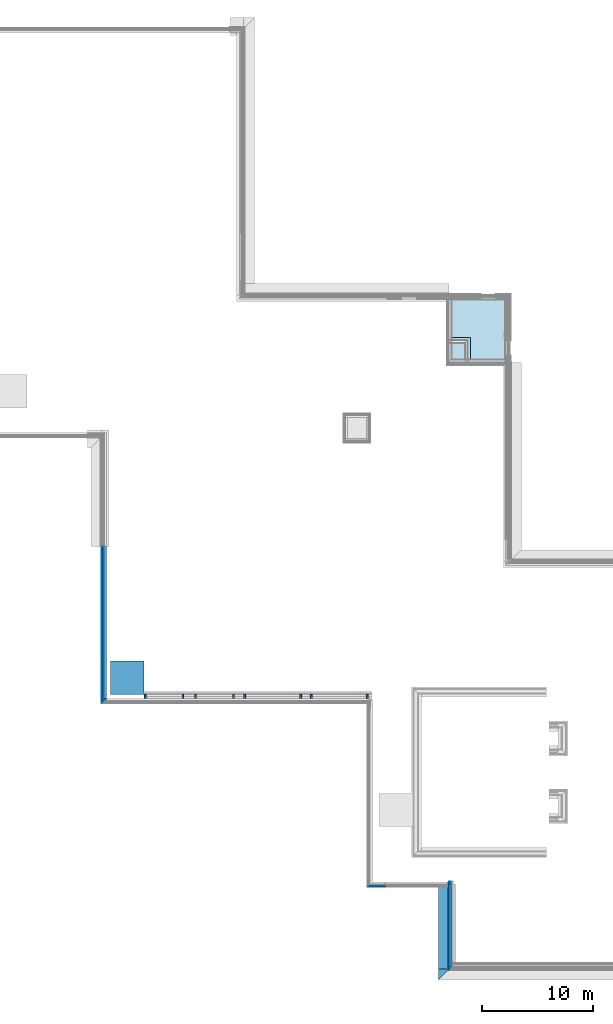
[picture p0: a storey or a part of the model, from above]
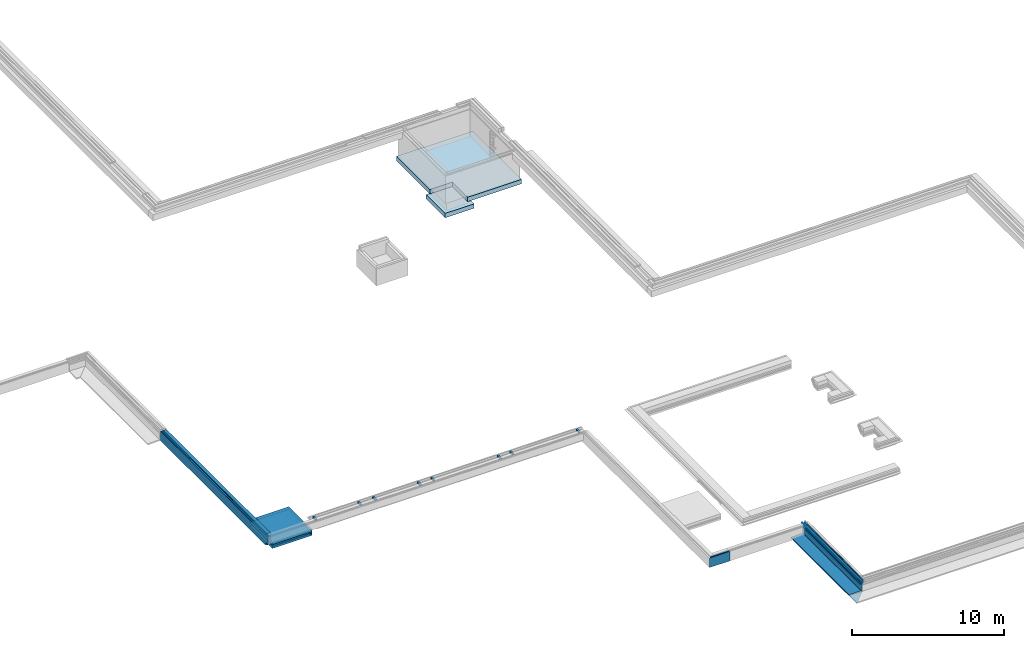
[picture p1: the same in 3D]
Properties of the parts of a building model (IFC2X3), part 1 of 14

# File
Description: ViewDefinition [CoordinationView_V2.0, SurfaceGeometryAddOnView, SpaceBoundary2ndLevelAddOnView], Option [Elements to export: Visible elements (on all stories)], Option [Partial Structure Display: Entire Model], Option [IFC Domain: All], Option [Structural Function: All Elements], Option [Convert Grid elements: On], Option [Convert IFC Annotations and ARCHICAD 2D elements: Off], Option [Convert 2D symbols of Doors and Windows: Off], Option [Export geometries that Participates in Collision Detection only: Off], Option [Split complex elements: On], Option [IFC Domain For Space Containment: Custom], Option [IFC Model position: Survey Point and Project Origin], Option [Curtain Wall export mode: Container Element], Option [Railing export mode: Container Element], Option [Stair export mode: Container Element], Option [Properties To Export: All properties], Option [Space containment: Off], Option [Bounding Box: Off], Option [Geometry to type objects: Off], Option [Element Properties: Visible Only], Option [Building Material Properties: Off], Option [Element Parameters: Off], Option [Component Parameters: Off], Option [IFC Base Quantities: Off], Option [Door Window Parameters: On], Option [IFC Space boundaries: On], Option [ARCHICAD Zone Categories as IFC Space classification data: Off], Option [Element Classifications: On]
File name: A:\ARHITEKT MUST SHARE\PROJEKTID\2020-04-09 PRG\03 Tööprojekt\Mudelid\PRG_PP_AR_v06.ifc
Time: 2022-06-07T12:43:35
Author: Ott Alver, Kaire Koidu, Lisett Laurimäe, Karoliine Kuus, Katrin Vilberg
Organization: Arhitekt Must OÜ
Written by: The EXPRESS Data Manager Version 5.02.0100.09 : 26 Sep 2013
Made in: IFC file generated by GRAPHISOFT ARCHICAD 25.0.0 INT FULL Windows version (IFC add-on version: 4013 INT FULL).
Authorization: Ott Alver, Kaire Koidu, Lisett Laurimäe, Karoliine Kuus, Katrin Vilberg

# IfcProject, Tallinna Pelgulinna riigigümnaasiumi õppehoone ehitusprojekt
Phase: Tööprojekt

# IfcSite, Kolde pst 67a
Description: Ühiskondlike ehitiste maa 100%; RefLatitude: 59, 26, 20, 700000; RefLongitude: 24, 42, 11, 300000; RefElevation: 5300 mm; Classification: 1.0.1 IfcSite (kinnistu) (RKAS BIM + ARCHICAD Classification 23 + v 2.0)
AR_Kinnistu - 025_Max_kõrgus: 16000 mm; 010_Katastritunnus: 78408:803:0075; 015_Ehitatav_pindala: 8000 m2; 020_Pindala: 38454 m2

# IfcBuilding, Riigigümnaasium
Classification: 1.0.2 IfcBuilding (hoone) (RKAS BIM + ARCHICAD Classification 23 + v 2.0)
AR_Hoone - 035_Sprinkler: yes; 001_Nimetus: Riigigümnaasium; 030_Hoone_aadress: Kolde pst 67a, Tallinn, 10321; ?: 3773.3 m2; 050_Neto_pindala: 8269.99 m2; 055_Neto_ruumala: 34560.7 m3; 040_Kõrgus: 15890 mm

# IfcBuildingStorey (6)
In: Riigigümnaasium
Name | Elevation (mm) | 060_Korruse_nimi | 070_Maapealne | Classification
Vundament | -1500 | Vundament | no
1. korrus | 0 | 1. korrus | yes | AR_Korrus - 065_Korruse_number: 1
2. korrus | 4600 | 2. korrus | yes | 1.0.3 IfcBuildingStorey (korrus) (RKAS BIM + ARCHICAD Classification 23 + v 2.0) | AR_Korrus - 065_Korruse_number: 2
3. korrus | 8350 | 3. korrus | yes | 1.0.3 IfcBuildingStorey (korrus) (RKAS BIM + ARCHICAD Classification 23 + v 2.0) | AR_Korrus - 065_Korruse_number: 3
4. TEHNO korrus | 12100 | TEHNO korrus | yes | 1.0.3 IfcBuildingStorey (korrus) (RKAS BIM + ARCHICAD Classification 23 + v 2.0)
Katus | 15900 | Katus | yes | 1.0.3 IfcBuildingStorey (korrus) (RKAS BIM + ARCHICAD Classification 23 + v 2.0)

# IfcSpace: Abiruumid/panipaigad (11)
InteriorOrExteriorSpace: INTERNAL; Classification: 1.21 IfcSpaceType (ruum) (RKAS BIM + ARCHICAD Classification)
Pset_SpaceCommon - Reference: Üüritav pind; Category: Abiruumid/panipaigad
AR_Ruum - 115_Kategooria: Abiruumid/panipaigad; 110_Tüüp: Üüritav pind; 125_Turvatsoon: Abiruumid/panipaigad
AC_Pset_RenovationAndPhasing - Renovation Status: New
Name | In | LongName = 100_Nimi | 105_Number | 120_Pindala (m2) | Group
191 | 1. korrus | Hoiuruum/Ladu | 191 | 23.9709
116 | 1. korrus | Abiruum | 116 | 3.04431 | TTS 02
198 | 1. korrus | Hoiuruum/Ladu | 198 | 26.6814 | TTS 05
176 | 1. korrus | Hoiuruum/Ladu | 176 | 9.17397 | TTS 22
230 | 2. korrus | Hoiuruum/Ladu | 230 | 30.8659 | TTS 16
254 | 2. korrus | Abiruum | 254 | 4.87507
229 | 2. korrus | Abiruum | 229 | 9.63895 | TTS 01
257 | 2. korrus | Abiruum | 257 | 5.39372
336 | 3. korrus | Abiruum | 336 | 18.426 | TTS 01
318 | 3. korrus | Abiruum | 318 | 11.8529
351 | 3. korrus | Abiruum | 351 | 6.48915 | TTS 01

# IfcSpace: Aula (2)
LongName: Aatrium/Fuajee; InteriorOrExteriorSpace: INTERNAL; Classification: 1.21 IfcSpaceType (ruum) (RKAS BIM + ARCHICAD Classification)
Pset_SpaceCommon - Reference: Üüritav pind; Category: Aula
AR_Ruum - 100_Nimi: Aatrium/Fuajee; 115_Kategooria: Aula; 110_Tüüp: Üüritav pind; 125_Turvatsoon: Aula
AC_Pset_RenovationAndPhasing - Renovation Status: New
Name | In | 105_Number | 120_Pindala (m2)
226.1 | 2. korrus | 226.1 | 103.615 | Group: TTS 01
226.2 | 3. korrus | 226.2 | 57.8569

# IfcSpace: Köögiruumid (8)
In: 1. korrus
InteriorOrExteriorSpace: INTERNAL; Classification: 1.21 IfcSpaceType (ruum) (RKAS BIM + ARCHICAD Classification)
Pset_SpaceCommon - Reference: Üüritav pind; Category: Köögiruumid
AR_Ruum - 115_Kategooria: Köögiruumid; 110_Tüüp: Üüritav pind; 125_Turvatsoon: Köögiruumid
AC_Pset_RenovationAndPhasing - Renovation Status: New
Name | LongName = 100_Nimi | 105_Number | 120_Pindala (m2) | Group
149 | Kööginurk/Köök | 149 | 95.7564 | TTS 01
141 | Hoiuruum/Ladu | 141 | 6.59968 | TTS 01
151 | Riietusruum | 151 | 6.76 | TTS 01
153 | WC | 153 | 1.94857 | TTS 01
152 | Pesuruum | 152 | 2.33343 | TTS 01
150 | Kabinet/Büroo | 150 | 9.78205
143 | Hoiuruum/Ladu | 143 | 3.49194 | TTS 01
142 | Hoiuruum/Ladu | 142 | 3.00324 | TTS 01

# IfcSpace: Märjad ruumid (56)
InteriorOrExteriorSpace: INTERNAL; Classification: 1.21 IfcSpaceType (ruum) (RKAS BIM + ARCHICAD Classification)
Pset_SpaceCommon - Reference: Üüritav pind; Category: Märjad ruumid
AR_Ruum - 115_Kategooria: Märjad ruumid; 110_Tüüp: Üüritav pind; 125_Turvatsoon: Märjad ruumid
AC_Pset_RenovationAndPhasing - Renovation Status: New
Name | In | LongName = 100_Nimi | 105_Number | 120_Pindala (m2) | Group
183 | 1. korrus | WC | 183 | 2.1358
187 | 1. korrus | WC | 187 | 2.10905
184 | 1. korrus | Pesuruum | 184 | 7.7438
186 | 1. korrus | Pesuruum | 186 | 7.65261
190 | 1. korrus | Pesuruum | 190 | 7.19918
180 | 1. korrus | Pesuruum | 180 | 7.3536
122 | 1. korrus | WC | 122 | 5.07894 | TTS 02
123 | 1. korrus | WC | 123 | 1.47943 | TTS 02
124 | 1. korrus | WC | 124 | 1.33987 | TTS 02
125 | 1. korrus | WC | 125 | 1.33987 | TTS 02
126 | 1. korrus | WC | 126 | 1.33987 | TTS 02
121 | 1. korrus | WC | 121 | 1.61197 | TTS 02
162 | 1. korrus | WC | 162 | 7.00256 | TTS 01
165 | 1. korrus | WC | 165 | 1.39298 | TTS 01
166 | 1. korrus | WC | 166 | 1.39298 | TTS 01
168 | 1. korrus | WC | 168 | 1.39298 | TTS 01
167 | 1. korrus | WC | 167 | 1.39298 | TTS 01
163 | 1. korrus | WC | 163 | 1.49425 | TTS 01
164 | 1. korrus | WC | 164 | 1.39298 | TTS 01
194 | 1. korrus | WC | 194 | 1.95199
193 | 1. korrus | WC | 193 | 2.0196
127 | 1. korrus | WC | 127 | 1.33988 | TTS 02
128 | 1. korrus | WC | 128 | 1.51264 | TTS 02
181 | 1. korrus | WC | 181 | 4.59543
189 | 1. korrus | WC | 189 | 4.55725
163.1 | 1. korrus | WC | 163.1 | 11.2722 | TTS 01
222 | 2. korrus | WC | 222 | 1.37998 | TTS 02
221 | 2. korrus | WC | 221 | 1.37998 | TTS 02
220 | 2. korrus | WC | 220 | 1.37998 | TTS 02
219 | 2. korrus | WC | 219 | 1.37998 | TTS 02
218 | 2. korrus | WC | 218 | 1.48204 | TTS 02
217 | 2. korrus | WC | 217 | 11.4102 | TTS 02
238 | 2. korrus | WC | 238 | 7.00256 | TTS 01
241 | 2. korrus | WC | 241 | 1.39298 | TTS 01
242 | 2. korrus | WC | 242 | 1.39298 | TTS 01
244 | 2. korrus | WC | 244 | 1.39298 | TTS 01
243 | 2. korrus | WC | 243 | 1.39298 | TTS 01
239 | 2. korrus | WC | 239 | 1.49425 | TTS 01
240 | 2. korrus | WC | 240 | 1.39298 | TTS 01
223 | 2. korrus | WC | 223 | 1.50827 | TTS 02
239.1 | 2. korrus | WC | 239.1 | 11.2722 | TTS 01
327 | 3. korrus | WC | 327 | 1.37998 | TTS 02
326 | 3. korrus | WC | 326 | 1.37998 | TTS 02
325 | 3. korrus | WC | 325 | 1.37998 | TTS 02
324 | 3. korrus | WC | 324 | 1.37998 | TTS 02
323 | 3. korrus | WC | 323 | 1.44592 | TTS 02
343 | 3. korrus | WC | 343 | 7.00256 | TTS 01
349 | 3. korrus | WC | 349 | 1.39298 | TTS 01
348 | 3. korrus | WC | 348 | 1.39298 | TTS 01
322 | 3. korrus | WC | 322 | 11.2901 | TTS 02
347 | 3. korrus | WC | 347 | 1.39298 | TTS 01
346 | 3. korrus | WC | 346 | 1.39298 | TTS 01
345 | 3. korrus | WC | 345 | 1.39298 | TTS 01
343.1 | 3. korrus | WC | 343.1 | 11.2722 | TTS 01
328 | 3. korrus | WC | 328 | 1.49558 | TTS 02
344 | 3. korrus | WC | 344 | 1.49425 | TTS 01

# IfcSpace: Personali ruumid (39)
InteriorOrExteriorSpace: INTERNAL; Classification: 1.21 IfcSpaceType (ruum) (RKAS BIM + ARCHICAD Classification)
Pset_SpaceCommon - Reference: Üüritav pind; Category: Personali ruumid
AR_Ruum - 115_Kategooria: Personali ruumid; 110_Tüüp: Üüritav pind; 125_Turvatsoon: Personali ruumid
AC_Pset_RenovationAndPhasing - Renovation Status: New
Name | In | LongName = 100_Nimi | 105_Number | 120_Pindala (m2) | Group
112 | 1. korrus | Riietusruum | 112 | 8.23039 | TTS 02
119 | 1. korrus | WC | 119 | 1.64765 | TTS 02
131 | 1. korrus | Kabinet/Büroo | 131 | 24.8738 | TTS 02
132 | 1. korrus | Kabinet/Büroo | 132 | 10.4075 | TTS 02
133 | 1. korrus | Nõupidamise ruum | 133 | 11.7527 | TTS 02
134 | 1. korrus | Kabinet/Büroo | 134 | 20.3091 | TTS 02
136 | 1. korrus | Kabinet/Büroo | 136 | 15.1182 | TTS 02
138 | 1. korrus | Kabinet/Büroo | 138 | 24.1936 | TTS 02
137 | 1. korrus | Kabinet/Büroo | 137 | 21.7035 | TTS 02
178 | 1. korrus | Tervishoiuruum | 178 | 20.4975
129 | 1. korrus | Kööginurk/Köök | 129 | 73.9946 | TTS 02
117 | 1. korrus | Nõupidamise ruum | 117 | 46.7019 | TTS 02
115.1 | 1. korrus | Dušš | 115.1 | 2.70465 | TTS 02
108 | 1. korrus | Kabinet/Büroo | 108 | 3.11313 | TTS 02
110 | 1. korrus | Kabinet/Büroo | 110 | 3.0839 | TTS 02
130 | 1. korrus | Koridor | 130 | 19.5208 | TTS 02
120 | 1. korrus | Puhkeruum | 120 | 80.7206 | TTS 02
114 | 1. korrus | WC | 114 | 1.62377 | TTS 02
113 | 1. korrus | WC | 113 | 1.64765 | TTS 02
111 | 1. korrus | Garderoob | 111 | 15.1477 | TTS 02
118 | 1. korrus | WC | 118 | 1.64765 | TTS 02
107 | 1. korrus | Kabinet/Büroo | 107 | 27.0513 | TTS 02
135 | 1. korrus | Kabinet/Büroo | 135 | 15.1162 | TTS 02
175 | 1. korrus | Riietusruum | 175 | 7.38083
174 | 1. korrus | Pesuruum | 174 | 1.7598
173 | 1. korrus | Pesuruum | 173 | 1.83489
172 | 1. korrus | WC | 172 | 1.79748
171 | 1. korrus | Kabinet/Büroo | 171 | 27.2314
192 | 1. korrus | Koristus- ja hooldusruum | 192 | 3.92524
115.2 | 1. korrus | Dušš | 115.2 | 2.66968 | TTS 02
109 | 1. korrus | Kabinet/Büroo | 109 | 3.11307 | TTS 02
235 | 2. korrus | Kabinet/Büroo | 235 | 18.9735 | TTS 01
207 | 2. korrus | Kabinet/Büroo | 207 | 17.0178 | TTS 02
247 | 2. korrus | Koristus- ja hooldusruum | 247 | 10.6071 | TTS 17
341 | 3. korrus | Abiruum | 341 | 19.0182 | TTS 01
305 | 3. korrus | Kabinet/Büroo | 305 | 13.5373 | TTS 02
309 | 3. korrus | Kabinet/Büroo | 309 | 16.817 | TTS 02
320 | 3. korrus | Koristus- ja hooldusruum | 320 | 11.0684 | TTS 02
305.1 | 3. korrus | Kabinet/Büroo | 305.1 | 8.99822 | TTS 02

# IfcSpace: Raamatukogu/mediateek (4)
In: 1. korrus
LongName: Raamatukogu; InteriorOrExteriorSpace: INTERNAL; Classification: 1.21 IfcSpaceType (ruum) (RKAS BIM + ARCHICAD Classification); Group: TTS 23
Pset_SpaceCommon - Reference: Üüritav pind; Category: Raamatukogu/mediateek
AR_Ruum - 100_Nimi: Raamatukogu; 115_Kategooria: Raamatukogu/mediateek; 110_Tüüp: Üüritav pind; 125_Turvatsoon: Raamatukogu/mediateek
AC_Pset_RenovationAndPhasing - Renovation Status: New
Name | 105_Number | 120_Pindala (m2)
170 | 170 | 155.958
170.1 | 170.1 | 4.45445
170.2 | 170.2 | 6.61809
170.3 | 170.3 | 4.30703

# IfcSpace: Spordiruumid (3)
LongName: Spordiruum/-saal; InteriorOrExteriorSpace: INTERNAL; Classification: 1.21 IfcSpaceType (ruum) (RKAS BIM + ARCHICAD Classification)
Pset_SpaceCommon - Reference: Üüritav pind; Category: Spordiruumid
AR_Ruum - 100_Nimi: Spordiruum/-saal; 115_Kategooria: Spordiruumid; 110_Tüüp: Üüritav pind; 125_Turvatsoon: Spordiruumid
AC_Pset_RenovationAndPhasing - Renovation Status: New
Name | In | 105_Number | 120_Pindala (m2)
197 | 1. korrus | 197 | 542.574
253 | 2. korrus | 253 | 61.32
252 | 2. korrus | 252 | 62.6603

# IfcSpace: Tehnopind (10)
InteriorOrExteriorSpace: INTERNAL; Classification: 1.21 IfcSpaceType (ruum) (RKAS BIM + ARCHICAD Classification)
Pset_SpaceCommon - Reference: Tehnopind; Category: Tehnopind
AR_Ruum - 115_Kategooria: Tehnopind; 110_Tüüp: Tehnopind; 125_Turvatsoon: Tehnopind
AC_Pset_RenovationAndPhasing - Renovation Status: New
Name | In | LongName = 100_Nimi | 105_Number | 120_Pindala (m2) | Group
160 | 1. korrus | Veemõõdusõlm | 160 | 8.43576
156 | 1. korrus | Elektrikilp | 156 | 9.02498 | TTS 19
155 | 1. korrus | Generaatoriruum | 155 | 9.12498 | TTS 18
154 | 1. korrus | Sprinkler/Tuletõrje pump | 154 | 16.7674
199 | 1. korrus | Vent ruum | 199 | 39.7786 | TTS 21
161 | 1. korrus | Vent ruum | 161 | 33.47
256 | 2. korrus | Vent ruum | 256 | 49.9815 | TTS 21
319 | 3. korrus | Elektrikilp | 319 | 11.7368
400 | 4. TEHNO korrus | Vent ruum | 400 | 158.243 | TTS 20
401 | 4. TEHNO korrus | Õhuvõtukamber | 401 | 16.8049 | TTS 20

# IfcSpace: Õpperuumid, suur (30)
InteriorOrExteriorSpace: INTERNAL; Classification: 1.21 IfcSpaceType (ruum) (RKAS BIM + ARCHICAD Classification)
Pset_SpaceCommon - Reference: Üüritav pind; Category: Õpperuumid, suur
AR_Ruum - 115_Kategooria: Õpperuumid, suur; 110_Tüüp: Üüritav pind; 125_Turvatsoon: Õpperuumid, suur
AC_Pset_RenovationAndPhasing - Renovation Status: New
Name | In | LongName = 100_Nimi | 105_Number | 120_Pindala (m2) | Group
103 | 1. korrus | Klassiruum | 103 | 67.7298 | TTS 02
148 | 1. korrus | Klassiruum | 148 | 66.9596 | TTS 01
105 | 1. korrus | Klassiruum | 105 | 67.5904 | TTS 02
104 | 1. korrus | Klassiruum | 104 | 66.867 | TTS 02
212 | 2. korrus | Klassiruum | 212 | 68.9089 | TTS 02
210 | 2. korrus | Klassiruum | 210 | 69.8721 | TTS 02
214 | 2. korrus | Nõupidamise ruum | 214 | 73.7044 | TTS 02
215 | 2. korrus | Nõupidamise ruum | 215 | 72.9467 | TTS 02
208 | 2. korrus | Klassiruum | 208 | 69.3758 | TTS 02
204 | 2. korrus | Klassiruum | 204 | 68.5561 | TTS 02
203 | 2. korrus | Klassiruum | 203 | 68.4834 | TTS 02
234 | 2. korrus | Klassiruum | 234 | 69.0595 | TTS 01
228 | 2. korrus | Klassiruum | 228 | 68.9449 | TTS 01
205 | 2. korrus | Klassiruum | 205 | 68.6598 | TTS 02
255 | 2. korrus | Klassiruum | 255 | 67.525
249 | 2. korrus | Klassiruum | 249 | 68.0334
304 | 3. korrus | Klassiruum | 304 | 68.4834 | TTS 02
303 | 3. korrus | Klassiruum | 303 | 67.8291 | TTS 02
310 | 3. korrus | Klassiruum | 310 | 69.3171 | TTS 02
302 | 3. korrus | Klassiruum | 302 | 63.9765 | TTS 02
314 | 3. korrus | Klassiruum | 314 | 68.9089 | TTS 02
334 | 3. korrus | Klassiruum | 334 | 69.3182 | TTS 01
340 | 3. korrus | Laboratoorium | 340 | 84.1305 | TTS 01
342 | 3. korrus | Klassiruum | 342 | 68.6383 | TTS 01
335 | 3. korrus | Klassiruum | 335 | 69.503 | TTS 01
337 | 3. korrus | Klassiruum | 337 | 69.2433 | TTS 01
312 | 3. korrus | Klassiruum | 312 | 69.8721 | TTS 02
332 | 3. korrus | Klassiruum | 332 | 69.8355 | TTS 01
316 | 3. korrus | Auditoorium | 316 | 144.694 | TTS 02
331 | 3. korrus | Klassiruum | 331 | 74.0632 | TTS 01

# IfcSpace: Õpperuumid, väike (16)
LongName: Klassiruum; InteriorOrExteriorSpace: INTERNAL; Classification: 1.21 IfcSpaceType (ruum) (RKAS BIM + ARCHICAD Classification)
Pset_SpaceCommon - Reference: Üüritav pind; Category: Õpperuumid, väike
AR_Ruum - 100_Nimi: Klassiruum; 115_Kategooria: Õpperuumid, väike; 110_Tüüp: Üüritav pind; 125_Turvatsoon: Õpperuumid, väike
AC_Pset_RenovationAndPhasing - Renovation Status: New
Name | In | 105_Number | 120_Pindala (m2) | Group
159 | 1. korrus | 159 | 46.7382 | TTS 01
158 | 1. korrus | 158 | 46.1161 | TTS 01
211 | 2. korrus | 211 | 41.1627 | TTS 02
232 | 2. korrus | 232 | 46.5236 | TTS 01
248 | 2. korrus | 248 | 39.8321
231 | 2. korrus | 231 | 47.3455 | TTS 01
209 | 2. korrus | 209 | 40.5333 | TTS 02
251 | 2. korrus | 251 | 40.2126
237 | 2. korrus | 237 | 39.7604 | TTS 01
236 | 2. korrus | 236 | 40.6798 | TTS 01
313 | 3. korrus | 313 | 41.1626 | TTS 02
338 | 3. korrus | 338 | 39.035 | TTS 01
311 | 3. korrus | 311 | 40.4985 | TTS 02
330 | 3. korrus | 330 | 41.5446 | TTS 01
307 | 3. korrus | 307 | 55.1263 | TTS 02
333 | 3. korrus | 333 | 40.4974 | TTS 01

# IfcSpace: Üldkasutatav pind (39)
InteriorOrExteriorSpace: INTERNAL; Classification: 1.21 IfcSpaceType (ruum) (RKAS BIM + ARCHICAD Classification)
Pset_SpaceCommon - Category: Üldkasutatav pind
AR_Ruum - 115_Kategooria: Üldkasutatav pind; 125_Turvatsoon: Üldkasutatav pind
AC_Pset_RenovationAndPhasing - Renovation Status: New
Name | In | LongName = 100_Nimi | Reference = 110_Tüüp | 105_Number | 120_Pindala (m2) | Group
195 | 1. korrus | Aatrium/Fuajee | Üüritav pind | 195 | 32.9555
106 | 1. korrus | Trepp/Trepikoda | Vertikaalsete ühendusteede pind | 106 | 19.9364 | TTS 03
139 | 1. korrus | Trepp/Trepikoda | Vertikaalsete ühendusteede pind | 139 | 38.8612 | TTS 04
188 | 1. korrus | Riietusruum | Üüritav pind | 188 | 26.5319
185 | 1. korrus | Riietusruum | Üüritav pind | 185 | 26.7094
182 | 1. korrus | Riietusruum | Üüritav pind | 182 | 28.7031
179 | 1. korrus | Riietusruum | Üüritav pind | 179 | 28.7527
157 | 1. korrus | Trepp/Trepikoda | Vertikaalsete ühendusteede pind | 157 | 19.9644
196 | 1. korrus | Koridor | Üüritav pind | 196 | 82.805
102.1 | 1. korrus | Garderoob | Üüritav pind | 102.1 | 119.782 | TTS 02
101 | 1. korrus | Aatrium/Fuajee | Üüritav pind | 101 | 253.476 | TTS 02
169 | 1. korrus | Lift | Üüritav pind | 169 | 3.23
147 | 1. korrus | Aatrium/Fuajee | Üüritav pind | 147 | 198.84 | TTS 01
140 | 1. korrus | Koridor | Üüritav pind | 140 | 7.02965 | TTS 04
177 | 1. korrus | Trepp/Trepikoda | Vertikaalsete ühendusteede pind | 177 | 21.1302
102.2 | 1. korrus | Garderoob | Üüritav pind | 102.2 | 119.849 | TTS 02
144 | 1. korrus | Koridor | Üüritav pind | 144 | 214.176 | TTS 01
146 | 1. korrus | Söökla/Kohvik | Üüritav pind | 146 | 227.255 | TTS 01
216 | 2. korrus | Nõupidamise ruum | Üüritav pind | 216 | 11.8284 | TTS 02
245 | 2. korrus | Lift | Vertikaalsete ühendusteede pind | 245 | 3.23
246 | 2. korrus | Koridor | Üüritav pind | 246 | 116.93
201 | 2. korrus | Koridor | Üüritav pind | 201 | 254.773 | TTS 02
227 | 2. korrus | Trepp/Trepikoda | Üüritav pind | 227 | 73.3487 | TTS 01
233 | 2. korrus | Trepp/Trepikoda | Vertikaalsete ühendusteede pind | 233 | 19.9573
250 | 2. korrus | Trepp/Trepikoda | Vertikaalsete ühendusteede pind | 250 | 30.3251
213 | 2. korrus | Trepp/Trepikoda | Vertikaalsete ühendusteede pind | 213 | 25.2342 | TTS 04
225 | 2. korrus | Õpilasesindus | Üüritav pind | 225 | 25.6581 | TTS 01
206 | 2. korrus | Trepp/Trepikoda | Vertikaalsete ühendusteede pind | 206 | 19.9284 | TTS 03
202 | 2. korrus | Puhkeruum | Üüritav pind | 202 | 90.2772 | TTS 02
224 | 2. korrus | Koridor | Üüritav pind | 224 | 181.989 | TTS 01
308 | 3. korrus | Trepp/Trepikoda | Vertikaalsete ühendusteede pind | 308 | 20.5717 | TTS 03
350 | 3. korrus | Lift | Vertikaalsete ühendusteede pind | 350 | 3.23
321 | 3. korrus | Nõupidamise ruum | Üüritav pind | 321 | 11.5436 | TTS 02
329 | 3. korrus | Koridor | Üüritav pind | 329 | 263.35 | TTS 01
301 | 3. korrus | Koridor | Üüritav pind | 301 | 272.216 | TTS 02
317 | 3. korrus | Nõupidamise ruum | Üüritav pind | 317 | 11.7977 | TTS 02
315 | 3. korrus | Trepp/Trepikoda | Vertikaalsete ühendusteede pind | 315 | 25.2336 | TTS 04
306 | 3. korrus | Puhkeruum | Üüritav pind | 306 | 43.1755 | TTS 02
339 | 3. korrus | Trepp/Trepikoda | Vertikaalsete ühendusteede pind | 339 | 20.5997

# IfcBeam: Garderoobi tala 650 x 280 (2)
In: 1. korrus
Type - PredefinedType: BEAM
Classification: 1.01 IfcBeamType (tala) (RKAS BIM + ARCHICAD Classification); Material: _METALL - alumiinium
Pset_BeamCommon - Reference: Vastavalt EK osale; Slope: 0 deg; LoadBearing: no; IsExternal: yes
AR_001-002 - 001_Nimetus: Tala; 002_Tüüp: Vastavalt EK osale
AC_Pset_RenovationAndPhasing - Renovation Status: New
Name | Span (mm)
Tala | 6370.27
Tala | 6140

# IfcBeam: HE200A 190 x 200, Tala
In: 2. korrus
Type - PredefinedType: BEAM
Classification: 1.01 IfcBeamType (tala) (RKAS BIM + ARCHICAD Classification); Material: Teras, S355
Pset_BeamCommon - Reference: Vastavalt-EK-osale; Span: 17296 mm; Slope: 0 deg; LoadBearing: yes; IsExternal: no
AR_001-002 - 001_Nimetus: Tala; 002_Tüüp: Vastavalt-EK-osale
AC_Pset_RenovationAndPhasing - Renovation Status: New

# IfcBeam: IPE160 160 x 82, Tala
In: 4. TEHNO korrus
Type - PredefinedType: BEAM
Classification: 1.01 IfcBeamType (tala) (RKAS BIM + ARCHICAD Classification); Material: Teras, S355
Pset_BeamCommon - Reference: Vastavalt-EK-osale; Span: 1291.36 mm; Slope: 4.585 deg; LoadBearing: yes; IsExternal: no
AR_001-002 - 001_Nimetus: Tala; 002_Tüüp: Vastavalt-EK-osale
AC_Pset_RenovationAndPhasing - Renovation Status: New

# IfcBeam: IPE180 180 x 91 (3)
In: 4. TEHNO korrus
Type - PredefinedType: BEAM
Classification: 1.01 IfcBeamType (tala) (RKAS BIM + ARCHICAD Classification); Material: Teras, S355
Pset_BeamCommon - Reference: Vastavalt-EK-osale; Slope: 0 deg; LoadBearing: yes; IsExternal: no
AR_001-002 - 001_Nimetus: Tala; 002_Tüüp: Vastavalt-EK-osale
AC_Pset_RenovationAndPhasing - Renovation Status: New
Name | Span (mm)
Tala | 13827.8
2 x Tala | 3824.65

# IfcBeam: RHS100x200x10 100 x 200 (25)
Type - PredefinedType: BEAM
Classification: 1.01 IfcBeamType (tala) (RKAS BIM + ARCHICAD Classification); Material: Teras, S355
Pset_BeamCommon - Reference: Terastalad vastavalt EK osale; LoadBearing: yes; IsExternal: no
AR_001-002 - 001_Nimetus: Katuseakna talad; 002_Tüüp: Terastalad vastavalt EK osale
AC_Pset_RenovationAndPhasing - Renovation Status: New
Name | In | Span (mm) | Slope (deg)
4 x Katuseakna talad | 3. korrus | 5730.99 | -7
2 x Katuseakna talad | 3. korrus | 7268.09 | 0
5 x Katuseakna talad | 4. TEHNO korrus | 5780.33 | -7
3 x Katuseakna talad | 4. TEHNO korrus | 5713.9 | -7
4 x Katuseakna talad | 4. TEHNO korrus | 4430 | -7
2 x Katuseakna talad | 4. TEHNO korrus | 11942.3 | 0
2 x Katuseakna talad | 4. TEHNO korrus | 6768.43 | 0
3 x Katuseakna talad | 4. TEHNO korrus | 6695.26 | 0

# IfcBeam: SHS200x200x10 200 x 200, Teras tala vastavalt EK osale
In: 3. korrus
Type - PredefinedType: BEAM
Classification: 1.01 IfcBeamType (tala) (RKAS BIM + ARCHICAD Classification); Material: Teras, S355
Pset_BeamCommon - Reference: Vastavalt ehituskonstruktiivsele osale; LoadBearing: yes; IsExternal: no
AR_001-002 - 001_Nimetus: Teras tala vastavalt EK osale; 002_Tüüp: Vastavalt ehituskonstruktiivsele osale
AC_Pset_RenovationAndPhasing - Renovation Status: New

# IfcBeam: Steel Universal Section 260 x 260 (4)
In: 4. TEHNO korrus
Type - PredefinedType: BEAM
Classification: 1.01 IfcBeamType (tala) (RKAS BIM + ARCHICAD Classification); Material: _VÄLISVIIMISTLUS - klinker tellisplaat, punane, kergelt varieeruva tooniga; vuuk weber.therm 371 – dunkelgrau
Pset_BeamCommon - Reference: Vastavalt-EK-osale; LoadBearing: yes; IsExternal: no
AR_001-002 - 001_Nimetus: Tala; 002_Tüüp: Vastavalt-EK-osale
AC_Pset_RenovationAndPhasing - Renovation Status: New
Name | Span (mm) | Slope (deg)
2 x Tala | 7798.61 | 4.42
2 x Tala | 6675.15 | 3.16

# IfcBeam: _KANDETARIND - liimpuit vastavalt EK osale 140 x 580 (11)
In: 3. korrus
Type - PredefinedType: BEAM
Classification: 1.01 IfcBeamType (tala) (RKAS BIM + ARCHICAD Classification); Material: _KANDETARIND - liimpuit vastavalt EK osale
Pset_BeamCommon - Slope: 0 deg; LoadBearing: yes; IsExternal: no
AR_001-002 - 001_Nimetus: Ribiplaat
AC_Pset_RenovationAndPhasing - Renovation Status: New
Name | Reference = 002_Tüüp | Span (mm)
6 x Ribiplaat | RP1 | 10260
5 x Ribiplaat | RP2 | 9590

# IfcBeam: _KANDETARIND - liimpuit vastavalt EK osale 140 x 640 (18)
In: 4. TEHNO korrus
Type - PredefinedType: BEAM
Classification: 1.01 IfcBeamType (tala) (RKAS BIM + ARCHICAD Classification); Material: _KANDETARIND - liimpuit vastavalt EK osale
Pset_BeamCommon - Slope: 0 deg; IsExternal: no
AC_Pset_RenovationAndPhasing - Renovation Status: New
Name | Reference = 002_Tüüp | Span (mm) | LoadBearing | 001_Nimetus
9 x Ribiplaat | RP3 | 11560.1 | yes | Ribiplaat
5 x Tala | Vastavalt-EK-osale | 13340 | no | Tala
2 x Tala | Vastavalt-EK-osale | 3750.04 | no | Tala
2 x Tala | Vastavalt-EK-osale | 3750 | no | Tala

# IfcBeam: _KANDETARIND - liimpuit vastavalt EK osale 160 x 600 (6)
In: 2. korrus
Type - PredefinedType: BEAM
Classification: 1.01 IfcBeamType (tala) (RKAS BIM + ARCHICAD Classification); Material: _KANDETARIND - liimpuit vastavalt EK osale
Pset_BeamCommon - Reference: Vastavalt-EK-osale; Slope: 0 deg; LoadBearing: no; IsExternal: no
AR_001-002 - 001_Nimetus: Tala; 002_Tüüp: Vastavalt-EK-osale
AC_Pset_RenovationAndPhasing - Renovation Status: New
Name | Span (mm)
4 x Tala | 4310.01
2 x Tala | 6310.04

# IfcBeam: _KANDETARIND - liimpuit vastavalt EK osale 160 x 720 (34)
In: 2. korrus
Type - PredefinedType: BEAM
Classification: 1.01 IfcBeamType (tala) (RKAS BIM + ARCHICAD Classification); Material: _KANDETARIND - liimpuit vastavalt EK osale
Pset_BeamCommon - Reference: Vastavalt-EK-osale; Slope: 0 deg; LoadBearing: no; IsExternal: no
AR_001-002 - 001_Nimetus: Tala; 002_Tüüp: Vastavalt-EK-osale
AC_Pset_RenovationAndPhasing - Renovation Status: New
Name | Span (mm)
7 x Tala | 7229.95
Tala | 4308.98
Tala | 4309.96
2 x Tala | 4310
Tala | 4310.06
2 x Tala | 5749.02
4 x Tala | 5750
4 x Tala | 5749.95
4 x Tala | 14010
8 x Tala | 9970

# IfcBeam: _KANDETARIND - liimpuit vastavalt EK osale 160 x 960, Tala
In: 2. korrus
Type - PredefinedType: BEAM
Classification: 1.01 IfcBeamType (tala) (RKAS BIM + ARCHICAD Classification); Material: _KANDETARIND - liimpuit vastavalt EK osale
Pset_BeamCommon - Reference: Vastavalt-EK-osale; Span: 5530.01 mm; Slope: 0 deg; LoadBearing: yes; IsExternal: no
AR_001-002 - 001_Nimetus: Tala; 002_Tüüp: Vastavalt-EK-osale
AC_Pset_RenovationAndPhasing - Renovation Status: New

# IfcBeam: _KANDETARIND - liimpuit vastavalt EK osale 240 x 1000 (11)
In: 1. korrus
Type - PredefinedType: BEAM
Classification: 1.01 IfcBeamType (tala) (RKAS BIM + ARCHICAD Classification); Material: _KANDETARIND - liimpuit vastavalt EK osale
Pset_BeamCommon - Reference: Vastavalt-EK-osale; Slope: 0 deg; LoadBearing: yes; IsExternal: no
AR_001-002 - 001_Nimetus: Tala; 002_Tüüp: Vastavalt-EK-osale
AC_Pset_RenovationAndPhasing - Renovation Status: New
Name | Span (mm)
Tala | 5460
Tala | 5280
Tala | 5390
Tala | 5270
2 x Tala | 6400
3 x Tala | 4170.01
Tala | 6170.04
Tala | 5159.95

# IfcBeam: _KANDETARIND - liimpuit vastavalt EK osale 240 x 430, Tala
In: 2. korrus
Type - PredefinedType: BEAM
Classification: 1.01 IfcBeamType (tala) (RKAS BIM + ARCHICAD Classification); Material: _KANDETARIND - liimpuit vastavalt EK osale
Pset_BeamCommon - Reference: Vastavalt-EK-osale; Span: 4170 mm; Slope: 0 deg; LoadBearing: yes; IsExternal: no
AR_001-002 - 001_Nimetus: Tala; 002_Tüüp: Vastavalt-EK-osale
AC_Pset_RenovationAndPhasing - Renovation Status: New

# IfcBeam: _KANDETARIND - liimpuit vastavalt EK osale 240 x 480 (2)
In: 1. korrus
Type - PredefinedType: BEAM
Classification: 1.01 IfcBeamType (tala) (RKAS BIM + ARCHICAD Classification); Material: _KANDETARIND - liimpuit vastavalt EK osale
Pset_BeamCommon - Reference: Vastavalt-EK-osale; Slope: 0 deg; LoadBearing: yes; IsExternal: no
AR_001-002 - 001_Nimetus: Tala; 002_Tüüp: Vastavalt-EK-osale
AC_Pset_RenovationAndPhasing - Renovation Status: New
Name | Span (mm)
Tala | 3729.99
Tala | 6569.99

# IfcBeam: _KANDETARIND - liimpuit vastavalt EK osale 240 x 680, Tala
In: 1. korrus
Type - PredefinedType: BEAM
Classification: 1.01 IfcBeamType (tala) (RKAS BIM + ARCHICAD Classification); Material: _KANDETARIND - liimpuit vastavalt EK osale
Pset_BeamCommon - Reference: Vastavalt-EK-osale; Span: 4170 mm; Slope: 0 deg; LoadBearing: yes; IsExternal: no
AR_001-002 - 001_Nimetus: Tala; 002_Tüüp: Vastavalt-EK-osale
AC_Pset_RenovationAndPhasing - Renovation Status: New

# IfcBeam: _KANDETARIND - liimpuit vastavalt EK osale 240 x 720 (34)
In: 2. korrus
Type - PredefinedType: BEAM
Classification: 1.01 IfcBeamType (tala) (RKAS BIM + ARCHICAD Classification); Material: _KANDETARIND - liimpuit vastavalt EK osale
Pset_BeamCommon - Reference: Vastavalt-EK-osale; Slope: 0 deg; IsExternal: no
AR_001-002 - 001_Nimetus: Tala; 002_Tüüp: Vastavalt-EK-osale
AC_Pset_RenovationAndPhasing - Renovation Status: New
Name | Span (mm) | LoadBearing
Tala | 4170 | no
3 x Tala | 5280 | yes
3 x Tala | 4169.73 | yes
3 x Tala | 7090 | yes
3 x Tala | 5270 | yes
Tala | 5389.99 | yes
Tala | 5280 | no
Tala | 4169.73 | no
2 x Tala | 3729.98 | yes
Tala | 4168.97 | no
Tala | 5611.02 | no
2 x Tala | 5609.99 | no
Tala | 5610 | no
Tala | 4170.05 | no
2 x Tala | 5600 | no
2 x Tala | 6170.04 | yes
Tala | 6569.99 | yes
3 x Tala | 4170.01 | yes
Tala | 6400 | yes
Tala | 2809.96 | yes

# IfcBeam: _KANDETARIND - liimpuit vastavalt EK osale 240 x 780 (10)
In: 3. korrus
Type - PredefinedType: BEAM
Classification: 1.01 IfcBeamType (tala) (RKAS BIM + ARCHICAD Classification); Material: _KANDETARIND - liimpuit vastavalt EK osale
Pset_BeamCommon - Reference: Vastavalt-EK-osale; Slope: 0 deg; IsExternal: no
AR_001-002 - 001_Nimetus: Tala; 002_Tüüp: Vastavalt-EK-osale
AC_Pset_RenovationAndPhasing - Renovation Status: New
Name | Span (mm) | LoadBearing
2 x Tala | 5609.94 | no
2 x Tala | 5270 | no
2 x Tala | 5390 | no
Tala | 5610 | no
Tala | 5609.99 | no
Tala | 6390 | yes
Tala | 4170.01 | yes

# IfcBeam: _KANDETARIND - liimpuit vastavalt EK osale 400 x 1000, Tala
In: 1. korrus
Type - PredefinedType: BEAM
Classification: 1.01 IfcBeamType (tala) (RKAS BIM + ARCHICAD Classification); Material: _KANDETARIND - liimpuit vastavalt EK osale
Pset_BeamCommon - Reference: Vastavalt-EK-osale; Span: 8579.1 mm; Slope: 0 deg; LoadBearing: yes; IsExternal: no
AR_001-002 - 001_Nimetus: Tala; 002_Tüüp: Vastavalt-EK-osale
AC_Pset_RenovationAndPhasing - Renovation Status: New

# IfcBeam: _KARKASS - puitroov 32x50mm vertikaalne, immutatud Driconi tulekaitsevahendiga või samaväärne, samm 600mm 140 x 640 (6)
In: 4. TEHNO korrus
Type - PredefinedType: BEAM
Classification: 1.01 IfcBeamType (tala) (RKAS BIM + ARCHICAD Classification); Material: _KARKASS - puitroov 32x50mm vertikaalne, immutatud Driconi tulekaitsevahendiga või samaväärne, samm 600mm
Pset_BeamCommon - Reference: Vastavalt-EK-osale; Slope: 0 deg; LoadBearing: no; IsExternal: no
AR_001-002 - 001_Nimetus: Tala; 002_Tüüp: Vastavalt-EK-osale
AC_Pset_RenovationAndPhasing - Renovation Status: New
Name | Span (mm)
2 x Tala | 2560
4 x Tala | 1160

# IfcBeam: _VIIMISTLUSKIHT - puit 320 x 1040 (5)
In: 2. korrus
Type - PredefinedType: BEAM
Classification: 1.01 IfcBeamType (tala) (RKAS BIM + ARCHICAD Classification); Material: _VIIMISTLUSKIHT - puit
Pset_BeamCommon - Reference: Vastavalt-EK-osale; Slope: 0 deg; LoadBearing: yes; IsExternal: no
AR_001-002 - 001_Nimetus: Tala; 002_Tüüp: Vastavalt-EK-osale
AC_Pset_RenovationAndPhasing - Renovation Status: New
Name | Span (mm)
Tala | 17350
4 x Tala | 17296

# IfcBeam: topeltauditooriumi tala 550 x 600, Tala
In: 3. korrus
Type - PredefinedType: BEAM
Classification: 1.01 IfcBeamType (tala) (RKAS BIM + ARCHICAD Classification); Material: _KANDETARIND - monteeritav raudbetoon vastavalt EK osale
Pset_BeamCommon - Reference: Vastavalt EK osale; Span: 13740.3 mm; Slope: 0 deg; LoadBearing: no; IsExternal: yes
AR_001-002 - 001_Nimetus: Tala; 002_Tüüp: Vastavalt EK osale
AC_Pset_RenovationAndPhasing - Renovation Status: New

# IfcBuildingElementPart (5798)
Name | In | Material
34 x _KANDETARIND - monoliitne raudbetoon vastavalt EK osale | Vundament | _KANDETARIND - monoliitne raudbetoon vastavalt EK osale
44 x _SOOJUSTUS - ekstrudeeritud polüstüreenist plaadid XPS 250, survetugevus min 250kPa, soojuserijuhtivus λD<0,036 W/(mK), veeimavus alla 0,2%, näiteks XPS 250 foam SL või samaväärne | Vundament | _SOOJUSTUS - ekstrudeeritud polüstüreenist plaadid XPS 250, survetugevus min 250kPa, soojuserijuhtivus λD<0,036 W/(mK), veeimavus alla 0,2%, näiteks XPS 250 foam SL või samaväärne
132 x _SOOJUSTUS - vahtpolüstüreenplaadid EPS 120 Perimeeter, survetugevus min 120kPa, veeimavus <2%, soojuserijuhtivus λD<0,036 W/(mK) | Vundament | _SOOJUSTUS - vahtpolüstüreenplaadid EPS 120 Perimeeter, survetugevus min 120kPa, veeimavus <2%, soojuserijuhtivus λD<0,036 W/(mK)
20 x _HÜDROISOLATSIOON - Bituumenvõõp COMBIFLEX-EL vastavalt TL2 nõuetele | Vundament | _HÜDROISOLATSIOON - Bituumenvõõp COMBIFLEX-EL vastavalt TL2 nõuetele
48 x _TUULETÕKE - sokli krohv, silikoonvaikkrohv Weber.pas 481 AquaBalance 1mm "scratch" viimistlus, toon helehall CL444 (S 3502-Y) * 35, SILS süsteem, või samaväärne | Vundament | _TUULETÕKE - sokli krohv, silikoonvaikkrohv Weber.pas 481 AquaBalance 1mm "scratch" viimistlus, toon helehall CL444 (S 3502-Y) * 35, SILS süsteem, või samaväärne
13 x _HÜDROISOLATSIOON - tsemendil baseeruv ühekomponentne hüdroisolatsioon hüdroisoleerimiseks sokli krohvi pealt, ülevärvitud silikoonvaikvärviga sokli krohvi tooni, Weber.tec 824 ja Weber.ton 411 AquaBalance toon CL444 (S 3502-Y) * 35 või samaväärne | Vundament | _HÜDROISOLATSIOON - tsemendil baseeruv ühekomponentne hüdroisolatsioon hüdroisoleerimiseks sokli krohvi pealt, ülevärvitud silikoonvaikvärviga sokli krohvi tooni, Weber.tec 824 ja Weber.ton 411 AquaBalance toon CL444 (S 3502-Y) * 35 või samaväärne
25 x _ALUSKATE - drenaaži- ja kaitsematt geotekstiiliga soojustuse kaitseks, Interplast Iso-Drain 8 Geo või samaväärne | Vundament | _ALUSKATE - drenaaži- ja kaitsematt geotekstiiliga soojustuse kaitseks, Interplast Iso-Drain 8 Geo või samaväärne
4 x _SOOJUSTUS - vahtpolüstüreenplaadid EPS 120 Perimeeter, survetugevus min. 120kPa, veeimavus <2%, soojuserijuhtivus λD<0,036 W/(mK) | Vundament | _SOOJUSTUS - vahtpolüstüreenplaadid EPS 120 Perimeeter, survetugevus min. 120kPa, veeimavus <2%, soojuserijuhtivus λD<0,036 W/(mK)
32 x _HÜDROISOLATSIOON - 3x SBS rullmaterjal vastavalt TL2 nõuetele, nakke tugevduseks betoonpind eelnevalt katta hüdroisolatsiooni bituumenvõõbaga | Vundament | _HÜDROISOLATSIOON - 3x SBS rullmaterjal vastavalt TL2 nõuetele, nakke tugevduseks betoonpind eelnevalt katta hüdroisolatsiooni bituumenvõõbaga
_PEALEVALUKIHT - raudbetoonplaat vastavalt EK osale, vajadusel põrandküte | Vundament | _PEALEVALUKIHT - raudbetoonplaat vastavalt EK osale, vajadusel põrandküte
_ERALDUSKIHT - polüetüleenkile 0,2mm, vuugid ülekattega 200mm ja teibitud | Vundament | _ERALDUSKIHT - polüetüleenkile 0,2mm, vuugid ülekattega 200mm ja teibitud
_ERALDUSKIHT - radoonitõkkekile/-membraan LEKU 280g/m² või samaväärne | Vundament | _ERALDUSKIHT - radoonitõkkekile/-membraan LEKU 280g/m² või samaväärne
22 x _TÄIDE - tasandus-/tugevduskiht, pinnasesse tambitud killustik E=80MPa, kiilutud fr 4/16 | Vundament | _TÄIDE - tasandus-/tugevduskiht, pinnasesse tambitud killustik E=80MPa, kiilutud fr 4/16
22 x _TÄIDE - tasandus-/tugevduskiht, pinnasesse tambitud killustik E=80MPa, fr 16/32 | Vundament | _TÄIDE - tasandus-/tugevduskiht, pinnasesse tambitud killustik E=80MPa, fr 16/32
4 x _PINNAS - tihendatud mineraalne tagasitäide või olemasolev pinnas, tihendusaste 92%, Emax/E1 <2.8 (vastavalt MaaRYL2010 klassile 2) | Vundament | _PINNAS - tihendatud mineraalne tagasitäide või olemasolev pinnas, tihendusaste 92%, Emax/E1 <2.8 (vastavalt MaaRYL2010 klassile 2)
3 x _PEALEVALUKIHT - raudbetoonplaat vastavalt EK osale, kalle trapi suunas 1:80 | Vundament | _PEALEVALUKIHT - raudbetoonplaat vastavalt EK osale, kalle trapi suunas 1:80
3 x _HÜDROISOLATSIOON/RADOONITÕKE - eelpaigaldatav elastne hüdroisolatsioonimembraan, värske betooniga nakkuv, radoonitihe, WFP Pre-Tec Membrane Plus või samaväärne | Vundament | _HÜDROISOLATSIOON/RADOONITÕKE - eelpaigaldatav elastne hüdroisolatsioonimembraan, värske betooniga nakkuv, radoonitihe, WFP Pre-Tec Membrane Plus või samaväärne
_VIIMISTLUSKIHT - Dold plaat vastavalt SA osale | Vundament | _VIIMISTLUSKIHT - Dold plaat vastavalt SA osale
_KARKASS - eriprofiilkinnitus vastavalt sisemisele plaatviimistlusele | Vundament | _KARKASS - eriprofiilkinnitus vastavalt sisemisele plaatviimistlusele
2 x _PLAATMATERJAL - erikõva kipsplaat, kinnitamiseks kasutada erikõvale plaadile sobivaid kruve nt XTB 3,9x55mm, Knauf Blue (Diamant) või samaväärne | Vundament | _PLAATMATERJAL - erikõva kipsplaat, kinnitamiseks kasutada erikõvale plaadile sobivaid kruve nt XTB 3,9x55mm, Knauf Blue (Diamant) või samaväärne
_KARKASS - metallkarkass CW 50/50/06 ja UW 75/40/06, samm 600, 50x50mm postid eraldiseisvalt vaheldumisi, kogupaksus 75mm, vahel mineraalvill, helineeldetegur αw = 0.85, ISOVER ACOUSTIC 50mm või samaväärne | Vundament | _KARKASS - metallkarkass CW 50/50/06 ja UW 75/40/06, samm 600, 50x50mm postid eraldiseisvalt vaheldumisi, kogupaksus 75mm, vahel mineraalvill, helineeldetegur αw = 0.85, ISOVER ACOUSTIC 50mm või samaväärne
16 x _KANDETARIND - CLT ristkihtliimpuit vastavalt EK osale, CLT paigaldusvuugid teibitakse ROTHOBLAAS teibiga | Vundament | _KANDETARIND - CLT ristkihtliimpuit vastavalt EK osale, CLT paigaldusvuugid teibitakse ROTHOBLAAS teibiga
12 x _VIIMISTLUSKIHT - viimistlus vastavalt SA osale | Vundament | _VIIMISTLUSKIHT - viimistlus vastavalt SA osale
12 x _KANDETARIND - monteeritav raudbetoon vastavalt EK osale | Vundament | _KANDETARIND - monteeritav raudbetoon vastavalt EK osale
9 x _SOOJUSTUS - ekstrudeeritud polüstüreenist plaadid XPS 250, soojuserijuhtivus lambdaD=0,035 W/mK, veeimavus alla 2%, näiteks Styrofoam 250 SL-A-N või samaväärne, plaatide vuugid omavahel nihutada | Vundament | _SOOJUSTUS - ekstrudeeritud polüstüreenist plaadid XPS 250, soojuserijuhtivus lambdaD=0,035 W/mK, veeimavus alla 2%, näiteks Styrofoam 250 SL-A-N või samaväärne, plaatide vuugid omavahel nihutada
16 x _HÜDROISOLATSIOON/RADOONITÕKE - eelpaigaldatav elastne hüdroisolatsioonimembraan, värske betooniga nakkuv, radoonitihe, FORSOC PROOFEX 3000 või samaväärne | Vundament | _HÜDROISOLATSIOON/RADOONITÕKE - eelpaigaldatav elastne hüdroisolatsioonimembraan, värske betooniga nakkuv, radoonitihe, FORSOC PROOFEX 3000 või samaväärne
8 x _KANDETARIND - monoliitne raudbetoonplaat | Vundament | _KANDETARIND - monoliitne raudbetoonplaat
56 x _KANDETARIND - CLT ristkihtliimpuit vastavalt EK osale, CLT paigaldusvuugid teibitakse ROTHOBLAAS teibiga | 1. korrus | _KANDETARIND - CLT ristkihtliimpuit vastavalt EK osale, CLT paigaldusvuugid teibitakse ROTHOBLAAS teibiga
21 x _SOOJUSTUS - mineraalvill, λD<0,032 W/(mK), kuumtsingitud lehtteras termoroovidega, S350GD+Zn275 vastavalt EN10346, ISOVER EXTREME 32 200mm või samaväärne | 1. korrus | _SOOJUSTUS - mineraalvill, λD<0,032 W/(mK), kuumtsingitud lehtteras termoroovidega, S350GD+Zn275 vastavalt EN10346, ISOVER EXTREME 32 200mm või samaväärne
21 x _TUULETÕKE - tuuletõkkeplaat, soojuserijuhtivus λD<0,031 W/(mK), ISOVER RKL FACADE või samaväärne, liitekohad katta tihendusteibiga ISOVER FacadeTape või samaväärne | 1. korrus | _TUULETÕKE - tuuletõkkeplaat, soojuserijuhtivus λD<0,031 W/(mK), ISOVER RKL FACADE või samaväärne, liitekohad katta tihendusteibiga ISOVER FacadeTape või samaväärne
21 x _KARKASS - puitroov 32x50mm vertikaalne, immutatud Driconi tulekaitsevahendiga või samaväärne, samm 600mm | 1. korrus | _KARKASS - puitroov 32x50mm vertikaalne, immutatud Driconi tulekaitsevahendiga või samaväärne, samm 600mm
21 x _KARKASS - puitroov 32x50mm horisontaalne, immutatud Driconi tulekaitsevahendiga või samaväärne, samm 600mm | 1. korrus | _KARKASS - puitroov 32x50mm horisontaalne, immutatud Driconi tulekaitsevahendiga või samaväärne, samm 600mm
21 x _VÄLISVIIMISTLUS - vertikaalne voodrilaud, Platowood P01 profiil 18x140mm, kuusk; eeltöödeldud tuletõkkega mõlemad küljed, B-s1, d0, Woodsafe Exterior WFX™ või samaväärne | 1. korrus | _VÄLISVIIMISTLUS - vertikaalne voodrilaud, Platowood P01 profiil 18x140mm, kuusk; eeltöödeldud tuletõkkega mõlemad küljed, B-s1, d0, Woodsafe Exterior WFX™ või samaväärne
353 x _VIIMISTLUSKIHT - viimistlus vastavalt SA osale | 1. korrus | _VIIMISTLUSKIHT - viimistlus vastavalt SA osale
52 x _KANDETARIND - monteeritav raudbetoon vastavalt EK osale | 1. korrus | _KANDETARIND - monteeritav raudbetoon vastavalt EK osale
81 x _VIIMISTLUSKIHT - Dold plaat vastavalt SA osale | 1. korrus | _VIIMISTLUSKIHT - Dold plaat vastavalt SA osale
107 x _KARKASS - eriprofiilkinnitus vastavalt sisemisele plaatviimistlusele | 1. korrus | _KARKASS - eriprofiilkinnitus vastavalt sisemisele plaatviimistlusele
2 x _PLAATMATERJAL - kipsplaat vastavalt ruumi nõuetele 12,5mm | 1. korrus | _PLAATMATERJAL - kipsplaat vastavalt ruumi nõuetele 12,5mm
_KARKASS - metallkarkass CW 50/50/06 ja UW 75/40/06, samm 600, 50x50mm postid eraldiseisvalt vaheldumisi, kogupaksus 75mm, vahel mineraalvill, helineeldetegur αw = 0.85, ISOVER ACOUSTIC 50mm või samaväärne | 1. korrus | _KARKASS - metallkarkass CW 50/50/06 ja UW 75/40/06, samm 600, 50x50mm postid eraldiseisvalt vaheldumisi, kogupaksus 75mm, vahel mineraalvill, helineeldetegur αw = 0.85, ISOVER ACOUSTIC 50mm või samaväärne
47 x _ÕHKVAHE | 1. korrus | _ÕHKVAHE
33 x _KARKASS - metallkarkass CW 75/50/06 ja UW 75/40/06, samm 600, vahel mineraalvill, helineeldetegur αw = 1.0, ISOVER ACOUSTIC 75mm või samaväärne | 1. korrus | _KARKASS - metallkarkass CW 75/50/06 ja UW 75/40/06, samm 600, vahel mineraalvill, helineeldetegur αw = 1.0, ISOVER ACOUSTIC 75mm või samaväärne
70 x _PLAATMATERJAL - OSB3 plaat | 1. korrus | _PLAATMATERJAL - OSB3 plaat
261 x _PLAATMATERJAL - tuletõkkekipsplaat, Knauf Red GKF või samaväärne | 1. korrus | _PLAATMATERJAL - tuletõkkekipsplaat, Knauf Red GKF või samaväärne
9 x _KARKASS - metallkarkass CW 75/50/06 ja UW 75/40/06, samm 600 | 1. korrus | _KARKASS - metallkarkass CW 75/50/06 ja UW 75/40/06, samm 600
358 x _PLAATMATERJAL - kipsplaat veekindel | 1. korrus | _PLAATMATERJAL - kipsplaat veekindel
3 x _VIIMISTLUSKIHT - keraamiline plaat sein | 1. korrus | _VIIMISTLUSKIHT - keraamiline plaat sein
52 x _KARKASS - puitpruss 100x50mm vertikaalne, samm 600mm, vahel mineraalvill, helineeldetegur αw = 1.0, ISOVER ACOUSTIC 100mm või samaväärne | 1. korrus | _KARKASS - puitpruss 100x50mm vertikaalne, samm 600mm, vahel mineraalvill, helineeldetegur αw = 1.0, ISOVER ACOUSTIC 100mm või samaväärne
74 x _KARKASS - metallkarkass CW 75/50, mineraalvill karkassi vahel | 1. korrus | _KARKASS - metallkarkass CW 75/50, mineraalvill karkassi vahel
4 x _KARKASS- distantasliist | 1. korrus | _KARKASS- distantasliist
5 x _PEALEVALUKIHT - raudbetoonplaat vastavalt EK osale, vajadusel põrandküte | 1. korrus | _PEALEVALUKIHT - raudbetoonplaat vastavalt EK osale, vajadusel põrandküte
5 x _ERALDUSKIHT - polüetüleenkile 0,2mm, vuugid ülekattega 200mm ja teibitud | 1. korrus | _ERALDUSKIHT - polüetüleenkile 0,2mm, vuugid ülekattega 200mm ja teibitud
8 x _SOOJUSTUS - vahtpolüstüreenplaadid EPS 120 Perimeeter, survetugevus min 120kPa, veeimavus <2%, soojuserijuhtivus λD<0,036 W/(mK) | 1. korrus | _SOOJUSTUS - vahtpolüstüreenplaadid EPS 120 Perimeeter, survetugevus min 120kPa, veeimavus <2%, soojuserijuhtivus λD<0,036 W/(mK)
4 x _ERALDUSKIHT - radoonitõkkekile/-membraan LEKU 280g/m² või samaväärne | 1. korrus | _ERALDUSKIHT - radoonitõkkekile/-membraan LEKU 280g/m² või samaväärne
4 x _TÄIDE - tasandus-/tugevduskiht, pinnasesse tambitud killustik E=80MPa, kiilutud fr 4/16 | 1. korrus | _TÄIDE - tasandus-/tugevduskiht, pinnasesse tambitud killustik E=80MPa, kiilutud fr 4/16
4 x _TÄIDE - tasandus-/tugevduskiht, pinnasesse tambitud killustik E=80MPa, fr 16/32 | 1. korrus | _TÄIDE - tasandus-/tugevduskiht, pinnasesse tambitud killustik E=80MPa, fr 16/32
4 x _PINNAS - tihendatud mineraalne tagasitäide või olemasolev pinnas, tihendusaste 92%, Emax/E1 <2.8 (vastavalt MaaRYL2010 klassile 2) | 1. korrus | _PINNAS - tihendatud mineraalne tagasitäide või olemasolev pinnas, tihendusaste 92%, Emax/E1 <2.8 (vastavalt MaaRYL2010 klassile 2)
8 x _KARKASS - metallkarkass CW 66/35/06, samm 600, mineraalvill karkassi vahel | 1. korrus | _KARKASS - metallkarkass CW 66/35/06, samm 600, mineraalvill karkassi vahel
7 x _VIIMISTLUSKIHT - puit | 1. korrus | _VIIMISTLUSKIHT - puit
7 x _KANDETARIND - raudbetoon C25/30 vastavalt EK osale | 1. korrus | _KANDETARIND - raudbetoon C25/30 vastavalt EK osale
44 x _KARKASS - metallkarkass CW 100/50/06 ja UW 100/40/06, samm 600, vahel mineraalvill, helineeldetegur αw = 1.0, ISOVER ACOUSTIC 100mm või samaväärne | 1. korrus | _KARKASS - metallkarkass CW 100/50/06 ja UW 100/40/06, samm 600, vahel mineraalvill, helineeldetegur αw = 1.0, ISOVER ACOUSTIC 100mm või samaväärne
_PLAATMATERJAL - vineerplaat | 1. korrus | _PLAATMATERJAL - vineerplaat
_KARKASS - roov 50x50mm, s. 600 mm, kinnitus puidukruvidega | 1. korrus | _KARKASS - roov 50x50mm, s. 600 mm, kinnitus puidukruvidega
14 x _KANDETARIND - monoliitne raudbetoon vastavalt EK osale | 1. korrus | _KANDETARIND - monoliitne raudbetoon vastavalt EK osale
12 x _HÜDROISOLATSIOON/RADOONITÕKE - eelpaigaldatav elastne hüdroisolatsioonimembraan, värske betooniga nakkuv, radoonitihe, FORSOC PROOFEX 3000 või samaväärne | 1. korrus | _HÜDROISOLATSIOON/RADOONITÕKE - eelpaigaldatav elastne hüdroisolatsioonimembraan, värske betooniga nakkuv, radoonitihe, FORSOC PROOFEX 3000 või samaväärne
12 x _SOOJUSTUS - vahtpolüstüreenplaadid EPS 120 Perimeeter, survetugevus min. 120kPa, veeimavus <2%, soojuserijuhtivus λD<0,036 W/(mK) | 1. korrus | _SOOJUSTUS - vahtpolüstüreenplaadid EPS 120 Perimeeter, survetugevus min. 120kPa, veeimavus <2%, soojuserijuhtivus λD<0,036 W/(mK)
12 x _ALUSKATE - drenaaži- ja kaitsematt geotekstiiliga soojustuse kaitseks, Interplast Iso-Drain 8 Geo või samaväärne | 1. korrus | _ALUSKATE - drenaaži- ja kaitsematt geotekstiiliga soojustuse kaitseks, Interplast Iso-Drain 8 Geo või samaväärne
_SOOJUSTUS - vahtpolüstüreenplaadid EPS 80, survetugevus min 80kPa, soojuserijuhtivus λD<0,038 W/(mK); sulundplaadid või vähemalt 2 kihti plaate ja plaadikihtide vuugid teineteise suhtes nihkes. | 1. korrus | _SOOJUSTUS - vahtpolüstüreenplaadid EPS 80, survetugevus min 80kPa, soojuserijuhtivus λD<0,038 W/(mK); sulundplaadid või vähemalt 2 kihti plaate ja plaadikihtide vuugid teineteise suhtes nihkes.
_ERALDUSKIHT - radoonitõkkekile/-membraan 0,5mm, radoonitakistus 6,1x(10 astmes 11) m2*s*Pa/kg, Delta-Radonsperre 450g/m² või samaväärne | 1. korrus | _ERALDUSKIHT - radoonitõkkekile/-membraan 0,5mm, radoonitakistus 6,1x(10 astmes 11) m2*s*Pa/kg, Delta-Radonsperre 450g/m² või samaväärne
_PLAATMATERJAL - niiskuskindel vineerplaat, kvaliteediklass BB | 1. korrus | _PLAATMATERJAL - niiskuskindel vineerplaat, kvaliteediklass BB
_KARKASS - puitroov 32x32mm, s. 600mm | 1. korrus | _KARKASS - puitroov 32x32mm, s. 600mm
_KANDETARIND - kergplokk Fibo3 200mm | 1. korrus | _KANDETARIND - kergplokk Fibo3 200mm
73 x _KANDETARIND - CLT ristkihtliimpuit vastavalt EK osale, CLT paigaldusvuugid teibitakse ROTHOBLAAS teibiga | 2. korrus | _KANDETARIND - CLT ristkihtliimpuit vastavalt EK osale, CLT paigaldusvuugid teibitakse ROTHOBLAAS teibiga
28 x _SOOJUSTUS - mineraalvill, λD<0,032 W/(mK), kuumtsingitud lehtteras termoroovidega, S350GD+Zn275 vastavalt EN10346, ISOVER EXTREME 32 200mm või samaväärne | 2. korrus | _SOOJUSTUS - mineraalvill, λD<0,032 W/(mK), kuumtsingitud lehtteras termoroovidega, S350GD+Zn275 vastavalt EN10346, ISOVER EXTREME 32 200mm või samaväärne
30 x _TUULETÕKE - tuuletõkkeplaat, soojuserijuhtivus λD<0,031 W/(mK), ISOVER RKL FACADE või samaväärne, liitekohad katta tihendusteibiga ISOVER FacadeTape või samaväärne | 2. korrus | _TUULETÕKE - tuuletõkkeplaat, soojuserijuhtivus λD<0,031 W/(mK), ISOVER RKL FACADE või samaväärne, liitekohad katta tihendusteibiga ISOVER FacadeTape või samaväärne
30 x _KARKASS - puitroov 32x50mm vertikaalne, immutatud Driconi tulekaitsevahendiga või samaväärne, samm 600mm | 2. korrus | _KARKASS - puitroov 32x50mm vertikaalne, immutatud Driconi tulekaitsevahendiga või samaväärne, samm 600mm
26 x _KARKASS - puitroov 32x50mm horisontaalne, immutatud Driconi tulekaitsevahendiga või samaväärne, samm 600mm | 2. korrus | _KARKASS - puitroov 32x50mm horisontaalne, immutatud Driconi tulekaitsevahendiga või samaväärne, samm 600mm
29 x _VÄLISVIIMISTLUS - vertikaalne voodrilaud, Platowood P01 profiil 18x140mm, kuusk; eeltöödeldud tuletõkkega mõlemad küljed, B-s1, d0, Woodsafe Exterior WFX™ või samaväärne | 2. korrus | _VÄLISVIIMISTLUS - vertikaalne voodrilaud, Platowood P01 profiil 18x140mm, kuusk; eeltöödeldud tuletõkkega mõlemad küljed, B-s1, d0, Woodsafe Exterior WFX™ või samaväärne
34 x _VIIMISTLUSKIHT - Dold plaat vastavalt SA osale | 2. korrus | _VIIMISTLUSKIHT - Dold plaat vastavalt SA osale
47 x _KARKASS - eriprofiilkinnitus vastavalt sisemisele plaatviimistlusele | 2. korrus | _KARKASS - eriprofiilkinnitus vastavalt sisemisele plaatviimistlusele
12 x _PLAATMATERJAL - kipsplaat vastavalt ruumi nõuetele 12,5mm | 2. korrus | _PLAATMATERJAL - kipsplaat vastavalt ruumi nõuetele 12,5mm
2 x _KARKASS - metallkarkass CW 50/50/06 ja UW 75/40/06, samm 600, 50x50mm postid eraldiseisvalt vaheldumisi, kogupaksus 75mm, vahel mineraalvill, helineeldetegur αw = 0.85, ISOVER ACOUSTIC 50mm või samaväärne | 2. korrus | _KARKASS - metallkarkass CW 50/50/06 ja UW 75/40/06, samm 600, 50x50mm postid eraldiseisvalt vaheldumisi, kogupaksus 75mm, vahel mineraalvill, helineeldetegur αw = 0.85, ISOVER ACOUSTIC 50mm või samaväärne
233 x _VIIMISTLUSKIHT - viimistlus vastavalt SA osale | 2. korrus | _VIIMISTLUSKIHT - viimistlus vastavalt SA osale
173 x _PLAATMATERJAL - tuletõkkekipsplaat, Knauf Red GKF või samaväärne | 2. korrus | _PLAATMATERJAL - tuletõkkekipsplaat, Knauf Red GKF või samaväärne
63 x _PLAATMATERJAL - OSB3 plaat | 2. korrus | _PLAATMATERJAL - OSB3 plaat
5 x _KARKASS - metallkarkass CW 66/35/06, samm 600, mineraalvill karkassi vahel | 2. korrus | _KARKASS - metallkarkass CW 66/35/06, samm 600, mineraalvill karkassi vahel
50 x _KANDETARIND - monteeritav raudbetoon vastavalt EK osale | 2. korrus | _KANDETARIND - monteeritav raudbetoon vastavalt EK osale
39 x _KARKASS - metallkarkass CW 75/50/06 ja UW 75/40/06, samm 600, vahel mineraalvill, helineeldetegur αw = 1.0, ISOVER ACOUSTIC 75mm või samaväärne | 2. korrus | _KARKASS - metallkarkass CW 75/50/06 ja UW 75/40/06, samm 600, vahel mineraalvill, helineeldetegur αw = 1.0, ISOVER ACOUSTIC 75mm või samaväärne
46 x _ÕHKVAHE | 2. korrus | _ÕHKVAHE
8 x _KARKASS - puitroov 70x45mm vertikaalne, samm 600mm, vahel mineraalvill, helineeldetegur αw = 1.0, ISOVER ACOUSTIC 70mm või samaväärne | 2. korrus | _KARKASS - puitroov 70x45mm vertikaalne, samm 600mm, vahel mineraalvill, helineeldetegur αw = 1.0, ISOVER ACOUSTIC 70mm või samaväärne
18 x _KARKASS- distantasliist | 2. korrus | _KARKASS- distantasliist
15 x _KARKASS - puitpruss 100x50mm vertikaalne, samm 600mm, vahel mineraalvill, helineeldetegur αw = 1.0, ISOVER ACOUSTIC 100mm või samaväärne | 2. korrus | _KARKASS - puitpruss 100x50mm vertikaalne, samm 600mm, vahel mineraalvill, helineeldetegur αw = 1.0, ISOVER ACOUSTIC 100mm või samaväärne
5 x _KANDETARIND - kergplokk Fibo3 200mm | 2. korrus | _KANDETARIND - kergplokk Fibo3 200mm
122 x _PLAATMATERJAL - kipsplaat veekindel | 2. korrus | _PLAATMATERJAL - kipsplaat veekindel
18 x _KARKASS - metallkarkass CW 75/50, mineraalvill karkassi vahel | 2. korrus | _KARKASS - metallkarkass CW 75/50, mineraalvill karkassi vahel
12 x _PEALEVALUKIHT - raudbetoonplaat vastavalt EK osale, vajadusel põrandküte | 2. korrus | _PEALEVALUKIHT - raudbetoonplaat vastavalt EK osale, vajadusel põrandküte
12 x _ISOLATSIOON - löögimüraisolatsioon, mineraalvill, koormustaluvus min 20 kPa, dünaamiline jäikus 16 MN/m³, ISOVER FLO või samaväärne | 2. korrus | _ISOLATSIOON - löögimüraisolatsioon, mineraalvill, koormustaluvus min 20 kPa, dünaamiline jäikus 16 MN/m³, ISOVER FLO või samaväärne
9 x _SOOJUSTUS - vahtpolüstüreenplaadid EPS 80, survetugevus min 80kPa, soojuserijuhtivus λD<0,038 W/(mK) | 2. korrus | _SOOJUSTUS - vahtpolüstüreenplaadid EPS 80, survetugevus min 80kPa, soojuserijuhtivus λD<0,038 W/(mK)
_METALL - alumiinium | 2. korrus | _METALL - alumiinium
Machine_Green | 2. korrus | Machine_Green
36 x _KARKASS - metallkarkass CW 100/50/06 ja UW 100/40/06, samm 600, vahel mineraalvill, helineeldetegur αw = 1.0, ISOVER ACOUSTIC 100mm või samaväärne | 2. korrus | _KARKASS - metallkarkass CW 100/50/06 ja UW 100/40/06, samm 600, vahel mineraalvill, helineeldetegur αw = 1.0, ISOVER ACOUSTIC 100mm või samaväärne
6 x _KARKASS - mütsprofiil MP-27, kuumtsingitud teras | 2. korrus | _KARKASS - mütsprofiil MP-27, kuumtsingitud teras
6 x _PLAATMATERJAL - niiskuskindel vineerplaat, kvaliteediklass BB | 2. korrus | _PLAATMATERJAL - niiskuskindel vineerplaat, kvaliteediklass BB
_KARKASS - puitroov 50x130mm, s. 600mm | 2. korrus | _KARKASS - puitroov 50x130mm, s. 600mm
2 x _KARKASS - puitpruss 70x70mm sammuga 600mm, vahel SOOJUSTUS - mineraalvill, soojuserijuhtivus λD<0,032 W/(mK), ISOVER EXTREME 32 70mm või samaväärne | 2. korrus | _KARKASS - puitpruss 70x70mm sammuga 600mm, vahel SOOJUSTUS - mineraalvill, soojuserijuhtivus λD<0,032 W/(mK), ISOVER EXTREME 32 70mm või samaväärne
3 x _SOOJUSTUS - jäik mineraalvillaplaat, vastavalt RIL 107-2012-le, R3, survetugevus min 60kPa, soojuserijuhtivus λD<0,037 W/(mK), ISOVER OL-TOP või samaväärne | 2. korrus | _SOOJUSTUS - jäik mineraalvillaplaat, vastavalt RIL 107-2012-le, R3, survetugevus min 60kPa, soojuserijuhtivus λD<0,037 W/(mK), ISOVER OL-TOP või samaväärne
3 x _SOOJUSTUS - mineraalvillaplaat, survetugevus min 60kPa, soojuserijuhtivus λD<0,037 W/(mK), ISOVER OL-P või samaväärne | 2. korrus | _SOOJUSTUS - mineraalvillaplaat, survetugevus min 60kPa, soojuserijuhtivus λD<0,037 W/(mK), ISOVER OL-P või samaväärne
3 x _AURUTÕKE - külmkleebitav aurutõkkekile Bytum 400 või samaväärne | 2. korrus | _AURUTÕKE - külmkleebitav aurutõkkekile Bytum 400 või samaväärne
5 x _KANDETARIND - raudbetoon C25/30 vastavalt EK osale | 2. korrus | _KANDETARIND - raudbetoon C25/30 vastavalt EK osale
8 x _KANDETARIND - kergplokk Fibo 100mm | 2. korrus | _KANDETARIND - kergplokk Fibo 100mm
4 x _PLAATMATERJAL - erikõva kipsplaat, kinnitamiseks kasutada erikõvale plaadile sobivaid kruve nt XTB 3,9x55mm, Knauf Blue (Diamant) või samaväärne | 2. korrus | _PLAATMATERJAL - erikõva kipsplaat, kinnitamiseks kasutada erikõvale plaadile sobivaid kruve nt XTB 3,9x55mm, Knauf Blue (Diamant) või samaväärne
2 x _ERALDUSKIHT - polüetüleenkile 0,2mm, vuugid ülekattega 200mm ja teibitud | 2. korrus | _ERALDUSKIHT - polüetüleenkile 0,2mm, vuugid ülekattega 200mm ja teibitud
2 x _SOOJUSTUS - mineraalvill, λD<0,032 W/(mK), kuumtsingitud lehtteras termoroovidega, S350GD+Zn275 vastavalt EN10346, ISOVER EXTREME 32 100mm või samaväärne | 2. korrus | _SOOJUSTUS - mineraalvill, λD<0,032 W/(mK), kuumtsingitud lehtteras termoroovidega, S350GD+Zn275 vastavalt EN10346, ISOVER EXTREME 32 100mm või samaväärne
2 x _ÕHK | 2. korrus | _ÕHK
2 x _KARKASS - kübarprofiil 50mm, samm 600mm, kuumtsingitud teras | 2. korrus | _KARKASS - kübarprofiil 50mm, samm 600mm, kuumtsingitud teras
3 x _ISOLATSIOON - tihendatud mineraalne täide, minimaalne tihedus ≥1800 kg/m3 | 2. korrus | _ISOLATSIOON - tihendatud mineraalne täide, minimaalne tihedus ≥1800 kg/m3
_KARKASS - metallkarkass CW 50/50/06 ja UW 50/40/06, samm 600, vahel mineraalvill, helineeldetegur αw = 0.85, ISOVER ACOUSTIC 50mm või samaväärne | 2. korrus | _KARKASS - metallkarkass CW 50/50/06 ja UW 50/40/06, samm 600, vahel mineraalvill, helineeldetegur αw = 0.85, ISOVER ACOUSTIC 50mm või samaväärne
2 x _VIIMISTLUSKIHT - spordipõrand vastavalt SA osale | 2. korrus | _VIIMISTLUSKIHT - spordipõrand vastavalt SA osale
_SOOJUSTUS - vill | 2. korrus | _SOOJUSTUS - vill
_EHITUS - akustiline riputussüsteem AMC EP 400+Sylomer 75, s 1,2m | 2. korrus | _EHITUS - akustiline riputussüsteem AMC EP 400+Sylomer 75, s 1,2m
2 x _UJUV TARIND - täitematerjal 1800 kg/m3 | 2. korrus | _UJUV TARIND - täitematerjal 1800 kg/m3
2 x _SOOJUSTUS - mürasummutav mineraalvill ISOVER FLO | 2. korrus | _SOOJUSTUS - mürasummutav mineraalvill ISOVER FLO
2 x _SOOJUSTUS - vahtploüstüreenplaadid EPS100 | 2. korrus | _SOOJUSTUS - vahtploüstüreenplaadid EPS100
2 x _KANDETARIND - monteeritav raudbetoon õõnespaneel, C50/60, eelpingestatud copy | 2. korrus | _KANDETARIND - monteeritav raudbetoon õõnespaneel, C50/60, eelpingestatud copy
_KARKASS - puitroov 32x32mm, s. 600mm | 2. korrus | _KARKASS - puitroov 32x32mm, s. 600mm
_VIIMISTLUSKIHT - must akustiline fliis vastavalt SA osale | 2. korrus | _VIIMISTLUSKIHT - must akustiline fliis vastavalt SA osale
3 x _SOOJUSTUS - akustiline vill Ecophon Industry must TAL PE 50mm või samaväärne | 2. korrus | _SOOJUSTUS - akustiline vill Ecophon Industry must TAL PE 50mm või samaväärne
_KARKASS - puitroov 60x40mm, s. 600mm | 2. korrus | _KARKASS - puitroov 60x40mm, s. 600mm
_KARKASS - distantsliist 18x45mm, s. 600mm | 2. korrus | _KARKASS - distantsliist 18x45mm, s. 600mm
_KARKASS - puitroov 70x50mm, s. 600mm | 2. korrus | _KARKASS - puitroov 70x50mm, s. 600mm
_KARKASS - distantsliist 22x50mm, s. 600mm | 2. korrus | _KARKASS - distantsliist 22x50mm, s. 600mm
2 x _KARKASS - metallkarkass CW 66/35/06, samm 600 | 2. korrus | _KARKASS - metallkarkass CW 66/35/06, samm 600
61 x _HÜDROISOLATSIOON - katusekate PVC rullmaterjal, vastavalt RIL 107-2012-le, helehall F91, Protan SE või samaväärne | 3. korrus | _HÜDROISOLATSIOON - katusekate PVC rullmaterjal, vastavalt RIL 107-2012-le, helehall F91, Protan SE või samaväärne
48 x _SOOJUSTUS - jäik mineraalvillaplaat, vastavalt RIL 107-2012-le, R3, survetugevus min 60kPa, soojuserijuhtivus λD<0,037 W/(mK), ISOVER OL-TOP või samaväärne | 3. korrus | _SOOJUSTUS - jäik mineraalvillaplaat, vastavalt RIL 107-2012-le, R3, survetugevus min 60kPa, soojuserijuhtivus λD<0,037 W/(mK), ISOVER OL-TOP või samaväärne
41 x _SOOJUSTUS - jäik mineraalvillaplaat tuulutussoontega, vastavalt RIL 107-2012-le, R3, survetugevus min 60kPa, soojuserijuhtivus λD<0,037 W/(mK), ISOVER OL-TOP/U või samaväärne | 3. korrus | _SOOJUSTUS - jäik mineraalvillaplaat tuulutussoontega, vastavalt RIL 107-2012-le, R3, survetugevus min 60kPa, soojuserijuhtivus λD<0,037 W/(mK), ISOVER OL-TOP/U või samaväärne
34 x _SOOJUSTUS - kergkruus fraktsioon 10-20, 50-150mm kiht kallete andmiseks | 3. korrus | _SOOJUSTUS - kergkruus fraktsioon 10-20, 50-150mm kiht kallete andmiseks
34 x _SOOJUSTUS - jäik mineraalvillaplaat paigaldatud treppi, vastavalt RIL 107-2012-le, R3, survetugevus min 60kPa, soojuserijuhtivus λD<0,037 W/(mK), ISOVER OL-TOP või samaväärne | 3. korrus | _SOOJUSTUS - jäik mineraalvillaplaat paigaldatud treppi, vastavalt RIL 107-2012-le, R3, survetugevus min 60kPa, soojuserijuhtivus λD<0,037 W/(mK), ISOVER OL-TOP või samaväärne
52 x _KANDETARIND - CLT ristkihtliimpuit vastavalt EK osale, CLT paigaldusvuugid teibitakse ROTHOBLAAS teibiga | 3. korrus | _KANDETARIND - CLT ristkihtliimpuit vastavalt EK osale, CLT paigaldusvuugid teibitakse ROTHOBLAAS teibiga
34 x _ÕHKVAHE | 3. korrus | _ÕHKVAHE
27 x _KARKASS - metallkarkass CW 75/50/06 ja UW 75/40/06, samm 600, vahel mineraalvill, helineeldetegur αw = 1.0, ISOVER ACOUSTIC 75mm või samaväärne | 3. korrus | _KARKASS - metallkarkass CW 75/50/06 ja UW 75/40/06, samm 600, vahel mineraalvill, helineeldetegur αw = 1.0, ISOVER ACOUSTIC 75mm või samaväärne
67 x _PLAATMATERJAL - OSB3 plaat | 3. korrus | _PLAATMATERJAL - OSB3 plaat
166 x _PLAATMATERJAL - tuletõkkekipsplaat, Knauf Red GKF või samaväärne | 3. korrus | _PLAATMATERJAL - tuletõkkekipsplaat, Knauf Red GKF või samaväärne
206 x _VIIMISTLUSKIHT - viimistlus vastavalt SA osale | 3. korrus | _VIIMISTLUSKIHT - viimistlus vastavalt SA osale
13 x _PEALEVALUKIHT - raudbetoonplaat vastavalt EK osale, vajadusel põrandküte | 3. korrus | _PEALEVALUKIHT - raudbetoonplaat vastavalt EK osale, vajadusel põrandküte
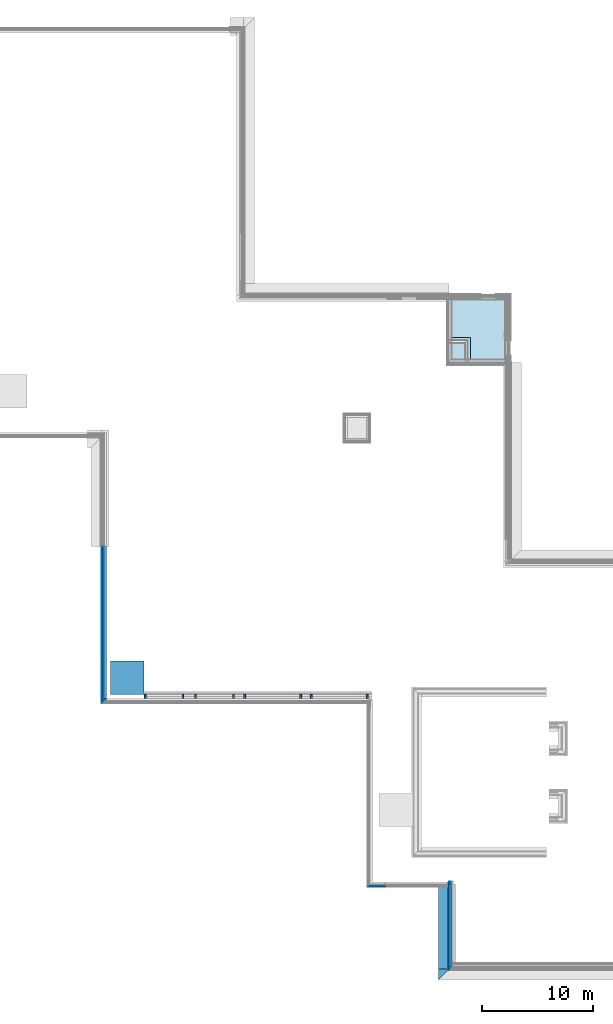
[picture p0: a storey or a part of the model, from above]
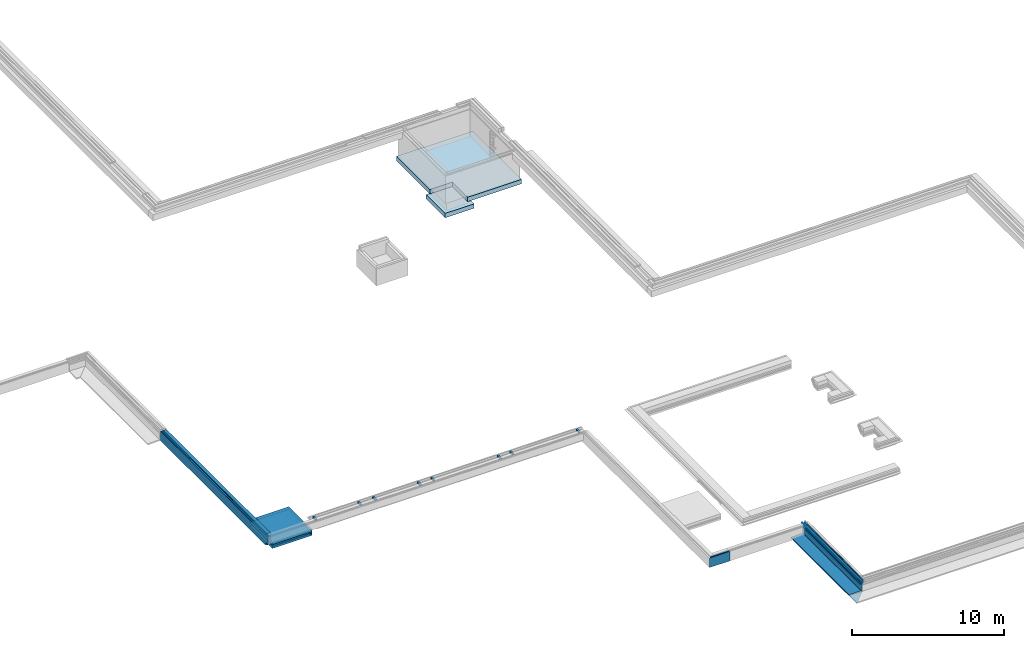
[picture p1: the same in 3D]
Properties of the parts of a building model (IFC2X3), part 2 of 14

# IfcBuildingElementPart (5798)
Name | In | Material
13 x _ISOLATSIOON - löögimüraisolatsioon, mineraalvill, koormustaluvus min 20 kPa, dünaamiline jäikus 16 MN/m³, ISOVER FLO või samaväärne | 3. korrus | _ISOLATSIOON - löögimüraisolatsioon, mineraalvill, koormustaluvus min 20 kPa, dünaamiline jäikus 16 MN/m³, ISOVER FLO või samaväärne
13 x _SOOJUSTUS - vahtpolüstüreenplaadid EPS 80, survetugevus min 80kPa, soojuserijuhtivus λD<0,038 W/(mK) | 3. korrus | _SOOJUSTUS - vahtpolüstüreenplaadid EPS 80, survetugevus min 80kPa, soojuserijuhtivus λD<0,038 W/(mK)
_UJUV TARIND - täitematerjal kergkruus 320 kg/m3 | 3. korrus | _UJUV TARIND - täitematerjal kergkruus 320 kg/m3
20 x _SOOJUSTUS - mineraalvill, λD<0,032 W/(mK), kuumtsingitud lehtteras termoroovidega, S350GD+Zn275 vastavalt EN10346, ISOVER EXTREME 32 200mm või samaväärne | 3. korrus | _SOOJUSTUS - mineraalvill, λD<0,032 W/(mK), kuumtsingitud lehtteras termoroovidega, S350GD+Zn275 vastavalt EN10346, ISOVER EXTREME 32 200mm või samaväärne
29 x _TUULETÕKE - tuuletõkkeplaat, soojuserijuhtivus λD<0,031 W/(mK), ISOVER RKL FACADE või samaväärne, liitekohad katta tihendusteibiga ISOVER FacadeTape või samaväärne | 3. korrus | _TUULETÕKE - tuuletõkkeplaat, soojuserijuhtivus λD<0,031 W/(mK), ISOVER RKL FACADE või samaväärne, liitekohad katta tihendusteibiga ISOVER FacadeTape või samaväärne
27 x _KARKASS - puitroov 32x50mm vertikaalne, immutatud Driconi tulekaitsevahendiga või samaväärne, samm 600mm | 3. korrus | _KARKASS - puitroov 32x50mm vertikaalne, immutatud Driconi tulekaitsevahendiga või samaväärne, samm 600mm
32 x _KARKASS - puitroov 32x50mm horisontaalne, immutatud Driconi tulekaitsevahendiga või samaväärne, samm 600mm | 3. korrus | _KARKASS - puitroov 32x50mm horisontaalne, immutatud Driconi tulekaitsevahendiga või samaväärne, samm 600mm
27 x _VÄLISVIIMISTLUS - vertikaalne voodrilaud, Platowood P01 profiil 18x140mm, kuusk; eeltöödeldud tuletõkkega mõlemad küljed, B-s1, d0, Woodsafe Exterior WFX™ või samaväärne | 3. korrus | _VÄLISVIIMISTLUS - vertikaalne voodrilaud, Platowood P01 profiil 18x140mm, kuusk; eeltöödeldud tuletõkkega mõlemad küljed, B-s1, d0, Woodsafe Exterior WFX™ või samaväärne
2 x _PLAATMATERJAL - niiskuskindel vineerplaat, kvaliteediklass BB | 3. korrus | _PLAATMATERJAL - niiskuskindel vineerplaat, kvaliteediklass BB
2 x _KARKASS - puitroov 50x130mm, s. 600mm | 3. korrus | _KARKASS - puitroov 50x130mm, s. 600mm
26 x _VIIMISTLUSKIHT - Dold plaat vastavalt SA osale | 3. korrus | _VIIMISTLUSKIHT - Dold plaat vastavalt SA osale
40 x _KARKASS - eriprofiilkinnitus vastavalt sisemisele plaatviimistlusele | 3. korrus | _KARKASS - eriprofiilkinnitus vastavalt sisemisele plaatviimistlusele
8 x _PLAATMATERJAL - kipsplaat vastavalt ruumi nõuetele 12,5mm | 3. korrus | _PLAATMATERJAL - kipsplaat vastavalt ruumi nõuetele 12,5mm
2 x _KARKASS - metallkarkass CW 50/50/06 ja UW 75/40/06, samm 600, 50x50mm postid eraldiseisvalt vaheldumisi, kogupaksus 75mm, vahel mineraalvill, helineeldetegur αw = 0.85, ISOVER ACOUSTIC 50mm või samaväärne | 3. korrus | _KARKASS - metallkarkass CW 50/50/06 ja UW 75/40/06, samm 600, 50x50mm postid eraldiseisvalt vaheldumisi, kogupaksus 75mm, vahel mineraalvill, helineeldetegur αw = 0.85, ISOVER ACOUSTIC 50mm või samaväärne
11 x _KARKASS - metallkarkass CW 66/35/06, samm 600, mineraalvill karkassi vahel | 3. korrus | _KARKASS - metallkarkass CW 66/35/06, samm 600, mineraalvill karkassi vahel
37 x _KANDETARIND - monteeritav raudbetoon vastavalt EK osale | 3. korrus | _KANDETARIND - monteeritav raudbetoon vastavalt EK osale
23 x _KARKASS - puitpruss 100x50mm vertikaalne, samm 600mm, vahel mineraalvill, helineeldetegur αw = 1.0, ISOVER ACOUSTIC 100mm või samaväärne | 3. korrus | _KARKASS - puitpruss 100x50mm vertikaalne, samm 600mm, vahel mineraalvill, helineeldetegur αw = 1.0, ISOVER ACOUSTIC 100mm või samaväärne
26 x _KARKASS- distantasliist | 3. korrus | _KARKASS- distantasliist
2 x _KARKASS - metallkarkass VP 120/40 | 3. korrus | _KARKASS - metallkarkass VP 120/40
2 x _KARKASS - teraskarkass vastavalt EK osale, vahel mineraalvillaplaat soojuserijuhtivus λD<0,035 W/(mK), kuumtsingitud lehtterasest termoroovidega, S350GD+Zn275 vastavalt EN10346, ISOVER OL-E 35 või samaväärne | 3. korrus | _KARKASS - teraskarkass vastavalt EK osale, vahel mineraalvillaplaat soojuserijuhtivus λD<0,035 W/(mK), kuumtsingitud lehtterasest termoroovidega, S350GD+Zn275 vastavalt EN10346, ISOVER OL-E 35 või samaväärne
6 x _KARKASS - puitroov 50x50mm vertikaalne, sügavimmutatud, samm 600mm | 3. korrus | _KARKASS - puitroov 50x50mm vertikaalne, sügavimmutatud, samm 600mm
24 x _PLAATMATERJAL - veekindla pinnaga niiskuskindel kuusevineer vastavalt EN 314 klass 3, BS 1203/H4, DIN 68705 osa 3 tüüp BFU nõuetele, lõikeserv ja õhuga kokkupuutuv pind kaitsta puidukaitsevahendiga, nt 2x Pinotex Impra | 3. korrus | _PLAATMATERJAL - veekindla pinnaga niiskuskindel kuusevineer vastavalt EN 314 klass 3, BS 1203/H4, DIN 68705 osa 3 tüüp BFU nõuetele, lõikeserv ja õhuga kokkupuutuv pind kaitsta puidukaitsevahendiga, nt 2x Pinotex Impra
6 x _KANDETARIND - puitkarkass vastavalt EK osale | 3. korrus | _KANDETARIND - puitkarkass vastavalt EK osale
18 x _ERALDUSKIHT - siirdetõke, min 140g/m2, Fibertex F2B 140g/m2 või samaväärne | 3. korrus | _ERALDUSKIHT - siirdetõke, min 140g/m2, Fibertex F2B 140g/m2 või samaväärne
2 x _SOOJUSTUS - mineraalvill, λD<0,032 W/(mK)+ kahekordne puitsõrestik 250x50+ 50x50 mm, ISOVER EXTREME 32 või samaväärne | 3. korrus | _SOOJUSTUS - mineraalvill, λD<0,032 W/(mK)+ kahekordne puitsõrestik 250x50+ 50x50 mm, ISOVER EXTREME 32 või samaväärne
_KARKASS - õhkvahe+kahekordne metallkarkass CD 60/27/06 samm 600x600mm, riputite samm 600 mm | 3. korrus | _KARKASS - õhkvahe+kahekordne metallkarkass CD 60/27/06 samm 600x600mm, riputite samm 600 mm
100 x _PLAATMATERJAL - kipsplaat veekindel | 3. korrus | _PLAATMATERJAL - kipsplaat veekindel
18 x _KARKASS - metallkarkass CW 100/50/06 ja UW 100/40/06, samm 600, vahel mineraalvill, helineeldetegur αw = 1.0, ISOVER ACOUSTIC 100mm või samaväärne | 3. korrus | _KARKASS - metallkarkass CW 100/50/06 ja UW 100/40/06, samm 600, vahel mineraalvill, helineeldetegur αw = 1.0, ISOVER ACOUSTIC 100mm või samaväärne
19 x _KARKASS - metallkarkass CW 75/50, mineraalvill karkassi vahel | 3. korrus | _KARKASS - metallkarkass CW 75/50, mineraalvill karkassi vahel
5 x _SOOJUSTUS - akustiline vill Ecophon Industry must TAL PE 50mm või samaväärne | 3. korrus | _SOOJUSTUS - akustiline vill Ecophon Industry must TAL PE 50mm või samaväärne
3 x _AURUTÕKE - aurutõkkekile, vuugid ülekattega teibitud, veeaurutakistus Sd0,3 kuni 25m, ISOVER Vario auru- ja õhutõkkesüsteem (Vario Xtra aurutõkkekile, Vario MultiTape SL, Vario DF) või samaväärne | 3. korrus | _AURUTÕKE - aurutõkkekile, vuugid ülekattega teibitud, veeaurutakistus Sd0,3 kuni 25m, ISOVER Vario auru- ja õhutõkkesüsteem (Vario Xtra aurutõkkekile, Vario MultiTape SL, Vario DF) või samaväärne
7 x _KARKASS - puitpruss 195x45mm sammuga 600mm vastavalt EK osale, vahel SOOJUSTUS - mineraalvill, soojuserijuhtivus λD<0,032 W/(mK), ISOVER EXTREME 32 200mm või samaväärne | 3. korrus | _KARKASS - puitpruss 195x45mm sammuga 600mm vastavalt EK osale, vahel SOOJUSTUS - mineraalvill, soojuserijuhtivus λD<0,032 W/(mK), ISOVER EXTREME 32 200mm või samaväärne
4 x _AURUTÕKE - aurutõkkekile, vuugid ülekattega teibitud, veeaurutakistus Sd 0,3 kuni 25m, ISOVER Vario auru- ja õhutõkkesüsteem (Vario Xtra aurutõkkekile, Vario MultiTape SL, Vario DF) või samaväärne | 3. korrus | _AURUTÕKE - aurutõkkekile, vuugid ülekattega teibitud, veeaurutakistus Sd 0,3 kuni 25m, ISOVER Vario auru- ja õhutõkkesüsteem (Vario Xtra aurutõkkekile, Vario MultiTape SL, Vario DF) või samaväärne
4 x _KARKASS - mütsprofiil MP-27, kuumtsingitud teras | 3. korrus | _KARKASS - mütsprofiil MP-27, kuumtsingitud teras
3 x _SOOJUSTUS - mineraalvillaplaat, survetugevus min 60kPa, soojuserijuhtivus λD<0,037 W/(mK), ISOVER OL-P või samaväärne | 3. korrus | _SOOJUSTUS - mineraalvillaplaat, survetugevus min 60kPa, soojuserijuhtivus λD<0,037 W/(mK), ISOVER OL-P või samaväärne
3 x _AURUTÕKE - külmkleebitav aurutõkkekile Bytum 400 või samaväärne | 3. korrus | _AURUTÕKE - külmkleebitav aurutõkkekile Bytum 400 või samaväärne
5 x _KARKASS - puitroov 50x50mm horisontaalne, sügavimmutatud, samm 600mm | 3. korrus | _KARKASS - puitroov 50x50mm horisontaalne, sügavimmutatud, samm 600mm
2 x _KANDETARIND - profiilplekk T130M-75L-930-1.2 vastavalt EK osale | 3. korrus | _KANDETARIND - profiilplekk T130M-75L-930-1.2 vastavalt EK osale
4 x _KANDETARIND - kergplokk Fibo 100mm | 3. korrus | _KANDETARIND - kergplokk Fibo 100mm
2 x _ISOLATSIOON - tihendatud mineraalne täide, minimaalne tihedus ≥1800 kg/m3 | 3. korrus | _ISOLATSIOON - tihendatud mineraalne täide, minimaalne tihedus ≥1800 kg/m3
2 x _KARKASS - metallkarkass CW 50/50/06 ja UW 50/40/06, samm 600, vahel mineraalvill, helineeldetegur αw = 0.85, ISOVER ACOUSTIC 50mm või samaväärne | 3. korrus | _KARKASS - metallkarkass CW 50/50/06 ja UW 50/40/06, samm 600, vahel mineraalvill, helineeldetegur αw = 0.85, ISOVER ACOUSTIC 50mm või samaväärne
2 x _ERALDUSKIHT - polüetüleenkile 0,2mm, vuugid ülekattega 200mm ja teibitud | 3. korrus | _ERALDUSKIHT - polüetüleenkile 0,2mm, vuugid ülekattega 200mm ja teibitud
10 x _PLAATMATERJAL - erikõva kipsplaat, kinnitamiseks kasutada erikõvale plaadile sobivaid kruve nt XTB 3,9x55mm, Knauf Blue (Diamant) või samaväärne | 3. korrus | _PLAATMATERJAL - erikõva kipsplaat, kinnitamiseks kasutada erikõvale plaadile sobivaid kruve nt XTB 3,9x55mm, Knauf Blue (Diamant) või samaväärne
3 x _SOOJUSTUS - vill metallkarkassi vahel | 3. korrus | _SOOJUSTUS - vill metallkarkassi vahel
2 x _VIIMISTLUSKIHT - must akustiline fliis vastavalt SA osale | 3. korrus | _VIIMISTLUSKIHT - must akustiline fliis vastavalt SA osale
3 x _METALL - alumiinium | 3. korrus | _METALL - alumiinium
2 x _KLAAS - kirgas | 3. korrus | _KLAAS - kirgas
9 x _PLAATMATERJAL - niiskuskindel kuusevineer vastavalt EN 314 klass 3, BS 1203/H4, DIN 68705 osa 3 tüüp BFU nõuetele | 3. korrus | _PLAATMATERJAL - niiskuskindel kuusevineer vastavalt EN 314 klass 3, BS 1203/H4, DIN 68705 osa 3 tüüp BFU nõuetele
_KARKASS - puitpruss vastavalt EK osale | 3. korrus | _KARKASS - puitpruss vastavalt EK osale
2 x _EHITUS - akustiline riputussüsteem AMC EP 400+Sylomer 75, s 1,2m | 3. korrus | _EHITUS - akustiline riputussüsteem AMC EP 400+Sylomer 75, s 1,2m
6 x _KARKASS - metallkarkass CW 100/50/06 ja UW 100/40/06, samm 600 | 3. korrus | _KARKASS - metallkarkass CW 100/50/06 ja UW 100/40/06, samm 600
_KARKASS - puitroov 50x110mm, s. 600mm | 3. korrus | _KARKASS - puitroov 50x110mm, s. 600mm
Machine_Green | 3. korrus | Machine_Green
3 x _KARKASS - metallkarkass CW 100/50/06 ja UW 100/40/06, samm 600 | 4. TEHNO korrus | _KARKASS - metallkarkass CW 100/50/06 ja UW 100/40/06, samm 600
3 x _PLAATMATERJAL - niiskuskindel kuusevineer vastavalt EN 314 klass 3, BS 1203/H4, DIN 68705 osa 3 tüüp BFU nõuetele | 4. TEHNO korrus | _PLAATMATERJAL - niiskuskindel kuusevineer vastavalt EN 314 klass 3, BS 1203/H4, DIN 68705 osa 3 tüüp BFU nõuetele
31 x _PLAATMATERJAL - tuletõkkekipsplaat, Knauf Red GKF või samaväärne | 4. TEHNO korrus | _PLAATMATERJAL - tuletõkkekipsplaat, Knauf Red GKF või samaväärne
16 x _VIIMISTLUSKIHT - viimistlus vastavalt SA osale | 4. TEHNO korrus | _VIIMISTLUSKIHT - viimistlus vastavalt SA osale
8 x _VÄLISVIIMISTLUS - kiudtsemendist fassaadikatteplaat, tuletundlikkus A2-s1, d0, Cembrit Cover toon hall C 020 või samaväärne | 4. TEHNO korrus | _VÄLISVIIMISTLUS - kiudtsemendist fassaadikatteplaat, tuletundlikkus A2-s1, d0, Cembrit Cover toon hall C 020 või samaväärne
17 x _KARKASS - puitroov 50x50mm vertikaalne, sügavimmutatud, samm 600mm | 4. TEHNO korrus | _KARKASS - puitroov 50x50mm vertikaalne, sügavimmutatud, samm 600mm
26 x _KARKASS - puitroov 32x50mm horisontaalne, immutatud Driconi tulekaitsevahendiga või samaväärne, samm 600mm | 4. TEHNO korrus | _KARKASS - puitroov 32x50mm horisontaalne, immutatud Driconi tulekaitsevahendiga või samaväärne, samm 600mm
_KARKASS - teraskarkass, C-profiilid, samm 600mm, kuumtsingitud lehtteras 2mm, S350GD+Zn275 vastavalt EN10346, keskkonnaklass C3 | 4. TEHNO korrus | _KARKASS - teraskarkass, C-profiilid, samm 600mm, kuumtsingitud lehtteras 2mm, S350GD+Zn275 vastavalt EN10346, keskkonnaklass C3
10 x _KARKASS - mütsprofiil MP-27, kuumtsingitud teras | 4. TEHNO korrus | _KARKASS - mütsprofiil MP-27, kuumtsingitud teras
18 x _KANDETARIND - CLT ristkihtliimpuit vastavalt EK osale, CLT paigaldusvuugid teibitakse ROTHOBLAAS teibiga | 4. TEHNO korrus | _KANDETARIND - CLT ristkihtliimpuit vastavalt EK osale, CLT paigaldusvuugid teibitakse ROTHOBLAAS teibiga
4 x _KARKASS - puitroov 70x45mm vertikaalne, samm 600mm, vahel mineraalvill, helineeldetegur αw = 1.0, ISOVER ACOUSTIC 70mm või samaväärne | 4. TEHNO korrus | _KARKASS - puitroov 70x45mm vertikaalne, samm 600mm, vahel mineraalvill, helineeldetegur αw = 1.0, ISOVER ACOUSTIC 70mm või samaväärne
2 x _ÕHKVAHE | 4. TEHNO korrus | _ÕHKVAHE
3 x _PLAATMATERJAL - niiskuskindel vineerplaat, kvaliteediklass BB | 4. TEHNO korrus | _PLAATMATERJAL - niiskuskindel vineerplaat, kvaliteediklass BB
10 x _SOOJUSTUS - akustiline vill Ecophon Industry must TAL PE 50mm või samaväärne | 4. TEHNO korrus | _SOOJUSTUS - akustiline vill Ecophon Industry must TAL PE 50mm või samaväärne
20 x _TUULETÕKE - tuuletõkkeplaat, soojuserijuhtivus λD<0,031 W/(mK), ISOVER RKL FACADE või samaväärne, liitekohad katta tihendusteibiga ISOVER FacadeTape või samaväärne | 4. TEHNO korrus | _TUULETÕKE - tuuletõkkeplaat, soojuserijuhtivus λD<0,031 W/(mK), ISOVER RKL FACADE või samaväärne, liitekohad katta tihendusteibiga ISOVER FacadeTape või samaväärne
5 x _SOOJUSTUS - mineraalvill, λD<0,032 W/(mK), kuumtsingitud lehtteras termoroovidega, S350GD+Zn275 vastavalt EN10346, ISOVER EXTREME 32 200mm või samaväärne | 4. TEHNO korrus | _SOOJUSTUS - mineraalvill, λD<0,032 W/(mK), kuumtsingitud lehtteras termoroovidega, S350GD+Zn275 vastavalt EN10346, ISOVER EXTREME 32 200mm või samaväärne
73 x _SOOJUSTUS - jäik mineraalvillaplaat, vastavalt RIL 107-2012-le, R3, survetugevus min 60kPa, soojuserijuhtivus λD<0,037 W/(mK), ISOVER OL-TOP või samaväärne | 4. TEHNO korrus | _SOOJUSTUS - jäik mineraalvillaplaat, vastavalt RIL 107-2012-le, R3, survetugevus min 60kPa, soojuserijuhtivus λD<0,037 W/(mK), ISOVER OL-TOP või samaväärne
13 x _SOOJUSTUS - mineraalvillaplaat, survetugevus min 60kPa, soojuserijuhtivus λD<0,037 W/(mK), ISOVER OL-P või samaväärne | 4. TEHNO korrus | _SOOJUSTUS - mineraalvillaplaat, survetugevus min 60kPa, soojuserijuhtivus λD<0,037 W/(mK), ISOVER OL-P või samaväärne
14 x _AURUTÕKE - külmkleebitav aurutõkkekile Bytum 400 või samaväärne | 4. TEHNO korrus | _AURUTÕKE - külmkleebitav aurutõkkekile Bytum 400 või samaväärne
13 x _VÄLISVIIMISTLUS - vertikaalne voodrilaud, Platowood P01 profiil 18x140mm, kuusk; eeltöödeldud tuletõkkega mõlemad küljed, B-s1, d0, Woodsafe Exterior WFX™ või samaväärne | 4. TEHNO korrus | _VÄLISVIIMISTLUS - vertikaalne voodrilaud, Platowood P01 profiil 18x140mm, kuusk; eeltöödeldud tuletõkkega mõlemad küljed, B-s1, d0, Woodsafe Exterior WFX™ või samaväärne
58 x _PLAATMATERJAL - veekindla pinnaga niiskuskindel kuusevineer vastavalt EN 314 klass 3, BS 1203/H4, DIN 68705 osa 3 tüüp BFU nõuetele, lõikeserv ja õhuga kokkupuutuv pind kaitsta puidukaitsevahendiga, nt 2x Pinotex Impra | 4. TEHNO korrus | _PLAATMATERJAL - veekindla pinnaga niiskuskindel kuusevineer vastavalt EN 314 klass 3, BS 1203/H4, DIN 68705 osa 3 tüüp BFU nõuetele, lõikeserv ja õhuga kokkupuutuv pind kaitsta puidukaitsevahendiga, nt 2x Pinotex Impra
11 x _KANDETARIND - puitkarkass vastavalt EK osale | 4. TEHNO korrus | _KANDETARIND - puitkarkass vastavalt EK osale
40 x _ERALDUSKIHT - siirdetõke, min 140g/m2, Fibertex F2B 140g/m2 või samaväärne | 4. TEHNO korrus | _ERALDUSKIHT - siirdetõke, min 140g/m2, Fibertex F2B 140g/m2 või samaväärne
101 x _HÜDROISOLATSIOON - katusekate PVC rullmaterjal, vastavalt RIL 107-2012-le, helehall F91, Protan SE või samaväärne | 4. TEHNO korrus | _HÜDROISOLATSIOON - katusekate PVC rullmaterjal, vastavalt RIL 107-2012-le, helehall F91, Protan SE või samaväärne
21 x _KARKASS - puitroov 50x50mm horisontaalne, sügavimmutatud, samm 600mm | 4. TEHNO korrus | _KARKASS - puitroov 50x50mm horisontaalne, sügavimmutatud, samm 600mm
7 x _AURUTÕKE - aurutõkkekile, vuugid ülekattega teibitud, veeaurutakistus Sd0,3 kuni 25m, ISOVER Vario auru- ja õhutõkkesüsteem (Vario Xtra aurutõkkekile, Vario MultiTape SL, Vario DF) või samaväärne | 4. TEHNO korrus | _AURUTÕKE - aurutõkkekile, vuugid ülekattega teibitud, veeaurutakistus Sd0,3 kuni 25m, ISOVER Vario auru- ja õhutõkkesüsteem (Vario Xtra aurutõkkekile, Vario MultiTape SL, Vario DF) või samaväärne
15 x _KARKASS - puitpruss 195x45mm sammuga 600mm vastavalt EK osale, vahel SOOJUSTUS - mineraalvill, soojuserijuhtivus λD<0,032 W/(mK), ISOVER EXTREME 32 200mm või samaväärne | 4. TEHNO korrus | _KARKASS - puitpruss 195x45mm sammuga 600mm vastavalt EK osale, vahel SOOJUSTUS - mineraalvill, soojuserijuhtivus λD<0,032 W/(mK), ISOVER EXTREME 32 200mm või samaväärne
14 x _KARKASS - puitroov 32x50mm vertikaalne, immutatud Driconi tulekaitsevahendiga või samaväärne, samm 600mm | 4. TEHNO korrus | _KARKASS - puitroov 32x50mm vertikaalne, immutatud Driconi tulekaitsevahendiga või samaväärne, samm 600mm
61 x _SOOJUSTUS - jäik mineraalvillaplaat tuulutussoontega, vastavalt RIL 107-2012-le, R3, survetugevus min 60kPa, soojuserijuhtivus λD<0,037 W/(mK), ISOVER OL-TOP/U või samaväärne | 4. TEHNO korrus | _SOOJUSTUS - jäik mineraalvillaplaat tuulutussoontega, vastavalt RIL 107-2012-le, R3, survetugevus min 60kPa, soojuserijuhtivus λD<0,037 W/(mK), ISOVER OL-TOP/U või samaväärne
61 x _SOOJUSTUS - kergkruus fraktsioon 10-20, 50-150mm kiht kallete andmiseks | 4. TEHNO korrus | _SOOJUSTUS - kergkruus fraktsioon 10-20, 50-150mm kiht kallete andmiseks
39 x _SOOJUSTUS - jäik mineraalvillaplaat paigaldatud treppi, vastavalt RIL 107-2012-le, R3, survetugevus min 60kPa, soojuserijuhtivus λD<0,037 W/(mK), ISOVER OL-TOP või samaväärne | 4. TEHNO korrus | _SOOJUSTUS - jäik mineraalvillaplaat paigaldatud treppi, vastavalt RIL 107-2012-le, R3, survetugevus min 60kPa, soojuserijuhtivus λD<0,037 W/(mK), ISOVER OL-TOP või samaväärne
7 x _AURUTÕKE - aurutõkkekile, vuugid ülekattega teibitud, veeaurutakistus Sd 0,3 kuni 25m, ISOVER Vario auru- ja õhutõkkesüsteem (Vario Xtra aurutõkkekile, Vario MultiTape SL, Vario DF) või samaväärne | 4. TEHNO korrus | _AURUTÕKE - aurutõkkekile, vuugid ülekattega teibitud, veeaurutakistus Sd 0,3 kuni 25m, ISOVER Vario auru- ja õhutõkkesüsteem (Vario Xtra aurutõkkekile, Vario MultiTape SL, Vario DF) või samaväärne
_VIIMISTLUSKIHT - must akustiline fliis vastavalt SA osale | 4. TEHNO korrus | _VIIMISTLUSKIHT - must akustiline fliis vastavalt SA osale
_KARKASS - puitroov 50x80mm, s. 600mm | 4. TEHNO korrus | _KARKASS - puitroov 50x80mm, s. 600mm
4 x _KANDETARIND - raudbetoon C25/30 vastavalt EK osale | 4. TEHNO korrus | _KANDETARIND - raudbetoon C25/30 vastavalt EK osale
_PEALEVALUKIHT - raudbetoonplaat vastavalt EK osale, vajadusel põrandküte | 4. TEHNO korrus | _PEALEVALUKIHT - raudbetoonplaat vastavalt EK osale, vajadusel põrandküte
_ISOLATSIOON - löögimüraisolatsioon, mineraalvill, koormustaluvus min 20 kPa, dünaamiline jäikus 16 MN/m³, ISOVER FLO või samaväärne | 4. TEHNO korrus | _ISOLATSIOON - löögimüraisolatsioon, mineraalvill, koormustaluvus min 20 kPa, dünaamiline jäikus 16 MN/m³, ISOVER FLO või samaväärne
_SOOJUSTUS - vahtpolüstüreenplaadid EPS 80, survetugevus min 80kPa, soojuserijuhtivus λD<0,038 W/(mK) | 4. TEHNO korrus | _SOOJUSTUS - vahtpolüstüreenplaadid EPS 80, survetugevus min 80kPa, soojuserijuhtivus λD<0,038 W/(mK)
_ISOLATSIOON - tihendatud mineraalne täide, minimaalne tihedus ≥1800 kg/m3 | 4. TEHNO korrus | _ISOLATSIOON - tihendatud mineraalne täide, minimaalne tihedus ≥1800 kg/m3
2 x _KARKASS - metallkarkass CW 50, samm 600, mineraalvill karkassi vahel | 4. TEHNO korrus | _KARKASS - metallkarkass CW 50, samm 600, mineraalvill karkassi vahel
12 x _METALL - alumiinium | 4. TEHNO korrus | _METALL - alumiinium
12 x _KLAAS - kirgas | 4. TEHNO korrus | _KLAAS - kirgas
6 x _PLAATMATERJAL - erikõva kipsplaat, kinnitamiseks kasutada erikõvale plaadile sobivaid kruve nt XTB 3,9x55mm, Knauf Blue (Diamant) või samaväärne | 4. TEHNO korrus | _PLAATMATERJAL - erikõva kipsplaat, kinnitamiseks kasutada erikõvale plaadile sobivaid kruve nt XTB 3,9x55mm, Knauf Blue (Diamant) või samaväärne
_SOOJUSTUS - vill metallkarkassi vahel | 4. TEHNO korrus | _SOOJUSTUS - vill metallkarkassi vahel
2 x _KARKASS - eriprofiilkinnitus vastavalt sisemisele plaatviimistlusele | 4. TEHNO korrus | _KARKASS - eriprofiilkinnitus vastavalt sisemisele plaatviimistlusele
4 x _ÕHK | 4. TEHNO korrus | _ÕHK
_METALL - teras | 4. TEHNO korrus | _METALL - teras
6 x _SOOJUSTUS - alumiiniumlaminaadiga PIR soojustusplaat, survetugevus min 120kPa, soojuserijuhtivus λD<0,022 W/(mK), KINGSPAN Therma TR26 või samaväärne, vuugid teibitud aurutõkke alumiiniumteibiga, TESCON aurutõkketeip või samaväärne | 4. TEHNO korrus | _SOOJUSTUS - alumiiniumlaminaadiga PIR soojustusplaat, survetugevus min 120kPa, soojuserijuhtivus λD<0,022 W/(mK), KINGSPAN Therma TR26 või samaväärne, vuugid teibitud aurutõkke alumiiniumteibiga, TESCON aurutõkketeip või samaväärne
9 x _METALL - raud | 4. TEHNO korrus | _METALL - raud
4 x _KANDETARIND - kergplokk Fibo 100mm | 4. TEHNO korrus | _KANDETARIND - kergplokk Fibo 100mm
_KANDETARIND - puitpruss 95x45mm sammuga 1200mm vastavalt EK osale | 4. TEHNO korrus | _KANDETARIND - puitpruss 95x45mm sammuga 1200mm vastavalt EK osale
7 x _PEALEVALUKIHT - vastavalt katusekaldele valatav raudbetoonplaat,C30/37, XC4 | 4. TEHNO korrus | _PEALEVALUKIHT - vastavalt katusekaldele valatav raudbetoonplaat,C30/37, XC4
7 x _ALUSKATE - drenaažimatt Icopal fonda geoplex 10 või analoog | 4. TEHNO korrus | _ALUSKATE - drenaažimatt Icopal fonda geoplex 10 või analoog
_EHITUS - akustiline riputussüsteem AMC EP 400+Sylomer 75, s 1,2m | 4. TEHNO korrus | _EHITUS - akustiline riputussüsteem AMC EP 400+Sylomer 75, s 1,2m
5 x _HÜDROISOLATSIOON - katusekate PVC rullmaterjal, vastavalt RIL 107-2012-le, helehall F91, Protan SE või samaväärne | Katus | _HÜDROISOLATSIOON - katusekate PVC rullmaterjal, vastavalt RIL 107-2012-le, helehall F91, Protan SE või samaväärne
3 x _SOOJUSTUS - jäik mineraalvillaplaat, vastavalt RIL 107-2012-le, R3, survetugevus min 60kPa, soojuserijuhtivus λD<0,037 W/(mK), ISOVER OL-TOP või samaväärne | Katus | _SOOJUSTUS - jäik mineraalvillaplaat, vastavalt RIL 107-2012-le, R3, survetugevus min 60kPa, soojuserijuhtivus λD<0,037 W/(mK), ISOVER OL-TOP või samaväärne
_SOOJUSTUS - jäik mineraalvillaplaat tuulutussoontega, vastavalt RIL 107-2012-le, R3, survetugevus min 60kPa, soojuserijuhtivus λD<0,037 W/(mK), ISOVER OL-TOP/U või samaväärne | Katus | _SOOJUSTUS - jäik mineraalvillaplaat tuulutussoontega, vastavalt RIL 107-2012-le, R3, survetugevus min 60kPa, soojuserijuhtivus λD<0,037 W/(mK), ISOVER OL-TOP/U või samaväärne
_SOOJUSTUS - kergkruus fraktsioon 10-20, 50-150mm kiht kallete andmiseks | Katus | _SOOJUSTUS - kergkruus fraktsioon 10-20, 50-150mm kiht kallete andmiseks
_SOOJUSTUS - jäik mineraalvillaplaat paigaldatud treppi, vastavalt RIL 107-2012-le, R3, survetugevus min 60kPa, soojuserijuhtivus λD<0,037 W/(mK), ISOVER OL-TOP või samaväärne | Katus | _SOOJUSTUS - jäik mineraalvillaplaat paigaldatud treppi, vastavalt RIL 107-2012-le, R3, survetugevus min 60kPa, soojuserijuhtivus λD<0,037 W/(mK), ISOVER OL-TOP või samaväärne
4 x _SOOJUSTUS - mineraalvillaplaat, survetugevus min 60kPa, soojuserijuhtivus λD<0,037 W/(mK), ISOVER OL-P või samaväärne | Katus | _SOOJUSTUS - mineraalvillaplaat, survetugevus min 60kPa, soojuserijuhtivus λD<0,037 W/(mK), ISOVER OL-P või samaväärne
2 x _KANDETARIND - profiilplekk T130M-75L-930-1.2 vastavalt EK osale | Katus | _KANDETARIND - profiilplekk T130M-75L-930-1.2 vastavalt EK osale

# IfcBuildingElementProxy: Coordinate Dimensions 25, nullpunkt
In: 1. korrus
Classification: 1.02 IfcBuildingElementProxyType (objekt) (RKAS BIM + ARCHICAD Classification)
Pset_BuildingElementProxyCommon - Reference: Coordinate Dimensions 25
AR_001-002 - 001_Nimetus: nullpunkt; 002_Tüüp: Coordinate Dimensions 25
AC_Pset_RenovationAndPhasing - Renovation Status: New

# IfcBuildingElementProxy: Cube 25, Nullpunkt
In: 1. korrus
Classification: 1.02 IfcBuildingElementProxyType (objekt) (RKAS BIM + ARCHICAD Classification)
Pset_BuildingElementProxyCommon - Reference: Cube 25
AR_001-002 - 001_Nimetus: Nullpunkt; 002_Tüüp: Cube 25
AC_Pset_RenovationAndPhasing - Renovation Status: New

# IfcColumn: SHS120x120x5 120 x 120 (10)
In: 1. korrus
Type - PredefinedType: COLUMN
Classification: 1.03 IfcColumnType (post) (RKAS BIM + ARCHICAD Classification); Material: Teras, S355
Pset_ColumnCommon - Reference: Vastavalt ehituskonstruktiivsele osale; Slope: 90 deg; LoadBearing: yes; IsExternal: no
AR_001-002 - 001_Nimetus: POST; 002_Tüüp: Vastavalt ehituskonstruktiivsele osale
AC_Pset_RenovationAndPhasing - Renovation Status: New

# IfcColumn: SHS150x150x6 150 x 150 (8)
Type - PredefinedType: COLUMN
Classification: 1.03 IfcColumnType (post) (RKAS BIM + ARCHICAD Classification); Material: IFC Building Material
Pset_ColumnCommon - Reference: Vastavalt ehituskonstruktiivsele osale; Slope: 90 deg; LoadBearing: yes; IsExternal: no
AR_001-002 - 002_Tüüp: Vastavalt ehituskonstruktiivsele osale
AC_Pset_RenovationAndPhasing - Renovation Status: New
Name | In | 001_Nimetus
3 x Post | 1. korrus | Post
POST | 2. korrus | POST
POST | 3. korrus | POST
3 x Post | 4. TEHNO korrus | Post

# IfcColumn: _KANDETARIND - liimpuit vastavalt EK osale 320 x 320 (16)
In: 1. korrus
Type - PredefinedType: COLUMN
Classification: 1.03 IfcColumnType (post) (RKAS BIM + ARCHICAD Classification); Material: _KANDETARIND - liimpuit vastavalt EK osale
Pset_ColumnCommon - Reference: Vastavalt ehituskonstruktiivsele osale; Slope: 90 deg; LoadBearing: yes; IsExternal: no
AR_001-002 - 001_Nimetus: Post; 002_Tüüp: Vastavalt ehituskonstruktiivsele osale
AC_Pset_RenovationAndPhasing - Renovation Status: New

# IfcColumn: _KANDETARIND - liimpuit vastavalt EK osale 380 x 380 (51)
Type - PredefinedType: COLUMN
Classification: 1.03 IfcColumnType (post) (RKAS BIM + ARCHICAD Classification); Material: _KANDETARIND - liimpuit vastavalt EK osale
Pset_ColumnCommon - Reference: Vastavalt ehituskonstruktiivsele osale; Slope: 90 deg; LoadBearing: yes; IsExternal: no
AR_001-002 - 001_Nimetus: POST; 002_Tüüp: Vastavalt ehituskonstruktiivsele osale
AC_Pset_RenovationAndPhasing - Renovation Status: New
Name | In
30 x POST | 1. korrus
14 x POST | 2. korrus
7 x POST | 3. korrus

# IfcColumn: _KANDETARIND - liimpuit vastavalt EK osale 400 x 400 (6)
In: 1. korrus
Type - PredefinedType: COLUMN
Classification: 1.03 IfcColumnType (post) (RKAS BIM + ARCHICAD Classification); Material: _KANDETARIND - liimpuit vastavalt EK osale
Pset_ColumnCommon - Reference: Vastavalt ehituskonstruktiivsele osale; Slope: 90 deg; LoadBearing: yes; IsExternal: no
AR_001-002 - 001_Nimetus: POST; 002_Tüüp: Vastavalt ehituskonstruktiivsele osale
AC_Pset_RenovationAndPhasing - Renovation Status: New

# IfcColumn: _KANDETARIND - raudbetoon C25/30 vastavalt EK osale 1160 x 300, POST
In: 1. korrus
Type - PredefinedType: COLUMN
Classification: 1.03 IfcColumnType (post) (RKAS BIM + ARCHICAD Classification); Material: _KANDETARIND - raudbetoon C25/30 vastavalt EK osale
Pset_ColumnCommon - Reference: Vastavalt ehituskonstruktiivsele osale; Slope: 90 deg; LoadBearing: yes; IsExternal: no
AR_001-002 - 001_Nimetus: POST; 002_Tüüp: Vastavalt ehituskonstruktiivsele osale
AC_Pset_RenovationAndPhasing - Renovation Status: New

# IfcColumn: _KANDETARIND - raudbetoon C25/30 vastavalt EK osale 300 x 300 (3)
Type - PredefinedType: COLUMN
Classification: 1.03 IfcColumnType (post) (RKAS BIM + ARCHICAD Classification); Material: _KANDETARIND - raudbetoon C25/30 vastavalt EK osale
Pset_ColumnCommon - Reference: Vastavalt ehituskonstruktiivsele osale; Slope: 90 deg; LoadBearing: yes; IsExternal: no
AR_001-002 - 001_Nimetus: POST; 002_Tüüp: Vastavalt ehituskonstruktiivsele osale
AC_Pset_RenovationAndPhasing - Renovation Status: New
Name | In
2 x POST | 1. korrus
POST | 2. korrus

# IfcColumn: _KANDETARIND - raudbetoon C25/30 vastavalt EK osale 400 x 400, POST
In: 1. korrus
Type - PredefinedType: COLUMN
Classification: 1.03 IfcColumnType (post) (RKAS BIM + ARCHICAD Classification); Material: _KANDETARIND - raudbetoon C25/30 vastavalt EK osale
Pset_ColumnCommon - Reference: Vastavalt ehituskonstruktiivsele osale; Slope: 90 deg; LoadBearing: yes; IsExternal: no
AR_001-002 - 001_Nimetus: POST; 002_Tüüp: Vastavalt ehituskonstruktiivsele osale
AC_Pset_RenovationAndPhasing - Renovation Status: New

# IfcColumn: _KANDETARIND - raudbetoon C25/30 vastavalt EK osale 420 x 420 (9)
Type - PredefinedType: COLUMN
Classification: 1.03 IfcColumnType (post) (RKAS BIM + ARCHICAD Classification)
Pset_ColumnCommon - Reference: Vastavalt ehituskonstruktiivsele osale; Slope: 90 deg; LoadBearing: yes; IsExternal: no
AR_001-002 - 001_Nimetus: POST; 002_Tüüp: Vastavalt ehituskonstruktiivsele osale
AC_Pset_RenovationAndPhasing - Renovation Status: New
Name | In
7 x POST | 1. korrus
2 x POST | 2. korrus

# IfcColumn: _KANDETARIND - raudbetoon C25/30 vastavalt EK osale 570 x 420, POST
In: 2. korrus
Type - PredefinedType: COLUMN
Classification: 1.03 IfcColumnType (post) (RKAS BIM + ARCHICAD Classification)
Pset_ColumnCommon - Reference: Vastavalt ehituskonstruktiivsele osale; Slope: 90 deg; LoadBearing: yes; IsExternal: no
AR_001-002 - 001_Nimetus: POST; 002_Tüüp: Vastavalt ehituskonstruktiivsele osale
AC_Pset_RenovationAndPhasing - Renovation Status: New

# IfcColumn: _ÕHK 98 x 98, Post
In: 4. TEHNO korrus
Type - PredefinedType: COLUMN
Classification: 1.03 IfcColumnType (post) (RKAS BIM + ARCHICAD Classification)
Pset_ColumnCommon - Reference: Vastavalt ehituskonstruktiivsele osale; Slope: 90 deg; LoadBearing: yes; IsExternal: no
AR_001-002 - 001_Nimetus: Post; 002_Tüüp: Vastavalt ehituskonstruktiivsele osale
AC_Pset_RenovationAndPhasing - Renovation Status: New

# IfcCovering: Aatriumi posti kõrvad 1 130 x 130 (127)
Classification: 1.07 IfcCoveringType (pinnadetailid) (RKAS BIM + ARCHICAD Classification); Material: _KANDETARIND - liimpuit vastavalt EK osale
Pset_CoveringCommon - Reference: E-01
AR_Ripplagi_Viimistlus_Põrandakate - 001_Nimetus: Posti katteelement; 200_Materjal (MUDELIS): _KANDETARIND - liimpuit vastavalt EK osale
AR_001-002 - 001_Nimetus: Posti katteelement; 002_Tüüp: E-01
AC_Pset_RenovationAndPhasing - Renovation Status: New
Name | In
82 x Posti katteelement | 1. korrus
30 x Posti katteelement | 2. korrus
15 x Posti katteelement | 3. korrus

# IfcCovering: Katuseakende parap-külg lisapuitkarkass 449 x 174 (2)
In: 4. TEHNO korrus
Classification: 1.07 IfcCoveringType (pinnadetailid) (RKAS BIM + ARCHICAD Classification)
Pset_CoveringCommon - Reference: Plekk K1
AR_Ripplagi_Viimistlus_Põrandakate - 001_Nimetus: Parapetiplekk; 200_Materjal (MUDELIS): _SOOJUSTUS - alumiiniumlaminaadiga PIR soojustusplaat, survetugevus min 120kPa, soojuserijuhtivus λD<0,022 W/(mK), KINGSPAN Therma TR26 või samaväärne, vuugid teibitud aurutõkke alumiiniumteibiga, TESCON aurutõkketeip või samaväärne; _PLAATMATERJAL - veekindla pinnaga niiskuskindel kuusevineer vastavalt EN 314 klass 3, BS 1203/H4, DIN 68705 osa 3 tüüp BFU nõuetele, lõikeserv ja õhuga kokkupuutuv pind kaitsta puidukaitsevahendiga, nt 2x Pinotex Impra; _METALL - raud; _ÕHK; _METALL - raud
AR_001-002 - 001_Nimetus: Parapetiplekk; 002_Tüüp: Plekk K1
AC_Pset_RenovationAndPhasing - Renovation Status: New

# IfcCovering: Parapeti plekk 433 x 199 (14)
In: 4. TEHNO korrus
Classification: 1.07 IfcCoveringType (pinnadetailid) (RKAS BIM + ARCHICAD Classification); Material: _GENEERILINE MATERJAL
Pset_CoveringCommon - Reference: Parapeti plekk
AR_Ripplagi_Viimistlus_Põrandakate - 001_Nimetus: Parapetiplekk; 200_Materjal (MUDELIS): _GENEERILINE MATERJAL
AR_001-002 - 001_Nimetus: Parapetiplekk; 002_Tüüp: Parapeti plekk
AC_Pset_RenovationAndPhasing - Renovation Status: New

# IfcCovering: Returned End 25 (23)
Classification: 1.07 IfcCoveringType (pinnadetailid) (RKAS BIM + ARCHICAD Classification)
Pset_CoveringCommon - Reference: Returned End 25
AR_001-002 - 002_Tüüp: Returned End 25
AC_Pset_RenovationAndPhasing - Renovation Status: New
Name | In | AR_Ripplagi_Viimistlus_Põrandakate, 001_Nimetus = AR_001-002, 001_Nimetus | 200_Materjal (MUDELIS) | Material
3 x Pale | 1. korrus | Pale | _VIIMISTLUSKIHT - viimistlus vastavalt SA osale; _KANDETARIND - monteeritav raudbetoon vastavalt EK osale
4 x Pale | 1. korrus | Pale | _VIIMISTLUSKIHT - viimistlus vastavalt SA osale | _VIIMISTLUSKIHT - viimistlus vastavalt SA osale
4 x Pale | 1. korrus | Pale | _PLAATMATERJAL - kipsplaat veekindel; _VIIMISTLUSKIHT - viimistlus vastavalt SA osale
Seina otsa krohv | 1. korrus | Seina otsa krohv | _VIIMISTLUSKIHT - viimistlus vastavalt SA osale | _VIIMISTLUSKIHT - viimistlus vastavalt SA osale
4 x Pale | 2. korrus | Pale | _VIIMISTLUSKIHT - viimistlus vastavalt SA osale | _VIIMISTLUSKIHT - viimistlus vastavalt SA osale
Pale | 2. korrus | Pale | _PLAATMATERJAL - tuletõkkekipsplaat, Knauf Red GKF või samaväärne; _KARKASS - eriprofiilkinnitus vastavalt sisemisele plaatviimistlusele; _VIIMISTLUSKIHT - Dold plaat vastavalt SA osale
Pale | 3. korrus | Pale | _PLAATMATERJAL - OSB3 plaat; _VIIMISTLUSKIHT - viimistlus vastavalt SA osale; _PLAATMATERJAL - tuletõkkekipsplaat, Knauf Red GKF või samaväärne
4 x Pale | 3. korrus | Pale | _VIIMISTLUSKIHT - viimistlus vastavalt SA osale | _VIIMISTLUSKIHT - viimistlus vastavalt SA osale
Pale | 3. korrus | Pale | _PLAATMATERJAL - tuletõkkekipsplaat, Knauf Red GKF või samaväärne; _KARKASS - eriprofiilkinnitus vastavalt sisemisele plaatviimistlusele; _VIIMISTLUSKIHT - Dold plaat vastavalt SA osale

# IfcCovering: _TUULETÕKE - sokli krohv, silikoonvaikkrohv Weber.pas 481 AquaBalance 1mm "scratch" viimistlus, toon helehall CL444 (S 3502-Y) * 35, SILS süsteem, või samaväärne 10, Välisseina viimistlus
In: 1. korrus
Classification: 1.07 IfcCoveringType (pinnadetailid) (RKAS BIM + ARCHICAD Classification); Material: _TUULETÕKE - sokli krohv, silikoonvaikkrohv Weber.pas 481 AquaBalance 1mm "scratch" viimistlus, toon helehall CL444 (S 3502-Y) * 35, SILS süsteem, või samaväärne
Pset_CoveringCommon - TotalThickness: 10 mm
AR_Ripplagi_Viimistlus_Põrandakate - 001_Nimetus: Soklikrohv; 200_Materjal (MUDELIS): _TUULETÕKE - sokli krohv, silikoonvaikkrohv Weber.pas 481 AquaBalance 1mm "scratch" viimistlus, toon helehall CL444 (S 3502-Y) * 35, SILS süsteem, või samaväärne
AR_001-002 - 001_Nimetus: Soklikrohv
AC_Pset_RenovationAndPhasing - Renovation Status: New

# IfcCovering: _VÄLISVIIMISTLUS - vertikaalne voodrilaud, Platowood P01 profiil 18x140mm, kuusk; eeltöödeldud tuletõkkega mõlemad küljed, B-s1, d0, Woodsafe Exterior WFX™ või samaväärne 18, Fassaadilaudis
In: 1. korrus
Classification: 1.07 IfcCoveringType (pinnadetailid) (RKAS BIM + ARCHICAD Classification); Material: _VÄLISVIIMISTLUS - vertikaalne voodrilaud, Platowood P01 profiil 18x140mm, kuusk; eeltöödeldud tuletõkkega mõlemad küljed, B-s1, d0, Woodsafe Exterior WFX™ või samaväärne
Pset_CoveringCommon - Reference: Fassaadilaudis; TotalThickness: 18 mm
AR_Ripplagi_Viimistlus_Põrandakate - 001_Nimetus: Fassaadilaudis; 200_Materjal (MUDELIS): _VÄLISVIIMISTLUS - vertikaalne voodrilaud, Platowood P01 profiil 18x140mm, kuusk; eeltöödeldud tuletõkkega mõlemad küljed, B-s1, d0, Woodsafe Exterior WFX™ või samaväärne
AR_001-002 - 001_Nimetus: Fassaadilaudis; 002_Tüüp: Fassaadilaudis
AC_Pset_RenovationAndPhasing - Renovation Status: New

# IfcCovering: katuseakende parap. kaldküljel-kunst 300 x 164 (2)
In: 4. TEHNO korrus
Classification: 1.07 IfcCoveringType (pinnadetailid) (RKAS BIM + ARCHICAD Classification)
Pset_CoveringCommon - Reference: Plekk K1
AR_Ripplagi_Viimistlus_Põrandakate - 001_Nimetus: Parapetiplekk; 200_Materjal (MUDELIS): _SOOJUSTUS - alumiiniumlaminaadiga PIR soojustusplaat, survetugevus min 120kPa, soojuserijuhtivus λD<0,022 W/(mK), KINGSPAN Therma TR26 või samaväärne, vuugid teibitud aurutõkke alumiiniumteibiga, TESCON aurutõkketeip või samaväärne; _PLAATMATERJAL - veekindla pinnaga niiskuskindel kuusevineer vastavalt EN 314 klass 3, BS 1203/H4, DIN 68705 osa 3 tüüp BFU nõuetele, lõikeserv ja õhuga kokkupuutuv pind kaitsta puidukaitsevahendiga, nt 2x Pinotex Impra; _METALL - raud; _ÕHK
AR_001-002 - 001_Nimetus: Parapetiplekk; 002_Tüüp: Plekk K1
AC_Pset_RenovationAndPhasing - Renovation Status: New

# IfcCovering: katuseakende parapetiplekk all 313 x 194, Parapetiplekk
In: 4. TEHNO korrus
Classification: 1.07 IfcCoveringType (pinnadetailid) (RKAS BIM + ARCHICAD Classification)
Pset_CoveringCommon - Reference: Plekk K1
AR_Ripplagi_Viimistlus_Põrandakate - 001_Nimetus: Parapetiplekk; 200_Materjal (MUDELIS): _SOOJUSTUS - alumiiniumlaminaadiga PIR soojustusplaat, survetugevus min 120kPa, soojuserijuhtivus λD<0,022 W/(mK), KINGSPAN Therma TR26 või samaväärne, vuugid teibitud aurutõkke alumiiniumteibiga, TESCON aurutõkketeip või samaväärne; _PLAATMATERJAL - veekindla pinnaga niiskuskindel kuusevineer vastavalt EN 314 klass 3, BS 1203/H4, DIN 68705 osa 3 tüüp BFU nõuetele, lõikeserv ja õhuga kokkupuutuv pind kaitsta puidukaitsevahendiga, nt 2x Pinotex Impra; _METALL - raud; _ÕHK
AR_001-002 - 001_Nimetus: Parapetiplekk; 002_Tüüp: Plekk K1
AC_Pset_RenovationAndPhasing - Renovation Status: New

# IfcCovering: katuseakende parapetiplekk all-puitkarkass 383 x 212, Parapetiplekk
In: 4. TEHNO korrus
Classification: 1.07 IfcCoveringType (pinnadetailid) (RKAS BIM + ARCHICAD Classification)
Pset_CoveringCommon - Reference: Plekk K1
AR_Ripplagi_Viimistlus_Põrandakate - 001_Nimetus: Parapetiplekk; 200_Materjal (MUDELIS): _SOOJUSTUS - alumiiniumlaminaadiga PIR soojustusplaat, survetugevus min 120kPa, soojuserijuhtivus λD<0,022 W/(mK), KINGSPAN Therma TR26 või samaväärne, vuugid teibitud aurutõkke alumiiniumteibiga, TESCON aurutõkketeip või samaväärne; _PLAATMATERJAL - veekindla pinnaga niiskuskindel kuusevineer vastavalt EN 314 klass 3, BS 1203/H4, DIN 68705 osa 3 tüüp BFU nõuetele, lõikeserv ja õhuga kokkupuutuv pind kaitsta puidukaitsevahendiga, nt 2x Pinotex Impra; _METALL - raud; _ÕHK; _METALL - raud
AR_001-002 - 001_Nimetus: Parapetiplekk; 002_Tüüp: Plekk K1
AC_Pset_RenovationAndPhasing - Renovation Status: New

# IfcCurtainWall: Curtain Wall Type (49)
Classification: 1.08 IfcCurtainWallType (rippfassaad) (RKAS BIM + ARCHICAD Classification)
AC_Pset_RenovationAndPhasing - Renovation Status: New
Name | In | 900_Tootja | 905_Mudel | 320_Klaas | 385_Raami_materjal | 390_Paneeli_materjal | 001_Nimetus | 300_Tüüp = Reference | 305_Ava_mõõt | 325_Helipidavus | 330_Tulekindlus | 335_Välispiire = IsExternal | 340_Soojusläbivus | 345_Päikesekiirgus_tegur | 350_Klaaspakett | 355_Pindala (m2) | 375_Viimistlus_seest = 376_Viimistlus_väljast | 910_Tooteinfo = 915_Kasutus-ja_hooldusjuhend
KLAASFASSAAD | 1. korrus | nt. Warmeco OÜ | Schüco AOC-50 | Kirgas | Alumiinium+liimpuitkarkass | Alumiinium raam | KLAASFASSAAD | KLF-01-ga | 61 920x7 260 | 33 dB | nõudeid ei esitata | yes | 0.8 | 0,26 | 3-kordne klaaspakett, sisemine klaas lamineritud ja välimine karastatud, 4-16-4-16-44.4 | 449.915 | toon RAL9006 alumiiniumhall | -
KLAASFASSAAD | 1. korrus | nt. Warmeco OÜ | Schüco AOC-50 | Kirgas | Alumiinium+liimpuitkarkass | Alumiinium raam | KLAASFASSAAD | KLF-02-gb | 11 420x3 490 | 33 dB | nõudeid ei esitata | yes | 0.8 | 0,39 | 3-kordne klaaspakett, sisemine klaas lamineritud ja välimine karastatud, 4-16-4-16-44.4 | 39.8566 | toon RAL9006 alumiiniumhall | -
KLAASFASSAAD | 1. korrus | nt. Warmeco OÜ | Schüco AOC-50 | Kirgas | Alumiinium+liimpuitkarkass | Alumiinium raam | KLAASFASSAAD | KLF-04-gv | 28 588x4 600 | 33 dB | nõudeid ei esitata | yes | 0.8 | 0,26 | 3-kordne,sisemine klaas lamineritud ja välimine karastatud, 4-16-4-16-66.4 | 131.503 | toon RAL9006 alumiiniumhall | -
KLAASFASSAAD | 1. korrus | nt. Warmeco OÜ | Schüco AOC-50 | Kirgas | Alumiinium+liimpuitkarkass | Alumiinium raam | KLAASFASSAAD | KLF-03-gb | 4 256x3 540 | 33 dB | nõudeid ei esitata | yes | 0.8 | 0,39 | 3-kordne klaaspakett, sisemine klaas lamineritud ja välimine karastatud, 4-16-4-16-44.4 | 15.0673 | toon RAL9006 alumiiniumhall | -
KLAASSEIN | 1. korrus | Undefined | Undefined | Undefined |  |  | KLAASSEIN | SU-403-p | 7 040x2 300 | Undefined | EI30 | no | 0 | Undefined | Undefined | 16.1915 |  | Undefined
KLAASSEIN | 1. korrus | - | - | Kirgas, karastatud lamineeritud |  |  | KLAASSEIN | SU-110-p | 4 145x3 200 | 30 dB | nõudeid ei esitata | no | 0 | nõudeid ei esitata | - | 13.264 |  | -
KLAASSEIN | 1. korrus | - | - | Kirgas, karastatud lamineeritud |  |  | KLAASSEIN | SU-404-p | 4 350x2 800 | 30 dB | EI30 | no | 0 | nõudeid ei esitata | - | 12.18 |  | -
KLAASSEIN | 1. korrus | - | - | Kirgas, karastatud lamineeritud |  |  | KLAASSEIN | SU-405-p | 3 161x2 300 | 35 dB | EI45 | no | 0 | nõudeid ei esitata | - | 7.27069 |  | -
Klaasfassaadi puitkarkass | 1. korrus | nt. Peetri Puit OÜ | Vastavalt ehituskonstruktiivsetele joonistele | - | Liimpuit, kuusk | Liimpuit, kuusk | Klaasfassaadi puitkarkass | KLF-02 | 11 420x3 490 | - | nõudeid ei esitata | yes | 0 | - | - | 39.8566 | Lakitud liimpuit vastavalt SA osale | -
Klaasfassaadi puitkarkass | 1. korrus | nt. Peetri Puit OÜ | Vastavalt ehituskonstruktiivsetele joonistele | - | Liimpuit, kuusk | Liimpuit, kuusk | Klaasfassaadi puitkarkass | KLF-03 | 4 256x3 540 | - | nõudeid ei esitata | yes | 0 | - | - | 15.0673 | Lakitud liimpuit vastavalt SA osale | -
Klaasfassaadi puitkarkass | 1. korrus | nt. Peetri Puit OÜ | Vastavalt ehituskonstruktiivsetele joonistele | - | Liimpuit, kuusk | Liimpuit, kuusk | Klaasfassaadi puitkarkass | KLF-04 | 28 588x4 600 | - | nõudeid ei esitata | yes | 0 | - | - | 131.503 | Lakitud liimpuit vastavalt SA osale | -
Klaasfassaadi puitkarkass | 1. korrus | nt. Peetri Puit OÜ | Vastavalt ehituskonstruktiivsetele joonistele | - | Liimpuit, kuusk | Liimpuit, kuusk | Klaasfassaadi puitkarkass | KLF-01 | 37 907x7 260 | - | nõudeid ei esitata | yes | 0 | - | - | 275.662 | Lakitud liimpuit vastavalt SA osale | -
Klaasfassaadi puitkarkass | 1. korrus | nt. Peetri Puit OÜ | Vastavalt ehituskonstruktiivsetele joonistele | - | Liimpuit, kuusk | Liimpuit, kuusk | Klaasfassaadi puitkarkass | KLF-01 | 23 550x7 260 | - | nõudeid ei esitata | yes | 0 | - | - | 171.05 | Lakitud liimpuit vastavalt SA osale | -
KLAASSEIN | 1. korrus | Määratakse järgmises projekti staadiumis | Määratakse järgmises projekti staadiumis | Kirgas | Sõrmjätkatud liimpuit | Kirgas klaaspakett | KLAASSEIN | SKS-101 | 4 169x2 300 | 40 dB | nõudeid ei esitata | no | 0 | - | 3-kordne karastatud ja lamineeritud klaaspakett | 9.5887 | Toonitud matt lakk | Määratakse järgmises projekti staadiumis
KLAASSEIN | 1. korrus | Määratakse järgmises projekti staadiumis | Määratakse järgmises projekti staadiumis | Kirgas | Sõrmjätkatud liimpuit | Kirgas klaaspakett | KLAASSEIN | SKS-101 | 4 169x2 300 | 40 dB | nõudeid ei esitata | no | 0 | - | 3-kordne karastatud ja lamineeritud klaaspakett | 9.58796 | Toonitud matt lakk | Määratakse järgmises projekti staadiumis
KLAASSEIN | 1. korrus | - | - | Kirgas karastatud lamineeritud |  |  | KLAASSEIN | SU-423-v | 2 510x2 300 | 35 dB | EI30 | no | 0 | - | - | 5.773 |  | -
KLAASSEIN | 1. korrus | - | - | Kirgas karastatud, lamineeritus |  |  | KLAASSEIN | SU-148-v | 2 308x3 090 | 32 dB | nõudeid ei esitata | no | 0 | - | - | 7.13206 |  | -
KLAASSEIN | 1. korrus | - | - | Kirgas karastatud, lamineeritus |  |  | KLAASSEIN | SU-148-p | 3 415x3 090 | 32 dB | nõudeid ei esitata | no | 0 | - | - | 10.5524 |  | -
KLAASSEIN | 1. korrus | - | - | Kirgas karastatud, lamineeritus |  |  | KLAASSEIN | SU-148-p | 2 230x3 090 | 32 dB | nõudeid ei esitata | no | 0 | - | - | 6.8907 |  | -
KLAASSEIN | 1. korrus | - | - | kirgas, karastatud, lamineeritud |  |  | KLAASSEIN | SU-155-v | 2 089x2 300 | 52 dB | nõudeid ei esitata | no | 0 | - | - | 4.80496 |  | -
KLAASSEIN | 1. korrus | - | - | kirgas, karastatud, lamineeritud |  |  | KLAASSEIN | SU-202-p | 2 600x3 200 | 25 dB | nõudeid ei esitata | no | 0 | - | - | 8.32001 |  | -
KLAASSEIN | 1. korrus | - | - | kirgas, karastatud, lamineeritud |  |  | KLAASSEIN | SU-154-p | 1 010x3 200 | 25 dB | nõudeid ei esitata | no | 0 | - | - | 3.23199 |  | -
KLAASSEIN | 2. korrus | - | - | Kirgas, karastatud ja lamineeritud |  |  | KLAASSEIN | SU-130-p | 7 234x2 300 | 35 dB | nõudeid ei esitata | no | 0 | nõudeid ei esitata | - | 16.6385 |  | -
2 x KLAASSEIN | 2. korrus | Määratakse järgmises projekti staadiumis | Määratakse järgmises projekti staadiumis | Kirgas | Sõrmjätkatud liimpuit | Kirgas klaaspakett | KLAASSEIN | SKS-103 | 5 195x2 300 | 40 dB | nõudeid ei esitata | no | 0 | - | 3-kordne karastatud ja lamineeritud klaaspakett | 11.9486 | Toonitud matt lakk | Määratakse järgmises projekti staadiumis
2 x KLAASSEIN | 2. korrus | Määratakse järgmises projekti staadiumis | Määratakse järgmises projekti staadiumis | Kirgas | Sõrmjätkatud liimpuit | Kirgas klaaspakett | KLAASSEIN | SKS-102 | 5 425x2 300 | 40 dB | nõudeid ei esitata | no | 0 | - | 3-kordne karastatud ja lamineeritud klaaspakett | 12.4775 | Toonitud matt lakk | Määratakse järgmises projekti staadiumis
2 x KLAASSEIN | 2. korrus | Määratakse järgmises projekti staadiumis | Määratakse järgmises projekti staadiumis | Kirgas | Sõrmjätkatud liimpuit | Kirgas klaaspakett | KLAASSEIN | SKS-104 | 6 959x2 300 | 40 dB | nõudeid ei esitata | no | 0 | - | 3-kordne karastatud ja lamineeritud klaaspakett | 16.0067 | Toonitud matt lakk | Määratakse järgmises projekti staadiumis
KLAASSEIN | 2. korrus | Vastavalt SA osale | Vastavalt SA osale | Kirgas, karastatud, lamineeritud | Sõrmjätkatud liimpuit | Kirgas klaaspakett | KLAASSEIN | SKS-105 | 5 570x2 300 | 40 dB | EI45 | no | 0 | - | 3-kordne karastatud ja lamineeritud klaaspakett | 12.811 | Toonitud matt lakk | -
KLAASSEIN | 2. korrus | - | - | Kirgas, karastatud ja lamineeritud |  |  | KLAASSEIN | SU-413-p | 4 390x2 300 | nõudeid ei esitata | EI30 | no | 0 | nõudeid ei esitata | - | 10.097 |  | -
KLAASSEIN | 2. korrus | - | - | Kirgas, karastatud ja lamineeritud |  |  | KLAASSEIN | SU-136-p | 4 351x2 300 | 40 dB | nõudeid ei esitata | no | 0 | nõudeid ei esitata | - | 10.007 |  | -
KLAASSEIN | 2. korrus | Määratakse järgmises projekti staadiumis | Määratakse järgmises projekti staadiumis | Kirgas | Sõrmjätkatud liimpuit | Kirgas klaaspakett | KLAASSEIN | SKS-108 | 2 750x2 300 | 33 dB | nõudeid ei esitata | no | 0 | - | 3-kordne karastatud ja lamineeritud klaaspakett | 0 | Toonitud matt lakk | Määratakse järgmises projekti staadiumis
KLAASSEIN | 2. korrus | - | - | Kirgas, karastatud ja lamineeritud |  |  | KLAASSEIN | SU-132-p | 5 390x2 300 | 40 dB | nõudeid ei esitata | no | 0 | nõudeid ei esitata | - | 0 |  | -
KLAASSEIN | 2. korrus | - | - | Kirgas, karastatud ja lamineeritud |  |  | KLAASSEIN | SU-407-v | 3 460x2 300 | 35 dB | EI30 | no | 0 | nõudeid ei esitata | - | 7.95801 |  | -
KLAASSEIN | 2. korrus | - | - | Kirgas, karastatud ja lamineeritud |  |  | KLAASSEIN | SU-410-v | 5 316x2 300 | 25 dB | EI30 | no | 0 | nõudeid ei esitata | - | 12.2271 |  | -
KLAASSEIN | 2. korrus | - | - | Kirgas, karastatud ja lamineeritud |  |  | KLAASSEIN | SU-409-p | 6 360x2 300 | 25 dB | EI30 | no | 0 | nõudeid ei esitata | - | 14.6281 |  | -
KLAASSEIN | 2. korrus | Vastavalt SA osale | Vastavalt SA osale | Kirgas | Sõrmjätkatud liimpuit | Kirgas klaaspakett | KLAASSEIN | SKS-106 | 5 410x2 480 | 40 dB | EI30 | no | 0 | - | 3-kordne karastatud ja lamineeritud klaaspakett | 13.4168 | Toonitud matt lakk | -
KLAASSEIN | 2. korrus | Vastavalt SA osale | Vastavalt SA osale | Kirgas | Sõrmjätkatud liimpuit | Kirgas klaaspakett | KLAASSEIN | SKS-107 | 5 410x2 480 | 40 dB | EI30 | no | 0 | - | 3-kordne karastatud ja lamineeritud klaaspakett | 13.4168 | Toonitud matt lakk | -
KLAASSEIN | 3. korrus | - | - | Kirgas, karastatud, lamineeritud |  |  | KLAASSEIN | SU-137-v | 1 890x2 300 | 35 dB | nõudeid ei esitata | no | 0 | Nõudeid ei esitata | - | 4.347 |  | -
Katuseaken | 3. korrus | nt. Warmeco OÜ | Mitteavatav osa Schüco FWS 50.SI või samaväärne ja suitsueemaldusaken Schüco AWS 57 RO. või samaväärne | kirgas klaas | alumiinium | Alumiinium | katuseaken | KA-05 | 3 726x2 744 | Rw≥25 dB | nõudeid ei esitata | yes | 1.2 | 0,28 | 3-kordne, sisemine ja välimine klaas lamineeritud ning karastatud, | 10.2199 | RAL 9006 (alumiiniumhall) | -
KLAASSEIN | 3. korrus | Vastavalt SA osale | Vastavalt SA osale | Kirgas | Sõrmjätkatud liimpuit | Kirgas klaaspakett | KLAASSEIN | SKS-109 | 2 800x2 300 | 30 dB | nõudeid ei esitata | no | 0 | - | 3-kordne karastatud ja lamineeritud klaaspakett | 6.44 | Toonitud matt lakk | -
KLAASSEIN | 3. korrus | - | - | Kirgas, karastatud, lamineeritud |  |  | KLAASSEIN | SU-410-v | 5 316x2 300 | 25 dB | EI30 | no | 0 | - | - | 12.2271 |  | -
KLAASSEIN | 3. korrus | - | - | Kirgas, karastatud, lamineeritud |  |  | KLAASSEIN | SU-409-p | 6 360x2 300 | 25 dB | EI30 | no | 0 | - | - | 14.6281 |  | -
KLAASSEIN | 3. korrus | - | - | Kirgas, karastatud ja lamineeritud |  |  | KLAASSEIN | SU-130-p | 7 311x2 300 | 35 dB | nõudeid ei esitata | no | 0 | nõudeid ei esitata | - | 16.8156 |  | -
Katuseaken | 4. TEHNO korrus | nt. Warmeco OÜ | Mitteavatav osa Schüco FWS 50.SI või samaväärne ja suitsueemaldusaken Schüco AWS 57 RO. või samaväärne | kirgas klaas | alumiinium | Alumiinium | katuseaken | KA-02 | 6 750x5 750 | Rw≥25 dB | nõudeid ei esitata | yes | 1.2 | 0,28 | 3-kordne, sisemine ja välimine klaas lamineeritud ning karastatud, | 38.8305 | RAL 9006 (alumiiniumhall) | -
Katuseaken | 4. TEHNO korrus | nt. Warmeco OÜ | Schüco FWS 50.SI või samaväärne; CE-märgisega sertifitseeritud paigaldusjuhendiga | kirgas klaas | alumiinium | Alumiinium | katuseaken | KA-03 | 11 840x5 603 | Rw≥25 dB | nõudeid ei esitata | yes | 1 | 0,28 | 3-kordne, sisemine ja välimine klaas lamineeritud ning karastatud, | 66.3535 | RAL 9006 (alumiiniumhall) | -
Katuseaken | 4. TEHNO korrus | nt. Warmeco OÜ | Mitteavatav osa Schüco FWS 50.SI või samaväärne ja suitsueemaldusaken Schüco AWS 57 RO. või samaväärne | kirgas klaas | alumiinium | Alumiinium | katuseaken | KA-04 | 7 141x5 540 | Rw≥25 dB | nõudeid ei esitata | yes | 1.2 | 0,28 | 3-kordne, sisemine ja välimine klaas lamineeritud ning karastatud, | 40.9776 | RAL 9006 (alumiiniumhall) | -
Katuseaken | 4. TEHNO korrus | nt. Warmeco OÜ | Schüco FWS 50.SI või samaväärne; CE-märgisega sertifitseeritud paigaldusjuhendiga | kirgas klaas | alumiinium | Alumiinium | katuseaken | KA-01 | 6 520x4 439 | Rw≥25 dB | nõudeid ei esitata | yes | 1 | 0,28 | 3-kordne, sisemine ja välimine klaas lamineeritud ning karastatud, | 28.9483 | RAL 9006 (alumiiniumhall) | -

# IfcDiscreteAccessory: 1+paiksekaitse 3 370 x 115 (453)
Classification: 1.09 IfcDiscreteAccessoryType (tarvik) (RKAS BIM + ARCHICAD Classification); Material: _VÄLISVIIMISTLUS - sõrmjätkatud puitprussid 120x115mm, liitekohad vähemärgatavad, Platowood sõrmjätkatud kuusk või samaväärne; eeltöödeldud tuletõkkevõõbaga, tuletundlikkus B-s1, d0, Woodsafe Exterior WFX™ või samaväärne; kinnitused vastavalt EK osale (2)
AR_001-002 - 001_Nimetus: Päikesevarjestus; 002_Tüüp: Platowood sõrmjätkatud kuusk, töödeldud tuletõkke võõbaga ja toonitud linaõliga halliks
Pset_QuantityTakeOff - Reference: Platowood sõrmjätkatud kuusk, töödeldud tuletõkke võõbaga ja toonitud linaõliga halliks
AC_Pset_RenovationAndPhasing - Renovation Status: New
Name | In
185 x Päikesevarjestus | 1. korrus
120 x Päikesevarjestus | 2. korrus
102 x Päikesevarjestus | 3. korrus
46 x Päikesevarjestus | 4. TEHNO korrus

# IfcDiscreteAccessory: 1+paiksekaitse 4 tk nihkes 1 120 x 115 (43)
Classification: 1.09 IfcDiscreteAccessoryType (tarvik) (RKAS BIM + ARCHICAD Classification); Material: _VÄLISVIIMISTLUS - sõrmjätkatud puitprussid 120x115mm, liitekohad vähemärgatavad, Platowood sõrmjätkatud kuusk või samaväärne; eeltöödeldud tuletõkkevõõbaga, tuletundlikkus B-s1, d0, Woodsafe Exterior WFX™ või samaväärne; kinnitused vastavalt EK osale
AR_001-002 - 001_Nimetus: Päikesevarjestus; 002_Tüüp: Platowood sõrmjätkatud kuusk, töödeldud tuletõkke võõbaga ja toonitud linaõliga halliks
Pset_QuantityTakeOff - Reference: Platowood sõrmjätkatud kuusk, töödeldud tuletõkke võõbaga ja toonitud linaõliga halliks
AC_Pset_RenovationAndPhasing - Renovation Status: New
Name | In
2 x Päikesevarjestus | 1. korrus
10 x Päikesevarjestus | 2. korrus
26 x Päikesevarjestus | 3. korrus
5 x Päikesevarjestus | 4. TEHNO korrus

# IfcDiscreteAccessory: 1+paiksekaitse 4 tk nihkes 2 370 x 355 (185)
Classification: 1.09 IfcDiscreteAccessoryType (tarvik) (RKAS BIM + ARCHICAD Classification); Material: _VÄLISVIIMISTLUS - sõrmjätkatud puitprussid 120x115mm, liitekohad vähemärgatavad, Platowood sõrmjätkatud kuusk või samaväärne; eeltöödeldud tuletõkkevõõbaga, tuletundlikkus B-s1, d0, Woodsafe Exterior WFX™ või samaväärne; kinnitused vastavalt EK osale (2)
AR_001-002 - 001_Nimetus: Päikesevarjestus; 002_Tüüp: Platowood sõrmjätkatud kuusk, töödeldud tuletõkke võõbaga ja toonitud linaõliga halliks
Pset_QuantityTakeOff - Reference: Platowood sõrmjätkatud kuusk, töödeldud tuletõkke võõbaga ja toonitud linaõliga halliks
AC_Pset_RenovationAndPhasing - Renovation Status: New
Name | In
55 x Päikesevarjestus | 1. korrus
46 x Päikesevarjestus | 2. korrus
47 x Päikesevarjestus | 3. korrus
37 x Päikesevarjestus | 4. TEHNO korrus

# IfcDiscreteAccessory: 120 1+paiksekaitse 3 tk 620 x 115 (27)
In: 1. korrus
Classification: 1.09 IfcDiscreteAccessoryType (tarvik) (RKAS BIM + ARCHICAD Classification); Material: _VÄLISVIIMISTLUS - sõrmjätkatud puitprussid 120x115mm, liitekohad vähemärgatavad, Platowood sõrmjätkatud kuusk või samaväärne; eeltöödeldud tuletõkkevõõbaga, tuletundlikkus B-s1, d0, Woodsafe Exterior WFX™ või samaväärne; kinnitused vastavalt EK osale (3)
AR_001-002 - 001_Nimetus: Päikesevarjestus; 002_Tüüp: Platowood sõrmjätkatud kuusk, töödeldud tuletõkke võõbaga ja toonitud linaõliga halliks
Pset_QuantityTakeOff - Reference: Platowood sõrmjätkatud kuusk, töödeldud tuletõkke võõbaga ja toonitud linaõliga halliks
AC_Pset_RenovationAndPhasing - Renovation Status: New

# IfcDiscreteAccessory: 120 4-ne vertikaalne -1 nurgaribi 620 x 115 (9)
Classification: 1.09 IfcDiscreteAccessoryType (tarvik) (RKAS BIM + ARCHICAD Classification); Material: _VÄLISVIIMISTLUS - sõrmjätkatud puitprussid 120x115mm, liitekohad vähemärgatavad, Platowood sõrmjätkatud kuusk või samaväärne; eeltöödeldud tuletõkkevõõbaga, tuletundlikkus B-s1, d0, Woodsafe Exterior WFX™ või samaväärne; kinnitused vastavalt EK osale (3)
AR_001-002 - 001_Nimetus: Päikesevarjestus; 002_Tüüp: Platowood sõrmjätkatud kuusk, töödeldud tuletõkke võõbaga ja toonitud linaõliga halliks
Pset_QuantityTakeOff - Reference: Platowood sõrmjätkatud kuusk, töödeldud tuletõkke võõbaga ja toonitud linaõliga halliks
AC_Pset_RenovationAndPhasing - Renovation Status: New
Name | In
8 x Päikesevarjestus | 1. korrus
Päikesevarjestus | 4. TEHNO korrus

# IfcDiscreteAccessory: 120 4-ne vertikaalne 870 x 115 (275)
Classification: 1.09 IfcDiscreteAccessoryType (tarvik) (RKAS BIM + ARCHICAD Classification); Material: _VÄLISVIIMISTLUS - sõrmjätkatud puitprussid 120x115mm, liitekohad vähemärgatavad, Platowood sõrmjätkatud kuusk või samaväärne; eeltöödeldud tuletõkkevõõbaga, tuletundlikkus B-s1, d0, Woodsafe Exterior WFX™ või samaväärne; kinnitused vastavalt EK osale (4)
AR_001-002 - 001_Nimetus: Päikesevarjestus; 002_Tüüp: Platowood sõrmjätkatud kuusk, töödeldud tuletõkke võõbaga ja toonitud linaõliga halliks
Pset_QuantityTakeOff - Reference: Platowood sõrmjätkatud kuusk, töödeldud tuletõkke võõbaga ja toonitud linaõliga halliks
AC_Pset_RenovationAndPhasing - Renovation Status: New
Name | In
210 x Päikesevarjestus | 1. korrus
27 x Päikesevarjestus | 2. korrus
19 x Päikesevarjestus | 3. korrus
19 x Päikesevarjestus | 4. TEHNO korrus

# IfcDiscreteAccessory: Downspout Complex 25 (8)
Classification: 1.09 IfcDiscreteAccessoryType (tarvik) (RKAS BIM + ARCHICAD Classification)
AR_001-002 - 002_Tüüp: Downspout Complex 25
Pset_QuantityTakeOff - Reference: Downspout Complex 25
AC_Pset_RenovationAndPhasing - Renovation Status: New
Name | In | 001_Nimetus
5 x Vihmavee toru LORO-X Quadratic 100x100 mm, kuumtsingitud teras, või analoogne | 1. korrus | Vihmavee toru LORO-X Quadratic 100x100 mm, kuumtsingitud teras, või analoogne
3 x küttekaabliga ja sadeveelehtriga kandiline sadeveetoru, 75x100; Ruukki kandiline vihmaveetoru, toon hõbedane RR40 või samaväärne | 4. TEHNO korrus | küttekaabliga ja sadeveelehtriga kandiline sadeveetoru, 75x100; Ruukki kandiline vihmaveetoru, toon hõbedane RR40 või samaväärne

# IfcDiscreteAccessory: Fassaadikiri graafikute kavad 10496 x 2301, Kooli nimetähed vastavalt infograafikale
In: 4. TEHNO korrus
Classification: 1.09 IfcDiscreteAccessoryType (tarvik) (RKAS BIM + ARCHICAD Classification); Material: _METALL - alumiinium (27)
AR_001-002 - 001_Nimetus: Kooli nimetähed vastavalt infograafikale; 002_Tüüp: Fassaaditähed
Pset_ManufacturerTypeInformation - ModelLabel: Fibershield-P
Pset_QuantityTakeOff - Reference: Fassaaditähed
AC_Pset_RenovationAndPhasing - Renovation Status: New

# IfcDiscreteAccessory: Fibreshield-p H kuni 6 m 235 x 290 (7)
Classification: 1.09 IfcDiscreteAccessoryType (tarvik) (RKAS BIM + ARCHICAD Classification); Material: _ÕHK, _METALL - teras
AR_001-002 - 001_Nimetus: Tuletõkkekardin
Pset_ManufacturerTypeInformation - ModelLabel: Fibershield-P
AC_Pset_RenovationAndPhasing - Renovation Status: New
Name | In | 002_Tüüp = Reference
Tuletõkkekardin | 1. korrus | TTK-1
Tuletõkkekardin | 1. korrus | TTK-2
Tuletõkkekardin | 1. korrus | TTK-5
Tuletõkkekardin | 1. korrus | TTK-6
Tuletõkkekardin | 2. korrus | TTK-7
Tuletõkkekardin | 2. korrus | TTK-3
Tuletõkkekardin | 3. korrus | TTK-4

# IfcDiscreteAccessory: KL-S-30_katusekaev vill+PVC 18 (24)
Classification: 1.09 IfcDiscreteAccessoryType (tarvik) (RKAS BIM + ARCHICAD Classification); Material: _HÜDROISOLATSIOON - katusekate PVC rullmaterjal, vastavalt RIL 107-2012-le, helehall F91, Protan SE või samaväärne, _ERALDUSKIHT - siirdetõke, min 140g/m2, Fibertex F2B 140g/m2 või samaväärne, _PLAATMATERJAL - veekindla pinnaga niiskuskindel kuusevineer vastavalt EN 314 klass 3, BS 1203/H4, DIN 68705 osa 3 tüüp BFU nõuetele, lõikeserv ja õhuga kokkupuutuv pind kaitsta puidukaitsevahendiga, nt 2x Pinotex Impra
AR_001-002 - 001_Nimetus: katusekaevu ala
AC_Pset_RenovationAndPhasing - Renovation Status: New
Name | In | 002_Tüüp = Reference
7 x katusekaevu ala | 3. korrus | SL-1
17 x katusekaevu ala | 4. TEHNO korrus | SL-02

# IfcDiscreteAccessory: Katuseakende parap-külg puitkarkass 370 x 174 (3)
Classification: 1.09 IfcDiscreteAccessoryType (tarvik) (RKAS BIM + ARCHICAD Classification)
AR_001-002 - 002_Tüüp: Katuseakende parap-külg puitkarkass
Pset_QuantityTakeOff - Reference: Katuseakende parap-külg puitkarkass
AC_Pset_RenovationAndPhasing - Renovation Status: New
Name | In | Material | 001_Nimetus
Katuseakna parapet | 3. korrus | _PLAATMATERJAL - veekindla pinnaga niiskuskindel kuusevineer vastavalt EN 314 klass 3, BS 1203/H4, DIN 68705 osa 3 tüüp BFU nõuetele, lõikeserv ja õhuga kokkupuutuv pind kaitsta puidukaitsevahendiga, nt 2x Pinotex Impra, _SOOJUSTUS - alumiiniumlaminaadiga PIR soojustusplaat, survetugevus min 120kPa, soojuserijuhtivus λD<0,022 W/(mK), KINGSPAN Therma TR26 või samaväärne, vuugid teibitud aurutõkke alumiiniumteibiga, TESCON aurutõkketeip või samaväärne, _METALL - raud (2) | Katuseakna parapet
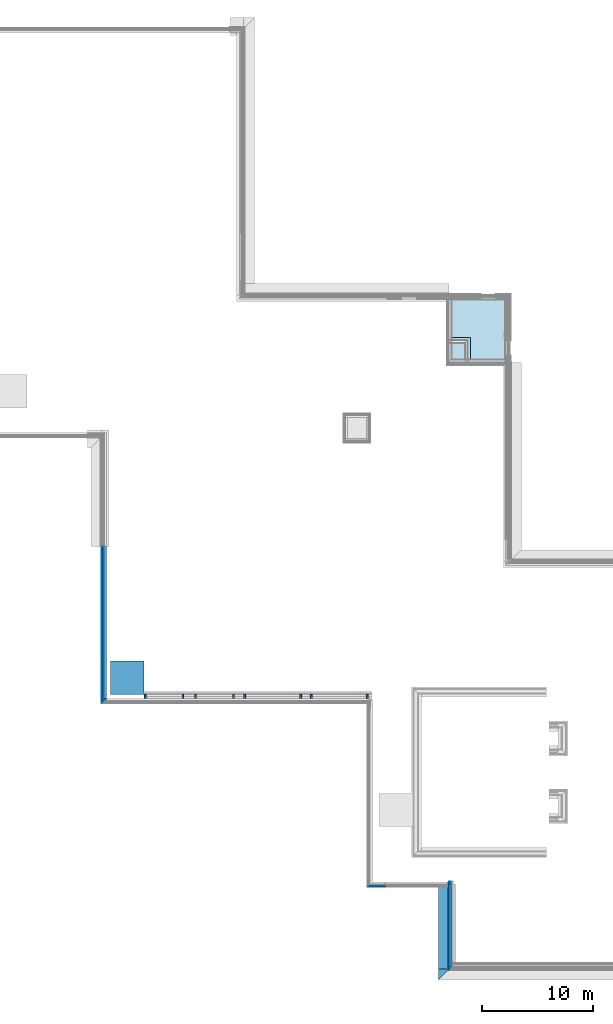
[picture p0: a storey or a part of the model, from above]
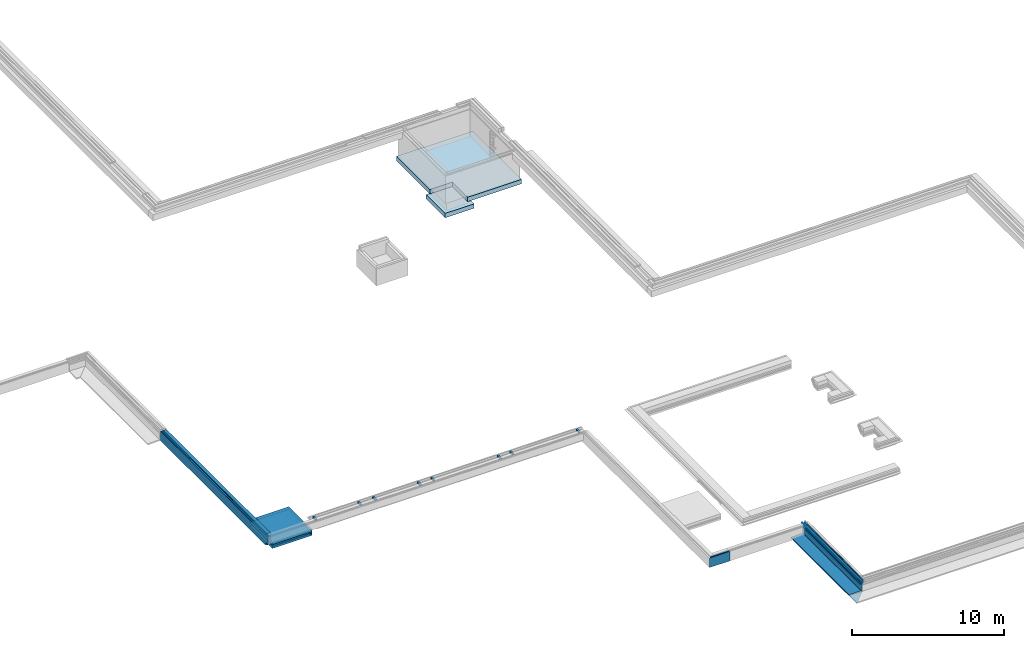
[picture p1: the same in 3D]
Properties of the parts of a building model (IFC2X3), part 3 of 14

# IfcDiscreteAccessory: Katuseakende parap-külg puitkarkass 370 x 174 (3)
Name | In | Material | 001_Nimetus
2 x Katuseakna parapetiplekk | 4. TEHNO korrus | _ÕHK, _PLAATMATERJAL - veekindla pinnaga niiskuskindel kuusevineer vastavalt EN 314 klass 3, BS 1203/H4, DIN 68705 osa 3 tüüp BFU nõuetele, lõikeserv ja õhuga kokkupuutuv pind kaitsta puidukaitsevahendiga, nt 2x Pinotex Impra, _SOOJUSTUS - alumiiniumlaminaadiga PIR soojustusplaat, survetugevus min 120kPa, soojuserijuhtivus λD<0,022 W/(mK), KINGSPAN Therma TR26 või samaväärne, vuugid teibitud aurutõkke alumiiniumteibiga, TESCON aurutõkketeip või samaväärne, _METALL - raud (2) | Katuseakna parapetiplekk

# IfcDiscreteAccessory: Renn 200 x 100 (3)
In: Katus
Classification: 1.09 IfcDiscreteAccessoryType (tarvik) (RKAS BIM + ARCHICAD Classification); Material: _METALL - teras
AR_001-002 - 001_Nimetus: Sadevee renn; 002_Tüüp: Renn
Pset_QuantityTakeOff - Reference: Renn
AC_Pset_RenovationAndPhasing - Renovation Status: New

# IfcDiscreteAccessory: Ribi mütsike (1976)
Classification: 1.09 IfcDiscreteAccessoryType (tarvik) (RKAS BIM + ARCHICAD Classification); Material: _METALL - teras
AR_001-002 - 001_Nimetus: Ribi mütsike; 002_Tüüp: FD-01
Pset_QuantityTakeOff - Reference: FD-01
AC_Pset_RenovationAndPhasing - Renovation Status: New
Name (ASTME MOODUL 1:ASTME MOODUL 1:...) | In
32 x 773977 | 2. korrus
747 x 773977 | 3. korrus
1197 x 773977 | 4. TEHNO korrus

# IfcDiscreteAccessory: Various Structures - 2 Segments - 150 x 150 x 360 (216+144) (56)
Classification: 1.09 IfcDiscreteAccessoryType (tarvik) (RKAS BIM + ARCHICAD Classification); Material: _PLASTIK (2)
AR_001-002 - 001_Nimetus: alarõhutuuluti, toon helehall; 002_Tüüp: alarõhutuuluti, toon helehall
Pset_QuantityTakeOff - Reference: alarõhutuuluti, toon helehall
AC_Pset_RenovationAndPhasing - Renovation Status: New
Name | In
19 x alarõhutuuluti, toon helehall | 3. korrus
35 x alarõhutuuluti, toon helehall | 4. TEHNO korrus
2 x alarõhutuuluti, toon helehall | Katus

# IfcDiscreteAccessory: Various Structures - 2 Segments - 150 x 150 x 395 (237+158), alarõhutuuluti, toon helehall
In: 3. korrus
Classification: 1.09 IfcDiscreteAccessoryType (tarvik) (RKAS BIM + ARCHICAD Classification); Material: _PLASTIK (2)
AR_001-002 - 001_Nimetus: alarõhutuuluti, toon helehall; 002_Tüüp: alarõhutuuluti, toon helehall
Pset_QuantityTakeOff - Reference: alarõhutuuluti, toon helehall
AC_Pset_RenovationAndPhasing - Renovation Status: New

# IfcDiscreteAccessory: Various Structures - 4 Segments - 118 x 118 x 233 (105+58+35+35) (5)
Classification: 1.09 IfcDiscreteAccessoryType (tarvik) (RKAS BIM + ARCHICAD Classification); Material: _ÕHK (4), _METALL - kuumtsingitud teras (4)
AR_001-002 - 001_Nimetus: Sadeveetoru liitmik, LORO-X 55686.100X, kuumtsingitud teras või analoog; 002_Tüüp: Sadeveetoru liitmik, LORO-X 55686.100X, kuumtsingitud teras või analoog
Pset_QuantityTakeOff - Reference: Sadeveetoru liitmik, LORO-X 55686.100X, kuumtsingitud teras või analoog
AC_Pset_RenovationAndPhasing - Renovation Status: New
Name | In
Sadeveetoru liitmik, LORO-X 55686.100X, kuumtsingitud teras või analoog | 2. korrus
4 x Sadeveetoru liitmik, LORO-X 55686.100X, kuumtsingitud teras või analoog | 3. korrus

# IfcDiscreteAccessory: Wall Mounted Ladder 25 (3)
Classification: 1.09 IfcDiscreteAccessoryType (tarvik) (RKAS BIM + ARCHICAD Classification)
AR_001-002 - 001_Nimetus: Seinaredel
AC_Pset_RenovationAndPhasing - Renovation Status: New
Name | In | 002_Tüüp = Reference
Seinaredel | Vundament | R-03
Seinaredel | 2. korrus | R-02
Seinaredel | 3. korrus | R-01

# IfcDiscreteAccessory: _METALL - alumiinium 155 x 150 (13)
In: 2. korrus
Classification: 1.09 IfcDiscreteAccessoryType (tarvik) (RKAS BIM + ARCHICAD Classification); Material: _METALL - alumiinium
AR_001-002 - 001_Nimetus: Päikesevarjestusruloo RENSON Fixscreen 150EVO või samaväärne
AC_Pset_RenovationAndPhasing - Renovation Status: New
Name | 002_Tüüp = Reference
Kardinvarjestus | PV2
12 x Kardinvarjestus | PV1

# IfcDiscreteAccessory: _METALL - kuumtsingitud teras 300 x 400, Turvakardina korpus Vastavalt Sa osale
In: 1. korrus
Classification: 1.09 IfcDiscreteAccessoryType (tarvik) (RKAS BIM + ARCHICAD Classification); Material: _METALL - kuumtsingitud teras
AR_001-002 - 001_Nimetus: Turvakardina korpus Vastavalt Sa osale
AC_Pset_RenovationAndPhasing - Renovation Status: New

# IfcDiscreteAccessory: _METALL - kuumtsingitud teras 40, hooldusplatvorm
In: 4. TEHNO korrus
Classification: 1.09 IfcDiscreteAccessoryType (tarvik) (RKAS BIM + ARCHICAD Classification); Material: _METALL - kuumtsingitud teras
AR_001-002 - 001_Nimetus: hooldusplatvorm; 002_Tüüp: keevisrest PW, kanderibi 40x3mm, silm 41,4x50,8mm, kuumtsingitud, ääristatud, hammastatud või samaväärne
Pset_QuantityTakeOff - Reference: keevisrest PW, kanderibi 40x3mm, silm 41,4x50,8mm, kuumtsingitud, ääristatud, hammastatud või samaväärne
AC_Pset_RenovationAndPhasing - Renovation Status: New

# IfcDiscreteAccessory: _METALL - kuumtsingitud teras D10 (19)
Classification: 1.09 IfcDiscreteAccessoryType (tarvik) (RKAS BIM + ARCHICAD Classification); Material: _METALL - kuumtsingitud teras
AC_Pset_RenovationAndPhasing - Renovation Status: New
Name | In | 001_Nimetus
2 x Piksevarras | 3. korrus | Piksevarras | AR_001-002 - 002_Tüüp: Piksevarras vastavalt EL osale; Pset_QuantityTakeOff - Reference: Piksevarras vastavalt EL osale
9 x turvapollari tross | 4. TEHNO korrus | turvapollari tross
3 x Piksevarras | 4. TEHNO korrus | Piksevarras | AR_001-002 - 002_Tüüp: Piksevarras vastavalt EL osale; Pset_QuantityTakeOff - Reference: Piksevarras vastavalt EL osale
2 x piksevarras | Katus | piksevarras | AR_001-002 - 002_Tüüp: Piksevarras vastavalt EL osale; Pset_QuantityTakeOff - Reference: Piksevarras vastavalt EL osale
3 x turvapollari tross | Katus | turvapollari tross

# IfcDiscreteAccessory: _METALL - kuumtsingitud teras D100 (25)
Classification: 1.09 IfcDiscreteAccessoryType (tarvik) (RKAS BIM + ARCHICAD Classification); Material: _METALL - kuumtsingitud teras
AR_001-002 - 001_Nimetus: katusepollar, toon alumiiniumhall RAL 9006
AC_Pset_RenovationAndPhasing - Renovation Status: New
Name | In
21 x katusepollar, toon alumiiniumhall RAL 9006 | 4. TEHNO korrus
4 x katusepollar, toon alumiiniumhall RAL 9006 | Katus

# IfcDiscreteAccessory: _METALL - teras 150 (7)
In: 1. korrus
Classification: 1.09 IfcDiscreteAccessoryType (tarvik) (RKAS BIM + ARCHICAD Classification); Material: _METALL - teras
AR_001-002 - 001_Nimetus: Terasdetail
AC_Pset_RenovationAndPhasing - Renovation Status: New

# IfcDiscreteAccessory: _METALL - teras 22 (11)
In: 1. korrus
Classification: 1.09 IfcDiscreteAccessoryType (tarvik) (RKAS BIM + ARCHICAD Classification); Material: _METALL - teras
AC_Pset_RenovationAndPhasing - Renovation Status: New
Name | 001_Nimetus
4 x süvistatud poritõkkesüsteem 22 mm vastavalt SA osale | süvistatud poritõkkesüsteem 22 mm vastavalt SA osale
5 x 30mm süvistatud roostevaba porirest betoonalusel vastavalt EK osale, kalle kaevu poole ≥1:80; resti silm 33x11mm, hambuline; porirest eemaldatav puhastuseks; vt joonist AR-7-207; sadevee kogumiseks resti all settepõhjaga restkaev, maapinnast -200mm kõrgusel, vesi koguneb sadeveetorustikku, vt VK osa | 30mm süvistatud roostevaba porirest betoonalusel vastavalt EK osale, kalle kaevu poole ≥1:80; resti silm 33x11mm, hambuline; porirest eemaldatav puhastuseks; vt joonist AR-7-207; sadevee kogumiseks resti all settepõhjaga restkaev, maapinnast -200mm kõrgusel, vesi koguneb sadeveetorustikku, vt VK osa
süvistatud poritõkkesüsteem 5mm vastavalt SA osale | süvistatud poritõkkesüsteem 5mm vastavalt SA osale
süvistatud poritõkkesüsteem 4mm vastavalt SA osale | süvistatud poritõkkesüsteem 4mm vastavalt SA osale

# IfcDiscreteAccessory: _METALL - teras 5 (7)
In: 1. korrus
Classification: 1.09 IfcDiscreteAccessoryType (tarvik) (RKAS BIM + ARCHICAD Classification); Material: _METALL - teras
AR_001-002 - 001_Nimetus: Terasdetail
AC_Pset_RenovationAndPhasing - Renovation Status: New

# IfcDiscreteAccessory: _METALL - teras 50 x 35 (36)
In: 1. korrus
Classification: 1.09 IfcDiscreteAccessoryType (tarvik) (RKAS BIM + ARCHICAD Classification); Material: _METALL - teras
AR_001-002 - 001_Nimetus: Varjestuskardina külgsiin RENSON või analoog; 002_Tüüp: PV1
Pset_QuantityTakeOff - Reference: PV1
AC_Pset_RenovationAndPhasing - Renovation Status: New

# IfcDiscreteAccessory: _METALL - teras 74 x 105 (14)
Classification: 1.09 IfcDiscreteAccessoryType (tarvik) (RKAS BIM + ARCHICAD Classification); Material: _METALL - teras
AR_001-002 - 001_Nimetus: Tuletõkke kardin
AC_Pset_RenovationAndPhasing - Renovation Status: New
Name | In | 002_Tüüp = Reference
8 x Tuletõkke kardin | 1. korrus | TTK-2
2 x Tuletõkke kardin | 2. korrus | TTK-3
2 x Tuletõkke kardin | 2. korrus | TTK-7
2 x Tuletõkke kardin | 3. korrus | TTK-4

# IfcDiscreteAccessory: _METALL - teras D120, Metallkorsten vastavalt generaatorile, RAL 9006 alumiiniumhall
In: 1. korrus
Classification: 1.09 IfcDiscreteAccessoryType (tarvik) (RKAS BIM + ARCHICAD Classification); Material: _METALL - teras
AR_001-002 - 001_Nimetus: Metallkorsten vastavalt generaatorile, RAL 9006 alumiiniumhall; 002_Tüüp: Metallkorsten, RAL 9006 alumiiniumhall
Pset_QuantityTakeOff - Reference: Metallkorsten, RAL 9006 alumiiniumhall
AC_Pset_RenovationAndPhasing - Renovation Status: New

# IfcDiscreteAccessory: _METALL - tsink 155 x 150 (5)
In: 2. korrus
Classification: 1.09 IfcDiscreteAccessoryType (tarvik) (RKAS BIM + ARCHICAD Classification); Material: _METALL - tsink
AR_001-002 - 001_Nimetus: Päikesevarjestusruloo RENSON Fixscreen 150EVO või samaväärne
AC_Pset_RenovationAndPhasing - Renovation Status: New
Name | 002_Tüüp = Reference
Kardinvarjestus | PV2
4 x Kardinvarjestus | PV1

# IfcDiscreteAccessory: _ÕHK 7000, Kunstiteos
In: 1. korrus
Classification: 1.09 IfcDiscreteAccessoryType (tarvik) (RKAS BIM + ARCHICAD Classification); Material: _ÕHK
AR_001-002 - 001_Nimetus: Kunstiteos; 002_Tüüp: Kunstiteos
Pset_QuantityTakeOff - Reference: Kunstiteos
AC_Pset_RenovationAndPhasing - Renovation Status: New

# IfcDiscreteAccessory: auditooriumi parapett 200 x 50 (7)
In: Katus
Classification: 1.09 IfcDiscreteAccessoryType (tarvik) (RKAS BIM + ARCHICAD Classification); Material: _METALL - kuumtsingitud teras
AR_001-002 - 001_Nimetus: Parapetiplekk; 002_Tüüp: auditooriumi parapett
Pset_QuantityTakeOff - Reference: auditooriumi parapett
AC_Pset_RenovationAndPhasing - Renovation Status: New

# IfcDiscreteAccessory: katuseakende parap. kaldküljel-kunst 300 x 164 (2)
In: 3. korrus
Classification: 1.09 IfcDiscreteAccessoryType (tarvik) (RKAS BIM + ARCHICAD Classification); Material: _PLAATMATERJAL - veekindla pinnaga niiskuskindel kuusevineer vastavalt EN 314 klass 3, BS 1203/H4, DIN 68705 osa 3 tüüp BFU nõuetele, lõikeserv ja õhuga kokkupuutuv pind kaitsta puidukaitsevahendiga, nt 2x Pinotex Impra, _SOOJUSTUS - alumiiniumlaminaadiga PIR soojustusplaat, survetugevus min 120kPa, soojuserijuhtivus λD<0,022 W/(mK), KINGSPAN Therma TR26 või samaväärne, vuugid teibitud aurutõkke alumiiniumteibiga, TESCON aurutõkketeip või samaväärne, _METALL - raud
AR_001-002 - 001_Nimetus: Katuseakna parapet; 002_Tüüp: katuseakende parap. kaldküljel-kunst
Pset_QuantityTakeOff - Reference: katuseakende parap. kaldküljel-kunst
AC_Pset_RenovationAndPhasing - Renovation Status: New

# IfcDiscreteAccessory: katuseakende parapetiplekk all 313 x 194, Katuseakna parapet
In: 3. korrus
Classification: 1.09 IfcDiscreteAccessoryType (tarvik) (RKAS BIM + ARCHICAD Classification); Material: _PLAATMATERJAL - veekindla pinnaga niiskuskindel kuusevineer vastavalt EN 314 klass 3, BS 1203/H4, DIN 68705 osa 3 tüüp BFU nõuetele, lõikeserv ja õhuga kokkupuutuv pind kaitsta puidukaitsevahendiga, nt 2x Pinotex Impra, _SOOJUSTUS - alumiiniumlaminaadiga PIR soojustusplaat, survetugevus min 120kPa, soojuserijuhtivus λD<0,022 W/(mK), KINGSPAN Therma TR26 või samaväärne, vuugid teibitud aurutõkke alumiiniumteibiga, TESCON aurutõkketeip või samaväärne, _METALL - raud
AR_001-002 - 001_Nimetus: Katuseakna parapet; 002_Tüüp: katuseakende parapetiplekk all
Pset_QuantityTakeOff - Reference: katuseakende parapetiplekk all
AC_Pset_RenovationAndPhasing - Renovation Status: New

# IfcDiscreteAccessory: katuseakende parapetiplekk all-lisapuitkarkass 405 x 241, Katuseakna parapet
In: 3. korrus
Classification: 1.09 IfcDiscreteAccessoryType (tarvik) (RKAS BIM + ARCHICAD Classification); Material: _ÕHK, _PLAATMATERJAL - veekindla pinnaga niiskuskindel kuusevineer vastavalt EN 314 klass 3, BS 1203/H4, DIN 68705 osa 3 tüüp BFU nõuetele, lõikeserv ja õhuga kokkupuutuv pind kaitsta puidukaitsevahendiga, nt 2x Pinotex Impra, _SOOJUSTUS - alumiiniumlaminaadiga PIR soojustusplaat, survetugevus min 120kPa, soojuserijuhtivus λD<0,022 W/(mK), KINGSPAN Therma TR26 või samaväärne, vuugid teibitud aurutõkke alumiiniumteibiga, TESCON aurutõkketeip või samaväärne, _METALL - raud (2)
AR_001-002 - 001_Nimetus: Katuseakna parapet; 002_Tüüp: katuseakende parapetiplekk all-lisapuitkarkass
Pset_QuantityTakeOff - Reference: katuseakende parapetiplekk all-lisapuitkarkass
AC_Pset_RenovationAndPhasing - Renovation Status: New

# IfcDiscreteAccessory: katuseakende parapetiplekk all-puitkarkass 383 x 212, Katuseakende parapetiplekk
In: 4. TEHNO korrus
Classification: 1.09 IfcDiscreteAccessoryType (tarvik) (RKAS BIM + ARCHICAD Classification); Material: _ÕHK, _PLAATMATERJAL - veekindla pinnaga niiskuskindel kuusevineer vastavalt EN 314 klass 3, BS 1203/H4, DIN 68705 osa 3 tüüp BFU nõuetele, lõikeserv ja õhuga kokkupuutuv pind kaitsta puidukaitsevahendiga, nt 2x Pinotex Impra, _SOOJUSTUS - alumiiniumlaminaadiga PIR soojustusplaat, survetugevus min 120kPa, soojuserijuhtivus λD<0,022 W/(mK), KINGSPAN Therma TR26 või samaväärne, vuugid teibitud aurutõkke alumiiniumteibiga, TESCON aurutõkketeip või samaväärne, _METALL - raud (2)
AR_001-002 - 001_Nimetus: Katuseakende parapetiplekk; 002_Tüüp: katuseakende parapetiplekk all-puitkarkass
Pset_QuantityTakeOff - Reference: katuseakende parapetiplekk all-puitkarkass
AC_Pset_RenovationAndPhasing - Renovation Status: New

# IfcDiscreteAccessory: katuseakende plekk ülal 283 x 165, Katuseakna parapet
In: 3. korrus
Classification: 1.09 IfcDiscreteAccessoryType (tarvik) (RKAS BIM + ARCHICAD Classification); Material: _PLAATMATERJAL - veekindla pinnaga niiskuskindel kuusevineer vastavalt EN 314 klass 3, BS 1203/H4, DIN 68705 osa 3 tüüp BFU nõuetele, lõikeserv ja õhuga kokkupuutuv pind kaitsta puidukaitsevahendiga, nt 2x Pinotex Impra, _SOOJUSTUS - alumiiniumlaminaadiga PIR soojustusplaat, survetugevus min 120kPa, soojuserijuhtivus λD<0,022 W/(mK), KINGSPAN Therma TR26 või samaväärne, vuugid teibitud aurutõkke alumiiniumteibiga, TESCON aurutõkketeip või samaväärne, _METALL - raud
AR_001-002 - 001_Nimetus: Katuseakna parapet; 002_Tüüp: katuseakende plekk ülal
Pset_QuantityTakeOff - Reference: katuseakende plekk ülal
AC_Pset_RenovationAndPhasing - Renovation Status: New

# IfcDiscreteAccessory: katuseakende plekk ülal-lisapuitkarkass 404 x 167, Katuseakna parapet
In: 3. korrus
Classification: 1.09 IfcDiscreteAccessoryType (tarvik) (RKAS BIM + ARCHICAD Classification); Material: _PLAATMATERJAL - veekindla pinnaga niiskuskindel kuusevineer vastavalt EN 314 klass 3, BS 1203/H4, DIN 68705 osa 3 tüüp BFU nõuetele, lõikeserv ja õhuga kokkupuutuv pind kaitsta puidukaitsevahendiga, nt 2x Pinotex Impra, _SOOJUSTUS - alumiiniumlaminaadiga PIR soojustusplaat, survetugevus min 120kPa, soojuserijuhtivus λD<0,022 W/(mK), KINGSPAN Therma TR26 või samaväärne, vuugid teibitud aurutõkke alumiiniumteibiga, TESCON aurutõkketeip või samaväärne, _METALL - raud (2)
AR_001-002 - 001_Nimetus: Katuseakna parapet; 002_Tüüp: katuseakende plekk ülal-lisapuitkarkass
Pset_QuantityTakeOff - Reference: katuseakende plekk ülal-lisapuitkarkass
AC_Pset_RenovationAndPhasing - Renovation Status: New

# IfcDiscreteAccessory: katuseakende plekk ülal-puitkarkass 353 x 165, Katuseakna parapetiplekk
In: 4. TEHNO korrus
Classification: 1.09 IfcDiscreteAccessoryType (tarvik) (RKAS BIM + ARCHICAD Classification); Material: _ÕHK, _PLAATMATERJAL - veekindla pinnaga niiskuskindel kuusevineer vastavalt EN 314 klass 3, BS 1203/H4, DIN 68705 osa 3 tüüp BFU nõuetele, lõikeserv ja õhuga kokkupuutuv pind kaitsta puidukaitsevahendiga, nt 2x Pinotex Impra, _SOOJUSTUS - alumiiniumlaminaadiga PIR soojustusplaat, survetugevus min 120kPa, soojuserijuhtivus λD<0,022 W/(mK), KINGSPAN Therma TR26 või samaväärne, vuugid teibitud aurutõkke alumiiniumteibiga, TESCON aurutõkketeip või samaväärne, _METALL - raud (2)
AR_001-002 - 001_Nimetus: Katuseakna parapetiplekk; 002_Tüüp: katuseakende plekk ülal-puitkarkass
Pset_QuantityTakeOff - Reference: katuseakende plekk ülal-puitkarkass
AC_Pset_RenovationAndPhasing - Renovation Status: New

# IfcDoor: 1015 x 2240 x 20, Siseuks
In: 1. korrus
Type - OperationType: SINGLE_SWING_RIGHT; ParameterTakesPrecedence: no; Sizeable: no
OverallHeight: 2200 mm; OverallWidth: 975 mm; Classification: 1.10 IfcDoorStyle (uks) (RKAS BIM + ARCHICAD Classification); Material: _METALL - alumiinium, _KLAAS - kirgas, _METALL - roostevaba terasleht, harjatud, 1mm
Pset_DoorCommon - Reference: SU-155-v
AR_Uks - 001_Nimetus: Siseuks; 300_Tüüp: SU-155-v; 305_Ava_mõõt: 975x2,200; 310_Materjal: MUDELIS: _METALL - alumiinium; _METALL - roostevaba terasleht, harjatud, 1mm; _KLAAS - kirgas; MÄRKUS: Täispuit ukseserv, fassaad spoonitud 8mm HDF, oksakuusk; 315_Avanemine: Pöördavanev - Parem ; ARCHICAD tüüp: 2; 320_Klaas: Kirgas, karastatud lamineeritud; 325_Helipidavus: 52 dB; 330_Tulekindlus: nõudeid ei esitata; 335_Välispiire: no; 340_Soojusläbivus: 0; 345_Päikesekiirgus_tegur: -; 350_Klaaspakett: -; 355_Pindala: 2.145 m2; 360_Ratastooliga: yes; 365_Isesulguv: yes; 370_Evakuatsiooniväljapääs: no; 375_Viimistlus_seest: Leng: METALL- tsink; Ukseleht: METALL- tsink; MÄRKUS: Toonitud matt lakk; 376_Viimistlus_väljast: Leng: METALL- tsink; Ukseleht: METALL- tsink; MÄRKUS: -; 380_Lukustus: Liugvarrega sulgur; 900_Tootja: -; 905_Mudel: -; 910_Tooteinfo: -; 915_Kasutus-ja_hooldusjuhend: -
Pset_ManufacturerOccurrence - SerialNumber: Off
AC_Pset_RenovationAndPhasing - Renovation Status: Undefined

# IfcDoor: 1040 x 2295 x 20, Klaasseina uks
In: 1. korrus
Type - OperationType: SINGLE_SWING_LEFT; ParameterTakesPrecedence: no; Sizeable: no
OverallHeight: 2275 mm; OverallWidth: 1000 mm; Classification: 1.10 IfcDoorStyle (uks) (RKAS BIM + ARCHICAD Classification); Material: _METALL - alumiinium, _KLAAS - kirgas, _METALL - teras
Pset_DoorCommon - Reference: SU-110-p
AR_Uks - 001_Nimetus: Klaasseina uks; 300_Tüüp: SU-110-p; 305_Ava_mõõt: 1,000x2,225; 310_Materjal: MUDELIS: _METALL - alumiinium; _METALL - teras; _KLAAS - kirgas; MÄRKUS: Täispuit ukseserv, fassaad spoonitud 8mm HDF, oksakuusk; 315_Avanemine: Pöördavanev - Vasak ; ARCHICAD tüüp: 2; 320_Klaas: Kirgas, karastatud; 325_Helipidavus: 30 dB; 330_Tulekindlus: nõudeid ei esitata; 335_Välispiire: no; 340_Soojusläbivus: 0; 345_Päikesekiirgus_tegur: Undefined; 350_Klaaspakett: -; 355_Pindala: 2.275 m2; 360_Ratastooliga: yes; 365_Isesulguv: yes; 370_Evakuatsiooniväljapääs: yes; 375_Viimistlus_seest: Leng: METALL- tsink; Ukseleht: METALL- tsink; MÄRKUS: Toonitud matt lakk; 376_Viimistlus_väljast: Leng: METALL- tsink; Ukseleht: METALL- tsink; MÄRKUS: -; 380_Lukustus: Liugvarrega sulgur, kaardilugeja, elektrilukk; 900_Tootja: -; 905_Mudel: -; 910_Tooteinfo: -; 915_Kasutus-ja_hooldusjuhend: -
Pset_ManufacturerOccurrence - SerialNumber: Off
AC_Pset_RenovationAndPhasing - Renovation Status: Undefined

# IfcDoor: 1122 x 1225 x 48, Peauks
In: 1. korrus
Type - OperationType: SINGLE_SWING_LEFT; ParameterTakesPrecedence: no; Sizeable: no
OverallHeight: 2435 mm; OverallWidth: 1380 mm; Classification: 1.10 IfcDoorStyle (uks) (RKAS BIM + ARCHICAD Classification); Material: _METALL - alumiinium, _KLAAS - kirgas, _METALL - teras, Birch
Pset_DoorCommon - Reference: VU-101-p-ga
AR_Uks - 001_Nimetus: Peauks; 300_Tüüp: VU-101-p-ga; 305_Ava_mõõt: 1 380x2 435; 310_Materjal: MUDELIS: Birch; _METALL - alumiinium; _METALL - teras; _KLAAS - kirgas; MÄRKUS: Alumiinium; 315_Avanemine: Pöördavanev - Parem; ARCHICAD tüüp: 2; 320_Klaas: Kirgas turvaklaas; 325_Helipidavus: 33 dB; 330_Tulekindlus: nõudeid ei esitata; 335_Välispiire: yes; 340_Soojusläbivus: 1; 345_Päikesekiirgus_tegur: 0,26; 350_Klaaspakett: 3-kordne, seest lamineeritud ja väljast karastatud turvaklaas; 355_Pindala: 3.3603 m2; 360_Ratastooliga: yes; 365_Isesulguv: yes; 370_Evakuatsiooniväljapääs: no; 375_Viimistlus_seest: Leng: TOON- RAL 9006 alumiinium hall; Ukseleht: TOON- RAL 9006 alumiinium hall; MÄRKUS: RAL 9006 alumiiniumhall; 376_Viimistlus_väljast: Leng: TOON- RAL 9006 alumiinium hall; Ukseleht: TOON- RAL 9006 alumiinium hall; MÄRKUS: RAL 9006 alumiiniumhall; 380_Lukustus: Lukustus vastavalt lukustusprojektile; 900_Tootja: nt Warmeco OÜ; 905_Mudel: Schüco AD UP 75, lai adapterproofiil või analoogl; 910_Tooteinfo: -; 915_Kasutus-ja_hooldusjuhend: -
Pset_ManufacturerOccurrence - SerialNumber: Off
AC_Pset_RenovationAndPhasing - Renovation Status: Undefined

# IfcDoor: 1122 x 1225 x 48, Peauks
In: 1. korrus
Type - OperationType: SINGLE_SWING_RIGHT; ParameterTakesPrecedence: no; Sizeable: no
OverallHeight: 2435 mm; OverallWidth: 1380 mm; Classification: 1.10 IfcDoorStyle (uks) (RKAS BIM + ARCHICAD Classification); Material: _METALL - alumiinium, _KLAAS - kirgas, _METALL - teras, Birch
Pset_DoorCommon - Reference: VU-101-v-ga
AR_Uks - 001_Nimetus: Peauks; 300_Tüüp: VU-101-v-ga; 305_Ava_mõõt: 1 380x2 435; 310_Materjal: MUDELIS: Birch; _METALL - alumiinium; _METALL - teras; _KLAAS - kirgas; MÄRKUS: Alumiinium; 315_Avanemine: Pöördavanev - Vasak; ARCHICAD tüüp: 3; 320_Klaas: Kirgas turvaklaas; 325_Helipidavus: 33 dB; 330_Tulekindlus: nõudeid ei esitata; 335_Välispiire: yes; 340_Soojusläbivus: 1; 345_Päikesekiirgus_tegur: 0,26; 350_Klaaspakett: 3-kordne, seest lamineeritud ja väljast karastatud turvaklaas; 355_Pindala: 3.3603 m2; 360_Ratastooliga: yes; 365_Isesulguv: yes; 370_Evakuatsiooniväljapääs: no; 375_Viimistlus_seest: Leng: TOON- RAL 9006 alumiinium hall; Ukseleht: TOON- RAL 9006 alumiinium hall; MÄRKUS: RAL 9006 alumiiniumhall; 376_Viimistlus_väljast: Leng: TOON- RAL 9006 alumiinium hall; Ukseleht: TOON- RAL 9006 alumiinium hall; MÄRKUS: RAL 9006 alumiiniumhall; 380_Lukustus: Vastavalt lukustusprojektile; 900_Tootja: nt Warmeco OÜ; 905_Mudel: Schüco AD UP 75, lai adapterproofiil või analoogl; 910_Tooteinfo: -; 915_Kasutus-ja_hooldusjuhend: -
Pset_ManufacturerOccurrence - SerialNumber: Off
AC_Pset_RenovationAndPhasing - Renovation Status: Undefined

# IfcDoor: 1270 x 2265 x 20, Kahepoolne siseuks
In: 1. korrus
Type - OperationType: DOUBLE_DOOR_SINGLE_SWING; ParameterTakesPrecedence: no; Sizeable: no
OverallHeight: 2225 mm; OverallWidth: 2500 mm; Classification: 1.10 IfcDoorStyle (uks) (RKAS BIM + ARCHICAD Classification); Material: _METALL - alumiinium, _KLAAS - kirgas, _METALL - roostevaba terasleht, harjatud, 1mm
Pset_DoorCommon - Reference: SU-202-p
AR_Uks - 001_Nimetus: Kahepoolne siseuks; 300_Tüüp: SU-202-p; 305_Ava_mõõt: 2,500x2,225; 310_Materjal: MUDELIS: _METALL - alumiinium; _METALL - roostevaba terasleht, harjatud, 1mm; _KLAAS - kirgas; MÄRKUS: Täispuit ukseserv, fassaad spoonitud 8mm HDF, oksakuusk; 315_Avanemine: Pöördavanev ; ARCHICAD tüüp: 2; 320_Klaas: Kirgas, karastatud lamineeritud; 325_Helipidavus: 25 dB; 330_Tulekindlus: nõudeid ei esitata; 335_Välispiire: no; 340_Soojusläbivus: 0; 345_Päikesekiirgus_tegur: -; 350_Klaaspakett: -; 355_Pindala: 5.56251 m2; 360_Ratastooliga: yes; 365_Isesulguv: yes; 370_Evakuatsiooniväljapääs: no; 375_Viimistlus_seest: Leng: METALL- tsink; Ukseleht: METALL- tsink; MÄRKUS: Toonitud matt lakk; 376_Viimistlus_väljast: Leng: METALL- tsink; Ukseleht: METALL- tsink; MÄRKUS: -; 380_Lukustus: Liugvarrega sulgur; 900_Tootja: -; 905_Mudel: -; 910_Tooteinfo: -; 915_Kasutus-ja_hooldusjuhend: -
Pset_ManufacturerOccurrence - SerialNumber: Off
AC_Pset_RenovationAndPhasing - Renovation Status: Undefined

# IfcDoor: 1379 x 1145 x 48, Kahepoolne välisuks
In: 1. korrus
Type - OperationType: DOUBLE_DOOR_SINGLE_SWING; ParameterTakesPrecedence: no; Sizeable: no
OverallHeight: 2275 mm; OverallWidth: 2763.58 mm; Classification: 1.10 IfcDoorStyle (uks) (RKAS BIM + ARCHICAD Classification); Material: _METALL - alumiinium, _KLAAS - kirgas, _METALL - roostevaba terasleht, harjatud, 1mm
Pset_DoorCommon - Reference: VU-301-p-gv
AR_Uks - 001_Nimetus: Kahepoolne välisuks; 300_Tüüp: VU-301-p-gv; 305_Ava_mõõt: 2 764x2 275; 310_Materjal: MUDELIS: _METALL - alumiinium; _METALL - roostevaba terasleht, harjatud, 1mm; _KLAAS - kirgas; MÄRKUS: Alumiinium; 315_Avanemine: Pöördavanev-Vasak ; ARCHICAD tüüp: 2; 320_Klaas: Kirgas turvaklaas; 325_Helipidavus: 33 dB; 330_Tulekindlus: nõudeid ei esitata; 335_Välispiire: yes; 340_Soojusläbivus: 1.1; 345_Päikesekiirgus_tegur: 0,26; 350_Klaaspakett: 3-kordne, seest lamineeritud ja väljast karastatud, turvaklaas 4-16-4-16-66.4; 355_Pindala: 6.28715 m2; 360_Ratastooliga: yes; 365_Isesulguv: yes; 370_Evakuatsiooniväljapääs: yes; 375_Viimistlus_seest: Leng: TOON- RAL 9006 alumiinium hall; Ukseleht: TOON- RAL 9006 alumiinium hall; MÄRKUS:; 376_Viimistlus_väljast: Leng: TOON- RAL 9006 alumiinium hall; Ukseleht: TOON- RAL 9006 alumiinium hall; MÄRKUS:; 380_Lukustus: Vastavalt lukustusprojektile. Lukud peavad olema pingega lukus - pingeta lahti; 900_Tootja: nt Warmeco OÜ; 905_Mudel: Schüco AD UP 75, lai adapterproofiil või analoog; 910_Tooteinfo: -; 915_Kasutus-ja_hooldusjuhend: -
Pset_ManufacturerOccurrence - SerialNumber: Off
AC_Pset_RenovationAndPhasing - Renovation Status: Undefined

# IfcDoor: 1420 x 1175 x 48, Ühepoolne välisuks
In: 1. korrus
Type - OperationType: SINGLE_SWING_RIGHT; ParameterTakesPrecedence: no; Sizeable: no
OverallHeight: 2335 mm; OverallWidth: 1380 mm; Classification: 1.10 IfcDoorStyle (uks) (RKAS BIM + ARCHICAD Classification); Material: _METALL - alumiinium, _KLAAS - kirgas, tuletõkke klaas, _METALL - teras, Birch
Pset_DoorCommon - Reference: VU-101-v-gb
AR_Uks - 001_Nimetus: Ühepoolne välisuks; 300_Tüüp: VU-101-v-gb; 305_Ava_mõõt: 1 380x2 335; 310_Materjal: MUDELIS: Birch; _METALL - alumiinium; _METALL - teras; _KLAAS - kirgas, tuletõkke klaas; MÄRKUS: Alumiinium; 315_Avanemine: Pöördavanev-Vasak ; ARCHICAD tüüp: 3; 320_Klaas: Kirgas turvaklaas; 325_Helipidavus: 33 dB; 330_Tulekindlus: nõudeid ei esitata; 335_Välispiire: yes; 340_Soojusläbivus: 1; 345_Päikesekiirgus_tegur: 0,39; 350_Klaaspakett: 3 kordne, seest lamineeritud ja väljast karastatud, 4-16-4-16-44,6 turvaklaas; 355_Pindala: 3.2223 m2; 360_Ratastooliga: yes; 365_Isesulguv: yes; 370_Evakuatsiooniväljapääs: yes; 375_Viimistlus_seest: Leng: TOON- RAL 9006 alumiinium hall; Ukseleht: TOON- RAL 9006 alumiinium hall; MÄRKUS:; 376_Viimistlus_väljast: Leng: TOON- RAL 9006 alumiinium hall; Ukseleht: TOON- RAL 9006 alumiinium hall; MÄRKUS:; 380_Lukustus: Vastavalt lukustusprojektile. Lukud peavad olema pingega lukus - pingeta lahti; 900_Tootja: nt Warmeco OÜ; 905_Mudel: Schüco AD UP 75, lai adapterproofiil või analoog; 910_Tooteinfo: -; 915_Kasutus-ja_hooldusjuhend: -
Pset_ManufacturerOccurrence - SerialNumber: Off
AC_Pset_RenovationAndPhasing - Renovation Status: Undefined

# IfcDoor: 1425 x 1145 x 48, Kahepoolne välisuks
In: 1. korrus
Type - OperationType: DOUBLE_DOOR_SINGLE_SWING; ParameterTakesPrecedence: no; Sizeable: no
OverallHeight: 2275 mm; OverallWidth: 2810 mm; Classification: 1.10 IfcDoorStyle (uks) (RKAS BIM + ARCHICAD Classification); Material: _METALL - alumiinium, _KLAAS - kirgas
Pset_DoorCommon - Reference: VU-301-v-gv
AR_Uks - 001_Nimetus: Kahepoolne välisuks; 300_Tüüp: VU-301-v-gv; 305_Ava_mõõt: 2 810x2 275; 310_Materjal: MUDELIS: _METALL - alumiinium; _KLAAS - kirgas; MÄRKUS: Alumiinium; 315_Avanemine: Pöördavanev-Vasak ; ARCHICAD tüüp: 2; 320_Klaas: Kirgas turvaklaas; 325_Helipidavus: 33 dB; 330_Tulekindlus: nõudeid ei esitata; 335_Välispiire: yes; 340_Soojusläbivus: 1.1; 345_Päikesekiirgus_tegur: 0,26; 350_Klaaspakett: 3-kordne, seest lamineeritud ja väljast karastatud, turvaklaas 4-16-4-16-66.4; 355_Pindala: 6.37426 m2; 360_Ratastooliga: yes; 365_Isesulguv: yes; 370_Evakuatsiooniväljapääs: yes; 375_Viimistlus_seest: Leng: TOON- RAL 9006 alumiinium hall; Ukseleht: TOON- RAL 9006 alumiinium hall; MÄRKUS:; 376_Viimistlus_väljast: Leng: TOON- RAL 9006 alumiinium hall; Ukseleht: TOON- RAL 9006 alumiinium hall; MÄRKUS:; 380_Lukustus: Vastavalt lukustusprojektile. Lukud peavad olema pingega lukus - pingeta lahti; 900_Tootja: nt Warmeco OÜ; 905_Mudel: Schüco AD UP 75, lai adapterproofiil või analoog; 910_Tooteinfo: -; 915_Kasutus-ja_hooldusjuhend: -
Pset_ManufacturerOccurrence - SerialNumber: Off
AC_Pset_RenovationAndPhasing - Renovation Status: Undefined

# IfcDoor: 1425 x 1225 x 20, Kahepoolne välisuks
In: 1. korrus
Type - OperationType: DOUBLE_DOOR_SINGLE_SWING; ParameterTakesPrecedence: no; Sizeable: no
OverallHeight: 2435 mm; OverallWidth: 2810 mm; Classification: 1.10 IfcDoorStyle (uks) (RKAS BIM + ARCHICAD Classification); Material: _METALL - alumiinium, _KLAAS - kirgas, _METALL - roostevaba terasleht, harjatud, 1mm
Pset_DoorCommon - Reference: VU-301-p-gb
AR_Uks - 001_Nimetus: Kahepoolne välisuks; 300_Tüüp: VU-301-p-gb; 305_Ava_mõõt: 2 810x2 435; 310_Materjal: MUDELIS: _METALL - alumiinium; _METALL - roostevaba terasleht, harjatud, 1mm; _KLAAS - kirgas; MÄRKUS: Alumiinium; 315_Avanemine: Pöördavanev- põhileht parem ; ARCHICAD tüüp: 2; 320_Klaas: Kirgas turvaklaas; 325_Helipidavus: 33 dB; 330_Tulekindlus: nõudeid ei esitata; 335_Välispiire: yes; 340_Soojusläbivus: 1.1; 345_Päikesekiirgus_tegur: 0,39; 350_Klaaspakett: 3-kordne, seest lamineeritud ja väljast karastatud, 4-16-4-16-44.4 turvaklaas; 355_Pindala: 6.84235 m2; 360_Ratastooliga: yes; 365_Isesulguv: yes; 370_Evakuatsiooniväljapääs: yes; 375_Viimistlus_seest: Leng: TOON- RAL 9006 alumiinium hall; Ukseleht: TOON- RAL 9006 alumiinium hall; MÄRKUS:; 376_Viimistlus_väljast: Leng: TOON- RAL 9006 alumiinium hall; Ukseleht: TOON- RAL 9006 alumiinium hall; MÄRKUS:; 380_Lukustus: Vastavalt lukustusprojektile. Lukud peavad olema pingega lukus - pingeta lahti; 900_Tootja: nt Warmeco OÜ; 905_Mudel: Schüco AD UP 75, lai adapterproofiil või analoog; 910_Tooteinfo: -; 915_Kasutus-ja_hooldusjuhend: -
Pset_ManufacturerOccurrence - SerialNumber: Off
AC_Pset_RenovationAndPhasing - Renovation Status: Undefined

# IfcDoor: 20 x 20 x 20 (2)
Type - OperationType: DOUBLE_DOOR_SINGLE_SWING; ParameterTakesPrecedence: no; Sizeable: no
OverallHeight: 2250 mm; Classification: 1.10 IfcDoorStyle (uks) (RKAS BIM + ARCHICAD Classification); Material: _METALL - alumiinium, _KLAAS - kirgas, _METALL - roostevaba terasleht, harjatud, 1mm
AR_Uks - 001_Nimetus: Klaasseina uks; 310_Materjal: MUDELIS: _METALL - alumiinium; _METALL - roostevaba terasleht, harjatud, 1mm; _KLAAS - kirgas; MÄRKUS: Täispuit ukseserv, fassaad spoonitud 8mm HDF, oksakuusk; 335_Välispiire: no; 340_Soojusläbivus: 0; 350_Klaaspakett: -; 360_Ratastooliga: yes; 365_Isesulguv: yes; 370_Evakuatsiooniväljapääs: yes; 375_Viimistlus_seest: Leng: METALL- tsink; Ukseleht: METALL- tsink; MÄRKUS: Toonitud matt lakk; 376_Viimistlus_väljast: Leng: METALL- tsink; Ukseleht: METALL- tsink; MÄRKUS: -; 900_Tootja: -; 905_Mudel: -; 910_Tooteinfo: -; 915_Kasutus-ja_hooldusjuhend: -
Pset_ManufacturerOccurrence - SerialNumber: Off
AC_Pset_RenovationAndPhasing - Renovation Status: Undefined
Name | In | OverallWidth (mm) | Reference = 300_Tüüp | 305_Ava_mõõt | 315_Avanemine | 320_Klaas | 325_Helipidavus | 330_Tulekindlus | 345_Päikesekiirgus_tegur | 355_Pindala (m2) | 380_Lukustus
Klaasseina uks | 1. korrus | 1846.56 | SU-405-p | 1,847x2,200 | Pöördavanev ; ARCHICAD tüüp: 2 | Kirgas, karastatud | 35 dB | EI45 | - | 4.15476 | Liugvarrega sulgur, kaardilugeja, elektrilukk
Klaasseina uks | 2. korrus | 1870 | SU-413-p | 1,870x2,200 | Pöördavanev, igapäevaselt magnet kinnituse abil avatud olekus. Tulekahju olukorras sulgub uks automaatselt evakuatsiooniukseks ; ARCHICAD tüüp: 2 | Kirgas, karastatud lamineeritud | nõudeid ei esitata | EI30 | nõudeid ei esitata | 4.2075 | Süvistatud magnetiline lahtihoidmismehhanism

# IfcDoor: 20 x 20 x 20 (5)
Type - OperationType: SINGLE_SWING_LEFT; ParameterTakesPrecedence: no; Sizeable: no
OverallHeight: 2250 mm; Classification: 1.10 IfcDoorStyle (uks) (RKAS BIM + ARCHICAD Classification)
AR_Uks - 001_Nimetus: Klaasseina uks; 335_Välispiire: no; 340_Soojusläbivus: 0; 350_Klaaspakett: -; 360_Ratastooliga: no; 375_Viimistlus_seest: Leng: METALL- tsink; Ukseleht: METALL- tsink; MÄRKUS: Toonitud matt lakk; 376_Viimistlus_väljast: Leng: METALL- tsink; Ukseleht: METALL- tsink; MÄRKUS: -; 900_Tootja: -; 905_Mudel: -; 910_Tooteinfo: -; 915_Kasutus-ja_hooldusjuhend: -
Pset_ManufacturerOccurrence - SerialNumber: Off
AC_Pset_RenovationAndPhasing - Renovation Status: Undefined
Name | In | OverallWidth (mm) | Material | Reference = 300_Tüüp | 305_Ava_mõõt | 310_Materjal | 315_Avanemine | 320_Klaas | 325_Helipidavus | 330_Tulekindlus | 345_Päikesekiirgus_tegur | 355_Pindala (m2) | 365_Isesulguv = 370_Evakuatsiooniväljapääs | 380_Lukustus
Klaasseina uks | 2. korrus | 979.938 | _METALL - alumiinium, _KLAAS - kirgas | SU-130-p | 980x2,200 | MUDELIS: _METALL - alumiinium; _KLAAS - kirgas; MÄRKUS: Täispuit ukseserv, fassaad spoonitud 8mm HDF, oksakuusk | Pöördavanev - Parem ; ARCHICAD tüüp: 2 | Kirgas, karastatud | 35 dB | nõudeid ei esitata | nõudeid ei esitata | 2.20486 | no | Liugvarrega sulgur, kaardilugeja, elektrilukk
Klaasseina uks | 2. korrus | 880 | _METALL - alumiinium, _KLAAS - kirgas, _METALL - roostevaba terasleht, harjatud, 1mm | SU-132-p | 880x2,200 | MUDELIS: _METALL - alumiinium; _METALL - roostevaba terasleht, harjatud, 1mm; _KLAAS - kirgas; MÄRKUS: Täispuit ukseserv, fassaad spoonitud 8mm HDF, oksakuusk | Pöördavanev - Vasak ; ARCHICAD tüüp: 2 | Kirgas, karastatud, lamineeritud | 40 dB | nõudeid ei esitata | nõudeid ei esitata | 1.98 | no | Liugvarrega sulgur, kaardilugeja, elektrilukk
Klaasseina uks | 2. korrus | 1130.04 | _METALL - alumiinium, _KLAAS - kirgas, _METALL - roostevaba terasleht, harjatud, 1mm | SU-409-p | 1,130x2,200 | MUDELIS: _METALL - alumiinium; _METALL - roostevaba terasleht, harjatud, 1mm; _KLAAS - kirgas; MÄRKUS: Täispuit ukseserv, fassaad spoonitud 8mm HDF, oksakuusk | Pöördavanev, igapäevaselt magnet kinnituse abil avatud olekus. Tulekahju olukorras sulgub uks automaatselt evakuatsiooniukseks - Vasak ; ARCHICAD tüüp: 3 | Kirgas, karastatud | 25 dB | EI30 | nõudeid ei esitata | 2.5426 | yes | Süvistatud magnetiline lahtihoidmismehhanism
Klaasseina uks | 3. korrus | 1130.11 | _METALL - alumiinium, _KLAAS - kirgas, _METALL - roostevaba terasleht, harjatud, 1mm | SU-409-p | 1,130x2,200 | MUDELIS: _METALL - alumiinium; _METALL - roostevaba terasleht, harjatud, 1mm; _KLAAS - kirgas; MÄRKUS: Täispuit ukseserv, fassaad spoonitud 8mm HDF, oksakuusk | Pöördavanev, igapäevaselt magnet kinnituse abil avatud olekus. Tulekahju olukorras sulgub uks automaatselt evakuatsiooniukseks - Vasak ; ARCHICAD tüüp: 3 | Kirgas, karastatud | 25 dB | EI30 | - | 2.54275 | yes | Süvistatud magnetiline lahtihoidmismehhanism
Klaasseina uks | 3. korrus | 979.938 | _METALL - alumiinium, _KLAAS - kirgas | SU-130-p | 980x2,200 | MUDELIS: _METALL - alumiinium; _KLAAS - kirgas; MÄRKUS: Täispuit ukseserv, fassaad spoonitud 8mm HDF, oksakuusk | Pöördavanev - Parem ; ARCHICAD tüüp: 2 | Kirgas, karastatud | 35 dB | nõudeid ei esitata | nõudeid ei esitata | 2.20486 | no | Liugvarrega sulgur, kaardilugeja, elektrilukk

# IfcDoor: 20 x 20 x 20 (5)
Type - OperationType: SINGLE_SWING_RIGHT; ParameterTakesPrecedence: no; Sizeable: no
OverallHeight: 2250 mm; Classification: 1.10 IfcDoorStyle (uks) (RKAS BIM + ARCHICAD Classification); Material: _METALL - alumiinium, _KLAAS - kirgas, _METALL - roostevaba terasleht, harjatud, 1mm
AR_Uks - 310_Materjal: MUDELIS: _METALL - alumiinium; _METALL - roostevaba terasleht, harjatud, 1mm; _KLAAS - kirgas; MÄRKUS: Täispuit ukseserv, fassaad spoonitud 8mm HDF, oksakuusk; 335_Välispiire: no; 340_Soojusläbivus: 0; 350_Klaaspakett: -; 360_Ratastooliga: no; 375_Viimistlus_seest: Leng: METALL- tsink; Ukseleht: METALL- tsink; MÄRKUS: Toonitud matt lakk; 376_Viimistlus_väljast: Leng: METALL- tsink; Ukseleht: METALL- tsink; MÄRKUS: -; 900_Tootja: -; 905_Mudel: -; 910_Tooteinfo: -; 915_Kasutus-ja_hooldusjuhend: -
Pset_ManufacturerOccurrence - SerialNumber: Off
AC_Pset_RenovationAndPhasing - Renovation Status: Undefined
Name | In | OverallWidth (mm) | Reference = 300_Tüüp | 001_Nimetus | 305_Ava_mõõt | 315_Avanemine | 320_Klaas | 325_Helipidavus | 330_Tulekindlus | 345_Päikesekiirgus_tegur | 355_Pindala (m2) | 365_Isesulguv = 370_Evakuatsiooniväljapääs | 380_Lukustus
Ühepoolne siseuks | 1. korrus | 980 | SU-423-v | Siseuks | 980x2,200 | Pöördavanev - Vasak ; ARCHICAD tüüp: 2 | Kirgas, karastatud | 35 dB | EI30 | Undefined | 2.205 | yes | Liugvarrega sulgur
Siseuks | 2. korrus | 980 | SU-407-v | Siseuks | 980x2,200 | Pöördavanev - Vasak ; ARCHICAD tüüp: 2 | Kirgas, karastatud, lamineeritud | 35 dB | EI30 | nõudeid ei esitata | 2.205 | yes | Liugvarrega sulgur
Klaasseina uks | 2. korrus | 1130 | SU-410-v | Klaasseina uks | 1,130x2,200 | Pöördavanev, igapäevaselt magnet kinnituse abil avatud olekus. Tulekahju olukorras sulgub uks automaatselt evakuatsiooniukseks - Vasak ; ARCHICAD tüüp: 3 | Kirgas, karastatud | 25 dB | EI30 | nõudeid ei esitata | 2.5425 | yes | Süvistatud magnetiline lahtihoidmismehhanism
Klaasseina uks | 3. korrus | 940 | SU-137-v | Klaasseina uks | 940x2,200 | Pöördavanev - Parem ; ARCHICAD tüüp: 2 | Kirgas, klaas | 35 dB | nõudeid ei esitata | - | 2.115 | no | Liugvarrega sulgur, kaardilugeja, elektrilukk
Klaasseina uks | 3. korrus | 1130 | SU-410-v | Klaasseina uks | 1,130x2,200 | Pöördavanev, igapäevaselt magnet kinnituse abil avatud olekus. Tulekahju olukorras sulgub uks automaatselt evakuatsiooniukseks - Vasak ; ARCHICAD tüüp: 3 | Kirgas, karastatud | 25 dB | EI30 | - | 2.5425 | yes | Süvistatud magnetiline lahtihoidmismehhanism

# IfcDoor: 20 x 2100 x 20, Siseuks
In: 1. korrus
Type - OperationType: SINGLE_SWING_LEFT; ParameterTakesPrecedence: no; Sizeable: no
OverallHeight: 2070 mm; OverallWidth: 880 mm; Classification: 1.10 IfcDoorStyle (uks) (RKAS BIM + ARCHICAD Classification); Material: _METALL - alumiinium, _KLAAS - kirgas, _METALL - roostevaba terasleht, harjatud, 1mm
Pset_DoorCommon - Reference: SU-148-p
AR_Uks - 001_Nimetus: Siseuks; 300_Tüüp: SU-148-p; 305_Ava_mõõt: 880x2,020; 310_Materjal: MUDELIS: _METALL - alumiinium; _METALL - roostevaba terasleht, harjatud, 1mm; _KLAAS - kirgas; MÄRKUS: Täispuit ukseserv, fassaad spoonitud 8mm HDF, oksakuusk; 315_Avanemine: Pöördavanev - Parem ; ARCHICAD tüüp: 3; 320_Klaas: Kirgas, karastatud; 325_Helipidavus: 35 dB; 330_Tulekindlus: nõudeid ei esitata; 335_Välispiire: no; 340_Soojusläbivus: 0; 345_Päikesekiirgus_tegur: nõudeid ei esitata; 350_Klaaspakett: -; 355_Pindala: 1.8201 m2; 360_Ratastooliga: no; 365_Isesulguv: no; 370_Evakuatsiooniväljapääs: no; 375_Viimistlus_seest: Leng: TOON- RAL 9006 alumiinium hall; Ukseleht: TOON- RAL 9006 alumiinium hall; MÄRKUS: Toonitud matt lakk; 376_Viimistlus_väljast: Leng: TOON- RAL 9006 alumiinium hall; Ukseleht: TOON- RAL 9006 alumiinium hall; MÄRKUS: -; 380_Lukustus: Liugvarrega sulgur; 900_Tootja: -; 905_Mudel: -; 910_Tooteinfo: -; 915_Kasutus-ja_hooldusjuhend: -
Pset_ManufacturerOccurrence - SerialNumber: Off
AC_Pset_RenovationAndPhasing - Renovation Status: Undefined

# IfcDoor: 20 x 2100 x 20, Siseuks
In: 1. korrus
Type - OperationType: SINGLE_SWING_RIGHT; ParameterTakesPrecedence: no; Sizeable: no
OverallHeight: 2070 mm; OverallWidth: 840 mm; Classification: 1.10 IfcDoorStyle (uks) (RKAS BIM + ARCHICAD Classification); Material: _METALL - alumiinium, _KLAAS - kirgas, _METALL - roostevaba terasleht, harjatud, 1mm
Pset_DoorCommon - Reference: SU-148-v
AR_Uks - 001_Nimetus: Siseuks; 300_Tüüp: SU-148-v; 305_Ava_mõõt: 840x2,020; 310_Materjal: MUDELIS: _METALL - alumiinium; _METALL - roostevaba terasleht, harjatud, 1mm; _KLAAS - kirgas; MÄRKUS: Täispuit ukseserv, fassaad spoonitud 8mm HDF, oksakuusk; 315_Avanemine: Pöördavanev - Parem ; ARCHICAD tüüp: 3; 320_Klaas: Kirgas, karastatud, lamineeritud; 325_Helipidavus: 35 dB; 330_Tulekindlus: nõudeid ei esitata; 335_Välispiire: no; 340_Soojusläbivus: 0; 345_Päikesekiirgus_tegur: -; 350_Klaaspakett: -; 355_Pindala: 1.7388 m2; 360_Ratastooliga: no; 365_Isesulguv: no; 370_Evakuatsiooniväljapääs: no; 375_Viimistlus_seest: Leng: TOON- RAL 9006 alumiinium hall; Ukseleht: TOON- RAL 9006 alumiinium hall; MÄRKUS: Toonitud matt lakk; 376_Viimistlus_väljast: Leng: TOON- RAL 9006 alumiinium hall; Ukseleht: TOON- RAL 9006 alumiinium hall; MÄRKUS: -; 380_Lukustus: Liugvarrega sulgur; 900_Tootja: -; 905_Mudel: -; 910_Tooteinfo: -; 915_Kasutus-ja_hooldusjuhend: -
Pset_ManufacturerOccurrence - SerialNumber: Off
AC_Pset_RenovationAndPhasing - Renovation Status: Undefined

# IfcDoor: 20 x 5 x 20, Klaasseina uks
In: 1. korrus
Type - OperationType: DOUBLE_DOOR_SINGLE_SWING; ParameterTakesPrecedence: no; Sizeable: no
OverallHeight: 2270 mm; OverallWidth: 1757.06 mm; Classification: 1.10 IfcDoorStyle (uks) (RKAS BIM + ARCHICAD Classification); Material: _METALL - alumiinium, _KLAAS - kirgas, _METALL - roostevaba terasleht, harjatud, 1mm
Pset_DoorCommon - Reference: SU-404-p
AR_Uks - 001_Nimetus: Klaasseina uks; 300_Tüüp: SU-404-p; 305_Ava_mõõt: 1,757x2,220; 310_Materjal: MUDELIS: _METALL - alumiinium; _METALL - roostevaba terasleht, harjatud, 1mm; _KLAAS - kirgas; MÄRKUS: Täispuit ukseserv, fassaad spoonitud 8mm HDF, oksakuusk; 315_Avanemine: Pöördavanev, igapäevaselt magnet kinnituse abil avatud olekus. Tulekahju olukorras sulgub uks automaatselt evakuatsiooniukseks ; ARCHICAD tüüp: 2; 320_Klaas: Kirgas, karastatud; 325_Helipidavus: 30 dB; 330_Tulekindlus: EI30; 335_Välispiire: no; 340_Soojusläbivus: 0; 345_Päikesekiirgus_tegur: nõudeid ei esitata; 350_Klaaspakett: -; 355_Pindala: 3.98852 m2; 360_Ratastooliga: yes; 365_Isesulguv: yes; 370_Evakuatsiooniväljapääs: yes; 375_Viimistlus_seest: Leng: METALL- tsink; Ukseleht: METALL- tsink; MÄRKUS: Toonitud matt lakk; 376_Viimistlus_väljast: Leng: METALL- tsink; Ukseleht: METALL- tsink; MÄRKUS: -; 380_Lukustus: Süvistatud magnetiline lahtihoidmismehhanism; 900_Tootja: -; 905_Mudel: -; 910_Tooteinfo: -; 915_Kasutus-ja_hooldusjuhend: -
Pset_ManufacturerOccurrence - SerialNumber: Off
AC_Pset_RenovationAndPhasing - Renovation Status: Undefined

# IfcDoor: 20 x 5 x 20, Siseuks
In: 1. korrus
Type - OperationType: SINGLE_SWING_LEFT; ParameterTakesPrecedence: no; Sizeable: no
OverallHeight: 2070 mm; OverallWidth: 880 mm; Classification: 1.10 IfcDoorStyle (uks) (RKAS BIM + ARCHICAD Classification); Material: _METALL - alumiinium, _KLAAS - kirgas, _METALL - roostevaba terasleht, harjatud, 1mm
Pset_DoorCommon - Reference: SU-148-p
AR_Uks - 001_Nimetus: Siseuks; 300_Tüüp: SU-148-p; 305_Ava_mõõt: 880x2,020; 310_Materjal: MUDELIS: _METALL - alumiinium; _METALL - roostevaba terasleht, harjatud, 1mm; _KLAAS - kirgas; MÄRKUS: Täispuit ukseserv, fassaad spoonitud 8mm HDF, oksakuusk; 315_Avanemine: Pöördavanev - Parem ; ARCHICAD tüüp: 3; 320_Klaas: Kirgas, karastatud; 325_Helipidavus: 35 dB; 330_Tulekindlus: nõudeid ei esitata; 335_Välispiire: no; 340_Soojusläbivus: 0; 345_Päikesekiirgus_tegur: nõudeid ei esitata; 350_Klaaspakett: -; 355_Pindala: 1.8216 m2; 360_Ratastooliga: no; 365_Isesulguv: no; 370_Evakuatsiooniväljapääs: no; 375_Viimistlus_seest: Leng: TOON- RAL 9006 alumiinium hall; Ukseleht: TOON- RAL 9006 alumiinium hall; MÄRKUS: Toonitud matt lakk; 376_Viimistlus_väljast: Leng: TOON- RAL 9006 alumiinium hall; Ukseleht: TOON- RAL 9006 alumiinium hall; MÄRKUS: -; 380_Lukustus: Liugvarrega sulgur; 900_Tootja: -; 905_Mudel: -; 910_Tooteinfo: -; 915_Kasutus-ja_hooldusjuhend: -
Pset_ManufacturerOccurrence - SerialNumber: Off
AC_Pset_RenovationAndPhasing - Renovation Status: Undefined

# IfcDoor: 72 x 1225 x 48, Kahepoolne välisuks
In: 1. korrus
Type - OperationType: DOUBLE_DOOR_SINGLE_SWING; ParameterTakesPrecedence: no; Sizeable: no
OverallHeight: 2435 mm; OverallWidth: 2810 mm; Classification: 1.10 IfcDoorStyle (uks) (RKAS BIM + ARCHICAD Classification); Material: _METALL - alumiinium, _KLAAS - kirgas, _METALL - roostevaba terasleht, harjatud, 1mm
Pset_DoorCommon - Reference: VU-301-p-ga
AR_Uks - 001_Nimetus: Kahepoolne välisuks; 300_Tüüp: VU-301-p-ga; 305_Ava_mõõt: 2 810x2 435; 310_Materjal: MUDELIS: _METALL - alumiinium; _METALL - roostevaba terasleht, harjatud, 1mm; _KLAAS - kirgas; MÄRKUS: Alumiinium; 315_Avanemine: Pöördavanev-põhileht Parem ; ARCHICAD tüüp: 2; 320_Klaas: Kirgas turvaklaas; 325_Helipidavus: 33 dB; 330_Tulekindlus: nõudeid ei esitata; 335_Välispiire: yes; 340_Soojusläbivus: 1.1; 345_Päikesekiirgus_tegur: 0,26; 350_Klaaspakett: 3-kordene, seest lamineeritud ja väljast karastatud. 4-16-4-16-44,6 turvaklaas; 355_Pindala: 6.83974 m2; 360_Ratastooliga: yes; 365_Isesulguv: yes; 370_Evakuatsiooniväljapääs: yes; 375_Viimistlus_seest: Leng: TOON- RAL 9006 alumiinium hall; Ukseleht: TOON- RAL 9006 alumiinium hall; MÄRKUS:; 376_Viimistlus_väljast: Leng: TOON- RAL 9006 alumiinium hall; Ukseleht: TOON- RAL 9006 alumiinium hall; MÄRKUS:; 380_Lukustus: Vastavalt lukustusprojektile. Lukud peavad olema pingega lukus - pingeta lahti; 900_Tootja: nt Warmeco OÜ; 905_Mudel: Schüco AD UP 75, lai adapterproofiil või analoog; 910_Tooteinfo: -; 915_Kasutus-ja_hooldusjuhend: -
Pset_ManufacturerOccurrence - SerialNumber: Off
AC_Pset_RenovationAndPhasing - Renovation Status: Undefined

# IfcDoor: 915 x 1225 x 48, Kahepoolne välisuks
In: 1. korrus
Type - OperationType: DOUBLE_DOOR_SINGLE_SWING; ParameterTakesPrecedence: no; Sizeable: no
OverallHeight: 2435 mm; OverallWidth: 2810.45 mm; Classification: 1.10 IfcDoorStyle (uks) (RKAS BIM + ARCHICAD Classification); Material: _METALL - alumiinium, _KLAAS - kirgas, _METALL - teras
Pset_DoorCommon - Reference: VU-301-p-ga
AR_Uks - 001_Nimetus: Kahepoolne välisuks; 300_Tüüp: VU-301-p-ga; 305_Ava_mõõt: 2 810x2 435; 310_Materjal: MUDELIS: _METALL - alumiinium; _METALL - teras; _KLAAS - kirgas; MÄRKUS: Alumiinium; 315_Avanemine: Pöördavanev-põhileht Parem ; ARCHICAD tüüp: 2; 320_Klaas: Kirgas turvaklaas; 325_Helipidavus: 33 dB; 330_Tulekindlus: nõudeid ei esitata; 335_Välispiire: yes; 340_Soojusläbivus: 1.1; 345_Päikesekiirgus_tegur: 0,26; 350_Klaaspakett: 3-kordene, seest lamineeritud ja väljast karastatud. 4-16-4-16-44,6 turvaklaas; 355_Pindala: 6.84346 m2; 360_Ratastooliga: yes; 365_Isesulguv: yes; 370_Evakuatsiooniväljapääs: yes; 375_Viimistlus_seest: Leng: TOON- RAL 9006 alumiinium hall; Ukseleht: TOON- RAL 9006 alumiinium hall; MÄRKUS:; 376_Viimistlus_väljast: Leng: TOON- RAL 9006 alumiinium hall; Ukseleht: TOON- RAL 9006 alumiinium hall; MÄRKUS:; 380_Lukustus: Vastavalt lukustusprojektile. Lukud peavad olema pingega lukus - pingeta lahti; 900_Tootja: nt Warmeco OÜ; 905_Mudel: Schüco AD UP 75, lai adapterproofiil või analoog; 910_Tooteinfo: -; 915_Kasutus-ja_hooldusjuhend: -
Pset_ManufacturerOccurrence - SerialNumber: Off
AC_Pset_RenovationAndPhasing - Renovation Status: Undefined

# IfcDoor: 941 x 2270 x 20, Klaasseina uks
In: 2. korrus
Type - OperationType: SINGLE_SWING_RIGHT; ParameterTakesPrecedence: no; Sizeable: no
OverallHeight: 2250 mm; OverallWidth: 1015 mm; Classification: 1.10 IfcDoorStyle (uks) (RKAS BIM + ARCHICAD Classification); Material: _METALL - alumiinium, _KLAAS - kirgas, _METALL - roostevaba terasleht, harjatud, 1mm
Pset_DoorCommon - Reference: SU-136-p
AR_Uks - 001_Nimetus: Klaasseina uks; 300_Tüüp: SU-136-p; 305_Ava_mõõt: 1,015x2,200; 310_Materjal: MUDELIS: _METALL - alumiinium; _METALL - roostevaba terasleht, harjatud, 1mm; _KLAAS - kirgas; MÄRKUS: Täispuit ukseserv, fassaad spoonitud 8mm HDF, oksakuusk; 315_Avanemine: Pöördavanev - Vasak ; ARCHICAD tüüp: 2; 320_Klaas: Kirgas, klaas; 325_Helipidavus: 40 dB; 330_Tulekindlus: nõudeid ei esitata; 335_Välispiire: no; 340_Soojusläbivus: 0; 345_Päikesekiirgus_tegur: nõudeid ei esitata; 350_Klaaspakett: -; 355_Pindala: 2.28375 m2; 360_Ratastooliga: no; 365_Isesulguv: no; 370_Evakuatsiooniväljapääs: no; 375_Viimistlus_seest: Leng: METALL- tsink; Ukseleht: METALL- tsink; MÄRKUS: Toonitud matt lakk; 376_Viimistlus_väljast: Leng: METALL- tsink; Ukseleht: METALL- tsink; MÄRKUS: -; 380_Lukustus: Liugvarrega sulgur, kaardilugeja, elektrilukk; 900_Tootja: -; 905_Mudel: -; 910_Tooteinfo: -; 915_Kasutus-ja_hooldusjuhend: -
Pset_ManufacturerOccurrence - SerialNumber: Off
AC_Pset_RenovationAndPhasing - Renovation Status: Undefined

# IfcDoor: 945 x 2270 x 20, Klaasseina uks
In: 1. korrus
Type - OperationType: DOUBLE_DOOR_SINGLE_SWING; ParameterTakesPrecedence: no; Sizeable: no
OverallHeight: 2250 mm; OverallWidth: 1850 mm; Classification: 1.10 IfcDoorStyle (uks) (RKAS BIM + ARCHICAD Classification); Material: _METALL - alumiinium, _KLAAS - kirgas, _METALL - roostevaba terasleht, harjatud, 1mm
Pset_DoorCommon - Reference: SU-403-p
AR_Uks - 001_Nimetus: Klaasseina uks; 300_Tüüp: SU-403-p; 305_Ava_mõõt: 1,850x2,200; 310_Materjal: MUDELIS: _METALL - alumiinium; _METALL - roostevaba terasleht, harjatud, 1mm; _KLAAS - kirgas; MÄRKUS: Täispuit ukseserv, fassaad spoonitud 8mm HDF, oksakuusk; 315_Avanemine: Pöördavanev ; ARCHICAD tüüp: 2; 320_Klaas: Kirgas, karastatud; 325_Helipidavus: 35 dB; 330_Tulekindlus: EI45; 335_Välispiire: no; 340_Soojusläbivus: 0; 345_Päikesekiirgus_tegur: Undefined; 350_Klaaspakett: -; 355_Pindala: 4.1625 m2; 360_Ratastooliga: yes; 365_Isesulguv: yes; 370_Evakuatsiooniväljapääs: no; 375_Viimistlus_seest: Leng: METALL- tsink; Ukseleht: METALL- tsink; MÄRKUS: Toonitud matt lakk; 376_Viimistlus_väljast: Leng: METALL- tsink; Ukseleht: METALL- tsink; MÄRKUS: -; 380_Lukustus: Liugvarrega sulgur, kaardilugeja, elektrilukk; 900_Tootja: -; 905_Mudel: -; 910_Tooteinfo: -; 915_Kasutus-ja_hooldusjuhend: -
Pset_ManufacturerOccurrence - SerialNumber: Off
AC_Pset_RenovationAndPhasing - Renovation Status: Undefined

# IfcDoor: 950 x 2265 x 20, Siseuks
In: 1. korrus
Type - OperationType: SINGLE_SWING_LEFT; ParameterTakesPrecedence: no; Sizeable: no
OverallHeight: 2225 mm; OverallWidth: 909.997 mm; Classification: 1.10 IfcDoorStyle (uks) (RKAS BIM + ARCHICAD Classification); Material: _METALL - alumiinium, _KLAAS - kirgas, _METALL - roostevaba terasleht, harjatud, 1mm
Pset_DoorCommon - Reference: SU-154-p
AR_Uks - 001_Nimetus: Siseuks; 300_Tüüp: SU-154-p; 305_Ava_mõõt: 910x2,225; 310_Materjal: MUDELIS: _METALL - alumiinium; _METALL - roostevaba terasleht, harjatud, 1mm; _KLAAS - kirgas; MÄRKUS: Täispuit ukseserv, fassaad spoonitud 8mm HDF, oksakuusk; 315_Avanemine: Pöördavanev - Parem ; ARCHICAD tüüp: 2; 320_Klaas: Kirgas, karastatud, lamineeritud; 325_Helipidavus: 25 dB; 330_Tulekindlus: nõudeid ei esitata; 335_Välispiire: no; 340_Soojusläbivus: 0; 345_Päikesekiirgus_tegur: -; 350_Klaaspakett: -; 355_Pindala: 2.02474 m2; 360_Ratastooliga: yes; 365_Isesulguv: yes; 370_Evakuatsiooniväljapääs: no; 375_Viimistlus_seest: Leng: METALL- tsink; Ukseleht: METALL- tsink; MÄRKUS: Toonitud matt lakk; 376_Viimistlus_väljast: Leng: METALL- tsink; Ukseleht: METALL- tsink; MÄRKUS: -; 380_Lukustus: Liugvarrega sulgur; 900_Tootja: -; 905_Mudel: -; 910_Tooteinfo: -; 915_Kasutus-ja_hooldusjuhend: -
Pset_ManufacturerOccurrence - SerialNumber: Off
AC_Pset_RenovationAndPhasing - Renovation Status: Undefined

# IfcDoor: Door 25, Hooldusluuk
In: 3. korrus
Type - OperationType: SINGLE_SWING_LEFT; ParameterTakesPrecedence: no; Sizeable: no
Type - Door Lining Properties - LiningDepth: 115 mm; LiningThickness: 40 mm; LiningOffset: -115 mm
Type - Door Panel Properties - Panel 1 - PanelDepth: 40 mm; PanelOperation: SWINGING; PanelWidth: 1; PanelPosition: MIDDLE
OverallHeight: 1000 mm; OverallWidth: 700 mm; Classification: 1.10 IfcDoorStyle (uks) (RKAS BIM + ARCHICAD Classification)
Pset_DoorCommon - Reference: SU-153-p; ThermalTransmittance: 0; IsExternal: no
AR_Uks - 001_Nimetus: Hooldusluuk; 300_Tüüp: SU-153-p; 305_Ava_mõõt: 700x1,000; 310_Materjal: MUDELIS: väljast-PUIT- kuusk H; PUIT- kuusk H; seest-PUIT- kuusk H; PUIT- kuusk H; MÄRKUS: Kuumtsingitud teras, 1mm; 315_Avanemine: Pöördavanev - Parem ; ARCHICAD tüüp: Side Hung; 320_Klaas: -; 325_Helipidavus: nõudeid ei esitata; 330_Tulekindlus: nõudeid ei esitata; 335_Välispiire: no; 340_Soojusläbivus: 0; 345_Päikesekiirgus_tegur: Nõudeid ei esitata; 350_Klaaspakett: -; 355_Pindala: 0.7 m2; 360_Ratastooliga: no; 365_Isesulguv: no; 370_Evakuatsiooniväljapääs: no; 375_Viimistlus_seest: Leng: PUIT- kuusk H; Ukseleht: PUIT- kuusk H; MÄRKUS: Kuumtsink; 376_Viimistlus_väljast: Leng: PUIT- kuusk H; Ukseleht: PUIT- kuusk H; MÄRKUS: -; 380_Lukustus: -; 900_Tootja: -; 905_Mudel: -; 910_Tooteinfo: -; 915_Kasutus-ja_hooldusjuhend: -
AC_Pset_RenovationAndPhasing - Renovation Status: New

# IfcDoor: Door 25 (8)
Type - OperationType: SINGLE_SWING_LEFT; ParameterTakesPrecedence: no; Sizeable: no
Type - Door Lining Properties - LiningDepth: 50 mm; LiningThickness: 30 mm; LiningOffset: -50 mm
Type - Door Panel Properties - Panel 1 - PanelDepth: 40 mm; PanelOperation: SWINGING; PanelWidth: 1; PanelPosition: MIDDLE
OverallHeight: 700 mm; OverallWidth: 700 mm; Classification: 1.10 IfcDoorStyle (uks) (RKAS BIM + ARCHICAD Classification)
Pset_DoorCommon - ThermalTransmittance: 0; IsExternal: no
AR_Uks - 001_Nimetus: Hooldusluuk vastavalt SA osale; 305_Ava_mõõt: 700x700; 310_Materjal: MUDELIS: väljast-TOON- RAL 9003 valge; TOON- RAL 9003 valge; seest-TOON- RAL 9003 valge; TOON- RAL 9003 valge; MÄRKUS: Teras; 315_Avanemine: Pöördavanev - Parem ; ARCHICAD tüüp: Side Hung; 320_Klaas: -; 325_Helipidavus: nõudeid ei esitata; 330_Tulekindlus: nõudeid ei esitata; 335_Välispiire: no; 340_Soojusläbivus: 0; 350_Klaaspakett: -; 355_Pindala: 0.49 m2; 360_Ratastooliga: no; 365_Isesulguv: no; 370_Evakuatsiooniväljapääs: no; 375_Viimistlus_seest: Leng: TOON- RAL 9003 valge; Ukseleht: TOON- RAL 9003 valge; MÄRKUS: -; 380_Lukustus: -; 900_Tootja: Alustar; 910_Tooteinfo: -; 915_Kasutus-ja_hooldusjuhend: -
AC_Pset_RenovationAndPhasing - Renovation Status: New
Name | In | Reference = 300_Tüüp | 345_Päikesekiirgus_tegur | 376_Viimistlus_väljast | 905_Mudel
2 x Hooldusluuk vastavalt SA osale | 1. korrus | HL-2 | Undefined | Leng: TOON- RAL 9003 valge; Ukseleht: TOON- RAL 9003 valge; MÄRKUS: Plaaditud vastavalt SA osale | Alustar F3 plaaditav
2 x Hooldusluuk vastavalt SA osale | 2. korrus | HL-1 | - | Leng: TOON- RAL 9003 valge; Ukseleht: TOON- RAL 9003 valge; MÄRKUS: Krohvitud ja värvitud vastavalt seinaviimistlusele | Alustar F2
2 x Hooldusluuk vastavalt SA osale | 2. korrus | HL-2 | Undefined | Leng: TOON- RAL 9003 valge; Ukseleht: TOON- RAL 9003 valge; MÄRKUS: Plaaditud vastavalt SA osale | Alustar F3 plaaditav
2 x Hooldusluuk vastavalt SA osale | 3. korrus | HL-2 | Undefined | Leng: TOON- RAL 9003 valge; Ukseleht: TOON- RAL 9003 valge; MÄRKUS: Plaaditud vastavalt SA osale | Alustar F3 plaaditav

# IfcDoor: Door 25, Välisuks
In: 4. TEHNO korrus
Type - OperationType: SINGLE_SWING_LEFT; ParameterTakesPrecedence: no; Sizeable: no
Type - Door Lining Properties - LiningDepth: 50 mm; LiningThickness: 50 mm; ThresholdThickness: 20 mm; LiningOffset: 150 mm; ThresholdOffset: 200 mm
Type - Door Panel Properties - Panel 1 - PanelDepth: 50 mm; PanelOperation: SWINGING; PanelWidth: 1; PanelPosition: MIDDLE
OverallHeight: 1800 mm; OverallWidth: 1000 mm; Classification: 1.10 IfcDoorStyle (uks) (RKAS BIM + ARCHICAD Classification)
Pset_DoorCommon - Reference: VU-103-p; ThermalTransmittance: 0; IsExternal: yes
AR_Uks - 001_Nimetus: Ühepoolne välisuks; 300_Tüüp: VU-103-p; 305_Ava_mõõt: 1 000x1 800; 310_Materjal: MUDELIS: väljast-TOON- helehall RR21; TOON- helehall RR21; seest-TOON- helehall RR21; TOON- helehall RR21; MÄRKUS: Kuumtsingitud lehtteras; 315_Avanemine: Pöördavanev - Parem ; ARCHICAD tüüp: Side Hung; 320_Klaas: -; 325_Helipidavus: 33 dB; 330_Tulekindlus: nõudeid ei esitata; 335_Välispiire: yes; 340_Soojusläbivus: 1.52; 345_Päikesekiirgus_tegur: -; 350_Klaaspakett: -; 355_Pindala: 1.8 m2; 360_Ratastooliga: no; 365_Isesulguv: no; 370_Evakuatsiooniväljapääs: no; 375_Viimistlus_seest: Leng: TOON- helehall RR21; Ukseleht: TOON- helehall RR21; MÄRKUS: RAL9006 alumiiniumhall; 376_Viimistlus_väljast: Leng: TOON- helehall RR21; Ukseleht: TOON- helehall RR21; MÄRKUS: RAL9006 alumiiniumhall; 380_Lukustus: Vastavalt lukustusprojektile; 900_Tootja: Saku Metall Uksetehas või samaväärne; 905_Mudel: Metalluks Q Med 1311; 910_Tooteinfo: Undefined; 915_Kasutus-ja_hooldusjuhend: Undefined
AC_Pset_RenovationAndPhasing - Renovation Status: New

# IfcDoor: Door 25, Välisuks
In: 4. TEHNO korrus
Type - OperationType: SINGLE_SWING_LEFT; ParameterTakesPrecedence: no; Sizeable: no
Type - Door Lining Properties - LiningDepth: 50 mm; LiningThickness: 50 mm; ThresholdThickness: 20 mm; LiningOffset: 150 mm; ThresholdOffset: 250 mm
Type - Door Panel Properties - Panel 1 - PanelDepth: 50 mm; PanelOperation: SWINGING; PanelWidth: 1; PanelPosition: MIDDLE
OverallHeight: 2100 mm; OverallWidth: 1000 mm; Classification: 1.10 IfcDoorStyle (uks) (RKAS BIM + ARCHICAD Classification)
Pset_DoorCommon - Reference: VU-102-p; ThermalTransmittance: 0; IsExternal: yes
AR_Uks - 001_Nimetus: Ühepoolne välisuks; 300_Tüüp: VU-102-p; 305_Ava_mõõt: 1 000x2 100; 310_Materjal: MUDELIS: väljast-TOON- helehall RR21; TOON- helehall RR21; seest-TOON- helehall RR21; TOON- helehall RR21; MÄRKUS: Kuumtsingitud lehtteras; 315_Avanemine: Pöördavanev - Parem ; ARCHICAD tüüp: Side Hung; 320_Klaas: -; 325_Helipidavus: 33 dB; 330_Tulekindlus: nõudeid ei esitata; 335_Välispiire: yes; 340_Soojusläbivus: 1.52; 345_Päikesekiirgus_tegur: -; 350_Klaaspakett: -; 355_Pindala: 2.1 m2; 360_Ratastooliga: no; 365_Isesulguv: no; 370_Evakuatsiooniväljapääs: no; 375_Viimistlus_seest: Leng: TOON- helehall RR21; Ukseleht: TOON- helehall RR21; MÄRKUS: RAL9006 alumiiniumhall; 376_Viimistlus_väljast: Leng: TOON- helehall RR21; Ukseleht: TOON- helehall RR21; MÄRKUS: RAL9006 alumiiniumhall; 380_Lukustus: Vastavalt lukustusprojektile; 900_Tootja: Saku Metall Uksetehas või samaväärne; 905_Mudel: Metalluks Q Med 1311; 910_Tooteinfo: -; 915_Kasutus-ja_hooldusjuhend: -
AC_Pset_RenovationAndPhasing - Renovation Status: New

# IfcDoor: Door 25 (3)
In: 1. korrus
Type - OperationType: SINGLE_SWING_LEFT; ParameterTakesPrecedence: no; Sizeable: no
Type - Door Lining Properties - LiningDepth: 80 mm; LiningThickness: 40 mm; LiningOffset: 1.38778e-14 mm
Type - Door Panel Properties - Panel 1 - PanelDepth: 40 mm; PanelOperation: SWINGING; PanelWidth: 1; PanelPosition: MIDDLE
OverallHeight: 2100 mm; OverallWidth: 1310 mm; Classification: 1.10 IfcDoorStyle (uks) (RKAS BIM + ARCHICAD Classification)
AR_Uks - 001_Nimetus: Välisuks; 305_Ava_mõõt: 1 310x2 100; 310_Materjal: MUDELIS: väljast-TOON- RAL 9006 alumiinium hall; TOON- RAL 9006 alumiinium hall; seest-TOON- RAL 9006 alumiinium hall; TOON- RAL 9006 alumiinium hall; MÄRKUS: Alumiinium; 315_Avanemine: Pöördavanev-Parem ; ARCHICAD tüüp: Side Hung; 320_Klaas: Kirgas turvaklaas; 330_Tulekindlus: nõudeid ei esitata; 335_Välispiire: yes; 340_Soojusläbivus: 1; 355_Pindala: 2.75101 m2; 360_Ratastooliga: yes; 365_Isesulguv: yes; 370_Evakuatsiooniväljapääs: yes; 380_Lukustus: Vastavalt lukustusprojektile. Lukud peavad olema pingega lukus - pingeta lahti; 900_Tootja: nt Warmeco OÜ; 905_Mudel: Schüco AD UP 75 või analoog; 910_Tooteinfo: -; 915_Kasutus-ja_hooldusjuhend: -
Pset_DoorCommon - ThermalTransmittance: 0; GlazingAreaFraction: 1.97309; IsExternal: yes
AC_Pset_RenovationAndPhasing - Renovation Status: New
Name | 376_Viimistlus_väljast = 375_Viimistlus_seest | 300_Tüüp = Reference | 325_Helipidavus | 345_Päikesekiirgus_tegur | 350_Klaaspakett
2 x Välisuks | Leng: TOON- RAL 9006 alumiinium hall; Ukseleht: TOON- RAL 9006 alumiinium hall; | VU-104-p-gb | 34 dB | 0,39 | 3-kordne klaaspakett, seest lamineeritud ja väljast karastatud, turvaklaas, 4-16-4-16-44,1
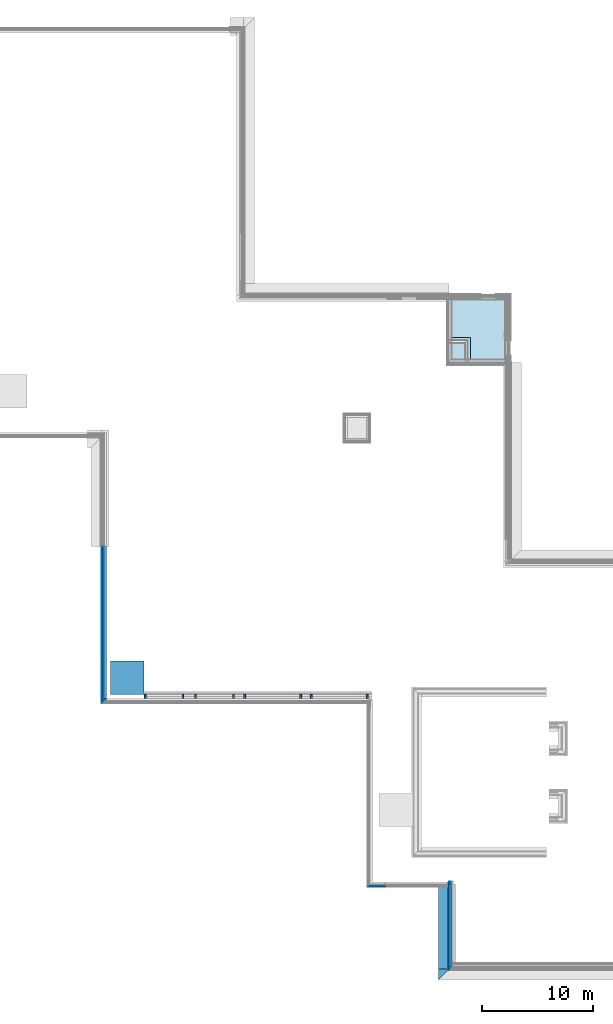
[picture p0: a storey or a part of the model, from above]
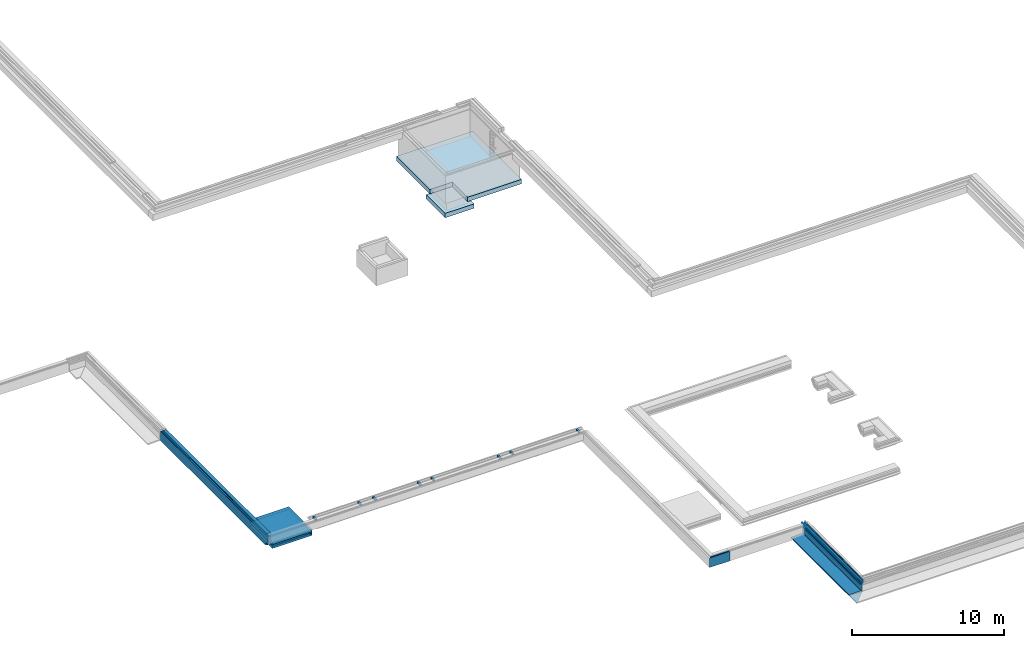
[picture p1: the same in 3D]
Properties of the parts of a building model (IFC2X3), part 4 of 14

# IfcDoor: Door 25 (3)
Name | 376_Viimistlus_väljast = 375_Viimistlus_seest | 300_Tüüp = Reference | 325_Helipidavus | 345_Päikesekiirgus_tegur | 350_Klaaspakett
Välisuks | Leng: TOON- RAL 9006 alumiinium hall; Ukseleht: TOON- RAL 9006 alumiinium hall; MÄRKUS: RAL 9006 alumiiniumhall | VU-104-p-ga | 33 dB | 0,26 | 3-kordne klaaspakett,seest lamineeritud ja väljast karastatud, 4-16-4-16-44,1

# IfcDoor: Door 25, Siseuks
In: 1. korrus
Type - OperationType: SINGLE_SWING_LEFT; ParameterTakesPrecedence: no; Sizeable: no
Type - Door Lining Properties - LiningDepth: 92 mm; LiningThickness: 40 mm; LiningOffset: -10 mm
Type - Door Panel Properties - Panel 1 - PanelDepth: 40 mm; PanelOperation: SWINGING; PanelWidth: 1; PanelPosition: MIDDLE
OverallHeight: 2300 mm; OverallWidth: 1000 mm; Classification: 1.10 IfcDoorStyle (uks) (RKAS BIM + ARCHICAD Classification)
Pset_DoorCommon - Reference: SU-420-p; ThermalTransmittance: 0; IsExternal: no
AR_Uks - 001_Nimetus: Siseuks; 300_Tüüp: SU-420-p; 305_Ava_mõõt: 1,000x2,300; 310_Materjal: MUDELIS: väljast-PUIT- kuusk H; PUIT- kuusk H; seest-PUIT- kuusk H; PUIT- kuusk H; MÄRKUS: Täispuit ukseserv, fassaad spoonitud 8mm HDF, oksakuusk; 315_Avanemine: Pöördavanev - Parem ; ARCHICAD tüüp: Side Hung; 320_Klaas: -; 325_Helipidavus: 35 dB; 330_Tulekindlus: EI30; 335_Välispiire: no; 340_Soojusläbivus: 0; 345_Päikesekiirgus_tegur: Nõudeid ei esitata; 350_Klaaspakett: -; 355_Pindala: 2.3 m2; 360_Ratastooliga: no; 365_Isesulguv: no; 370_Evakuatsiooniväljapääs: no; 375_Viimistlus_seest: Leng: PUIT- kuusk H; Ukseleht: PUIT- kuusk H; MÄRKUS: Toonitud matt lakk; 376_Viimistlus_väljast: Leng: PUIT- kuusk H; Ukseleht: PUIT- kuusk H; MÄRKUS: -; 380_Lukustus: Liugvarrega sulgur, kaardilugeja, elektrilukk; 900_Tootja: -; 905_Mudel: -; 910_Tooteinfo: -; 915_Kasutus-ja_hooldusjuhend: -
AC_Pset_RenovationAndPhasing - Renovation Status: New

# IfcDoor: Door 25, Siseuks
In: 3. korrus
Type - OperationType: SINGLE_SWING_LEFT; ParameterTakesPrecedence: no; Sizeable: no
Type - Door Lining Properties - LiningDepth: 92 mm; LiningThickness: 40 mm; LiningOffset: -300 mm
Type - Door Panel Properties - Panel 1 - PanelDepth: 40 mm; PanelOperation: SWINGING; PanelWidth: 1; PanelPosition: MIDDLE
OverallHeight: 2300 mm; OverallWidth: 1000 mm; Classification: 1.10 IfcDoorStyle (uks) (RKAS BIM + ARCHICAD Classification)
Pset_DoorCommon - Reference: SU-139-p; ThermalTransmittance: 0; IsExternal: no
AR_Uks - 001_Nimetus: Siseuks; 300_Tüüp: SU-139-p; 305_Ava_mõõt: 1,000x2,300; 310_Materjal: MUDELIS: väljast-PUIT- kuusk H; PUIT- kuusk H; seest-PUIT- kuusk H; PUIT- kuusk H; MÄRKUS: Täispuit ukseserv, fassaad spoonitud 8mm HDF, oksakuusk; 315_Avanemine: Pöördavanev - Parem ; ARCHICAD tüüp: Side Hung; 320_Klaas: -; 325_Helipidavus: nõudeid ei esitata; 330_Tulekindlus: nõudeid ei esitata; 335_Välispiire: no; 340_Soojusläbivus: 0; 345_Päikesekiirgus_tegur: Nõudeid ei esitata; 350_Klaaspakett: -; 355_Pindala: 2.3 m2; 360_Ratastooliga: no; 365_Isesulguv: no; 370_Evakuatsiooniväljapääs: no; 375_Viimistlus_seest: Leng: PUIT- kuusk H; Ukseleht: PUIT- kuusk H; MÄRKUS: Toonitud matt lakk; 376_Viimistlus_väljast: Leng: PUIT- kuusk H; Ukseleht: PUIT- kuusk H; MÄRKUS: -; 380_Lukustus: Liugvarrega sulgur, kaardilugeja, elektrilukk; 900_Tootja: -; 905_Mudel: -; 910_Tooteinfo: -; 915_Kasutus-ja_hooldusjuhend: -
AC_Pset_RenovationAndPhasing - Renovation Status: New

# IfcDoor: Door 25, Siseuks
In: 1. korrus
Type - OperationType: SINGLE_SWING_LEFT; ParameterTakesPrecedence: no; Sizeable: no
Type - Door Lining Properties - LiningDepth: 92 mm; LiningThickness: 40 mm; LiningOffset: -52 mm
Type - Door Panel Properties - Panel 1 - PanelDepth: 40 mm; PanelOperation: SWINGING; PanelWidth: 1; PanelPosition: MIDDLE
OverallHeight: 2300 mm; OverallWidth: 1000 mm; Classification: 1.10 IfcDoorStyle (uks) (RKAS BIM + ARCHICAD Classification)
Pset_DoorCommon - Reference: SU-119-p; ThermalTransmittance: 0; IsExternal: no
AR_Uks - 001_Nimetus: Siseuks; 300_Tüüp: SU-119-p; 305_Ava_mõõt: 1,000x2,300; 310_Materjal: MUDELIS: väljast-PUIT- kuusk H; PUIT- kuusk H; seest-PUIT- kuusk H; PUIT- kuusk H; MÄRKUS: Täispuit ukseserv, fassaad spoonitud 8mm HDF, oksakuusk; 315_Avanemine: Lükanduks - Parem ; ARCHICAD tüüp: Side Hung; 320_Klaas: -; 325_Helipidavus: nõudeid ei esitata; 330_Tulekindlus: nõudeid ei esitata; 335_Välispiire: no; 340_Soojusläbivus: 0; 345_Päikesekiirgus_tegur: Nõudeid ei esitata; 350_Klaaspakett: -; 355_Pindala: 2.3 m2; 360_Ratastooliga: no; 365_Isesulguv: no; 370_Evakuatsiooniväljapääs: no; 375_Viimistlus_seest: Leng: PUIT- kuusk H; Ukseleht: PUIT- kuusk H; MÄRKUS: Toonitud matt lakk; 376_Viimistlus_väljast: Leng: PUIT- kuusk H; Ukseleht: PUIT- kuusk H; MÄRKUS: -; 380_Lukustus: ilma lingita, sõrmekonks, mehaaniline lukk; 900_Tootja: -; 905_Mudel: -; 910_Tooteinfo: -; 915_Kasutus-ja_hooldusjuhend: -
AC_Pset_RenovationAndPhasing - Renovation Status: New

# IfcDoor: Door 25 (5)
In: 1. korrus
Type - OperationType: SINGLE_SWING_LEFT; ParameterTakesPrecedence: no; Sizeable: no
Type - Door Lining Properties - LiningDepth: 92 mm; LiningThickness: 40 mm; LiningOffset: -92 mm
Type - Door Panel Properties - Panel 1 - PanelDepth: 40 mm; PanelOperation: SWINGING; PanelWidth: 1; PanelPosition: MIDDLE
OverallWidth: 1000 mm; Classification: 1.10 IfcDoorStyle (uks) (RKAS BIM + ARCHICAD Classification)
Pset_DoorCommon - ThermalTransmittance: 0; IsExternal: no
AR_Uks - 001_Nimetus: Siseuks; 315_Avanemine: Pöördavanev - Parem ; ARCHICAD tüüp: Side Hung; 320_Klaas: -; 335_Välispiire: no; 340_Soojusläbivus: 0; 345_Päikesekiirgus_tegur: Nõudeid ei esitata; 350_Klaaspakett: -; 360_Ratastooliga: no; 365_Isesulguv: no; 370_Evakuatsiooniväljapääs: no; 376_Viimistlus_väljast: Leng: PUIT- kuusk H; Ukseleht: PUIT- kuusk H; MÄRKUS: -; 900_Tootja: -; 905_Mudel: -; 910_Tooteinfo: -; 915_Kasutus-ja_hooldusjuhend: -
AC_Pset_RenovationAndPhasing - Renovation Status: New
Name | OverallHeight (mm) | Reference = 300_Tüüp | 305_Ava_mõõt | 310_Materjal | 325_Helipidavus | 330_Tulekindlus | 355_Pindala (m2) | 375_Viimistlus_seest | 380_Lukustus
4 x Siseuks | 2300 | SU-126-p | 1,000x2,300 | MUDELIS: väljast-PUIT- kuusk H; PUIT- kuusk H; seest-PUIT- kuusk H; PUIT- kuusk H; MÄRKUS: Täispuit ukseserv, fassaad spoonitud 8mm HDF, oksakuusk | 30 dB | nõudeid ei esitata | 2.3 | Leng: PUIT- kuusk H; Ukseleht: PUIT- kuusk H; MÄRKUS: Toonitud matt lakk | Liugvarrega sulgur, kaardilugeja, elektrilukk
Siseuks | 2100 | SU-414-p | 1,000x2,100 | MUDELIS: väljast-PUIT- kuusk H; PUIT- kuusk H; seest-PUIT- kuusk H; PUIT- kuusk H; MÄRKUS: Kuumtsingitud teras, 1mm | 40 dB | EI30 | 2.1 | Leng: PUIT- kuusk H; Ukseleht: PUIT- kuusk H; MÄRKUS: Kuumtsink | -

# IfcDoor: Door 25 (2)
In: 1. korrus
Type - OperationType: SINGLE_SWING_LEFT; ParameterTakesPrecedence: no; Sizeable: no
Type - Door Lining Properties - LiningDepth: 92 mm; LiningThickness: 40 mm; LiningOffset: 118 mm
Type - Door Panel Properties - Panel 1 - PanelDepth: 40 mm; PanelOperation: SWINGING; PanelWidth: 1; PanelPosition: MIDDLE
OverallHeight: 2100 mm; OverallWidth: 1000 mm; Classification: 1.10 IfcDoorStyle (uks) (RKAS BIM + ARCHICAD Classification)
Pset_DoorCommon - Reference: SU-402-p; ThermalTransmittance: 0; IsExternal: no
AR_Uks - 001_Nimetus: Siseuks; 300_Tüüp: SU-402-p; 305_Ava_mõõt: 1,000x2,100; 310_Materjal: MUDELIS: väljast-PUIT- kuusk H; PUIT- kuusk H; seest-PUIT- kuusk H; PUIT- kuusk H; MÄRKUS: Kuumtsingitud teras, 1mm; 315_Avanemine: Pöördavanev - Parem ; ARCHICAD tüüp: Side Hung; 320_Klaas: -; 325_Helipidavus: 35 dB; 330_Tulekindlus: EI60; 335_Välispiire: no; 340_Soojusläbivus: 0; 345_Päikesekiirgus_tegur: Nõudeid ei esitata; 350_Klaaspakett: -; 355_Pindala: 2.1 m2; 360_Ratastooliga: no; 365_Isesulguv: no; 370_Evakuatsiooniväljapääs: no; 375_Viimistlus_seest: Leng: PUIT- kuusk H; Ukseleht: PUIT- kuusk H; MÄRKUS: Kuumtsink; 376_Viimistlus_väljast: Leng: PUIT- kuusk H; Ukseleht: PUIT- kuusk H; MÄRKUS: -; 380_Lukustus: Liugvarrega sulgur, kaardilugeja, elektrilukk; 900_Tootja: -; 905_Mudel: -; 910_Tooteinfo: -; 915_Kasutus-ja_hooldusjuhend: -
AC_Pset_RenovationAndPhasing - Renovation Status: New

# IfcDoor: Door 25, Siseuks
In: 1. korrus
Type - OperationType: SINGLE_SWING_LEFT; ParameterTakesPrecedence: no; Sizeable: no
Type - Door Lining Properties - LiningDepth: 92 mm; LiningThickness: 40 mm; LiningOffset: 165 mm
Type - Door Panel Properties - Panel 1 - PanelDepth: 40 mm; PanelOperation: SWINGING; PanelWidth: 1; PanelPosition: MIDDLE
OverallHeight: 2100 mm; OverallWidth: 1000 mm; Classification: 1.10 IfcDoorStyle (uks) (RKAS BIM + ARCHICAD Classification)
Pset_DoorCommon - Reference: SU-408-p; ThermalTransmittance: 0; IsExternal: no
AR_Uks - 001_Nimetus: Siseuks; 300_Tüüp: SU-408-p; 305_Ava_mõõt: 1,000x2,100; 310_Materjal: MUDELIS: väljast-PUIT- kuusk H; PUIT- kuusk H; seest-PUIT- kuusk H; PUIT- kuusk H; MÄRKUS: Täispuit ukseserv, fassaad värvitud 8mm HDF, oksakuusk; 315_Avanemine: Pöördavanev - Parem ; ARCHICAD tüüp: Side Hung; 320_Klaas: -; 325_Helipidavus: nõudeid ei esitata; 330_Tulekindlus: EI30; 335_Välispiire: no; 340_Soojusläbivus: 0; 345_Päikesekiirgus_tegur: Nõudeid ei esitata; 350_Klaaspakett: -; 355_Pindala: 2.1 m2; 360_Ratastooliga: no; 365_Isesulguv: no; 370_Evakuatsiooniväljapääs: no; 375_Viimistlus_seest: Leng: PUIT- kuusk H; Ukseleht: PUIT- kuusk H; MÄRKUS: Toonitud matt lakk; 376_Viimistlus_väljast: Leng: PUIT- kuusk H; Ukseleht: PUIT- kuusk H; MÄRKUS: -; 380_Lukustus: Liugvarrega sulgur, kaardilugeja, elektrilukk; 900_Tootja: -; 905_Mudel: -; 910_Tooteinfo: -; 915_Kasutus-ja_hooldusjuhend: -
AC_Pset_RenovationAndPhasing - Renovation Status: New

# IfcDoor: Door 25 (3)
Type - OperationType: SINGLE_SWING_LEFT; ParameterTakesPrecedence: no; Sizeable: no
Type - Door Lining Properties - LiningDepth: 92 mm; LiningThickness: 50 mm; LiningOffset: -177 mm
Type - Door Panel Properties - Panel 1 - PanelDepth: 50 mm; PanelOperation: SWINGING; PanelWidth: 1; PanelPosition: MIDDLE
OverallHeight: 2300 mm; OverallWidth: 1000 mm; Classification: 1.10 IfcDoorStyle (uks) (RKAS BIM + ARCHICAD Classification)
Pset_DoorCommon - Reference: SU-120-p; ThermalTransmittance: 0
AR_Uks - 001_Nimetus: Siseuks; 300_Tüüp: SU-120-p; 305_Ava_mõõt: 1,000x2,300; 310_Materjal: MUDELIS: väljast-TOON- RAL 9006 alumiinium hall; TOON- RAL 9006 alumiinium hall; seest-TOON- RAL 9006 alumiinium hall; TOON- RAL 9006 alumiinium hall; MÄRKUS: Kuumtsingitud teras, 1mm; 315_Avanemine: Pöördavanev - Parem ; ARCHICAD tüüp: Side Hung; 320_Klaas: -; 325_Helipidavus: 25 dB; 330_Tulekindlus: nõudeid ei esitata; 335_Välispiire: no; 340_Soojusläbivus: 0; 345_Päikesekiirgus_tegur: Nõudeid ei esitata; 350_Klaaspakett: -; 355_Pindala: 2.3 m2; 360_Ratastooliga: no; 365_Isesulguv: no; 370_Evakuatsiooniväljapääs: no; 375_Viimistlus_seest: Leng: TOON- RAL 9006 alumiinium hall; Ukseleht: TOON- RAL 9006 alumiinium hall; MÄRKUS: Pulbervärv, värvi toon vastavalt sanruumi tarnitavale keraamilisele plaadile.; 376_Viimistlus_väljast: Leng: TOON- RAL 9006 alumiinium hall; Ukseleht: TOON- RAL 9006 alumiinium hall; MÄRKUS: -; 380_Lukustus: Väljas link, sees väändenupp ja reeling ukse sulgemiseks; 900_Tootja: -; 905_Mudel: -; 910_Tooteinfo: -; 915_Kasutus-ja_hooldusjuhend: -
AC_Pset_RenovationAndPhasing - Renovation Status: New
Name | In
Siseuks | 1. korrus
Siseuks | 2. korrus
Siseuks | 3. korrus

# IfcDoor: Door 25, Siseuks
In: 2. korrus
Type - OperationType: SINGLE_SWING_LEFT; ParameterTakesPrecedence: no; Sizeable: no
Type - Door Lining Properties - LiningDepth: 92 mm; LiningThickness: 50 mm; LiningOffset: -35 mm
Type - Door Panel Properties - Panel 1 - PanelDepth: 50 mm; PanelOperation: SWINGING; PanelWidth: 1; PanelPosition: MIDDLE
OverallHeight: 2300 mm; OverallWidth: 1000 mm; Classification: 1.10 IfcDoorStyle (uks) (RKAS BIM + ARCHICAD Classification)
Pset_DoorCommon - Reference: SU-416-p; ThermalTransmittance: 0; IsExternal: no
AR_Uks - 001_Nimetus: Siseuks; 300_Tüüp: SU-416-p; 305_Ava_mõõt: 1,000x2,300; 310_Materjal: MUDELIS: väljast-TOON- RAL 9006 alumiinium hall; TOON- RAL 9006 alumiinium hall; seest-TOON- RAL 9006 alumiinium hall; TOON- RAL 9006 alumiinium hall; MÄRKUS: Täispuit ukseserv, fassaad spoonitud 8mm HDF, oksakuusk; 315_Avanemine: Pöördavanev - Parem ; ARCHICAD tüüp: Side Hung; 320_Klaas: -; 325_Helipidavus: 45 dB; 330_Tulekindlus: EI30; 335_Välispiire: no; 340_Soojusläbivus: 0; 345_Päikesekiirgus_tegur: Nõudeid ei esitata; 350_Klaaspakett: -; 355_Pindala: 2.3 m2; 360_Ratastooliga: no; 365_Isesulguv: no; 370_Evakuatsiooniväljapääs: no; 375_Viimistlus_seest: Leng: TOON- RAL 9006 alumiinium hall; Ukseleht: TOON- RAL 9006 alumiinium hall; MÄRKUS: Toonitud matt lakk; 376_Viimistlus_väljast: Leng: TOON- RAL 9006 alumiinium hall; Ukseleht: TOON- RAL 9006 alumiinium hall; MÄRKUS: -; 380_Lukustus: Liugvarrega sulgur, kaardilugeja, elektrilukk; 900_Tootja: -; 905_Mudel: -; 910_Tooteinfo: -; 915_Kasutus-ja_hooldusjuhend: -
AC_Pset_RenovationAndPhasing - Renovation Status: New

# IfcDoor: Door 25, Siseuks
In: 2. korrus
Type - OperationType: SINGLE_SWING_LEFT; ParameterTakesPrecedence: no; Sizeable: no
Type - Door Lining Properties - LiningDepth: 92 mm; LiningThickness: 50 mm; LiningOffset: -77 mm
Type - Door Panel Properties - Panel 1 - PanelDepth: 50 mm; PanelOperation: SWINGING; PanelWidth: 1; PanelPosition: MIDDLE
OverallHeight: 2300 mm; OverallWidth: 1000 mm; Classification: 1.10 IfcDoorStyle (uks) (RKAS BIM + ARCHICAD Classification)
Pset_DoorCommon - Reference: SU-131-p; ThermalTransmittance: 0; IsExternal: no
AR_Uks - 001_Nimetus: Siseuks; 300_Tüüp: SU-131-p; 305_Ava_mõõt: 1,000x2,300; 310_Materjal: MUDELIS: väljast-TOON- RAL 9006 alumiinium hall; TOON- RAL 9006 alumiinium hall; seest-TOON- RAL 9006 alumiinium hall; TOON- RAL 9006 alumiinium hall; MÄRKUS: Täispuit ukseserv, fassaad spoonitud 8mm HDF, oksakuusk; 315_Avanemine: Pöördavanev - Parem ; ARCHICAD tüüp: Side Hung; 320_Klaas: -; 325_Helipidavus: nõudeid ei esitata; 330_Tulekindlus: nõudeid ei esitata; 335_Välispiire: no; 340_Soojusläbivus: 0; 345_Päikesekiirgus_tegur: Nõudeid ei esitata; 350_Klaaspakett: -; 355_Pindala: 2.3 m2; 360_Ratastooliga: no; 365_Isesulguv: no; 370_Evakuatsiooniväljapääs: no; 375_Viimistlus_seest: Leng: TOON- RAL 9006 alumiinium hall; Ukseleht: TOON- RAL 9006 alumiinium hall; MÄRKUS: Toonitud matt lakk; 376_Viimistlus_väljast: Leng: TOON- RAL 9006 alumiinium hall; Ukseleht: TOON- RAL 9006 alumiinium hall; MÄRKUS: -; 380_Lukustus: ilma lingita, sõrmekonks, mehaaniline lukk; 900_Tootja: -; 905_Mudel: -; 910_Tooteinfo: -; 915_Kasutus-ja_hooldusjuhend: -
AC_Pset_RenovationAndPhasing - Renovation Status: New

# IfcDoor: Door 25, Siseuks
In: 1. korrus
Type - OperationType: SINGLE_SWING_LEFT; ParameterTakesPrecedence: no; Sizeable: no
Type - Door Lining Properties - LiningDepth: 92 mm; LiningThickness: 50 mm; LiningOffset: -82 mm
Type - Door Panel Properties - Panel 1 - PanelDepth: 50 mm; PanelOperation: SWINGING; PanelWidth: 1; PanelPosition: MIDDLE
OverallHeight: 2300 mm; OverallWidth: 1000 mm; Classification: 1.10 IfcDoorStyle (uks) (RKAS BIM + ARCHICAD Classification)
Pset_DoorCommon - Reference: SU-108-v; ThermalTransmittance: 0; IsExternal: no
AR_Uks - 001_Nimetus: Siseuks; 300_Tüüp: SU-108-v; 305_Ava_mõõt: 1,000x2,300; 310_Materjal: MUDELIS: väljast-TOON- RAL 9006 alumiinium hall; TOON- RAL 9006 alumiinium hall; seest-TOON- RAL 9006 alumiinium hall; TOON- RAL 9006 alumiinium hall; MÄRKUS: Täispuit ukseserv, fassaad spoonitud 8mm HDF, oksakuusk; 315_Avanemine: Pöördavanev - Parem ; ARCHICAD tüüp: Side Hung; 320_Klaas: -; 325_Helipidavus: 30 dB; 330_Tulekindlus: nõudeid ei esitata; 335_Välispiire: no; 340_Soojusläbivus: 0; 345_Päikesekiirgus_tegur: Nõudeid ei esitata; 350_Klaaspakett: -; 355_Pindala: 2.3 m2; 360_Ratastooliga: no; 365_Isesulguv: no; 370_Evakuatsiooniväljapääs: no; 375_Viimistlus_seest: Leng: TOON- RAL 9006 alumiinium hall; Ukseleht: TOON- RAL 9006 alumiinium hall; MÄRKUS: Toonitud matt lakk; 376_Viimistlus_väljast: Leng: TOON- RAL 9006 alumiinium hall; Ukseleht: TOON- RAL 9006 alumiinium hall; MÄRKUS: -; 380_Lukustus: Liugvarrega sulgur, mehaaniline lukk; 900_Tootja: -; 905_Mudel: -; 910_Tooteinfo: -; 915_Kasutus-ja_hooldusjuhend: -
AC_Pset_RenovationAndPhasing - Renovation Status: New

# IfcDoor: Door 25 (16)
Type - OperationType: SINGLE_SWING_LEFT; ParameterTakesPrecedence: no; Sizeable: no
Type - Door Lining Properties - LiningDepth: 92 mm; LiningThickness: 50 mm; LiningOffset: -92 mm
Type - Door Panel Properties - Panel 1 - PanelDepth: 50 mm; PanelOperation: SWINGING; PanelWidth: 1; PanelPosition: MIDDLE
Classification: 1.10 IfcDoorStyle (uks) (RKAS BIM + ARCHICAD Classification)
Pset_DoorCommon - ThermalTransmittance: 0; IsExternal: no
AR_Uks - 001_Nimetus: Siseuks; 315_Avanemine: Pöördavanev - Parem ; ARCHICAD tüüp: Side Hung; 335_Välispiire: no; 340_Soojusläbivus: 0; 345_Päikesekiirgus_tegur: Nõudeid ei esitata; 350_Klaaspakett: -; 365_Isesulguv: no; 370_Evakuatsiooniväljapääs: no; 376_Viimistlus_väljast: Leng: TOON- RAL 9006 alumiinium hall; Ukseleht: TOON- RAL 9006 alumiinium hall; MÄRKUS: -; 900_Tootja: -; 905_Mudel: -; 910_Tooteinfo: -; 915_Kasutus-ja_hooldusjuhend: -
AC_Pset_RenovationAndPhasing - Renovation Status: New
Name | In | OverallHeight (mm) | OverallWidth (mm) | Reference = 300_Tüüp | 305_Ava_mõõt | 310_Materjal | 320_Klaas | 325_Helipidavus | 330_Tulekindlus | 355_Pindala (m2) | 360_Ratastooliga | 375_Viimistlus_seest | 380_Lukustus
Siseuks | 1. korrus | 2300 | 1000 | SU-124-p | 1,000x2,300 | MUDELIS: väljast-TOON- RAL 9006 alumiinium hall; TOON- RAL 9006 alumiinium hall; seest-TOON- RAL 9006 alumiinium hall; TOON- RAL 9006 alumiinium hall; MÄRKUS: Täispuit ukseserv, fassaad spoonitud 8mm HDF, oksakuusk | Kirgas, karastatud | 40 dB | nõudeid ei esitata | 2.3 | no | Leng: TOON- RAL 9006 alumiinium hall; Ukseleht: TOON- RAL 9006 alumiinium hall; MÄRKUS: Toonitud matt lakk | Liugvarrega sulgur, kaardilugeja, elektrilukk | Pset_DoorCommon - GlazingAreaFraction: 1.72
Siseuks | 1. korrus | 2100 | 1000 | SU-127-p | 1,000x2,100 | MUDELIS: väljast-TOON- RAL 9006 alumiinium hall; TOON- RAL 9006 alumiinium hall; seest-TOON- RAL 9006 alumiinium hall; TOON- RAL 9006 alumiinium hall; MÄRKUS: Kuumtsingitud teras, 1mm | - | 25 dB | nõudeid ei esitata | 2.1 | yes | Leng: TOON- RAL 9006 alumiinium hall; Ukseleht: TOON- RAL 9006 alumiinium hall; MÄRKUS: Pulbervärv, värvi toon vastavalt sanruumi tarnitavale keraamilisele plaadile. | Väljas link, sees väändenupp ja reeling ukse sulgemiseks
Siseuks | 1. korrus | 2300 | 800 | SU-145-p | 800x2,300 | MUDELIS: väljast-TOON- RAL 9006 alumiinium hall; TOON- RAL 9006 alumiinium hall; seest-TOON- RAL 9006 alumiinium hall; TOON- RAL 9006 alumiinium hall; MÄRKUS: Kuumtsingitud teras, 1mm | - | - | nõudeid ei esitata | 1.84 | no | Leng: TOON- RAL 9006 alumiinium hall; Ukseleht: TOON- RAL 9006 alumiinium hall; MÄRKUS: Pulbervärv | ilma lingita, sõrmekonks, mehaaniline lukk
3 x Siseuks | 2. korrus | 2300 | 800 | SU-107-p | 800x2,300 | MUDELIS: väljast-TOON- RAL 9006 alumiinium hall; TOON- RAL 9006 alumiinium hall; seest-TOON- RAL 9006 alumiinium hall; TOON- RAL 9006 alumiinium hall; MÄRKUS: Kuumtsingitud teras, 1mm | - | 25 dB | nõudeid ei esitata | 1.84 | no | Leng: TOON- RAL 9006 alumiinium hall; Ukseleht: TOON- RAL 9006 alumiinium hall; MÄRKUS: Pulbervärv, värvi toon vastavalt sanruumi tarnitavale keraamilisele plaadile. | Liugvarrega sulgur, väljas link, sees väändenupp
Siseuks | 2. korrus | 2300 | 1000 | SU-124-p | 1,000x2,300 | MUDELIS: väljast-TOON- RAL 9006 alumiinium hall; TOON- RAL 9006 alumiinium hall; seest-TOON- RAL 9006 alumiinium hall; TOON- RAL 9006 alumiinium hall; MÄRKUS: Täispuit ukseserv, fassaad spoonitud 8mm HDF, oksakuusk | Kirgas, karastatud | 40 dB | nõudeid ei esitata | 2.3 | no | Leng: TOON- RAL 9006 alumiinium hall; Ukseleht: TOON- RAL 9006 alumiinium hall; MÄRKUS: Toonitud matt lakk | Liugvarrega sulgur, kaardilugeja, elektrilukk | Pset_DoorCommon - GlazingAreaFraction: 1.72
Siseuks | 2. korrus | 2300 | 800 | SU-145-p | 800x2,300 | MUDELIS: väljast-TOON- RAL 9006 alumiinium hall; TOON- RAL 9006 alumiinium hall; seest-TOON- RAL 9006 alumiinium hall; TOON- RAL 9006 alumiinium hall; MÄRKUS: Kuumtsingitud teras, 1mm | - | - | nõudeid ei esitata | 1.84 | no | Leng: TOON- RAL 9006 alumiinium hall; Ukseleht: TOON- RAL 9006 alumiinium hall; MÄRKUS: Pulbervärv | ilma lingita, sõrmekonks, mehaaniline lukk
Siseuks | 2. korrus | 2300 | 1000 | SU-415-p | 1,000x2,300 | MUDELIS: väljast-TOON- RAL 9006 alumiinium hall; TOON- RAL 9006 alumiinium hall; seest-TOON- RAL 9006 alumiinium hall; TOON- RAL 9006 alumiinium hall; MÄRKUS: Täispuit ukseserv, fassaad spoonitud 8mm HDF, oksakuusk | - | nõudeid ei esitata | EI30 | 2.3 | no | Leng: TOON- RAL 9006 alumiinium hall; Ukseleht: TOON- RAL 9006 alumiinium hall; MÄRKUS: Toonitud matt lakk | Liugvarrega sulgur, kaardilugeja, elektrilukk
2 x Siseuks | 3. korrus | 2300 | 1000 | SU-141-p | 1,000x2,300 | MUDELIS: väljast-TOON- RAL 9006 alumiinium hall; TOON- RAL 9006 alumiinium hall; seest-TOON- RAL 9006 alumiinium hall; TOON- RAL 9006 alumiinium hall; MÄRKUS: Täispuit ukseserv, fassaad spoonitud 8mm HDF, oksakuusk | Kirgas, klaas | 30 dB | nõudeid ei esitata | 2.3 | no | Leng: TOON- RAL 9006 alumiinium hall; Ukseleht: TOON- RAL 9006 alumiinium hall; MÄRKUS: Toonitud matt lakk | Liugvarrega sulgur, kaardilugeja, elektrilukk | Pset_DoorCommon - GlazingAreaFraction: 1.72
Siseuks | 3. korrus | 2300 | 1000 | SU-131-p | 1,000x2,300 | MUDELIS: väljast-TOON- RAL 9006 alumiinium hall; TOON- RAL 9006 alumiinium hall; seest-TOON- RAL 9006 alumiinium hall; TOON- RAL 9006 alumiinium hall; MÄRKUS: Täispuit ukseserv, fassaad spoonitud 8mm HDF, oksakuusk | - | nõudeid ei esitata | nõudeid ei esitata | 2.3 | no | Leng: TOON- RAL 9006 alumiinium hall; Ukseleht: TOON- RAL 9006 alumiinium hall; MÄRKUS: Toonitud matt lakk | ilma lingita, sõrmekonks, mehaaniline lukk
Siseuks | 3. korrus | 2300 | 800 | SU-145-p | 800x2,300 | MUDELIS: väljast-TOON- RAL 9006 alumiinium hall; TOON- RAL 9006 alumiinium hall; seest-TOON- RAL 9006 alumiinium hall; TOON- RAL 9006 alumiinium hall; MÄRKUS: Kuumtsingitud teras, 1mm | - | - | nõudeid ei esitata | 1.84 | no | Leng: TOON- RAL 9006 alumiinium hall; Ukseleht: TOON- RAL 9006 alumiinium hall; MÄRKUS: Pulbervärv | ilma lingita, sõrmekonks, mehaaniline lukk
3 x Siseuks | 3. korrus | 2300 | 800 | SU-107-p | 800x2,300 | MUDELIS: väljast-TOON- RAL 9006 alumiinium hall; TOON- RAL 9006 alumiinium hall; seest-TOON- RAL 9006 alumiinium hall; TOON- RAL 9006 alumiinium hall; MÄRKUS: Kuumtsingitud teras, 1mm | - | 25 dB | nõudeid ei esitata | 1.84 | no | Leng: TOON- RAL 9006 alumiinium hall; Ukseleht: TOON- RAL 9006 alumiinium hall; MÄRKUS: Pulbervärv, värvi toon vastavalt sanruumi tarnitavale keraamilisele plaadile. | Liugvarrega sulgur, väljas link, sees väändenupp

# IfcDoor: Door 25, Siseuks
In: 1. korrus
Type - OperationType: SINGLE_SWING_LEFT; ParameterTakesPrecedence: no; Sizeable: no
Type - Door Lining Properties - LiningDepth: 92 mm; LiningThickness: 50 mm; LiningOffset: 103 mm
Type - Door Panel Properties - Panel 1 - PanelDepth: 50 mm; PanelOperation: SWINGING; PanelWidth: 1; PanelPosition: MIDDLE
OverallHeight: 2300 mm; OverallWidth: 1050 mm; Classification: 1.10 IfcDoorStyle (uks) (RKAS BIM + ARCHICAD Classification)
Pset_DoorCommon - Reference: SU-109-p; ThermalTransmittance: 0; IsExternal: no
AR_Uks - 001_Nimetus: Siseuks; 300_Tüüp: SU-109-p; 305_Ava_mõõt: 1,050x2,300; 310_Materjal: MUDELIS: väljast-TOON- RAL 9006 alumiinium hall; TOON- RAL 9006 alumiinium hall; seest-TOON- RAL 9006 alumiinium hall; TOON- RAL 9006 alumiinium hall; MÄRKUS: Täispuit ukseserv, fassaad spoonitud 8mm HDF, oksakuusk; 315_Avanemine: Pöördavanev - Parem ; ARCHICAD tüüp: Side Hung; 320_Klaas: -; 325_Helipidavus: nõudeid ei esitata; 330_Tulekindlus: nõudeid ei esitata; 335_Välispiire: no; 340_Soojusläbivus: 0; 345_Päikesekiirgus_tegur: Nõudeid ei esitata; 350_Klaaspakett: -; 355_Pindala: 2.415 m2; 360_Ratastooliga: no; 365_Isesulguv: no; 370_Evakuatsiooniväljapääs: no; 375_Viimistlus_seest: Leng: TOON- RAL 9006 alumiinium hall; Ukseleht: TOON- RAL 9006 alumiinium hall; MÄRKUS: Toonitud matt lakk; 376_Viimistlus_väljast: Leng: TOON- RAL 9006 alumiinium hall; Ukseleht: TOON- RAL 9006 alumiinium hall; MÄRKUS: -; 380_Lukustus: Liugvarrega sulgur, mehaaniline lukk; 900_Tootja: -; 905_Mudel: -; 910_Tooteinfo: -; 915_Kasutus-ja_hooldusjuhend: -
AC_Pset_RenovationAndPhasing - Renovation Status: New

# IfcDoor: Door 25 (4)
In: 1. korrus
Type - OperationType: SINGLE_SWING_LEFT; ParameterTakesPrecedence: no; Sizeable: no
Type - Door Lining Properties - LiningDepth: 92 mm; LiningThickness: 50 mm; LiningOffset: 108 mm
Type - Door Panel Properties - Panel 1 - PanelDepth: 50 mm; PanelOperation: SWINGING; PanelWidth: 1; PanelPosition: MIDDLE
OverallHeight: 2100 mm; Classification: 1.10 IfcDoorStyle (uks) (RKAS BIM + ARCHICAD Classification)
Pset_DoorCommon - ThermalTransmittance: 0; IsExternal: no
AR_Uks - 001_Nimetus: Siseuks; 315_Avanemine: Pöördavanev - Parem ; ARCHICAD tüüp: Side Hung; 320_Klaas: -; 325_Helipidavus: 25 dB; 330_Tulekindlus: nõudeid ei esitata; 335_Välispiire: no; 340_Soojusläbivus: 0; 345_Päikesekiirgus_tegur: Nõudeid ei esitata; 350_Klaaspakett: -; 365_Isesulguv: no; 370_Evakuatsiooniväljapääs: no; 376_Viimistlus_väljast: Leng: TOON- RAL 9006 alumiinium hall; Ukseleht: TOON- RAL 9006 alumiinium hall; MÄRKUS: -; 900_Tootja: -; 905_Mudel: -; 910_Tooteinfo: -; 915_Kasutus-ja_hooldusjuhend: -
AC_Pset_RenovationAndPhasing - Renovation Status: New
Name | OverallWidth (mm) | Reference = 300_Tüüp | 305_Ava_mõõt | 310_Materjal | 355_Pindala (m2) | 360_Ratastooliga | 375_Viimistlus_seest | 380_Lukustus
Siseuks | 1000 | SU-127-p | 1,000x2,100 | MUDELIS: väljast-TOON- RAL 9006 alumiinium hall; TOON- RAL 9006 alumiinium hall; seest-TOON- RAL 9006 alumiinium hall; TOON- RAL 9006 alumiinium hall; MÄRKUS: Kuumtsingitud teras, 1mm | 2.1 | yes | Leng: TOON- RAL 9006 alumiinium hall; Ukseleht: TOON- RAL 9006 alumiinium hall; MÄRKUS: Pulbervärv, värvi toon vastavalt sanruumi tarnitavale keraamilisele plaadile. | Väljas link, sees väändenupp ja reeling ukse sulgemiseks
2 x Siseuks | 800 | SU-128-p | 800x2,100 | MUDELIS: väljast-TOON- RAL 9006 alumiinium hall; TOON- RAL 9006 alumiinium hall; seest-TOON- RAL 9006 alumiinium hall; TOON- RAL 9006 alumiinium hall; MÄRKUS: Kuumtsingitud teras, 1mm | 1.68 | no | Leng: TOON- RAL 9006 alumiinium hall; Ukseleht: TOON- RAL 9006 alumiinium hall; MÄRKUS: Kuumtsink | Liugvarrega sulgur, väljas link, sees väändenupp
Siseuks | 800 | SU-125-p | 800x2,100 | MUDELIS: väljast-TOON- RAL 9006 alumiinium hall; TOON- RAL 9006 alumiinium hall; seest-TOON- RAL 9006 alumiinium hall; TOON- RAL 9006 alumiinium hall; MÄRKUS: Täispuit ukseserv, fassaad spoonitud 8mm HDF, oksakuusk | 1.68 | no | Leng: TOON- RAL 9006 alumiinium hall; Ukseleht: TOON- RAL 9006 alumiinium hall; MÄRKUS: Toonitud matt lakk | Liugvarrega sulgur, väljas link, sees väändenupp | Pset_DoorCommon - GlazingAreaFraction: 1.17

# IfcDoor: Door 25, Siseuks
In: 1. korrus
Type - OperationType: SINGLE_SWING_LEFT; ParameterTakesPrecedence: no; Sizeable: no
Type - Door Lining Properties - LiningDepth: 92 mm; LiningThickness: 50 mm; LiningOffset: 125 mm
Type - Door Panel Properties - Panel 1 - PanelDepth: 50 mm; PanelOperation: SWINGING; PanelWidth: 1; PanelPosition: MIDDLE
OverallHeight: 2300 mm; OverallWidth: 1000 mm; Classification: 1.10 IfcDoorStyle (uks) (RKAS BIM + ARCHICAD Classification)
Pset_DoorCommon - Reference: SU-108-p; ThermalTransmittance: 0; IsExternal: no
AR_Uks - 001_Nimetus: Siseuks; 300_Tüüp: SU-108-p; 305_Ava_mõõt: 1,000x2,300; 310_Materjal: MUDELIS: väljast-TOON- RAL 9006 alumiinium hall; TOON- RAL 9006 alumiinium hall; seest-TOON- RAL 9006 alumiinium hall; TOON- RAL 9006 alumiinium hall; MÄRKUS: Täispuit ukseserv, fassaad spoonitud 8mm HDF, oksakuusk; 315_Avanemine: Pöördavanev - Parem ; ARCHICAD tüüp: Side Hung; 320_Klaas: -; 325_Helipidavus: 25 dB; 330_Tulekindlus: nõudeid ei esitata; 335_Välispiire: no; 340_Soojusläbivus: 0; 345_Päikesekiirgus_tegur: Nõudeid ei esitata; 350_Klaaspakett: -; 355_Pindala: 2.3 m2; 360_Ratastooliga: no; 365_Isesulguv: no; 370_Evakuatsiooniväljapääs: no; 375_Viimistlus_seest: Leng: TOON- RAL 9006 alumiinium hall; Ukseleht: TOON- RAL 9006 alumiinium hall; MÄRKUS: Toonitud matt lakk; 376_Viimistlus_väljast: Leng: TOON- RAL 9006 alumiinium hall; Ukseleht: TOON- RAL 9006 alumiinium hall; MÄRKUS: -; 380_Lukustus: Liugvarrega sulgur, mehaaniline lukk; 900_Tootja: -; 905_Mudel: -; 910_Tooteinfo: -; 915_Kasutus-ja_hooldusjuhend: -
AC_Pset_RenovationAndPhasing - Renovation Status: New

# IfcDoor: Door 25 (17)
Type - OperationType: SINGLE_SWING_LEFT; ParameterTakesPrecedence: no; Sizeable: no
Type - Door Lining Properties - LiningDepth: 92 mm; LiningThickness: 50 mm; LiningOffset: 63 mm
Type - Door Panel Properties - Panel 1 - PanelDepth: 50 mm; PanelOperation: SWINGING; PanelWidth: 1; PanelPosition: MIDDLE
OverallWidth: 800 mm; Classification: 1.10 IfcDoorStyle (uks) (RKAS BIM + ARCHICAD Classification)
Pset_DoorCommon - ThermalTransmittance: 0
AR_Uks - 001_Nimetus: Siseuks; 310_Materjal: MUDELIS: väljast-TOON- RAL 9006 alumiinium hall; TOON- RAL 9006 alumiinium hall; seest-TOON- RAL 9006 alumiinium hall; TOON- RAL 9006 alumiinium hall; MÄRKUS: Kuumtsingitud teras, 1mm; 315_Avanemine: Pöördavanev - Parem ; ARCHICAD tüüp: Side Hung; 320_Klaas: -; 325_Helipidavus: 25 dB; 330_Tulekindlus: nõudeid ei esitata; 335_Välispiire: no; 340_Soojusläbivus: 0; 345_Päikesekiirgus_tegur: Nõudeid ei esitata; 350_Klaaspakett: -; 360_Ratastooliga: no; 365_Isesulguv: no; 370_Evakuatsiooniväljapääs: no; 376_Viimistlus_väljast: Leng: TOON- RAL 9006 alumiinium hall; Ukseleht: TOON- RAL 9006 alumiinium hall; MÄRKUS: -; 380_Lukustus: Liugvarrega sulgur, väljas link, sees väändenupp; 900_Tootja: -; 905_Mudel: -; 910_Tooteinfo: -; 915_Kasutus-ja_hooldusjuhend: -
AC_Pset_RenovationAndPhasing - Renovation Status: New
Name | In | OverallHeight (mm) | Reference = 300_Tüüp | 305_Ava_mõõt | 355_Pindala (m2) | 375_Viimistlus_seest
Siseuks | 1. korrus | 2100 | SU-123-p | 800x2,100 | 1.68 | Leng: TOON- RAL 9006 alumiinium hall; Ukseleht: TOON- RAL 9006 alumiinium hall; MÄRKUS: Kuumtsink | Pset_DoorCommon - IsExternal: no
5 x Siseuks | 1. korrus | 2300 | SU-107-p | 800x2,300 | 1.84 | Leng: TOON- RAL 9006 alumiinium hall; Ukseleht: TOON- RAL 9006 alumiinium hall; MÄRKUS: Pulbervärv, värvi toon vastavalt sanruumi tarnitavale keraamilisele plaadile. | Pset_DoorCommon - IsExternal: no
2 x Siseuks | 1. korrus | 2100 | SU-128-p | 800x2,100 | 1.68 | Leng: TOON- RAL 9006 alumiinium hall; Ukseleht: TOON- RAL 9006 alumiinium hall; MÄRKUS: Kuumtsink | Pset_DoorCommon - IsExternal: no
3 x Siseuks | 1. korrus | 2300 | SU-121-p | 800x2,300 | 1.84 | Leng: TOON- RAL 9006 alumiinium hall; Ukseleht: TOON- RAL 9006 alumiinium hall; MÄRKUS: Kuumtsink
3 x Siseuks | 2. korrus | 2300 | SU-121-p | 800x2,300 | 1.84 | Leng: TOON- RAL 9006 alumiinium hall; Ukseleht: TOON- RAL 9006 alumiinium hall; MÄRKUS: Kuumtsink
3 x Siseuks | 3. korrus | 2300 | SU-121-p | 800x2,300 | 1.84 | Leng: TOON- RAL 9006 alumiinium hall; Ukseleht: TOON- RAL 9006 alumiinium hall; MÄRKUS: Kuumtsink

# IfcDoor: Door 25, Siseuks
In: 3. korrus
Type - OperationType: SINGLE_SWING_LEFT; ParameterTakesPrecedence: no; Sizeable: no
Type - Door Lining Properties - LiningDepth: 92 mm; LiningThickness: 50 mm; LiningOffset: 78 mm
Type - Door Panel Properties - Panel 1 - PanelDepth: 50 mm; PanelOperation: SWINGING; PanelWidth: 1; PanelPosition: MIDDLE
OverallHeight: 2300 mm; OverallWidth: 1000 mm; Classification: 1.10 IfcDoorStyle (uks) (RKAS BIM + ARCHICAD Classification)
Pset_DoorCommon - Reference: SU-141-p; ThermalTransmittance: 0; GlazingAreaFraction: 1.72; IsExternal: no
AR_Uks - 001_Nimetus: Siseuks; 300_Tüüp: SU-141-p; 305_Ava_mõõt: 1,000x2,300; 310_Materjal: MUDELIS: väljast-TOON- RAL 9006 alumiinium hall; TOON- RAL 9006 alumiinium hall; seest-TOON- RAL 9006 alumiinium hall; TOON- RAL 9006 alumiinium hall; MÄRKUS: Täispuit ukseserv, fassaad spoonitud 8mm HDF, oksakuusk; 315_Avanemine: Pöördavanev - Parem ; ARCHICAD tüüp: Side Hung; 320_Klaas: Kirgas, klaas; 325_Helipidavus: 30 dB; 330_Tulekindlus: nõudeid ei esitata; 335_Välispiire: no; 340_Soojusläbivus: 0; 345_Päikesekiirgus_tegur: Nõudeid ei esitata; 350_Klaaspakett: -; 355_Pindala: 2.3 m2; 360_Ratastooliga: no; 365_Isesulguv: no; 370_Evakuatsiooniväljapääs: no; 375_Viimistlus_seest: Leng: TOON- RAL 9006 alumiinium hall; Ukseleht: TOON- RAL 9006 alumiinium hall; MÄRKUS: Toonitud matt lakk; 376_Viimistlus_väljast: Leng: TOON- RAL 9006 alumiinium hall; Ukseleht: TOON- RAL 9006 alumiinium hall; MÄRKUS: -; 380_Lukustus: Liugvarrega sulgur, kaardilugeja, elektrilukk; 900_Tootja: -; 905_Mudel: -; 910_Tooteinfo: -; 915_Kasutus-ja_hooldusjuhend: -
AC_Pset_RenovationAndPhasing - Renovation Status: New

# IfcDoor: Door 25 (7)
Type - OperationType: SINGLE_SWING_RIGHT; ParameterTakesPrecedence: no; Sizeable: no
Type - Door Lining Properties - LiningDepth: 50 mm; LiningThickness: 30 mm; LiningOffset: -50 mm
Type - Door Panel Properties - Panel 1 - PanelDepth: 40 mm; PanelOperation: SWINGING; PanelWidth: 1; PanelPosition: MIDDLE
OverallHeight: 700 mm; OverallWidth: 700 mm; Classification: 1.10 IfcDoorStyle (uks) (RKAS BIM + ARCHICAD Classification)
Pset_DoorCommon - ThermalTransmittance: 0; IsExternal: no
AR_Uks - 001_Nimetus: Hooldusluuk vastavalt SA osale; 305_Ava_mõõt: 700x700; 310_Materjal: MUDELIS: väljast-TOON- RAL 9003 valge; TOON- RAL 9003 valge; seest-TOON- RAL 9003 valge; TOON- RAL 9003 valge; MÄRKUS: Teras; 315_Avanemine: Pöördavanev - Vasak ; ARCHICAD tüüp: Side Hung; 320_Klaas: -; 325_Helipidavus: nõudeid ei esitata; 330_Tulekindlus: nõudeid ei esitata; 335_Välispiire: no; 340_Soojusläbivus: 0; 350_Klaaspakett: -; 355_Pindala: 0.49 m2; 360_Ratastooliga: no; 365_Isesulguv: no; 370_Evakuatsiooniväljapääs: no; 375_Viimistlus_seest: Leng: TOON- RAL 9003 valge; Ukseleht: TOON- RAL 9003 valge; MÄRKUS: -; 380_Lukustus: -; 900_Tootja: Alustar; 910_Tooteinfo: -; 915_Kasutus-ja_hooldusjuhend: -
AC_Pset_RenovationAndPhasing - Renovation Status: New
Name | In | Reference = 300_Tüüp | 345_Päikesekiirgus_tegur | 376_Viimistlus_väljast | 905_Mudel
2 x Hooldusluuk vastavalt SA osale | 1. korrus | HL-2 | Undefined | Leng: TOON- RAL 9003 valge; Ukseleht: TOON- RAL 9003 valge; MÄRKUS: Plaaditud vastavalt SA osale | Alustar F3 plaaditav
Hooldusluuk vastavalt SA osale | 2. korrus | HL-1 | - | Leng: TOON- RAL 9003 valge; Ukseleht: TOON- RAL 9003 valge; MÄRKUS: Krohvitud ja värvitud vastavalt seinaviimistlusele | Alustar F2
2 x Hooldusluuk vastavalt SA osale | 2. korrus | HL-2 | Undefined | Leng: TOON- RAL 9003 valge; Ukseleht: TOON- RAL 9003 valge; MÄRKUS: Plaaditud vastavalt SA osale | Alustar F3 plaaditav
2 x Hooldusluuk vastavalt SA osale | 3. korrus | HL-2 | Undefined | Leng: TOON- RAL 9003 valge; Ukseleht: TOON- RAL 9003 valge; MÄRKUS: Plaaditud vastavalt SA osale | Alustar F3 plaaditav

# IfcDoor: Door 25, Hooldusluuk vastavat SA osale
In: 2. korrus
Type - OperationType: SINGLE_SWING_RIGHT; ParameterTakesPrecedence: no; Sizeable: no
Type - Door Lining Properties - LiningDepth: 50 mm; LiningThickness: 30 mm; LiningOffset: 145 mm
Type - Door Panel Properties - Panel 1 - PanelDepth: 40 mm; PanelOperation: SWINGING; PanelWidth: 1; PanelPosition: MIDDLE
OverallHeight: 700 mm; OverallWidth: 700 mm; Classification: 1.10 IfcDoorStyle (uks) (RKAS BIM + ARCHICAD Classification)
Pset_DoorCommon - Reference: HL-1; ThermalTransmittance: 0; IsExternal: no
AR_Uks - 001_Nimetus: Hooldusluuk vastavat SA osale; 300_Tüüp: HL-1; 305_Ava_mõõt: 700x700; 310_Materjal: MUDELIS: väljast-TOON- RAL 9003 valge; TOON- RAL 9003 valge; seest-TOON- RAL 9003 valge; TOON- RAL 9003 valge; MÄRKUS: Teras; 315_Avanemine: Pöördavanev - Vasak ; ARCHICAD tüüp: Side Hung; 320_Klaas: -; 325_Helipidavus: nõudeid ei esitata; 330_Tulekindlus: nõudeid ei esitata; 335_Välispiire: no; 340_Soojusläbivus: 0; 345_Päikesekiirgus_tegur: Undefined; 350_Klaaspakett: -; 355_Pindala: 0.49 m2; 360_Ratastooliga: no; 365_Isesulguv: no; 370_Evakuatsiooniväljapääs: no; 375_Viimistlus_seest: Leng: TOON- RAL 9003 valge; Ukseleht: TOON- RAL 9003 valge; MÄRKUS: -; 376_Viimistlus_väljast: Leng: TOON- RAL 9003 valge; Ukseleht: TOON- RAL 9003 valge; MÄRKUS: Viimistletud vastavalt SA osale; 380_Lukustus: -; 900_Tootja: Alustar; 905_Mudel: Alustar F2; 910_Tooteinfo: -; 915_Kasutus-ja_hooldusjuhend: -
AC_Pset_RenovationAndPhasing - Renovation Status: New

# IfcDoor: Door 25, Siseuks
In: 3. korrus
Type - OperationType: SINGLE_SWING_RIGHT; ParameterTakesPrecedence: no; Sizeable: no
Type - Door Lining Properties - LiningDepth: 92 mm; LiningThickness: 40 mm; LiningOffset: -195 mm
Type - Door Panel Properties - Panel 1 - PanelDepth: 40 mm; PanelOperation: SWINGING; PanelWidth: 1; PanelPosition: MIDDLE
OverallHeight: 2100 mm; OverallWidth: 1000 mm; Classification: 1.10 IfcDoorStyle (uks) (RKAS BIM + ARCHICAD Classification)
Pset_DoorCommon - Reference: SU-402-v; ThermalTransmittance: 0; IsExternal: no
AR_Uks - 001_Nimetus: Siseuks; 300_Tüüp: SU-402-v; 305_Ava_mõõt: 1,000x2,100; 310_Materjal: MUDELIS: väljast-PUIT- kuusk H; PUIT- kuusk H; seest-PUIT- kuusk H; PUIT- kuusk H; MÄRKUS: Kuumtsingitud teras, 1mm; 315_Avanemine: Pöördavanev - Vasak ; ARCHICAD tüüp: Side Hung; 320_Klaas: -; 325_Helipidavus: nõudeid ei esitata; 330_Tulekindlus: EI45; 335_Välispiire: no; 340_Soojusläbivus: 0; 345_Päikesekiirgus_tegur: Nõudeid ei esitata; 350_Klaaspakett: -; 355_Pindala: 2.1 m2; 360_Ratastooliga: no; 365_Isesulguv: no; 370_Evakuatsiooniväljapääs: no; 375_Viimistlus_seest: Leng: PUIT- kuusk H; Ukseleht: PUIT- kuusk H; MÄRKUS: Kuumtsink; 376_Viimistlus_väljast: Leng: PUIT- kuusk H; Ukseleht: PUIT- kuusk H; MÄRKUS: -; 380_Lukustus: Liugvarrega sulgur; 900_Tootja: -; 905_Mudel: -; 910_Tooteinfo: -; 915_Kasutus-ja_hooldusjuhend: -
AC_Pset_RenovationAndPhasing - Renovation Status: New

# IfcDoor: Door 25, Siseuks
In: 1. korrus
Type - OperationType: SINGLE_SWING_RIGHT; ParameterTakesPrecedence: no; Sizeable: no
Type - Door Lining Properties - LiningDepth: 92 mm; LiningThickness: 40 mm; LiningOffset: -92 mm
Type - Door Panel Properties - Panel 1 - PanelDepth: 40 mm; PanelOperation: SWINGING; PanelWidth: 1; PanelPosition: MIDDLE
OverallHeight: 2090 mm; OverallWidth: 800 mm; Classification: 1.10 IfcDoorStyle (uks) (RKAS BIM + ARCHICAD Classification)
Pset_DoorCommon - Reference: SU-118-v; ThermalTransmittance: 0; IsExternal: no
AR_Uks - 001_Nimetus: Siseuks; 300_Tüüp: SU-118-v; 305_Ava_mõõt: 800x2,090; 310_Materjal: MUDELIS: väljast-PUIT- kuusk H; PUIT- kuusk H; seest-PUIT- kuusk H; PUIT- kuusk H; MÄRKUS: Kuumtsingitud teras, 1mm; 315_Avanemine: Pöördavanev - Vasak ; ARCHICAD tüüp: Side Hung; 320_Klaas: -; 325_Helipidavus: nõudeid ei esitata; 330_Tulekindlus: nõudeid ei esitata; 335_Välispiire: no; 340_Soojusläbivus: 0; 345_Päikesekiirgus_tegur: Nõudeid ei esitata; 350_Klaaspakett: -; 355_Pindala: 1.672 m2; 360_Ratastooliga: no; 365_Isesulguv: no; 370_Evakuatsiooniväljapääs: no; 375_Viimistlus_seest: Leng: PUIT- kuusk H; Ukseleht: PUIT- kuusk H; MÄRKUS: Kuumtsink; 376_Viimistlus_väljast: Leng: PUIT- kuusk H; Ukseleht: PUIT- kuusk H; MÄRKUS: -; 380_Lukustus: Mehaaniline lukk; 900_Tootja: -; 905_Mudel: -; 910_Tooteinfo: -; 915_Kasutus-ja_hooldusjuhend: -
AC_Pset_RenovationAndPhasing - Renovation Status: New

# IfcDoor: Door 25, Siseuks
In: 1. korrus
Type - OperationType: SINGLE_SWING_RIGHT; ParameterTakesPrecedence: no; Sizeable: no
Type - Door Lining Properties - LiningDepth: 92 mm; LiningThickness: 40 mm; LiningOffset: 0 mm
Type - Door Panel Properties - Panel 1 - PanelDepth: 40 mm; PanelOperation: SWINGING; PanelWidth: 1; PanelPosition: MIDDLE
OverallHeight: 2300 mm; OverallWidth: 1000 mm; Classification: 1.10 IfcDoorStyle (uks) (RKAS BIM + ARCHICAD Classification)
Pset_DoorCommon - Reference: SU-126-v; ThermalTransmittance: 0; IsExternal: no
AR_Uks - 001_Nimetus: Siseuks; 300_Tüüp: SU-126-v; 305_Ava_mõõt: 1,000x2,300; 310_Materjal: MUDELIS: väljast-PUIT- kuusk H; PUIT- kuusk H; seest-PUIT- kuusk H; PUIT- kuusk H; MÄRKUS: Täispuit ukseserv, fassaad spoonitud 8mm HDF, oksakuusk; 315_Avanemine: Pöördavanev - Vasak ; ARCHICAD tüüp: Side Hung; 320_Klaas: -; 325_Helipidavus: 30 dB; 330_Tulekindlus: nõudeid ei esitata; 335_Välispiire: no; 340_Soojusläbivus: 0; 345_Päikesekiirgus_tegur: Nõudeid ei esitata; 350_Klaaspakett: -; 355_Pindala: 2.3 m2; 360_Ratastooliga: no; 365_Isesulguv: no; 370_Evakuatsiooniväljapääs: no; 375_Viimistlus_seest: Leng: PUIT- kuusk H; Ukseleht: PUIT- kuusk H; MÄRKUS: Toonitud matt lakk; 376_Viimistlus_väljast: Leng: PUIT- kuusk H; Ukseleht: PUIT- kuusk H; MÄRKUS: -; 380_Lukustus: Liugvarrega sulgur, kaardilugeja, elektrilukk; 900_Tootja: -; 905_Mudel: -; 910_Tooteinfo: -; 915_Kasutus-ja_hooldusjuhend: -
AC_Pset_RenovationAndPhasing - Renovation Status: New

# IfcDoor: Door 25, Siseuks
In: 1. korrus
Type - OperationType: SINGLE_SWING_RIGHT; ParameterTakesPrecedence: no; Sizeable: no
Type - Door Lining Properties - LiningDepth: 92 mm; LiningThickness: 40 mm; LiningOffset: 128 mm
Type - Door Panel Properties - Panel 1 - PanelDepth: 40 mm; PanelOperation: SWINGING; PanelWidth: 1; PanelPosition: MIDDLE
OverallHeight: 2100 mm; OverallWidth: 1000 mm; Classification: 1.10 IfcDoorStyle (uks) (RKAS BIM + ARCHICAD Classification)
Pset_DoorCommon - Reference: SU-402-v; ThermalTransmittance: 0; IsExternal: no
AR_Uks - 001_Nimetus: Siseuks; 300_Tüüp: SU-402-v; 305_Ava_mõõt: 1,000x2,100; 310_Materjal: MUDELIS: väljast-PUIT- kuusk H; PUIT- kuusk H; seest-PUIT- kuusk H; PUIT- kuusk H; MÄRKUS: Kuumtsingitud teras, 1mm; 315_Avanemine: Pöördavanev - Vasak ; ARCHICAD tüüp: Side Hung; 320_Klaas: -; 325_Helipidavus: nõudeid ei esitata; 330_Tulekindlus: EI60; 335_Välispiire: no; 340_Soojusläbivus: 0; 345_Päikesekiirgus_tegur: Nõudeid ei esitata; 350_Klaaspakett: -; 355_Pindala: 2.1 m2; 360_Ratastooliga: no; 365_Isesulguv: no; 370_Evakuatsiooniväljapääs: no; 375_Viimistlus_seest: Leng: PUIT- kuusk H; Ukseleht: PUIT- kuusk H; MÄRKUS: Kuumtsink; 376_Viimistlus_väljast: Leng: PUIT- kuusk H; Ukseleht: PUIT- kuusk H; MÄRKUS: -; 380_Lukustus: Liugvarrega sulgur; 900_Tootja: -; 905_Mudel: -; 910_Tooteinfo: -; 915_Kasutus-ja_hooldusjuhend: -
AC_Pset_RenovationAndPhasing - Renovation Status: New

# IfcDoor: Door 25, Siseuks
In: 1. korrus
Type - OperationType: SINGLE_SWING_RIGHT; ParameterTakesPrecedence: no; Sizeable: no
Type - Door Lining Properties - LiningDepth: 92 mm; LiningThickness: 40 mm; LiningOffset: 165 mm
Type - Door Panel Properties - Panel 1 - PanelDepth: 40 mm; PanelOperation: SWINGING; PanelWidth: 1; PanelPosition: MIDDLE
OverallHeight: 2100 mm; OverallWidth: 1000 mm; Classification: 1.10 IfcDoorStyle (uks) (RKAS BIM + ARCHICAD Classification)
Pset_DoorCommon - Reference: SU-408-v; ThermalTransmittance: 0; IsExternal: no
AR_Uks - 001_Nimetus: Siseuks; 300_Tüüp: SU-408-v; 305_Ava_mõõt: 1,000x2,100; 310_Materjal: MUDELIS: väljast-PUIT- kuusk H; PUIT- kuusk H; seest-PUIT- kuusk H; PUIT- kuusk H; MÄRKUS: Täispuit ukseserv, fassaad värvitud 8mm HDF, oksakuusk; 315_Avanemine: Pöördavanev - Vasak ; ARCHICAD tüüp: Side Hung; 320_Klaas: -; 325_Helipidavus: nõudeid ei esitata; 330_Tulekindlus: EI45; 335_Välispiire: no; 340_Soojusläbivus: 0; 345_Päikesekiirgus_tegur: Nõudeid ei esitata; 350_Klaaspakett: -; 355_Pindala: 2.1 m2; 360_Ratastooliga: no; 365_Isesulguv: no; 370_Evakuatsiooniväljapääs: no; 375_Viimistlus_seest: Leng: PUIT- kuusk H; Ukseleht: PUIT- kuusk H; MÄRKUS: Toonitud matt lakk; 376_Viimistlus_väljast: Leng: PUIT- kuusk H; Ukseleht: PUIT- kuusk H; MÄRKUS: -; 380_Lukustus: Liugvarrega sulgur, kaardilugeja, elektrilukk; 900_Tootja: -; 905_Mudel: -; 910_Tooteinfo: -; 915_Kasutus-ja_hooldusjuhend: -
AC_Pset_RenovationAndPhasing - Renovation Status: New

# IfcDoor: Door 25, Siseuks
In: 3. korrus
Type - OperationType: SINGLE_SWING_RIGHT; ParameterTakesPrecedence: no; Sizeable: no
Type - Door Lining Properties - LiningDepth: 92 mm; LiningThickness: 40 mm; LiningOffset: 47 mm
Type - Door Panel Properties - Panel 1 - PanelDepth: 40 mm; PanelOperation: SWINGING; PanelWidth: 1; PanelPosition: MIDDLE
OverallHeight: 2100 mm; OverallWidth: 1000 mm; Classification: 1.10 IfcDoorStyle (uks) (RKAS BIM + ARCHICAD Classification)
Pset_DoorCommon - Reference: SU-402-v; ThermalTransmittance: 0; IsExternal: no
AR_Uks - 001_Nimetus: Siseuks; 300_Tüüp: SU-402-v; 305_Ava_mõõt: 1,000x2,100; 310_Materjal: MUDELIS: väljast-PUIT- kuusk H; PUIT- kuusk H; seest-PUIT- kuusk H; PUIT- kuusk H; MÄRKUS: Kuumtsingitud teras, 1mm; 315_Avanemine: Pöördavanev - Vasak ; ARCHICAD tüüp: Side Hung; 320_Klaas: -; 325_Helipidavus: nõudeid ei esitata; 330_Tulekindlus: EI45; 335_Välispiire: no; 340_Soojusläbivus: 0; 345_Päikesekiirgus_tegur: Nõudeid ei esitata; 350_Klaaspakett: -; 355_Pindala: 2.1 m2; 360_Ratastooliga: no; 365_Isesulguv: no; 370_Evakuatsiooniväljapääs: no; 375_Viimistlus_seest: Leng: PUIT- kuusk H; Ukseleht: PUIT- kuusk H; MÄRKUS: Kuumtsink; 376_Viimistlus_väljast: Leng: PUIT- kuusk H; Ukseleht: PUIT- kuusk H; MÄRKUS: -; 380_Lukustus: Liugvarrega sulgur; 900_Tootja: -; 905_Mudel: -; 910_Tooteinfo: -; 915_Kasutus-ja_hooldusjuhend: -
AC_Pset_RenovationAndPhasing - Renovation Status: New

# IfcDoor: Door 25, Siseuks
In: 1. korrus
Type - OperationType: SINGLE_SWING_RIGHT; ParameterTakesPrecedence: no; Sizeable: no
Type - Door Lining Properties - LiningDepth: 92 mm; LiningThickness: 50 mm; LiningOffset: -112 mm
Type - Door Panel Properties - Panel 1 - PanelDepth: 50 mm; PanelOperation: SWINGING; PanelWidth: 1; PanelPosition: MIDDLE
OverallHeight: 2100 mm; OverallWidth: 800 mm; Classification: 1.10 IfcDoorStyle (uks) (RKAS BIM + ARCHICAD Classification)
Pset_DoorCommon - Reference: SU-418-v; ThermalTransmittance: 0; IsExternal: no
AR_Uks - 001_Nimetus: Siseuks; 300_Tüüp: SU-418-v; 305_Ava_mõõt: 800x2,100; 310_Materjal: MUDELIS: väljast-TOON- RAL 9006 alumiinium hall; TOON- RAL 9006 alumiinium hall; seest-TOON- RAL 9006 alumiinium hall; TOON- RAL 9006 alumiinium hall; MÄRKUS: Kuumtsingitud teras, 1mm; 315_Avanemine: Pöördavanev - Vasak ; ARCHICAD tüüp: Side Hung; 320_Klaas: -; 325_Helipidavus: 35 dB; 330_Tulekindlus: EI30; 335_Välispiire: no; 340_Soojusläbivus: 0; 345_Päikesekiirgus_tegur: Nõudeid ei esitata; 350_Klaaspakett: -; 355_Pindala: 1.68 m2; 360_Ratastooliga: no; 365_Isesulguv: no; 370_Evakuatsiooniväljapääs: no; 375_Viimistlus_seest: Leng: TOON- RAL 9006 alumiinium hall; Ukseleht: TOON- RAL 9006 alumiinium hall; MÄRKUS: Kuumtsink; 376_Viimistlus_väljast: Leng: TOON- RAL 9006 alumiinium hall; Ukseleht: TOON- RAL 9006 alumiinium hall; MÄRKUS: -; 380_Lukustus: Liugvarrega sulgur, kaardilugeja, elektrilukk; 900_Tootja: -; 905_Mudel: -; 910_Tooteinfo: -; 915_Kasutus-ja_hooldusjuhend: -
AC_Pset_RenovationAndPhasing - Renovation Status: New

# IfcDoor: Door 25 (3)
In: 1. korrus
Type - OperationType: SINGLE_SWING_RIGHT; ParameterTakesPrecedence: no; Sizeable: no
Type - Door Lining Properties - LiningDepth: 92 mm; LiningThickness: 50 mm; LiningOffset: -142 mm
Type - Door Panel Properties - Panel 1 - PanelDepth: 50 mm; PanelOperation: SWINGING; PanelWidth: 1; PanelPosition: MIDDLE
OverallHeight: 2300 mm; OverallWidth: 1000 mm; Classification: 1.10 IfcDoorStyle (uks) (RKAS BIM + ARCHICAD Classification)
Pset_DoorCommon - Reference: SU-108-p; ThermalTransmittance: 0; IsExternal: no
AR_Uks - 001_Nimetus: Siseuks; 300_Tüüp: SU-108-p; 305_Ava_mõõt: 1,000x2,300; 310_Materjal: MUDELIS: väljast-TOON- RAL 9006 alumiinium hall; TOON- RAL 9006 alumiinium hall; seest-TOON- RAL 9006 alumiinium hall; TOON- RAL 9006 alumiinium hall; MÄRKUS: Täispuit ukseserv, fassaad spoonitud 8mm HDF, oksakuusk; 315_Avanemine: Pöördavanev - Parem ; ARCHICAD tüüp: Side Hung; 320_Klaas: -; 325_Helipidavus: 25 dB; 330_Tulekindlus: nõudeid ei esitata; 335_Välispiire: no; 340_Soojusläbivus: 0; 345_Päikesekiirgus_tegur: Nõudeid ei esitata; 350_Klaaspakett: -; 355_Pindala: 2.3 m2; 360_Ratastooliga: no; 365_Isesulguv: no; 370_Evakuatsiooniväljapääs: no; 375_Viimistlus_seest: Leng: TOON- RAL 9006 alumiinium hall; Ukseleht: TOON- RAL 9006 alumiinium hall; MÄRKUS: Toonitud matt lakk; 376_Viimistlus_väljast: Leng: TOON- RAL 9006 alumiinium hall; Ukseleht: TOON- RAL 9006 alumiinium hall; MÄRKUS: -; 380_Lukustus: Liugvarrega sulgur, mehaaniline lukk; 900_Tootja: -; 905_Mudel: -; 910_Tooteinfo: -; 915_Kasutus-ja_hooldusjuhend: -
AC_Pset_RenovationAndPhasing - Renovation Status: New

# IfcDoor: Door 25, Siseuks
In: 1. korrus
Type - OperationType: SINGLE_SWING_RIGHT; ParameterTakesPrecedence: no; Sizeable: no
Type - Door Lining Properties - LiningDepth: 92 mm; LiningThickness: 50 mm; LiningOffset: -170 mm
Type - Door Panel Properties - Panel 1 - PanelDepth: 50 mm; PanelOperation: SWINGING; PanelWidth: 1; PanelPosition: MIDDLE
OverallHeight: 2300 mm; OverallWidth: 1000 mm; Classification: 1.10 IfcDoorStyle (uks) (RKAS BIM + ARCHICAD Classification)
Pset_DoorCommon - Reference: SU-108-p; ThermalTransmittance: 0; IsExternal: no
AR_Uks - 001_Nimetus: Siseuks; 300_Tüüp: SU-108-p; 305_Ava_mõõt: 1,000x2,300; 310_Materjal: MUDELIS: väljast-TOON- RAL 9006 alumiinium hall; TOON- RAL 9006 alumiinium hall; seest-TOON- RAL 9006 alumiinium hall; TOON- RAL 9006 alumiinium hall; MÄRKUS: Täispuit ukseserv, fassaad spoonitud 8mm HDF, oksakuusk; 315_Avanemine: Pöördavanev - Parem ; ARCHICAD tüüp: Side Hung; 320_Klaas: -; 325_Helipidavus: 25 dB; 330_Tulekindlus: nõudeid ei esitata; 335_Välispiire: no; 340_Soojusläbivus: 0; 345_Päikesekiirgus_tegur: Nõudeid ei esitata; 350_Klaaspakett: -; 355_Pindala: 2.3 m2; 360_Ratastooliga: no; 365_Isesulguv: no; 370_Evakuatsiooniväljapääs: no; 375_Viimistlus_seest: Leng: TOON- RAL 9006 alumiinium hall; Ukseleht: TOON- RAL 9006 alumiinium hall; MÄRKUS: Toonitud matt lakk; 376_Viimistlus_väljast: Leng: TOON- RAL 9006 alumiinium hall; Ukseleht: TOON- RAL 9006 alumiinium hall; MÄRKUS: -; 380_Lukustus: Liugvarrega sulgur, mehaaniline lukk; 900_Tootja: -; 905_Mudel: -; 910_Tooteinfo: -; 915_Kasutus-ja_hooldusjuhend: -
AC_Pset_RenovationAndPhasing - Renovation Status: New

# IfcDoor: Door 25, Siseuks
In: 1. korrus
Type - OperationType: SINGLE_SWING_RIGHT; ParameterTakesPrecedence: no; Sizeable: no
Type - Door Lining Properties - LiningDepth: 92 mm; LiningThickness: 50 mm; LiningOffset: -82 mm
Type - Door Panel Properties - Panel 1 - PanelDepth: 50 mm; PanelOperation: SWINGING; PanelWidth: 1; PanelPosition: MIDDLE
OverallHeight: 2300 mm; OverallWidth: 1000 mm; Classification: 1.10 IfcDoorStyle (uks) (RKAS BIM + ARCHICAD Classification)
Pset_DoorCommon - Reference: SU-108-p; ThermalTransmittance: 0; IsExternal: no
AR_Uks - 001_Nimetus: Siseuks; 300_Tüüp: SU-108-p; 305_Ava_mõõt: 1,000x2,300; 310_Materjal: MUDELIS: väljast-TOON- RAL 9006 alumiinium hall; TOON- RAL 9006 alumiinium hall; seest-TOON- RAL 9006 alumiinium hall; TOON- RAL 9006 alumiinium hall; MÄRKUS: Täispuit ukseserv, fassaad spoonitud 8mm HDF, oksakuusk; 315_Avanemine: Pöördavanev - Parem ; ARCHICAD tüüp: Side Hung; 320_Klaas: -; 325_Helipidavus: 25 dB; 330_Tulekindlus: nõudeid ei esitata; 335_Välispiire: no; 340_Soojusläbivus: 0; 345_Päikesekiirgus_tegur: Nõudeid ei esitata; 350_Klaaspakett: -; 355_Pindala: 2.3 m2; 360_Ratastooliga: no; 365_Isesulguv: no; 370_Evakuatsiooniväljapääs: no; 375_Viimistlus_seest: Leng: TOON- RAL 9006 alumiinium hall; Ukseleht: TOON- RAL 9006 alumiinium hall; MÄRKUS: Toonitud matt lakk; 376_Viimistlus_väljast: Leng: TOON- RAL 9006 alumiinium hall; Ukseleht: TOON- RAL 9006 alumiinium hall; MÄRKUS: -; 380_Lukustus: Liugvarrega sulgur, mehaaniline lukk; 900_Tootja: -; 905_Mudel: -; 910_Tooteinfo: -; 915_Kasutus-ja_hooldusjuhend: -
AC_Pset_RenovationAndPhasing - Renovation Status: New

# IfcDoor: Door 25 (23)
Type - OperationType: SINGLE_SWING_RIGHT; ParameterTakesPrecedence: no; Sizeable: no
Type - Door Lining Properties - LiningDepth: 92 mm; LiningThickness: 50 mm; LiningOffset: -92 mm
Type - Door Panel Properties - Panel 1 - PanelDepth: 50 mm; PanelOperation: SWINGING; PanelWidth: 1; PanelPosition: MIDDLE
Classification: 1.10 IfcDoorStyle (uks) (RKAS BIM + ARCHICAD Classification)
Pset_DoorCommon - ThermalTransmittance: 0; IsExternal: no
AR_Uks - 001_Nimetus: Siseuks; 315_Avanemine: Pöördavanev - Vasak ; ARCHICAD tüüp: Side Hung; 335_Välispiire: no; 340_Soojusläbivus: 0; 345_Päikesekiirgus_tegur: Nõudeid ei esitata; 350_Klaaspakett: -; 365_Isesulguv: no; 370_Evakuatsiooniväljapääs: no; 376_Viimistlus_väljast: Leng: TOON- RAL 9006 alumiinium hall; Ukseleht: TOON- RAL 9006 alumiinium hall; MÄRKUS: -; 900_Tootja: -; 905_Mudel: -; 910_Tooteinfo: -; 915_Kasutus-ja_hooldusjuhend: -
AC_Pset_RenovationAndPhasing - Renovation Status: New
Name | In | OverallHeight (mm) | OverallWidth (mm) | Reference = 300_Tüüp | 305_Ava_mõõt | 310_Materjal | 320_Klaas | 325_Helipidavus | 330_Tulekindlus | 355_Pindala (m2) | 360_Ratastooliga | 375_Viimistlus_seest | 380_Lukustus
2 x Siseuks | 1. korrus | 2300 | 800 | SU-125-v | 800x2,300 | MUDELIS: väljast-TOON- RAL 9006 alumiinium hall; TOON- RAL 9006 alumiinium hall; seest-TOON- RAL 9006 alumiinium hall; TOON- RAL 9006 alumiinium hall; MÄRKUS: Täispuit ukseserv, fassaad spoonitud 8mm HDF, oksakuusk | - | 25 dB | nõudeid ei esitata | 1.84 | no | Leng: TOON- RAL 9006 alumiinium hall; Ukseleht: TOON- RAL 9006 alumiinium hall; MÄRKUS: Toonitud matt lakk | Liugvarrega sulgur, väljas link, sees väändenupp
Siseuks | 1. korrus | 2300 | 1000 | SU-146-v | 1,000x2,300 | MUDELIS: väljast-TOON- RAL 9006 alumiinium hall; TOON- RAL 9006 alumiinium hall; seest-TOON- RAL 9006 alumiinium hall; TOON- RAL 9006 alumiinium hall; MÄRKUS: Täispuit ukseserv, fassaad spoonitud 8mm HDF, oksakuusk | - | nõudeid ei esitata | nõudeid ei esitata | 2.3 | no | Leng: TOON- RAL 9006 alumiinium hall; Ukseleht: TOON- RAL 9006 alumiinium hall; MÄRKUS: Toonitud matt lakk | Liugvarrega sulgur, kaardilugeja, elektrilukk
Siseuks | 1. korrus | 2300 | 800 | SU-150-v | 800x2,300 | MUDELIS: väljast-TOON- RAL 9006 alumiinium hall; TOON- RAL 9006 alumiinium hall; seest-TOON- RAL 9006 alumiinium hall; TOON- RAL 9006 alumiinium hall; MÄRKUS: Täispuit ukseserv, fassaad spoonitud 8mm HDF, oksakuusk | - | nõudeid ei esitata | nõudeid ei esitata | 1.84 | no | Leng: TOON- RAL 9006 alumiinium hall; Ukseleht: TOON- RAL 9006 alumiinium hall; MÄRKUS: Toonitud matt lakk | ilma lingita, sõrmekonks, mehaaniline lukk
Siseuks | 1. korrus | 2300 | 1000 | SU-106-v | 1,000x2,300 | MUDELIS: väljast-TOON- RAL 9006 alumiinium hall; TOON- RAL 9006 alumiinium hall; seest-TOON- RAL 9006 alumiinium hall; TOON- RAL 9006 alumiinium hall; MÄRKUS: Kuumtsingitud teras, 1mm | - | 25 dB | nõudeid ei esitata | 2.3 | no | Leng: TOON- RAL 9006 alumiinium hall; Ukseleht: TOON- RAL 9006 alumiinium hall; MÄRKUS: Pulbervärv, värvi toon vastavalt sanruumi tarnitavale keraamilisele plaadile. | Väljas link, sees väändenupp ja reeling ukse sulgemiseks
Siseuks | 1. korrus | 2100 | 1000 | SU-149-v | 1,000x2,100 | MUDELIS: väljast-TOON- RAL 9006 alumiinium hall; TOON- RAL 9006 alumiinium hall; seest-TOON- RAL 9006 alumiinium hall; TOON- RAL 9006 alumiinium hall; MÄRKUS: Kuumtsingitud teras, 1mm | - | nõudeid ei esitata | nõudeid ei esitata | 2.1 | yes | Leng: TOON- RAL 9006 alumiinium hall; Ukseleht: TOON- RAL 9006 alumiinium hall; MÄRKUS: Pulbervärv | Liugvarrega sulgur, väljas link, sees väändenupp
Siseuks | 1. korrus | 2300 | 1000 | SU-131-v | 1,000x2,300 | MUDELIS: väljast-TOON- RAL 9006 alumiinium hall; TOON- RAL 9006 alumiinium hall; seest-TOON- RAL 9006 alumiinium hall; TOON- RAL 9006 alumiinium hall; MÄRKUS: Täispuit ukseserv, fassaad spoonitud 8mm HDF, oksakuusk | - | nõudeid ei esitata | nõudeid ei esitata | 2.3 | no | Leng: TOON- RAL 9006 alumiinium hall; Ukseleht: TOON- RAL 9006 alumiinium hall; MÄRKUS: Toonitud matt lakk | ilma lingita, sõrmekonks, mehaaniline lukk
6 x Siseuks | 1. korrus | 2300 | 800 | SU-107-v | 800x2,300 | MUDELIS: väljast-TOON- RAL 9006 alumiinium hall; TOON- RAL 9006 alumiinium hall; seest-TOON- RAL 9006 alumiinium hall; TOON- RAL 9006 alumiinium hall; MÄRKUS: Kuumtsingitud teras, 1mm | - | 25 dB | nõudeid ei esitata | 1.84 | no | Leng: TOON- RAL 9006 alumiinium hall; Ukseleht: TOON- RAL 9006 alumiinium hall; MÄRKUS: Pulbervärv, värvi toon vastavalt sanruumi tarnitavale keraamilisele plaadile. | Liugvarrega sulgur, väljas link, sees väändenupp
Siseuks | 2. korrus | 2300 | 1000 | SU-415-v | 1,000x2,300 | MUDELIS: väljast-TOON- RAL 9006 alumiinium hall; TOON- RAL 9006 alumiinium hall; seest-TOON- RAL 9006 alumiinium hall; TOON- RAL 9006 alumiinium hall; MÄRKUS: Täispuit ukseserv, fassaad spoonitud 8mm HDF, oksakuusk | - | nõudeid ei esitata | EI30 | 2.3 | no | Leng: TOON- RAL 9006 alumiinium hall; Ukseleht: TOON- RAL 9006 alumiinium hall; MÄRKUS: Toonitud matt lakk | Mehaaniline lukk
3 x Siseuks | 2. korrus | 2300 | 800 | SU-107-v | 800x2,300 | MUDELIS: väljast-TOON- RAL 9006 alumiinium hall; TOON- RAL 9006 alumiinium hall; seest-TOON- RAL 9006 alumiinium hall; TOON- RAL 9006 alumiinium hall; MÄRKUS: Kuumtsingitud teras, 1mm | - | 25 dB | nõudeid ei esitata | 1.84 | no | Leng: TOON- RAL 9006 alumiinium hall; Ukseleht: TOON- RAL 9006 alumiinium hall; MÄRKUS: Pulbervärv, värvi toon vastavalt sanruumi tarnitavale keraamilisele plaadile. | Liugvarrega sulgur, väljas link, sees väändenupp
Siseuks | 2. korrus | 2300 | 800 | SU-150-v | 800x2,300 | MUDELIS: väljast-TOON- RAL 9006 alumiinium hall; TOON- RAL 9006 alumiinium hall; seest-TOON- RAL 9006 alumiinium hall; TOON- RAL 9006 alumiinium hall; MÄRKUS: Täispuit ukseserv, fassaad spoonitud 8mm HDF, oksakuusk | - | nõudeid ei esitata | nõudeid ei esitata | 1.84 | no | Leng: TOON- RAL 9006 alumiinium hall; Ukseleht: TOON- RAL 9006 alumiinium hall; MÄRKUS: Toonitud matt lakk | ilma lingita, sõrmekonks, mehaaniline lukk
Siseuks | 3. korrus | 2300 | 1000 | SU-141-v | 1,000x2,300 | MUDELIS: väljast-TOON- RAL 9006 alumiinium hall; TOON- RAL 9006 alumiinium hall; seest-TOON- RAL 9006 alumiinium hall; TOON- RAL 9006 alumiinium hall; MÄRKUS: Täispuit ukseserv, fassaad spoonitud 8mm HDF, oksakuusk | Kirgas, klaas | 30 dB | nõudeid ei esitata | 2.3 | no | Leng: TOON- RAL 9006 alumiinium hall; Ukseleht: TOON- RAL 9006 alumiinium hall; MÄRKUS: Toonitud matt lakk | Liugvarrega sulgur, kaardilugeja, elektrilukk
3 x Siseuks | 3. korrus | 2300 | 800 | SU-107-v | 800x2,300 | MUDELIS: väljast-TOON- RAL 9006 alumiinium hall; TOON- RAL 9006 alumiinium hall; seest-TOON- RAL 9006 alumiinium hall; TOON- RAL 9006 alumiinium hall; MÄRKUS: Kuumtsingitud teras, 1mm | - | 25 dB | nõudeid ei esitata | 1.84 | no | Leng: TOON- RAL 9006 alumiinium hall; Ukseleht: TOON- RAL 9006 alumiinium hall; MÄRKUS: Pulbervärv, värvi toon vastavalt sanruumi tarnitavale keraamilisele plaadile. | Liugvarrega sulgur, väljas link, sees väändenupp
Siseuks | 3. korrus | 2300 | 800 | SU-145-v | 800x2,300 | MUDELIS: väljast-TOON- RAL 9006 alumiinium hall; TOON- RAL 9006 alumiinium hall; seest-TOON- RAL 9006 alumiinium hall; TOON- RAL 9006 alumiinium hall; MÄRKUS: Kuumtsingitud teras, 1mm | - | - | nõudeid ei esitata | 1.84 | no | Leng: TOON- RAL 9006 alumiinium hall; Ukseleht: TOON- RAL 9006 alumiinium hall; MÄRKUS: Pulbervärv | ilma lingita, sõrmekonks, mehaaniline lukk

# IfcDoor: Door 25, Siseuks
In: 3. korrus
Type - OperationType: SINGLE_SWING_RIGHT; ParameterTakesPrecedence: no; Sizeable: no
Type - Door Lining Properties - LiningDepth: 92 mm; LiningThickness: 50 mm; LiningOffset: 0 mm
Type - Door Panel Properties - Panel 1 - PanelDepth: 50 mm; PanelOperation: SWINGING; PanelWidth: 1; PanelPosition: MIDDLE
OverallHeight: 2300 mm; OverallWidth: 1000 mm; Classification: 1.10 IfcDoorStyle (uks) (RKAS BIM + ARCHICAD Classification)
Pset_DoorCommon - Reference: SU-141-v; ThermalTransmittance: 0; GlazingAreaFraction: 1.72; IsExternal: no
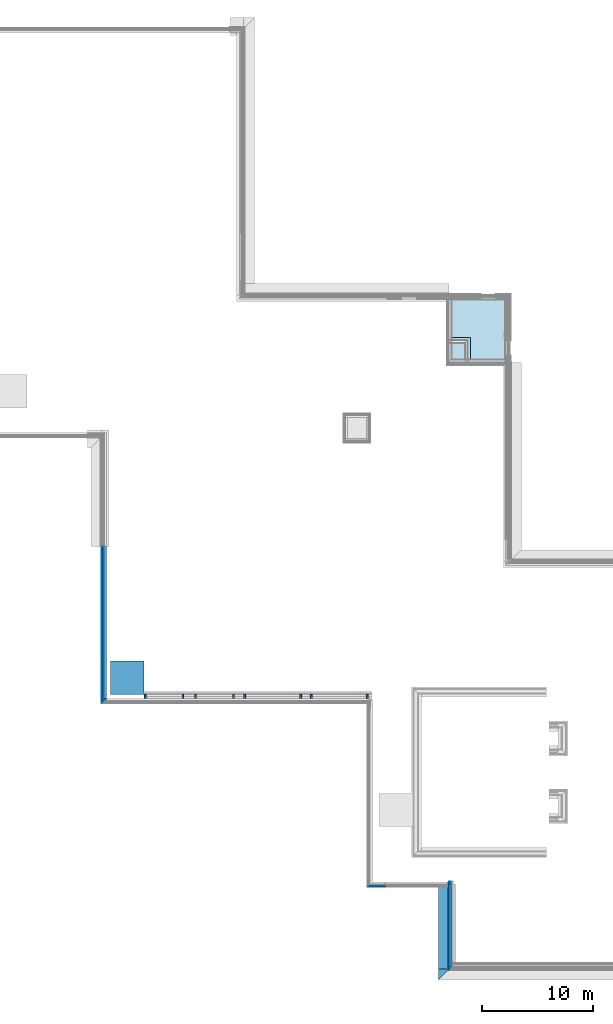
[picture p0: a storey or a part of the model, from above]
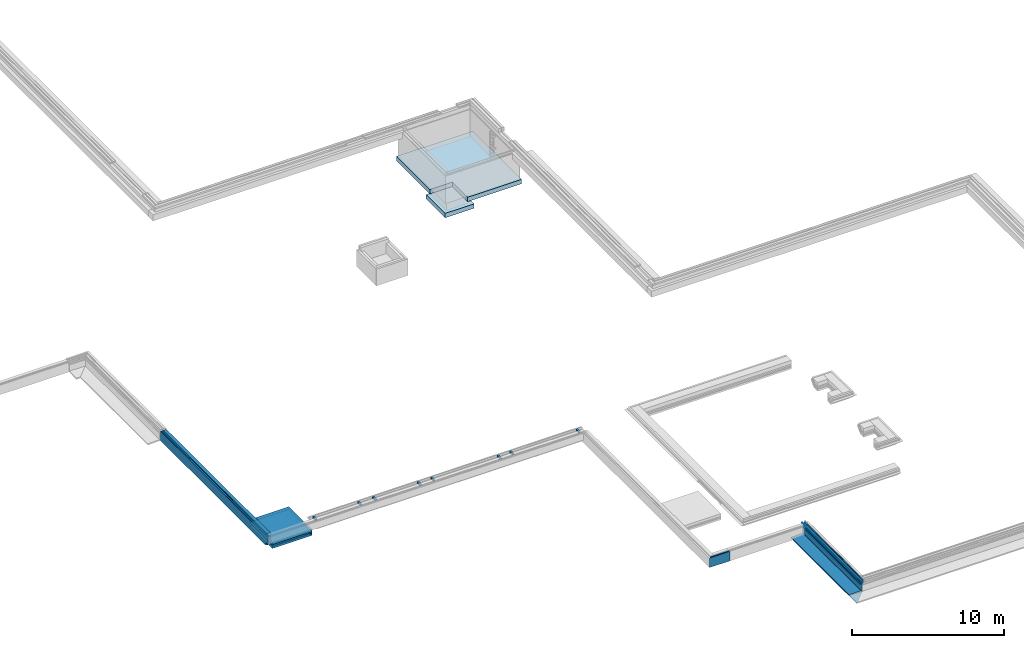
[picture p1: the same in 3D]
Properties of the parts of a building model (IFC2X3), part 5 of 14

# IfcDoor: Door 25, Siseuks
AR_Uks - 001_Nimetus: Siseuks; 300_Tüüp: SU-141-v; 305_Ava_mõõt: 1,000x2,300; 310_Materjal: MUDELIS: väljast-TOON- RAL 9006 alumiinium hall; TOON- RAL 9006 alumiinium hall; seest-TOON- RAL 9006 alumiinium hall; TOON- RAL 9006 alumiinium hall; MÄRKUS: Täispuit ukseserv, fassaad spoonitud 8mm HDF, oksakuusk; 315_Avanemine: Pöördavanev - Vasak ; ARCHICAD tüüp: Side Hung; 320_Klaas: Kirgas, klaas; 325_Helipidavus: 30 dB; 330_Tulekindlus: nõudeid ei esitata; 335_Välispiire: no; 340_Soojusläbivus: 0; 345_Päikesekiirgus_tegur: Nõudeid ei esitata; 350_Klaaspakett: -; 355_Pindala: 2.3 m2; 360_Ratastooliga: no; 365_Isesulguv: no; 370_Evakuatsiooniväljapääs: no; 375_Viimistlus_seest: Leng: TOON- RAL 9006 alumiinium hall; Ukseleht: TOON- RAL 9006 alumiinium hall; MÄRKUS: Toonitud matt lakk; 376_Viimistlus_väljast: Leng: TOON- RAL 9006 alumiinium hall; Ukseleht: TOON- RAL 9006 alumiinium hall; MÄRKUS: -; 380_Lukustus: Liugvarrega sulgur, kaardilugeja, elektrilukk; 900_Tootja: -; 905_Mudel: -; 910_Tooteinfo: -; 915_Kasutus-ja_hooldusjuhend: -
AC_Pset_RenovationAndPhasing - Renovation Status: New

# IfcDoor: Door 25 (4)
In: 1. korrus
Type - OperationType: SINGLE_SWING_RIGHT; ParameterTakesPrecedence: no; Sizeable: no
Type - Door Lining Properties - LiningDepth: 92 mm; LiningThickness: 50 mm; LiningOffset: 108 mm
Type - Door Panel Properties - Panel 1 - PanelDepth: 50 mm; PanelOperation: SWINGING; PanelWidth: 1; PanelPosition: MIDDLE
OverallHeight: 2100 mm; OverallWidth: 1000 mm; Classification: 1.10 IfcDoorStyle (uks) (RKAS BIM + ARCHICAD Classification)
Pset_DoorCommon - ThermalTransmittance: 0; IsExternal: no
AR_Uks - 001_Nimetus: Siseuks; 305_Ava_mõõt: 1,000x2,100; 315_Avanemine: Pöördavanev - Vasak ; ARCHICAD tüüp: Side Hung; 320_Klaas: -; 325_Helipidavus: nõudeid ei esitata; 330_Tulekindlus: nõudeid ei esitata; 335_Välispiire: no; 340_Soojusläbivus: 0; 345_Päikesekiirgus_tegur: Nõudeid ei esitata; 350_Klaaspakett: -; 355_Pindala: 2.1 m2; 365_Isesulguv: no; 370_Evakuatsiooniväljapääs: no; 376_Viimistlus_väljast: Leng: TOON- RAL 9006 alumiinium hall; Ukseleht: TOON- RAL 9006 alumiinium hall; MÄRKUS: -; 900_Tootja: -; 905_Mudel: -; 910_Tooteinfo: -; 915_Kasutus-ja_hooldusjuhend: -
AC_Pset_RenovationAndPhasing - Renovation Status: New
Name | Reference = 300_Tüüp | 310_Materjal | 360_Ratastooliga | 375_Viimistlus_seest | 380_Lukustus
3 x Siseuks | SU-149-v | MUDELIS: väljast-TOON- RAL 9006 alumiinium hall; TOON- RAL 9006 alumiinium hall; seest-TOON- RAL 9006 alumiinium hall; TOON- RAL 9006 alumiinium hall; MÄRKUS: Kuumtsingitud teras, 1mm | yes | Leng: TOON- RAL 9006 alumiinium hall; Ukseleht: TOON- RAL 9006 alumiinium hall; MÄRKUS: Pulbervärv | Liugvarrega sulgur, väljas link, sees väändenupp
Siseuks | SU-147-v | MUDELIS: väljast-TOON- RAL 9006 alumiinium hall; TOON- RAL 9006 alumiinium hall; seest-TOON- RAL 9006 alumiinium hall; TOON- RAL 9006 alumiinium hall; MÄRKUS: Täispuit ukseserv, fassaad spoonitud 8mm HDF, oksakuusk | no | Leng: TOON- RAL 9006 alumiinium hall; Ukseleht: TOON- RAL 9006 alumiinium hall; MÄRKUS: Toonitud matt lakk | Liugvarrega sulgur, kaardilugeja, elektrilukk | Pset_DoorCommon - GlazingAreaFraction: 1.56

# IfcDoor: Door 25, Siseuks
In: 3. korrus
Type - OperationType: SINGLE_SWING_RIGHT; ParameterTakesPrecedence: no; Sizeable: no
Type - Door Lining Properties - LiningDepth: 92 mm; LiningThickness: 50 mm; LiningOffset: 128 mm
Type - Door Panel Properties - Panel 1 - PanelDepth: 50 mm; PanelOperation: SWINGING; PanelWidth: 1; PanelPosition: MIDDLE
OverallHeight: 2300 mm; OverallWidth: 1000 mm; Classification: 1.10 IfcDoorStyle (uks) (RKAS BIM + ARCHICAD Classification)
Pset_DoorCommon - Reference: SU-141-v; ThermalTransmittance: 0; GlazingAreaFraction: 1.72; IsExternal: no
AR_Uks - 001_Nimetus: Siseuks; 300_Tüüp: SU-141-v; 305_Ava_mõõt: 1,000x2,300; 310_Materjal: MUDELIS: väljast-TOON- RAL 9006 alumiinium hall; TOON- RAL 9006 alumiinium hall; seest-TOON- RAL 9006 alumiinium hall; TOON- RAL 9006 alumiinium hall; MÄRKUS: Täispuit ukseserv, fassaad spoonitud 8mm HDF, oksakuusk; 315_Avanemine: Pöördavanev - Vasak ; ARCHICAD tüüp: Side Hung; 320_Klaas: Kirgas, klaas; 325_Helipidavus: 30 dB; 330_Tulekindlus: nõudeid ei esitata; 335_Välispiire: no; 340_Soojusläbivus: 0; 345_Päikesekiirgus_tegur: Nõudeid ei esitata; 350_Klaaspakett: -; 355_Pindala: 2.3 m2; 360_Ratastooliga: no; 365_Isesulguv: no; 370_Evakuatsiooniväljapääs: no; 375_Viimistlus_seest: Leng: TOON- RAL 9006 alumiinium hall; Ukseleht: TOON- RAL 9006 alumiinium hall; MÄRKUS: Toonitud matt lakk; 376_Viimistlus_väljast: Leng: TOON- RAL 9006 alumiinium hall; Ukseleht: TOON- RAL 9006 alumiinium hall; MÄRKUS: -; 380_Lukustus: Liugvarrega sulgur, kaardilugeja, elektrilukk; 900_Tootja: -; 905_Mudel: -; 910_Tooteinfo: -; 915_Kasutus-ja_hooldusjuhend: -
AC_Pset_RenovationAndPhasing - Renovation Status: New

# IfcDoor: Door 25, Siseuks
In: 1. korrus
Type - OperationType: SINGLE_SWING_RIGHT; ParameterTakesPrecedence: no; Sizeable: no
Type - Door Lining Properties - LiningDepth: 92 mm; LiningThickness: 50 mm; LiningOffset: 148 mm
Type - Door Panel Properties - Panel 1 - PanelDepth: 50 mm; PanelOperation: SWINGING; PanelWidth: 1; PanelPosition: MIDDLE
OverallHeight: 2300 mm; OverallWidth: 1000 mm; Classification: 1.10 IfcDoorStyle (uks) (RKAS BIM + ARCHICAD Classification)
Pset_DoorCommon - Reference: SU-122-v; ThermalTransmittance: 0; IsExternal: no
AR_Uks - 001_Nimetus: Siseuks; 300_Tüüp: SU-122-v; 305_Ava_mõõt: 1,000x2,300; 310_Materjal: MUDELIS: väljast-TOON- RAL 9006 alumiinium hall; TOON- RAL 9006 alumiinium hall; seest-TOON- RAL 9006 alumiinium hall; TOON- RAL 9006 alumiinium hall; MÄRKUS: Täispuit ukseserv, fassaad spoonitud 8mm HDF, oksakuusk; 315_Avanemine: Pöördavanev - Vasak ; ARCHICAD tüüp: Side Hung; 320_Klaas: -; 325_Helipidavus: 25 dB; 330_Tulekindlus: nõudeid ei esitata; 335_Välispiire: no; 340_Soojusläbivus: 0; 345_Päikesekiirgus_tegur: Nõudeid ei esitata; 350_Klaaspakett: -; 355_Pindala: 2.3 m2; 360_Ratastooliga: no; 365_Isesulguv: no; 370_Evakuatsiooniväljapääs: no; 375_Viimistlus_seest: Leng: TOON- RAL 9006 alumiinium hall; Ukseleht: TOON- RAL 9006 alumiinium hall; MÄRKUS: Toonitud matt lakk; 376_Viimistlus_väljast: Leng: TOON- RAL 9006 alumiinium hall; Ukseleht: TOON- RAL 9006 alumiinium hall; MÄRKUS: -; 380_Lukustus: Liugvarrega sulgur, kaardilugeja, elektrilukk; 900_Tootja: -; 905_Mudel: -; 910_Tooteinfo: -; 915_Kasutus-ja_hooldusjuhend: -
AC_Pset_RenovationAndPhasing - Renovation Status: New

# IfcDoor: Door 25, Siseuks
In: 2. korrus
Type - OperationType: SINGLE_SWING_RIGHT; ParameterTakesPrecedence: no; Sizeable: no
Type - Door Lining Properties - LiningDepth: 92 mm; LiningThickness: 50 mm; LiningOffset: 208 mm
Type - Door Panel Properties - Panel 1 - PanelDepth: 50 mm; PanelOperation: SWINGING; PanelWidth: 1; PanelPosition: MIDDLE
OverallHeight: 2300 mm; OverallWidth: 900 mm; Classification: 1.10 IfcDoorStyle (uks) (RKAS BIM + ARCHICAD Classification)
Pset_DoorCommon - Reference: SU-134-v; ThermalTransmittance: 0; GlazingAreaFraction: 1.505; IsExternal: no
AR_Uks - 001_Nimetus: Siseuks; 300_Tüüp: SU-134-v; 305_Ava_mõõt: 900x2,300; 310_Materjal: MUDELIS: väljast-TOON- RAL 9006 alumiinium hall; TOON- RAL 9006 alumiinium hall; seest-TOON- RAL 9006 alumiinium hall; TOON- RAL 9006 alumiinium hall; MÄRKUS: Täispuit ukseserv, fassaad spoonitud 8mm HDF, oksakuusk; 315_Avanemine: Pöördavanev - Vasak ; ARCHICAD tüüp: Side Hung; 320_Klaas: -; 325_Helipidavus: 40 dB; 330_Tulekindlus: nõudeid ei esitata; 335_Välispiire: no; 340_Soojusläbivus: 0; 345_Päikesekiirgus_tegur: Nõudeid ei esitata; 350_Klaaspakett: -; 355_Pindala: 2.07 m2; 360_Ratastooliga: no; 365_Isesulguv: no; 370_Evakuatsiooniväljapääs: no; 375_Viimistlus_seest: Leng: TOON- RAL 9006 alumiinium hall; Ukseleht: TOON- RAL 9006 alumiinium hall; MÄRKUS: Toonitud matt lakk; 376_Viimistlus_väljast: Leng: TOON- RAL 9006 alumiinium hall; Ukseleht: TOON- RAL 9006 alumiinium hall; MÄRKUS: -; 380_Lukustus: Mehaaniline lukk; 900_Tootja: -; 905_Mudel: -; 910_Tooteinfo: -; 915_Kasutus-ja_hooldusjuhend: -
AC_Pset_RenovationAndPhasing - Renovation Status: New

# IfcDoor: Door 25, Siseuks
In: 2. korrus
Type - OperationType: SINGLE_SWING_RIGHT; ParameterTakesPrecedence: no; Sizeable: no
Type - Door Lining Properties - LiningDepth: 92 mm; LiningThickness: 50 mm; LiningOffset: 405 mm
Type - Door Panel Properties - Panel 1 - PanelDepth: 50 mm; PanelOperation: SWINGING; PanelWidth: 1; PanelPosition: MIDDLE
OverallHeight: 2300 mm; OverallWidth: 1000 mm; Classification: 1.10 IfcDoorStyle (uks) (RKAS BIM + ARCHICAD Classification)
Pset_DoorCommon - Reference: SU-417-v; ThermalTransmittance: 0; IsExternal: no
AR_Uks - 001_Nimetus: Siseuks; 300_Tüüp: SU-417-v; 305_Ava_mõõt: 1,000x2,300; 310_Materjal: MUDELIS: väljast-TOON- RAL 9006 alumiinium hall; TOON- RAL 9006 alumiinium hall; seest-TOON- RAL 9006 alumiinium hall; TOON- RAL 9006 alumiinium hall; MÄRKUS: Kuumtsingitud teras, 1mm; 315_Avanemine: Pöördavanev - Vasak ; ARCHICAD tüüp: Side Hung; 320_Klaas: -; 325_Helipidavus: 45 dB; 330_Tulekindlus: EI30; 335_Välispiire: no; 340_Soojusläbivus: 0; 345_Päikesekiirgus_tegur: Nõudeid ei esitata; 350_Klaaspakett: -; 355_Pindala: 2.3 m2; 360_Ratastooliga: no; 365_Isesulguv: no; 370_Evakuatsiooniväljapääs: no; 375_Viimistlus_seest: Leng: TOON- RAL 9006 alumiinium hall; Ukseleht: TOON- RAL 9006 alumiinium hall; MÄRKUS: Kuumtsink; 376_Viimistlus_väljast: Leng: TOON- RAL 9006 alumiinium hall; Ukseleht: TOON- RAL 9006 alumiinium hall; MÄRKUS: -; 380_Lukustus: -; 900_Tootja: -; 905_Mudel: -; 910_Tooteinfo: -; 915_Kasutus-ja_hooldusjuhend: -
AC_Pset_RenovationAndPhasing - Renovation Status: New

# IfcDoor: Door 25, Siseuks
In: 3. korrus
Type - OperationType: SINGLE_SWING_RIGHT; ParameterTakesPrecedence: no; Sizeable: no
Type - Door Lining Properties - LiningDepth: 92 mm; LiningThickness: 50 mm; LiningOffset: 47 mm
Type - Door Panel Properties - Panel 1 - PanelDepth: 50 mm; PanelOperation: SWINGING; PanelWidth: 1; PanelPosition: MIDDLE
OverallHeight: 2100 mm; OverallWidth: 800 mm; Classification: 1.10 IfcDoorStyle (uks) (RKAS BIM + ARCHICAD Classification)
Pset_DoorCommon - Reference: SU-422-v; ThermalTransmittance: 0; IsExternal: no
AR_Uks - 001_Nimetus: Siseuks; 300_Tüüp: SU-422-v; 305_Ava_mõõt: 800x2,100; 310_Materjal: MUDELIS: väljast-TOON- RAL 9006 alumiinium hall; TOON- RAL 9006 alumiinium hall; seest-TOON- RAL 9006 alumiinium hall; TOON- RAL 9006 alumiinium hall; MÄRKUS: Täispuit ukseserv, fassaad spoonitud 8mm HDF, oksakuusk; 315_Avanemine: Pöördavanev - Vasak ; ARCHICAD tüüp: Side Hung; 320_Klaas: -; 325_Helipidavus: -; 330_Tulekindlus: EI30; 335_Välispiire: no; 340_Soojusläbivus: 0; 345_Päikesekiirgus_tegur: Nõudeid ei esitata; 350_Klaaspakett: -; 355_Pindala: 1.68 m2; 360_Ratastooliga: no; 365_Isesulguv: no; 370_Evakuatsiooniväljapääs: no; 375_Viimistlus_seest: Leng: TOON- RAL 9006 alumiinium hall; Ukseleht: TOON- RAL 9006 alumiinium hall; MÄRKUS: Toonitud matt lakk; 376_Viimistlus_väljast: Leng: TOON- RAL 9006 alumiinium hall; Ukseleht: TOON- RAL 9006 alumiinium hall; MÄRKUS: -; 380_Lukustus: ilma lingita, sõrmekonks, mehaaniline lukk; 900_Tootja: -; 905_Mudel: -; 910_Tooteinfo: -; 915_Kasutus-ja_hooldusjuhend: -
AC_Pset_RenovationAndPhasing - Renovation Status: New

# IfcDoor: Door 25, Siseuks
In: 2. korrus
Type - OperationType: SINGLE_SWING_RIGHT; ParameterTakesPrecedence: no; Sizeable: no
Type - Door Lining Properties - LiningDepth: 92 mm; LiningThickness: 50 mm; LiningOffset: 48 mm
Type - Door Panel Properties - Panel 1 - PanelDepth: 50 mm; PanelOperation: SWINGING; PanelWidth: 1; PanelPosition: MIDDLE
OverallHeight: 2300 mm; OverallWidth: 900 mm; Classification: 1.10 IfcDoorStyle (uks) (RKAS BIM + ARCHICAD Classification)
Pset_DoorCommon - Reference: SU-134-v; ThermalTransmittance: 0; GlazingAreaFraction: 1.505; IsExternal: no
AR_Uks - 001_Nimetus: Siseuks; 300_Tüüp: SU-134-v; 305_Ava_mõõt: 900x2,300; 310_Materjal: MUDELIS: väljast-TOON- RAL 9006 alumiinium hall; TOON- RAL 9006 alumiinium hall; seest-TOON- RAL 9006 alumiinium hall; TOON- RAL 9006 alumiinium hall; MÄRKUS: Täispuit ukseserv, fassaad spoonitud 8mm HDF, oksakuusk; 315_Avanemine: Pöördavanev - Vasak ; ARCHICAD tüüp: Side Hung; 320_Klaas: -; 325_Helipidavus: 40 dB; 330_Tulekindlus: nõudeid ei esitata; 335_Välispiire: no; 340_Soojusläbivus: 0; 345_Päikesekiirgus_tegur: Nõudeid ei esitata; 350_Klaaspakett: -; 355_Pindala: 2.07 m2; 360_Ratastooliga: no; 365_Isesulguv: no; 370_Evakuatsiooniväljapääs: no; 375_Viimistlus_seest: Leng: TOON- RAL 9006 alumiinium hall; Ukseleht: TOON- RAL 9006 alumiinium hall; MÄRKUS: Toonitud matt lakk; 376_Viimistlus_väljast: Leng: TOON- RAL 9006 alumiinium hall; Ukseleht: TOON- RAL 9006 alumiinium hall; MÄRKUS: -; 380_Lukustus: Mehaaniline lukk; 900_Tootja: -; 905_Mudel: -; 910_Tooteinfo: -; 915_Kasutus-ja_hooldusjuhend: -
AC_Pset_RenovationAndPhasing - Renovation Status: New

# IfcDoor: Door 25 (11)
Type - OperationType: SINGLE_SWING_RIGHT; ParameterTakesPrecedence: no; Sizeable: no
Type - Door Lining Properties - LiningDepth: 92 mm; LiningThickness: 50 mm; LiningOffset: 63 mm
Type - Door Panel Properties - Panel 1 - PanelDepth: 50 mm; PanelOperation: SWINGING; PanelWidth: 1; PanelPosition: MIDDLE
OverallWidth: 800 mm; Classification: 1.10 IfcDoorStyle (uks) (RKAS BIM + ARCHICAD Classification)
Pset_DoorCommon - ThermalTransmittance: 0
AR_Uks - 001_Nimetus: Siseuks; 310_Materjal: MUDELIS: väljast-TOON- RAL 9006 alumiinium hall; TOON- RAL 9006 alumiinium hall; seest-TOON- RAL 9006 alumiinium hall; TOON- RAL 9006 alumiinium hall; MÄRKUS: Kuumtsingitud teras, 1mm; 315_Avanemine: Pöördavanev - Vasak ; ARCHICAD tüüp: Side Hung; 320_Klaas: -; 330_Tulekindlus: nõudeid ei esitata; 335_Välispiire: no; 340_Soojusläbivus: 0; 345_Päikesekiirgus_tegur: Nõudeid ei esitata; 350_Klaaspakett: -; 360_Ratastooliga: no; 365_Isesulguv: no; 370_Evakuatsiooniväljapääs: no; 376_Viimistlus_väljast: Leng: TOON- RAL 9006 alumiinium hall; Ukseleht: TOON- RAL 9006 alumiinium hall; MÄRKUS: -; 380_Lukustus: Liugvarrega sulgur, väljas link, sees väändenupp; 900_Tootja: -; 905_Mudel: -; 910_Tooteinfo: -; 915_Kasutus-ja_hooldusjuhend: -
AC_Pset_RenovationAndPhasing - Renovation Status: New
Name | In | OverallHeight (mm) | Reference = 300_Tüüp | 305_Ava_mõõt | 325_Helipidavus | 355_Pindala (m2) | 375_Viimistlus_seest
Siseuks | 1. korrus | 2100 | SU-123-v | 800x2,100 | nõudeid ei esitata | 1.68 | Leng: TOON- RAL 9006 alumiinium hall; Ukseleht: TOON- RAL 9006 alumiinium hall; MÄRKUS: Kuumtsink | Pset_DoorCommon - IsExternal: no
Siseuks | 1. korrus | 2300 | SU-107-v | 800x2,300 | 25 dB | 1.84 | Leng: TOON- RAL 9006 alumiinium hall; Ukseleht: TOON- RAL 9006 alumiinium hall; MÄRKUS: Pulbervärv, värvi toon vastavalt sanruumi tarnitavale keraamilisele plaadile. | Pset_DoorCommon - IsExternal: no
3 x Siseuks | 1. korrus | 2300 | SU-121-v | 800x2,300 | 25 dB | 1.84 | Leng: TOON- RAL 9006 alumiinium hall; Ukseleht: TOON- RAL 9006 alumiinium hall; MÄRKUS: Kuumtsink
3 x Siseuks | 2. korrus | 2300 | SU-121-v | 800x2,300 | 25 dB | 1.84 | Leng: TOON- RAL 9006 alumiinium hall; Ukseleht: TOON- RAL 9006 alumiinium hall; MÄRKUS: Kuumtsink
3 x Siseuks | 3. korrus | 2300 | SU-121-v | 800x2,300 | 25 dB | 1.84 | Leng: TOON- RAL 9006 alumiinium hall; Ukseleht: TOON- RAL 9006 alumiinium hall; MÄRKUS: Kuumtsink

# IfcDoor: Door 25 (2)
In: 4. TEHNO korrus
Type - OperationType: SINGLE_SWING_RIGHT; ParameterTakesPrecedence: no; Sizeable: no
Type - Door Lining Properties - LiningDepth: 92 mm; LiningThickness: 50 mm; ThresholdDepth: 42 mm; ThresholdThickness: 12 mm; LiningOffset: -200 mm; ThresholdOffset: -108 mm
Type - Door Panel Properties - Panel 1 - PanelDepth: 50 mm; PanelOperation: SWINGING; PanelWidth: 1; PanelPosition: MIDDLE
OverallHeight: 2100 mm; OverallWidth: 1000 mm; Classification: 1.10 IfcDoorStyle (uks) (RKAS BIM + ARCHICAD Classification)
Pset_DoorCommon - Reference: SU-142-v; ThermalTransmittance: 0; IsExternal: no
AR_Uks - 001_Nimetus: Siseuks; 300_Tüüp: SU-142-v; 305_Ava_mõõt: 1,000x2,100; 310_Materjal: MUDELIS: väljast-TOON- helehall RR21; TOON- helehall RR21; seest-TOON- helehall RR21; TOON- helehall RR21; MÄRKUS: Kuumtsingitud teras, 1mm; 315_Avanemine: Pöördavanev - Vasak ; ARCHICAD tüüp: Side Hung; 320_Klaas: -; 325_Helipidavus: 33 dB; 330_Tulekindlus: nõudeid ei esitata; 335_Välispiire: no; 340_Soojusläbivus: 0; 345_Päikesekiirgus_tegur: Nõudeid ei esitata; 350_Klaaspakett: -; 355_Pindala: 2.1 m2; 360_Ratastooliga: no; 365_Isesulguv: no; 370_Evakuatsiooniväljapääs: no; 375_Viimistlus_seest: Leng: TOON- helehall RR21; Ukseleht: TOON- helehall RR21; MÄRKUS: Kuumtsink; 376_Viimistlus_väljast: Leng: TOON- helehall RR21; Ukseleht: TOON- helehall RR21; MÄRKUS: -; 380_Lukustus: -; 900_Tootja: Saku Metall Uksetehas või samaväärne; 905_Mudel: Metalluks Q Med 1311; 910_Tooteinfo: -; 915_Kasutus-ja_hooldusjuhend: -
AC_Pset_RenovationAndPhasing - Renovation Status: New

# IfcDoor: Door with Sidelight on Side 2 25 (41)
Type - OperationType: SINGLE_SWING_LEFT; ParameterTakesPrecedence: no; Sizeable: no
Type - Door Panel Properties - Panel 1 - PanelDepth: 40 mm; PanelOperation: SWINGING; PanelWidth: 1; PanelPosition: MIDDLE
OverallHeight: 2300 mm; Classification: 1.10 IfcDoorStyle (uks) (RKAS BIM + ARCHICAD Classification)
Pset_DoorCommon - ThermalTransmittance: 0; IsExternal: no
AR_Uks - 001_Nimetus: Siseuks; 310_Materjal: MUDELIS: väljast-PUIT- kuusk H; PUIT- kuusk H; seest-PUIT- kuusk H; PUIT- kuusk H; MÄRKUS: Täispuit ukseserv, fassaad spoonitud 8mm HDF, oksakuusk; 315_Avanemine: Pöördavanev - Parem ; ARCHICAD tüüp: Side Hung; 330_Tulekindlus: nõudeid ei esitata; 335_Välispiire: no; 340_Soojusläbivus: 0; 345_Päikesekiirgus_tegur: Nõudeid ei esitata; 350_Klaaspakett: -; 370_Evakuatsiooniväljapääs: no; 375_Viimistlus_seest: Leng: PUIT- kuusk H; Ukseleht: PUIT- kuusk H; MÄRKUS: Toonitud matt lakk; 376_Viimistlus_väljast: Leng: PUIT- kuusk H; Ukseleht: PUIT- kuusk H; MÄRKUS: -; 900_Tootja: -; 905_Mudel: -; 910_Tooteinfo: -; 915_Kasutus-ja_hooldusjuhend: -
AC_Pset_RenovationAndPhasing - Renovation Status: New
Name | In | OverallWidth (mm) | Reference = 300_Tüüp | GlazingAreaFraction | 305_Ava_mõõt | 320_Klaas | 325_Helipidavus | 355_Pindala (m2) | 360_Ratastooliga = 365_Isesulguv | 380_Lukustus
Siseuks | 1. korrus | 3000 | SU-115-p | 5.80449 | 3,02x2,30 | Kirgas, karastatud | 25 dB | 6.90001 | no | Liugvarrega sulgur, kaardilugeja, elektrilukk
Siseuks | 1. korrus | 3010.93 | SU-114-p | 5.82874 | 3,011x2,300 | Kirgas, karastatud | 25 dB | 6.92513 | no | Liugvarrega sulgur, kaardilugeja, elektrilukk
Siseuks | 1. korrus | 2996.18 | SU-117-p | 5.796 | 2,996x2,300 | Kirgas, karastatud | 25 dB | 6.89122 | no | Liugvarrega sulgur, kaardilugeja, elektrilukk
4 x Siseuks | 1. korrus | 1500 | SU-101-p | 2.47845 | 1,500x2,300 | Kirgas, karastatud | 40 dB | 3.45 | yes | Liugvarrega sulgur, kaardilugeja, elektrilukk
Siseuks | 1. korrus | 1400 | SU-102-p | 2.26637 | 1,400x2,300 | Kirgas, karastatud | 40 dB | 3.22 | no | Liugvarrega sulgur, kaardilugeja, elektrilukk
Siseuks | 1. korrus | 3245 | SU-111-p | 6.34838 | 3,245x2,300 | Kirgas, karastatud | 30 dB | 7.4635 | no | Liugvarrega sulgur, kaardilugeja, elektrilukk
Siseuks | 1. korrus | 2790 | SU-112-p | 5.33828 | 2,790x2,300 | Kirgas, karastatud | 30 dB | 6.417 | no | Liugvarrega sulgur, kaardilugeja, elektrilukk
Siseuks | 1. korrus | 2940 | SU-116-v | 5.67525 | 2,94x2,10 | Kirgas, karastatud | 25 dB | 6.762 | no | Liugvarrega sulgur, kaardilugeja, elektrilukk
9 x Siseuks | 2. korrus | 1500 | SU-101-p | 2.47845 | 1,500x2,300 | Kirgas, karastatud | 40 dB | 3.45 | yes | Liugvarrega sulgur, kaardilugeja, elektrilukk
Siseuks | 2. korrus | 1780 | SU-129-p | 3.10005 | 1,780x2,300 | Kirgas, karastatud | 40 dB | 4.094 | no | Liugvarrega sulgur, kaardilugeja, elektrilukk
Siseuks | 2. korrus | 1780 | SU-129-p | 3.10006 | 1,780x2,300 | Kirgas, karastatud | 40 dB | 4.094 | no | Liugvarrega sulgur, kaardilugeja, elektrilukk
Siseuks | 2. korrus | 1500 | SU-151-p | 2.47845 | 1,500x2,300 | Kirgas, karastatud | 40 dB | 3.45 | no | Liugvarrega sulgur
Siseuks | 2. korrus | 1500 | SU-152-p | 2.47845 | 1,500x2,300 | Kirgas, karastatud | 45 dB | 3.45 | no | Liugvarrega sulgur
12 x Siseuks | 3. korrus | 1500 | SU-101-p | 2.47845 | 1,500x2,300 | Kirgas, karastatud | 40 dB | 3.45 | yes | Liugvarrega sulgur, kaardilugeja, elektrilukk
3 x Siseuks | 3. korrus | 1500 | SU-101-p | 2.50325 | 1,500x2,300 | Kirgas, karastatud | 40 dB | 3.45 | yes | Liugvarrega sulgur, kaardilugeja, elektrilukk
Siseuks | 3. korrus | 2490 | SU-138-p | 4.67625 | 2,490x2,300 | Kirgas, klaas | 35 dB | 5.727 | no | Liugvarrega sulgur, kaardilugeja, elektrilukk
Siseuks | 3. korrus | 1780 | SU-129-p | 3.10006 | 1,780x2,300 | Kirgas, karastatud | 40 dB | 4.094 | no | Liugvarrega sulgur, kaardilugeja, elektrilukk

# IfcDoor: Door with Sidelight on Side 2 25 (27)
Type - OperationType: SINGLE_SWING_RIGHT; ParameterTakesPrecedence: no; Sizeable: no
Type - Door Panel Properties - Panel 1 - PanelDepth: 40 mm; PanelOperation: SWINGING; PanelWidth: 1; PanelPosition: MIDDLE
OverallHeight: 2300 mm; Classification: 1.10 IfcDoorStyle (uks) (RKAS BIM + ARCHICAD Classification)
Pset_DoorCommon - ThermalTransmittance: 0; IsExternal: no
AR_Uks - 001_Nimetus: Siseuks; 310_Materjal: MUDELIS: väljast-PUIT- kuusk H; PUIT- kuusk H; seest-PUIT- kuusk H; PUIT- kuusk H; MÄRKUS: Täispuit ukseserv, fassaad spoonitud 8mm HDF, oksakuusk; 315_Avanemine: Pöördavanev - Vasak ; ARCHICAD tüüp: Side Hung; 330_Tulekindlus: nõudeid ei esitata; 335_Välispiire: no; 340_Soojusläbivus: 0; 345_Päikesekiirgus_tegur: Nõudeid ei esitata; 350_Klaaspakett: -; 370_Evakuatsiooniväljapääs: no; 375_Viimistlus_seest: Leng: PUIT- kuusk H; Ukseleht: PUIT- kuusk H; MÄRKUS: Toonitud matt lakk; 376_Viimistlus_väljast: Leng: PUIT- kuusk H; Ukseleht: PUIT- kuusk H; MÄRKUS: -; 900_Tootja: -; 905_Mudel: -; 910_Tooteinfo: -; 915_Kasutus-ja_hooldusjuhend: -
AC_Pset_RenovationAndPhasing - Renovation Status: New
Name | In | OverallWidth (mm) | Reference = 300_Tüüp | GlazingAreaFraction | 305_Ava_mõõt | 320_Klaas | 325_Helipidavus | 355_Pindala (m2) | 360_Ratastooliga = 365_Isesulguv | 380_Lukustus
Siseuks | 1. korrus | 1500 | SU-101-v | 2.47845 | 1,500x2,300 | Kirgas, karastatud | 40 dB | 3.45 | yes | Liugvarrega sulgur, kaardilugeja, elektrilukk
Siseuks | 1. korrus | 1960 | SU-144-v | 3.49568 | 1,960x2,300 | Kirgas, klaas | 30 dB | 4.508 | no | Liugvarrega sulgur, kaardilugeja, elektrilukk
Siseuks | 1. korrus | 1600 | SU-105-v | 2.71037 | 1,680x2,300 | Kirgas, karastatud | 30 dB | 3.68 | no | Liugvarrega sulgur, kaardilugeja, elektrilukk
2 x Siseuks | 1. korrus | 1600 | SU-104-v | 2.71037 | 1,630x2,300 | Kirgas, karastatud | 30 dB | 3.68 | no | Liugvarrega sulgur, kaardilugeja, elektrilukk
Siseuks | 1. korrus | 2000 | SU-103-v | 3.58448 | 2,000x2,300 | Kirgas, karastatud | 30 dB | 4.6 | yes | Liugvarrega sulgur, kaardilugeja, elektrilukk
Siseuks | 1. korrus | 3320.01 | SU-113-v | 6.5149 | 4,35x2,30 | Kirgas, karastatud | 25 dB | 7.63602 | no | Liugvarrega sulgur, kaardilugeja, elektrilukk
Siseuks | 1. korrus | 1940 | SU-135-v | 3.45128 | 1,940x2,300 | Kirgas, klaas | 40 dB | 4.462 | no | Liugvarrega sulgur, kaardilugeja, elektrilukk
8 x Siseuks | 2. korrus | 1500 | SU-101-v | 2.47845 | 1,500x2,300 | Kirgas, karastatud | 40 dB | 3.45 | yes | Liugvarrega sulgur, kaardilugeja, elektrilukk
Siseuks | 2. korrus | 1500 | SU-151-v | 2.47845 | 1,500x2,300 | Kirgas, karastatud | 40 dB | 3.45 | no | Liugvarrega sulgur
3 x Siseuks | 3. korrus | 1500 | SU-101-v | 2.50325 | 1,500x2,300 | Kirgas, karastatud | 40 dB | 3.45 | yes | Liugvarrega sulgur, kaardilugeja, elektrilukk
5 x Siseuks | 3. korrus | 1500 | SU-101-v | 2.47845 | 1,500x2,300 | Kirgas, karastatud | 40 dB | 3.45 | yes | Liugvarrega sulgur, kaardilugeja, elektrilukk
Siseuks | 3. korrus | 2490 | SU-138-v | 4.67625 | 2,490x2,300 | Kirgas, klaas | 35 dB | 5.727 | no | Liugvarrega sulgur, kaardilugeja, elektrilukk
Siseuks | 3. korrus | 1810 | SU-133-v | 3.16665 | 1,810x2,300 | Kirgas, karastatud | 40 dB | 4.163 | no | Liugvarrega sulgur, kaardilugeja, elektrilukk

# IfcDoor: Double Door 25, Jäätmeluuk
In: 1. korrus
Type - OperationType: DOUBLE_DOOR_SINGLE_SWING; ParameterTakesPrecedence: no; Sizeable: no
Type - Door Lining Properties - LiningDepth: 50 mm; LiningThickness: 30 mm; LiningOffset: 80 mm
Type - Door Panel Properties - Panel 1 - PanelDepth: 40 mm; PanelOperation: SWINGING; PanelWidth: 0.513408; PanelPosition: LEFT
Type - Door Panel Properties - Panel 2 - PanelDepth: 40 mm; PanelOperation: SWINGING; PanelWidth: 0.513408; PanelPosition: RIGHT
OverallHeight: 900 mm; OverallWidth: 955 mm; Classification: 1.10 IfcDoorStyle (uks) (RKAS BIM + ARCHICAD Classification)
Pset_DoorCommon - Reference: SU-140; ThermalTransmittance: 0; IsExternal: no
AR_Uks - 001_Nimetus: Jäätmeluuk; 300_Tüüp: SU-140; 305_Ava_mõõt: 955x900; 310_Materjal: MUDELIS: väljast-PUIT- kuusk H; PUIT- kuusk H; seest-PUIT- kuusk H; PUIT- kuusk H; MÄRKUS: Kuumtsingitud teras, 1mm; 315_Avanemine: Undefined - Vasak ; ARCHICAD tüüp: Side Hung; 320_Klaas: -; 325_Helipidavus: Nõudeid ei esitata; 330_Tulekindlus: nõudeid ei esitata; 335_Välispiire: no; 340_Soojusläbivus: 0; 345_Päikesekiirgus_tegur: Nõudeid ei esitata; 350_Klaaspakett: -; 355_Pindala: 0.8595 m2; 360_Ratastooliga: no; 365_Isesulguv: no; 370_Evakuatsiooniväljapääs: no; 375_Viimistlus_seest: Leng: PUIT- kuusk H; Ukseleht: PUIT- kuusk H; MÄRKUS: Kuumtsink; 376_Viimistlus_väljast: Leng: PUIT- kuusk H; Ukseleht: PUIT- kuusk H; MÄRKUS: -; 380_Lukustus: vt lukustuse projekt; 900_Tootja: Vastavalt SA siseuste spetsifikatsioonile; 905_Mudel: Vastavalt SA siseuste spetsifikatsioonile; 910_Tooteinfo: -; 915_Kasutus-ja_hooldusjuhend: -
AC_Pset_RenovationAndPhasing - Renovation Status: New

# IfcDoor: Double Door 25, Kahepoolne siseuks
In: 1. korrus
Type - OperationType: DOUBLE_DOOR_SINGLE_SWING; ParameterTakesPrecedence: no; Sizeable: no
Type - Door Lining Properties - LiningDepth: 92 mm; LiningThickness: 40 mm; LiningOffset: -92 mm; CasingThickness: 50 mm; CasingDepth: 19 mm
Type - Door Panel Properties - Panel 1 - PanelDepth: 40 mm; PanelOperation: SWINGING; PanelWidth: 0.50625; PanelPosition: RIGHT
Type - Door Panel Properties - Panel 2 - PanelDepth: 40 mm; PanelOperation: SWINGING; PanelWidth: 0.50625; PanelPosition: LEFT
OverallHeight: 2300 mm; OverallWidth: 2000 mm; Classification: 1.10 IfcDoorStyle (uks) (RKAS BIM + ARCHICAD Classification)
Pset_DoorCommon - Reference: SU-406-p; ThermalTransmittance: 0; IsExternal: no
AR_Uks - 001_Nimetus: Kahepoolne siseuks; 300_Tüüp: SU-406-p; 305_Ava_mõõt: 2,000x2,300; 310_Materjal: MUDELIS: väljast-PUIT- kuusk H; PUIT- kuusk H; seest-PUIT- kuusk H; PUIT- kuusk H; MÄRKUS: Täispuit ukseserv, fassaad spoonitud 8mm HDF, oksakuusk; 315_Avanemine: Pöördavanev - Parem ; ARCHICAD tüüp: Side Hung; 320_Klaas: -; 325_Helipidavus: nõudeid ei esitata; 330_Tulekindlus: EI90; 335_Välispiire: no; 340_Soojusläbivus: 0; 345_Päikesekiirgus_tegur: Nõudeid ei esitata; 350_Klaaspakett: -; 355_Pindala: 4.6 m2; 360_Ratastooliga: no; 365_Isesulguv: no; 370_Evakuatsiooniväljapääs: no; 375_Viimistlus_seest: Leng: PUIT- kuusk H; Ukseleht: PUIT- kuusk H; MÄRKUS: Toonitud matt lakk; 376_Viimistlus_väljast: Leng: PUIT- kuusk H; Ukseleht: PUIT- kuusk H; MÄRKUS: -; 380_Lukustus: Liugvarrega sulgur, kaardilugeja, elektrilukk; 900_Tootja: -; 905_Mudel: -; 910_Tooteinfo: -; 915_Kasutus-ja_hooldusjuhend: -
AC_Pset_RenovationAndPhasing - Renovation Status: New

# IfcDoor: Double Door 25, Kahepoolne siseuks
In: 2. korrus
Type - OperationType: DOUBLE_DOOR_SINGLE_SWING; ParameterTakesPrecedence: no; Sizeable: no
Type - Door Lining Properties - LiningDepth: 92 mm; LiningThickness: 40 mm; LiningOffset: -92 mm
Type - Door Panel Properties - Panel 1 - PanelDepth: 40 mm; PanelOperation: SWINGING; PanelWidth: 0.508955; PanelPosition: LEFT
Type - Door Panel Properties - Panel 2 - PanelDepth: 40 mm; PanelOperation: SWINGING; PanelWidth: 0.508955; PanelPosition: RIGHT
OverallHeight: 2300 mm; OverallWidth: 1420 mm; Classification: 1.10 IfcDoorStyle (uks) (RKAS BIM + ARCHICAD Classification)
Pset_DoorCommon - Reference: SU-411-p; ThermalTransmittance: 0; GlazingAreaFraction: 1.90101; IsExternal: no
AR_Uks - 001_Nimetus: Kahepoolne siseuks; 300_Tüüp: SU-411-p; 305_Ava_mõõt: 1,420x2,300; 310_Materjal: MUDELIS: väljast-PUIT- kuusk H; PUIT- kuusk H; seest-PUIT- kuusk H; PUIT- kuusk H; MÄRKUS: Täispuit ukseserv, fassaad spoonitud 8mm HDF, oksakuusk; 315_Avanemine: Pöördavanev - Vasak ; ARCHICAD tüüp: Side Hung; 320_Klaas: -; 325_Helipidavus: nõudeid ei esitata; 330_Tulekindlus: EI45; 335_Välispiire: no; 340_Soojusläbivus: 0; 345_Päikesekiirgus_tegur: Nõudeid ei esitata; 350_Klaaspakett: -; 355_Pindala: 3.266 m2; 360_Ratastooliga: no; 365_Isesulguv: no; 370_Evakuatsiooniväljapääs: no; 375_Viimistlus_seest: Leng: PUIT- kuusk H; Ukseleht: PUIT- kuusk H; MÄRKUS: Toonitud matt lakk; 376_Viimistlus_väljast: Leng: PUIT- kuusk H; Ukseleht: PUIT- kuusk H; MÄRKUS: -; 380_Lukustus: Liugvarrega sulgur, kaardilugeja, elektrilukk; 900_Tootja: -; 905_Mudel: -; 910_Tooteinfo: -; 915_Kasutus-ja_hooldusjuhend: -
AC_Pset_RenovationAndPhasing - Renovation Status: New

# IfcDoor: Double Door 25, Kahepoolne siseuks
In: 1. korrus
Type - OperationType: DOUBLE_DOOR_SINGLE_SWING; ParameterTakesPrecedence: no; Sizeable: no
Type - Door Lining Properties - LiningDepth: 92 mm; LiningThickness: 40 mm; LiningOffset: 155 mm
Type - Door Panel Properties - Panel 1 - PanelDepth: 40 mm; PanelOperation: SWINGING; PanelWidth: 0.507643; PanelPosition: LEFT
Type - Door Panel Properties - Panel 2 - PanelDepth: 40 mm; PanelOperation: SWINGING; PanelWidth: 0.507643; PanelPosition: RIGHT
OverallHeight: 1320 mm; OverallWidth: 1650 mm; Classification: 1.10 IfcDoorStyle (uks) (RKAS BIM + ARCHICAD Classification)
Pset_DoorCommon - Reference: SU-412-p; ThermalTransmittance: 0; IsExternal: no
AR_Uks - 001_Nimetus: Kahepoolne siseuks; 300_Tüüp: SU-412-p; 305_Ava_mõõt: 1,650x1,320; 310_Materjal: MUDELIS: väljast-TOON- helehall RR21; TOON- helehall RR21; seest-TOON- helehall RR21; TOON- helehall RR21; MÄRKUS: Kuumtsingitud teras, 1mm; 315_Avanemine: Pöördavanev - Vasak ; ARCHICAD tüüp: Side Hung; 320_Klaas: -; 325_Helipidavus: nõudeid ei esitata; 330_Tulekindlus: EI45; 335_Välispiire: no; 340_Soojusläbivus: 0; 345_Päikesekiirgus_tegur: Nõudeid ei esitata; 350_Klaaspakett: -; 355_Pindala: 2.178 m2; 360_Ratastooliga: no; 365_Isesulguv: no; 370_Evakuatsiooniväljapääs: no; 375_Viimistlus_seest: Leng: TOON- helehall RR21; Ukseleht: TOON- helehall RR21; MÄRKUS: Kuumtsink; 376_Viimistlus_väljast: Leng: TOON- helehall RR21; Ukseleht: TOON- helehall RR21; MÄRKUS: -; 380_Lukustus: -; 900_Tootja: -; 905_Mudel: -; 910_Tooteinfo: -; 915_Kasutus-ja_hooldusjuhend: -
AC_Pset_RenovationAndPhasing - Renovation Status: New

# IfcDoor: Double Door Asymmetric 25, Kahepoolne siseuks
In: 1. korrus
Type - OperationType: DOUBLE_DOOR_SINGLE_SWING; ParameterTakesPrecedence: no; Sizeable: no
Type - Door Lining Properties - LiningDepth: 115 mm; LiningThickness: 40 mm; LiningOffset: -210 mm
Type - Door Panel Properties - Panel 1 - PanelDepth: 40 mm; PanelOperation: SWINGING; PanelWidth: 0.709402; PanelPosition: RIGHT
Type - Door Panel Properties - Panel 2 - PanelDepth: 40 mm; PanelOperation: SWINGING; PanelWidth: 0.30525; PanelPosition: LEFT
OverallHeight: 2100 mm; OverallWidth: 1718 mm; Classification: 1.10 IfcDoorStyle (uks) (RKAS BIM + ARCHICAD Classification)
Pset_DoorCommon - Reference: SU-201-v; ThermalTransmittance: 0; GlazingAreaFraction: 0.5316; IsExternal: no
AR_Uks - 001_Nimetus: Kahepoolne siseuks; 300_Tüüp: SU-201-v; 305_Ava_mõõt: 1,718x2,100; 310_Materjal: MUDELIS: väljast-PUIT- kuusk H; PUIT- kuusk H; seest-PUIT- kuusk H; PUIT- kuusk H; MÄRKUS: Täispuit ukseserv, fassaad värvitud 8mm HDF; 315_Avanemine: Pöördavanev - Parem ; ARCHICAD tüüp: Side Hung; 320_Klaas: Kirgas, karastatud; 325_Helipidavus: nõudeid ei esitata; 330_Tulekindlus: nõudeid ei esitata; 335_Välispiire: no; 340_Soojusläbivus: 0; 345_Päikesekiirgus_tegur: Nõudeid ei esitata; 350_Klaaspakett: -; 355_Pindala: 3.6078 m2; 360_Ratastooliga: yes; 365_Isesulguv: yes; 370_Evakuatsiooniväljapääs: no; 375_Viimistlus_seest: Leng: PUIT- kuusk H; Ukseleht: PUIT- kuusk H; MÄRKUS: Valge; 376_Viimistlus_väljast: Leng: PUIT- kuusk H; Ukseleht: PUIT- kuusk H; MÄRKUS: -; 380_Lukustus: Täpsustatada; 900_Tootja: -; 905_Mudel: -; 910_Tooteinfo: -; 915_Kasutus-ja_hooldusjuhend: -
AC_Pset_RenovationAndPhasing - Renovation Status: New

# IfcDoor: Double Door Asymmetric 25, Siseuks
In: 1. korrus
Type - OperationType: DOUBLE_DOOR_SINGLE_SWING; ParameterTakesPrecedence: no; Sizeable: no
Type - Door Lining Properties - LiningDepth: 115 mm; LiningThickness: 40 mm; LiningOffset: 55 mm; CasingThickness: 50 mm; CasingDepth: 19 mm
Type - Door Panel Properties - Panel 1 - PanelDepth: 40 mm; PanelOperation: SWINGING; PanelWidth: 0.644444; PanelPosition: RIGHT
Type - Door Panel Properties - Panel 2 - PanelDepth: 40 mm; PanelOperation: SWINGING; PanelWidth: 0.37037; PanelPosition: LEFT
OverallHeight: 2100 mm; OverallWidth: 1700 mm; Classification: 1.10 IfcDoorStyle (uks) (RKAS BIM + ARCHICAD Classification)
Pset_DoorCommon - Reference: SU-424-v; ThermalTransmittance: 0; GlazingAreaFraction: 2.20437; IsExternal: no
AR_Uks - 001_Nimetus: Siseuks; 300_Tüüp: SU-424-v; 305_Ava_mõõt: 1 700x2 100; 310_Materjal: MUDELIS: väljast-PUIT- kuusk H; PUIT- kuusk H; seest-PUIT- kuusk H; PUIT- kuusk H; MÄRKUS: Kuumtsingitud teras, 1mm; 315_Avanemine: Pöördavanev - Parem ; ARCHICAD tüüp: Side Hung; 320_Klaas: -; 325_Helipidavus: nõudeid ei esitata; 330_Tulekindlus: EI30; 335_Välispiire: no; 340_Soojusläbivus: 0; 345_Päikesekiirgus_tegur: Nõudeid ei esitata; 350_Klaaspakett: -; 355_Pindala: 3.57 m2; 360_Ratastooliga: no; 365_Isesulguv: no; 370_Evakuatsiooniväljapääs: no; 375_Viimistlus_seest: Leng: PUIT- kuusk H; Ukseleht: PUIT- kuusk H; MÄRKUS: Kuumtsink; 376_Viimistlus_väljast: Leng: PUIT- kuusk H; Ukseleht: PUIT- kuusk H; MÄRKUS: -; 380_Lukustus: Liugvarrega sulgur; 900_Tootja: -; 905_Mudel: -; 910_Tooteinfo: -; 915_Kasutus-ja_hooldusjuhend: -
AC_Pset_RenovationAndPhasing - Renovation Status: New

# IfcDoor: Double Door Asymmetric 25, Kahepoolne välisuks
In: 1. korrus
Type - OperationType: DOUBLE_DOOR_SINGLE_SWING; ParameterTakesPrecedence: no; Sizeable: no
Type - Door Lining Properties - LiningDepth: 75 mm; LiningThickness: 50 mm; ThresholdDepth: 15 mm; ThresholdThickness: 10 mm; LiningOffset: -75 mm; ThresholdOffset: 60 mm
Type - Door Panel Properties - Panel 1 - PanelDepth: 60 mm; PanelOperation: SWINGING; PanelWidth: 0.815385; PanelPosition: LEFT
Type - Door Panel Properties - Panel 2 - PanelDepth: 60 mm; PanelOperation: SWINGING; PanelWidth: 0.230769; PanelPosition: RIGHT
OverallHeight: 2100 mm; OverallWidth: 1400 mm; Classification: 1.10 IfcDoorStyle (uks) (RKAS BIM + ARCHICAD Classification)
Pset_DoorCommon - Reference: VU-202-p; ThermalTransmittance: 0; IsExternal: yes
AR_Uks - 001_Nimetus: Kahepoolne välisuks; 300_Tüüp: VU-202-p; 305_Ava_mõõt: 1 400x2 100; 310_Materjal: MUDELIS: väljast-TOON- RAL 9006 alumiinium hall; TOON- RAL 9006 alumiinium hall; seest-TOON- RAL 9006 alumiinium hall; TOON- RAL 9006 alumiinium hall; MÄRKUS: Alumiinium; 315_Avanemine: Pöördavanev-Parem ; ARCHICAD tüüp: Side Hung; 320_Klaas: -; 325_Helipidavus: 34 dB; 330_Tulekindlus: nõudeid ei esitata; 335_Välispiire: yes; 340_Soojusläbivus: 1; 345_Päikesekiirgus_tegur: -; 350_Klaaspakett: -; 355_Pindala: 2.94 m2; 360_Ratastooliga: no; 365_Isesulguv: yes; 370_Evakuatsiooniväljapääs: no; 375_Viimistlus_seest: Leng: TOON- RAL 9006 alumiinium hall; Ukseleht: TOON- RAL 9006 alumiinium hall; MÄRKUS: toon RAL9006 alumiiniumhall; 376_Viimistlus_väljast: Leng: TOON- RAL 9006 alumiinium hall; Ukseleht: TOON- RAL 9006 alumiinium hall; MÄRKUS: toon RAL9006 alumiiniumhall; 380_Lukustus: Vastavalt lukustusprojektile; 900_Tootja: nt Warmeco OÜ; 905_Mudel: Schüco AD UP 75 või analoog; 910_Tooteinfo: -; 915_Kasutus-ja_hooldusjuhend: -
AC_Pset_RenovationAndPhasing - Renovation Status: New

# IfcDoor: Double Door Asymmetric 25 (2)
In: 1. korrus
Type - OperationType: DOUBLE_DOOR_SINGLE_SWING; ParameterTakesPrecedence: no; Sizeable: no
Type - Door Lining Properties - LiningDepth: 75 mm; LiningThickness: 50 mm; ThresholdDepth: 15 mm; ThresholdThickness: 10 mm; LiningOffset: -75 mm; ThresholdOffset: 60 mm
Type - Door Panel Properties - Panel 1 - PanelDepth: 60 mm; PanelOperation: SWINGING; PanelWidth: 0.815385; PanelPosition: RIGHT
Type - Door Panel Properties - Panel 2 - PanelDepth: 60 mm; PanelOperation: SWINGING; PanelWidth: 0.230769; PanelPosition: LEFT
OverallHeight: 2100 mm; OverallWidth: 1400 mm; Classification: 1.10 IfcDoorStyle (uks) (RKAS BIM + ARCHICAD Classification)
Pset_DoorCommon - Reference: VU-202-p; ThermalTransmittance: 0; IsExternal: yes
AR_Uks - 001_Nimetus: Kahepoolne välisuks; 300_Tüüp: VU-202-p; 305_Ava_mõõt: 1 400x2 100; 310_Materjal: MUDELIS: väljast-TOON- RAL 9006 alumiinium hall; TOON- RAL 9006 alumiinium hall; seest-TOON- RAL 9006 alumiinium hall; TOON- RAL 9006 alumiinium hall; MÄRKUS: Alumiinium; 315_Avanemine: Pöördavanev-Parem ; ARCHICAD tüüp: Side Hung; 320_Klaas: -; 325_Helipidavus: 34 dB; 330_Tulekindlus: nõudeid ei esitata; 335_Välispiire: yes; 340_Soojusläbivus: 1; 345_Päikesekiirgus_tegur: -; 350_Klaaspakett: -; 355_Pindala: 2.94 m2; 360_Ratastooliga: no; 365_Isesulguv: yes; 370_Evakuatsiooniväljapääs: no; 375_Viimistlus_seest: Leng: TOON- RAL 9006 alumiinium hall; Ukseleht: TOON- RAL 9006 alumiinium hall; MÄRKUS: toon RAL9006 alumiiniumhall; 376_Viimistlus_väljast: Leng: TOON- RAL 9006 alumiinium hall; Ukseleht: TOON- RAL 9006 alumiinium hall; MÄRKUS: toon RAL9006 alumiiniumhall; 380_Lukustus: Vastavalt lukustusprojektile; 900_Tootja: nt Warmeco OÜ; 905_Mudel: Schüco AD UP 75 või analoog; 910_Tooteinfo: -; 915_Kasutus-ja_hooldusjuhend: -
AC_Pset_RenovationAndPhasing - Renovation Status: New

# IfcDoor: Double Door Asymmetric 25, Kahepoolne välisuks
In: 1. korrus
Type - OperationType: DOUBLE_DOOR_SINGLE_SWING; ParameterTakesPrecedence: no; Sizeable: no
Type - Door Lining Properties - LiningDepth: 75 mm; LiningThickness: 50 mm; ThresholdDepth: 15 mm; ThresholdThickness: 10 mm; LiningOffset: 25 mm; ThresholdOffset: 160 mm
Type - Door Panel Properties - Panel 1 - PanelDepth: 60 mm; PanelOperation: SWINGING; PanelWidth: 0.682353; PanelPosition: RIGHT
Type - Door Panel Properties - Panel 2 - PanelDepth: 60 mm; PanelOperation: SWINGING; PanelWidth: 0.352941; PanelPosition: LEFT
OverallHeight: 2100 mm; OverallWidth: 1800 mm; Classification: 1.10 IfcDoorStyle (uks) (RKAS BIM + ARCHICAD Classification)
Pset_DoorCommon - Reference: VU-203-v-gb; ThermalTransmittance: 0; GlazingAreaFraction: 2.37507; IsExternal: yes
AR_Uks - 001_Nimetus: Kahepoolne välisuks; 300_Tüüp: VU-203-v-gb; 305_Ava_mõõt: 1 800x2 100; 310_Materjal: MUDELIS: väljast-TOON- RAL 9006 alumiinium hall; TOON- RAL 9006 alumiinium hall; seest-TOON- RAL 9006 alumiinium hall; TOON- RAL 9006 alumiinium hall; MÄRKUS: Alumiinium; 315_Avanemine: Pöördavanev-vasak; ARCHICAD tüüp: Side Hung; 320_Klaas: Kirgas turvaklaas; 325_Helipidavus: 34 dB; 330_Tulekindlus: nõudeid ei esitata; 335_Välispiire: yes; 340_Soojusläbivus: 1; 345_Päikesekiirgus_tegur: 0,39; 350_Klaaspakett: 3-kordne klaaspakett, seest lamineeritud ja väljast karastatud, turvaklaas, 4-16-4-16-44,1; 355_Pindala: 3.78 m2; 360_Ratastooliga: yes; 365_Isesulguv: yes; 370_Evakuatsiooniväljapääs: yes; 375_Viimistlus_seest: Leng: TOON- RAL 9006 alumiinium hall; Ukseleht: TOON- RAL 9006 alumiinium hall; MÄRKUS: RAL 9006 alumiiniumhall; 376_Viimistlus_väljast: Leng: TOON- RAL 9006 alumiinium hall; Ukseleht: TOON- RAL 9006 alumiinium hall; MÄRKUS: RAL 9006 alumiiniumhall; 380_Lukustus: Vastavalt lukustusprojektile. Lukud peavad olema pingega lukus - pingeta lahti; 900_Tootja: nt Warmeco OÜ; 905_Mudel: Schüco AD UP 75 või analoog; 910_Tooteinfo: -; 915_Kasutus-ja_hooldusjuhend: -
AC_Pset_RenovationAndPhasing - Renovation Status: New

# IfcDoor: Double Door Asymmetric 25, Kahepoolne välisuks
In: 1. korrus
Type - OperationType: DOUBLE_DOOR_SINGLE_SWING; ParameterTakesPrecedence: no; Sizeable: no
Type - Door Lining Properties - LiningDepth: 75 mm; LiningThickness: 50 mm; ThresholdDepth: 15 mm; ThresholdThickness: 10 mm; LiningOffset: 25 mm; ThresholdOffset: 160 mm
Type - Door Panel Properties - Panel 1 - PanelDepth: 60 mm; PanelOperation: SWINGING; PanelWidth: 0.815385; PanelPosition: RIGHT
Type - Door Panel Properties - Panel 2 - PanelDepth: 60 mm; PanelOperation: SWINGING; PanelWidth: 0.230769; PanelPosition: LEFT
OverallHeight: 2100 mm; OverallWidth: 1400 mm; Classification: 1.10 IfcDoorStyle (uks) (RKAS BIM + ARCHICAD Classification)
Pset_DoorCommon - Reference: VU-202-p; ThermalTransmittance: 0; IsExternal: yes
AR_Uks - 001_Nimetus: Kahepoolne välisuks; 300_Tüüp: VU-202-p; 305_Ava_mõõt: 1 400x2 100; 310_Materjal: MUDELIS: väljast-TOON- RAL 9006 alumiinium hall; TOON- RAL 9006 alumiinium hall; seest-TOON- RAL 9006 alumiinium hall; TOON- RAL 9006 alumiinium hall; MÄRKUS: Alumiinium; 315_Avanemine: Pöördavanev-Parem ; ARCHICAD tüüp: Side Hung; 320_Klaas: -; 325_Helipidavus: 34 dB; 330_Tulekindlus: nõudeid ei esitata; 335_Välispiire: yes; 340_Soojusläbivus: 1; 345_Päikesekiirgus_tegur: -; 350_Klaaspakett: -; 355_Pindala: 2.94 m2; 360_Ratastooliga: no; 365_Isesulguv: yes; 370_Evakuatsiooniväljapääs: no; 375_Viimistlus_seest: Leng: TOON- RAL 9006 alumiinium hall; Ukseleht: TOON- RAL 9006 alumiinium hall; MÄRKUS: toon RAL9006 alumiiniumhall; 376_Viimistlus_väljast: Leng: TOON- RAL 9006 alumiinium hall; Ukseleht: TOON- RAL 9006 alumiinium hall; MÄRKUS: toon RAL9006 alumiiniumhall; 380_Lukustus: Vastavalt lukustusprojektile; 900_Tootja: nt Warmeco OÜ; 905_Mudel: Schüco AD UP 75 või analoog; 910_Tooteinfo: -; 915_Kasutus-ja_hooldusjuhend: -
AC_Pset_RenovationAndPhasing - Renovation Status: New

# IfcDoor: Double Door with Sidelight 25 (4)
Type - OperationType: USERDEFINED; ParameterTakesPrecedence: no; Sizeable: no
OverallHeight: 2300 mm; OverallWidth: 2800 mm; Classification: 1.10 IfcDoorStyle (uks) (RKAS BIM + ARCHICAD Classification)
Pset_DoorCommon - Reference: SU-401-p; ThermalTransmittance: 0; GlazingAreaFraction: 4.47181; IsExternal: no
AR_Uks - 001_Nimetus: Kahepoolne siseuks; 300_Tüüp: SU-401-p; 305_Ava_mõõt: 2,800x2,300; 310_Materjal: MUDELIS: väljast-PUIT- kuusk H; PUIT- kuusk H; seest-PUIT- kuusk H; PUIT- kuusk H; MÄRKUS: Täispuit ukseserv, fassaad spoonitud 8mm HDF, oksakuusk; 315_Avanemine: Pöördavanev, igapäevaselt magnet kinnituse abil avatud olekus. Tulekahju olukorras sulgub uks automaatselt evakuatsiooniukseks - Parem ; ARCHICAD tüüp: Side Hung; 320_Klaas: Kirgas, karastatud; 325_Helipidavus: 35 dB; 330_Tulekindlus: EI30; 335_Välispiire: no; 340_Soojusläbivus: 0; 345_Päikesekiirgus_tegur: Nõudeid ei esitata; 350_Klaaspakett: -; 355_Pindala: 6.44 m2; 360_Ratastooliga: no; 365_Isesulguv: no; 370_Evakuatsiooniväljapääs: no; 375_Viimistlus_seest: Leng: PUIT- kuusk H; Ukseleht: PUIT- kuusk H; MÄRKUS: Toonitud matt lakk; 376_Viimistlus_väljast: Leng: PUIT- kuusk H; Ukseleht: PUIT- kuusk H; MÄRKUS: -; 380_Lukustus: Süvistatud magnetiline lahtihoidmismehhanism; 900_Tootja: -; 905_Mudel: -; 910_Tooteinfo: -; 915_Kasutus-ja_hooldusjuhend: -
AC_Pset_RenovationAndPhasing - Renovation Status: New
Name | In
2 x Kahepoolne siseuks | 2. korrus
2 x Kahepoolne siseuks | 3. korrus

# IfcDoor: Double Door with Sidelight, Transom 25 (2)
In: 1. korrus
Type - OperationType: USERDEFINED; ParameterTakesPrecedence: no; Sizeable: no
OverallWidth: 2800 mm; Classification: 1.10 IfcDoorStyle (uks) (RKAS BIM + ARCHICAD Classification)
Pset_DoorCommon - ThermalTransmittance: 0; IsExternal: no
AR_Uks - 001_Nimetus: Kahepoolne siseuks; 310_Materjal: MUDELIS: väljast-PUIT- kuusk H; PUIT- kuusk H; seest-PUIT- kuusk H; PUIT- kuusk H; MÄRKUS: Täispuit ukseserv, fassaad spoonitud 8mm HDF, oksakuusk; 315_Avanemine: Pöördavanev, igapäevaselt magnet kinnituse abil avatud olekus. Tulekahju olukorras sulgub uks automaatselt evakuatsiooniukseks - Parem ; ARCHICAD tüüp: Side Hung; 330_Tulekindlus: EI30; 335_Välispiire: no; 340_Soojusläbivus: 0; 345_Päikesekiirgus_tegur: Nõudeid ei esitata; 350_Klaaspakett: -; 360_Ratastooliga: yes; 365_Isesulguv: yes; 370_Evakuatsiooniväljapääs: no; 375_Viimistlus_seest: Leng: PUIT- kuusk H; Ukseleht: PUIT- kuusk H; MÄRKUS: Toonitud matt lakk; 376_Viimistlus_väljast: Leng: PUIT- kuusk H; Ukseleht: PUIT- kuusk H; MÄRKUS: -; 380_Lukustus: Süvistatud magnetiline lahtihoidmismehhanism; 900_Tootja: -; 905_Mudel: -; 910_Tooteinfo: -; 915_Kasutus-ja_hooldusjuhend: -
AC_Pset_RenovationAndPhasing - Renovation Status: New
Name | OverallHeight (mm) | Reference = 300_Tüüp | GlazingAreaFraction | 305_Ava_mõõt | 320_Klaas | 325_Helipidavus | 355_Pindala (m2)
Kahepoolne siseuks | 3400 | SU-419-p | 7.62581 | 2,800x3,400 | Kirgas, klaas | 25 dB | 9.52
Kahepoolne siseuks | 3200 | SU-421-p | 7.07692 | 2,800x3,200 | Kirgas, karastatud | 35 dB | 8.96

# IfcDoor: Exterior Sliding Door 25 (3)
In: 1. korrus
Type - OperationType: SLIDING_TO_LEFT; ParameterTakesPrecedence: no; Sizeable: no
Type - Door Panel Properties - Panel 1 - PanelDepth: 40 mm; PanelOperation: SLIDING; PanelWidth: 1; PanelPosition: MIDDLE
OverallHeight: 2300 mm; Classification: 1.10 IfcDoorStyle (uks) (RKAS BIM + ARCHICAD Classification)
Pset_DoorCommon - ThermalTransmittance: 0; IsExternal: no
AR_Uks - 001_Nimetus: Siseuks; 315_Avanemine: Lükanduks - Parem ; ARCHICAD tüüp: External Sliding; 320_Klaas: -; 325_Helipidavus: nõudeid ei esitata; 330_Tulekindlus: nõudeid ei esitata; 335_Välispiire: no; 340_Soojusläbivus: 0; 345_Päikesekiirgus_tegur: Nõudeid ei esitata; 350_Klaaspakett: -; 360_Ratastooliga: no; 365_Isesulguv: no; 370_Evakuatsiooniväljapääs: no; 380_Lukustus: Nupust avanev; 900_Tootja: -; 905_Mudel: -; 910_Tooteinfo: -; 915_Kasutus-ja_hooldusjuhend: -
AC_Pset_RenovationAndPhasing - Renovation Status: New
Name | OverallWidth (mm) | Reference = 300_Tüüp | 305_Ava_mõõt | 310_Materjal | 355_Pindala (m2) | 375_Viimistlus_seest | 376_Viimistlus_väljast
Siseuks | 900 | SU-506-p | 900x2,300 | MUDELIS: väljast-PUIT- kuusk H; PUIT- kuusk H; seest-PUIT- kuusk H; PUIT- kuusk H; MÄRKUS: Kuumtsingitud teras, 1mm | 2.07 | Leng: PUIT- kuusk H; Ukseleht: PUIT- kuusk H; MÄRKUS: Pulbervärv, värvi toon vastavalt sanruumi tarnitavale keraamilisele plaadile. | Leng: PUIT- kuusk H; Ukseleht: PUIT- kuusk H; MÄRKUS: -
2 x Siseuks | 1000 | SU-504-p | 1 000x2 300 | MUDELIS: väljast-PUIT- kuusk H; PUIT- kuusk H; seest-PUIT- kuusk H; PUIT- kuusk H; MÄRKUS: Täispuit ukseserv, fassaad spoonitud 8mm HDF, oksakuusk | 2.3 | Leng: PUIT- kuusk H; Ukseleht: PUIT- kuusk H; MÄRKUS: Toonitud matt lakk | Leng: PUIT- kuusk H; Ukseleht: PUIT- kuusk H; MÄRKUS: Toonitud matt lakk

# IfcDoor: Movable Wall 25, Siirdesein
In: 1. korrus
Type - ParameterTakesPrecedence: no; Sizeable: no
Classification: 1.10 IfcDoorStyle (uks) (RKAS BIM + ARCHICAD Classification); Material: _PLASTIK
Pset_DoorCommon - Reference: SU-501; IsExternal: no
AR_Uks - 001_Nimetus: Siirdesein; 300_Tüüp: SU-501; 305_Ava_mõõt: 0,98x3,20; 310_Materjal: Alum raam, mdf; 315_Avanemine: Lukatavad paneelid; 320_Klaas: -; 325_Helipidavus: 52 dB; 330_Tulekindlus: nõudeid ei esitata; 335_Välispiire: no; 340_Soojusläbivus: 0; 345_Päikesekiirgus_tegur: -; 350_Klaaspakett: -; 360_Ratastooliga: yes; 365_Isesulguv: no; 370_Evakuatsiooniväljapääs: no; 375_Viimistlus_seest: Õpetajate toa pool kuuse oksaspoon, matt lakk. Konverentsiruumi poolsel küljel valge markeriga kirjutatav magnetlaminaat.; 376_Viimistlus_väljast: -; 380_Lukustus: vt lukustuse projekt; 900_Tootja: Wallenium Dorma Hüppe; 905_Mudel: Variflex100; 910_Tooteinfo: -; 915_Kasutus-ja_hooldusjuhend: -
AC_Pset_RenovationAndPhasing - Renovation Status: New

# IfcDoor: Sliding Folding Multipanel Bifold Door 25, Siirdesein
In: 1. korrus
Type - OperationType: DOUBLE_DOOR_FOLDING; ParameterTakesPrecedence: no; Sizeable: no
Type - Door Lining Properties - LiningDepth: 115 mm; LiningThickness: 40 mm; LiningOffset: 125 mm
Type - Door Panel Properties - Panel 1 - PanelDepth: 50 mm; PanelOperation: FOLDING; PanelWidth: 0.0756961; PanelPosition: RIGHT
Type - Door Panel Properties - Panel 2 - PanelDepth: 50 mm; PanelOperation: FOLDING; PanelWidth: 0.151392; PanelPosition: RIGHT
Type - Door Panel Properties - Panel 3 - PanelDepth: 50 mm; PanelOperation: FOLDING; PanelWidth: 0.151392; PanelPosition: RIGHT
Type - Door Panel Properties - Panel 4 - PanelDepth: 50 mm; PanelOperation: FOLDING; PanelWidth: 0.151392; PanelPosition: RIGHT
Type - Door Panel Properties - Panel 5 - PanelDepth: 50 mm; PanelOperation: FOLDING; PanelWidth: 0.151392; PanelPosition: LEFT
Type - Door Panel Properties - Panel 6 - PanelDepth: 50 mm; PanelOperation: FOLDING; PanelWidth: 0.151392; PanelPosition: LEFT
Type - Door Panel Properties - Panel 7 - PanelDepth: 50 mm; PanelOperation: FOLDING; PanelWidth: 0.151392; PanelPosition: LEFT
Type - Door Panel Properties - Panel 8 - PanelDepth: 50 mm; PanelOperation: FOLDING; PanelWidth: 0.0756961; PanelPosition: LEFT
OverallHeight: 2800 mm; OverallWidth: 7175 mm; Classification: 1.10 IfcDoorStyle (uks) (RKAS BIM + ARCHICAD Classification)
Pset_DoorCommon - Reference: SU-503; ThermalTransmittance: 0; IsExternal: no
AR_Uks - 001_Nimetus: Siirdesein; 300_Tüüp: SU-503; 305_Ava_mõõt: 7,175x2,800; 310_Materjal: MUDELIS: väljast-TOON- RAL 9003 valge; TOON- RAL 9003 valge; seest-TOON- RAL 9003 valge; TOON- RAL 9003 valge; MÄRKUS: Alum raam, kaetud kolmekihilise ristkihtliimpuiduga; 315_Avanemine: Siirdesein ; ARCHICAD tüüp: Double Sliding Folding Multi-panel; 320_Klaas: -; 325_Helipidavus: 52 dB; 330_Tulekindlus: nõudeid ei esitata; 335_Välispiire: no; 340_Soojusläbivus: 0; 345_Päikesekiirgus_tegur: Nõudeid ei esitata; 350_Klaaspakett: -; 355_Pindala: 20.09 m2; 360_Ratastooliga: no; 365_Isesulguv: no; 370_Evakuatsiooniväljapääs: no; 375_Viimistlus_seest: Leng: TOON- RAL 9003 valge; Ukseleht: TOON- RAL 9003 valge; MÄRKUS: Valge kirjutatav magnetlaminaat, metallosad pulbervärvitud valge; 376_Viimistlus_väljast: Leng: TOON- RAL 9003 valge; Ukseleht: TOON- RAL 9003 valge; MÄRKUS: -; 380_Lukustus: vt lukustuse projekt; 900_Tootja: Wallenium; 905_Mudel: Alatar; 910_Tooteinfo: -; 915_Kasutus-ja_hooldusjuhend: -
AC_Pset_RenovationAndPhasing - Renovation Status: New

# IfcDoor: Sliding Folding Multipanel Bifold Door 25, Siirdesein
In: 2. korrus
Type - OperationType: DOUBLE_DOOR_FOLDING; ParameterTakesPrecedence: no; Sizeable: no
Type - Door Lining Properties - LiningDepth: 115 mm; LiningThickness: 40 mm; LiningOffset: 55 mm
Type - Door Panel Properties - Panel 1 - PanelDepth: 50 mm; PanelOperation: FOLDING; PanelWidth: 0.0582036; PanelPosition: LEFT
Type - Door Panel Properties - Panel 2 - PanelDepth: 50 mm; PanelOperation: FOLDING; PanelWidth: 0.116407; PanelPosition: LEFT
Type - Door Panel Properties - Panel 3 - PanelDepth: 50 mm; PanelOperation: FOLDING; PanelWidth: 0.116407; PanelPosition: LEFT
Type - Door Panel Properties - Panel 4 - PanelDepth: 50 mm; PanelOperation: FOLDING; PanelWidth: 0.116407; PanelPosition: LEFT
Type - Door Panel Properties - Panel 5 - PanelDepth: 50 mm; PanelOperation: FOLDING; PanelWidth: 0.116407; PanelPosition: LEFT
Type - Door Panel Properties - Panel 6 - PanelDepth: 50 mm; PanelOperation: FOLDING; PanelWidth: 0.116407; PanelPosition: RIGHT
Type - Door Panel Properties - Panel 7 - PanelDepth: 50 mm; PanelOperation: FOLDING; PanelWidth: 0.116407; PanelPosition: RIGHT
Type - Door Panel Properties - Panel 8 - PanelDepth: 50 mm; PanelOperation: FOLDING; PanelWidth: 0.116407; PanelPosition: RIGHT
Type - Door Panel Properties - Panel 9 - PanelDepth: 50 mm; PanelOperation: FOLDING; PanelWidth: 0.116407; PanelPosition: RIGHT
Type - Door Panel Properties - Panel 10 - PanelDepth: 50 mm; PanelOperation: FOLDING; PanelWidth: 0.0582036; PanelPosition: RIGHT
OverallHeight: 2600 mm; OverallWidth: 11070.1 mm; Classification: 1.10 IfcDoorStyle (uks) (RKAS BIM + ARCHICAD Classification)
Pset_DoorCommon - Reference: SU-502; ThermalTransmittance: 0; IsExternal: no
AR_Uks - 001_Nimetus: Siirdesein; 300_Tüüp: SU-502; 305_Ava_mõõt: 11,070x2,600; 310_Materjal: MUDELIS: väljast-TOON- RAL 9003 valge; TOON- RAL 9003 valge; seest-TOON- RAL 9003 valge; TOON- RAL 9003 valge; MÄRKUS: Alum raam, kilp; 315_Avanemine: Siirdesein ; ARCHICAD tüüp: Double Sliding Folding Multi-panel; 320_Klaas: -; 325_Helipidavus: 52 dB; 330_Tulekindlus: nõudeid ei esitata; 335_Välispiire: no; 340_Soojusläbivus: 0; 345_Päikesekiirgus_tegur: Nõudeid ei esitata; 350_Klaaspakett: -; 355_Pindala: 28.7822 m2; 360_Ratastooliga: no; 365_Isesulguv: no; 370_Evakuatsiooniväljapääs: no; 375_Viimistlus_seest: Leng: TOON- RAL 9003 valge; Ukseleht: TOON- RAL 9003 valge; MÄRKUS: Valge kirjutatav magnetlaminaat, metallosad pulbervärvitud valge; 376_Viimistlus_väljast: Leng: TOON- RAL 9003 valge; Ukseleht: TOON- RAL 9003 valge; MÄRKUS: -; 380_Lukustus: vt lukustuse projekt; 900_Tootja: Wallenium; 905_Mudel: Alatar; 910_Tooteinfo: -; 915_Kasutus-ja_hooldusjuhend: -
AC_Pset_RenovationAndPhasing - Renovation Status: New

# IfcFlowTerminal: Fluorescent Wall Lamp 25 (138)
Classification: 1.12 IfcLightFixtureType (valgusti) (RKAS BIM + ARCHICAD Classification)
AR_Valgusti - 001_Nimetus: Fassaadivalgusti; 400_Võimsus: 31; 405_Paigaldusviis: Seina; 410_IP_klass: 66; 900_Tootja: nt. iGuzzini illuminazione S.p.A, tarnija Luminec OÜ; 910_Tooteinfo: -; 915_Kasutus-ja_hooldusjuhend: -
AR_Santehnika - 001_Nimetus: Fassaadivalgusti; 900_Tootja: nt. iGuzzini illuminazione S.p.A, tarnija Luminec OÜ; 910_Tooteinfo: -; 915_Kasutus-ja_hooldusjuhend: -
AC_Pset_RenovationAndPhasing - Renovation Status: New
Name | In | AR_Valgusti, 002_Tüüp = AR_Santehnika, 002_Tüüp = Reference | AR_Valgusti, 905_Mudel = AR_Santehnika, 905_Mudel
2 x Fassaadivalgusti | 1. korrus | FV-3 | Linealuce L63 Mini 47
42 x Fassaadivalgusti | 3. korrus | FV-1 | Linealuce L39 Mini 47
94 x Fassaadivalgusti | 4. TEHNO korrus | FV-1 | Linealuce L39 Mini 47

# IfcFlowTerminal: Spotlamp Ceiling 25 (2)
In: 2. korrus
Classification: 1.12 IfcLightFixtureType (valgusti) (RKAS BIM + ARCHICAD Classification)
AR_Valgusti - 001_Nimetus: Kunstiteose valgusti; 002_Tüüp: FV-2; 400_Võimsus: 28; 405_Paigaldusviis: Seina; 410_IP_klass: 65; 900_Tootja: nt. Meyer + Sohn, tarnija Luminec OÜ; 905_Mudel: Monospot 3, silver grey; 910_Tooteinfo: -; 915_Kasutus-ja_hooldusjuhend: -
AR_Santehnika - 001_Nimetus: Kunstiteose valgusti; 002_Tüüp: FV-2; 900_Tootja: nt. Meyer + Sohn, tarnija Luminec OÜ; 905_Mudel: Monospot 3, silver grey; 910_Tooteinfo: -; 915_Kasutus-ja_hooldusjuhend: -
Pset_DistributionFlowElementCommon - Reference: FV-2
AC_Pset_RenovationAndPhasing - Renovation Status: New

# IfcMember: 120 x 120 (6)
In: 1. korrus
Type - PredefinedType: MULLION
Classification: Curtain Wall Frame (RKAS BIM + ARCHICAD Classification); Material: _KANDETARIND - liimpuit vastavalt EK osale
Pset_MemberCommon - Slope: 90 deg
AC_Pset_RenovationAndPhasing - Renovation Status: Undefined
Name
RF RAAM NURK-855
RF RAAM NURK-854
RF RAAM NURK-853
2 x RF RAAM NURK-852
RF RAAM NURK-864

# IfcMember: 50 x 100 (2)
In: 1. korrus
Type - PredefinedType: MEMBER
Classification: 1.13 IfcMemberType (kandev element) (RKAS BIM + ARCHICAD Classification); Material: _METALL - alumiinium
Pset_MemberCommon - Reference: Regular Double Frame with Cap 25; Slope: 90 deg
AR_001-002 - 002_Tüüp: Regular Double Frame with Cap 25
AC_Pset_RenovationAndPhasing - Renovation Status: Undefined
Name | 001_Nimetus
RF RAAM NURK-869 | RF RAAM NURK-869
RF RAAM NURK-875 | RF RAAM NURK-875

# IfcMember: Boundary Frame 50 x 100 (520)
Type - PredefinedType: MEMBER
Classification: 1.13 IfcMemberType (kandev element) (RKAS BIM + ARCHICAD Classification)
Pset_MemberCommon - Reference: Built-in Frame
AR_001-002 - 002_Tüüp: Built-in Frame
AC_Pset_RenovationAndPhasing - Renovation Status: Undefined
Name | In | Material | Slope (deg) | 001_Nimetus
2 x RF RAAM SERV-553 | 1. korrus | _METALL - alumiinium | 0 | RF RAAM SERV-553
RF RAAM SERV-534 | 1. korrus | _METALL - alumiinium | 0 | RF RAAM SERV-534
2 x RF RAAM SERV-554 | 1. korrus | _METALL - alumiinium | 0 | RF RAAM SERV-554
2 x RF RAAM SERV-555 | 1. korrus | _METALL - alumiinium | 0 | RF RAAM SERV-555
2 x RF RAAM SERV-556 | 1. korrus | _METALL - alumiinium | 0 | RF RAAM SERV-556
2 x RF RAAM SERV-557 | 1. korrus | _METALL - alumiinium | 0 | RF RAAM SERV-557
2 x RF RAAM SERV-558 | 1. korrus | _METALL - alumiinium | 0 | RF RAAM SERV-558
2 x RF RAAM SERV-559 | 1. korrus | _METALL - alumiinium | 0 | RF RAAM SERV-559
2 x RF RAAM SERV-560 | 1. korrus | _METALL - alumiinium | 0 | RF RAAM SERV-560
2 x RF RAAM SERV-561 | 1. korrus | _METALL - alumiinium | 0 | RF RAAM SERV-561
2 x RF RAAM SERV-408 | 1. korrus | _METALL - alumiinium | 0 | RF RAAM SERV-408
RF RAAM SERV-589 | 1. korrus | _METALL - alumiinium | 0 | RF RAAM SERV-589
RF RAAM SERV-590 | 1. korrus | _METALL - alumiinium | 0 | RF RAAM SERV-590
RF RAAM SERV-591 | 1. korrus | _METALL - alumiinium | 0 | RF RAAM SERV-591
RF RAAM SERV-592 | 1. korrus | _METALL - alumiinium | 0 | RF RAAM SERV-592
RF RAAM SERV-593 | 1. korrus | _METALL - alumiinium | 0 | RF RAAM SERV-593
RF RAAM SERV-594 | 1. korrus | _METALL - alumiinium | 0 | RF RAAM SERV-594
RF RAAM SERV-595 | 1. korrus | _METALL - alumiinium | 0 | RF RAAM SERV-595
RF RAAM SERV-596 | 1. korrus | _METALL - alumiinium | 0 | RF RAAM SERV-596
RF RAAM SERV-597 | 1. korrus | _METALL - alumiinium | 0 | RF RAAM SERV-597
RF RAAM SERV-598 | 1. korrus | _METALL - alumiinium | 0 | RF RAAM SERV-598
RF RAAM SERV-599 | 1. korrus | _METALL - alumiinium | 0 | RF RAAM SERV-599
RF RAAM SERV-600 | 1. korrus | _METALL - alumiinium | 0 | RF RAAM SERV-600
RF RAAM SERV-601 | 1. korrus | _METALL - alumiinium | 0 | RF RAAM SERV-601
RF RAAM SERV-602 | 1. korrus | _METALL - alumiinium | 0 | RF RAAM SERV-602
RF RAAM SERV-603 | 1. korrus | _METALL - alumiinium | 0 | RF RAAM SERV-603
RF RAAM SERV-604 | 1. korrus | _METALL - alumiinium | 0 | RF RAAM SERV-604
RF RAAM SERV-605 | 1. korrus | _METALL - alumiinium | 0 | RF RAAM SERV-605
RF RAAM SERV-635 | 1. korrus | _METALL - alumiinium | 0 | RF RAAM SERV-635
2 x RF RAAM SERV-636 | 1. korrus | _METALL - alumiinium | 0 | RF RAAM SERV-636
2 x RF RAAM SERV-637 | 1. korrus | _METALL - alumiinium | 0 | RF RAAM SERV-637
2 x RF RAAM SERV-638 | 1. korrus | _METALL - alumiinium | 0 | RF RAAM SERV-638
2 x RF RAAM SERV-639 | 1. korrus | _METALL - alumiinium | 0 | RF RAAM SERV-639
2 x RF RAAM SERV-640 | 1. korrus | _METALL - alumiinium | 0 | RF RAAM SERV-640
2 x RF RAAM SERV-641 | 1. korrus | _METALL - alumiinium | 0 | RF RAAM SERV-641
2 x RF RAAM SERV-642 | 1. korrus | _METALL - alumiinium | 0 | RF RAAM SERV-642
RF RAAM SERV-533 | 1. korrus | _METALL - alumiinium | 0 | RF RAAM SERV-533
RF RAAM SERV-643 | 1. korrus | _METALL - alumiinium | 0 | RF RAAM SERV-643
RF RAAM SERV-529 | 1. korrus | _METALL - alumiinium | 0 | RF RAAM SERV-529
RF RAAM SERV-551 | 1. korrus | _METALL - alumiinium | 90 | RF RAAM SERV-551
RF RAAM SERV-550 | 1. korrus | _METALL - alumiinium | 90 | RF RAAM SERV-550
RF RAAM SERV-549 | 1. korrus | _METALL - alumiinium | 90 | RF RAAM SERV-549
RF RAAM SERV-548 | 1. korrus | _METALL - alumiinium | 90 | RF RAAM SERV-548
RF RAAM SERV-552 | 1. korrus | _METALL - alumiinium | 90 | RF RAAM SERV-552
RF RAAM SERV-530 | 1. korrus | _METALL - alumiinium | 0 | RF RAAM SERV-530
RF RAAM SERV-547 | 1. korrus | _METALL - alumiinium | 90 | RF RAAM SERV-547
RF RAAM SERV-546 | 1. korrus | _METALL - alumiinium | 0.00000575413 | RF RAAM SERV-546
2 x RF RAAM SERV-545 | 1. korrus | _METALL - alumiinium | 0.00000114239 | RF RAAM SERV-545
2 x RF RAAM SERV-544 | 1. korrus | _METALL - alumiinium | 0.00000440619 | RF RAAM SERV-544
2 x RF RAAM SERV-543 | 1. korrus | _METALL - alumiinium | 0.00000440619 | RF RAAM SERV-543
2 x RF RAAM SERV-542 | 1. korrus | _METALL - alumiinium | 0.00000440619 | RF RAAM SERV-542
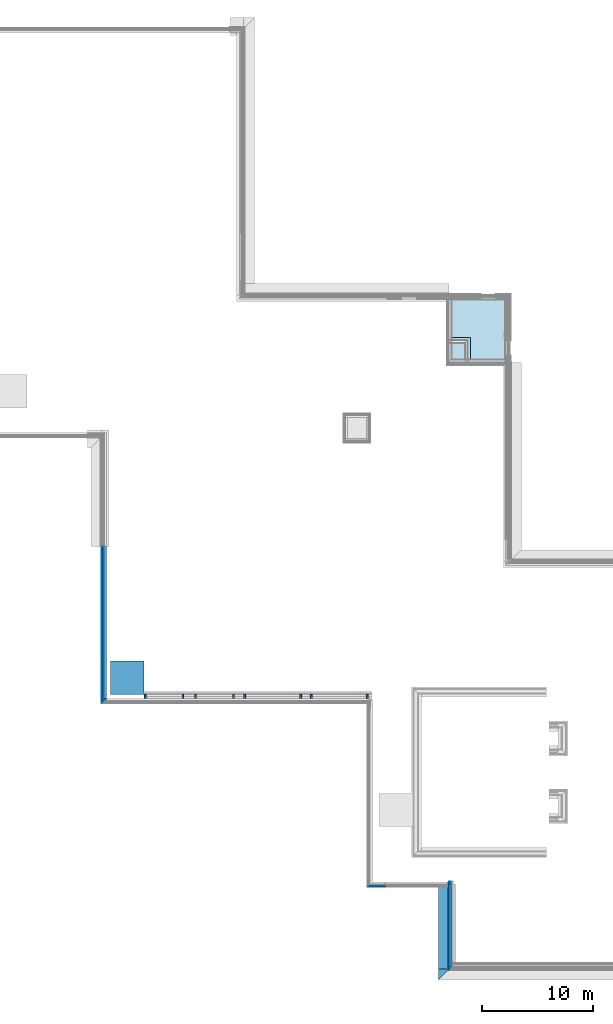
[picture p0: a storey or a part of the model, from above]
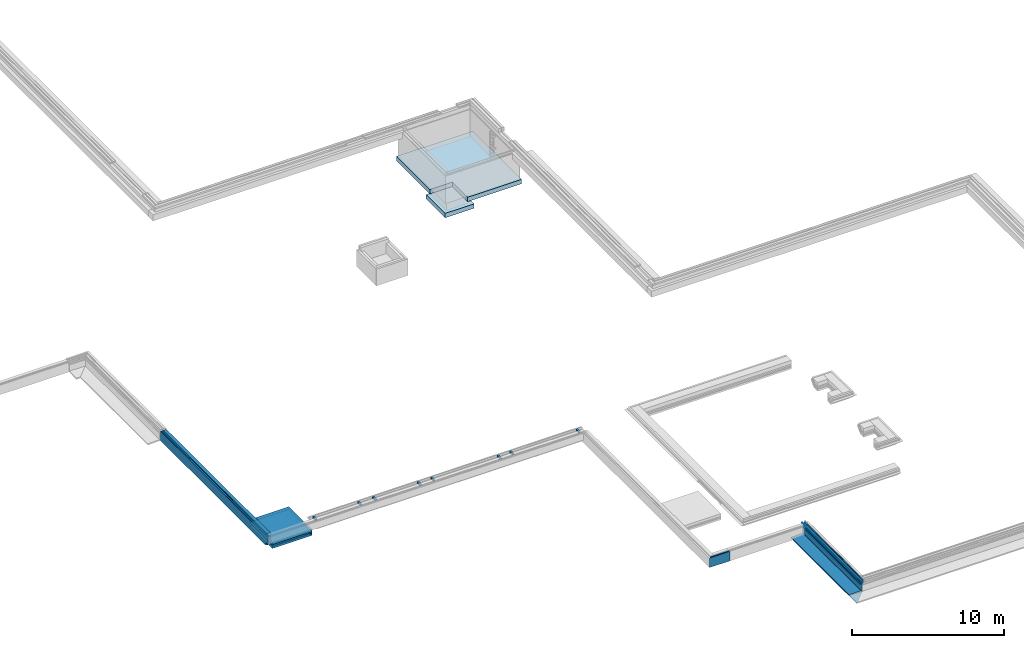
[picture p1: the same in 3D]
Properties of the parts of a building model (IFC2X3), part 6 of 14

# IfcMember: Boundary Frame 50 x 100 (520)
Name | In | Material | Slope (deg) | 001_Nimetus
RF RAAM SERV-541 | 1. korrus | _METALL - alumiinium | 0 | RF RAAM SERV-541
2 x RF RAAM SERV-582 | 1. korrus | _METALL - alumiinium | 0 | RF RAAM SERV-582
2 x RF RAAM SERV-581 | 1. korrus | _METALL - alumiinium | 0 | RF RAAM SERV-581
2 x RF RAAM SERV-580 | 1. korrus | _METALL - alumiinium | 0 | RF RAAM SERV-580
2 x RF RAAM SERV-579 | 1. korrus | _METALL - alumiinium | 0 | RF RAAM SERV-579
2 x RF RAAM SERV-578 | 1. korrus | _METALL - alumiinium | 0 | RF RAAM SERV-578
2 x RF RAAM SERV-577 | 1. korrus | _METALL - alumiinium | 0 | RF RAAM SERV-577
2 x RF RAAM SERV-576 | 1. korrus | _METALL - alumiinium | 0 | RF RAAM SERV-576
2 x RF RAAM SERV-575 | 1. korrus | _METALL - alumiinium | 0 | RF RAAM SERV-575
2 x RF RAAM SERV-574 | 1. korrus | _METALL - alumiinium | 0 | RF RAAM SERV-574
2 x RF RAAM SERV-573 | 1. korrus | _METALL - alumiinium | 0 | RF RAAM SERV-573
2 x RF RAAM SERV-572 | 1. korrus | _METALL - alumiinium | 0 | RF RAAM SERV-572
RF RAAM SERV-571 | 1. korrus | _METALL - alumiinium | 0 | RF RAAM SERV-571
RF RAAM SERV-628 | 1. korrus | _METALL - alumiinium | 0 | RF RAAM SERV-628
RF RAAM SERV-627 | 1. korrus | _METALL - alumiinium | 0 | RF RAAM SERV-627
RF RAAM SERV-626 | 1. korrus | _METALL - alumiinium | 0 | RF RAAM SERV-626
RF RAAM SERV-625 | 1. korrus | _METALL - alumiinium | 0 | RF RAAM SERV-625
RF RAAM SERV-624 | 1. korrus | _METALL - alumiinium | 0 | RF RAAM SERV-624
RF RAAM SERV-623 | 1. korrus | _METALL - alumiinium | 0 | RF RAAM SERV-623
RF RAAM SERV-622 | 1. korrus | _METALL - alumiinium | 0 | RF RAAM SERV-622
RF RAAM SERV-621 | 1. korrus | _METALL - alumiinium | 0 | RF RAAM SERV-621
RF RAAM SERV-620 | 1. korrus | _METALL - alumiinium | 0 | RF RAAM SERV-620
RF RAAM SERV-619 | 1. korrus | _METALL - alumiinium | 0 | RF RAAM SERV-619
RF RAAM SERV-618 | 1. korrus | _METALL - alumiinium | 0 | RF RAAM SERV-618
RF RAAM SERV-617 | 1. korrus | _METALL - alumiinium | 0 | RF RAAM SERV-617
RF RAAM SERV-616 | 1. korrus | _METALL - alumiinium | 0 | RF RAAM SERV-616
RF RAAM SERV-615 | 1. korrus | _METALL - alumiinium | 0 | RF RAAM SERV-615
RF RAAM SERV-614 | 1. korrus | _METALL - alumiinium | 0 | RF RAAM SERV-614
RF RAAM SERV-613 | 1. korrus | _METALL - alumiinium | 0 | RF RAAM SERV-613
RF RAAM SERV-612 | 1. korrus | _METALL - alumiinium | 0 | RF RAAM SERV-612
RF RAAM SERV-662 | 1. korrus | _METALL - alumiinium | 0 | RF RAAM SERV-662
2 x RF RAAM SERV-661 | 1. korrus | _METALL - alumiinium | 0 | RF RAAM SERV-661
2 x RF RAAM SERV-660 | 1. korrus | _METALL - alumiinium | 0 | RF RAAM SERV-660
2 x RF RAAM SERV-659 | 1. korrus | _METALL - alumiinium | 0 | RF RAAM SERV-659
2 x RF RAAM SERV-658 | 1. korrus | _METALL - alumiinium | 0 | RF RAAM SERV-658
2 x RF RAAM SERV-657 | 1. korrus | _METALL - alumiinium | 0 | RF RAAM SERV-657
2 x RF RAAM SERV-656 | 1. korrus | _METALL - alumiinium | 0 | RF RAAM SERV-656
2 x RF RAAM SERV-655 | 1. korrus | _METALL - alumiinium | 0 | RF RAAM SERV-655
2 x RF RAAM SERV-654 | 1. korrus | _METALL - alumiinium | 0 | RF RAAM SERV-654
2 x RF RAAM SERV-653 | 1. korrus | _METALL - alumiinium | 0 | RF RAAM SERV-653
RF RAAM SERV-652 | 1. korrus | _METALL - alumiinium | 0.0000042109 | RF RAAM SERV-652
RF RAAM SERV-645 | 1. korrus | _METALL - alumiinium | 0 | RF RAAM SERV-645
RF RAAM SERV-651 | 1. korrus | _METALL - alumiinium | 90 | RF RAAM SERV-651
RF RAAM SERV-650 | 1. korrus | _METALL - alumiinium | 90 | RF RAAM SERV-650
RF RAAM SERV-649 | 1. korrus | _METALL - alumiinium | 90 | RF RAAM SERV-649
RF RAAM SERV-648 | 1. korrus | _METALL - alumiinium | 90 | RF RAAM SERV-648
RF RAAM SERV-647 | 1. korrus | _METALL - alumiinium | 90 | RF RAAM SERV-647
RF RAAM SERV-646 | 1. korrus | _METALL - alumiinium | 90 | RF RAAM SERV-646
RF RAAM SERV-702 | 1. korrus | _METALL - alumiinium | 0 | RF RAAM SERV-702
RF RAAM SERV-703 | 1. korrus | _METALL - alumiinium | 0 | RF RAAM SERV-703
RF RAAM SERV-704 | 1. korrus | _METALL - alumiinium | 0 | RF RAAM SERV-704
RF RAAM SERV-707 | 1. korrus | _METALL - alumiinium | 0 | RF RAAM SERV-707
RF RAAM SERV-721 | 1. korrus | _METALL - alumiinium | 90 | RF RAAM SERV-721
RF RAAM SERV-701 | 1. korrus | _METALL - alumiinium | 0 | RF RAAM SERV-701
RF RAAM SERV-722 | 1. korrus | _METALL - alumiinium | 90 | RF RAAM SERV-722
RF RAAM SERV-710 | 1. korrus | _METALL - alumiinium | 90 | RF RAAM SERV-710
RF RAAM SERV-709 | 1. korrus | _METALL - alumiinium | 90 | RF RAAM SERV-709
RF RAAM SERV-708 | 1. korrus | _METALL - alumiinium | 0 | RF RAAM SERV-708
RF RAAM SERV-720 | 1. korrus | _METALL - alumiinium | 90 | RF RAAM SERV-720
RF RAAM SERV-719 | 1. korrus | _METALL - alumiinium | 0 | RF RAAM SERV-719
RF RAAM SERV-718 | 1. korrus | _METALL - alumiinium | 0.00000271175 | RF RAAM SERV-718
RF RAAM SERV-717 | 1. korrus | _METALL - alumiinium | 0 | RF RAAM SERV-717
RF RAAM SERV-716 | 1. korrus | _METALL - alumiinium | 0 | RF RAAM SERV-716
RF RAAM SERV-715 | 1. korrus | _METALL - alumiinium | 0 | RF RAAM SERV-715
RF RAAM SERV-714 | 1. korrus | _METALL - alumiinium | 0 | RF RAAM SERV-714
RF RAAM SERV-713 | 1. korrus | _METALL - alumiinium | 0 | RF RAAM SERV-713
RF RAAM SERV-712 | 1. korrus | _METALL - alumiinium | 0.00000124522 | RF RAAM SERV-712
RF RAAM SERV-711 | 1. korrus | _METALL - alumiinium | 90 | RF RAAM SERV-711
RF RAAM SERV-076 | 1. korrus | _METALL - alumiinium | 0 | RF RAAM SERV-076
RF RAAM SERV-077 | 1. korrus | _METALL - alumiinium | 0 | RF RAAM SERV-077
RF RAAM SERV-078 | 1. korrus | _METALL - alumiinium | 0 | RF RAAM SERV-078
RF RAAM SERV-079 | 1. korrus | _METALL - alumiinium | 0 | RF RAAM SERV-079
RF RAAM SERV-080 | 1. korrus | _METALL - alumiinium | 0 | RF RAAM SERV-080
RF RAAM SERV-081 | 1. korrus | _METALL - alumiinium | 0 | RF RAAM SERV-081
RF RAAM SERV-082 | 1. korrus | _METALL - alumiinium | 0 | RF RAAM SERV-082
RF RAAM SERV-083 | 1. korrus | _METALL - alumiinium | 0 | RF RAAM SERV-083
RF RAAM SERV-084 | 1. korrus | _METALL - alumiinium | 0 | RF RAAM SERV-084
RF RAAM SERV-085 | 1. korrus | _METALL - alumiinium | 0 | RF RAAM SERV-085
RF RAAM SERV-086 | 1. korrus | _METALL - alumiinium | 0 | RF RAAM SERV-086
RF RAAM SERV-087 | 1. korrus | _METALL - alumiinium | 0 | RF RAAM SERV-087
RF RAAM SERV-088 | 1. korrus | _METALL - alumiinium | 0 | RF RAAM SERV-088
RF RAAM SERV-089 | 1. korrus | _METALL - alumiinium | 0 | RF RAAM SERV-089
RF RAAM SERV-090 | 1. korrus | _METALL - alumiinium | 0 | RF RAAM SERV-090
RF RAAM SERV-091 | 1. korrus | _METALL - alumiinium | 0 | RF RAAM SERV-091
RF RAAM SERV-097 | 1. korrus | _METALL - alumiinium | 90 | RF RAAM SERV-097
RF RAAM SERV-096 | 1. korrus | _METALL - alumiinium | 90 | RF RAAM SERV-096
RF RAAM SERV-095 | 1. korrus | _METALL - alumiinium | 90 | RF RAAM SERV-095
RF RAAM SERV-094 | 1. korrus | _METALL - alumiinium | 0 | RF RAAM SERV-094
RF RAAM SERV-123 | 1. korrus | _METALL - alumiinium | 90 | RF RAAM SERV-123
RF RAAM SERV-122 | 1. korrus | _METALL - alumiinium | 90 | RF RAAM SERV-122
RF RAAM SERV-121 | 1. korrus | _METALL - alumiinium | 90 | RF RAAM SERV-121
RF RAAM SERV-120 | 1. korrus | _METALL - alumiinium | 90 | RF RAAM SERV-120
RF RAAM SERV-098 | 1. korrus | _METALL - alumiinium | 90 | RF RAAM SERV-098
RF RAAM SERV-119 | 1. korrus | _METALL - alumiinium | 0 | RF RAAM SERV-119
RF RAAM SERV-118 | 1. korrus | _METALL - alumiinium | 0 | RF RAAM SERV-118
RF RAAM SERV-117 | 1. korrus | _METALL - alumiinium | 0 | RF RAAM SERV-117
RF RAAM SERV-116 | 1. korrus | _METALL - alumiinium | 0 | RF RAAM SERV-116
RF RAAM SERV-115 | 1. korrus | _METALL - alumiinium | 0 | RF RAAM SERV-115
RF RAAM SERV-114 | 1. korrus | _METALL - alumiinium | 0 | RF RAAM SERV-114
RF RAAM SERV-113 | 1. korrus | _METALL - alumiinium | 0 | RF RAAM SERV-113
RF RAAM SERV-112 | 1. korrus | _METALL - alumiinium | 0 | RF RAAM SERV-112
RF RAAM SERV-111 | 1. korrus | _METALL - alumiinium | 0 | RF RAAM SERV-111
RF RAAM SERV-110 | 1. korrus | _METALL - alumiinium | 0 | RF RAAM SERV-110
RF RAAM SERV-109 | 1. korrus | _METALL - alumiinium | 0 | RF RAAM SERV-109
RF RAAM SERV-108 | 1. korrus | _METALL - alumiinium | 0 | RF RAAM SERV-108
RF RAAM SERV-107 | 1. korrus | _METALL - alumiinium | 0 | RF RAAM SERV-107
RF RAAM SERV-106 | 1. korrus | _METALL - alumiinium | 0 | RF RAAM SERV-106
RF RAAM SERV-105 | 1. korrus | _METALL - alumiinium | 0 | RF RAAM SERV-105
RF RAAM SERV-104 | 1. korrus | _METALL - alumiinium | 0 | RF RAAM SERV-104
RF RAAM SERV-103 | 1. korrus | _METALL - alumiinium | 0 | RF RAAM SERV-103
RF RAAM SERV-102 | 1. korrus | _METALL - alumiinium | 0 | RF RAAM SERV-102
RF RAAM SERV-101 | 1. korrus | _METALL - alumiinium | 0 | RF RAAM SERV-101
RF RAAM SERV-100 | 1. korrus | _METALL - alumiinium | 0 | RF RAAM SERV-100
RF RAAM SERV-099 | 1. korrus | _METALL - alumiinium | 0 | RF RAAM SERV-099
RF RAAM SERV-752 | 1. korrus | _METALL - alumiinium | 0 | RF RAAM SERV-752
RF RAAM SERV-761 | 1. korrus | _METALL - alumiinium | 90 | RF RAAM SERV-761
RF RAAM SERV-763 | 1. korrus | _METALL - alumiinium | 90 | RF RAAM SERV-763
RF RAAM SERV-762 | 1. korrus | _METALL - alumiinium | 90 | RF RAAM SERV-762
RF RAAM SERV-757 | 1. korrus | _METALL - alumiinium | 90 | RF RAAM SERV-757
RF RAAM SERV-756 | 1. korrus | _METALL - alumiinium | 90 | RF RAAM SERV-756
RF RAAM SERV-755 | 1. korrus | _METALL - alumiinium | 90 | RF RAAM SERV-755
RF RAAM SERV-754 | 1. korrus | _METALL - alumiinium | 0 | RF RAAM SERV-754
RF RAAM SERV-760 | 1. korrus | _METALL - alumiinium | 0 | RF RAAM SERV-760
RF RAAM SERV-759 | 1. korrus | _METALL - alumiinium | 0 | RF RAAM SERV-759
RF RAAM SERV-758 | 1. korrus | _METALL - alumiinium | 0 | RF RAAM SERV-758
RF RAAM SERV-198 | 1. korrus | _GENEERILINE MATERJAL | 0 | RF RAAM SERV-198
2 x RF RAAM SERV-199 | 1. korrus | _GENEERILINE MATERJAL | 0 | RF RAAM SERV-199
RF RAAM SERV-196 | 1. korrus | _GENEERILINE MATERJAL | 0 | RF RAAM SERV-196
RF RAAM SERV-195 | 1. korrus | _GENEERILINE MATERJAL | 0 | RF RAAM SERV-195
RF RAAM SERV-201 | 1. korrus | _GENEERILINE MATERJAL | 90 | RF RAAM SERV-201
RF RAAM SERV-200 | 1. korrus | _GENEERILINE MATERJAL | 0 | RF RAAM SERV-200
RF RAAM SERV-210 | 1. korrus | _GENEERILINE MATERJAL | 90 | RF RAAM SERV-210
RF RAAM SERV-209 | 1. korrus | _GENEERILINE MATERJAL | 90 | RF RAAM SERV-209
RF RAAM SERV-208 | 1. korrus | _GENEERILINE MATERJAL | 0 | RF RAAM SERV-208
RF RAAM SERV-207 | 1. korrus | _GENEERILINE MATERJAL | 6.66875e-07 | RF RAAM SERV-207
RF RAAM SERV-206 | 1. korrus | _GENEERILINE MATERJAL | 0 | RF RAAM SERV-206
RF RAAM SERV-205 | 1. korrus | _GENEERILINE MATERJAL | 0 | RF RAAM SERV-205
RF RAAM SERV-204 | 1. korrus | _GENEERILINE MATERJAL | 0 | RF RAAM SERV-204
RF RAAM SERV-203 | 1. korrus | _GENEERILINE MATERJAL | 2.0146e-07 | RF RAAM SERV-203
RF RAAM SERV-202 | 1. korrus | _GENEERILINE MATERJAL | 90 | RF RAAM SERV-202
RF RAAM SERV-212 | 1. korrus | _GENEERILINE MATERJAL | 6.66875e-07 | RF RAAM SERV-212
RF RAAM SERV-213 | 1. korrus | _GENEERILINE MATERJAL | 0 | RF RAAM SERV-213
RF RAAM SERV-214 | 1. korrus | _GENEERILINE MATERJAL | 0 | RF RAAM SERV-214
RF RAAM SERV-130 | 1. korrus | _GENEERILINE MATERJAL | 0 | RF RAAM SERV-130
RF RAAM SERV-139 | 1. korrus | _GENEERILINE MATERJAL | 0 | RF RAAM SERV-139
RF RAAM SERV-138 | 1. korrus | _GENEERILINE MATERJAL | 0 | RF RAAM SERV-138
RF RAAM SERV-134 | 1. korrus | _GENEERILINE MATERJAL | 0 | RF RAAM SERV-134
RF RAAM SERV-136 | 1. korrus | _GENEERILINE MATERJAL | 90 | RF RAAM SERV-136
RF RAAM SERV-135 | 1. korrus | _GENEERILINE MATERJAL | 0 | RF RAAM SERV-135
RF RAAM SERV-141 | 1. korrus | _GENEERILINE MATERJAL | 0 | RF RAAM SERV-141
RF RAAM SERV-143 | 1. korrus | _GENEERILINE MATERJAL | 0 | RF RAAM SERV-143
RF RAAM SERV-186 | 1. korrus | _GENEERILINE MATERJAL | 0 | RF RAAM SERV-186
RF RAAM SERV-193 | 1. korrus | _GENEERILINE MATERJAL | 0 | RF RAAM SERV-193
RF RAAM SERV-192 | 1. korrus | _GENEERILINE MATERJAL | 0 | RF RAAM SERV-192
RF RAAM SERV-190 | 1. korrus | _GENEERILINE MATERJAL | 0 | RF RAAM SERV-190
RF RAAM SERV-191 | 1. korrus | _GENEERILINE MATERJAL | 90 | RF RAAM SERV-191
RF RAAM SERV-188 | 1. korrus | _GENEERILINE MATERJAL | 0 | RF RAAM SERV-188
RF RAAM SERV-187 | 1. korrus | _GENEERILINE MATERJAL | 90 | RF RAAM SERV-187
RF RAAM SERV-341 | 1. korrus | _GENEERILINE MATERJAL | 0 | RF RAAM SERV-341
2 x RF RAAM SERV-343 | 1. korrus | _GENEERILINE MATERJAL | 90 | RF RAAM SERV-343
RF RAAM SERV-344 | 1. korrus | _GENEERILINE MATERJAL | 90 | RF RAAM SERV-344
RF RAAM SERV-346 | 1. korrus | _GENEERILINE MATERJAL | 0 | RF RAAM SERV-346
RF RAAM SERV-345 | 1. korrus | _GENEERILINE MATERJAL | 0 | RF RAAM SERV-345
RF RAAM SERV-348 | 1. korrus | _GENEERILINE MATERJAL | 90 | RF RAAM SERV-348
RF RAAM SERV-347 | 1. korrus | _GENEERILINE MATERJAL | 0 | RF RAAM SERV-347
2 x RF RAAM SERV-340 | 1. korrus | _GENEERILINE MATERJAL | 0 | RF RAAM SERV-340
RF RAAM SERV-339 | 1. korrus | _GENEERILINE MATERJAL | 90 | RF RAAM SERV-339
RF RAAM SERV-501 | 1. korrus | _GENEERILINE MATERJAL | 0 | RF RAAM SERV-501
RF RAAM SERV-499 | 1. korrus | _GENEERILINE MATERJAL | 0 | RF RAAM SERV-499
RF RAAM SERV-502 | 1. korrus | _GENEERILINE MATERJAL | 0 | RF RAAM SERV-502
RF RAAM SERV-500 | 1. korrus | _GENEERILINE MATERJAL | 0 | RF RAAM SERV-500
2 x RF RAAM SERV-509 | 1. korrus | _GENEERILINE MATERJAL | 0 | RF RAAM SERV-509
2 x RF RAAM SERV-508 | 1. korrus | _GENEERILINE MATERJAL | 0 | RF RAAM SERV-508
RF RAAM SERV-507 | 1. korrus | _GENEERILINE MATERJAL | 0 | RF RAAM SERV-507
RF RAAM SERV-510 | 1. korrus | _GENEERILINE MATERJAL | 0.00000896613 | RF RAAM SERV-510
RF RAAM SERV-512 | 1. korrus | _GENEERILINE MATERJAL | 90 | RF RAAM SERV-512
RF RAAM SERV-511 | 1. korrus | _GENEERILINE MATERJAL | 90 | RF RAAM SERV-511
RF RAAM SERV-506 | 1. korrus | _GENEERILINE MATERJAL | 0.0000129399 | RF RAAM SERV-506
RF RAAM SERV-505 | 1. korrus | _GENEERILINE MATERJAL | 90 | RF RAAM SERV-505
RF RAAM SERV-504 | 1. korrus | _GENEERILINE MATERJAL | 90 | RF RAAM SERV-504
RF RAAM SERV-503 | 1. korrus | _GENEERILINE MATERJAL | 0 | RF RAAM SERV-503
RF RAAM SERV-335 | 1. korrus | _GENEERILINE MATERJAL | 0 | RF RAAM SERV-335
RF RAAM SERV-337 | 1. korrus | _GENEERILINE MATERJAL | 90 | RF RAAM SERV-337
RF RAAM SERV-334 | 1. korrus | _GENEERILINE MATERJAL | 0 | RF RAAM SERV-334
RF RAAM SERV-338 | 1. korrus | _GENEERILINE MATERJAL | 90 | RF RAAM SERV-338
RF RAAM SERV-339 | 1. korrus | _GENEERILINE MATERJAL | 0 | RF RAAM SERV-339
RF RAAM SERV-341 | 1. korrus | _GENEERILINE MATERJAL | 1.713e-08 | RF RAAM SERV-341
RF RAAM SERV-342 | 1. korrus | _GENEERILINE MATERJAL | 90 | RF RAAM SERV-342
RF RAAM SERV-344 | 1. korrus | _GENEERILINE MATERJAL | 0 | RF RAAM SERV-344
RF RAAM SERV-179 | 2. korrus | _GENEERILINE MATERJAL | 0 | RF RAAM SERV-179
RF RAAM SERV-180 | 2. korrus | _GENEERILINE MATERJAL | 0 | RF RAAM SERV-180
RF RAAM SERV-185 | 2. korrus | _GENEERILINE MATERJAL | 0 | RF RAAM SERV-185
RF RAAM SERV-184 | 2. korrus | _GENEERILINE MATERJAL | 0 | RF RAAM SERV-184
RF RAAM SERV-189 | 2. korrus | _GENEERILINE MATERJAL | 0 | RF RAAM SERV-189
RF RAAM SERV-190 | 2. korrus | _GENEERILINE MATERJAL | 0 | RF RAAM SERV-190
2 x RF RAAM SERV-197 | 2. korrus | _GENEERILINE MATERJAL | 0 | RF RAAM SERV-197
RF RAAM SERV-196 | 2. korrus | _GENEERILINE MATERJAL | 0 | RF RAAM SERV-196
RF RAAM SERV-183 | 2. korrus | _GENEERILINE MATERJAL | 0 | RF RAAM SERV-183
RF RAAM SERV-181 | 2. korrus | _GENEERILINE MATERJAL | 0 | RF RAAM SERV-181
2 x RF RAAM SERV-195 | 2. korrus | _GENEERILINE MATERJAL | 0 | RF RAAM SERV-195
RF RAAM SERV-191 | 2. korrus | _GENEERILINE MATERJAL | 0 | RF RAAM SERV-191
RF RAAM SERV-177 | 2. korrus | _GENEERILINE MATERJAL | 90 | RF RAAM SERV-177
RF RAAM SERV-186 | 2. korrus | _GENEERILINE MATERJAL | 0 | RF RAAM SERV-186
RF RAAM SERV-188 | 2. korrus | _GENEERILINE MATERJAL | 0 | RF RAAM SERV-188
RF RAAM SERV-198 | 2. korrus | _GENEERILINE MATERJAL | 0 | RF RAAM SERV-198
RF RAAM SERV-194 | 2. korrus | _GENEERILINE MATERJAL | 0 | RF RAAM SERV-194
RF RAAM SERV-193 | 2. korrus | _GENEERILINE MATERJAL | 90 | RF RAAM SERV-193
RF RAAM SERV-192 | 2. korrus | _GENEERILINE MATERJAL | 0 | RF RAAM SERV-192
2 x RF RAAM SERV-199 | 2. korrus | _GENEERILINE MATERJAL | 0 | RF RAAM SERV-199
2 x RF RAAM SERV-200 | 2. korrus | _GENEERILINE MATERJAL | 0 | RF RAAM SERV-200
RF RAAM SERV-207 | 2. korrus | _GENEERILINE MATERJAL | 0 | RF RAAM SERV-207
RF RAAM SERV-208 | 2. korrus | _GENEERILINE MATERJAL | 0 | RF RAAM SERV-208
RF RAAM SERV-209 | 2. korrus | _GENEERILINE MATERJAL | 0 | RF RAAM SERV-209
RF RAAM SERV-210 | 2. korrus | _GENEERILINE MATERJAL | 0 | RF RAAM SERV-210
RF RAAM SERV-212 | 2. korrus | _GENEERILINE MATERJAL | 0 | RF RAAM SERV-212
RF RAAM SERV-657 | 2. korrus | _METALL - alumiinium | 0 | RF RAAM SERV-657
RF RAAM SERV-658 | 2. korrus | _METALL - alumiinium | 0 | RF RAAM SERV-658
2 x RF RAAM SERV-656 | 2. korrus | _METALL - alumiinium | 0 | RF RAAM SERV-656
RF RAAM SERV-655 | 2. korrus | _METALL - alumiinium | 90 | RF RAAM SERV-655
RF RAAM SERV-666 | 2. korrus | _METALL - alumiinium | 0 | RF RAAM SERV-666
2 x RF RAAM SERV-665 | 2. korrus | _METALL - alumiinium | 0 | RF RAAM SERV-665
2 x RF RAAM SERV-664 | 2. korrus | _METALL - alumiinium | 0 | RF RAAM SERV-664
2 x RF RAAM SERV-663 | 2. korrus | _METALL - alumiinium | 0 | RF RAAM SERV-663
RF RAAM SERV-659 | 2. korrus | _METALL - alumiinium | 0 | RF RAAM SERV-659
2 x RF RAAM SERV-662 | 2. korrus | _METALL - alumiinium | 0 | RF RAAM SERV-662
RF RAAM SERV-661 | 2. korrus | _METALL - alumiinium | 90 | RF RAAM SERV-661
RF RAAM SERV-660 | 2. korrus | _METALL - alumiinium | 0 | RF RAAM SERV-660
RF RAAM SERV-661 | 2. korrus | _METALL - alumiinium | 0 | RF RAAM SERV-661
RF RAAM SERV-660 | 2. korrus | _METALL - alumiinium | 90 | RF RAAM SERV-660
RF RAAM SERV-671 | 2. korrus | _METALL - alumiinium | 0 | RF RAAM SERV-671
RF RAAM SERV-670 | 2. korrus | _METALL - alumiinium | 0 | RF RAAM SERV-670
RF RAAM SERV-669 | 2. korrus | _METALL - alumiinium | 0 | RF RAAM SERV-669
RF RAAM SERV-668 | 2. korrus | _METALL - alumiinium | 0 | RF RAAM SERV-668
RF RAAM SERV-666 | 2. korrus | _METALL - alumiinium | 90 | RF RAAM SERV-666
RF RAAM SERV-667 | 2. korrus | _METALL - alumiinium | 0 | RF RAAM SERV-667
RF RAAM SERV-112 | 2. korrus | _GENEERILINE MATERJAL | 90 | RF RAAM SERV-112
RF RAAM SERV-111 | 2. korrus | _GENEERILINE MATERJAL | 0 | RF RAAM SERV-111
RF RAAM SERV-113 | 2. korrus | _GENEERILINE MATERJAL | 0 | RF RAAM SERV-113
RF RAAM SERV-124 | 2. korrus | _GENEERILINE MATERJAL | 0 | RF RAAM SERV-124
RF RAAM SERV-123 | 2. korrus | _GENEERILINE MATERJAL | 0 | RF RAAM SERV-123
RF RAAM SERV-122 | 2. korrus | _GENEERILINE MATERJAL | 0 | RF RAAM SERV-122
RF RAAM SERV-116 | 2. korrus | _GENEERILINE MATERJAL | 0 | RF RAAM SERV-116
RF RAAM SERV-117 | 2. korrus | _GENEERILINE MATERJAL | 0 | RF RAAM SERV-117
RF RAAM SERV-121 | 2. korrus | _GENEERILINE MATERJAL | 0 | RF RAAM SERV-121
RF RAAM SERV-118 | 2. korrus | _GENEERILINE MATERJAL | 0 | RF RAAM SERV-118
RF RAAM SERV-120 | 2. korrus | _GENEERILINE MATERJAL | 0 | RF RAAM SERV-120
RF RAAM SERV-119 | 2. korrus | _GENEERILINE MATERJAL | 90 | RF RAAM SERV-119
RF RAAM SERV-126 | 2. korrus | _GENEERILINE MATERJAL | 0 | RF RAAM SERV-126
RF RAAM SERV-127 | 2. korrus | _GENEERILINE MATERJAL | 0 | RF RAAM SERV-127
RF RAAM SERV-128 | 2. korrus | _GENEERILINE MATERJAL | 0 | RF RAAM SERV-128
RF RAAM SERV-494 | 2. korrus | _METALL - alumiinium | 0 | RF RAAM SERV-494
2 x RF RAAM SERV-497 | 2. korrus | _METALL - alumiinium | 0 | RF RAAM SERV-497
2 x RF RAAM SERV-503 | 2. korrus | _METALL - alumiinium | 0 | RF RAAM SERV-503
2 x RF RAAM SERV-502 | 2. korrus | _METALL - alumiinium | 0 | RF RAAM SERV-502
RF RAAM SERV-498 | 2. korrus | _METALL - alumiinium | 0 | RF RAAM SERV-498
RF RAAM SERV-501 | 2. korrus | _METALL - alumiinium | 0 | RF RAAM SERV-501
RF RAAM SERV-500 | 2. korrus | _METALL - alumiinium | 90 | RF RAAM SERV-500
RF RAAM SERV-496 | 2. korrus | _METALL - alumiinium | 0 | RF RAAM SERV-496
RF RAAM SERV-495 | 2. korrus | _METALL - alumiinium | 90 | RF RAAM SERV-495
RF RAAM SERV-712 | 2. korrus | _METALL - alumiinium | 0 | RF RAAM SERV-712
RF RAAM SERV-713 | 2. korrus | _METALL - alumiinium | 0 | RF RAAM SERV-713
RF RAAM SERV-711 | 2. korrus | _METALL - alumiinium | 0 | RF RAAM SERV-711
RF RAAM SERV-710 | 2. korrus | _METALL - alumiinium | 90 | RF RAAM SERV-710
RF RAAM SERV-721 | 2. korrus | _METALL - alumiinium | 0 | RF RAAM SERV-721
RF RAAM SERV-720 | 2. korrus | _METALL - alumiinium | 0 | RF RAAM SERV-720
RF RAAM SERV-719 | 2. korrus | _METALL - alumiinium | 0 | RF RAAM SERV-719
RF RAAM SERV-718 | 2. korrus | _METALL - alumiinium | 0 | RF RAAM SERV-718
RF RAAM SERV-714 | 2. korrus | _METALL - alumiinium | 0 | RF RAAM SERV-714
RF RAAM SERV-716 | 2. korrus | _METALL - alumiinium | 90 | RF RAAM SERV-716
RF RAAM SERV-715 | 2. korrus | _METALL - alumiinium | 0 | RF RAAM SERV-715
RF RAAM SERV-717 | 2. korrus | _METALL - alumiinium | 0 | RF RAAM SERV-717
RF RAAM SERV-647 | 2. korrus | _METALL - alumiinium | 0 | RF RAAM SERV-647
RF RAAM SERV-648 | 2. korrus | _METALL - alumiinium | 0 | RF RAAM SERV-648
RF RAAM SERV-646 | 2. korrus | _METALL - alumiinium | 0 | RF RAAM SERV-646
RF RAAM SERV-645 | 2. korrus | _METALL - alumiinium | 90 | RF RAAM SERV-645
RF RAAM SERV-655 | 2. korrus | _METALL - alumiinium | 0 | RF RAAM SERV-655
RF RAAM SERV-654 | 2. korrus | _METALL - alumiinium | 0 | RF RAAM SERV-654
RF RAAM SERV-653 | 2. korrus | _METALL - alumiinium | 0 | RF RAAM SERV-653
RF RAAM SERV-649 | 2. korrus | _METALL - alumiinium | 0 | RF RAAM SERV-649
RF RAAM SERV-652 | 2. korrus | _METALL - alumiinium | 0 | RF RAAM SERV-652
RF RAAM SERV-651 | 2. korrus | _METALL - alumiinium | 90 | RF RAAM SERV-651
RF RAAM SERV-650 | 2. korrus | _METALL - alumiinium | 0 | RF RAAM SERV-650
RF RAAM SERV-192 | 2. korrus | _KANDETARIND - puitkarkass | 0 | RF RAAM SERV-192
RF RAAM SERV-204 | 2. korrus | _KANDETARIND - puitkarkass | 0 | RF RAAM SERV-204
RF RAAM SERV-205 | 2. korrus | _KANDETARIND - puitkarkass | 90 | RF RAAM SERV-205
RF RAAM SERV-193 | 2. korrus | _KANDETARIND - puitkarkass | 0 | RF RAAM SERV-193
RF RAAM SERV-203 | 2. korrus | _KANDETARIND - puitkarkass | 0 | RF RAAM SERV-203
RF RAAM SERV-194 | 2. korrus | _KANDETARIND - puitkarkass | 0 | RF RAAM SERV-194
RF RAAM SERV-202 | 2. korrus | _KANDETARIND - puitkarkass | 0 | RF RAAM SERV-202
RF RAAM SERV-201 | 2. korrus | _KANDETARIND - puitkarkass | 0 | RF RAAM SERV-201
RF RAAM SERV-196 | 2. korrus | _KANDETARIND - puitkarkass | 0 | RF RAAM SERV-196
RF RAAM SERV-200 | 2. korrus | _KANDETARIND - puitkarkass | 0 | RF RAAM SERV-200
RF RAAM SERV-199 | 2. korrus | _KANDETARIND - puitkarkass | 0 | RF RAAM SERV-199
RF RAAM SERV-198 | 2. korrus | _KANDETARIND - puitkarkass | 90 | RF RAAM SERV-198
RF RAAM SERV-197 | 2. korrus | _KANDETARIND - puitkarkass | 0 | RF RAAM SERV-197
RF RAAM SERV-196 | 2. korrus | _GENEERILINE MATERJAL | 90 | RF RAAM SERV-196
RF RAAM SERV-204 | 2. korrus | _GENEERILINE MATERJAL | 0 | RF RAAM SERV-204
RF RAAM SERV-203 | 2. korrus | _GENEERILINE MATERJAL | 0 | RF RAAM SERV-203
RF RAAM SERV-202 | 2. korrus | _GENEERILINE MATERJAL | 0 | RF RAAM SERV-202
RF RAAM SERV-201 | 2. korrus | _GENEERILINE MATERJAL | 90 | RF RAAM SERV-201
RF RAAM SERV-205 | 2. korrus | _GENEERILINE MATERJAL | 0 | RF RAAM SERV-205
RF RAAM SERV-206 | 2. korrus | _GENEERILINE MATERJAL | 0 | RF RAAM SERV-206
RF RAAM SERV-589 | 2. korrus | _GENEERILINE MATERJAL | 0 | RF RAAM SERV-589
RF RAAM SERV-592 | 2. korrus | _GENEERILINE MATERJAL | 0 | RF RAAM SERV-592
RF RAAM SERV-602 | 2. korrus | _GENEERILINE MATERJAL | 0 | RF RAAM SERV-602
RF RAAM SERV-601 | 2. korrus | _GENEERILINE MATERJAL | 0 | RF RAAM SERV-601
RF RAAM SERV-600 | 2. korrus | _GENEERILINE MATERJAL | 0 | RF RAAM SERV-600
RF RAAM SERV-599 | 2. korrus | _GENEERILINE MATERJAL | 0 | RF RAAM SERV-599
RF RAAM SERV-595 | 2. korrus | _GENEERILINE MATERJAL | 0 | RF RAAM SERV-595
RF RAAM SERV-591 | 2. korrus | _GENEERILINE MATERJAL | 0 | RF RAAM SERV-591
RF RAAM SERV-598 | 2. korrus | _GENEERILINE MATERJAL | 0 | RF RAAM SERV-598
RF RAAM SERV-597 | 2. korrus | _GENEERILINE MATERJAL | 90 | RF RAAM SERV-597
RF RAAM SERV-596 | 2. korrus | _GENEERILINE MATERJAL | 0 | RF RAAM SERV-596
RF RAAM SERV-590 | 2. korrus | _GENEERILINE MATERJAL | 90 | RF RAAM SERV-590
RF RAAM SERV-604 | 2. korrus | _GENEERILINE MATERJAL | 0 | RF RAAM SERV-604
RF RAAM SERV-605 | 2. korrus | _GENEERILINE MATERJAL | 0 | RF RAAM SERV-605
RF RAAM SERV-606 | 2. korrus | _GENEERILINE MATERJAL | 0 | RF RAAM SERV-606
RF RAAM SERV-536 | 2. korrus | _GENEERILINE MATERJAL | 0 | RF RAAM SERV-536
RF RAAM SERV-525 | 2. korrus | _GENEERILINE MATERJAL | 0 | RF RAAM SERV-525
RF RAAM SERV-535 | 2. korrus | _GENEERILINE MATERJAL | 0 | RF RAAM SERV-535
RF RAAM SERV-526 | 2. korrus | _GENEERILINE MATERJAL | 0 | RF RAAM SERV-526
RF RAAM SERV-534 | 2. korrus | _GENEERILINE MATERJAL | 0 | RF RAAM SERV-534
RF RAAM SERV-533 | 2. korrus | _GENEERILINE MATERJAL | 0 | RF RAAM SERV-533
RF RAAM SERV-528 | 2. korrus | _GENEERILINE MATERJAL | 0 | RF RAAM SERV-528
RF RAAM SERV-531 | 2. korrus | _GENEERILINE MATERJAL | 0 | RF RAAM SERV-531
RF RAAM SERV-529 | 2. korrus | _GENEERILINE MATERJAL | 0 | RF RAAM SERV-529
RF RAAM SERV-524 | 2. korrus | _GENEERILINE MATERJAL | 0 | RF RAAM SERV-524
RF RAAM SERV-523 | 2. korrus | _GENEERILINE MATERJAL | 90 | RF RAAM SERV-523
RF RAAM SERV-530 | 2. korrus | _GENEERILINE MATERJAL | 90 | RF RAAM SERV-530
RF RAAM SERV-538 | 2. korrus | _GENEERILINE MATERJAL | 0 | RF RAAM SERV-538
RF RAAM SERV-539 | 2. korrus | _GENEERILINE MATERJAL | 0 | RF RAAM SERV-539
RF RAAM SERV-543 | 2. korrus | _GENEERILINE MATERJAL | 0 | RF RAAM SERV-543
RF RAAM SERV-549 | 2. korrus | _GENEERILINE MATERJAL | 0 | RF RAAM SERV-549
RF RAAM SERV-550 | 2. korrus | _GENEERILINE MATERJAL | 0 | RF RAAM SERV-550
RF RAAM SERV-551 | 2. korrus | _GENEERILINE MATERJAL | 0 | RF RAAM SERV-551
RF RAAM SERV-552 | 2. korrus | _GENEERILINE MATERJAL | 0 | RF RAAM SERV-552
RF RAAM SERV-553 | 2. korrus | _GENEERILINE MATERJAL | 0 | RF RAAM SERV-553
2 x RF RAAM SERV-078 | 3. korrus | _GENEERILINE MATERJAL | 0 | RF RAAM SERV-078
RF RAAM SERV-073 | 3. korrus | _GENEERILINE MATERJAL | 90 | RF RAAM SERV-073
2 x RF RAAM SERV-077 | 3. korrus | _GENEERILINE MATERJAL | 0 | RF RAAM SERV-077
RF RAAM SERV-076 | 3. korrus | _GENEERILINE MATERJAL | 90 | RF RAAM SERV-076
RF RAAM SERV-075 | 3. korrus | _GENEERILINE MATERJAL | 0 | RF RAAM SERV-075
RF RAAM SERV-072 | 3. korrus | _GENEERILINE MATERJAL | 0 | RF RAAM SERV-072
RF RAAM SERV-079 | 3. korrus | _GENEERILINE MATERJAL | 90 | RF RAAM SERV-079
RF RAAM SERV-073 | 3. korrus | _GENEERILINE MATERJAL | 0 | RF RAAM SERV-073
RF RAAM SERV-076 | 3. korrus | _GENEERILINE MATERJAL | 0 | RF RAAM SERV-076
RF RAAM SERV-075 | 3. korrus | _GENEERILINE MATERJAL | 90 | RF RAAM SERV-075
RF RAAM SERV-074 | 3. korrus | _GENEERILINE MATERJAL | 0 | RF RAAM SERV-074
RF RAAM SERV-589 | 3. korrus | _GENEERILINE MATERJAL | 0 | RF RAAM SERV-589
RF RAAM SERV-592 | 3. korrus | _GENEERILINE MATERJAL | 0 | RF RAAM SERV-592
RF RAAM SERV-602 | 3. korrus | _GENEERILINE MATERJAL | 0 | RF RAAM SERV-602
RF RAAM SERV-593 | 3. korrus | _GENEERILINE MATERJAL | 0 | RF RAAM SERV-593
RF RAAM SERV-601 | 3. korrus | _GENEERILINE MATERJAL | 0 | RF RAAM SERV-601
RF RAAM SERV-600 | 3. korrus | _GENEERILINE MATERJAL | 0 | RF RAAM SERV-600
2 x RF RAAM SERV-599 | 3. korrus | _GENEERILINE MATERJAL | 0 | RF RAAM SERV-599
RF RAAM SERV-597 | 3. korrus | _GENEERILINE MATERJAL | 90 | RF RAAM SERV-597
RF RAAM SERV-595 | 3. korrus | _GENEERILINE MATERJAL | 0 | RF RAAM SERV-595
RF RAAM SERV-598 | 3. korrus | _GENEERILINE MATERJAL | 0 | RF RAAM SERV-598
RF RAAM SERV-596 | 3. korrus | _GENEERILINE MATERJAL | 0 | RF RAAM SERV-596
RF RAAM SERV-591 | 3. korrus | _GENEERILINE MATERJAL | 0 | RF RAAM SERV-591
RF RAAM SERV-590 | 3. korrus | _GENEERILINE MATERJAL | 90 | RF RAAM SERV-590
RF RAAM SERV-443 | 3. korrus | _GENEERILINE MATERJAL | 0 | RF RAAM SERV-443
2 x RF RAAM SERV-446 | 3. korrus | _GENEERILINE MATERJAL | 0 | RF RAAM SERV-446
2 x RF RAAM SERV-458 | 3. korrus | _GENEERILINE MATERJAL | 0 | RF RAAM SERV-458
2 x RF RAAM SERV-447 | 3. korrus | _GENEERILINE MATERJAL | 0 | RF RAAM SERV-447
2 x RF RAAM SERV-457 | 3. korrus | _GENEERILINE MATERJAL | 0 | RF RAAM SERV-457
RF RAAM SERV-445 | 3. korrus | _GENEERILINE MATERJAL | 0 | RF RAAM SERV-445
2 x RF RAAM SERV-456 | 3. korrus | _GENEERILINE MATERJAL | 0 | RF RAAM SERV-456
RF RAAM SERV-455 | 3. korrus | _GENEERILINE MATERJAL | 0 | RF RAAM SERV-455
2 x RF RAAM SERV-454 | 3. korrus | _GENEERILINE MATERJAL | 0 | RF RAAM SERV-454
RF RAAM SERV-450 | 3. korrus | _GENEERILINE MATERJAL | 0 | RF RAAM SERV-450
RF RAAM SERV-448 | 3. korrus | _GENEERILINE MATERJAL | 0 | RF RAAM SERV-448
RF RAAM SERV-453 | 3. korrus | _GENEERILINE MATERJAL | 0 | RF RAAM SERV-453
RF RAAM SERV-452 | 3. korrus | _GENEERILINE MATERJAL | 90 | RF RAAM SERV-452
RF RAAM SERV-451 | 3. korrus | _GENEERILINE MATERJAL | 0 | RF RAAM SERV-451
RF RAAM SERV-444 | 3. korrus | _GENEERILINE MATERJAL | 90 | RF RAAM SERV-444
RF RAAM SERV-215 | 3. korrus | _GENEERILINE MATERJAL | 0 | RF RAAM SERV-215
RF RAAM SERV-216 | 3. korrus | _GENEERILINE MATERJAL | 0 | RF RAAM SERV-216
2 x RF RAAM SERV-221 | 3. korrus | _GENEERILINE MATERJAL | 0 | RF RAAM SERV-221
RF RAAM SERV-220 | 3. korrus | _GENEERILINE MATERJAL | 0 | RF RAAM SERV-220
2 x RF RAAM SERV-225 | 3. korrus | _GENEERILINE MATERJAL | 0 | RF RAAM SERV-225
2 x RF RAAM SERV-226 | 3. korrus | _GENEERILINE MATERJAL | 0 | RF RAAM SERV-226
2 x RF RAAM SERV-233 | 3. korrus | _GENEERILINE MATERJAL | 0 | RF RAAM SERV-233
2 x RF RAAM SERV-232 | 3. korrus | _GENEERILINE MATERJAL | 0 | RF RAAM SERV-232
RF RAAM SERV-219 | 3. korrus | _GENEERILINE MATERJAL | 0 | RF RAAM SERV-219
RF RAAM SERV-217 | 3. korrus | _GENEERILINE MATERJAL | 0 | RF RAAM SERV-217
2 x RF RAAM SERV-231 | 3. korrus | _GENEERILINE MATERJAL | 0 | RF RAAM SERV-231
2 x RF RAAM SERV-227 | 3. korrus | _GENEERILINE MATERJAL | 0 | RF RAAM SERV-227
RF RAAM SERV-213 | 3. korrus | _GENEERILINE MATERJAL | 90 | RF RAAM SERV-213
RF RAAM SERV-222 | 3. korrus | _GENEERILINE MATERJAL | 0 | RF RAAM SERV-222
RF RAAM SERV-224 | 3. korrus | _GENEERILINE MATERJAL | 0 | RF RAAM SERV-224
RF RAAM SERV-234 | 3. korrus | _GENEERILINE MATERJAL | 0 | RF RAAM SERV-234
RF RAAM SERV-230 | 3. korrus | _GENEERILINE MATERJAL | 0 | RF RAAM SERV-230
RF RAAM SERV-229 | 3. korrus | _GENEERILINE MATERJAL | 90 | RF RAAM SERV-229
RF RAAM SERV-228 | 3. korrus | _GENEERILINE MATERJAL | 0 | RF RAAM SERV-228

# IfcMember: Boundary Frame 50 x 120 (109)
Type - PredefinedType: MEMBER
Classification: 1.13 IfcMemberType (kandev element) (RKAS BIM + ARCHICAD Classification)
AC_Pset_RenovationAndPhasing - Renovation Status: Undefined
Name | In | Material | Reference = 002_Tüüp | Slope (deg) | 001_Nimetus
RF RAAM SERV-131 | 1. korrus | _GENEERILINE MATERJAL | Built-in Frame | 0 | RF RAAM SERV-131
RF RAAM SERV-134 | 1. korrus | _GENEERILINE MATERJAL | Built-in Frame | 0 | RF RAAM SERV-134
RF RAAM SERV-148 | 1. korrus | _GENEERILINE MATERJAL | Built-in Frame | 0 | RF RAAM SERV-148
RF RAAM SERV-135 | 1. korrus | _GENEERILINE MATERJAL | Built-in Frame | 0 | RF RAAM SERV-135
RF RAAM SERV-147 | 1. korrus | _GENEERILINE MATERJAL | Built-in Frame | 0 | RF RAAM SERV-147
RF RAAM SERV-146 | 1. korrus | _GENEERILINE MATERJAL | Built-in Frame | 0 | RF RAAM SERV-146
RF RAAM SERV-145 | 1. korrus | _GENEERILINE MATERJAL | Built-in Frame | 0 | RF RAAM SERV-145
RF RAAM SERV-138 | 1. korrus | _GENEERILINE MATERJAL | Built-in Frame | 0 | RF RAAM SERV-138
RF RAAM SERV-144 | 1. korrus | _GENEERILINE MATERJAL | Built-in Frame | 0 | RF RAAM SERV-144
RF RAAM SERV-139 | 1. korrus | _GENEERILINE MATERJAL | Built-in Frame | 0 | RF RAAM SERV-139
RF RAAM SERV-143 | 1. korrus | _GENEERILINE MATERJAL | Built-in Frame | 0 | RF RAAM SERV-143
RF RAAM SERV-133 | 1. korrus | _GENEERILINE MATERJAL | Built-in Frame | 0 | RF RAAM SERV-133
RF RAAM SERV-132 | 1. korrus | _GENEERILINE MATERJAL | Built-in Frame | 90 | RF RAAM SERV-132
RF RAAM SERV-142 | 1. korrus | _GENEERILINE MATERJAL | Built-in Frame | 0 | RF RAAM SERV-142
RF RAAM SERV-141 | 1. korrus | _GENEERILINE MATERJAL | Built-in Frame | 90 | RF RAAM SERV-141
RF RAAM SERV-140 | 1. korrus | _GENEERILINE MATERJAL | Built-in Frame | 0 | RF RAAM SERV-140
RF RAAM SERV-008 | 1. korrus | _METALL - alumiinium | Modular Frame 25 | 0 | RF RAAM SERV-008
RF RAAM SERV-019 | 1. korrus | _METALL - alumiinium | Modular Frame 25 | 90 | RF RAAM SERV-019
RF RAAM SERV-010 | 1. korrus | _METALL - alumiinium | Modular Frame 25 | 0 | RF RAAM SERV-010
RF RAAM SERV-018 | 1. korrus | _METALL - alumiinium | Modular Frame 25 | 90 | RF RAAM SERV-018
RF RAAM SERV-012 | 1. korrus | _METALL - alumiinium | Modular Frame 25 | 90 | RF RAAM SERV-012
RF RAAM SERV-013 | 1. korrus | _METALL - alumiinium | Modular Frame 25 | 90 | RF RAAM SERV-013
RF RAAM SERV-011 | 1. korrus | _METALL - alumiinium | Modular Frame 25 | 0 | RF RAAM SERV-011
RF RAAM SERV-017 | 1. korrus | _METALL - alumiinium | Modular Frame 25 | 0 | RF RAAM SERV-017
RF RAAM SERV-016 | 1. korrus | _METALL - alumiinium | Modular Frame 25 | 0 | RF RAAM SERV-016
RF RAAM SERV-015 | 1. korrus | _METALL - alumiinium | Modular Frame 25 | 0 | RF RAAM SERV-015
RF RAAM SERV-014 | 1. korrus | _METALL - alumiinium | Modular Frame 25 | 0 | RF RAAM SERV-014
RF RAAM SERV-195 | 1. korrus | _METALL - alumiinium | Built-in Frame | 0 | RF RAAM SERV-195
RF RAAM SERV-198 | 1. korrus | _METALL - alumiinium | Built-in Frame | 0 | RF RAAM SERV-198
RF RAAM SERV-204 | 1. korrus | _METALL - alumiinium | Built-in Frame | 0 | RF RAAM SERV-204
RF RAAM SERV-203 | 1. korrus | _METALL - alumiinium | Built-in Frame | 0 | RF RAAM SERV-203
RF RAAM SERV-199 | 1. korrus | _METALL - alumiinium | Built-in Frame | 0 | RF RAAM SERV-199
RF RAAM SERV-201 | 1. korrus | _METALL - alumiinium | Built-in Frame | 90 | RF RAAM SERV-201
RF RAAM SERV-200 | 1. korrus | _METALL - alumiinium | Built-in Frame | 0 | RF RAAM SERV-200
RF RAAM SERV-202 | 1. korrus | _METALL - alumiinium | Built-in Frame | 0 | RF RAAM SERV-202
RF RAAM SERV-197 | 1. korrus | _METALL - alumiinium | Built-in Frame | 0 | RF RAAM SERV-197
RF RAAM SERV-196 | 1. korrus | _METALL - alumiinium | Built-in Frame | 90 | RF RAAM SERV-196
RF RAAM SERV-113 | 1. korrus | _METALL - alumiinium | Built-in Frame | 0 | RF RAAM SERV-113
RF RAAM SERV-116 | 1. korrus | _METALL - alumiinium | Built-in Frame | 0 | RF RAAM SERV-116
RF RAAM SERV-122 | 1. korrus | _METALL - alumiinium | Built-in Frame | 0 | RF RAAM SERV-122
RF RAAM SERV-121 | 1. korrus | _METALL - alumiinium | Built-in Frame | 0 | RF RAAM SERV-121
RF RAAM SERV-117 | 1. korrus | _METALL - alumiinium | Built-in Frame | 0 | RF RAAM SERV-117
RF RAAM SERV-120 | 1. korrus | _METALL - alumiinium | Built-in Frame | 0 | RF RAAM SERV-120
RF RAAM SERV-119 | 1. korrus | _METALL - alumiinium | Built-in Frame | 90 | RF RAAM SERV-119
RF RAAM SERV-118 | 1. korrus | _METALL - alumiinium | Built-in Frame | 0 | RF RAAM SERV-118
RF RAAM SERV-115 | 1. korrus | _METALL - alumiinium | Built-in Frame | 0 | RF RAAM SERV-115
RF RAAM SERV-114 | 1. korrus | _METALL - alumiinium | Built-in Frame | 90 | RF RAAM SERV-114
RF RAAM SERV-057 | 1. korrus | _METALL - alumiinium | Modular Frame 25 | 0 | RF RAAM SERV-057
RF RAAM SERV-056 | 1. korrus | _METALL - alumiinium | Modular Frame 25 | 90 | RF RAAM SERV-056
RF RAAM SERV-061 | 1. korrus | _METALL - alumiinium | Modular Frame 25 | 0 | RF RAAM SERV-061
RF RAAM SERV-059 | 1. korrus | _METALL - alumiinium | Modular Frame 25 | 90 | RF RAAM SERV-059
RF RAAM SERV-058 | 1. korrus | _METALL - alumiinium | Modular Frame 25 | 0 | RF RAAM SERV-058
RF RAAM SERV-060 | 1. korrus | _METALL - alumiinium | Modular Frame 25 | 0 | RF RAAM SERV-060
2 x RF RAAM SERV-097 | 1. korrus | _METALL - alumiinium | Modular Frame 25 | 0 | RF RAAM SERV-097
RF RAAM SERV-104 | 1. korrus | _METALL - alumiinium | Modular Frame 25 | 90 | RF RAAM SERV-104
RF RAAM SERV-098 | 1. korrus | _METALL - alumiinium | Modular Frame 25 | 0 | RF RAAM SERV-098
RF RAAM SERV-101 | 1. korrus | _METALL - alumiinium | Modular Frame 25 | 0 | RF RAAM SERV-101
2 x RF RAAM SERV-099 | 1. korrus | _METALL - alumiinium | Modular Frame 25 | 90 | RF RAAM SERV-099
RF RAAM SERV-103 | 1. korrus | _METALL - alumiinium | Modular Frame 25 | 90 | RF RAAM SERV-103
RF RAAM SERV-100 | 1. korrus | _METALL - alumiinium | Modular Frame 25 | 90 | RF RAAM SERV-100
RF RAAM SERV-102 | 1. korrus | _METALL - alumiinium | Modular Frame 25 | 0 | RF RAAM SERV-102
RF RAAM SERV-102 | 1. korrus | _METALL - alumiinium | Modular Frame 25 | 90 | RF RAAM SERV-102
RF RAAM SERV-098 | 1. korrus | _METALL - alumiinium | Modular Frame 25 | 90 | RF RAAM SERV-098
RF RAAM SERV-101 | 1. korrus | _METALL - alumiinium | Modular Frame 25 | 90 | RF RAAM SERV-101
RF RAAM SERV-100 | 1. korrus | _METALL - alumiinium | Modular Frame 25 | 0 | RF RAAM SERV-100
RF RAAM SERV-062 | 2. korrus | _METALL - alumiinium | Built-in Frame | 0 | RF RAAM SERV-062
RF RAAM SERV-049 | 2. korrus | _METALL - alumiinium | Built-in Frame | 0 | RF RAAM SERV-049
RF RAAM SERV-061 | 2. korrus | _METALL - alumiinium | Built-in Frame | 0 | RF RAAM SERV-061
RF RAAM SERV-050 | 2. korrus | _METALL - alumiinium | Built-in Frame | 0 | RF RAAM SERV-050
RF RAAM SERV-060 | 2. korrus | _METALL - alumiinium | Built-in Frame | 0 | RF RAAM SERV-060
RF RAAM SERV-051 | 2. korrus | _METALL - alumiinium | Built-in Frame | 0 | RF RAAM SERV-051
RF RAAM SERV-059 | 2. korrus | _METALL - alumiinium | Built-in Frame | 0 | RF RAAM SERV-059
RF RAAM SERV-052 | 2. korrus | _METALL - alumiinium | Built-in Frame | 0 | RF RAAM SERV-052
RF RAAM SERV-053 | 2. korrus | _METALL - alumiinium | Built-in Frame | 0 | RF RAAM SERV-053
RF RAAM SERV-058 | 2. korrus | _METALL - alumiinium | Built-in Frame | 0 | RF RAAM SERV-058
RF RAAM SERV-057 | 2. korrus | _METALL - alumiinium | Built-in Frame | 0 | RF RAAM SERV-057
RF RAAM SERV-048 | 2. korrus | _METALL - alumiinium | Built-in Frame | 0 | RF RAAM SERV-048
RF RAAM SERV-047 | 2. korrus | _METALL - alumiinium | Built-in Frame | 90 | RF RAAM SERV-047
RF RAAM SERV-056 | 2. korrus | _METALL - alumiinium | Built-in Frame | 0 | RF RAAM SERV-056
RF RAAM SERV-055 | 2. korrus | _METALL - alumiinium | Built-in Frame | 90 | RF RAAM SERV-055
RF RAAM SERV-054 | 2. korrus | _METALL - alumiinium | Built-in Frame | 0 | RF RAAM SERV-054
RF RAAM SERV-142 | 2. korrus | _KANDETARIND - puitkarkass | Built-in Frame | 0 | RF RAAM SERV-142
RF RAAM SERV-150 | 2. korrus | _KANDETARIND - puitkarkass | Built-in Frame | 0 | RF RAAM SERV-150
RF RAAM SERV-151 | 2. korrus | _KANDETARIND - puitkarkass | Built-in Frame | 90 | RF RAAM SERV-151
RF RAAM SERV-143 | 2. korrus | _KANDETARIND - puitkarkass | Built-in Frame | 0 | RF RAAM SERV-143
RF RAAM SERV-149 | 2. korrus | _KANDETARIND - puitkarkass | Built-in Frame | 0 | RF RAAM SERV-149
RF RAAM SERV-148 | 2. korrus | _KANDETARIND - puitkarkass | Built-in Frame | 0 | RF RAAM SERV-148
RF RAAM SERV-144 | 2. korrus | _KANDETARIND - puitkarkass | Built-in Frame | 0 | RF RAAM SERV-144
RF RAAM SERV-147 | 2. korrus | _KANDETARIND - puitkarkass | Built-in Frame | 0 | RF RAAM SERV-147
RF RAAM SERV-145 | 2. korrus | _KANDETARIND - puitkarkass | Built-in Frame | 0 | RF RAAM SERV-145
RF RAAM SERV-146 | 2. korrus | _KANDETARIND - puitkarkass | Built-in Frame | 90 | RF RAAM SERV-146
RF RAAM SERV-080 | 2. korrus | _METALL - alumiinium | Built-in Frame | 0 | RF RAAM SERV-080
RF RAAM SERV-067 | 2. korrus | _METALL - alumiinium | Built-in Frame | 0 | RF RAAM SERV-067
RF RAAM SERV-079 | 2. korrus | _METALL - alumiinium | Built-in Frame | 0 | RF RAAM SERV-079
RF RAAM SERV-068 | 2. korrus | _METALL - alumiinium | Built-in Frame | 0 | RF RAAM SERV-068
RF RAAM SERV-078 | 2. korrus | _METALL - alumiinium | Built-in Frame | 0 | RF RAAM SERV-078
RF RAAM SERV-069 | 2. korrus | _METALL - alumiinium | Built-in Frame | 0 | RF RAAM SERV-069
RF RAAM SERV-077 | 2. korrus | _METALL - alumiinium | Built-in Frame | 0 | RF RAAM SERV-077
RF RAAM SERV-070 | 2. korrus | _METALL - alumiinium | Built-in Frame | 0 | RF RAAM SERV-070
RF RAAM SERV-071 | 2. korrus | _METALL - alumiinium | Built-in Frame | 0 | RF RAAM SERV-071
RF RAAM SERV-076 | 2. korrus | _METALL - alumiinium | Built-in Frame | 0 | RF RAAM SERV-076
RF RAAM SERV-075 | 2. korrus | _METALL - alumiinium | Built-in Frame | 0 | RF RAAM SERV-075
RF RAAM SERV-066 | 2. korrus | _METALL - alumiinium | Built-in Frame | 0 | RF RAAM SERV-066
RF RAAM SERV-065 | 2. korrus | _METALL - alumiinium | Built-in Frame | 90 | RF RAAM SERV-065
RF RAAM SERV-074 | 2. korrus | _METALL - alumiinium | Built-in Frame | 0 | RF RAAM SERV-074
RF RAAM SERV-073 | 2. korrus | _METALL - alumiinium | Built-in Frame | 90 | RF RAAM SERV-073
RF RAAM SERV-072 | 2. korrus | _METALL - alumiinium | Built-in Frame | 0 | RF RAAM SERV-072

# IfcMember: Boundary Frame 50 x 130 (42)
In: 2. korrus
Type - PredefinedType: MEMBER
Classification: 1.13 IfcMemberType (kandev element) (RKAS BIM + ARCHICAD Classification); Material: _METALL - alumiinium
Pset_MemberCommon - Reference: Built-in Frame
AR_001-002 - 002_Tüüp: Built-in Frame
AC_Pset_RenovationAndPhasing - Renovation Status: Undefined
Name | Slope (deg) | 001_Nimetus
RF RAAM SERV-041 | 0 | RF RAAM SERV-041
RF RAAM SERV-032 | 0 | RF RAAM SERV-032
RF RAAM SERV-040 | 0 | RF RAAM SERV-040
RF RAAM SERV-031 | 0 | RF RAAM SERV-031
RF RAAM SERV-030 | 0 | RF RAAM SERV-030
RF RAAM SERV-029 | 90 | RF RAAM SERV-029
RF RAAM SERV-042 | 0 | RF RAAM SERV-042
RF RAAM SERV-039 | 0 | RF RAAM SERV-039
RF RAAM SERV-033 | 0 | RF RAAM SERV-033
RF RAAM SERV-034 | 0 | RF RAAM SERV-034
RF RAAM SERV-038 | 0 | RF RAAM SERV-038
RF RAAM SERV-037 | 0 | RF RAAM SERV-037
RF RAAM SERV-036 | 90 | RF RAAM SERV-036
RF RAAM SERV-035 | 0 | RF RAAM SERV-035
2 x RF RAAM SERV-068 | 0 | RF RAAM SERV-068
2 x RF RAAM SERV-081 | 90 | RF RAAM SERV-081
2 x RF RAAM SERV-069 | 0 | RF RAAM SERV-069
2 x RF RAAM SERV-070 | 0 | RF RAAM SERV-070
2 x RF RAAM SERV-071 | 0 | RF RAAM SERV-071
2 x RF RAAM SERV-073 | 90 | RF RAAM SERV-073
2 x RF RAAM SERV-072 | 0 | RF RAAM SERV-072
2 x RF RAAM SERV-080 | 90 | RF RAAM SERV-080
2 x RF RAAM SERV-079 | 0 | RF RAAM SERV-079
2 x RF RAAM SERV-078 | 0 | RF RAAM SERV-078
2 x RF RAAM SERV-077 | 0 | RF RAAM SERV-077
2 x RF RAAM SERV-076 | 0 | RF RAAM SERV-076
2 x RF RAAM SERV-075 | 4.7655e-07 | RF RAAM SERV-075
2 x RF RAAM SERV-074 | 90 | RF RAAM SERV-074

# IfcMember: Boundary Frame 50 x 200 (109)
In: 4. TEHNO korrus
Type - PredefinedType: MEMBER
Classification: 1.13 IfcMemberType (kandev element) (RKAS BIM + ARCHICAD Classification); Material: _METALL - alumiinium
Pset_MemberCommon - Reference: Frame 25
AR_001-002 - 002_Tüüp: Frame 25
AC_Pset_RenovationAndPhasing - Renovation Status: Undefined
Name | Slope (deg) | 001_Nimetus
RF RAAM SERV-551 | 2.81875e-08 | RF RAAM SERV-551
RF RAAM SERV-549 | 2.81881e-08 | RF RAAM SERV-549
RF RAAM SERV-559 | 2.81884e-08 | RF RAAM SERV-559
RF RAAM SERV-558 | 2.81881e-08 | RF RAAM SERV-558
RF RAAM SERV-560 | 1.28609e-07 | RF RAAM SERV-560
RF RAAM SERV-564 | 7 | RF RAAM SERV-564
RF RAAM SERV-563 | 7 | RF RAAM SERV-563
RF RAAM SERV-562 | 7 | RF RAAM SERV-562
RF RAAM SERV-561 | 7 | RF RAAM SERV-561
RF RAAM SERV-557 | 5.8998e-07 | RF RAAM SERV-557
RF RAAM SERV-556 | 7 | RF RAAM SERV-556
RF RAAM SERV-555 | 7 | RF RAAM SERV-555
RF RAAM SERV-554 | 7 | RF RAAM SERV-554
RF RAAM SERV-553 | 7 | RF RAAM SERV-553
RF RAAM SERV-552 | 2.81881e-08 | RF RAAM SERV-552
RF RAAM SERV-566 | 7 | RF RAAM SERV-566
RF RAAM SERV-567 | 7 | RF RAAM SERV-567
RF RAAM SERV-568 | 7 | RF RAAM SERV-568
RF RAAM SERV-569 | 7 | RF RAAM SERV-569
RF RAAM SERV-570 | 7 | RF RAAM SERV-570
RF RAAM SERV-571 | 7 | RF RAAM SERV-571
RF RAAM SERV-572 | 2.81881e-08 | RF RAAM SERV-572
RF RAAM SERV-573 | 2.81884e-08 | RF RAAM SERV-573
RF RAAM SERV-576 | 2.81867e-08 | RF RAAM SERV-576
RF RAAM SERV-577 | 2.81881e-08 | RF RAAM SERV-577
RF RAAM SERV-578 | 2.81889e-08 | RF RAAM SERV-578
RF RAAM SERV-579 | 2.81881e-08 | RF RAAM SERV-579
RF RAAM SERV-863 | 0 | RF RAAM SERV-863
RF RAAM SERV-864 | 0 | RF RAAM SERV-864
RF RAAM SERV-865 | 0 | RF RAAM SERV-865
RF RAAM SERV-866 | 0 | RF RAAM SERV-866
RF RAAM SERV-875 | 0 | RF RAAM SERV-875
RF RAAM SERV-874 | 0 | RF RAAM SERV-874
RF RAAM SERV-873 | 0 | RF RAAM SERV-873
RF RAAM SERV-872 | 0 | RF RAAM SERV-872
RF RAAM SERV-876 | 3.47281e-07 | RF RAAM SERV-876
RF RAAM SERV-862 | 0 | RF RAAM SERV-862
RF RAAM SERV-861 | 7 | RF RAAM SERV-861
RF RAAM SERV-878 | 7 | RF RAAM SERV-878
RF RAAM SERV-877 | 7 | RF RAAM SERV-877
RF RAAM SERV-871 | 3.01028e-07 | RF RAAM SERV-871
RF RAAM SERV-870 | 7 | RF RAAM SERV-870
RF RAAM SERV-869 | 7 | RF RAAM SERV-869
RF RAAM SERV-868 | 7 | RF RAAM SERV-868
RF RAAM SERV-867 | 0 | RF RAAM SERV-867
RF RAAM SERV-880 | 7 | RF RAAM SERV-880
RF RAAM SERV-881 | 7 | RF RAAM SERV-881
RF RAAM SERV-882 | 7 | RF RAAM SERV-882
RF RAAM SERV-883 | 7 | RF RAAM SERV-883
RF RAAM SERV-884 | 0 | RF RAAM SERV-884
RF RAAM SERV-885 | 0 | RF RAAM SERV-885
RF RAAM SERV-886 | 0 | RF RAAM SERV-886
RF RAAM SERV-887 | 0 | RF RAAM SERV-887
RF RAAM SERV-888 | 0 | RF RAAM SERV-888
RF RAAM SERV-889 | 0 | RF RAAM SERV-889
RF RAAM SERV-890 | 0 | RF RAAM SERV-890
RF RAAM SERV-891 | 0 | RF RAAM SERV-891
RF RAAM SERV-892 | 0 | RF RAAM SERV-892
RF RAAM SERV-893 | 0 | RF RAAM SERV-893
RF RAAM SERV-894 | 0 | RF RAAM SERV-894
RF RAAM SERV-895 | 0 | RF RAAM SERV-895
2 x RF RAAM SERV-844 | 7 | RF RAAM SERV-844
RF RAAM SERV-819 | 7 | RF RAAM SERV-819
RF RAAM SERV-978 | 0.00000855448 | RF RAAM SERV-978
RF RAAM SERV-876 | 0.00000443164 | RF RAAM SERV-876
RF RAAM SERV-877 | 7.88817e-07 | RF RAAM SERV-877
RF RAAM SERV-884 | 0.00000110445 | RF RAAM SERV-884
RF RAAM SERV-990 | 7 | RF RAAM SERV-990
RF RAAM SERV-891 | 0.00000840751 | RF RAAM SERV-891
RF RAAM SERV-892 | 0.00000529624 | RF RAAM SERV-892
RF RAAM SERV-893 | 0.0000082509 | RF RAAM SERV-893
RF RAAM SERV-894 | 0.00000827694 | RF RAAM SERV-894
RF RAAM SERV-897 | 0.00000871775 | RF RAAM SERV-897
RF RAAM SERV-898 | 7 | RF RAAM SERV-898
RF RAAM SERV-900 | 7 | RF RAAM SERV-900
RF RAAM VERT-033 | 7 | RF RAAM VERT-033
RF RAAM VERT-034 | 7 | RF RAAM VERT-034
RF RAAM SERV-991 | 0.00000839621 | RF RAAM SERV-991
RF RAAM SERV-981 | 9.82871e-07 | RF RAAM SERV-981
RF RAAM SERV-984 | 0.00000105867 | RF RAAM SERV-984
RF RAAM SERV-986 | 7 | RF RAAM SERV-986
RF RAAM SERV-987 | 7 | RF RAAM SERV-987
RF RAAM SERV-964 | 7 | RF RAAM SERV-964
RF RAAM SERV-985 | 7 | RF RAAM SERV-985
RF RAAM SERV-988 | 9.8287e-07 | RF RAAM SERV-988
RF RAAM SERV-989 | 0.00000839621 | RF RAAM SERV-989
RF RAAM SERV-992 | 7 | RF RAAM SERV-992
RF RAAM SERV-993 | 0.00000850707 | RF RAAM SERV-993
RF RAAM SERV-994 | 0.00000105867 | RF RAAM SERV-994
RF RAAM SERV-995 | 0.00000855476 | RF RAAM SERV-995
RF RAAM SERV-997 | 9.07786e-07 | RF RAAM SERV-997
RF RAAM SERV-999 | 8.11802e-07 | RF RAAM SERV-999
RF RAAM SERV-000 | 0.00000825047 | RF RAAM SERV-000
RF RAAM SERV-830 | 0 | RF RAAM SERV-830
RF RAAM SERV-829 | 7 | RF RAAM SERV-829
RF RAAM SERV-831 | 0 | RF RAAM SERV-831
RF RAAM SERV-832 | 0 | RF RAAM SERV-832
RF RAAM SERV-833 | 0 | RF RAAM SERV-833
RF RAAM SERV-835 | 7 | RF RAAM SERV-835
RF RAAM SERV-836 | 7 | RF RAAM SERV-836
RF RAAM SERV-834 | 0 | RF RAAM SERV-834
RF RAAM SERV-843 | 7 | RF RAAM SERV-843
RF RAAM SERV-842 | 1.98785e-14 | RF RAAM SERV-842
RF RAAM SERV-841 | 0 | RF RAAM SERV-841
RF RAAM SERV-840 | 0 | RF RAAM SERV-840
RF RAAM SERV-839 | 0 | RF RAAM SERV-839
RF RAAM SERV-838 | 1.99395e-14 | RF RAAM SERV-838
RF RAAM SERV-837 | 7 | RF RAAM SERV-837

# IfcMember: Boundary Frame 60 x 160 (33)
In: 1. korrus
Type - PredefinedType: MEMBER
Classification: 1.13 IfcMemberType (kandev element) (RKAS BIM + ARCHICAD Classification); Material: _KANDETARIND - liimpuit vastavalt EK osale
Pset_MemberCommon - Reference: Built-in Butt-glazed Frame
AR_001-002 - 002_Tüüp: Built-in Butt-glazed Frame
AC_Pset_RenovationAndPhasing - Renovation Status: Undefined
Name | Slope (deg) | 001_Nimetus
2 x RF RAAM SERV-524 | 0 | RF RAAM SERV-524
RF RAAM SERV-617 | 0 | RF RAAM SERV-617
RF RAAM SERV-620 | 0 | RF RAAM SERV-620
RF RAAM HOR-230 | 0 | RF RAAM HOR-230
RF RAAM HOR-231 | 0 | RF RAAM HOR-231
RF RAAM SERV-634 | 90 | RF RAAM SERV-634
RF RAAM SERV-635 | 90 | RF RAAM SERV-635
RF RAAM SERV-623 | 90 | RF RAAM SERV-623
RF RAAM SERV-622 | 90 | RF RAAM SERV-622
RF RAAM SERV-621 | 0 | RF RAAM SERV-621
RF RAAM SERV-547 | 0 | RF RAAM SERV-547
RF RAAM SERV-633 | 90 | RF RAAM SERV-633
RF RAAM SERV-632 | 0 | RF RAAM SERV-632
RF RAAM SERV-631 | 0.00000271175 | RF RAAM SERV-631
RF RAAM SERV-630 | 0 | RF RAAM SERV-630
RF RAAM SERV-629 | 0 | RF RAAM SERV-629
RF RAAM SERV-628 | 0 | RF RAAM SERV-628
RF RAAM SERV-627 | 0 | RF RAAM SERV-627
RF RAAM SERV-626 | 0 | RF RAAM SERV-626
RF RAAM SERV-625 | 0.00000124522 | RF RAAM SERV-625
RF RAAM SERV-624 | 90 | RF RAAM SERV-624
RF RAAM SERV-638 | 0 | RF RAAM SERV-638
RF RAAM SERV-642 | 90 | RF RAAM SERV-642
RF RAAM SERV-641 | 90 | RF RAAM SERV-641
RF RAAM SERV-640 | 0 | RF RAAM SERV-640
RF RAAM SERV-649 | 90 | RF RAAM SERV-649
RF RAAM SERV-648 | 90 | RF RAAM SERV-648
RF RAAM SERV-647 | 90 | RF RAAM SERV-647
RF RAAM SERV-643 | 90 | RF RAAM SERV-643
RF RAAM SERV-646 | 0 | RF RAAM SERV-646
RF RAAM SERV-645 | 0 | RF RAAM SERV-645
RF RAAM SERV-644 | 0 | RF RAAM SERV-644

# IfcMember: Boundary Frame 60 x 200 (50)
In: 1. korrus
Type - PredefinedType: MEMBER
Classification: 1.13 IfcMemberType (kandev element) (RKAS BIM + ARCHICAD Classification); Material: _KANDETARIND - liimpuit vastavalt EK osale
Pset_MemberCommon - Reference: Built-in Butt-glazed Frame
AR_001-002 - 002_Tüüp: Built-in Butt-glazed Frame
AC_Pset_RenovationAndPhasing - Renovation Status: Undefined
Name | Slope (deg) | 001_Nimetus
RF RAAM SERV-456 | 90 | RF RAAM SERV-456
RF RAAM SERV-412 | 0 | RF RAAM SERV-412
RF RAAM SERV-413 | 0 | RF RAAM SERV-413
RF RAAM SERV-414 | 0 | RF RAAM SERV-414
RF RAAM SERV-415 | 0 | RF RAAM SERV-415
RF RAAM SERV-416 | 0 | RF RAAM SERV-416
RF RAAM SERV-417 | 0 | RF RAAM SERV-417
RF RAAM SERV-418 | 0 | RF RAAM SERV-418
RF RAAM SERV-419 | 0 | RF RAAM SERV-419
RF RAAM SERV-420 | 0 | RF RAAM SERV-420
RF RAAM SERV-421 | 0 | RF RAAM SERV-421
RF RAAM SERV-422 | 0 | RF RAAM SERV-422
RF RAAM SERV-423 | 0 | RF RAAM SERV-423
RF RAAM SERV-424 | 0 | RF RAAM SERV-424
RF RAAM SERV-425 | 0 | RF RAAM SERV-425
RF RAAM SERV-426 | 0 | RF RAAM SERV-426
RF RAAM SERV-427 | 0 | RF RAAM SERV-427
RF RAAM HOR-474 | 0 | RF RAAM HOR-474
RF RAAM HOR-491 | 0 | RF RAAM HOR-491
RF RAAM HOR-492 | 0 | RF RAAM HOR-492
RF RAAM SERV-433 | 90 | RF RAAM SERV-433
RF RAAM SERV-432 | 90 | RF RAAM SERV-432
RF RAAM SERV-431 | 90 | RF RAAM SERV-431
RF RAAM SERV-457 | 87.4776 | RF RAAM SERV-457
RF RAAM HOR-694 | 0 | RF RAAM HOR-694
RF RAAM SERV-458 | 87.4776 | RF RAAM SERV-458
RF RAAM SERV-410 | 0 | RF RAAM SERV-410
RF RAAM SERV-459 | 90 | RF RAAM SERV-459
RF RAAM SERV-434 | 90 | RF RAAM SERV-434
RF RAAM SERV-455 | 0 | RF RAAM SERV-455
RF RAAM SERV-454 | 0 | RF RAAM SERV-454
RF RAAM SERV-453 | 0 | RF RAAM SERV-453
RF RAAM SERV-452 | 0 | RF RAAM SERV-452
RF RAAM SERV-451 | 0 | RF RAAM SERV-451
RF RAAM SERV-450 | 0 | RF RAAM SERV-450
RF RAAM SERV-449 | 0 | RF RAAM SERV-449
RF RAAM SERV-448 | 0 | RF RAAM SERV-448
RF RAAM SERV-447 | 0 | RF RAAM SERV-447
RF RAAM SERV-446 | 0 | RF RAAM SERV-446
RF RAAM SERV-445 | 0 | RF RAAM SERV-445
RF RAAM SERV-444 | 0 | RF RAAM SERV-444
RF RAAM SERV-443 | 0 | RF RAAM SERV-443
RF RAAM SERV-442 | 0 | RF RAAM SERV-442
RF RAAM SERV-441 | 0 | RF RAAM SERV-441
RF RAAM SERV-440 | 0 | RF RAAM SERV-440
RF RAAM SERV-439 | 0 | RF RAAM SERV-439
RF RAAM SERV-438 | 0 | RF RAAM SERV-438
RF RAAM SERV-437 | 0 | RF RAAM SERV-437
RF RAAM SERV-436 | 0 | RF RAAM SERV-436
RF RAAM SERV-435 | 0 | RF RAAM SERV-435

# IfcMember: Boundary Frame 60 x 360 (124)
In: 1. korrus
Type - PredefinedType: MEMBER
Classification: 1.13 IfcMemberType (kandev element) (RKAS BIM + ARCHICAD Classification); Material: _KANDETARIND - liimpuit vastavalt EK osale
Pset_MemberCommon - Reference: Built-in Butt-glazed Frame
AR_001-002 - 002_Tüüp: Built-in Butt-glazed Frame
AC_Pset_RenovationAndPhasing - Renovation Status: Undefined
Name | Slope (deg) | 001_Nimetus
RF RAAM SERV-709 | 0 | RF RAAM SERV-709
RF RAAM SERV-710 | 0 | RF RAAM SERV-710
RF RAAM SERV-711 | 0 | RF RAAM SERV-711
RF RAAM SERV-712 | 0 | RF RAAM SERV-712
RF RAAM SERV-713 | 0 | RF RAAM SERV-713
RF RAAM SERV-714 | 0 | RF RAAM SERV-714
RF RAAM SERV-715 | 0 | RF RAAM SERV-715
RF RAAM SERV-716 | 0 | RF RAAM SERV-716
4 x RF RAAM HOR-648 | 0 | RF RAAM HOR-648
RF RAAM SERV-612 | 0 | RF RAAM SERV-612
RF RAAM SERV-678 | 0 | RF RAAM SERV-678
RF RAAM SERV-663 | 0 | RF RAAM SERV-663
RF RAAM SERV-664 | 0 | RF RAAM SERV-664
RF RAAM SERV-665 | 0 | RF RAAM SERV-665
RF RAAM SERV-666 | 0 | RF RAAM SERV-666
RF RAAM SERV-667 | 0 | RF RAAM SERV-667
RF RAAM SERV-668 | 0 | RF RAAM SERV-668
RF RAAM SERV-669 | 0 | RF RAAM SERV-669
RF RAAM SERV-670 | 0 | RF RAAM SERV-670
RF RAAM SERV-671 | 0 | RF RAAM SERV-671
RF RAAM SERV-672 | 0 | RF RAAM SERV-672
RF RAAM SERV-673 | 0 | RF RAAM SERV-673
RF RAAM SERV-674 | 0 | RF RAAM SERV-674
RF RAAM SERV-675 | 0 | RF RAAM SERV-675
RF RAAM SERV-676 | 0 | RF RAAM SERV-676
RF RAAM SERV-677 | 0 | RF RAAM SERV-677
RF RAAM SERV-662 | 0 | RF RAAM SERV-662
RF RAAM SERV-697 | 0 | RF RAAM SERV-697
RF RAAM SERV-718 | 0 | RF RAAM SERV-718
RF RAAM SERV-700 | 5.21397e-07 | RF RAAM SERV-700
RF RAAM SERV-699 | 5.21397e-07 | RF RAAM SERV-699
RF RAAM SERV-698 | 5.21397e-07 | RF RAAM SERV-698
RF RAAM SERV-697 | 5.21397e-07 | RF RAAM SERV-697
RF RAAM SERV-696 | 5.21397e-07 | RF RAAM SERV-696
RF RAAM SERV-695 | 5.21397e-07 | RF RAAM SERV-695
RF RAAM SERV-694 | 5.21397e-07 | RF RAAM SERV-694
RF RAAM SERV-693 | 5.21397e-07 | RF RAAM SERV-693
RF RAAM SERV-692 | 5.21397e-07 | RF RAAM SERV-692
RF RAAM SERV-691 | 5.21397e-07 | RF RAAM SERV-691
RF RAAM SERV-690 | 5.21397e-07 | RF RAAM SERV-690
RF RAAM SERV-689 | 5.21397e-07 | RF RAAM SERV-689
RF RAAM SERV-688 | 5.21397e-07 | RF RAAM SERV-688
RF RAAM SERV-687 | 5.21397e-07 | RF RAAM SERV-687
RF RAAM SERV-686 | 5.21397e-07 | RF RAAM SERV-686
RF RAAM SERV-685 | 5.1705e-07 | RF RAAM SERV-685
RF RAAM SERV-736 | 0 | RF RAAM SERV-736
RF RAAM SERV-735 | 0 | RF RAAM SERV-735
RF RAAM SERV-734 | 0 | RF RAAM SERV-734
RF RAAM SERV-733 | 0 | RF RAAM SERV-733
RF RAAM SERV-732 | 0 | RF RAAM SERV-732
RF RAAM SERV-731 | 0 | RF RAAM SERV-731
RF RAAM SERV-730 | 0 | RF RAAM SERV-730
RF RAAM SERV-729 | 0 | RF RAAM SERV-729
RF RAAM SERV-728 | 0 | RF RAAM SERV-728
RF RAAM SERV-727 | 0.00000617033 | RF RAAM SERV-727
RF RAAM SERV-707 | 90 | RF RAAM SERV-707
RF RAAM SERV-706 | 90 | RF RAAM SERV-706
RF RAAM SERV-705 | 90 | RF RAAM SERV-705
RF RAAM SERV-704 | 90 | RF RAAM SERV-704
RF RAAM SERV-703 | 90 | RF RAAM SERV-703
RF RAAM SERV-702 | 90 | RF RAAM SERV-702
RF RAAM SERV-701 | 5.21397e-07 | RF RAAM SERV-701
RF RAAM SERV-726 | 0.0000990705 | RF RAAM SERV-726
RF RAAM SERV-725 | 90 | RF RAAM SERV-725
RF RAAM SERV-724 | 90 | RF RAAM SERV-724
RF RAAM SERV-723 | 90 | RF RAAM SERV-723
RF RAAM SERV-722 | 90 | RF RAAM SERV-722
RF RAAM SERV-721 | 90 | RF RAAM SERV-721
RF RAAM SERV-720 | 90 | RF RAAM SERV-720
RF RAAM SERV-719 | 0 | RF RAAM SERV-719
RF RAAM SERV-880 | 0 | RF RAAM SERV-880
RF RAAM SERV-861 | 0 | RF RAAM SERV-861
RF RAAM SERV-881 | 0 | RF RAAM SERV-881
RF RAAM SERV-882 | 0 | RF RAAM SERV-882
RF RAAM SERV-883 | 0 | RF RAAM SERV-883
RF RAAM SERV-884 | 0 | RF RAAM SERV-884
RF RAAM SERV-885 | 0 | RF RAAM SERV-885
RF RAAM SERV-886 | 0 | RF RAAM SERV-886
RF RAAM SERV-887 | 0 | RF RAAM SERV-887
RF RAAM SERV-888 | 0 | RF RAAM SERV-888
4 x RF RAAM HOR-249 | 0 | RF RAAM HOR-249
RF RAAM SERV-860 | 0 | RF RAAM SERV-860
RF RAAM SERV-917 | 0 | RF RAAM SERV-917
RF RAAM SERV-856 | 0 | RF RAAM SERV-856
2 x RF RAAM SERV-916 | 0 | RF RAAM SERV-916
RF RAAM SERV-879 | 90 | RF RAAM SERV-879
RF RAAM SERV-878 | 90 | RF RAAM SERV-878
RF RAAM SERV-877 | 90 | RF RAAM SERV-877
RF RAAM SERV-876 | 90 | RF RAAM SERV-876
RF RAAM SERV-875 | 90 | RF RAAM SERV-875
RF RAAM SERV-874 | 90 | RF RAAM SERV-874
RF RAAM SERV-873 | 0 | RF RAAM SERV-873
RF RAAM SERV-872 | 0 | RF RAAM SERV-872
RF RAAM SERV-871 | 0 | RF RAAM SERV-871
RF RAAM SERV-870 | 0 | RF RAAM SERV-870
RF RAAM SERV-869 | 0 | RF RAAM SERV-869
RF RAAM SERV-868 | 0 | RF RAAM SERV-868
RF RAAM SERV-909 | 0 | RF RAAM SERV-909
RF RAAM SERV-908 | 0 | RF RAAM SERV-908
RF RAAM SERV-907 | 0 | RF RAAM SERV-907
RF RAAM SERV-906 | 0 | RF RAAM SERV-906
RF RAAM SERV-905 | 0 | RF RAAM SERV-905
RF RAAM SERV-904 | 0 | RF RAAM SERV-904
RF RAAM SERV-903 | 0 | RF RAAM SERV-903
RF RAAM SERV-902 | 0 | RF RAAM SERV-902
RF RAAM SERV-901 | 0 | RF RAAM SERV-901
RF RAAM SERV-900 | 0 | RF RAAM SERV-900
RF RAAM SERV-899 | 0 | RF RAAM SERV-899
RF RAAM SERV-898 | 0.00000252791 | RF RAAM SERV-898
RF RAAM SERV-897 | 90 | RF RAAM SERV-897
RF RAAM SERV-896 | 90 | RF RAAM SERV-896
RF RAAM SERV-895 | 90 | RF RAAM SERV-895
RF RAAM SERV-894 | 90 | RF RAAM SERV-894
RF RAAM SERV-893 | 90 | RF RAAM SERV-893
RF RAAM SERV-892 | 90 | RF RAAM SERV-892
RF RAAM SERV-891 | 0 | RF RAAM SERV-891
RF RAAM HOR-776 | 0 | RF RAAM HOR-776

# IfcMember: Boundary Frame 85 x 115 (12)
In: 3. korrus
Type - PredefinedType: MEMBER
Classification: 1.13 IfcMemberType (kandev element) (RKAS BIM + ARCHICAD Classification); Material: _METALL - alumiinium
Pset_MemberCommon - Reference: Frame 25
AR_001-002 - 002_Tüüp: Frame 25
AC_Pset_RenovationAndPhasing - Renovation Status: Undefined
Name | Slope (deg) | 001_Nimetus
RF RAAM SERV-346 | 7 | RF RAAM SERV-346
RF RAAM SERV-347 | 8.83487e-14 | RF RAAM SERV-347
RF RAAM SERV-348 | 1.34633e-13 | RF RAAM SERV-348
RF RAAM SERV-349 | 7 | RF RAAM SERV-349
RF RAAM SERV-353 | 7 | RF RAAM SERV-353
RF RAAM SERV-352 | 1.53743e-13 | RF RAAM SERV-352
RF RAAM SERV-351 | 4.12556e-08 | RF RAAM SERV-351
RF RAAM SERV-350 | 7 | RF RAAM SERV-350
RF RAAM SERV-355 | 7 | RF RAAM SERV-355
RF RAAM SERV-356 | 7 | RF RAAM SERV-356
RF RAAM SERV-357 | 1.36272e-13 | RF RAAM SERV-357
RF RAAM SERV-358 | 1.76697e-13 | RF RAAM SERV-358

# IfcMember: Corner Frame 120 x 120 (7)
In: 1. korrus
Type - PredefinedType: MEMBER
Classification: 1.13 IfcMemberType (kandev element) (RKAS BIM + ARCHICAD Classification); Material: _KANDETARIND - liimpuit vastavalt EK osale
Pset_MemberCommon - Reference: Block Butt-Glazed Frame 25; Slope: 90 deg
AR_001-002 - 002_Tüüp: Block Butt-Glazed Frame 25
AC_Pset_RenovationAndPhasing - Renovation Status: Undefined
Name | 001_Nimetus
2 x RF RAAM NURK-920 | RF RAAM NURK-920
2 x RF RAAM NURK-857 | RF RAAM NURK-857
RF RAAM NURK-921 | RF RAAM NURK-921
RF RAAM NURK-922 | RF RAAM NURK-922
RF RAAM NURK-923 | RF RAAM NURK-923

# IfcMember: Corner Frame 80 x 100 (16)
In: 1. korrus
Type - PredefinedType: MEMBER
Classification: 1.13 IfcMemberType (kandev element) (RKAS BIM + ARCHICAD Classification); Material: _METALL - alumiinium
Pset_MemberCommon - Reference: Regular Double Frame with Cap 25; Slope: 90 deg
AR_001-002 - 002_Tüüp: Regular Double Frame with Cap 25
AC_Pset_RenovationAndPhasing - Renovation Status: Undefined
Name | 001_Nimetus
RF RAAM NURK-947 | RF RAAM NURK-947
RF RAAM NURK-948 | RF RAAM NURK-948
RF RAAM NURK-949 | RF RAAM NURK-949
RF RAAM NURK-950 | RF RAAM NURK-950
RF RAAM NURK-952 | RF RAAM NURK-952
RF RAAM NURK-953 | RF RAAM NURK-953
RF RAAM NURK-954 | RF RAAM NURK-954
RF RAAM NURK-955 | RF RAAM NURK-955
RF RAAM NURK-957 | RF RAAM NURK-957
RF RAAM NURK-958 | RF RAAM NURK-958
RF RAAM NURK-959 | RF RAAM NURK-959
RF RAAM NURK-960 | RF RAAM NURK-960
RF RAAM NURK-961 | RF RAAM NURK-961
RF RAAM NURK-951 | RF RAAM NURK-951
RF RAAM NURK-956 | RF RAAM NURK-956
RF RAAM NURK-962 | RF RAAM NURK-962

# IfcMember: Corner Frame 80 x 60 (2)
Type - PredefinedType: MEMBER
Classification: 1.13 IfcMemberType (kandev element) (RKAS BIM + ARCHICAD Classification)
Pset_MemberCommon - Reference: Block Frame with Cap 25; Slope: 90 deg
AR_001-002 - 002_Tüüp: Block Frame with Cap 25
AC_Pset_RenovationAndPhasing - Renovation Status: Undefined
Name | In | 001_Nimetus
RF RAAM NURK-066 | 2. korrus | RF RAAM NURK-066
RF RAAM NURK-067 | 3. korrus | RF RAAM NURK-067

# IfcMember: IfcMember (2)
In: 4. TEHNO korrus
Type - ElementType: Rail; PredefinedType: USERDEFINED
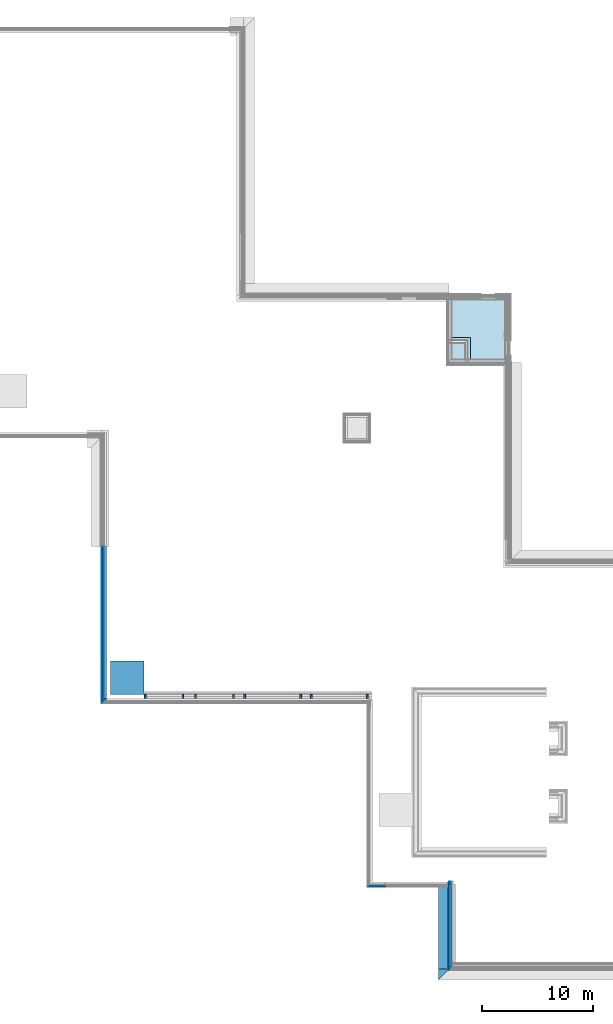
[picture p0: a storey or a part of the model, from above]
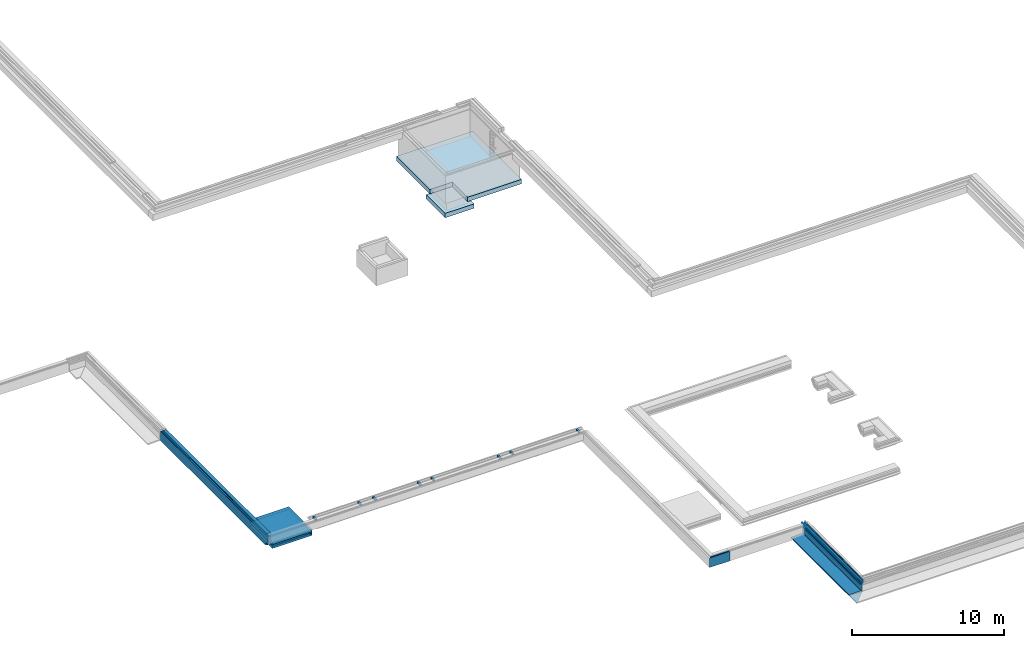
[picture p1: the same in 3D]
Properties of the parts of a building model (IFC2X3), part 7 of 14

# IfcMember: IfcMember (2)
Classification: Rail (RKAS BIM + ARCHICAD Classification); Material: _METALL - kuumtsingitud teras
AC_Pset_RenovationAndPhasing - Renovation Status: New

# IfcMember: IfcMember (260)
Type - ElementType: Stair Riser; PredefinedType: USERDEFINED
Classification: Stair Riser (RKAS BIM + ARCHICAD Classification); Material: _VIIMISTLUSKIHT - viimistlus vastavalt SA osale
AC_Pset_RenovationAndPhasing - Renovation Status: New
Name | In
2 x TV TÕUS - 146 | 1. korrus
2 x TV TÕUS - 147 | 1. korrus
2 x TV TÕUS - 148 | 1. korrus
2 x TV TÕUS - 149 | 1. korrus
2 x TV TÕUS - 150 | 1. korrus
2 x TV TÕUS - 151 | 1. korrus
2 x TV TÕUS - 152 | 1. korrus
2 x TV TÕUS - 153 | 1. korrus
2 x TV TÕUS - 154 | 1. korrus
2 x TV TÕUS - 155 | 1. korrus
2 x TV TÕUS - 156 | 1. korrus
2 x TV TÕUS - 157 | 1. korrus
2 x TV TÕUS - 158 | 1. korrus
2 x TV TÕUS - 159 | 1. korrus
2 x SL RISER - 006 | 1. korrus
2 x TV TÕUS - 160 | 1. korrus
2 x TV TÕUS - 161 | 1. korrus
2 x TV TÕUS - 162 | 1. korrus
2 x TV TÕUS - 163 | 1. korrus
2 x TV TÕUS - 164 | 1. korrus
2 x TV TÕUS - 165 | 1. korrus
2 x TV TÕUS - 166 | 1. korrus
2 x TV TÕUS - 167 | 1. korrus
2 x TV TÕUS - 168 | 1. korrus
2 x TV TÕUS - 169 | 1. korrus
2 x TV TÕUS - 170 | 1. korrus
2 x TV TÕUS - 171 | 1. korrus
2 x TV TÕUS - 172 | 1. korrus
2 x TV TÕUS - 173 | 1. korrus
TV TÕUS - 110 | 1. korrus
TV TÕUS - 111 | 1. korrus
TV TÕUS - 112 | 1. korrus
TV TÕUS - 113 | 1. korrus
TV TÕUS - 114 | 1. korrus
TV TÕUS - 115 | 1. korrus
TV TÕUS - 116 | 1. korrus
SL RISER - 012 | 1. korrus
TV TÕUS - 117 | 1. korrus
TV TÕUS - 118 | 1. korrus
TV TÕUS - 119 | 1. korrus
TV TÕUS - 120 | 1. korrus
TV TÕUS - 121 | 1. korrus
TV TÕUS - 122 | 1. korrus
TV TÕUS - 123 | 1. korrus
TV TÕUS - 124 | 1. korrus
SL RISER - 013 | 1. korrus
TV TÕUS - 125 | 1. korrus
TV TÕUS - 126 | 1. korrus
TV TÕUS - 127 | 1. korrus
TV TÕUS - 128 | 1. korrus
SL RISER - 014 | 1. korrus
TV TÕUS - 129 | 1. korrus
TV TÕUS - 130 | 1. korrus
TV TÕUS - 131 | 1. korrus
TV TÕUS - 132 | 1. korrus
TV TÕUS - 133 | 1. korrus
TV TÕUS - 134 | 1. korrus
TV TÕUS - 135 | 1. korrus
TV TÕUS - 176 | 1. korrus
TV TÕUS - 177 | 1. korrus
TV TÕUS - 178 | 1. korrus
TV TÕUS - 179 | 1. korrus
TV TÕUS - 180 | 1. korrus
TV TÕUS - 181 | 1. korrus
TV TÕUS - 182 | 1. korrus
TV TÕUS - 183 | 1. korrus
TV TÕUS - 184 | 1. korrus
TV TÕUS - 185 | 1. korrus
TV TÕUS - 186 | 1. korrus
TV TÕUS - 187 | 1. korrus
TV TÕUS - 188 | 1. korrus
TV TÕUS - 189 | 1. korrus
TV TÕUS - 190 | 1. korrus
TV TÕUS - 191 | 1. korrus
TV TÕUS - 192 | 1. korrus
TV TÕUS - 193 | 1. korrus
TV TÕUS - 205 | 1. korrus
TV TÕUS - 206 | 1. korrus
TV TÕUS - 207 | 1. korrus
TV TÕUS - 208 | 1. korrus
TV TÕUS - 209 | 1. korrus
TV TÕUS - 210 | 1. korrus
TV TÕUS - 211 | 1. korrus
TV TÕUS - 212 | 1. korrus
TV TÕUS - 213 | 1. korrus
TV TÕUS - 223 | 1. korrus
TV TÕUS - 224 | 1. korrus
3 x TV TÕUS - 117 | 2. korrus
3 x TV TÕUS - 118 | 2. korrus
3 x TV TÕUS - 119 | 2. korrus
3 x TV TÕUS - 120 | 2. korrus
3 x TV TÕUS - 121 | 2. korrus
3 x TV TÕUS - 122 | 2. korrus
3 x TV TÕUS - 123 | 2. korrus
3 x TV TÕUS - 124 | 2. korrus
3 x TV TÕUS - 125 | 2. korrus
3 x TV TÕUS - 126 | 2. korrus
2 x TV TÕUS - 127 | 2. korrus
2 x TV TÕUS - 128 | 2. korrus
2 x SL RISER - 005 | 2. korrus
2 x TV TÕUS - 129 | 2. korrus
2 x TV TÕUS - 130 | 2. korrus
2 x TV TÕUS - 131 | 2. korrus
3 x TV TÕUS - 132 | 2. korrus
3 x TV TÕUS - 133 | 2. korrus
3 x TV TÕUS - 134 | 2. korrus
3 x TV TÕUS - 135 | 2. korrus
2 x TV TÕUS - 136 | 2. korrus
2 x TV TÕUS - 137 | 2. korrus
2 x TV TÕUS - 138 | 2. korrus
2 x TV TÕUS - 139 | 2. korrus
TV TÕUS - 110 | 2. korrus
TV TÕUS - 111 | 2. korrus
TV TÕUS - 112 | 2. korrus
SL RISER - 012 | 2. korrus
TV TÕUS - 113 | 2. korrus
TV TÕUS - 114 | 2. korrus
TV TÕUS - 115 | 2. korrus
TV TÕUS - 116 | 2. korrus
SL RISER - 013 | 2. korrus
SL RISER - 014 | 2. korrus
TV TÕUS - 163 | 2. korrus
TV TÕUS - 164 | 2. korrus
TV TÕUS - 165 | 2. korrus
TV TÕUS - 166 | 2. korrus
TV TÕUS - 167 | 2. korrus
TV TÕUS - 168 | 2. korrus
TV TÕUS - 169 | 2. korrus
TV TÕUS - 170 | 2. korrus
TV TÕUS - 171 | 2. korrus
TV TÕUS - 172 | 2. korrus
TV TÕUS - 173 | 2. korrus
TV TÕUS - 174 | 2. korrus
TV TÕUS - 175 | 2. korrus
TV TÕUS - 176 | 2. korrus
TV TÕUS - 177 | 2. korrus
TV TÕUS - 178 | 2. korrus
TV TÕUS - 179 | 2. korrus
TV TÕUS - 180 | 2. korrus
TV TÕUS - 181 | 2. korrus
TV TÕUS - 182 | 2. korrus
TV TÕUS - 183 | 2. korrus
TV TÕUS - 184 | 2. korrus
TV TÕUS - 185 | 2. korrus
TV TÕUS - 186 | 2. korrus
TV TÕUS - 197 | 2. korrus
TV TÕUS - 198 | 2. korrus
TV TÕUS - 199 | 2. korrus
TV TÕUS - 200 | 2. korrus
TV TÕUS - 201 | 2. korrus
TV TÕUS - 202 | 2. korrus
TV TÕUS - 203 | 2. korrus
TV TÕUS - 204 | 2. korrus
TV TÕUS - 163 | 3. korrus
TV TÕUS - 164 | 3. korrus
TV TÕUS - 165 | 3. korrus
TV TÕUS - 166 | 3. korrus
TV TÕUS - 167 | 3. korrus
TV TÕUS - 168 | 3. korrus
TV TÕUS - 169 | 3. korrus
TV TÕUS - 170 | 3. korrus
TV TÕUS - 171 | 3. korrus
TV TÕUS - 172 | 3. korrus
TV TÕUS - 173 | 3. korrus
TV TÕUS - 174 | 3. korrus
TV TÕUS - 175 | 3. korrus
TV TÕUS - 176 | 3. korrus
TV TÕUS - 177 | 3. korrus
TV TÕUS - 178 | 3. korrus
TV TÕUS - 179 | 3. korrus
TV TÕUS - 180 | 3. korrus
TV TÕUS - 181 | 3. korrus
TV TÕUS - 182 | 3. korrus
TV TÕUS - 183 | 3. korrus
TV TÕUS - 184 | 3. korrus
TV TÕUS - 185 | 3. korrus
TV TÕUS - 186 | 3. korrus
2 x TV TÕUS - 197 | 3. korrus
2 x TV TÕUS - 198 | 3. korrus
2 x TV TÕUS - 199 | 3. korrus
2 x TV TÕUS - 200 | 3. korrus
2 x TV TÕUS - 201 | 3. korrus
2 x TV TÕUS - 202 | 3. korrus
2 x TV TÕUS - 203 | 3. korrus
2 x TV TÕUS - 204 | 3. korrus

# IfcMember: IfcMember (34)
Type - ElementType: Stair Structure; PredefinedType: USERDEFINED
Classification: Stair Structure (RKAS BIM + ARCHICAD Classification)
AC_Pset_RenovationAndPhasing - Renovation Status: New
Name | In | Material
2 x TT KONSTRUKTSIOON - 010 | 1. korrus | _KANDETARIND - raudbetoon C25/30 vastavalt EK osale
2 x TM KONSTRUKTSIOON - 006 | 1. korrus | _KANDETARIND - raudbetoon C25/30 vastavalt EK osale
2 x TT KONSTRUKTSIOON - 011 | 1. korrus | _KANDETARIND - raudbetoon C25/30 vastavalt EK osale
TT KONSTRUKTSIOON - 015 | 1. korrus | _KANDETARIND - raudbetoon C25/30 vastavalt EK osale
TM KONSTRUKTSIOON - 012 | 1. korrus | _KANDETARIND - raudbetoon C25/30 vastavalt EK osale
TT KONSTRUKTSIOON - 016 | 1. korrus | _KANDETARIND - raudbetoon C25/30 vastavalt EK osale
TM KONSTRUKTSIOON - 013 | 1. korrus | _KANDETARIND - raudbetoon C25/30 vastavalt EK osale
TT KONSTRUKTSIOON - 017 | 1. korrus | _KANDETARIND - raudbetoon C25/30 vastavalt EK osale
TM KONSTRUKTSIOON - 014 | 1. korrus | _KANDETARIND - raudbetoon C25/30 vastavalt EK osale
TT KONSTRUKTSIOON - 018 | 1. korrus | _KANDETARIND - raudbetoon C25/30 vastavalt EK osale
2 x TT KONSTRUKTSIOON - 019 | 1. korrus | _KANDETARIND - raudbetoon C25/30 vastavalt EK osale
2 x TT KONSTRUKTSIOON - 012 | 1. korrus | _KANDETARIND - raudbetoon C25/30 vastavalt EK osale
2 x TT KONSTRUKTSIOON - 008 | 2. korrus | _KANDETARIND - raudbetoon C25/30 vastavalt EK osale
2 x TM KONSTRUKTSIOON - 005 | 2. korrus | _KANDETARIND - raudbetoon C25/30 vastavalt EK osale
2 x TT KONSTRUKTSIOON - 009 | 2. korrus | _KANDETARIND - raudbetoon C25/30 vastavalt EK osale
TT KONSTRUKTSIOON - 015 | 2. korrus | _KANDETARIND - raudbetoon C25/30 vastavalt EK osale
TM KONSTRUKTSIOON - 012 | 2. korrus | _KANDETARIND - raudbetoon C25/30 vastavalt EK osale
TT KONSTRUKTSIOON - 016 | 2. korrus | _KANDETARIND - raudbetoon C25/30 vastavalt EK osale
TM KONSTRUKTSIOON - 013 | 2. korrus | _KANDETARIND - raudbetoon C25/30 vastavalt EK osale
TT KONSTRUKTSIOON - 017 | 2. korrus | _KANDETARIND - raudbetoon C25/30 vastavalt EK osale
TM KONSTRUKTSIOON - 014 | 2. korrus | _KANDETARIND - raudbetoon C25/30 vastavalt EK osale
TT KONSTRUKTSIOON - 018 | 2. korrus | _KANDETARIND - raudbetoon C25/30 vastavalt EK osale
trepp | 4. TEHNO korrus | _METALL - kuumtsingitud teras
2 x SF RIGHT STRINGER - 025 | 4. TEHNO korrus | _METALL - kuumtsingitud teras
SF LEFT STRINGER - 025 | 4. TEHNO korrus | _METALL - kuumtsingitud teras

# IfcMember: IfcMember (311)
Type - ElementType: Stair Tread; PredefinedType: USERDEFINED
Classification: Stair Tread (RKAS BIM + ARCHICAD Classification)
AC_Pset_RenovationAndPhasing - Renovation Status: New
Name | In | Material
2 x TV ASTE - 146 | 1. korrus | _VIIMISTLUSKIHT - viimistlus vastavalt SA osale
2 x TV ASTE - 147 | 1. korrus | _VIIMISTLUSKIHT - viimistlus vastavalt SA osale
2 x TV ASTE - 148 | 1. korrus | _VIIMISTLUSKIHT - viimistlus vastavalt SA osale
2 x TV ASTE - 149 | 1. korrus | _VIIMISTLUSKIHT - viimistlus vastavalt SA osale
2 x TV ASTE - 150 | 1. korrus | _VIIMISTLUSKIHT - viimistlus vastavalt SA osale
2 x TV ASTE - 151 | 1. korrus | _VIIMISTLUSKIHT - viimistlus vastavalt SA osale
2 x TV ASTE - 152 | 1. korrus | _VIIMISTLUSKIHT - viimistlus vastavalt SA osale
2 x TV ASTE - 153 | 1. korrus | _VIIMISTLUSKIHT - viimistlus vastavalt SA osale
2 x TV ASTE - 154 | 1. korrus | _VIIMISTLUSKIHT - viimistlus vastavalt SA osale
2 x TV ASTE - 155 | 1. korrus | _VIIMISTLUSKIHT - viimistlus vastavalt SA osale
2 x TV ASTE - 156 | 1. korrus | _VIIMISTLUSKIHT - viimistlus vastavalt SA osale
2 x TV ASTE - 157 | 1. korrus | _VIIMISTLUSKIHT - viimistlus vastavalt SA osale
2 x TV ASTE - 158 | 1. korrus | _VIIMISTLUSKIHT - viimistlus vastavalt SA osale
2 x TV ASTE - 159 | 1. korrus | _VIIMISTLUSKIHT - viimistlus vastavalt SA osale
2 x SL TREAD - 006 | 1. korrus | _VIIMISTLUSKIHT - viimistlus vastavalt SA osale
2 x TV ASTE - 160 | 1. korrus | _VIIMISTLUSKIHT - viimistlus vastavalt SA osale
2 x TV ASTE - 161 | 1. korrus | _VIIMISTLUSKIHT - viimistlus vastavalt SA osale
2 x TV ASTE - 162 | 1. korrus | _VIIMISTLUSKIHT - viimistlus vastavalt SA osale
2 x TV ASTE - 163 | 1. korrus | _VIIMISTLUSKIHT - viimistlus vastavalt SA osale
2 x TV ASTE - 164 | 1. korrus | _VIIMISTLUSKIHT - viimistlus vastavalt SA osale
2 x TV ASTE - 165 | 1. korrus | _VIIMISTLUSKIHT - viimistlus vastavalt SA osale
2 x TV ASTE - 166 | 1. korrus | _VIIMISTLUSKIHT - viimistlus vastavalt SA osale
2 x TV ASTE - 167 | 1. korrus | _VIIMISTLUSKIHT - viimistlus vastavalt SA osale
2 x TV ASTE - 168 | 1. korrus | _VIIMISTLUSKIHT - viimistlus vastavalt SA osale
2 x TV ASTE - 169 | 1. korrus | _VIIMISTLUSKIHT - viimistlus vastavalt SA osale
2 x TV ASTE - 170 | 1. korrus | _VIIMISTLUSKIHT - viimistlus vastavalt SA osale
2 x TV ASTE - 171 | 1. korrus | _VIIMISTLUSKIHT - viimistlus vastavalt SA osale
2 x TV ASTE - 172 | 1. korrus | _VIIMISTLUSKIHT - viimistlus vastavalt SA osale
TV ASTE - 110 | 1. korrus | _VIIMISTLUSKIHT - viimistlus vastavalt SA osale
TV ASTE - 111 | 1. korrus | _VIIMISTLUSKIHT - viimistlus vastavalt SA osale
TV ASTE - 112 | 1. korrus | _VIIMISTLUSKIHT - viimistlus vastavalt SA osale
TV ASTE - 113 | 1. korrus | _VIIMISTLUSKIHT - viimistlus vastavalt SA osale
TV ASTE - 114 | 1. korrus | _VIIMISTLUSKIHT - viimistlus vastavalt SA osale
TV ASTE - 115 | 1. korrus | _VIIMISTLUSKIHT - viimistlus vastavalt SA osale
TV ASTE - 116 | 1. korrus | _VIIMISTLUSKIHT - viimistlus vastavalt SA osale
SL TREAD - 012 | 1. korrus | _VIIMISTLUSKIHT - viimistlus vastavalt SA osale
TV ASTE - 117 | 1. korrus | _VIIMISTLUSKIHT - viimistlus vastavalt SA osale
TV ASTE - 118 | 1. korrus | _VIIMISTLUSKIHT - viimistlus vastavalt SA osale
TV ASTE - 119 | 1. korrus | _VIIMISTLUSKIHT - viimistlus vastavalt SA osale
TV ASTE - 120 | 1. korrus | _VIIMISTLUSKIHT - viimistlus vastavalt SA osale
TV ASTE - 121 | 1. korrus | _VIIMISTLUSKIHT - viimistlus vastavalt SA osale
TV ASTE - 122 | 1. korrus | _VIIMISTLUSKIHT - viimistlus vastavalt SA osale
TV ASTE - 123 | 1. korrus | _VIIMISTLUSKIHT - viimistlus vastavalt SA osale
TV ASTE - 124 | 1. korrus | _VIIMISTLUSKIHT - viimistlus vastavalt SA osale
SL TREAD - 013 | 1. korrus | _VIIMISTLUSKIHT - viimistlus vastavalt SA osale
TV ASTE - 125 | 1. korrus | _VIIMISTLUSKIHT - viimistlus vastavalt SA osale
TV ASTE - 126 | 1. korrus | _VIIMISTLUSKIHT - viimistlus vastavalt SA osale
TV ASTE - 127 | 1. korrus | _VIIMISTLUSKIHT - viimistlus vastavalt SA osale
TV ASTE - 128 | 1. korrus | _VIIMISTLUSKIHT - viimistlus vastavalt SA osale
SL TREAD - 014 | 1. korrus | _VIIMISTLUSKIHT - viimistlus vastavalt SA osale
TV ASTE - 129 | 1. korrus | _VIIMISTLUSKIHT - viimistlus vastavalt SA osale
TV ASTE - 130 | 1. korrus | _VIIMISTLUSKIHT - viimistlus vastavalt SA osale
TV ASTE - 131 | 1. korrus | _VIIMISTLUSKIHT - viimistlus vastavalt SA osale
TV ASTE - 132 | 1. korrus | _VIIMISTLUSKIHT - viimistlus vastavalt SA osale
TV ASTE - 133 | 1. korrus | _VIIMISTLUSKIHT - viimistlus vastavalt SA osale
TV ASTE - 134 | 1. korrus | _VIIMISTLUSKIHT - viimistlus vastavalt SA osale
TV ASTE - 135 | 1. korrus | _VIIMISTLUSKIHT - viimistlus vastavalt SA osale
TV ASTE - 177 | 1. korrus | _VIIMISTLUSKIHT - viimistlus vastavalt SA osale
TV ASTE - 178 | 1. korrus | _VIIMISTLUSKIHT - viimistlus vastavalt SA osale
TV ASTE - 179 | 1. korrus | _VIIMISTLUSKIHT - viimistlus vastavalt SA osale
TV ASTE - 180 | 1. korrus | _VIIMISTLUSKIHT - viimistlus vastavalt SA osale
TV ASTE - 181 | 1. korrus | _VIIMISTLUSKIHT - viimistlus vastavalt SA osale
TV ASTE - 182 | 1. korrus | _VIIMISTLUSKIHT - viimistlus vastavalt SA osale
TV ASTE - 183 | 1. korrus | _VIIMISTLUSKIHT - viimistlus vastavalt SA osale
TV ASTE - 184 | 1. korrus | _VIIMISTLUSKIHT - viimistlus vastavalt SA osale
TV ASTE - 185 | 1. korrus | _VIIMISTLUSKIHT - viimistlus vastavalt SA osale
TV ASTE - 186 | 1. korrus | _VIIMISTLUSKIHT - viimistlus vastavalt SA osale
TV ASTE - 187 | 1. korrus | _VIIMISTLUSKIHT - viimistlus vastavalt SA osale
TV ASTE - 188 | 1. korrus | _VIIMISTLUSKIHT - viimistlus vastavalt SA osale
TV ASTE - 189 | 1. korrus | _VIIMISTLUSKIHT - viimistlus vastavalt SA osale
TV ASTE - 190 | 1. korrus | _VIIMISTLUSKIHT - viimistlus vastavalt SA osale
TV ASTE - 191 | 1. korrus | _VIIMISTLUSKIHT - viimistlus vastavalt SA osale
TV ASTE - 192 | 1. korrus | _VIIMISTLUSKIHT - viimistlus vastavalt SA osale
TV ASTE - 193 | 1. korrus | _VIIMISTLUSKIHT - viimistlus vastavalt SA osale
TV ASTE - 194 | 1. korrus | _VIIMISTLUSKIHT - viimistlus vastavalt SA osale
TV ASTE - 206 | 1. korrus | _VIIMISTLUSKIHT - viimistlus vastavalt SA osale
TV ASTE - 207 | 1. korrus | _VIIMISTLUSKIHT - viimistlus vastavalt SA osale
TV ASTE - 208 | 1. korrus | _VIIMISTLUSKIHT - viimistlus vastavalt SA osale
TV ASTE - 209 | 1. korrus | _VIIMISTLUSKIHT - viimistlus vastavalt SA osale
TV ASTE - 210 | 1. korrus | _VIIMISTLUSKIHT - viimistlus vastavalt SA osale
TV ASTE - 211 | 1. korrus | _VIIMISTLUSKIHT - viimistlus vastavalt SA osale
TV ASTE - 212 | 1. korrus | _VIIMISTLUSKIHT - viimistlus vastavalt SA osale
TV ASTE - 213 | 1. korrus | _VIIMISTLUSKIHT - viimistlus vastavalt SA osale
TV ASTE - 214 | 1. korrus | _VIIMISTLUSKIHT - viimistlus vastavalt SA osale
TV ASTE - 224 | 1. korrus | _VIIMISTLUSKIHT - viimistlus vastavalt SA osale
TV ASTE - 225 | 1. korrus | _VIIMISTLUSKIHT - viimistlus vastavalt SA osale
3 x TV ASTE - 117 | 2. korrus | _VIIMISTLUSKIHT - viimistlus vastavalt SA osale
3 x TV ASTE - 118 | 2. korrus | _VIIMISTLUSKIHT - viimistlus vastavalt SA osale
3 x TV ASTE - 119 | 2. korrus | _VIIMISTLUSKIHT - viimistlus vastavalt SA osale
3 x TV ASTE - 120 | 2. korrus | _VIIMISTLUSKIHT - viimistlus vastavalt SA osale
3 x TV ASTE - 121 | 2. korrus | _VIIMISTLUSKIHT - viimistlus vastavalt SA osale
3 x TV ASTE - 122 | 2. korrus | _VIIMISTLUSKIHT - viimistlus vastavalt SA osale
3 x TV ASTE - 123 | 2. korrus | _VIIMISTLUSKIHT - viimistlus vastavalt SA osale
3 x TV ASTE - 124 | 2. korrus | _VIIMISTLUSKIHT - viimistlus vastavalt SA osale
3 x TV ASTE - 125 | 2. korrus | _VIIMISTLUSKIHT - viimistlus vastavalt SA osale
3 x TV ASTE - 126 | 2. korrus | _VIIMISTLUSKIHT - viimistlus vastavalt SA osale
3 x TV ASTE - 127 | 2. korrus | _VIIMISTLUSKIHT - viimistlus vastavalt SA osale
2 x TV ASTE - 128 | 2. korrus | _VIIMISTLUSKIHT - viimistlus vastavalt SA osale
2 x SL TREAD - 005 | 2. korrus | _VIIMISTLUSKIHT - viimistlus vastavalt SA osale
2 x TV ASTE - 129 | 2. korrus | _VIIMISTLUSKIHT - viimistlus vastavalt SA osale
2 x TV ASTE - 130 | 2. korrus | _VIIMISTLUSKIHT - viimistlus vastavalt SA osale
2 x TV ASTE - 131 | 2. korrus | _VIIMISTLUSKIHT - viimistlus vastavalt SA osale
2 x TV ASTE - 132 | 2. korrus | _VIIMISTLUSKIHT - viimistlus vastavalt SA osale
3 x TV ASTE - 133 | 2. korrus | _VIIMISTLUSKIHT - viimistlus vastavalt SA osale
3 x TV ASTE - 134 | 2. korrus | _VIIMISTLUSKIHT - viimistlus vastavalt SA osale
3 x TV ASTE - 135 | 2. korrus | _VIIMISTLUSKIHT - viimistlus vastavalt SA osale
3 x TV ASTE - 136 | 2. korrus | _VIIMISTLUSKIHT - viimistlus vastavalt SA osale
2 x TV ASTE - 137 | 2. korrus | _VIIMISTLUSKIHT - viimistlus vastavalt SA osale
2 x TV ASTE - 138 | 2. korrus | _VIIMISTLUSKIHT - viimistlus vastavalt SA osale
TV ASTE - 111 | 2. korrus | _VIIMISTLUSKIHT - viimistlus vastavalt SA osale
TV ASTE - 112 | 2. korrus | _VIIMISTLUSKIHT - viimistlus vastavalt SA osale
TV ASTE - 113 | 2. korrus | _VIIMISTLUSKIHT - viimistlus vastavalt SA osale
SL TREAD - 012 | 2. korrus | _VIIMISTLUSKIHT - viimistlus vastavalt SA osale
TV ASTE - 114 | 2. korrus | _VIIMISTLUSKIHT - viimistlus vastavalt SA osale
TV ASTE - 115 | 2. korrus | _VIIMISTLUSKIHT - viimistlus vastavalt SA osale
TV ASTE - 116 | 2. korrus | _VIIMISTLUSKIHT - viimistlus vastavalt SA osale
SL TREAD - 013 | 2. korrus | _VIIMISTLUSKIHT - viimistlus vastavalt SA osale
SL TREAD - 014 | 2. korrus | _VIIMISTLUSKIHT - viimistlus vastavalt SA osale
TV ASTE - 163 | 2. korrus | _VIIMISTLUSKIHT - viimistlus vastavalt SA osale
TV ASTE - 164 | 2. korrus | _VIIMISTLUSKIHT - viimistlus vastavalt SA osale
TV ASTE - 165 | 2. korrus | _VIIMISTLUSKIHT - viimistlus vastavalt SA osale
TV ASTE - 166 | 2. korrus | _VIIMISTLUSKIHT - viimistlus vastavalt SA osale
TV ASTE - 167 | 2. korrus | _VIIMISTLUSKIHT - viimistlus vastavalt SA osale
TV ASTE - 168 | 2. korrus | _VIIMISTLUSKIHT - viimistlus vastavalt SA osale
TV ASTE - 169 | 2. korrus | _VIIMISTLUSKIHT - viimistlus vastavalt SA osale
TV ASTE - 170 | 2. korrus | _VIIMISTLUSKIHT - viimistlus vastavalt SA osale
TV ASTE - 171 | 2. korrus | _VIIMISTLUSKIHT - viimistlus vastavalt SA osale
TV ASTE - 172 | 2. korrus | _VIIMISTLUSKIHT - viimistlus vastavalt SA osale
TV ASTE - 173 | 2. korrus | _VIIMISTLUSKIHT - viimistlus vastavalt SA osale
TV ASTE - 174 | 2. korrus | _VIIMISTLUSKIHT - viimistlus vastavalt SA osale
TV ASTE - 175 | 2. korrus | _VIIMISTLUSKIHT - viimistlus vastavalt SA osale
TV ASTE - 176 | 2. korrus | _VIIMISTLUSKIHT - viimistlus vastavalt SA osale
TV ASTE - 177 | 2. korrus | _VIIMISTLUSKIHT - viimistlus vastavalt SA osale
TV ASTE - 178 | 2. korrus | _VIIMISTLUSKIHT - viimistlus vastavalt SA osale
TV ASTE - 179 | 2. korrus | _VIIMISTLUSKIHT - viimistlus vastavalt SA osale
TV ASTE - 180 | 2. korrus | _VIIMISTLUSKIHT - viimistlus vastavalt SA osale
TV ASTE - 181 | 2. korrus | _VIIMISTLUSKIHT - viimistlus vastavalt SA osale
TV ASTE - 182 | 2. korrus | _VIIMISTLUSKIHT - viimistlus vastavalt SA osale
TV ASTE - 183 | 2. korrus | _VIIMISTLUSKIHT - viimistlus vastavalt SA osale
TV ASTE - 184 | 2. korrus | _VIIMISTLUSKIHT - viimistlus vastavalt SA osale
TV ASTE - 185 | 2. korrus | _VIIMISTLUSKIHT - viimistlus vastavalt SA osale
TV ASTE - 186 | 2. korrus | _VIIMISTLUSKIHT - viimistlus vastavalt SA osale
TV ASTE - 201 | 2. korrus | _VIIMISTLUSKIHT - viimistlus vastavalt SA osale
TV ASTE - 202 | 2. korrus | _VIIMISTLUSKIHT - viimistlus vastavalt SA osale
TV ASTE - 203 | 2. korrus | _VIIMISTLUSKIHT - viimistlus vastavalt SA osale
TV ASTE - 204 | 2. korrus | _VIIMISTLUSKIHT - viimistlus vastavalt SA osale
TV ASTE - 205 | 2. korrus | _VIIMISTLUSKIHT - viimistlus vastavalt SA osale
TV ASTE - 206 | 2. korrus | _VIIMISTLUSKIHT - viimistlus vastavalt SA osale
TV ASTE - 207 | 2. korrus | _VIIMISTLUSKIHT - viimistlus vastavalt SA osale
TV ASTE - 208 | 2. korrus | _VIIMISTLUSKIHT - viimistlus vastavalt SA osale
3 x TV ASTE - 163 | 3. korrus | _VIIMISTLUSKIHT - viimistlus vastavalt SA osale
3 x TV ASTE - 164 | 3. korrus | _VIIMISTLUSKIHT - viimistlus vastavalt SA osale
3 x TV ASTE - 165 | 3. korrus | _VIIMISTLUSKIHT - viimistlus vastavalt SA osale
3 x TV ASTE - 166 | 3. korrus | _VIIMISTLUSKIHT - viimistlus vastavalt SA osale
3 x TV ASTE - 167 | 3. korrus | _VIIMISTLUSKIHT - viimistlus vastavalt SA osale
3 x TV ASTE - 168 | 3. korrus | _VIIMISTLUSKIHT - viimistlus vastavalt SA osale
3 x TV ASTE - 169 | 3. korrus | _VIIMISTLUSKIHT - viimistlus vastavalt SA osale
3 x TV ASTE - 170 | 3. korrus | _VIIMISTLUSKIHT - viimistlus vastavalt SA osale
3 x TV ASTE - 171 | 3. korrus | _VIIMISTLUSKIHT - viimistlus vastavalt SA osale
3 x TV ASTE - 172 | 3. korrus | _VIIMISTLUSKIHT - viimistlus vastavalt SA osale
3 x TV ASTE - 173 | 3. korrus | _VIIMISTLUSKIHT - viimistlus vastavalt SA osale
3 x TV ASTE - 174 | 3. korrus | _VIIMISTLUSKIHT - viimistlus vastavalt SA osale
3 x TV ASTE - 175 | 3. korrus | _VIIMISTLUSKIHT - viimistlus vastavalt SA osale
3 x TV ASTE - 176 | 3. korrus | _VIIMISTLUSKIHT - viimistlus vastavalt SA osale
3 x TV ASTE - 177 | 3. korrus | _VIIMISTLUSKIHT - viimistlus vastavalt SA osale
3 x TV ASTE - 178 | 3. korrus | _VIIMISTLUSKIHT - viimistlus vastavalt SA osale
3 x TV ASTE - 179 | 3. korrus | _VIIMISTLUSKIHT - viimistlus vastavalt SA osale
3 x TV ASTE - 180 | 3. korrus | _VIIMISTLUSKIHT - viimistlus vastavalt SA osale
3 x TV ASTE - 181 | 3. korrus | _VIIMISTLUSKIHT - viimistlus vastavalt SA osale
3 x TV ASTE - 182 | 3. korrus | _VIIMISTLUSKIHT - viimistlus vastavalt SA osale
3 x TV ASTE - 183 | 3. korrus | _VIIMISTLUSKIHT - viimistlus vastavalt SA osale
3 x TV ASTE - 184 | 3. korrus | _VIIMISTLUSKIHT - viimistlus vastavalt SA osale
3 x TV ASTE - 185 | 3. korrus | _VIIMISTLUSKIHT - viimistlus vastavalt SA osale
3 x TV ASTE - 186 | 3. korrus | _VIIMISTLUSKIHT - viimistlus vastavalt SA osale
2 x TV ASTE - 201 | 3. korrus | _VIIMISTLUSKIHT - viimistlus vastavalt SA osale
2 x TV ASTE - 202 | 3. korrus | _VIIMISTLUSKIHT - viimistlus vastavalt SA osale
2 x TV ASTE - 203 | 3. korrus | _VIIMISTLUSKIHT - viimistlus vastavalt SA osale
2 x TV ASTE - 204 | 3. korrus | _VIIMISTLUSKIHT - viimistlus vastavalt SA osale
2 x TV ASTE - 205 | 3. korrus | _VIIMISTLUSKIHT - viimistlus vastavalt SA osale
2 x TV ASTE - 206 | 3. korrus | _VIIMISTLUSKIHT - viimistlus vastavalt SA osale
2 x TV ASTE - 207 | 3. korrus | _VIIMISTLUSKIHT - viimistlus vastavalt SA osale
2 x TV ASTE - 208 | 3. korrus | _VIIMISTLUSKIHT - viimistlus vastavalt SA osale
4 x aste | 4. TEHNO korrus | _METALL - kuumtsingitud teras
TV ASTE - 179 | 4. TEHNO korrus | _METALL - kuumtsingitud teras
TV ASTE - 180 | 4. TEHNO korrus | _METALL - kuumtsingitud teras
TV ASTE - 185 | 4. TEHNO korrus | _METALL - kuumtsingitud teras

# IfcMember: IfcMember (4)
In: 4. TEHNO korrus
Type - PredefinedType: POST
Classification: Railing Post (RKAS BIM + ARCHICAD Classification); Material: _METALL - kuumtsingitud teras
AC_Pset_RenovationAndPhasing - Renovation Status: New

# IfcMember: Mullion Frame 20 x 70 (59)
Type - PredefinedType: MEMBER
Classification: 1.13 IfcMemberType (kandev element) (RKAS BIM + ARCHICAD Classification)
Pset_MemberCommon - Reference: Built-in Frame; Slope: 90 deg
AR_001-002 - 002_Tüüp: Built-in Frame
AC_Pset_RenovationAndPhasing - Renovation Status: Undefined
Name | In | Material | 001_Nimetus
RF RAAM VERT-332 | 1. korrus | _GENEERILINE MATERJAL | RF RAAM VERT-332
RF RAAM VERT-333 | 1. korrus | _GENEERILINE MATERJAL | RF RAAM VERT-333
RF RAAM VERT-346 | 1. korrus | _GENEERILINE MATERJAL | RF RAAM VERT-346
RF RAAM VERT-389 | 1. korrus | _GENEERILINE MATERJAL | RF RAAM VERT-389
RF RAAM VERT-390 | 1. korrus | _GENEERILINE MATERJAL | RF RAAM VERT-390
RF RAAM VERT-391 | 1. korrus | _GENEERILINE MATERJAL | RF RAAM VERT-391
RF RAAM VERT-340 | 1. korrus | _GENEERILINE MATERJAL | RF RAAM VERT-340
RF RAAM VERT-345 | 1. korrus | _GENEERILINE MATERJAL | RF RAAM VERT-345
RF RAAM VERT-350 | 1. korrus | _GENEERILINE MATERJAL | RF RAAM VERT-350
RF RAAM VERT-351 | 1. korrus | _GENEERILINE MATERJAL | RF RAAM VERT-351
RF RAAM VERT-356 | 1. korrus | _METALL - alumiinium | RF RAAM VERT-356
2 x RF RAAM VERT-401 | 1. korrus | _METALL - alumiinium | RF RAAM VERT-401
RF RAAM VERT-395 | 1. korrus | _METALL - alumiinium | RF RAAM VERT-395
RF RAAM VERT-396 | 1. korrus | _METALL - alumiinium | RF RAAM VERT-396
RF RAAM VERT-456 | 1. korrus | _METALL - alumiinium | RF RAAM VERT-456
RF RAAM VERT-455 | 1. korrus | _METALL - alumiinium | RF RAAM VERT-455
RF RAAM VERT-421 | 1. korrus | _METALL - alumiinium | RF RAAM VERT-421
2 x RF RAAM VERT-302 | 2. korrus | _GENEERILINE MATERJAL | RF RAAM VERT-302
RF RAAM VERT-317 | 2. korrus | _GENEERILINE MATERJAL | RF RAAM VERT-317
RF RAAM VERT-321 | 2. korrus | _GENEERILINE MATERJAL | RF RAAM VERT-321
RF RAAM VERT-322 | 2. korrus | _GENEERILINE MATERJAL | RF RAAM VERT-322
RF RAAM VERT-323 | 2. korrus | _GENEERILINE MATERJAL | RF RAAM VERT-323
RF RAAM VERT-340 | 2. korrus | _GENEERILINE MATERJAL | RF RAAM VERT-340
RF RAAM VERT-341 | 2. korrus | _GENEERILINE MATERJAL | RF RAAM VERT-341
RF RAAM VERT-306 | 2. korrus | _KANDETARIND - puitkarkass | RF RAAM VERT-306
RF RAAM VERT-307 | 2. korrus | _KANDETARIND - puitkarkass | RF RAAM VERT-307
RF RAAM VERT-308 | 2. korrus | _KANDETARIND - puitkarkass | RF RAAM VERT-308
RF RAAM VERT-309 | 2. korrus | _KANDETARIND - puitkarkass | RF RAAM VERT-309
RF RAAM VERT-310 | 2. korrus | _KANDETARIND - puitkarkass | RF RAAM VERT-310
RF RAAM VERT-350 | 2. korrus | _GENEERILINE MATERJAL | RF RAAM VERT-350
RF RAAM VERT-351 | 2. korrus | _GENEERILINE MATERJAL | RF RAAM VERT-351
RF RAAM VERT-358 | 2. korrus | _GENEERILINE MATERJAL | RF RAAM VERT-358
RF RAAM VERT-366 | 2. korrus | _GENEERILINE MATERJAL | RF RAAM VERT-366
RF RAAM VERT-367 | 2. korrus | _GENEERILINE MATERJAL | RF RAAM VERT-367
RF RAAM VERT-464 | 2. korrus | _GENEERILINE MATERJAL | RF RAAM VERT-464
RF RAAM VERT-465 | 2. korrus | _GENEERILINE MATERJAL | RF RAAM VERT-465
RF RAAM VERT-392 | 2. korrus | _GENEERILINE MATERJAL | RF RAAM VERT-392
RF RAAM VERT-397 | 2. korrus | _GENEERILINE MATERJAL | RF RAAM VERT-397
RF RAAM VERT-398 | 2. korrus | _GENEERILINE MATERJAL | RF RAAM VERT-398
RF RAAM VERT-399 | 2. korrus | _GENEERILINE MATERJAL | RF RAAM VERT-399
RF RAAM VERT-304 | 3. korrus | _GENEERILINE MATERJAL | RF RAAM VERT-304
3 x RF RAAM VERT-302 | 3. korrus | _GENEERILINE MATERJAL | RF RAAM VERT-302
RF RAAM VERT-303 | 3. korrus | _GENEERILINE MATERJAL | RF RAAM VERT-303
RF RAAM VERT-366 | 3. korrus | _GENEERILINE MATERJAL | RF RAAM VERT-366
2 x RF RAAM VERT-367 | 3. korrus | _GENEERILINE MATERJAL | RF RAAM VERT-367
RF RAAM VERT-368 | 3. korrus | _GENEERILINE MATERJAL | RF RAAM VERT-368
RF RAAM VERT-452 | 3. korrus | _GENEERILINE MATERJAL | RF RAAM VERT-452
RF RAAM VERT-379 | 3. korrus | _GENEERILINE MATERJAL | RF RAAM VERT-379
RF RAAM VERT-380 | 3. korrus | _GENEERILINE MATERJAL | RF RAAM VERT-380
RF RAAM VERT-385 | 3. korrus | _GENEERILINE MATERJAL | RF RAAM VERT-385
RF RAAM VERT-317 | 3. korrus | _GENEERILINE MATERJAL | RF RAAM VERT-317
RF RAAM VERT-321 | 3. korrus | _GENEERILINE MATERJAL | RF RAAM VERT-321
RF RAAM VERT-322 | 3. korrus | _GENEERILINE MATERJAL | RF RAAM VERT-322
RF RAAM VERT-323 | 3. korrus | _GENEERILINE MATERJAL | RF RAAM VERT-323

# IfcMember: Mullion Frame 50 x 100 (334)
In: 1. korrus
Type - PredefinedType: MEMBER
Classification: 1.13 IfcMemberType (kandev element) (RKAS BIM + ARCHICAD Classification); Material: _METALL - alumiinium
Pset_MemberCommon - Reference: Built-in Frame; Slope: 90 deg
AR_001-002 - 002_Tüüp: Built-in Frame
AC_Pset_RenovationAndPhasing - Renovation Status: Undefined
Name | 001_Nimetus
2 x RF RAAM VERT-053 | RF RAAM VERT-053
RF RAAM VERT-054 | RF RAAM VERT-054
RF RAAM VERT-055 | RF RAAM VERT-055
RF RAAM VERT-056 | RF RAAM VERT-056
RF RAAM VERT-057 | RF RAAM VERT-057
RF RAAM VERT-059 | RF RAAM VERT-059
RF RAAM VERT-060 | RF RAAM VERT-060
RF RAAM VERT-061 | RF RAAM VERT-061
RF RAAM VERT-062 | RF RAAM VERT-062
RF RAAM VERT-063 | RF RAAM VERT-063
RF RAAM VERT-065 | RF RAAM VERT-065
RF RAAM VERT-066 | RF RAAM VERT-066
RF RAAM VERT-067 | RF RAAM VERT-067
RF RAAM VERT-068 | RF RAAM VERT-068
RF RAAM VERT-069 | RF RAAM VERT-069
RF RAAM VERT-071 | RF RAAM VERT-071
RF RAAM VERT-072 | RF RAAM VERT-072
RF RAAM VERT-073 | RF RAAM VERT-073
2 x RF RAAM VERT-074 | RF RAAM VERT-074
2 x RF RAAM VERT-075 | RF RAAM VERT-075
2 x RF RAAM VERT-077 | RF RAAM VERT-077
2 x RF RAAM VERT-078 | RF RAAM VERT-078
2 x RF RAAM VERT-079 | RF RAAM VERT-079
2 x RF RAAM VERT-080 | RF RAAM VERT-080
2 x RF RAAM VERT-081 | RF RAAM VERT-081
2 x RF RAAM VERT-083 | RF RAAM VERT-083
2 x RF RAAM VERT-084 | RF RAAM VERT-084
2 x RF RAAM VERT-085 | RF RAAM VERT-085
2 x RF RAAM VERT-086 | RF RAAM VERT-086
2 x RF RAAM VERT-087 | RF RAAM VERT-087
2 x RF RAAM VERT-089 | RF RAAM VERT-089
RF RAAM VERT-090 | RF RAAM VERT-090
RF RAAM VERT-091 | RF RAAM VERT-091
RF RAAM VERT-092 | RF RAAM VERT-092
RF RAAM VERT-093 | RF RAAM VERT-093
RF RAAM VERT-095 | RF RAAM VERT-095
RF RAAM VERT-096 | RF RAAM VERT-096
RF RAAM VERT-097 | RF RAAM VERT-097
RF RAAM VERT-098 | RF RAAM VERT-098
RF RAAM VERT-099 | RF RAAM VERT-099
RF RAAM VERT-101 | RF RAAM VERT-101
RF RAAM VERT-102 | RF RAAM VERT-102
RF RAAM VERT-103 | RF RAAM VERT-103
RF RAAM VERT-104 | RF RAAM VERT-104
RF RAAM VERT-105 | RF RAAM VERT-105
RF RAAM VERT-107 | RF RAAM VERT-107
RF RAAM VERT-108 | RF RAAM VERT-108
2 x RF RAAM VERT-109 | RF RAAM VERT-109
2 x RF RAAM VERT-110 | RF RAAM VERT-110
2 x RF RAAM VERT-111 | RF RAAM VERT-111
2 x RF RAAM VERT-113 | RF RAAM VERT-113
2 x RF RAAM VERT-114 | RF RAAM VERT-114
2 x RF RAAM VERT-115 | RF RAAM VERT-115
2 x RF RAAM VERT-116 | RF RAAM VERT-116
2 x RF RAAM VERT-117 | RF RAAM VERT-117
RF RAAM VERT-119 | RF RAAM VERT-119
RF RAAM VERT-120 | RF RAAM VERT-120
RF RAAM VERT-121 | RF RAAM VERT-121
RF RAAM VERT-122 | RF RAAM VERT-122
RF RAAM VERT-123 | RF RAAM VERT-123
RF RAAM VERT-125 | RF RAAM VERT-125
RF RAAM VERT-126 | RF RAAM VERT-126
RF RAAM VERT-127 | RF RAAM VERT-127
RF RAAM VERT-128 | RF RAAM VERT-128
RF RAAM VERT-129 | RF RAAM VERT-129
RF RAAM VERT-131 | RF RAAM VERT-131
RF RAAM VERT-132 | RF RAAM VERT-132
RF RAAM VERT-133 | RF RAAM VERT-133
RF RAAM VERT-134 | RF RAAM VERT-134
RF RAAM VERT-135 | RF RAAM VERT-135
RF RAAM VERT-137 | RF RAAM VERT-137
RF RAAM VERT-138 | RF RAAM VERT-138
RF RAAM VERT-139 | RF RAAM VERT-139
RF RAAM VERT-140 | RF RAAM VERT-140
RF RAAM VERT-141 | RF RAAM VERT-141
RF RAAM VERT-143 | RF RAAM VERT-143
RF RAAM VERT-144 | RF RAAM VERT-144
RF RAAM VERT-145 | RF RAAM VERT-145
RF RAAM VERT-146 | RF RAAM VERT-146
RF RAAM VERT-147 | RF RAAM VERT-147
RF RAAM VERT-624 | RF RAAM VERT-624
RF RAAM VERT-625 | RF RAAM VERT-625
RF RAAM VERT-626 | RF RAAM VERT-626
RF RAAM VERT-629 | RF RAAM VERT-629
RF RAAM VERT-630 | RF RAAM VERT-630
RF RAAM VERT-631 | RF RAAM VERT-631
RF RAAM VERT-632 | RF RAAM VERT-632
RF RAAM VERT-633 | RF RAAM VERT-633
RF RAAM VERT-634 | RF RAAM VERT-634
RF RAAM VERT-635 | RF RAAM VERT-635
RF RAAM VERT-636 | RF RAAM VERT-636
RF RAAM VERT-637 | RF RAAM VERT-637
RF RAAM VERT-638 | RF RAAM VERT-638
RF RAAM VERT-639 | RF RAAM VERT-639
RF RAAM VERT-640 | RF RAAM VERT-640
RF RAAM VERT-641 | RF RAAM VERT-641
RF RAAM VERT-642 | RF RAAM VERT-642
RF RAAM VERT-643 | RF RAAM VERT-643
RF RAAM VERT-644 | RF RAAM VERT-644
RF RAAM VERT-645 | RF RAAM VERT-645
RF RAAM VERT-646 | RF RAAM VERT-646
RF RAAM VERT-647 | RF RAAM VERT-647
RF RAAM VERT-648 | RF RAAM VERT-648
RF RAAM VERT-649 | RF RAAM VERT-649
RF RAAM VERT-650 | RF RAAM VERT-650
RF RAAM VERT-651 | RF RAAM VERT-651
RF RAAM VERT-652 | RF RAAM VERT-652
RF RAAM VERT-653 | RF RAAM VERT-653
RF RAAM VERT-654 | RF RAAM VERT-654
RF RAAM VERT-655 | RF RAAM VERT-655
RF RAAM VERT-656 | RF RAAM VERT-656
RF RAAM VERT-657 | RF RAAM VERT-657
RF RAAM VERT-658 | RF RAAM VERT-658
RF RAAM VERT-659 | RF RAAM VERT-659
RF RAAM VERT-660 | RF RAAM VERT-660
RF RAAM VERT-661 | RF RAAM VERT-661
RF RAAM VERT-662 | RF RAAM VERT-662
RF RAAM VERT-663 | RF RAAM VERT-663
RF RAAM VERT-664 | RF RAAM VERT-664
RF RAAM VERT-665 | RF RAAM VERT-665
RF RAAM VERT-666 | RF RAAM VERT-666
RF RAAM VERT-667 | RF RAAM VERT-667
RF RAAM VERT-668 | RF RAAM VERT-668
RF RAAM VERT-867 | RF RAAM VERT-867
RF RAAM VERT-868 | RF RAAM VERT-868
RF RAAM VERT-869 | RF RAAM VERT-869
RF RAAM VERT-870 | RF RAAM VERT-870
RF RAAM VERT-871 | RF RAAM VERT-871
RF RAAM VERT-872 | RF RAAM VERT-872
RF RAAM VERT-873 | RF RAAM VERT-873
RF RAAM VERT-874 | RF RAAM VERT-874
RF RAAM VERT-875 | RF RAAM VERT-875
RF RAAM VERT-876 | RF RAAM VERT-876
RF RAAM VERT-878 | RF RAAM VERT-878
RF RAAM VERT-879 | RF RAAM VERT-879
RF RAAM VERT-880 | RF RAAM VERT-880
RF RAAM VERT-881 | RF RAAM VERT-881
RF RAAM VERT-942 | RF RAAM VERT-942
RF RAAM VERT-943 | RF RAAM VERT-943
RF RAAM VERT-945 | RF RAAM VERT-945
RF RAAM VERT-946 | RF RAAM VERT-946
RF RAAM VERT-947 | RF RAAM VERT-947
RF RAAM VERT-948 | RF RAAM VERT-948
RF RAAM VERT-950 | RF RAAM VERT-950
RF RAAM VERT-951 | RF RAAM VERT-951
RF RAAM VERT-952 | RF RAAM VERT-952
RF RAAM VERT-954 | RF RAAM VERT-954
RF RAAM VERT-955 | RF RAAM VERT-955
RF RAAM VERT-956 | RF RAAM VERT-956
RF RAAM VERT-957 | RF RAAM VERT-957
RF RAAM VERT-959 | RF RAAM VERT-959
RF RAAM VERT-965 | RF RAAM VERT-965
RF RAAM VERT-966 | RF RAAM VERT-966
RF RAAM VERT-967 | RF RAAM VERT-967
RF RAAM VERT-969 | RF RAAM VERT-969
RF RAAM VERT-970 | RF RAAM VERT-970
RF RAAM VERT-971 | RF RAAM VERT-971
RF RAAM VERT-972 | RF RAAM VERT-972
RF RAAM VERT-974 | RF RAAM VERT-974
RF RAAM VERT-975 | RF RAAM VERT-975
RF RAAM VERT-976 | RF RAAM VERT-976
RF RAAM VERT-977 | RF RAAM VERT-977
RF RAAM VERT-979 | RF RAAM VERT-979
RF RAAM VERT-980 | RF RAAM VERT-980
RF RAAM VERT-981 | RF RAAM VERT-981
RF RAAM VERT-982 | RF RAAM VERT-982
RF RAAM VERT-984 | RF RAAM VERT-984
RF RAAM VERT-985 | RF RAAM VERT-985
RF RAAM VERT-986 | RF RAAM VERT-986
RF RAAM VERT-987 | RF RAAM VERT-987
RF RAAM VERT-989 | RF RAAM VERT-989
RF RAAM VERT-990 | RF RAAM VERT-990
RF RAAM VERT-991 | RF RAAM VERT-991
RF RAAM VERT-992 | RF RAAM VERT-992
RF RAAM VERT-994 | RF RAAM VERT-994
RF RAAM VERT-995 | RF RAAM VERT-995
RF RAAM VERT-996 | RF RAAM VERT-996
RF RAAM VERT-997 | RF RAAM VERT-997
RF RAAM VERT-998 | RF RAAM VERT-998
RF RAAM VERT-999 | RF RAAM VERT-999
RF RAAM VERT-000 | RF RAAM VERT-000
RF RAAM VERT-001 | RF RAAM VERT-001
RF RAAM VERT-002 | RF RAAM VERT-002
RF RAAM VERT-003 | RF RAAM VERT-003
RF RAAM VERT-004 | RF RAAM VERT-004
RF RAAM VERT-005 | RF RAAM VERT-005
2 x RF RAAM VERT-010 | RF RAAM VERT-010
2 x RF RAAM VERT-011 | RF RAAM VERT-011
RF RAAM VERT-012 | RF RAAM VERT-012
RF RAAM VERT-025 | RF RAAM VERT-025
RF RAAM VERT-026 | RF RAAM VERT-026
RF RAAM VERT-027 | RF RAAM VERT-027
RF RAAM VERT-028 | RF RAAM VERT-028
RF RAAM VERT-043 | RF RAAM VERT-043
RF RAAM VERT-044 | RF RAAM VERT-044
RF RAAM VERT-045 | RF RAAM VERT-045
RF RAAM VERT-046 | RF RAAM VERT-046
RF RAAM VERT-047 | RF RAAM VERT-047
RF RAAM VERT-048 | RF RAAM VERT-048
RF RAAM VERT-050 | RF RAAM VERT-050
RF RAAM VERT-051 | RF RAAM VERT-051
RF RAAM VERT-052 | RF RAAM VERT-052
RF RAAM VERT-076 | RF RAAM VERT-076
RF RAAM VERT-082 | RF RAAM VERT-082
RF RAAM VERT-088 | RF RAAM VERT-088
RF RAAM VERT-112 | RF RAAM VERT-112
RF RAAM VERT-524 | RF RAAM VERT-524
RF RAAM VERT-525 | RF RAAM VERT-525
RF RAAM VERT-526 | RF RAAM VERT-526
RF RAAM VERT-527 | RF RAAM VERT-527
RF RAAM VERT-528 | RF RAAM VERT-528
RF RAAM VERT-529 | RF RAAM VERT-529
RF RAAM VERT-345 | RF RAAM VERT-345
RF RAAM VERT-346 | RF RAAM VERT-346
RF RAAM VERT-347 | RF RAAM VERT-347
RF RAAM VERT-348 | RF RAAM VERT-348
RF RAAM VERT-350 | RF RAAM VERT-350
RF RAAM VERT-351 | RF RAAM VERT-351
RF RAAM VERT-353 | RF RAAM VERT-353
RF RAAM VERT-354 | RF RAAM VERT-354
RF RAAM VERT-355 | RF RAAM VERT-355
RF RAAM VERT-356 | RF RAAM VERT-356
RF RAAM VERT-358 | RF RAAM VERT-358
RF RAAM VERT-359 | RF RAAM VERT-359
5 x RF RAAM VERT-470 | RF RAAM VERT-470
RF RAAM VERT-471 | RF RAAM VERT-471
RF RAAM VERT-472 | RF RAAM VERT-472
RF RAAM VERT-473 | RF RAAM VERT-473
RF RAAM VERT-474 | RF RAAM VERT-474
RF RAAM VERT-475 | RF RAAM VERT-475
RF RAAM VERT-476 | RF RAAM VERT-476
53 x RF RAAM VERT-904 | RF RAAM VERT-904
RF RAAM VERT-242 | RF RAAM VERT-242
RF RAAM VERT-223 | RF RAAM VERT-223
RF RAAM VERT-224 | RF RAAM VERT-224
RF RAAM VERT-225 | RF RAAM VERT-225
RF RAAM VERT-226 | RF RAAM VERT-226
RF RAAM VERT-227 | RF RAAM VERT-227
RF RAAM VERT-228 | RF RAAM VERT-228
RF RAAM VERT-229 | RF RAAM VERT-229
RF RAAM VERT-230 | RF RAAM VERT-230
RF RAAM VERT-231 | RF RAAM VERT-231
RF RAAM VERT-232 | RF RAAM VERT-232
RF RAAM VERT-233 | RF RAAM VERT-233
RF RAAM VERT-234 | RF RAAM VERT-234
RF RAAM VERT-235 | RF RAAM VERT-235
RF RAAM VERT-236 | RF RAAM VERT-236
RF RAAM VERT-237 | RF RAAM VERT-237
RF RAAM VERT-238 | RF RAAM VERT-238
RF RAAM VERT-239 | RF RAAM VERT-239
RF RAAM VERT-240 | RF RAAM VERT-240
RF RAAM VERT-241 | RF RAAM VERT-241
RF RAAM VERT-488 | RF RAAM VERT-488
RF RAAM VERT-489 | RF RAAM VERT-489

# IfcMember: Mullion Frame 50 x 110 (6)
In: 1. korrus
Type - PredefinedType: MEMBER
Classification: 1.13 IfcMemberType (kandev element) (RKAS BIM + ARCHICAD Classification); Material: _GENEERILINE MATERJAL
Pset_MemberCommon - Reference: Built-in Frame; Slope: 90 deg
AR_001-002 - 002_Tüüp: Built-in Frame
AC_Pset_RenovationAndPhasing - Renovation Status: Undefined
Name | 001_Nimetus
RF RAAM VERT-288 | RF RAAM VERT-288
RF RAAM VERT-289 | RF RAAM VERT-289
RF RAAM VERT-290 | RF RAAM VERT-290
RF RAAM VERT-292 | RF RAAM VERT-292
RF RAAM VERT-293 | RF RAAM VERT-293
RF RAAM VERT-294 | RF RAAM VERT-294

# IfcMember: Mullion Frame 50 x 125 (8)
In: 1. korrus
Type - PredefinedType: MEMBER
Classification: 1.13 IfcMemberType (kandev element) (RKAS BIM + ARCHICAD Classification); Material: _METALL - alumiinium
Pset_MemberCommon - Reference: Modular Frame 25; Slope: 90 deg
AR_001-002 - 002_Tüüp: Modular Frame 25
AC_Pset_RenovationAndPhasing - Renovation Status: Undefined
Name | 001_Nimetus
RF RAAM VERT-294 | RF RAAM VERT-294
RF RAAM VERT-295 | RF RAAM VERT-295
RF RAAM VERT-340 | RF RAAM VERT-340
RF RAAM VERT-335 | RF RAAM VERT-335
RF RAAM VERT-336 | RF RAAM VERT-336
RF RAAM VERT-337 | RF RAAM VERT-337
RF RAAM VERT-354 | RF RAAM VERT-354
RF RAAM VERT-370 | RF RAAM VERT-370

# IfcMember: Mullion Frame 50 x 200 (76)
Type - PredefinedType: MEMBER
Classification: 1.13 IfcMemberType (kandev element) (RKAS BIM + ARCHICAD Classification); Material: _METALL - alumiinium
Pset_MemberCommon - Reference: Frame 25
AR_001-002 - 002_Tüüp: Frame 25
AC_Pset_RenovationAndPhasing - Renovation Status: Undefined
Name | In | Slope (deg) | 001_Nimetus
RF RAAM VERT-460 | 3. korrus | 2.19933e-08 | RF RAAM VERT-460
RF RAAM VERT-458 | 3. korrus | 46.319 | RF RAAM VERT-458
RF RAAM VERT-461 | 3. korrus | 23.9435 | RF RAAM VERT-461
RF RAAM VERT-462 | 3. korrus | 1.65952 | RF RAAM VERT-462
RF RAAM VERT-463 | 3. korrus | 9.24688 | RF RAAM VERT-463
RF RAAM VERT-464 | 3. korrus | 7 | RF RAAM VERT-464
RF RAAM VERT-655 | 4. TEHNO korrus | 7 | RF RAAM VERT-655
RF RAAM VERT-659 | 4. TEHNO korrus | 7 | RF RAAM VERT-659
RF RAAM VERT-651 | 4. TEHNO korrus | 7 | RF RAAM VERT-651
RF RAAM VERT-652 | 4. TEHNO korrus | 7 | RF RAAM VERT-652
RF RAAM VERT-662 | 4. TEHNO korrus | 7 | RF RAAM VERT-662
RF RAAM VERT-663 | 4. TEHNO korrus | 7 | RF RAAM VERT-663
RF RAAM VERT-644 | 4. TEHNO korrus | 7 | RF RAAM VERT-644
2 x RF RAAM VERT-645 | 4. TEHNO korrus | 7 | RF RAAM VERT-645
RF RAAM VERT-646 | 4. TEHNO korrus | 7 | RF RAAM VERT-646
RF RAAM VERT-647 | 4. TEHNO korrus | 7 | RF RAAM VERT-647
RF RAAM VERT-648 | 4. TEHNO korrus | 7 | RF RAAM VERT-648
RF RAAM VERT-649 | 4. TEHNO korrus | 7 | RF RAAM VERT-649
RF RAAM VERT-650 | 4. TEHNO korrus | 7 | RF RAAM VERT-650
RF RAAM VERT-664 | 4. TEHNO korrus | 7 | RF RAAM VERT-664
RF RAAM VERT-665 | 4. TEHNO korrus | 7 | RF RAAM VERT-665
RF RAAM VERT-666 | 4. TEHNO korrus | 7 | RF RAAM VERT-666
RF RAAM VERT-667 | 4. TEHNO korrus | 7 | RF RAAM VERT-667
RF RAAM VERT-833 | 4. TEHNO korrus | 7 | RF RAAM VERT-833
RF RAAM VERT-834 | 4. TEHNO korrus | 7 | RF RAAM VERT-834
RF RAAM VERT-835 | 4. TEHNO korrus | 7 | RF RAAM VERT-835
RF RAAM VERT-838 | 4. TEHNO korrus | 7 | RF RAAM VERT-838
RF RAAM VERT-839 | 4. TEHNO korrus | 7 | RF RAAM VERT-839
RF RAAM VERT-841 | 4. TEHNO korrus | 7 | RF RAAM VERT-841
RF RAAM VERT-842 | 4. TEHNO korrus | 7 | RF RAAM VERT-842
RF RAAM VERT-850 | 4. TEHNO korrus | 7 | RF RAAM VERT-850
RF RAAM VERT-851 | 4. TEHNO korrus | 7 | RF RAAM VERT-851
RF RAAM VERT-853 | 4. TEHNO korrus | 7 | RF RAAM VERT-853
RF RAAM VERT-854 | 4. TEHNO korrus | 7 | RF RAAM VERT-854
RF RAAM VERT-855 | 4. TEHNO korrus | 7 | RF RAAM VERT-855
RF RAAM VERT-856 | 4. TEHNO korrus | 7 | RF RAAM VERT-856
RF RAAM VERT-857 | 4. TEHNO korrus | 7 | RF RAAM VERT-857
RF RAAM VERT-858 | 4. TEHNO korrus | 7 | RF RAAM VERT-858
RF RAAM VERT-860 | 4. TEHNO korrus | 7 | RF RAAM VERT-860
RF RAAM VERT-863 | 4. TEHNO korrus | 7 | RF RAAM VERT-863
RF RAAM VERT-869 | 4. TEHNO korrus | 7 | RF RAAM VERT-869
RF RAAM VERT-870 | 4. TEHNO korrus | 7 | RF RAAM VERT-870
RF RAAM VERT-031 | 4. TEHNO korrus | 7 | RF RAAM VERT-031
RF RAAM VERT-102 | 4. TEHNO korrus | 7 | RF RAAM VERT-102
RF RAAM VERT-030 | 4. TEHNO korrus | 7 | RF RAAM VERT-030
RF RAAM VERT-098 | 4. TEHNO korrus | 7 | RF RAAM VERT-098
RF RAAM VERT-099 | 4. TEHNO korrus | 7 | RF RAAM VERT-099
RF RAAM VERT-100 | 4. TEHNO korrus | 7 | RF RAAM VERT-100
RF RAAM VERT-104 | 4. TEHNO korrus | 7 | RF RAAM VERT-104
RF RAAM VERT-105 | 4. TEHNO korrus | 7 | RF RAAM VERT-105
RF RAAM VERT-106 | 4. TEHNO korrus | 7 | RF RAAM VERT-106
RF RAAM VERT-107 | 4. TEHNO korrus | 7 | RF RAAM VERT-107
RF RAAM VERT-108 | 4. TEHNO korrus | 7 | RF RAAM VERT-108
RF RAAM VERT-109 | 4. TEHNO korrus | 7 | RF RAAM VERT-109
RF RAAM VERT-110 | 4. TEHNO korrus | 7 | RF RAAM VERT-110
RF RAAM VERT-111 | 4. TEHNO korrus | 7 | RF RAAM VERT-111
RF RAAM VERT-112 | 4. TEHNO korrus | 7 | RF RAAM VERT-112
RF RAAM VERT-113 | 4. TEHNO korrus | 7 | RF RAAM VERT-113
RF RAAM VERT-114 | 4. TEHNO korrus | 7 | RF RAAM VERT-114
RF RAAM VERT-115 | 4. TEHNO korrus | 7 | RF RAAM VERT-115
RF RAAM VERT-116 | 4. TEHNO korrus | 7 | RF RAAM VERT-116
RF RAAM VERT-117 | 4. TEHNO korrus | 7 | RF RAAM VERT-117
RF RAAM VERT-118 | 4. TEHNO korrus | 7 | RF RAAM VERT-118
RF RAAM VERT-197 | 4. TEHNO korrus | 7 | RF RAAM VERT-197
RF RAAM VERT-193 | 4. TEHNO korrus | 7 | RF RAAM VERT-193
RF RAAM VERT-337 | 4. TEHNO korrus | 7 | RF RAAM VERT-337
RF RAAM VERT-199 | 4. TEHNO korrus | 7 | RF RAAM VERT-199
RF RAAM VERT-198 | 4. TEHNO korrus | 7 | RF RAAM VERT-198
RF RAAM VERT-339 | 4. TEHNO korrus | 7 | RF RAAM VERT-339
RF RAAM VERT-195 | 4. TEHNO korrus | 7 | RF RAAM VERT-195
RF RAAM VERT-194 | 4. TEHNO korrus | 7 | RF RAAM VERT-194
RF RAAM VERT-331 | 4. TEHNO korrus | 7 | RF RAAM VERT-331
RF RAAM VERT-332 | 4. TEHNO korrus | 7 | RF RAAM VERT-332
RF RAAM VERT-333 | 4. TEHNO korrus | 7 | RF RAAM VERT-333
RF RAAM VERT-335 | 4. TEHNO korrus | 7 | RF RAAM VERT-335

# IfcMember: Mullion Frame 50 x 70 (20)
In: 2. korrus
Type - PredefinedType: MEMBER
Classification: 1.13 IfcMemberType (kandev element) (RKAS BIM + ARCHICAD Classification)
Pset_MemberCommon - Reference: Built-in Frame; Slope: 90 deg
AR_001-002 - 002_Tüüp: Built-in Frame
AC_Pset_RenovationAndPhasing - Renovation Status: Undefined
Name | Material | 001_Nimetus
2 x RF RAAM VERT-268 | _METALL - alumiinium | RF RAAM VERT-268
2 x RF RAAM VERT-269 | _METALL - alumiinium | RF RAAM VERT-269
RF RAAM VERT-270 | _METALL - alumiinium | RF RAAM VERT-270
RF RAAM VERT-277 | _METALL - alumiinium | RF RAAM VERT-277
2 x RF RAAM VERT-282 | _METALL - alumiinium | RF RAAM VERT-282
2 x RF RAAM VERT-283 | _METALL - alumiinium | RF RAAM VERT-283
2 x RF RAAM VERT-284 | _METALL - alumiinium | RF RAAM VERT-284
RF RAAM VERT-293 | _METALL - alumiinium | RF RAAM VERT-293
RF RAAM VERT-238 | _METALL - alumiinium | RF RAAM VERT-238
RF RAAM VERT-239 | _METALL - alumiinium | RF RAAM VERT-239
RF RAAM VERT-335 | _KANDETARIND - puitkarkass | RF RAAM VERT-335
RF RAAM VERT-336 | _KANDETARIND - puitkarkass | RF RAAM VERT-336
RF RAAM VERT-317 | _METALL - alumiinium | RF RAAM VERT-317
RF RAAM VERT-267 | _METALL - alumiinium | RF RAAM VERT-267
RF RAAM VERT-276 | _METALL - alumiinium | RF RAAM VERT-276

# IfcMember: Mullion Frame 50 x 90 (21)
In: 2. korrus
Type - PredefinedType: MEMBER
Classification: 1.13 IfcMemberType (kandev element) (RKAS BIM + ARCHICAD Classification); Material: _METALL - alumiinium
Pset_MemberCommon - Reference: Built-in Frame; Slope: 90 deg
AR_001-002 - 002_Tüüp: Built-in Frame
AC_Pset_RenovationAndPhasing - Renovation Status: Undefined
Name | 001_Nimetus
RF RAAM VERT-301 | RF RAAM VERT-301
RF RAAM VERT-302 | RF RAAM VERT-302
RF RAAM VERT-311 | RF RAAM VERT-311
RF RAAM VERT-316 | RF RAAM VERT-316
RF RAAM VERT-317 | RF RAAM VERT-317
2 x RF RAAM VERT-321 | RF RAAM VERT-321
2 x RF RAAM VERT-322 | RF RAAM VERT-322
2 x RF RAAM VERT-323 | RF RAAM VERT-323
2 x RF RAAM VERT-324 | RF RAAM VERT-324
2 x RF RAAM VERT-333 | RF RAAM VERT-333
2 x RF RAAM VERT-334 | RF RAAM VERT-334
2 x RF RAAM VERT-335 | RF RAAM VERT-335
2 x RF RAAM VERT-336 | RF RAAM VERT-336

# IfcMember: Mullion Frame 60 x 160 (25)
In: 1. korrus
Type - PredefinedType: MEMBER
Classification: 1.13 IfcMemberType (kandev element) (RKAS BIM + ARCHICAD Classification); Material: _KANDETARIND - liimpuit vastavalt EK osale
Pset_MemberCommon - Reference: Built-in Butt-glazed Frame
AR_001-002 - 002_Tüüp: Built-in Butt-glazed Frame
AC_Pset_RenovationAndPhasing - Renovation Status: Undefined
Name | Slope (deg) | 001_Nimetus
RF RAAM VERT-345 | 90 | RF RAAM VERT-345
RF RAAM VERT-346 | 90 | RF RAAM VERT-346
RF RAAM VERT-347 | 90 | RF RAAM VERT-347
RF RAAM VERT-348 | 90 | RF RAAM VERT-348
RF RAAM VERT-350 | 90 | RF RAAM VERT-350
RF RAAM VERT-351 | 90 | RF RAAM VERT-351
RF RAAM VERT-353 | 90 | RF RAAM VERT-353
RF RAAM VERT-354 | 90 | RF RAAM VERT-354
RF RAAM VERT-355 | 90 | RF RAAM VERT-355
RF RAAM VERT-356 | 88.6028 | RF RAAM VERT-356
RF RAAM VERT-358 | 88.5679 | RF RAAM VERT-358
RF RAAM VERT-359 | 90 | RF RAAM VERT-359
RF RAAM VERT-446 | 90 | RF RAAM VERT-446
RF RAAM VERT-447 | 90 | RF RAAM VERT-447
RF RAAM VERT-448 | 90 | RF RAAM VERT-448
RF RAAM VERT-449 | 85.2115 | RF RAAM VERT-449
RF RAAM VERT-450 | 90 | RF RAAM VERT-450
RF RAAM VERT-451 | 85.2115 | RF RAAM VERT-451
RF RAAM VERT-452 | 90 | RF RAAM VERT-452
RF RAAM VERT-399 | 90 | RF RAAM VERT-399
RF RAAM VERT-400 | 90 | RF RAAM VERT-400
RF RAAM VERT-402 | 90 | RF RAAM VERT-402
RF RAAM VERT-403 | 90 | RF RAAM VERT-403
RF RAAM VERT-474 | 90 | RF RAAM VERT-474
RF RAAM VERT-475 | 90 | RF RAAM VERT-475

# IfcMember: Mullion Frame 60 x 200 (73)
In: 1. korrus
Type - PredefinedType: MEMBER
Classification: 1.13 IfcMemberType (kandev element) (RKAS BIM + ARCHICAD Classification); Material: _KANDETARIND - liimpuit vastavalt EK osale
Pset_MemberCommon - Reference: Built-in Butt-glazed Frame
AR_001-002 - 002_Tüüp: Built-in Butt-glazed Frame
AC_Pset_RenovationAndPhasing - Renovation Status: Undefined
Name | Slope (deg) | 001_Nimetus
RF RAAM VERT-675 | 90 | RF RAAM VERT-675
RF RAAM VERT-674 | 90 | RF RAAM VERT-674
RF RAAM VERT-673 | 90 | RF RAAM VERT-673
RF RAAM VERT-672 | 90 | RF RAAM VERT-672
RF RAAM VERT-671 | 90 | RF RAAM VERT-671
RF RAAM VERT-457 | 90 | RF RAAM VERT-457
RF RAAM VERT-458 | 90 | RF RAAM VERT-458
RF RAAM VERT-459 | 90 | RF RAAM VERT-459
RF RAAM VERT-460 | 90 | RF RAAM VERT-460
RF RAAM VERT-461 | 90 | RF RAAM VERT-461
RF RAAM VERT-462 | 90 | RF RAAM VERT-462
RF RAAM VERT-463 | 90 | RF RAAM VERT-463
RF RAAM VERT-464 | 90 | RF RAAM VERT-464
RF RAAM VERT-465 | 90 | RF RAAM VERT-465
RF RAAM VERT-466 | 90 | RF RAAM VERT-466
RF RAAM VERT-467 | 90 | RF RAAM VERT-467
RF RAAM VERT-468 | 90 | RF RAAM VERT-468
RF RAAM VERT-469 | 90 | RF RAAM VERT-469
RF RAAM VERT-470 | 90 | RF RAAM VERT-470
RF RAAM VERT-471 | 90 | RF RAAM VERT-471
RF RAAM VERT-472 | 90 | RF RAAM VERT-472
RF RAAM VERT-473 | 90 | RF RAAM VERT-473
RF RAAM VERT-479 | 88.4657 | RF RAAM VERT-479
RF RAAM VERT-480 | 90 | RF RAAM VERT-480
RF RAAM VERT-481 | 90 | RF RAAM VERT-481
RF RAAM VERT-482 | 90 | RF RAAM VERT-482
RF RAAM VERT-483 | 90 | RF RAAM VERT-483
RF RAAM VERT-484 | 90 | RF RAAM VERT-484
RF RAAM VERT-485 | 90 | RF RAAM VERT-485
RF RAAM VERT-486 | 90 | RF RAAM VERT-486
RF RAAM VERT-487 | 90 | RF RAAM VERT-487
RF RAAM VERT-488 | 90 | RF RAAM VERT-488
RF RAAM VERT-489 | 90 | RF RAAM VERT-489
RF RAAM VERT-490 | 90 | RF RAAM VERT-490
RF RAAM VERT-491 | 90 | RF RAAM VERT-491
RF RAAM VERT-492 | 90 | RF RAAM VERT-492
RF RAAM VERT-493 | 90 | RF RAAM VERT-493
RF RAAM VERT-494 | 90 | RF RAAM VERT-494
RF RAAM VERT-495 | 88.5057 | RF RAAM VERT-495
RF RAAM VERT-622 | 90 | RF RAAM VERT-622
RF RAAM VERT-500 | 90 | RF RAAM VERT-500
RF RAAM VERT-501 | 84.9649 | RF RAAM VERT-501
RF RAAM VERT-502 | 90 | RF RAAM VERT-502
RF RAAM VERT-503 | 90 | RF RAAM VERT-503
RF RAAM VERT-504 | 90 | RF RAAM VERT-504
RF RAAM VERT-505 | 90 | RF RAAM VERT-505
RF RAAM VERT-506 | 90 | RF RAAM VERT-506
RF RAAM VERT-507 | 90 | RF RAAM VERT-507
RF RAAM VERT-508 | 90 | RF RAAM VERT-508
RF RAAM VERT-509 | 90 | RF RAAM VERT-509
RF RAAM VERT-510 | 90 | RF RAAM VERT-510
RF RAAM VERT-511 | 90 | RF RAAM VERT-511
RF RAAM VERT-512 | 90 | RF RAAM VERT-512
RF RAAM VERT-513 | 90 | RF RAAM VERT-513
RF RAAM VERT-514 | 90 | RF RAAM VERT-514
RF RAAM VERT-515 | 90 | RF RAAM VERT-515
RF RAAM VERT-516 | 90 | RF RAAM VERT-516
RF RAAM VERT-517 | 84.9649 | RF RAAM VERT-517
RF RAAM VERT-518 | 90 | RF RAAM VERT-518
RF RAAM VERT-676 | 90 | RF RAAM VERT-676
RF RAAM VERT-677 | 90 | RF RAAM VERT-677
RF RAAM VERT-678 | 90 | RF RAAM VERT-678
RF RAAM VERT-679 | 90 | RF RAAM VERT-679
RF RAAM VERT-680 | 90 | RF RAAM VERT-680
RF RAAM VERT-681 | 90 | RF RAAM VERT-681
RF RAAM VERT-682 | 90 | RF RAAM VERT-682
RF RAAM VERT-683 | 90 | RF RAAM VERT-683
RF RAAM VERT-684 | 90 | RF RAAM VERT-684
RF RAAM VERT-685 | 90 | RF RAAM VERT-685
RF RAAM VERT-686 | 90 | RF RAAM VERT-686
RF RAAM VERT-687 | 90 | RF RAAM VERT-687
RF RAAM VERT-688 | 90 | RF RAAM VERT-688
RF RAAM VERT-689 | 90 | RF RAAM VERT-689

# IfcMember: Mullion Frame 60 x 360 (242)
In: 1. korrus
Type - PredefinedType: MEMBER
Classification: 1.13 IfcMemberType (kandev element) (RKAS BIM + ARCHICAD Classification); Material: _KANDETARIND - liimpuit vastavalt EK osale
Pset_MemberCommon - Reference: Built-in Butt-glazed Frame
AR_001-002 - 002_Tüüp: Built-in Butt-glazed Frame
AC_Pset_RenovationAndPhasing - Renovation Status: Undefined
Name | Slope (deg) | 001_Nimetus
121 x RF RAAM VERT-837 | 90 | RF RAAM VERT-837
RF RAAM VERT-837 | 88.6028 | RF RAAM VERT-837
RF RAAM VERT-837 | 81.573 | RF RAAM VERT-837
RF RAAM VERT-153 | 90 | RF RAAM VERT-153
RF RAAM VERT-154 | 90 | RF RAAM VERT-154
RF RAAM VERT-155 | 90 | RF RAAM VERT-155
RF RAAM VERT-156 | 90 | RF RAAM VERT-156
RF RAAM VERT-157 | 90 | RF RAAM VERT-157
RF RAAM VERT-158 | 90 | RF RAAM VERT-158
RF RAAM VERT-159 | 90 | RF RAAM VERT-159
RF RAAM VERT-160 | 90 | RF RAAM VERT-160
RF RAAM VERT-186 | 90 | RF RAAM VERT-186
RF RAAM VERT-187 | 90 | RF RAAM VERT-187
RF RAAM VERT-188 | 90 | RF RAAM VERT-188
RF RAAM VERT-189 | 90 | RF RAAM VERT-189
RF RAAM VERT-190 | 90 | RF RAAM VERT-190
RF RAAM VERT-227 | 90 | RF RAAM VERT-227
RF RAAM VERT-228 | 90 | RF RAAM VERT-228
RF RAAM VERT-229 | 90 | RF RAAM VERT-229
RF RAAM VERT-230 | 90 | RF RAAM VERT-230
RF RAAM VERT-231 | 90 | RF RAAM VERT-231
RF RAAM VERT-232 | 90 | RF RAAM VERT-232
RF RAAM VERT-233 | 90 | RF RAAM VERT-233
RF RAAM VERT-234 | 90 | RF RAAM VERT-234
RF RAAM VERT-257 | 90 | RF RAAM VERT-257
RF RAAM VERT-258 | 90 | RF RAAM VERT-258
RF RAAM VERT-259 | 90 | RF RAAM VERT-259
RF RAAM VERT-260 | 90 | RF RAAM VERT-260
RF RAAM VERT-489 | 90 | RF RAAM VERT-489
RF RAAM VERT-490 | 90 | RF RAAM VERT-490
RF RAAM VERT-491 | 90 | RF RAAM VERT-491
RF RAAM VERT-492 | 90 | RF RAAM VERT-492
RF RAAM VERT-493 | 90 | RF RAAM VERT-493
RF RAAM VERT-501 | 90 | RF RAAM VERT-501
62 x RF RAAM VERT-457 | 90 | RF RAAM VERT-457
RF RAAM VERT-457 | 88.6028 | RF RAAM VERT-457
3 x RF RAAM VERT-457 | 81.573 | RF RAAM VERT-457
RF RAAM VERT-457 | 88.5679 | RF RAAM VERT-457
RF RAAM VERT-457 | 88.6361 | RF RAAM VERT-457
RF RAAM VERT-849 | 90 | RF RAAM VERT-849
RF RAAM VERT-850 | 90 | RF RAAM VERT-850
RF RAAM VERT-851 | 90 | RF RAAM VERT-851
RF RAAM VERT-852 | 90 | RF RAAM VERT-852
RF RAAM VERT-872 | 90 | RF RAAM VERT-872
RF RAAM VERT-873 | 90 | RF RAAM VERT-873
RF RAAM VERT-874 | 90 | RF RAAM VERT-874
RF RAAM VERT-875 | 90 | RF RAAM VERT-875
RF RAAM VERT-876 | 90 | RF RAAM VERT-876
RF RAAM VERT-877 | 90 | RF RAAM VERT-877
RF RAAM VERT-878 | 90 | RF RAAM VERT-878
RF RAAM VERT-879 | 90 | RF RAAM VERT-879
RF RAAM VERT-880 | 90 | RF RAAM VERT-880
RF RAAM VERT-881 | 90 | RF RAAM VERT-881
RF RAAM VERT-882 | 90 | RF RAAM VERT-882
RF RAAM VERT-975 | 90 | RF RAAM VERT-975
RF RAAM VERT-976 | 90 | RF RAAM VERT-976
RF RAAM VERT-008 | 90 | RF RAAM VERT-008
RF RAAM VERT-009 | 90 | RF RAAM VERT-009
RF RAAM VERT-010 | 90 | RF RAAM VERT-010

# IfcMember: Mullion Frame 70 x 70 (18)
Type - PredefinedType: MEMBER
Classification: 1.13 IfcMemberType (kandev element) (RKAS BIM + ARCHICAD Classification); Material: _METALL - alumiinium
Pset_MemberCommon - Reference: Built-in Frame; Slope: 90 deg
AR_001-002 - 002_Tüüp: Built-in Frame
AC_Pset_RenovationAndPhasing - Renovation Status: Undefined
Name | In | 001_Nimetus
2 x RF RAAM VERT-299 | 1. korrus | RF RAAM VERT-299
2 x RF RAAM VERT-300 | 1. korrus | RF RAAM VERT-300
2 x RF RAAM VERT-311 | 1. korrus | RF RAAM VERT-311
2 x RF RAAM VERT-282 | 2. korrus | RF RAAM VERT-282
2 x RF RAAM VERT-283 | 2. korrus | RF RAAM VERT-283
2 x RF RAAM VERT-284 | 2. korrus | RF RAAM VERT-284
2 x RF RAAM VERT-285 | 2. korrus | RF RAAM VERT-285
2 x RF RAAM VERT-308 | 2. korrus | RF RAAM VERT-308
2 x RF RAAM VERT-309 | 2. korrus | RF RAAM VERT-309

# IfcMember: Transom Frame 50 x 100 (423)
Type - PredefinedType: MEMBER
Classification: 1.13 IfcMemberType (kandev element) (RKAS BIM + ARCHICAD Classification)
Pset_MemberCommon - Slope: 0 deg
AC_Pset_RenovationAndPhasing - Renovation Status: Undefined
Name | In | Material | Reference = 002_Tüüp | 001_Nimetus
RF RAAM HOR-705 | 1. korrus | _METALL - alumiinium | Frame 25 | RF RAAM HOR-705
26 x RF RAAM HOR-669 | 1. korrus | _METALL - alumiinium | Frame 25 | RF RAAM HOR-669
RF RAAM HOR-760 | 1. korrus | _METALL - alumiinium | Frame 25 | RF RAAM HOR-760
RF RAAM HOR-704 | 1. korrus | _METALL - alumiinium | Frame 25 | RF RAAM HOR-704
RF RAAM HOR-758 | 1. korrus | _METALL - alumiinium | Frame 25 | RF RAAM HOR-758
RF RAAM HOR-757 | 1. korrus | _METALL - alumiinium | Frame 25 | RF RAAM HOR-757
RF RAAM HOR-756 | 1. korrus | _METALL - alumiinium | Frame 25 | RF RAAM HOR-756
RF RAAM HOR-755 | 1. korrus | _METALL - alumiinium | Frame 25 | RF RAAM HOR-755
RF RAAM HOR-754 | 1. korrus | _METALL - alumiinium | Frame 25 | RF RAAM HOR-754
RF RAAM HOR-753 | 1. korrus | _METALL - alumiinium | Frame 25 | RF RAAM HOR-753
RF RAAM HOR-752 | 1. korrus | _METALL - alumiinium | Frame 25 | RF RAAM HOR-752
RF RAAM HOR-751 | 1. korrus | _METALL - alumiinium | Frame 25 | RF RAAM HOR-751
RF RAAM HOR-750 | 1. korrus | _METALL - alumiinium | Frame 25 | RF RAAM HOR-750
RF RAAM HOR-749 | 1. korrus | _METALL - alumiinium | Frame 25 | RF RAAM HOR-749
RF RAAM HOR-701 | 1. korrus | _METALL - alumiinium | Frame 25 | RF RAAM HOR-701
RF RAAM HOR-702 | 1. korrus | _METALL - alumiinium | Frame 25 | RF RAAM HOR-702
RF RAAM HOR-703 | 1. korrus | _METALL - alumiinium | Frame 25 | RF RAAM HOR-703
RF RAAM HOR-706 | 1. korrus | _METALL - alumiinium | Frame 25 | RF RAAM HOR-706
RF RAAM HOR-681 | 1. korrus | _METALL - alumiinium | Frame 25 | RF RAAM HOR-681
RF RAAM HOR-682 | 1. korrus | _METALL - alumiinium | Frame 25 | RF RAAM HOR-682
RF RAAM HOR-683 | 1. korrus | _METALL - alumiinium | Frame 25 | RF RAAM HOR-683
RF RAAM HOR-684 | 1. korrus | _METALL - alumiinium | Frame 25 | RF RAAM HOR-684
RF RAAM HOR-685 | 1. korrus | _METALL - alumiinium | Frame 25 | RF RAAM HOR-685
RF RAAM HOR-686 | 1. korrus | _METALL - alumiinium | Frame 25 | RF RAAM HOR-686
RF RAAM HOR-687 | 1. korrus | _METALL - alumiinium | Frame 25 | RF RAAM HOR-687
RF RAAM HOR-688 | 1. korrus | _METALL - alumiinium | Frame 25 | RF RAAM HOR-688
RF RAAM HOR-689 | 1. korrus | _METALL - alumiinium | Frame 25 | RF RAAM HOR-689
RF RAAM HOR-690 | 1. korrus | _METALL - alumiinium | Frame 25 | RF RAAM HOR-690
RF RAAM HOR-691 | 1. korrus | _METALL - alumiinium | Frame 25 | RF RAAM HOR-691
RF RAAM HOR-692 | 1. korrus | _METALL - alumiinium | Frame 25 | RF RAAM HOR-692
RF RAAM HOR-711 | 1. korrus | _METALL - alumiinium | Frame 25 | RF RAAM HOR-711
RF RAAM HOR-712 | 1. korrus | _METALL - alumiinium | Frame 25 | RF RAAM HOR-712
RF RAAM HOR-713 | 1. korrus | _METALL - alumiinium | Frame 25 | RF RAAM HOR-713
RF RAAM HOR-714 | 1. korrus | _METALL - alumiinium | Frame 25 | RF RAAM HOR-714
RF RAAM HOR-715 | 1. korrus | _METALL - alumiinium | Frame 25 | RF RAAM HOR-715
RF RAAM HOR-716 | 1. korrus | _METALL - alumiinium | Frame 25 | RF RAAM HOR-716
RF RAAM HOR-717 | 1. korrus | _METALL - alumiinium | Frame 25 | RF RAAM HOR-717
RF RAAM HOR-718 | 1. korrus | _METALL - alumiinium | Frame 25 | RF RAAM HOR-718
RF RAAM HOR-719 | 1. korrus | _METALL - alumiinium | Frame 25 | RF RAAM HOR-719
RF RAAM HOR-720 | 1. korrus | _METALL - alumiinium | Frame 25 | RF RAAM HOR-720
RF RAAM HOR-721 | 1. korrus | _METALL - alumiinium | Frame 25 | RF RAAM HOR-721
RF RAAM HOR-723 | 1. korrus | _METALL - alumiinium | Frame 25 | RF RAAM HOR-723
RF RAAM HOR-724 | 1. korrus | _METALL - alumiinium | Frame 25 | RF RAAM HOR-724
RF RAAM HOR-725 | 1. korrus | _METALL - alumiinium | Frame 25 | RF RAAM HOR-725
RF RAAM HOR-726 | 1. korrus | _METALL - alumiinium | Frame 25 | RF RAAM HOR-726
RF RAAM HOR-727 | 1. korrus | _METALL - alumiinium | Frame 25 | RF RAAM HOR-727
RF RAAM HOR-728 | 1. korrus | _METALL - alumiinium | Frame 25 | RF RAAM HOR-728
RF RAAM HOR-729 | 1. korrus | _METALL - alumiinium | Frame 25 | RF RAAM HOR-729
RF RAAM HOR-730 | 1. korrus | _METALL - alumiinium | Frame 25 | RF RAAM HOR-730
RF RAAM HOR-731 | 1. korrus | _METALL - alumiinium | Frame 25 | RF RAAM HOR-731
RF RAAM HOR-732 | 1. korrus | _METALL - alumiinium | Frame 25 | RF RAAM HOR-732
RF RAAM HOR-733 | 1. korrus | _METALL - alumiinium | Frame 25 | RF RAAM HOR-733
2 x RF RAAM HOR-827 | 1. korrus | _METALL - alumiinium | Frame 25 | RF RAAM HOR-827
2 x RF RAAM HOR-828 | 1. korrus | _METALL - alumiinium | Frame 25 | RF RAAM HOR-828
2 x RF RAAM HOR-829 | 1. korrus | _METALL - alumiinium | Frame 25 | RF RAAM HOR-829
2 x RF RAAM HOR-830 | 1. korrus | _METALL - alumiinium | Frame 25 | RF RAAM HOR-830
2 x RF RAAM HOR-831 | 1. korrus | _METALL - alumiinium | Frame 25 | RF RAAM HOR-831
RF RAAM HOR-978 | 1. korrus | _METALL - alumiinium | Frame 25 | RF RAAM HOR-978
RF RAAM HOR-979 | 1. korrus | _METALL - alumiinium | Frame 25 | RF RAAM HOR-979
RF RAAM HOR-980 | 1. korrus | _METALL - alumiinium | Frame 25 | RF RAAM HOR-980
RF RAAM HOR-981 | 1. korrus | _METALL - alumiinium | Frame 25 | RF RAAM HOR-981
RF RAAM HOR-982 | 1. korrus | _METALL - alumiinium | Frame 25 | RF RAAM HOR-982
RF RAAM HOR-026 | 1. korrus | _METALL - alumiinium | Frame 25 | RF RAAM HOR-026
RF RAAM HOR-027 | 1. korrus | _METALL - alumiinium | Frame 25 | RF RAAM HOR-027
RF RAAM HOR-028 | 1. korrus | _METALL - alumiinium | Frame 25 | RF RAAM HOR-028
RF RAAM HOR-029 | 1. korrus | _METALL - alumiinium | Frame 25 | RF RAAM HOR-029
RF RAAM HOR-030 | 1. korrus | _METALL - alumiinium | Frame 25 | RF RAAM HOR-030
RF RAAM HOR-031 | 1. korrus | _METALL - alumiinium | Frame 25 | RF RAAM HOR-031
RF RAAM HOR-032 | 1. korrus | _METALL - alumiinium | Frame 25 | RF RAAM HOR-032
RF RAAM HOR-033 | 1. korrus | _METALL - alumiinium | Frame 25 | RF RAAM HOR-033
RF RAAM HOR-034 | 1. korrus | _METALL - alumiinium | Frame 25 | RF RAAM HOR-034
RF RAAM HOR-035 | 1. korrus | _METALL - alumiinium | Frame 25 | RF RAAM HOR-035
RF RAAM HOR-036 | 1. korrus | _METALL - alumiinium | Frame 25 | RF RAAM HOR-036
RF RAAM HOR-037 | 1. korrus | _METALL - alumiinium | Frame 25 | RF RAAM HOR-037
RF RAAM HOR-038 | 1. korrus | _METALL - alumiinium | Frame 25 | RF RAAM HOR-038
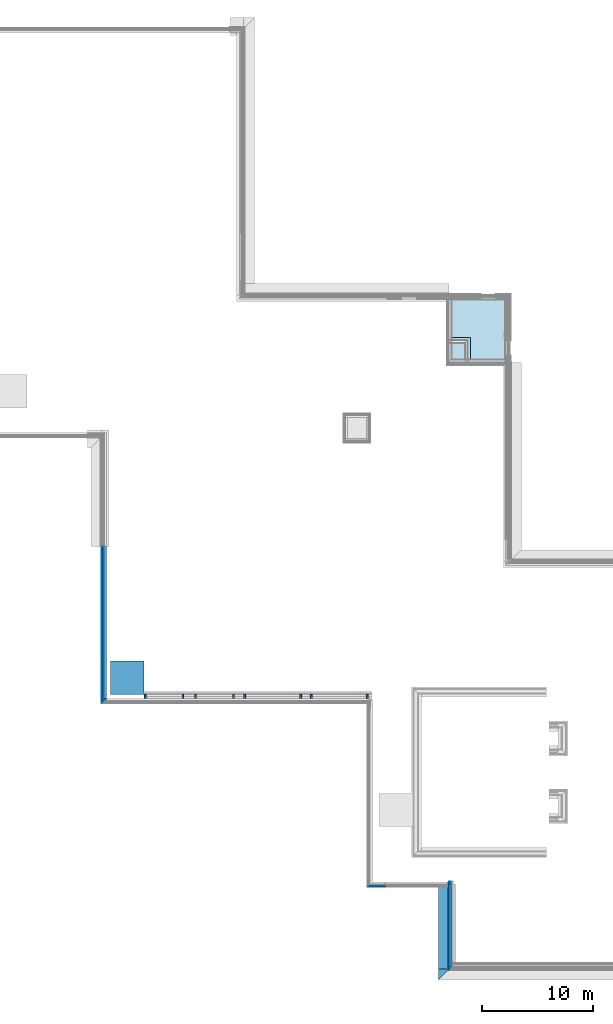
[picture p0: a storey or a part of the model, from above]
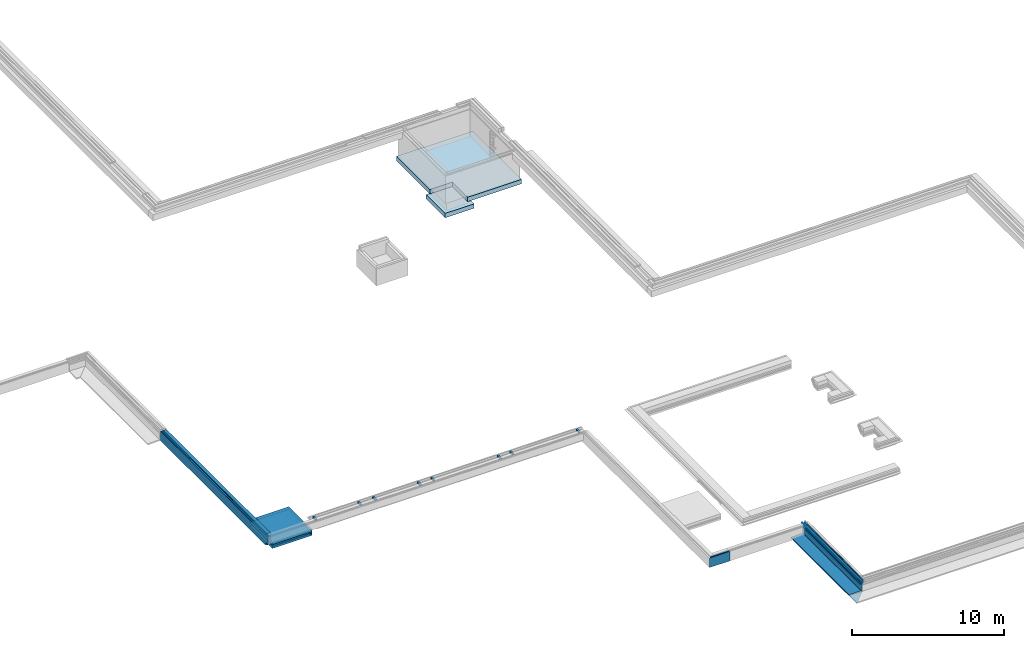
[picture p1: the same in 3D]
Properties of the parts of a building model (IFC2X3), part 8 of 14

# IfcMember: Transom Frame 50 x 100 (423)
Name | In | Material | Reference = 002_Tüüp | 001_Nimetus
RF RAAM HOR-039 | 1. korrus | _METALL - alumiinium | Frame 25 | RF RAAM HOR-039
RF RAAM HOR-040 | 1. korrus | _METALL - alumiinium | Frame 25 | RF RAAM HOR-040
RF RAAM HOR-043 | 1. korrus | _METALL - alumiinium | Frame 25 | RF RAAM HOR-043
RF RAAM HOR-044 | 1. korrus | _METALL - alumiinium | Frame 25 | RF RAAM HOR-044
RF RAAM HOR-045 | 1. korrus | _METALL - alumiinium | Frame 25 | RF RAAM HOR-045
RF RAAM HOR-046 | 1. korrus | _METALL - alumiinium | Frame 25 | RF RAAM HOR-046
RF RAAM HOR-047 | 1. korrus | _METALL - alumiinium | Frame 25 | RF RAAM HOR-047
RF RAAM HOR-048 | 1. korrus | _METALL - alumiinium | Frame 25 | RF RAAM HOR-048
RF RAAM HOR-049 | 1. korrus | _METALL - alumiinium | Frame 25 | RF RAAM HOR-049
RF RAAM HOR-050 | 1. korrus | _METALL - alumiinium | Frame 25 | RF RAAM HOR-050
RF RAAM HOR-051 | 1. korrus | _METALL - alumiinium | Frame 25 | RF RAAM HOR-051
RF RAAM HOR-052 | 1. korrus | _METALL - alumiinium | Frame 25 | RF RAAM HOR-052
RF RAAM HOR-053 | 1. korrus | _METALL - alumiinium | Frame 25 | RF RAAM HOR-053
RF RAAM HOR-054 | 1. korrus | _METALL - alumiinium | Frame 25 | RF RAAM HOR-054
RF RAAM HOR-055 | 1. korrus | _METALL - alumiinium | Frame 25 | RF RAAM HOR-055
RF RAAM HOR-056 | 1. korrus | _METALL - alumiinium | Frame 25 | RF RAAM HOR-056
RF RAAM HOR-057 | 1. korrus | _METALL - alumiinium | Frame 25 | RF RAAM HOR-057
RF RAAM HOR-060 | 1. korrus | _METALL - alumiinium | Frame 25 | RF RAAM HOR-060
RF RAAM HOR-061 | 1. korrus | _METALL - alumiinium | Frame 25 | RF RAAM HOR-061
RF RAAM HOR-062 | 1. korrus | _METALL - alumiinium | Frame 25 | RF RAAM HOR-062
RF RAAM HOR-063 | 1. korrus | _METALL - alumiinium | Frame 25 | RF RAAM HOR-063
RF RAAM HOR-064 | 1. korrus | _METALL - alumiinium | Frame 25 | RF RAAM HOR-064
RF RAAM HOR-065 | 1. korrus | _METALL - alumiinium | Frame 25 | RF RAAM HOR-065
RF RAAM HOR-066 | 1. korrus | _METALL - alumiinium | Frame 25 | RF RAAM HOR-066
RF RAAM HOR-067 | 1. korrus | _METALL - alumiinium | Frame 25 | RF RAAM HOR-067
RF RAAM HOR-068 | 1. korrus | _METALL - alumiinium | Frame 25 | RF RAAM HOR-068
RF RAAM HOR-069 | 1. korrus | _METALL - alumiinium | Frame 25 | RF RAAM HOR-069
RF RAAM HOR-070 | 1. korrus | _METALL - alumiinium | Frame 25 | RF RAAM HOR-070
RF RAAM HOR-071 | 1. korrus | _METALL - alumiinium | Frame 25 | RF RAAM HOR-071
RF RAAM HOR-072 | 1. korrus | _METALL - alumiinium | Frame 25 | RF RAAM HOR-072
RF RAAM HOR-073 | 1. korrus | _METALL - alumiinium | Frame 25 | RF RAAM HOR-073
RF RAAM HOR-074 | 1. korrus | _METALL - alumiinium | Frame 25 | RF RAAM HOR-074
RF RAAM HOR-077 | 1. korrus | _METALL - alumiinium | Frame 25 | RF RAAM HOR-077
RF RAAM HOR-078 | 1. korrus | _METALL - alumiinium | Frame 25 | RF RAAM HOR-078
RF RAAM HOR-079 | 1. korrus | _METALL - alumiinium | Frame 25 | RF RAAM HOR-079
RF RAAM HOR-080 | 1. korrus | _METALL - alumiinium | Frame 25 | RF RAAM HOR-080
RF RAAM HOR-081 | 1. korrus | _METALL - alumiinium | Frame 25 | RF RAAM HOR-081
RF RAAM HOR-082 | 1. korrus | _METALL - alumiinium | Frame 25 | RF RAAM HOR-082
RF RAAM HOR-083 | 1. korrus | _METALL - alumiinium | Frame 25 | RF RAAM HOR-083
RF RAAM HOR-084 | 1. korrus | _METALL - alumiinium | Frame 25 | RF RAAM HOR-084
RF RAAM HOR-085 | 1. korrus | _METALL - alumiinium | Frame 25 | RF RAAM HOR-085
RF RAAM HOR-086 | 1. korrus | _METALL - alumiinium | Frame 25 | RF RAAM HOR-086
RF RAAM HOR-087 | 1. korrus | _METALL - alumiinium | Frame 25 | RF RAAM HOR-087
RF RAAM HOR-088 | 1. korrus | _METALL - alumiinium | Frame 25 | RF RAAM HOR-088
RF RAAM HOR-089 | 1. korrus | _METALL - alumiinium | Frame 25 | RF RAAM HOR-089
RF RAAM HOR-090 | 1. korrus | _METALL - alumiinium | Frame 25 | RF RAAM HOR-090
RF RAAM HOR-091 | 1. korrus | _METALL - alumiinium | Frame 25 | RF RAAM HOR-091
RF RAAM HOR-094 | 1. korrus | _METALL - alumiinium | Frame 25 | RF RAAM HOR-094
RF RAAM HOR-095 | 1. korrus | _METALL - alumiinium | Frame 25 | RF RAAM HOR-095
RF RAAM HOR-096 | 1. korrus | _METALL - alumiinium | Frame 25 | RF RAAM HOR-096
RF RAAM HOR-097 | 1. korrus | _METALL - alumiinium | Frame 25 | RF RAAM HOR-097
RF RAAM HOR-098 | 1. korrus | _METALL - alumiinium | Frame 25 | RF RAAM HOR-098
RF RAAM HOR-099 | 1. korrus | _METALL - alumiinium | Frame 25 | RF RAAM HOR-099
RF RAAM HOR-100 | 1. korrus | _METALL - alumiinium | Frame 25 | RF RAAM HOR-100
RF RAAM HOR-101 | 1. korrus | _METALL - alumiinium | Frame 25 | RF RAAM HOR-101
RF RAAM HOR-102 | 1. korrus | _METALL - alumiinium | Frame 25 | RF RAAM HOR-102
RF RAAM HOR-103 | 1. korrus | _METALL - alumiinium | Frame 25 | RF RAAM HOR-103
RF RAAM HOR-104 | 1. korrus | _METALL - alumiinium | Frame 25 | RF RAAM HOR-104
RF RAAM HOR-105 | 1. korrus | _METALL - alumiinium | Frame 25 | RF RAAM HOR-105
RF RAAM HOR-106 | 1. korrus | _METALL - alumiinium | Frame 25 | RF RAAM HOR-106
RF RAAM HOR-107 | 1. korrus | _METALL - alumiinium | Frame 25 | RF RAAM HOR-107
RF RAAM HOR-108 | 1. korrus | _METALL - alumiinium | Frame 25 | RF RAAM HOR-108
RF RAAM HOR-128 | 1. korrus | _METALL - alumiinium | Frame 25 | RF RAAM HOR-128
RF RAAM HOR-129 | 1. korrus | _METALL - alumiinium | Frame 25 | RF RAAM HOR-129
RF RAAM HOR-130 | 1. korrus | _METALL - alumiinium | Frame 25 | RF RAAM HOR-130
RF RAAM HOR-131 | 1. korrus | _METALL - alumiinium | Frame 25 | RF RAAM HOR-131
RF RAAM HOR-132 | 1. korrus | _METALL - alumiinium | Frame 25 | RF RAAM HOR-132
RF RAAM HOR-241 | 1. korrus | _METALL - alumiinium | Frame 25 | RF RAAM HOR-241
RF RAAM HOR-242 | 1. korrus | _METALL - alumiinium | Frame 25 | RF RAAM HOR-242
RF RAAM HOR-243 | 1. korrus | _METALL - alumiinium | Frame 25 | RF RAAM HOR-243
RF RAAM HOR-244 | 1. korrus | _METALL - alumiinium | Frame 25 | RF RAAM HOR-244
RF RAAM HOR-245 | 1. korrus | _METALL - alumiinium | Frame 25 | RF RAAM HOR-245
RF RAAM HOR-301 | 1. korrus | _METALL - alumiinium | Frame 25 | RF RAAM HOR-301
RF RAAM HOR-302 | 1. korrus | _METALL - alumiinium | Frame 25 | RF RAAM HOR-302
RF RAAM HOR-303 | 1. korrus | _METALL - alumiinium | Frame 25 | RF RAAM HOR-303
RF RAAM HOR-304 | 1. korrus | _METALL - alumiinium | Frame 25 | RF RAAM HOR-304
RF RAAM HOR-305 | 1. korrus | _METALL - alumiinium | Frame 25 | RF RAAM HOR-305
RF RAAM HOR-306 | 1. korrus | _METALL - alumiinium | Frame 25 | RF RAAM HOR-306
RF RAAM HOR-307 | 1. korrus | _METALL - alumiinium | Frame 25 | RF RAAM HOR-307
RF RAAM HOR-312 | 1. korrus | _METALL - alumiinium | Frame 25 | RF RAAM HOR-312
RF RAAM HOR-313 | 1. korrus | _METALL - alumiinium | Frame 25 | RF RAAM HOR-313
RF RAAM HOR-314 | 1. korrus | _METALL - alumiinium | Frame 25 | RF RAAM HOR-314
RF RAAM HOR-315 | 1. korrus | _METALL - alumiinium | Frame 25 | RF RAAM HOR-315
RF RAAM HOR-316 | 1. korrus | _METALL - alumiinium | Frame 25 | RF RAAM HOR-316
RF RAAM HOR-317 | 1. korrus | _METALL - alumiinium | Frame 25 | RF RAAM HOR-317
RF RAAM HOR-318 | 1. korrus | _METALL - alumiinium | Frame 25 | RF RAAM HOR-318
RF RAAM HOR-319 | 1. korrus | _METALL - alumiinium | Frame 25 | RF RAAM HOR-319
RF RAAM HOR-320 | 1. korrus | _METALL - alumiinium | Frame 25 | RF RAAM HOR-320
RF RAAM HOR-323 | 1. korrus | _METALL - alumiinium | Frame 25 | RF RAAM HOR-323
RF RAAM HOR-324 | 1. korrus | _METALL - alumiinium | Frame 25 | RF RAAM HOR-324
RF RAAM HOR-325 | 1. korrus | _METALL - alumiinium | Frame 25 | RF RAAM HOR-325
RF RAAM HOR-326 | 1. korrus | _METALL - alumiinium | Frame 25 | RF RAAM HOR-326
RF RAAM HOR-327 | 1. korrus | _METALL - alumiinium | Frame 25 | RF RAAM HOR-327
RF RAAM HOR-328 | 1. korrus | _METALL - alumiinium | Frame 25 | RF RAAM HOR-328
2 x RF RAAM HOR-329 | 1. korrus | _METALL - alumiinium | Frame 25 | RF RAAM HOR-329
2 x RF RAAM HOR-330 | 1. korrus | _METALL - alumiinium | Frame 25 | RF RAAM HOR-330
RF RAAM HOR-331 | 1. korrus | _METALL - alumiinium | Frame 25 | RF RAAM HOR-331
RF RAAM HOR-334 | 1. korrus | _METALL - alumiinium | Frame 25 | RF RAAM HOR-334
RF RAAM HOR-335 | 1. korrus | _METALL - alumiinium | Frame 25 | RF RAAM HOR-335
RF RAAM HOR-336 | 1. korrus | _METALL - alumiinium | Frame 25 | RF RAAM HOR-336
RF RAAM HOR-337 | 1. korrus | _METALL - alumiinium | Frame 25 | RF RAAM HOR-337
RF RAAM HOR-338 | 1. korrus | _METALL - alumiinium | Frame 25 | RF RAAM HOR-338
RF RAAM HOR-339 | 1. korrus | _METALL - alumiinium | Frame 25 | RF RAAM HOR-339
RF RAAM HOR-340 | 1. korrus | _METALL - alumiinium | Frame 25 | RF RAAM HOR-340
RF RAAM HOR-341 | 1. korrus | _METALL - alumiinium | Frame 25 | RF RAAM HOR-341
RF RAAM HOR-342 | 1. korrus | _METALL - alumiinium | Frame 25 | RF RAAM HOR-342
RF RAAM HOR-345 | 1. korrus | _METALL - alumiinium | Frame 25 | RF RAAM HOR-345
RF RAAM HOR-346 | 1. korrus | _METALL - alumiinium | Frame 25 | RF RAAM HOR-346
RF RAAM HOR-347 | 1. korrus | _METALL - alumiinium | Frame 25 | RF RAAM HOR-347
RF RAAM HOR-348 | 1. korrus | _METALL - alumiinium | Frame 25 | RF RAAM HOR-348
RF RAAM HOR-349 | 1. korrus | _METALL - alumiinium | Frame 25 | RF RAAM HOR-349
RF RAAM HOR-350 | 1. korrus | _METALL - alumiinium | Frame 25 | RF RAAM HOR-350
RF RAAM HOR-351 | 1. korrus | _METALL - alumiinium | Frame 25 | RF RAAM HOR-351
RF RAAM HOR-352 | 1. korrus | _METALL - alumiinium | Frame 25 | RF RAAM HOR-352
RF RAAM HOR-353 | 1. korrus | _METALL - alumiinium | Frame 25 | RF RAAM HOR-353
RF RAAM HOR-503 | 1. korrus | _METALL - alumiinium | Frame 25 | RF RAAM HOR-503
RF RAAM HOR-956 | 1. korrus | _METALL - alumiinium | Frame 25 | RF RAAM HOR-956
RF RAAM HOR-591 | 1. korrus | _METALL - alumiinium | Frame 25 | RF RAAM HOR-591
RF RAAM HOR-592 | 1. korrus | _METALL - alumiinium | Frame 25 | RF RAAM HOR-592
RF RAAM HOR-593 | 1. korrus | _METALL - alumiinium | Frame 25 | RF RAAM HOR-593
RF RAAM HOR-594 | 1. korrus | _METALL - alumiinium | Frame 25 | RF RAAM HOR-594
RF RAAM HOR-595 | 1. korrus | _METALL - alumiinium | Frame 25 | RF RAAM HOR-595
RF RAAM HOR-596 | 1. korrus | _METALL - alumiinium | Frame 25 | RF RAAM HOR-596
RF RAAM HOR-597 | 1. korrus | _METALL - alumiinium | Frame 25 | RF RAAM HOR-597
RF RAAM HOR-598 | 1. korrus | _METALL - alumiinium | Frame 25 | RF RAAM HOR-598
RF RAAM HOR-599 | 1. korrus | _METALL - alumiinium | Frame 25 | RF RAAM HOR-599
RF RAAM HOR-600 | 1. korrus | _METALL - alumiinium | Frame 25 | RF RAAM HOR-600
RF RAAM HOR-601 | 1. korrus | _METALL - alumiinium | Frame 25 | RF RAAM HOR-601
RF RAAM HOR-602 | 1. korrus | _METALL - alumiinium | Frame 25 | RF RAAM HOR-602
RF RAAM HOR-604 | 1. korrus | _METALL - alumiinium | Frame 25 | RF RAAM HOR-604
RF RAAM HOR-605 | 1. korrus | _METALL - alumiinium | Frame 25 | RF RAAM HOR-605
RF RAAM HOR-606 | 1. korrus | _METALL - alumiinium | Frame 25 | RF RAAM HOR-606
RF RAAM HOR-607 | 1. korrus | _METALL - alumiinium | Frame 25 | RF RAAM HOR-607
RF RAAM HOR-608 | 1. korrus | _METALL - alumiinium | Frame 25 | RF RAAM HOR-608
RF RAAM HOR-609 | 1. korrus | _METALL - alumiinium | Frame 25 | RF RAAM HOR-609
RF RAAM HOR-610 | 1. korrus | _METALL - alumiinium | Frame 25 | RF RAAM HOR-610
RF RAAM HOR-611 | 1. korrus | _METALL - alumiinium | Frame 25 | RF RAAM HOR-611
RF RAAM HOR-612 | 1. korrus | _METALL - alumiinium | Frame 25 | RF RAAM HOR-612
RF RAAM HOR-613 | 1. korrus | _METALL - alumiinium | Frame 25 | RF RAAM HOR-613
RF RAAM HOR-614 | 1. korrus | _METALL - alumiinium | Frame 25 | RF RAAM HOR-614
RF RAAM HOR-615 | 1. korrus | _METALL - alumiinium | Frame 25 | RF RAAM HOR-615
RF RAAM HOR-616 | 1. korrus | _METALL - alumiinium | Frame 25 | RF RAAM HOR-616
RF RAAM HOR-617 | 1. korrus | _METALL - alumiinium | Frame 25 | RF RAAM HOR-617
RF RAAM HOR-618 | 1. korrus | _METALL - alumiinium | Frame 25 | RF RAAM HOR-618
RF RAAM HOR-619 | 1. korrus | _METALL - alumiinium | Frame 25 | RF RAAM HOR-619
RF RAAM HOR-620 | 1. korrus | _METALL - alumiinium | Frame 25 | RF RAAM HOR-620
RF RAAM HOR-621 | 1. korrus | _METALL - alumiinium | Frame 25 | RF RAAM HOR-621
RF RAAM HOR-622 | 1. korrus | _METALL - alumiinium | Frame 25 | RF RAAM HOR-622
RF RAAM HOR-623 | 1. korrus | _METALL - alumiinium | Frame 25 | RF RAAM HOR-623
RF RAAM HOR-624 | 1. korrus | _METALL - alumiinium | Frame 25 | RF RAAM HOR-624
RF RAAM HOR-625 | 1. korrus | _METALL - alumiinium | Frame 25 | RF RAAM HOR-625
RF RAAM HOR-626 | 1. korrus | _METALL - alumiinium | Frame 25 | RF RAAM HOR-626
RF RAAM HOR-627 | 1. korrus | _METALL - alumiinium | Frame 25 | RF RAAM HOR-627
RF RAAM HOR-628 | 1. korrus | _METALL - alumiinium | Frame 25 | RF RAAM HOR-628
RF RAAM HOR-629 | 1. korrus | _METALL - alumiinium | Frame 25 | RF RAAM HOR-629
RF RAAM HOR-630 | 1. korrus | _METALL - alumiinium | Frame 25 | RF RAAM HOR-630
RF RAAM HOR-631 | 1. korrus | _METALL - alumiinium | Frame 25 | RF RAAM HOR-631
RF RAAM HOR-632 | 1. korrus | _METALL - alumiinium | Frame 25 | RF RAAM HOR-632
RF RAAM HOR-633 | 1. korrus | _METALL - alumiinium | Frame 25 | RF RAAM HOR-633
RF RAAM HOR-634 | 1. korrus | _METALL - alumiinium | Frame 25 | RF RAAM HOR-634
RF RAAM HOR-635 | 1. korrus | _METALL - alumiinium | Frame 25 | RF RAAM HOR-635
RF RAAM HOR-821 | 1. korrus | _METALL - alumiinium | Frame 25 | RF RAAM HOR-821
RF RAAM HOR-822 | 1. korrus | _METALL - alumiinium | Frame 25 | RF RAAM HOR-822
RF RAAM HOR-823 | 1. korrus | _METALL - alumiinium | Frame 25 | RF RAAM HOR-823
RF RAAM HOR-824 | 1. korrus | _METALL - alumiinium | Frame 25 | RF RAAM HOR-824
RF RAAM HOR-825 | 1. korrus | _METALL - alumiinium | Frame 25 | RF RAAM HOR-825
RF RAAM HOR-826 | 1. korrus | _METALL - alumiinium | Frame 25 | RF RAAM HOR-826
RF RAAM HOR-832 | 1. korrus | _METALL - alumiinium | Frame 25 | RF RAAM HOR-832
RF RAAM HOR-833 | 1. korrus | _METALL - alumiinium | Frame 25 | RF RAAM HOR-833
RF RAAM HOR-834 | 1. korrus | _METALL - alumiinium | Frame 25 | RF RAAM HOR-834
RF RAAM HOR-835 | 1. korrus | _METALL - alumiinium | Frame 25 | RF RAAM HOR-835
RF RAAM HOR-836 | 1. korrus | _METALL - alumiinium | Frame 25 | RF RAAM HOR-836
RF RAAM HOR-837 | 1. korrus | _METALL - alumiinium | Frame 25 | RF RAAM HOR-837
RF RAAM HOR-838 | 1. korrus | _METALL - alumiinium | Frame 25 | RF RAAM HOR-838
RF RAAM HOR-839 | 1. korrus | _METALL - alumiinium | Frame 25 | RF RAAM HOR-839
RF RAAM HOR-840 | 1. korrus | _METALL - alumiinium | Frame 25 | RF RAAM HOR-840
RF RAAM HOR-843 | 1. korrus | _METALL - alumiinium | Frame 25 | RF RAAM HOR-843
RF RAAM HOR-844 | 1. korrus | _METALL - alumiinium | Frame 25 | RF RAAM HOR-844
RF RAAM HOR-845 | 1. korrus | _METALL - alumiinium | Frame 25 | RF RAAM HOR-845
RF RAAM HOR-846 | 1. korrus | _METALL - alumiinium | Frame 25 | RF RAAM HOR-846
RF RAAM HOR-847 | 1. korrus | _METALL - alumiinium | Frame 25 | RF RAAM HOR-847
RF RAAM HOR-848 | 1. korrus | _METALL - alumiinium | Frame 25 | RF RAAM HOR-848
RF RAAM HOR-849 | 1. korrus | _METALL - alumiinium | Frame 25 | RF RAAM HOR-849
RF RAAM HOR-850 | 1. korrus | _METALL - alumiinium | Frame 25 | RF RAAM HOR-850
RF RAAM HOR-914 | 1. korrus | _METALL - alumiinium | Frame 25 | RF RAAM HOR-914
RF RAAM HOR-915 | 1. korrus | _METALL - alumiinium | Frame 25 | RF RAAM HOR-915
RF RAAM HOR-916 | 1. korrus | _METALL - alumiinium | Frame 25 | RF RAAM HOR-916
RF RAAM HOR-917 | 1. korrus | _METALL - alumiinium | Frame 25 | RF RAAM HOR-917
RF RAAM HOR-918 | 1. korrus | _METALL - alumiinium | Frame 25 | RF RAAM HOR-918
RF RAAM HOR-919 | 1. korrus | _METALL - alumiinium | Frame 25 | RF RAAM HOR-919
RF RAAM HOR-920 | 1. korrus | _METALL - alumiinium | Frame 25 | RF RAAM HOR-920
RF RAAM HOR-921 | 1. korrus | _METALL - alumiinium | Frame 25 | RF RAAM HOR-921
RF RAAM HOR-922 | 1. korrus | _METALL - alumiinium | Frame 25 | RF RAAM HOR-922
RF RAAM HOR-923 | 1. korrus | _METALL - alumiinium | Frame 25 | RF RAAM HOR-923
RF RAAM HOR-924 | 1. korrus | _METALL - alumiinium | Frame 25 | RF RAAM HOR-924
RF RAAM HOR-928 | 1. korrus | _METALL - alumiinium | Frame 25 | RF RAAM HOR-928
RF RAAM HOR-929 | 1. korrus | _METALL - alumiinium | Frame 25 | RF RAAM HOR-929
RF RAAM HOR-930 | 1. korrus | _METALL - alumiinium | Frame 25 | RF RAAM HOR-930
RF RAAM HOR-931 | 1. korrus | _METALL - alumiinium | Frame 25 | RF RAAM HOR-931
RF RAAM HOR-932 | 1. korrus | _METALL - alumiinium | Frame 25 | RF RAAM HOR-932
RF RAAM HOR-933 | 1. korrus | _METALL - alumiinium | Frame 25 | RF RAAM HOR-933
RF RAAM HOR-934 | 1. korrus | _METALL - alumiinium | Frame 25 | RF RAAM HOR-934
RF RAAM HOR-935 | 1. korrus | _METALL - alumiinium | Frame 25 | RF RAAM HOR-935
RF RAAM HOR-936 | 1. korrus | _METALL - alumiinium | Frame 25 | RF RAAM HOR-936
RF RAAM HOR-937 | 1. korrus | _METALL - alumiinium | Frame 25 | RF RAAM HOR-937
RF RAAM HOR-938 | 1. korrus | _METALL - alumiinium | Frame 25 | RF RAAM HOR-938
RF RAAM HOR-939 | 1. korrus | _METALL - alumiinium | Frame 25 | RF RAAM HOR-939
RF RAAM HOR-940 | 1. korrus | _METALL - alumiinium | Frame 25 | RF RAAM HOR-940
RF RAAM HOR-941 | 1. korrus | _METALL - alumiinium | Frame 25 | RF RAAM HOR-941
RF RAAM HOR-942 | 1. korrus | _METALL - alumiinium | Frame 25 | RF RAAM HOR-942
RF RAAM HOR-943 | 1. korrus | _METALL - alumiinium | Frame 25 | RF RAAM HOR-943
RF RAAM HOR-944 | 1. korrus | _METALL - alumiinium | Frame 25 | RF RAAM HOR-944
RF RAAM HOR-945 | 1. korrus | _METALL - alumiinium | Frame 25 | RF RAAM HOR-945
RF RAAM HOR-946 | 1. korrus | _METALL - alumiinium | Frame 25 | RF RAAM HOR-946
RF RAAM HOR-947 | 1. korrus | _METALL - alumiinium | Frame 25 | RF RAAM HOR-947
RF RAAM HOR-948 | 1. korrus | _METALL - alumiinium | Frame 25 | RF RAAM HOR-948
RF RAAM HOR-949 | 1. korrus | _METALL - alumiinium | Frame 25 | RF RAAM HOR-949
RF RAAM HOR-951 | 1. korrus | _METALL - alumiinium | Frame 25 | RF RAAM HOR-951
RF RAAM HOR-952 | 1. korrus | _METALL - alumiinium | Frame 25 | RF RAAM HOR-952
RF RAAM HOR-881 | 1. korrus | _METALL - alumiinium | Frame 25 | RF RAAM HOR-881
RF RAAM HOR-954 | 1. korrus | _METALL - alumiinium | Frame 25 | RF RAAM HOR-954
RF RAAM HOR-955 | 1. korrus | _METALL - alumiinium | Frame 25 | RF RAAM HOR-955
RF RAAM HOR-393 | 1. korrus | _METALL - alumiinium | Frame 25 | RF RAAM HOR-393
RF RAAM HOR-394 | 1. korrus | _METALL - alumiinium | Frame 25 | RF RAAM HOR-394
RF RAAM HOR-395 | 1. korrus | _METALL - alumiinium | Frame 25 | RF RAAM HOR-395
RF RAAM HOR-396 | 1. korrus | _METALL - alumiinium | Frame 25 | RF RAAM HOR-396
RF RAAM HOR-397 | 1. korrus | _METALL - alumiinium | Frame 25 | RF RAAM HOR-397
RF RAAM HOR-746 | 1. korrus | _METALL - alumiinium | Frame 25 | RF RAAM HOR-746
RF RAAM HOR-747 | 1. korrus | _METALL - alumiinium | Frame 25 | RF RAAM HOR-747
RF RAAM HOR-748 | 1. korrus | _METALL - alumiinium | Frame 25 | RF RAAM HOR-748
RF RAAM HOR-813 | 1. korrus | _METALL - alumiinium | Frame 25 | RF RAAM HOR-813
RF RAAM HOR-882 | 1. korrus | _METALL - alumiinium | Frame 25 | RF RAAM HOR-882
RF RAAM HOR-883 | 1. korrus | _METALL - alumiinium | Frame 25 | RF RAAM HOR-883
RF RAAM HOR-217 | 1. korrus | _METALL - alumiinium | Frame 25 | RF RAAM HOR-217
RF RAAM HOR-218 | 1. korrus | _METALL - alumiinium | Frame 25 | RF RAAM HOR-218
RF RAAM HOR-219 | 1. korrus | _METALL - alumiinium | Frame 25 | RF RAAM HOR-219
RF RAAM HOR-220 | 1. korrus | _METALL - alumiinium | Frame 25 | RF RAAM HOR-220
RF RAAM HOR-223 | 1. korrus | _METALL - alumiinium | Frame 25 | RF RAAM HOR-223
RF RAAM HOR-226 | 1. korrus | _METALL - alumiinium | Frame 25 | RF RAAM HOR-226
RF RAAM HOR-227 | 1. korrus | _METALL - alumiinium | Frame 25 | RF RAAM HOR-227
RF RAAM HOR-228 | 1. korrus | _METALL - alumiinium | Frame 25 | RF RAAM HOR-228
RF RAAM HOR-229 | 1. korrus | _METALL - alumiinium | Frame 25 | RF RAAM HOR-229
RF RAAM HOR-230 | 1. korrus | _METALL - alumiinium | Frame 25 | RF RAAM HOR-230
RF RAAM HOR-231 | 1. korrus | _METALL - alumiinium | Frame 25 | RF RAAM HOR-231
RF RAAM HOR-232 | 1. korrus | _METALL - alumiinium | Frame 25 | RF RAAM HOR-232
54 x RF RAAM HOR-798 | 1. korrus | _METALL - alumiinium | Frame 25 | RF RAAM HOR-798
RF RAAM HOR-018 | 1. korrus | _METALL - alumiinium | Frame 25 | RF RAAM HOR-018
RF RAAM HOR-019 | 1. korrus | _METALL - alumiinium | Frame 25 | RF RAAM HOR-019
5 x RF RAAM HOR-404 | 1. korrus | _METALL - alumiinium | Frame 25 | RF RAAM HOR-404
2 x RF RAAM HOR-389 | 2. korrus | _GENEERILINE MATERJAL | Built-in Butt-glazed Frame | RF RAAM HOR-389
2 x RF RAAM HOR-388 | 2. korrus | _GENEERILINE MATERJAL | Built-in Butt-glazed Frame | RF RAAM HOR-388
2 x RF RAAM HOR-387 | 2. korrus | _GENEERILINE MATERJAL | Built-in Butt-glazed Frame | RF RAAM HOR-387
2 x RF RAAM HOR-386 | 2. korrus | _GENEERILINE MATERJAL | Built-in Butt-glazed Frame | RF RAAM HOR-386
2 x RF RAAM HOR-385 | 2. korrus | _GENEERILINE MATERJAL | Built-in Butt-glazed Frame | RF RAAM HOR-385

# IfcMember: Transom Frame 50 x 125 (7)
In: 1. korrus
Type - PredefinedType: MEMBER
Classification: 1.13 IfcMemberType (kandev element) (RKAS BIM + ARCHICAD Classification); Material: _METALL - alumiinium
Pset_MemberCommon - Reference: Modular Frame 25; Slope: 0 deg
AR_001-002 - 002_Tüüp: Modular Frame 25
AC_Pset_RenovationAndPhasing - Renovation Status: Undefined
Name | 001_Nimetus
RF RAAM HOR-372 | RF RAAM HOR-372
RF RAAM HOR-371 | RF RAAM HOR-371
RF RAAM HOR-370 | RF RAAM HOR-370
RF RAAM HOR-365 | RF RAAM HOR-365
RF RAAM HOR-405 | RF RAAM HOR-405
RF RAAM HOR-404 | RF RAAM HOR-404
RF RAAM HOR-400 | RF RAAM HOR-400

# IfcMember: Transom Frame 50 x 200 (49)
In: 4. TEHNO korrus
Type - PredefinedType: MEMBER
Classification: 1.13 IfcMemberType (kandev element) (RKAS BIM + ARCHICAD Classification); Material: _METALL - alumiinium
Pset_MemberCommon - Reference: Frame 25
AR_001-002 - 002_Tüüp: Frame 25
AC_Pset_RenovationAndPhasing - Renovation Status: Undefined
Name | Slope (deg) | 001_Nimetus
RF RAAM HOR-523 | 5.43395e-08 | RF RAAM HOR-523
RF RAAM HOR-526 | 6.89237e-08 | RF RAAM HOR-526
RF RAAM HOR-543 | 2.81881e-08 | RF RAAM HOR-543
RF RAAM HOR-534 | 2.81881e-08 | RF RAAM HOR-534
RF RAAM HOR-535 | 2.81881e-08 | RF RAAM HOR-535
RF RAAM HOR-538 | 2.81881e-08 | RF RAAM HOR-538
RF RAAM HOR-546 | 2.03121e-08 | RF RAAM HOR-546
RF RAAM HOR-547 | 4.92861e-08 | RF RAAM HOR-547
RF RAAM HOR-548 | 2.76808e-08 | RF RAAM HOR-548
RF RAAM HOR-549 | 2.81881e-08 | RF RAAM HOR-549
RF RAAM HOR-550 | 2.81881e-08 | RF RAAM HOR-550
RF RAAM HOR-551 | 2.81882e-08 | RF RAAM HOR-551
RF RAAM HOR-530 | 0 | RF RAAM HOR-530
RF RAAM HOR-536 | 0 | RF RAAM HOR-536
RF RAAM HOR-544 | 0 | RF RAAM HOR-544
RF RAAM HOR-545 | 0 | RF RAAM HOR-545
RF RAAM HOR-548 | 0 | RF RAAM HOR-548
RF RAAM HOR-549 | 0 | RF RAAM HOR-549
RF RAAM HOR-552 | 0 | RF RAAM HOR-552
RF RAAM HOR-554 | 0 | RF RAAM HOR-554
RF RAAM HOR-558 | 1.32861e-14 | RF RAAM HOR-558
RF RAAM HOR-562 | 0 | RF RAAM HOR-562
RF RAAM HOR-564 | 3.79044e-09 | RF RAAM HOR-564
RF RAAM HOR-565 | 2.27575e-08 | RF RAAM HOR-565
RF RAAM HOR-833 | 3.88508e-08 | RF RAAM HOR-833
RF RAAM HOR-744 | 2.81204e-11 | RF RAAM HOR-744
RF RAAM HOR-745 | 7.38879e-08 | RF RAAM HOR-745
RF RAAM HOR-749 | 1.32896e-07 | RF RAAM HOR-749
RF RAAM HOR-848 | 2.91798e-07 | RF RAAM HOR-848
RF RAAM HOR-837 | 5.52009e-08 | RF RAAM HOR-837
RF RAAM HOR-753 | 2.53075e-07 | RF RAAM HOR-753
RF RAAM HOR-756 | 2.85654e-08 | RF RAAM HOR-756
RF RAAM HOR-757 | 6.81644e-09 | RF RAAM HOR-757
RF RAAM HOR-846 | 8.50584e-08 | RF RAAM HOR-846
RF RAAM HOR-831 | 4.98441e-08 | RF RAAM HOR-831
RF RAAM HOR-834 | 1.85726e-14 | RF RAAM HOR-834
RF RAAM HOR-845 | 0.00000362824 | RF RAAM HOR-845
RF RAAM HOR-852 | 7.69985e-07 | RF RAAM HOR-852
RF RAAM HOR-853 | 0 | RF RAAM HOR-853
RF RAAM HOR-028 | 0 | RF RAAM HOR-028
RF RAAM HOR-029 | 0 | RF RAAM HOR-029
RF RAAM HOR-030 | 0 | RF RAAM HOR-030
RF RAAM HOR-031 | 0 | RF RAAM HOR-031
RF RAAM HOR-033 | 0 | RF RAAM HOR-033
RF RAAM HOR-034 | 0 | RF RAAM HOR-034
RF RAAM HOR-035 | 0 | RF RAAM HOR-035
RF RAAM HOR-036 | 0 | RF RAAM HOR-036
RF RAAM HOR-150 | 0 | RF RAAM HOR-150
RF RAAM HOR-151 | 0 | RF RAAM HOR-151

# IfcMember: Transom Frame 60 x 100 (23)
In: 1. korrus
Type - PredefinedType: MEMBER
Classification: 1.13 IfcMemberType (kandev element) (RKAS BIM + ARCHICAD Classification); Material: _GENEERILINE MATERJAL
Pset_MemberCommon - Reference: Built-in Butt-glazed Frame; Slope: 0 deg
AR_001-002 - 002_Tüüp: Built-in Butt-glazed Frame
AC_Pset_RenovationAndPhasing - Renovation Status: Undefined
Name | 001_Nimetus
RF RAAM HOR-389 | RF RAAM HOR-389
RF RAAM HOR-388 | RF RAAM HOR-388
RF RAAM HOR-387 | RF RAAM HOR-387
RF RAAM HOR-386 | RF RAAM HOR-386
RF RAAM HOR-385 | RF RAAM HOR-385
RF RAAM HOR-384 | RF RAAM HOR-384
RF RAAM HOR-383 | RF RAAM HOR-383
RF RAAM HOR-382 | RF RAAM HOR-382
RF RAAM HOR-381 | RF RAAM HOR-381
RF RAAM HOR-436 | RF RAAM HOR-436
RF RAAM HOR-435 | RF RAAM HOR-435
RF RAAM HOR-434 | RF RAAM HOR-434
RF RAAM HOR-472 | RF RAAM HOR-472
RF RAAM HOR-471 | RF RAAM HOR-471
RF RAAM HOR-470 | RF RAAM HOR-470
RF RAAM HOR-467 | RF RAAM HOR-467
RF RAAM HOR-469 | RF RAAM HOR-469
RF RAAM HOR-464 | RF RAAM HOR-464
RF RAAM HOR-562 | RF RAAM HOR-562
RF RAAM HOR-433 | RF RAAM HOR-433
RF RAAM HOR-432 | RF RAAM HOR-432
RF RAAM HOR-431 | RF RAAM HOR-431
RF RAAM HOR-463 | RF RAAM HOR-463

# IfcMember: Transom Frame 60 x 120 (273)
In: 1. korrus
Type - PredefinedType: MEMBER
Classification: 1.13 IfcMemberType (kandev element) (RKAS BIM + ARCHICAD Classification); Material: _KANDETARIND - liimpuit vastavalt EK osale
Pset_MemberCommon - Reference: Built-in Butt-glazed Frame; Slope: 0 deg
AR_001-002 - 002_Tüüp: Built-in Butt-glazed Frame
AC_Pset_RenovationAndPhasing - Renovation Status: Undefined
Name | 001_Nimetus
RF RAAM HOR-217 | RF RAAM HOR-217
RF RAAM HOR-218 | RF RAAM HOR-218
RF RAAM HOR-219 | RF RAAM HOR-219
RF RAAM HOR-220 | RF RAAM HOR-220
RF RAAM HOR-223 | RF RAAM HOR-223
RF RAAM HOR-226 | RF RAAM HOR-226
RF RAAM HOR-227 | RF RAAM HOR-227
RF RAAM HOR-228 | RF RAAM HOR-228
RF RAAM HOR-229 | RF RAAM HOR-229
RF RAAM HOR-232 | RF RAAM HOR-232
RF RAAM HOR-329 | RF RAAM HOR-329
RF RAAM HOR-330 | RF RAAM HOR-330
RF RAAM HOR-364 | RF RAAM HOR-364
RF RAAM HOR-294 | RF RAAM HOR-294
RF RAAM HOR-363 | RF RAAM HOR-363
RF RAAM HOR-298 | RF RAAM HOR-298
RF RAAM HOR-299 | RF RAAM HOR-299
RF RAAM HOR-452 | RF RAAM HOR-452
RF RAAM HOR-453 | RF RAAM HOR-453
RF RAAM HOR-454 | RF RAAM HOR-454
RF RAAM HOR-455 | RF RAAM HOR-455
RF RAAM HOR-456 | RF RAAM HOR-456
RF RAAM HOR-457 | RF RAAM HOR-457
RF RAAM HOR-458 | RF RAAM HOR-458
RF RAAM HOR-459 | RF RAAM HOR-459
RF RAAM HOR-460 | RF RAAM HOR-460
RF RAAM HOR-461 | RF RAAM HOR-461
RF RAAM HOR-462 | RF RAAM HOR-462
RF RAAM HOR-463 | RF RAAM HOR-463
RF RAAM HOR-464 | RF RAAM HOR-464
RF RAAM HOR-465 | RF RAAM HOR-465
RF RAAM HOR-466 | RF RAAM HOR-466
RF RAAM HOR-467 | RF RAAM HOR-467
RF RAAM HOR-475 | RF RAAM HOR-475
RF RAAM HOR-476 | RF RAAM HOR-476
RF RAAM HOR-477 | RF RAAM HOR-477
RF RAAM HOR-478 | RF RAAM HOR-478
RF RAAM HOR-479 | RF RAAM HOR-479
RF RAAM HOR-480 | RF RAAM HOR-480
RF RAAM HOR-481 | RF RAAM HOR-481
RF RAAM HOR-482 | RF RAAM HOR-482
RF RAAM HOR-483 | RF RAAM HOR-483
RF RAAM HOR-484 | RF RAAM HOR-484
RF RAAM HOR-485 | RF RAAM HOR-485
RF RAAM HOR-486 | RF RAAM HOR-486
RF RAAM HOR-487 | RF RAAM HOR-487
RF RAAM HOR-488 | RF RAAM HOR-488
RF RAAM HOR-489 | RF RAAM HOR-489
RF RAAM HOR-490 | RF RAAM HOR-490
RF RAAM HOR-496 | RF RAAM HOR-496
RF RAAM HOR-497 | RF RAAM HOR-497
RF RAAM HOR-498 | RF RAAM HOR-498
RF RAAM HOR-499 | RF RAAM HOR-499
RF RAAM HOR-500 | RF RAAM HOR-500
RF RAAM HOR-501 | RF RAAM HOR-501
RF RAAM HOR-502 | RF RAAM HOR-502
RF RAAM HOR-503 | RF RAAM HOR-503
RF RAAM HOR-504 | RF RAAM HOR-504
RF RAAM HOR-505 | RF RAAM HOR-505
RF RAAM HOR-506 | RF RAAM HOR-506
RF RAAM HOR-507 | RF RAAM HOR-507
RF RAAM HOR-508 | RF RAAM HOR-508
RF RAAM HOR-509 | RF RAAM HOR-509
RF RAAM HOR-510 | RF RAAM HOR-510
RF RAAM HOR-511 | RF RAAM HOR-511
RF RAAM HOR-512 | RF RAAM HOR-512
RF RAAM HOR-513 | RF RAAM HOR-513
RF RAAM HOR-514 | RF RAAM HOR-514
RF RAAM HOR-515 | RF RAAM HOR-515
124 x RF RAAM HOR-648 | RF RAAM HOR-648
RF RAAM HOR-783 | RF RAAM HOR-783
RF RAAM HOR-784 | RF RAAM HOR-784
RF RAAM HOR-835 | RF RAAM HOR-835
RF RAAM HOR-836 | RF RAAM HOR-836
69 x RF RAAM HOR-249 | RF RAAM HOR-249
RF RAAM HOR-808 | RF RAAM HOR-808
RF RAAM HOR-738 | RF RAAM HOR-738
RF RAAM HOR-739 | RF RAAM HOR-739
RF RAAM HOR-740 | RF RAAM HOR-740
RF RAAM HOR-741 | RF RAAM HOR-741
RF RAAM HOR-742 | RF RAAM HOR-742
RF RAAM HOR-810 | RF RAAM HOR-810

# IfcOpeningElement: OPENING (45)
Classification: 1.14 IfcOpeningElement (avaelement) (RKAS BIM + ARCHICAD Classification)
AC_Pset_RenovationAndPhasing - Renovation Status: New
Name | In | Reference = 002_Tüüp | 001_Nimetus
4 x Tulekustuti nišš vastavalt SA osale | 1. korrus | Tulekustuti nišš vastavalt SA osale: 1 320x250 | Tulekustuti nišš vastavalt SA osale
2 x Tulekustuti nišš vastavalt SA osale | 1. korrus | Tulekustuti nišš vastavalt SA osale: 1 300x400 | Tulekustuti nišš vastavalt SA osale
2 x Tulekustuti nišš vastavalt SA osale | 1. korrus | Tulekustuti nišš vastavalt SA osale: 900x900 | Tulekustuti nišš vastavalt SA osale
Tulekustuti nišš vastavalt SA osale | 1. korrus | Tulekustuti nišš vastavalt SA osale: 1 200x1 000 | Tulekustuti nišš vastavalt SA osale
6 x Tulekustuti nišš vastavalt SA osale | 2. korrus | Tulekustuti nišš vastavalt SA osale: 1 320x250 | Tulekustuti nišš vastavalt SA osale
2 x Küttekollektori nišš, luuk vastavalt SA osale | 2. korrus | Küttekollektori nišš, luuk vastavalt SA osale: 900x900 | Küttekollektori nišš, luuk vastavalt SA osale
Šaht | 2. korrus | Šaht: 1 801x2 100 | Šaht
Šaht | 2. korrus | Šaht: 2 299x2 100 | Šaht
Õhuruum | 2. korrus | Õhuruum: 6 390x4 900 | Õhuruum
Šaht | 2. korrus | Šaht: 609x500 | Šaht
Šaht | 2. korrus | Šaht: 815x550 | Šaht
Šaht | 2. korrus | Šaht: 2 796x2 530 | Šaht
Šaht | 2. korrus | Šaht: 605x500 | Šaht
Šaht | 2. korrus | Šaht: 500x700 | Šaht
2 x Tulekustuti nišš vastavalt SA osale | 2. korrus | Tulekustuti nišš vastavalt SA osale: 900x900 | Tulekustuti nišš vastavalt SA osale
Tulekustuti nišš vastavalt SA osale | 2. korrus | Tulekustuti nišš vastavalt SA osale: 980x220 | Tulekustuti nišš vastavalt SA osale
Šaht | 3. korrus | Šaht: 655x2 530 | Šaht
Šaht | 3. korrus | Šaht: 1 840x5 580 | Šaht
Õhuruum | 3. korrus | Õhuruum: 6 490x4 620 | Õhuruum
3 x Šaht | 3. korrus | Šaht: 500x700 | Šaht
6 x Tulekustuti nišš vastavalt SA osale | 3. korrus | Tulekustuti nišš vastavalt SA osale: 1 320x250 | Tulekustuti nišš vastavalt SA osale
2 x Küttekollektori nišš, luuk vastavalt SA osale | 3. korrus | Küttekollektori nišš, luuk vastavalt SA osale: 900x900 | Küttekollektori nišš, luuk vastavalt SA osale
Ava | 3. korrus | Ava: 205x205 | Ava
2 x Tulekustuti nišš vastavalt SA osale | 3. korrus | Tulekustuti nišš vastavalt SA osale: 900x900 | Tulekustuti nišš vastavalt SA osale

# IfcPlate: Distinct Panel 1000 x 2240 x 20 (2)
In: 2. korrus
Classification: 1.15 IfcPlateType (plaat) (RKAS BIM + ARCHICAD Classification); Material: _GENEERILINE MATERJAL KLAAS
Pset_PlateCommon - Reference: Built-in CW Panel
AR_001-002 - 001_Nimetus: RF PANEEL ERI-026; 002_Tüüp: Built-in CW Panel
AC_Pset_RenovationAndPhasing - Renovation Status: Undefined

# IfcPlate: Distinct Panel 1005 x 2240 x 20 (2)
In: 2. korrus
Classification: 1.15 IfcPlateType (plaat) (RKAS BIM + ARCHICAD Classification); Material: _GENEERILINE MATERJAL KLAAS
Pset_PlateCommon - Reference: Built-in CW Panel
AR_001-002 - 001_Nimetus: RF PANEEL ERI-016; 002_Tüüp: Built-in CW Panel
AC_Pset_RenovationAndPhasing - Renovation Status: Undefined

# IfcPlate: Distinct Panel 1010 x 2240 x 20 (2)
In: 1. korrus
Classification: 1.15 IfcPlateType (plaat) (RKAS BIM + ARCHICAD Classification); Material: _GENEERILINE MATERJAL KLAAS
Pset_PlateCommon - Reference: Built-in CW Panel
AR_001-002 - 001_Nimetus: RF PANEEL ERI-029; 002_Tüüp: Built-in CW Panel
AC_Pset_RenovationAndPhasing - Renovation Status: Undefined

# IfcPlate: Distinct Panel 1015 x 2265 x 20, RF PANEEL ERI-022
In: 1. korrus
Classification: 1.15 IfcPlateType (plaat) (RKAS BIM + ARCHICAD Classification); Material: _GENEERILINE MATERJAL KLAAS
Pset_PlateCommon - Reference: Built-in CW Panel
AR_001-002 - 001_Nimetus: RF PANEEL ERI-022; 002_Tüüp: Built-in CW Panel
AC_Pset_RenovationAndPhasing - Renovation Status: Undefined

# IfcPlate: Distinct Panel 1030 x 2240 x 20 (6)
In: 2. korrus
Classification: 1.15 IfcPlateType (plaat) (RKAS BIM + ARCHICAD Classification); Material: _GENEERILINE MATERJAL KLAAS
Pset_PlateCommon - Reference: Built-in CW Panel
AR_001-002 - 002_Tüüp: Built-in CW Panel
AC_Pset_RenovationAndPhasing - Renovation Status: Undefined
Name | 001_Nimetus
2 x Siseuks | Siseuks
2 x RF PANEEL ERI-018 | RF PANEEL ERI-018
2 x RF PANEEL ERI-019 | RF PANEEL ERI-019

# IfcPlate: Distinct Panel 1035 x 2240 x 20 (4)
In: 1. korrus
Classification: 1.15 IfcPlateType (plaat) (RKAS BIM + ARCHICAD Classification); Material: _GENEERILINE MATERJAL KLAAS
Pset_PlateCommon - Reference: Built-in CW Panel
AR_001-002 - 002_Tüüp: Built-in CW Panel
AC_Pset_RenovationAndPhasing - Renovation Status: Undefined
Name | 001_Nimetus
2 x RF PANEEL ERI-026 | RF PANEEL ERI-026
2 x RF PANEEL ERI-027 | RF PANEEL ERI-027

# IfcPlate: Distinct Panel 1040 x 2265 x 20, RF PANEEL ERI-024
In: 1. korrus
Classification: 1.15 IfcPlateType (plaat) (RKAS BIM + ARCHICAD Classification); Material: _GENEERILINE MATERJAL KLAAS
Pset_PlateCommon - Reference: Built-in CW Panel
AR_001-002 - 001_Nimetus: RF PANEEL ERI-024; 002_Tüüp: Built-in CW Panel
AC_Pset_RenovationAndPhasing - Renovation Status: Undefined

# IfcPlate: Distinct Panel 1050 x 2240 x 20 (4)
In: 2. korrus
Classification: 1.15 IfcPlateType (plaat) (RKAS BIM + ARCHICAD Classification); Material: _GENEERILINE MATERJAL KLAAS
Pset_PlateCommon - Reference: Built-in CW Panel
AR_001-002 - 002_Tüüp: Built-in CW Panel
AC_Pset_RenovationAndPhasing - Renovation Status: Undefined
Name | 001_Nimetus
2 x RF PANEEL ERI-016 | RF PANEEL ERI-016
2 x RF PANEEL ERI-027 | RF PANEEL ERI-027

# IfcPlate: Distinct Panel 1075 x 145 x 20 (2)
In: 2. korrus
Classification: 1.15 IfcPlateType (plaat) (RKAS BIM + ARCHICAD Classification); Material: _GENEERILINE MATERJAL KLAAS
Pset_PlateCommon - Reference: Built-in CW Panel
AR_001-002 - 001_Nimetus: RF PANEEL ERI-043; 002_Tüüp: Built-in CW Panel
AC_Pset_RenovationAndPhasing - Renovation Status: Undefined

# IfcPlate: Distinct Panel 1075 x 2240 x 20 (9)
In: 2. korrus
Classification: 1.15 IfcPlateType (plaat) (RKAS BIM + ARCHICAD Classification); Material: _GENEERILINE MATERJAL KLAAS
Pset_PlateCommon - Reference: Built-in CW Panel
AR_001-002 - 002_Tüüp: Built-in CW Panel
AC_Pset_RenovationAndPhasing - Renovation Status: Undefined
Name | 001_Nimetus
2 x Siseuks | Siseuks
2 x RF PANEEL ERI-018 | RF PANEEL ERI-018
4 x RF PANEEL ERI-019 | RF PANEEL ERI-019
RF PANEEL ERI-034 | RF PANEEL ERI-034

# IfcPlate: Distinct Panel 1075 x 2265 x 20 (2)
In: 2. korrus
Classification: 1.15 IfcPlateType (plaat) (RKAS BIM + ARCHICAD Classification); Material: _GENEERILINE MATERJAL KLAAS
Pset_PlateCommon - Reference: Built-in CW Panel
AR_001-002 - 001_Nimetus: RF PANEEL ERI-037; 002_Tüüp: Built-in CW Panel
AC_Pset_RenovationAndPhasing - Renovation Status: Undefined

# IfcPlate: Distinct Panel 1100 x 145 x 20 (6)
In: 2. korrus
Classification: 1.15 IfcPlateType (plaat) (RKAS BIM + ARCHICAD Classification); Material: _GENEERILINE MATERJAL KLAAS
Pset_PlateCommon - Reference: Built-in CW Panel
AR_001-002 - 002_Tüüp: Built-in CW Panel
AC_Pset_RenovationAndPhasing - Renovation Status: Undefined
Name | 001_Nimetus
2 x RF PANEEL ERI-044 | RF PANEEL ERI-044
2 x RF PANEEL ERI-045 | RF PANEEL ERI-045
2 x RF PANEEL ERI-046 | RF PANEEL ERI-046

# IfcPlate: Distinct Panel 1100 x 2240 x 20 (14)
In: 2. korrus
Classification: 1.15 IfcPlateType (plaat) (RKAS BIM + ARCHICAD Classification); Material: _GENEERILINE MATERJAL KLAAS
Pset_PlateCommon - Reference: Built-in CW Panel
AR_001-002 - 002_Tüüp: Built-in CW Panel
AC_Pset_RenovationAndPhasing - Renovation Status: Undefined
Name | 001_Nimetus
2 x RF PANEEL ERI-020 | RF PANEEL ERI-020
2 x RF PANEEL ERI-021 | RF PANEEL ERI-021
2 x RF PANEEL ERI-022 | RF PANEEL ERI-022
2 x RF PANEEL ERI-023 | RF PANEEL ERI-023
2 x RF PANEEL ERI-027 | RF PANEEL ERI-027
RF PANEEL ERI-031 | RF PANEEL ERI-031
RF PANEEL ERI-030 | RF PANEEL ERI-030
RF PANEEL ERI-032 | RF PANEEL ERI-032
RF PANEEL ERI-036 | RF PANEEL ERI-036

# IfcPlate: Distinct Panel 1100 x 2265 x 20 (6)
In: 2. korrus
Classification: 1.15 IfcPlateType (plaat) (RKAS BIM + ARCHICAD Classification); Material: _GENEERILINE MATERJAL KLAAS
Pset_PlateCommon - Reference: Built-in CW Panel
AR_001-002 - 002_Tüüp: Built-in CW Panel
AC_Pset_RenovationAndPhasing - Renovation Status: Undefined
Name | 001_Nimetus
2 x RF PANEEL ERI-038 | RF PANEEL ERI-038
2 x RF PANEEL ERI-039 | RF PANEEL ERI-039
2 x RF PANEEL ERI-040 | RF PANEEL ERI-040

# IfcPlate: Distinct Panel 1136 x 2240 x 20, RF PANEEL ERI-025
In: 2. korrus
Classification: 1.15 IfcPlateType (plaat) (RKAS BIM + ARCHICAD Classification); Material: _GENEERILINE MATERJAL KLAAS
Pset_PlateCommon - Reference: Built-in CW Panel
AR_001-002 - 001_Nimetus: RF PANEEL ERI-025; 002_Tüüp: Built-in CW Panel
AC_Pset_RenovationAndPhasing - Renovation Status: Undefined

# IfcPlate: Distinct Panel 1266 x 1444 x 58, RF PANEEL ERI-205
In: 4. TEHNO korrus
Classification: 1.15 IfcPlateType (plaat) (RKAS BIM + ARCHICAD Classification); Material: _KLAAS - kirgas
Pset_PlateCommon - Reference: Built-in CW Panel
AR_001-002 - 001_Nimetus: RF PANEEL ERI-205; 002_Tüüp: Built-in CW Panel
AC_Pset_RenovationAndPhasing - Renovation Status: Undefined

# IfcPlate: Distinct Panel 1266 x 1445 x 58, RF PANEEL ERI-209
In: 4. TEHNO korrus
Classification: 1.15 IfcPlateType (plaat) (RKAS BIM + ARCHICAD Classification); Material: _KLAAS - kirgas
Pset_PlateCommon - Reference: Built-in CW Panel
AR_001-002 - 001_Nimetus: RF PANEEL ERI-209; 002_Tüüp: Built-in CW Panel
AC_Pset_RenovationAndPhasing - Renovation Status: Undefined

# IfcPlate: Distinct Panel 1266 x 1470 x 58, RF PANEEL ERI-207
In: 4. TEHNO korrus
Classification: 1.15 IfcPlateType (plaat) (RKAS BIM + ARCHICAD Classification); Material: _KLAAS - kirgas
Pset_PlateCommon - Reference: Built-in CW Panel
AR_001-002 - 001_Nimetus: RF PANEEL ERI-207; 002_Tüüp: Built-in CW Panel
AC_Pset_RenovationAndPhasing - Renovation Status: Undefined

# IfcPlate: Distinct Panel 1270 x 1444 x 58, RF PANEEL ERI-206
In: 4. TEHNO korrus
Classification: 1.15 IfcPlateType (plaat) (RKAS BIM + ARCHICAD Classification); Material: _KLAAS - kirgas
Pset_PlateCommon - Reference: Built-in CW Panel
AR_001-002 - 001_Nimetus: RF PANEEL ERI-206; 002_Tüüp: Built-in CW Panel
AC_Pset_RenovationAndPhasing - Renovation Status: Undefined

# IfcPlate: Distinct Panel 1295 x 1444 x 58 (3)
In: 4. TEHNO korrus
Classification: 1.15 IfcPlateType (plaat) (RKAS BIM + ARCHICAD Classification); Material: _KLAAS - kirgas
Pset_PlateCommon - Reference: Built-in CW Panel
AR_001-002 - 002_Tüüp: Built-in CW Panel
AC_Pset_RenovationAndPhasing - Renovation Status: Undefined
Name | 001_Nimetus
RF PANEEL ERI-211 | RF PANEEL ERI-211
RF PANEEL ERI-208 | RF PANEEL ERI-208
RF PANEEL ERI-210 | RF PANEEL ERI-210

# IfcPlate: Distinct Panel 1317 x 2240 x 20, RF PANEEL ERI-025
In: 2. korrus
Classification: 1.15 IfcPlateType (plaat) (RKAS BIM + ARCHICAD Classification); Material: _GENEERILINE MATERJAL KLAAS
Pset_PlateCommon - Reference: Built-in CW Panel
AR_001-002 - 001_Nimetus: RF PANEEL ERI-025; 002_Tüüp: Built-in CW Panel
AC_Pset_RenovationAndPhasing - Renovation Status: Undefined

# IfcPlate: Distinct Panel 20 x 20 x 20 (39)
Classification: 1.15 IfcPlateType (plaat) (RKAS BIM + ARCHICAD Classification); Material: _GENEERILINE MATERJAL KLAAS
Pset_PlateCommon - Reference: Built-in CW Panel
AR_001-002 - 002_Tüüp: Built-in CW Panel
AC_Pset_RenovationAndPhasing - Renovation Status: Undefined
Name | In | 001_Nimetus
2 x RF PANEEL ERI-049 | 1. korrus | RF PANEEL ERI-049
RF PANEEL ERI-050 | 1. korrus | RF PANEEL ERI-050
RF PANEEL ERI-051 | 1. korrus | RF PANEEL ERI-051
2 x RF PANEEL ERI-060 | 1. korrus | RF PANEEL ERI-060
RF PANEEL ERI-061 | 1. korrus | RF PANEEL ERI-061
RF PANEEL ERI-064 | 1. korrus | RF PANEEL ERI-064
Klaasseina uks | 2. korrus | Klaasseina uks
5 x RF PANEEL ERI-023 | 2. korrus | RF PANEEL ERI-023
RF PANEEL ERI-040 | 2. korrus | RF PANEEL ERI-040
RF PANEEL ERI-024 | 2. korrus | RF PANEEL ERI-024
RF PANEEL ERI-025 | 2. korrus | RF PANEEL ERI-025
RF PANEEL ERI-027 | 2. korrus | RF PANEEL ERI-027
RF PANEEL ERI-049 | 2. korrus | RF PANEEL ERI-049
2 x RF PANEEL ERI-051 | 2. korrus | RF PANEEL ERI-051
RF PANEEL ERI-060 | 2. korrus | RF PANEEL ERI-060
RF PANEEL ERI-059 | 2. korrus | RF PANEEL ERI-059
RF PANEEL ERI-061 | 2. korrus | RF PANEEL ERI-061
RF PANEEL ERI-054 | 2. korrus | RF PANEEL ERI-054
RF PANEEL ERI-053 | 2. korrus | RF PANEEL ERI-053
5 x RF PANEEL ERI-023 | 3. korrus | RF PANEEL ERI-023
RF PANEEL ERI-024 | 3. korrus | RF PANEEL ERI-024
RF PANEEL ERI-060 | 3. korrus | RF PANEEL ERI-060
RF PANEEL ERI-061 | 3. korrus | RF PANEEL ERI-061
RF PANEEL ERI-059 | 3. korrus | RF PANEEL ERI-059
RF PANEEL ERI-051 | 3. korrus | RF PANEEL ERI-051
RF PANEEL ERI-053 | 3. korrus | RF PANEEL ERI-053
2 x Klaasseina uks | 3. korrus | Klaasseina uks

# IfcPlate: Distinct Panel 20 x 2100 x 20, RF PANEEL ERI-058
In: 1. korrus
Classification: 1.15 IfcPlateType (plaat) (RKAS BIM + ARCHICAD Classification); Material: _GENEERILINE MATERJAL KLAAS
Pset_PlateCommon - Reference: Built-in CW Panel
AR_001-002 - 001_Nimetus: RF PANEEL ERI-058; 002_Tüüp: Built-in CW Panel
AC_Pset_RenovationAndPhasing - Renovation Status: Undefined

# IfcPlate: Distinct Panel 20 x 2300 x 20 (16)
Classification: 1.15 IfcPlateType (plaat) (RKAS BIM + ARCHICAD Classification); Material: _GENEERILINE MATERJAL KLAAS
Pset_PlateCommon - Reference: Built-in CW Panel
AR_001-002 - 002_Tüüp: Built-in CW Panel
AC_Pset_RenovationAndPhasing - Renovation Status: Undefined
Name | In | 001_Nimetus
RF PANEEL ERI-046 | 1. korrus | RF PANEEL ERI-046
RF PANEEL ERI-045 | 1. korrus | RF PANEEL ERI-045
RF PANEEL ERI-051 | 1. korrus | RF PANEEL ERI-051
2 x RF PANEEL ERI-023 | 2. korrus | RF PANEEL ERI-023
RF PANEEL ERI-042 | 2. korrus | RF PANEEL ERI-042
RF PANEEL ERI-028 | 2. korrus | RF PANEEL ERI-028
RF PANEEL ERI-052 | 2. korrus | RF PANEEL ERI-052
2 x Klaasseina uks | 2. korrus | Klaasseina uks
3 x RF PANEEL ERI-023 | 3. korrus | RF PANEEL ERI-023
RF PANEEL ERI-025 | 3. korrus | RF PANEEL ERI-025
Siseuks | 3. korrus | Siseuks
RF PANEEL ERI-059 | 3. korrus | RF PANEEL ERI-059

# IfcPlate: Distinct Panel 20 x 5 x 20 (5)
In: 1. korrus
Classification: 1.15 IfcPlateType (plaat) (RKAS BIM + ARCHICAD Classification); Material: _GENEERILINE MATERJAL KLAAS
Pset_PlateCommon - Reference: Built-in CW Panel
AR_001-002 - 002_Tüüp: Built-in CW Panel
AC_Pset_RenovationAndPhasing - Renovation Status: Undefined
Name | 001_Nimetus
RF PANEEL ERI-040 | RF PANEEL ERI-040
RF PANEEL ERI-042 | RF PANEEL ERI-042
2 x RF PANEEL ERI-052 | RF PANEEL ERI-052
RF PANEEL ERI-053 | RF PANEEL ERI-053

# IfcPlate: Distinct Panel 20 x 500 x 20, RF PANEEL ERI-047
In: 1. korrus
Classification: 1.15 IfcPlateType (plaat) (RKAS BIM + ARCHICAD Classification); Material: _GENEERILINE MATERJAL KLAAS
Pset_PlateCommon - Reference: Built-in CW Panel
AR_001-002 - 001_Nimetus: RF PANEEL ERI-047; 002_Tüüp: Built-in CW Panel
AC_Pset_RenovationAndPhasing - Renovation Status: Undefined

# IfcPlate: Distinct Panel 20 x 990 x 20 (3)
In: 1. korrus
Classification: 1.15 IfcPlateType (plaat) (RKAS BIM + ARCHICAD Classification); Material: _GENEERILINE MATERJAL KLAAS
Pset_PlateCommon - Reference: Built-in CW Panel
AR_001-002 - 002_Tüüp: Built-in CW Panel
AC_Pset_RenovationAndPhasing - Renovation Status: Undefined
Name | 001_Nimetus
2 x RF PANEEL ERI-058 | RF PANEEL ERI-058
RF PANEEL ERI-060 | RF PANEEL ERI-060

# IfcPlate: Distinct Panel 264 x 2240 x 20 (2)
In: 2. korrus
Classification: 1.15 IfcPlateType (plaat) (RKAS BIM + ARCHICAD Classification); Material: _GENEERILINE MATERJAL KLAAS
Pset_PlateCommon - Reference: Built-in CW Panel
AR_001-002 - 001_Nimetus: RF PANEEL ERI-025; 002_Tüüp: Built-in CW Panel
AC_Pset_RenovationAndPhasing - Renovation Status: Undefined

# IfcPlate: Distinct Panel 545 x 2240 x 20, RF PANEEL ERI-036
In: 1. korrus
Classification: 1.15 IfcPlateType (plaat) (RKAS BIM + ARCHICAD Classification); Material: _GENEERILINE MATERJAL KLAAS
Pset_PlateCommon - Reference: Built-in CW Panel
AR_001-002 - 001_Nimetus: RF PANEEL ERI-036; 002_Tüüp: Built-in CW Panel
AC_Pset_RenovationAndPhasing - Renovation Status: Undefined

# IfcPlate: Distinct Panel 725 x 2240 x 20, RF PANEEL ERI-029
In: 1. korrus
Classification: 1.15 IfcPlateType (plaat) (RKAS BIM + ARCHICAD Classification); Material: _GENEERILINE MATERJAL KLAAS
Pset_PlateCommon - Reference: Built-in CW Panel
AR_001-002 - 001_Nimetus: RF PANEEL ERI-029; 002_Tüüp: Built-in CW Panel
AC_Pset_RenovationAndPhasing - Renovation Status: Undefined

# IfcPlate: Distinct Panel 865 x 2240 x 20, RF PANEEL ERI-041
In: 2. korrus
Classification: 1.15 IfcPlateType (plaat) (RKAS BIM + ARCHICAD Classification); Material: _GENEERILINE MATERJAL KLAAS
Pset_PlateCommon - Reference: Built-in CW Panel
AR_001-002 - 001_Nimetus: RF PANEEL ERI-041; 002_Tüüp: Built-in CW Panel
AC_Pset_RenovationAndPhasing - Renovation Status: Undefined

# IfcPlate: Distinct Panel 890 x 2240 x 20, RF PANEEL ERI-042
In: 2. korrus
Classification: 1.15 IfcPlateType (plaat) (RKAS BIM + ARCHICAD Classification); Material: _GENEERILINE MATERJAL KLAAS
Pset_PlateCommon - Reference: Built-in CW Panel
AR_001-002 - 001_Nimetus: RF PANEEL ERI-042; 002_Tüüp: Built-in CW Panel
AC_Pset_RenovationAndPhasing - Renovation Status: Undefined

# IfcPlate: Distinct Panel 895 x 2240 x 20, RF PANEEL ERI-052
In: 2. korrus
Classification: 1.15 IfcPlateType (plaat) (RKAS BIM + ARCHICAD Classification); Material: _GENEERILINE MATERJAL KLAAS
Pset_PlateCommon - Reference: Built-in CW Panel
AR_001-002 - 001_Nimetus: RF PANEEL ERI-052; 002_Tüüp: Built-in CW Panel
AC_Pset_RenovationAndPhasing - Renovation Status: Undefined

# IfcPlate: Distinct Panel 935 x 145 x 20 (2)
In: 2. korrus
Classification: 1.15 IfcPlateType (plaat) (RKAS BIM + ARCHICAD Classification); Material: _GENEERILINE MATERJAL KLAAS
Pset_PlateCommon - Reference: Built-in CW Panel
AR_001-002 - 001_Nimetus: RF PANEEL ERI-042; 002_Tüüp: Built-in CW Panel
AC_Pset_RenovationAndPhasing - Renovation Status: Undefined

# IfcPlate: Distinct Panel 935 x 2265 x 20 (2)
In: 2. korrus
Classification: 1.15 IfcPlateType (plaat) (RKAS BIM + ARCHICAD Classification); Material: _GENEERILINE MATERJAL KLAAS
Pset_PlateCommon - Reference: Built-in CW Panel
AR_001-002 - 001_Nimetus: RF PANEEL ERI-041; 002_Tüüp: Built-in CW Panel
AC_Pset_RenovationAndPhasing - Renovation Status: Undefined

# IfcPlate: Distinct Panel 940 x 2240 x 20 (4)
In: 1. korrus
Classification: 1.15 IfcPlateType (plaat) (RKAS BIM + ARCHICAD Classification); Material: _GENEERILINE MATERJAL KLAAS
Pset_PlateCommon - Reference: Built-in CW Panel
AR_001-002 - 002_Tüüp: Built-in CW Panel
AC_Pset_RenovationAndPhasing - Renovation Status: Undefined
Name | 001_Nimetus
RF PANEEL ERI-030 | RF PANEEL ERI-030
RF PANEEL ERI-031 | RF PANEEL ERI-031
RF PANEEL ERI-034 | RF PANEEL ERI-034
RF PANEEL ERI-035 | RF PANEEL ERI-035

# IfcPlate: Distinct Panel 999 x 2240 x 20 (2)
In: 1. korrus
Classification: 1.15 IfcPlateType (plaat) (RKAS BIM + ARCHICAD Classification); Material: _GENEERILINE MATERJAL KLAAS
Pset_PlateCommon - Reference: Built-in CW Panel
AR_001-002 - 001_Nimetus: RF PANEEL ERI-025; 002_Tüüp: Built-in CW Panel
AC_Pset_RenovationAndPhasing - Renovation Status: Undefined

# IfcPlate: Main Panel 10 x 1822 x 58, RF PANEEL PEAMINE-926
In: 4. TEHNO korrus
Classification: 1.15 IfcPlateType (plaat) (RKAS BIM + ARCHICAD Classification); Material: _KLAAS - kirgas
Pset_PlateCommon - Reference: Built-in CW Panel
AR_001-002 - 001_Nimetus: RF PANEEL PEAMINE-926; 002_Tüüp: Built-in CW Panel
AC_Pset_RenovationAndPhasing - Renovation Status: Undefined

# IfcPlate: Main Panel 10 x 5 x 58 (3)
In: 4. TEHNO korrus
Classification: 1.15 IfcPlateType (plaat) (RKAS BIM + ARCHICAD Classification); Material: _KLAAS - kirgas
Pset_PlateCommon - Reference: Built-in CW Panel
AR_001-002 - 002_Tüüp: Built-in CW Panel
AC_Pset_RenovationAndPhasing - Renovation Status: Undefined
Name | 001_Nimetus
RF PANEEL PEAMINE-912 | RF PANEEL PEAMINE-912
RF PANEEL PEAMINE-916 | RF PANEEL PEAMINE-916
RF PANEEL PEAMINE-906 | RF PANEEL PEAMINE-906

# IfcPlate: Main Panel 1004 x 2240 x 20, RF PANEEL PEAMINE-067
In: 1. korrus
Classification: 1.15 IfcPlateType (plaat) (RKAS BIM + ARCHICAD Classification); Material: _GENEERILINE MATERJAL KLAAS
Pset_PlateCommon - Reference: Built-in CW Panel
AR_001-002 - 001_Nimetus: RF PANEEL PEAMINE-067; 002_Tüüp: Built-in CW Panel
AC_Pset_RenovationAndPhasing - Renovation Status: Undefined

# IfcPlate: Main Panel 1015 x 865 x 20, RF PANEEL PEAMINE-053
In: 1. korrus
Classification: 1.15 IfcPlateType (plaat) (RKAS BIM + ARCHICAD Classification); Material: _GENEERILINE MATERJAL KLAAS
Pset_PlateCommon - Reference: Built-in CW Panel
AR_001-002 - 001_Nimetus: RF PANEEL PEAMINE-053; 002_Tüüp: Built-in CW Panel
AC_Pset_RenovationAndPhasing - Renovation Status: Undefined

# IfcPlate: Main Panel 1040 x 865 x 20 (2)
In: 1. korrus
Classification: 1.15 IfcPlateType (plaat) (RKAS BIM + ARCHICAD Classification); Material: _GENEERILINE MATERJAL KLAAS
Pset_PlateCommon - Reference: Built-in CW Panel
AR_001-002 - 002_Tüüp: Built-in CW Panel
AC_Pset_RenovationAndPhasing - Renovation Status: Undefined
Name | 001_Nimetus
RF PANEEL PEAMINE-054 | RF PANEEL PEAMINE-054
RF PANEEL PEAMINE-055 | RF PANEEL PEAMINE-055

# IfcPlate: Main Panel 1086 x 1075 x 33, RF PANEEL PEAMINE-010
In: 1. korrus
Classification: 1.15 IfcPlateType (plaat) (RKAS BIM + ARCHICAD Classification); Material: _KLAAS - kirgas
Pset_PlateCommon - Reference: Built-in CW Panel
AR_001-002 - 001_Nimetus: RF PANEEL PEAMINE-010; 002_Tüüp: Built-in CW Panel
AC_Pset_RenovationAndPhasing - Renovation Status: Undefined

# IfcPlate: Main Panel 1086 x 1195 x 33, RF PANEEL PEAMINE-010
In: 1. korrus
Classification: 1.15 IfcPlateType (plaat) (RKAS BIM + ARCHICAD Classification); Material: _KLAAS - kirgas
Pset_PlateCommon - Reference: Built-in CW Panel
AR_001-002 - 001_Nimetus: RF PANEEL PEAMINE-010; 002_Tüüp: Built-in CW Panel
AC_Pset_RenovationAndPhasing - Renovation Status: Undefined

# IfcPlate: Main Panel 1086 x 1220 x 33 (4)
In: 1. korrus
Classification: 1.15 IfcPlateType (plaat) (RKAS BIM + ARCHICAD Classification); Material: _KLAAS - kirgas
Pset_PlateCommon - Reference: Built-in CW Panel
AR_001-002 - 002_Tüüp: Built-in CW Panel
AC_Pset_RenovationAndPhasing - Renovation Status: Undefined
Name | 001_Nimetus
2 x RF PANEEL PEAMINE-010 | RF PANEEL PEAMINE-010
RF PANEEL PEAMINE-018 | RF PANEEL PEAMINE-018
RF PANEEL PEAMINE-022 | RF PANEEL PEAMINE-022

# IfcPlate: Main Panel 1122 x 1075 x 33 (4)
In: 1. korrus
Classification: 1.15 IfcPlateType (plaat) (RKAS BIM + ARCHICAD Classification); Material: _KLAAS - kirgas
Pset_PlateCommon - Reference: Built-in CW Panel
AR_001-002 - 002_Tüüp: Built-in CW Panel
AC_Pset_RenovationAndPhasing - Renovation Status: Undefined
Name | 001_Nimetus
RF PANEEL PEAMINE-024 | RF PANEEL PEAMINE-024
RF PANEEL PEAMINE-019 | RF PANEEL PEAMINE-019
RF PANEEL PEAMINE-026 | RF PANEEL PEAMINE-026
RF PANEEL PEAMINE-017 | RF PANEEL PEAMINE-017

# IfcPlate: Main Panel 1122 x 1220 x 33 (14)
In: 1. korrus
Classification: 1.15 IfcPlateType (plaat) (RKAS BIM + ARCHICAD Classification); Material: _KLAAS - kirgas
Pset_PlateCommon - Reference: Built-in CW Panel
AR_001-002 - 002_Tüüp: Built-in CW Panel
AC_Pset_RenovationAndPhasing - Renovation Status: Undefined
Name | 001_Nimetus
4 x RF PANEEL PEAMINE-010 | RF PANEEL PEAMINE-010
RF PANEEL PEAMINE-011 | RF PANEEL PEAMINE-011
RF PANEEL PEAMINE-014 | RF PANEEL PEAMINE-014
RF PANEEL PEAMINE-015 | RF PANEEL PEAMINE-015
RF PANEEL PEAMINE-016 | RF PANEEL PEAMINE-016
RF PANEEL PEAMINE-027 | RF PANEEL PEAMINE-027
RF PANEEL PEAMINE-021 | RF PANEEL PEAMINE-021
RF PANEEL PEAMINE-023 | RF PANEEL PEAMINE-023
RF PANEEL PEAMINE-025 | RF PANEEL PEAMINE-025
2 x Pöörduks | Pöörduks

# IfcPlate: Main Panel 1122 x 1225 x 33 (2)
In: 1. korrus
Classification: 1.15 IfcPlateType (plaat) (RKAS BIM + ARCHICAD Classification); Material: _KLAAS - kirgas
Pset_PlateCommon - Reference: Built-in CW Panel
AR_001-002 - 002_Tüüp: Built-in CW Panel
AC_Pset_RenovationAndPhasing - Renovation Status: Undefined
Name | 001_Nimetus
RF PANEEL PEAMINE-010 | RF PANEEL PEAMINE-010
Pöörduks | Pöörduks

# IfcPlate: Main Panel 1137 x 1220 x 33, RF PANEEL PEAMINE-079
In: 1. korrus
Classification: 1.15 IfcPlateType (plaat) (RKAS BIM + ARCHICAD Classification); Material: _KLAAS - kirgas
Pset_PlateCommon - Reference: Built-in CW Panel
AR_001-002 - 001_Nimetus: RF PANEEL PEAMINE-079; 002_Tüüp: Built-in CW Panel
AC_Pset_RenovationAndPhasing - Renovation Status: Undefined

# IfcPlate: Main Panel 1143 x 1075 x 33, RF PANEEL PEAMINE-086
In: 1. korrus
Classification: 1.15 IfcPlateType (plaat) (RKAS BIM + ARCHICAD Classification); Material: _KLAAS - kirgas
Pset_PlateCommon - Reference: Built-in CW Panel
AR_001-002 - 001_Nimetus: RF PANEEL PEAMINE-086; 002_Tüüp: Built-in CW Panel
AC_Pset_RenovationAndPhasing - Renovation Status: Undefined

# IfcPlate: Main Panel 1143 x 1195 x 33, RF PANEEL PEAMINE-106
In: 1. korrus
Classification: 1.15 IfcPlateType (plaat) (RKAS BIM + ARCHICAD Classification); Material: _KLAAS - kirgas
Pset_PlateCommon - Reference: Built-in CW Panel
AR_001-002 - 001_Nimetus: RF PANEEL PEAMINE-106; 002_Tüüp: Built-in CW Panel
AC_Pset_RenovationAndPhasing - Renovation Status: Undefined

# IfcPlate: Main Panel 1143 x 1220 x 33 (4)
In: 1. korrus
Classification: 1.15 IfcPlateType (plaat) (RKAS BIM + ARCHICAD Classification); Material: _KLAAS - kirgas
Pset_PlateCommon - Reference: Built-in CW Panel
AR_001-002 - 002_Tüüp: Built-in CW Panel
AC_Pset_RenovationAndPhasing - Renovation Status: Undefined
Name | 001_Nimetus
RF PANEEL PEAMINE-082 | RF PANEEL PEAMINE-082
RF PANEEL PEAMINE-083 | RF PANEEL PEAMINE-083
RF PANEEL PEAMINE-085 | RF PANEEL PEAMINE-085
RF PANEEL PEAMINE-118 | RF PANEEL PEAMINE-118

# IfcPlate: Main Panel 1177 x 1075 x 33, RF PANEEL PEAMINE-081
In: 1. korrus
Classification: 1.15 IfcPlateType (plaat) (RKAS BIM + ARCHICAD Classification); Material: _KLAAS - kirgas
Pset_PlateCommon - Reference: Built-in CW Panel
AR_001-002 - 001_Nimetus: RF PANEEL PEAMINE-081; 002_Tüüp: Built-in CW Panel
AC_Pset_RenovationAndPhasing - Renovation Status: Undefined

# IfcPlate: Main Panel 1177 x 1195 x 33, RF PANEEL PEAMINE-071
In: 1. korrus
Classification: 1.15 IfcPlateType (plaat) (RKAS BIM + ARCHICAD Classification); Material: _KLAAS - kirgas
Pset_PlateCommon - Reference: Built-in CW Panel
AR_001-002 - 001_Nimetus: RF PANEEL PEAMINE-071; 002_Tüüp: Built-in CW Panel
AC_Pset_RenovationAndPhasing - Renovation Status: Undefined

# IfcPlate: Main Panel 1177 x 1220 x 33 (3)
In: 1. korrus
Classification: 1.15 IfcPlateType (plaat) (RKAS BIM + ARCHICAD Classification); Material: _KLAAS - kirgas
Pset_PlateCommon - Reference: Built-in CW Panel
AR_001-002 - 002_Tüüp: Built-in CW Panel
AC_Pset_RenovationAndPhasing - Renovation Status: Undefined
Name | 001_Nimetus
RF PANEEL PEAMINE-073 | RF PANEEL PEAMINE-073
RF PANEEL PEAMINE-075 | RF PANEEL PEAMINE-075
RF PANEEL PEAMINE-077 | RF PANEEL PEAMINE-077

# IfcPlate: Main Panel 12 x 1400 x 58, RF PANEEL PEAMINE-875
In: 4. TEHNO korrus
Classification: 1.15 IfcPlateType (plaat) (RKAS BIM + ARCHICAD Classification); Material: _KLAAS - kirgas
Pset_PlateCommon - Reference: Built-in CW Panel
AR_001-002 - 001_Nimetus: RF PANEEL PEAMINE-875; 002_Tüüp: Built-in CW Panel
AC_Pset_RenovationAndPhasing - Renovation Status: Undefined

# IfcPlate: Main Panel 1265 x 865 x 20 (2)
In: 1. korrus
Classification: 1.15 IfcPlateType (plaat) (RKAS BIM + ARCHICAD Classification); Material: _GENEERILINE MATERJAL KLAAS
Pset_PlateCommon - Reference: Built-in CW Panel
AR_001-002 - 002_Tüüp: Built-in CW Panel
AC_Pset_RenovationAndPhasing - Renovation Status: Undefined
Name | 001_Nimetus
RF PANEEL PEAMINE-080 | RF PANEEL PEAMINE-080
RF PANEEL PEAMINE-079 | RF PANEEL PEAMINE-079

# IfcPlate: Main Panel 1270 x 1445 x 58, RF PANEEL PEAMINE-954
In: 4. TEHNO korrus
Classification: 1.15 IfcPlateType (plaat) (RKAS BIM + ARCHICAD Classification); Material: _KLAAS - kirgas
Pset_PlateCommon - Reference: Built-in CW Panel
AR_001-002 - 001_Nimetus: RF PANEEL PEAMINE-954; 002_Tüüp: Built-in CW Panel
AC_Pset_RenovationAndPhasing - Renovation Status: Undefined

# IfcPlate: Main Panel 1270 x 1470 x 58, RF PANEEL PEAMINE-958
In: 4. TEHNO korrus
Classification: 1.15 IfcPlateType (plaat) (RKAS BIM + ARCHICAD Classification); Material: _KLAAS - kirgas
Pset_PlateCommon - Reference: Built-in CW Panel
AR_001-002 - 001_Nimetus: RF PANEEL PEAMINE-958; 002_Tüüp: Built-in CW Panel
AC_Pset_RenovationAndPhasing - Renovation Status: Undefined

# IfcPlate: Main Panel 1295 x 1445 x 58 (3)
In: 4. TEHNO korrus
Classification: 1.15 IfcPlateType (plaat) (RKAS BIM + ARCHICAD Classification); Material: _KLAAS - kirgas
Pset_PlateCommon - Reference: Built-in CW Panel
AR_001-002 - 002_Tüüp: Built-in CW Panel
AC_Pset_RenovationAndPhasing - Renovation Status: Undefined
Name | 001_Nimetus
RF PANEEL PEAMINE-957 | RF PANEEL PEAMINE-957
RF PANEEL PEAMINE-956 | RF PANEEL PEAMINE-956
RF PANEEL PEAMINE-955 | RF PANEEL PEAMINE-955

# IfcPlate: Main Panel 1295 x 1470 x 58 (3)
In: 4. TEHNO korrus
Classification: 1.15 IfcPlateType (plaat) (RKAS BIM + ARCHICAD Classification); Material: _KLAAS - kirgas
Pset_PlateCommon - Reference: Built-in CW Panel
AR_001-002 - 002_Tüüp: Built-in CW Panel
AC_Pset_RenovationAndPhasing - Renovation Status: Undefined
Name | 001_Nimetus
RF PANEEL PEAMINE-960 | RF PANEEL PEAMINE-960
RF PANEEL PEAMINE-959 | RF PANEEL PEAMINE-959
RF PANEEL PEAMINE-961 | RF PANEEL PEAMINE-961

# IfcPlate: Main Panel 13 x 5 x 58, SE-aken
In: 4. TEHNO korrus
Classification: 1.15 IfcPlateType (plaat) (RKAS BIM + ARCHICAD Classification); Material: _KLAAS - kirgas
Pset_PlateCommon - Reference: Built-in CW Panel
AR_001-002 - 001_Nimetus: SE-aken; 002_Tüüp: Built-in CW Panel
AC_Pset_RenovationAndPhasing - Renovation Status: Undefined

# IfcPlate: Main Panel 1365 x 1783 x 58, RF PANEEL PEAMINE-915
In: 4. TEHNO korrus
Classification: 1.15 IfcPlateType (plaat) (RKAS BIM + ARCHICAD Classification); Material: _KLAAS - kirgas
Pset_PlateCommon - Reference: Built-in CW Panel
AR_001-002 - 001_Nimetus: RF PANEEL PEAMINE-915; 002_Tüüp: Built-in CW Panel
AC_Pset_RenovationAndPhasing - Renovation Status: Undefined

# IfcPlate: Main Panel 1365 x 1820 x 58, RF PANEEL PEAMINE-928
In: 4. TEHNO korrus
Classification: 1.15 IfcPlateType (plaat) (RKAS BIM + ARCHICAD Classification); Material: _KLAAS - kirgas
Pset_PlateCommon - Reference: Built-in CW Panel
AR_001-002 - 001_Nimetus: RF PANEEL PEAMINE-928; 002_Tüüp: Built-in CW Panel
AC_Pset_RenovationAndPhasing - Renovation Status: Undefined

# IfcPlate: Main Panel 1366 x 33 x 58, RF PANEEL PEAMINE-930
In: 4. TEHNO korrus
Classification: 1.15 IfcPlateType (plaat) (RKAS BIM + ARCHICAD Classification); Material: _KLAAS - kirgas
Pset_PlateCommon - Reference: Built-in CW Panel
AR_001-002 - 001_Nimetus: RF PANEEL PEAMINE-930; 002_Tüüp: Built-in CW Panel
AC_Pset_RenovationAndPhasing - Renovation Status: Undefined

# IfcPlate: Main Panel 1371 x 1145 x 33 (2)
In: 1. korrus
Classification: 1.15 IfcPlateType (plaat) (RKAS BIM + ARCHICAD Classification); Material: _KLAAS - kirgas
Pset_PlateCommon - Reference: Built-in CW Panel
AR_001-002 - 002_Tüüp: Built-in CW Panel
AC_Pset_RenovationAndPhasing - Renovation Status: Undefined
Name | 001_Nimetus
RF PANEEL PEAMINE-021 | RF PANEEL PEAMINE-021
RF PANEEL PEAMINE-013 | RF PANEEL PEAMINE-013

# IfcPlate: Main Panel 1371 x 1170 x 33, RF PANEEL PEAMINE-017
In: 1. korrus
Classification: 1.15 IfcPlateType (plaat) (RKAS BIM + ARCHICAD Classification); Material: _KLAAS - kirgas
Pset_PlateCommon - Reference: Built-in CW Panel
AR_001-002 - 001_Nimetus: RF PANEEL PEAMINE-017; 002_Tüüp: Built-in CW Panel
AC_Pset_RenovationAndPhasing - Renovation Status: Undefined

# IfcPlate: Main Panel 1385 x 1145 x 33 (2)
In: 1. korrus
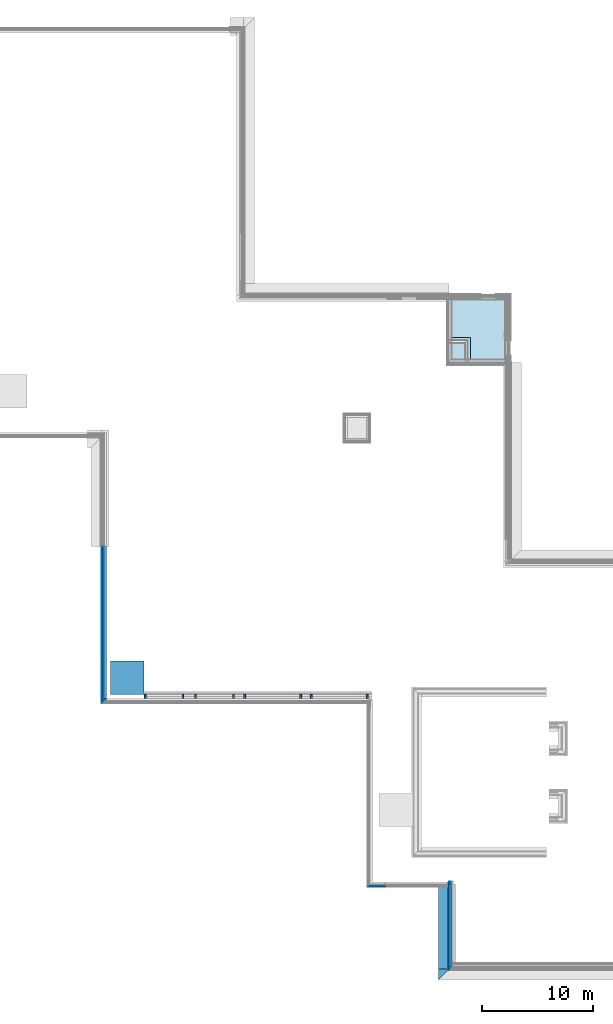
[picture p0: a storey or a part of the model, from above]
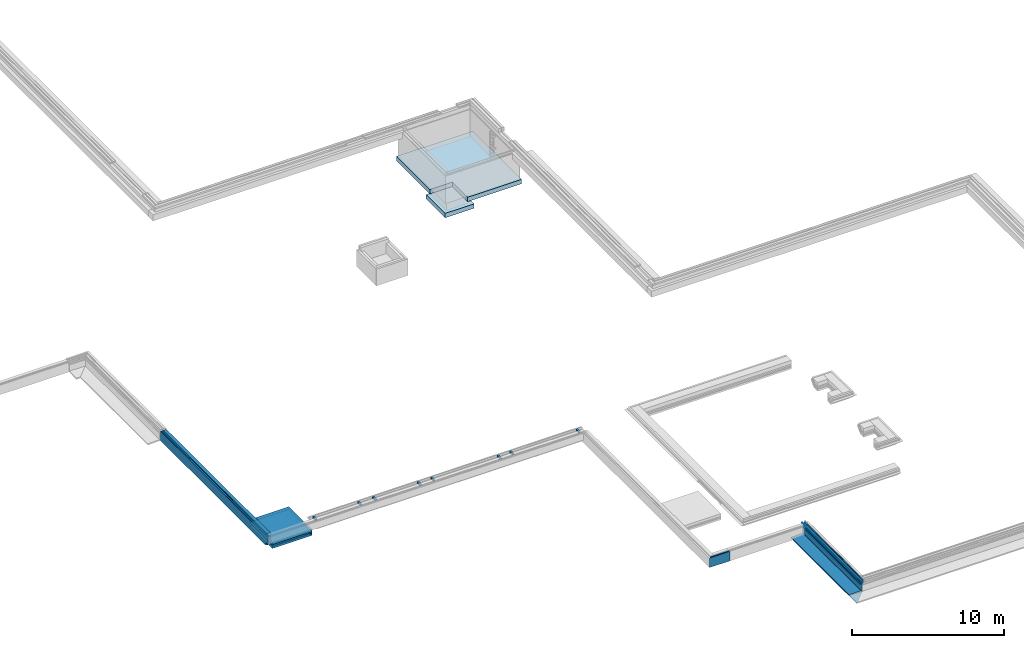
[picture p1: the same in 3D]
Properties of the parts of a building model (IFC2X3), part 9 of 14

# IfcPlate: Main Panel 1385 x 1145 x 33 (2)
Classification: 1.15 IfcPlateType (plaat) (RKAS BIM + ARCHICAD Classification); Material: _KLAAS - kirgas
Pset_PlateCommon - Reference: Built-in CW Panel
AR_001-002 - 002_Tüüp: Built-in CW Panel
AC_Pset_RenovationAndPhasing - Renovation Status: Undefined
Name | 001_Nimetus
RF PANEEL PEAMINE-011 | RF PANEEL PEAMINE-011
RF PANEEL PEAMINE-019 | RF PANEEL PEAMINE-019

# IfcPlate: Main Panel 1385 x 1170 x 33, RF PANEEL PEAMINE-015
In: 1. korrus
Classification: 1.15 IfcPlateType (plaat) (RKAS BIM + ARCHICAD Classification); Material: _KLAAS - kirgas
Pset_PlateCommon - Reference: Built-in CW Panel
AR_001-002 - 001_Nimetus: RF PANEEL PEAMINE-015; 002_Tüüp: Built-in CW Panel
AC_Pset_RenovationAndPhasing - Renovation Status: Undefined

# IfcPlate: Main Panel 1385 x 1220 x 33 (2)
In: 1. korrus
Classification: 1.15 IfcPlateType (plaat) (RKAS BIM + ARCHICAD Classification); Material: _KLAAS - kirgas
Pset_PlateCommon - Reference: Built-in CW Panel
AR_001-002 - 002_Tüüp: Built-in CW Panel
AC_Pset_RenovationAndPhasing - Renovation Status: Undefined
Name | 001_Nimetus
RF PANEEL PEAMINE-987 | RF PANEEL PEAMINE-987
RF PANEEL PEAMINE-994 | RF PANEEL PEAMINE-994

# IfcPlate: Main Panel 1385 x 995 x 33 (2)
In: 1. korrus
Classification: 1.15 IfcPlateType (plaat) (RKAS BIM + ARCHICAD Classification); Material: _KLAAS - kirgas
Pset_PlateCommon - Reference: Built-in CW Panel
AR_001-002 - 002_Tüüp: Built-in CW Panel
AC_Pset_RenovationAndPhasing - Renovation Status: Undefined
Name | 001_Nimetus
RF PANEEL PEAMINE-996 | RF PANEEL PEAMINE-996
RF PANEEL PEAMINE-003 | RF PANEEL PEAMINE-003

# IfcPlate: Main Panel 1396 x 33 x 58, RF PANEEL PEAMINE-882
In: 4. TEHNO korrus
Classification: 1.15 IfcPlateType (plaat) (RKAS BIM + ARCHICAD Classification); Material: _KLAAS - kirgas
Pset_PlateCommon - Reference: Built-in CW Panel
AR_001-002 - 001_Nimetus: RF PANEEL PEAMINE-882; 002_Tüüp: Built-in CW Panel
AC_Pset_RenovationAndPhasing - Renovation Status: Undefined

# IfcPlate: Main Panel 1410 x 1783 x 58, RF PANEEL PEAMINE-935
In: 4. TEHNO korrus
Classification: 1.15 IfcPlateType (plaat) (RKAS BIM + ARCHICAD Classification); Material: _KLAAS - kirgas
Pset_PlateCommon - Reference: Built-in CW Panel
AR_001-002 - 001_Nimetus: RF PANEEL PEAMINE-935; 002_Tüüp: Built-in CW Panel
AC_Pset_RenovationAndPhasing - Renovation Status: Undefined

# IfcPlate: Main Panel 1410 x 1820 x 58, RF PANEEL PEAMINE-938
In: 4. TEHNO korrus
Classification: 1.15 IfcPlateType (plaat) (RKAS BIM + ARCHICAD Classification); Material: _KLAAS - kirgas
Pset_PlateCommon - Reference: Built-in CW Panel
AR_001-002 - 001_Nimetus: RF PANEEL PEAMINE-938; 002_Tüüp: Built-in CW Panel
AC_Pset_RenovationAndPhasing - Renovation Status: Undefined

# IfcPlate: Main Panel 1415 x 33 x 58, RF PANEEL PEAMINE-936
In: 4. TEHNO korrus
Classification: 1.15 IfcPlateType (plaat) (RKAS BIM + ARCHICAD Classification); Material: _KLAAS - kirgas
Pset_PlateCommon - Reference: Built-in CW Panel
AR_001-002 - 001_Nimetus: RF PANEEL PEAMINE-936; 002_Tüüp: Built-in CW Panel
AC_Pset_RenovationAndPhasing - Renovation Status: Undefined

# IfcPlate: Main Panel 1420 x 1075 x 33 (15)
In: 1. korrus
Classification: 1.15 IfcPlateType (plaat) (RKAS BIM + ARCHICAD Classification); Material: _KLAAS - kirgas
Pset_PlateCommon - Reference: Built-in CW Panel
AR_001-002 - 002_Tüüp: Built-in CW Panel
AC_Pset_RenovationAndPhasing - Renovation Status: Undefined
Name | 001_Nimetus
RF PANEEL PEAMINE-130 | RF PANEEL PEAMINE-130
RF PANEEL PEAMINE-136 | RF PANEEL PEAMINE-136
RF PANEEL PEAMINE-142 | RF PANEEL PEAMINE-142
RF PANEEL PEAMINE-148 | RF PANEEL PEAMINE-148
RF PANEEL PEAMINE-154 | RF PANEEL PEAMINE-154
RF PANEEL PEAMINE-160 | RF PANEEL PEAMINE-160
RF PANEEL PEAMINE-166 | RF PANEEL PEAMINE-166
RF PANEEL PEAMINE-172 | RF PANEEL PEAMINE-172
RF PANEEL PEAMINE-084 | RF PANEEL PEAMINE-084
RF PANEEL PEAMINE-124 | RF PANEEL PEAMINE-124
RF PANEEL PEAMINE-112 | RF PANEEL PEAMINE-112
RF PANEEL PEAMINE-090 | RF PANEEL PEAMINE-090
RF PANEEL PEAMINE-089 | RF PANEEL PEAMINE-089
RF PANEEL PEAMINE-088 | RF PANEEL PEAMINE-088
RF PANEEL PEAMINE-087 | RF PANEEL PEAMINE-087

# IfcPlate: Main Panel 1420 x 1145 x 33, RF PANEEL PEAMINE-020
In: 1. korrus
Classification: 1.15 IfcPlateType (plaat) (RKAS BIM + ARCHICAD Classification); Material: _KLAAS - kirgas
Pset_PlateCommon - Reference: Built-in CW Panel
AR_001-002 - 001_Nimetus: RF PANEEL PEAMINE-020; 002_Tüüp: Built-in CW Panel
AC_Pset_RenovationAndPhasing - Renovation Status: Undefined

# IfcPlate: Main Panel 1420 x 1195 x 33 (15)
In: 1. korrus
Classification: 1.15 IfcPlateType (plaat) (RKAS BIM + ARCHICAD Classification); Material: _KLAAS - kirgas
Pset_PlateCommon - Reference: Built-in CW Panel
AR_001-002 - 002_Tüüp: Built-in CW Panel
AC_Pset_RenovationAndPhasing - Renovation Status: Undefined
Name | 001_Nimetus
RF PANEEL PEAMINE-091 | RF PANEEL PEAMINE-091
RF PANEEL PEAMINE-096 | RF PANEEL PEAMINE-096
RF PANEEL PEAMINE-101 | RF PANEEL PEAMINE-101
RF PANEEL PEAMINE-107 | RF PANEEL PEAMINE-107
RF PANEEL PEAMINE-113 | RF PANEEL PEAMINE-113
RF PANEEL PEAMINE-119 | RF PANEEL PEAMINE-119
RF PANEEL PEAMINE-125 | RF PANEEL PEAMINE-125
RF PANEEL PEAMINE-131 | RF PANEEL PEAMINE-131
RF PANEEL PEAMINE-137 | RF PANEEL PEAMINE-137
RF PANEEL PEAMINE-143 | RF PANEEL PEAMINE-143
RF PANEEL PEAMINE-149 | RF PANEEL PEAMINE-149
RF PANEEL PEAMINE-155 | RF PANEEL PEAMINE-155
RF PANEEL PEAMINE-161 | RF PANEEL PEAMINE-161
RF PANEEL PEAMINE-167 | RF PANEEL PEAMINE-167
RF PANEEL PEAMINE-173 | RF PANEEL PEAMINE-173

# IfcPlate: Main Panel 1420 x 1220 x 33 (64)
In: 1. korrus
Classification: 1.15 IfcPlateType (plaat) (RKAS BIM + ARCHICAD Classification); Material: _KLAAS - kirgas
Pset_PlateCommon - Reference: Built-in CW Panel
AR_001-002 - 002_Tüüp: Built-in CW Panel
AC_Pset_RenovationAndPhasing - Renovation Status: Undefined
Name | 001_Nimetus
RF PANEEL PEAMINE-092 | RF PANEEL PEAMINE-092
RF PANEEL PEAMINE-093 | RF PANEEL PEAMINE-093
RF PANEEL PEAMINE-094 | RF PANEEL PEAMINE-094
RF PANEEL PEAMINE-095 | RF PANEEL PEAMINE-095
RF PANEEL PEAMINE-097 | RF PANEEL PEAMINE-097
RF PANEEL PEAMINE-098 | RF PANEEL PEAMINE-098
RF PANEEL PEAMINE-099 | RF PANEEL PEAMINE-099
RF PANEEL PEAMINE-100 | RF PANEEL PEAMINE-100
RF PANEEL PEAMINE-102 | RF PANEEL PEAMINE-102
RF PANEEL PEAMINE-103 | RF PANEEL PEAMINE-103
RF PANEEL PEAMINE-104 | RF PANEEL PEAMINE-104
RF PANEEL PEAMINE-105 | RF PANEEL PEAMINE-105
RF PANEEL PEAMINE-108 | RF PANEEL PEAMINE-108
RF PANEEL PEAMINE-109 | RF PANEEL PEAMINE-109
RF PANEEL PEAMINE-110 | RF PANEEL PEAMINE-110
RF PANEEL PEAMINE-111 | RF PANEEL PEAMINE-111
RF PANEEL PEAMINE-114 | RF PANEEL PEAMINE-114
RF PANEEL PEAMINE-115 | RF PANEEL PEAMINE-115
RF PANEEL PEAMINE-116 | RF PANEEL PEAMINE-116
RF PANEEL PEAMINE-117 | RF PANEEL PEAMINE-117
RF PANEEL PEAMINE-120 | RF PANEEL PEAMINE-120
RF PANEEL PEAMINE-121 | RF PANEEL PEAMINE-121
RF PANEEL PEAMINE-122 | RF PANEEL PEAMINE-122
RF PANEEL PEAMINE-123 | RF PANEEL PEAMINE-123
RF PANEEL PEAMINE-126 | RF PANEEL PEAMINE-126
RF PANEEL PEAMINE-127 | RF PANEEL PEAMINE-127
RF PANEEL PEAMINE-128 | RF PANEEL PEAMINE-128
RF PANEEL PEAMINE-129 | RF PANEEL PEAMINE-129
RF PANEEL PEAMINE-132 | RF PANEEL PEAMINE-132
RF PANEEL PEAMINE-133 | RF PANEEL PEAMINE-133
RF PANEEL PEAMINE-134 | RF PANEEL PEAMINE-134
RF PANEEL PEAMINE-135 | RF PANEEL PEAMINE-135
RF PANEEL PEAMINE-138 | RF PANEEL PEAMINE-138
RF PANEEL PEAMINE-139 | RF PANEEL PEAMINE-139
RF PANEEL PEAMINE-140 | RF PANEEL PEAMINE-140
RF PANEEL PEAMINE-141 | RF PANEEL PEAMINE-141
RF PANEEL PEAMINE-144 | RF PANEEL PEAMINE-144
RF PANEEL PEAMINE-145 | RF PANEEL PEAMINE-145
RF PANEEL PEAMINE-146 | RF PANEEL PEAMINE-146
RF PANEEL PEAMINE-147 | RF PANEEL PEAMINE-147
RF PANEEL PEAMINE-150 | RF PANEEL PEAMINE-150
RF PANEEL PEAMINE-151 | RF PANEEL PEAMINE-151
RF PANEEL PEAMINE-152 | RF PANEEL PEAMINE-152
RF PANEEL PEAMINE-153 | RF PANEEL PEAMINE-153
RF PANEEL PEAMINE-156 | RF PANEEL PEAMINE-156
RF PANEEL PEAMINE-157 | RF PANEEL PEAMINE-157
RF PANEEL PEAMINE-158 | RF PANEEL PEAMINE-158
RF PANEEL PEAMINE-159 | RF PANEEL PEAMINE-159
RF PANEEL PEAMINE-162 | RF PANEEL PEAMINE-162
RF PANEEL PEAMINE-163 | RF PANEEL PEAMINE-163
RF PANEEL PEAMINE-164 | RF PANEEL PEAMINE-164
RF PANEEL PEAMINE-165 | RF PANEEL PEAMINE-165
RF PANEEL PEAMINE-168 | RF PANEEL PEAMINE-168
RF PANEEL PEAMINE-169 | RF PANEEL PEAMINE-169
RF PANEEL PEAMINE-170 | RF PANEEL PEAMINE-170
RF PANEEL PEAMINE-171 | RF PANEEL PEAMINE-171
RF PANEEL PEAMINE-174 | RF PANEEL PEAMINE-174
RF PANEEL PEAMINE-175 | RF PANEEL PEAMINE-175
RF PANEEL PEAMINE-176 | RF PANEEL PEAMINE-176
RF PANEEL PEAMINE-177 | RF PANEEL PEAMINE-177
RF PANEEL PEAMINE-988 | RF PANEEL PEAMINE-988
RF PANEEL PEAMINE-989 | RF PANEEL PEAMINE-989
RF PANEEL PEAMINE-990 | RF PANEEL PEAMINE-990
RF PANEEL PEAMINE-993 | RF PANEEL PEAMINE-993

# IfcPlate: Main Panel 1420 x 995 x 33 (6)
In: 1. korrus
Classification: 1.15 IfcPlateType (plaat) (RKAS BIM + ARCHICAD Classification); Material: _KLAAS - kirgas
Pset_PlateCommon - Reference: Built-in CW Panel
AR_001-002 - 002_Tüüp: Built-in CW Panel
AC_Pset_RenovationAndPhasing - Renovation Status: Undefined
Name | 001_Nimetus
RF PANEEL PEAMINE-997 | RF PANEEL PEAMINE-997
RF PANEEL PEAMINE-998 | RF PANEEL PEAMINE-998
RF PANEEL PEAMINE-999 | RF PANEEL PEAMINE-999
RF PANEEL PEAMINE-000 | RF PANEEL PEAMINE-000
RF PANEEL PEAMINE-001 | RF PANEEL PEAMINE-001
RF PANEEL PEAMINE-002 | RF PANEEL PEAMINE-002

# IfcPlate: Main Panel 1660 x 1400 x 58, RF PANEEL PEAMINE-890
In: 4. TEHNO korrus
Classification: 1.15 IfcPlateType (plaat) (RKAS BIM + ARCHICAD Classification); Material: _KLAAS - kirgas
Pset_PlateCommon - Reference: Built-in CW Panel
AR_001-002 - 001_Nimetus: RF PANEEL PEAMINE-890; 002_Tüüp: Built-in CW Panel
AC_Pset_RenovationAndPhasing - Renovation Status: Undefined

# IfcPlate: Main Panel 1667 x 1415 x 58, RF PANEEL PEAMINE-855
In: 4. TEHNO korrus
Classification: 1.15 IfcPlateType (plaat) (RKAS BIM + ARCHICAD Classification); Material: _KLAAS - kirgas
Pset_PlateCommon - Reference: Built-in CW Panel
AR_001-002 - 001_Nimetus: RF PANEEL PEAMINE-855; 002_Tüüp: Built-in CW Panel
AC_Pset_RenovationAndPhasing - Renovation Status: Undefined

# IfcPlate: Main Panel 1674 x 20 x 58, RF PANEEL PEAMINE-876
In: 4. TEHNO korrus
Classification: 1.15 IfcPlateType (plaat) (RKAS BIM + ARCHICAD Classification); Material: _KLAAS - kirgas
Pset_PlateCommon - Reference: Built-in CW Panel
AR_001-002 - 001_Nimetus: RF PANEEL PEAMINE-876; 002_Tüüp: Built-in CW Panel
AC_Pset_RenovationAndPhasing - Renovation Status: Undefined

# IfcPlate: Main Panel 18 x 5 x 58, RF PANEEL PEAMINE-927
In: 4. TEHNO korrus
Classification: 1.15 IfcPlateType (plaat) (RKAS BIM + ARCHICAD Classification); Material: _KLAAS - kirgas
Pset_PlateCommon - Reference: Built-in CW Panel
AR_001-002 - 001_Nimetus: RF PANEEL PEAMINE-927; 002_Tüüp: Built-in CW Panel
AC_Pset_RenovationAndPhasing - Renovation Status: Undefined

# IfcPlate: Main Panel 19 x 5 x 58, RF PANEEL PEAMINE-904
In: 4. TEHNO korrus
Classification: 1.15 IfcPlateType (plaat) (RKAS BIM + ARCHICAD Classification); Material: _KLAAS - kirgas
Pset_PlateCommon - Reference: Built-in CW Panel
AR_001-002 - 001_Nimetus: RF PANEEL PEAMINE-904; 002_Tüüp: Built-in CW Panel
AC_Pset_RenovationAndPhasing - Renovation Status: Undefined

# IfcPlate: Main Panel 1945 x 1834 x 58, RF PANEEL PEAMINE-922
In: 4. TEHNO korrus
Classification: 1.15 IfcPlateType (plaat) (RKAS BIM + ARCHICAD Classification); Material: _KLAAS - kirgas
Pset_PlateCommon - Reference: Built-in CW Panel
AR_001-002 - 001_Nimetus: RF PANEEL PEAMINE-922; 002_Tüüp: Built-in CW Panel
AC_Pset_RenovationAndPhasing - Renovation Status: Undefined

# IfcPlate: Main Panel 1955 x 1821 x 58, RF PANEEL PEAMINE-924
In: 4. TEHNO korrus
Classification: 1.15 IfcPlateType (plaat) (RKAS BIM + ARCHICAD Classification); Material: _KLAAS - kirgas
Pset_PlateCommon - Reference: Built-in CW Panel
AR_001-002 - 001_Nimetus: RF PANEEL PEAMINE-924; 002_Tüüp: Built-in CW Panel
AC_Pset_RenovationAndPhasing - Renovation Status: Undefined

# IfcPlate: Main Panel 1955 x 1841 x 58, RF PANEEL PEAMINE-915
In: 4. TEHNO korrus
Classification: 1.15 IfcPlateType (plaat) (RKAS BIM + ARCHICAD Classification); Material: _KLAAS - kirgas
Pset_PlateCommon - Reference: Built-in CW Panel
AR_001-002 - 001_Nimetus: RF PANEEL PEAMINE-915; 002_Tüüp: Built-in CW Panel
AC_Pset_RenovationAndPhasing - Renovation Status: Undefined

# IfcPlate: Main Panel 1960 x 1822 x 58, RF PANEEL PEAMINE-925
In: 4. TEHNO korrus
Classification: 1.15 IfcPlateType (plaat) (RKAS BIM + ARCHICAD Classification); Material: _KLAAS - kirgas
Pset_PlateCommon - Reference: Built-in CW Panel
AR_001-002 - 001_Nimetus: RF PANEEL PEAMINE-925; 002_Tüüp: Built-in CW Panel
AC_Pset_RenovationAndPhasing - Renovation Status: Undefined

# IfcPlate: Main Panel 20 x 1822 x 58, RF PANEEL PEAMINE-927
In: 4. TEHNO korrus
Classification: 1.15 IfcPlateType (plaat) (RKAS BIM + ARCHICAD Classification); Material: _KLAAS - kirgas
Pset_PlateCommon - Reference: Built-in CW Panel
AR_001-002 - 001_Nimetus: RF PANEEL PEAMINE-927; 002_Tüüp: Built-in CW Panel
AC_Pset_RenovationAndPhasing - Renovation Status: Undefined

# IfcPlate: Main Panel 20 x 1841 x 58, RF PANEEL PEAMINE-917
In: 4. TEHNO korrus
Classification: 1.15 IfcPlateType (plaat) (RKAS BIM + ARCHICAD Classification); Material: _KLAAS - kirgas
Pset_PlateCommon - Reference: Built-in CW Panel
AR_001-002 - 001_Nimetus: RF PANEEL PEAMINE-917; 002_Tüüp: Built-in CW Panel
AC_Pset_RenovationAndPhasing - Renovation Status: Undefined

# IfcPlate: Main Panel 20 x 5 x 58 (5)
In: 4. TEHNO korrus
Classification: 1.15 IfcPlateType (plaat) (RKAS BIM + ARCHICAD Classification); Material: _KLAAS - kirgas
Pset_PlateCommon - Reference: Built-in CW Panel
AR_001-002 - 002_Tüüp: Built-in CW Panel
AC_Pset_RenovationAndPhasing - Renovation Status: Undefined
Name | 001_Nimetus
RF PANEEL PEAMINE-855 | RF PANEEL PEAMINE-855
RF PANEEL PEAMINE-876 | RF PANEEL PEAMINE-876
RF PANEEL PEAMINE-903 | RF PANEEL PEAMINE-903
RF PANEEL PEAMINE-914 | RF PANEEL PEAMINE-914
RF PANEEL PEAMINE-915 | RF PANEEL PEAMINE-915

# IfcPlate: Main Panel 24 x 33 x 58, RF PANEEL PEAMINE-882
In: 4. TEHNO korrus
Classification: 1.15 IfcPlateType (plaat) (RKAS BIM + ARCHICAD Classification); Material: _KLAAS - kirgas
Pset_PlateCommon - Reference: Built-in CW Panel
AR_001-002 - 001_Nimetus: RF PANEEL PEAMINE-882; 002_Tüüp: Built-in CW Panel
AC_Pset_RenovationAndPhasing - Renovation Status: Undefined

# IfcPlate: Main Panel 24 x 5 x 58 (2)
In: 4. TEHNO korrus
Classification: 1.15 IfcPlateType (plaat) (RKAS BIM + ARCHICAD Classification); Material: _KLAAS - kirgas
Pset_PlateCommon - Reference: Built-in CW Panel
AR_001-002 - 002_Tüüp: Built-in CW Panel
AC_Pset_RenovationAndPhasing - Renovation Status: Undefined
Name | 001_Nimetus
RF PANEEL PEAMINE-905 | RF PANEEL PEAMINE-905
RF PANEEL PEAMINE-916 | RF PANEEL PEAMINE-916

# IfcPlate: Main Panel 25 x 1 x 58, RF PANEEL PEAMINE-907
In: 4. TEHNO korrus
Classification: 1.15 IfcPlateType (plaat) (RKAS BIM + ARCHICAD Classification); Material: _KLAAS - kirgas
Pset_PlateCommon - Reference: Built-in CW Panel
AR_001-002 - 001_Nimetus: RF PANEEL PEAMINE-907; 002_Tüüp: Built-in CW Panel
AC_Pset_RenovationAndPhasing - Renovation Status: Undefined

# IfcPlate: Main Panel 5 x 1783 x 58, RF PANEEL PEAMINE-935
In: 4. TEHNO korrus
Classification: 1.15 IfcPlateType (plaat) (RKAS BIM + ARCHICAD Classification); Material: _KLAAS - kirgas
Pset_PlateCommon - Reference: Built-in CW Panel
AR_001-002 - 001_Nimetus: RF PANEEL PEAMINE-935; 002_Tüüp: Built-in CW Panel
AC_Pset_RenovationAndPhasing - Renovation Status: Undefined

# IfcPlate: Main Panel 5 x 1787 x 58, RF PANEEL PEAMINE-936
In: 4. TEHNO korrus
Classification: 1.15 IfcPlateType (plaat) (RKAS BIM + ARCHICAD Classification); Material: _KLAAS - kirgas
Pset_PlateCommon - Reference: Built-in CW Panel
AR_001-002 - 001_Nimetus: RF PANEEL PEAMINE-936; 002_Tüüp: Built-in CW Panel
AC_Pset_RenovationAndPhasing - Renovation Status: Undefined

# IfcPlate: Main Panel 5 x 21 x 58, RF PANEEL PEAMINE-925
In: 4. TEHNO korrus
Classification: 1.15 IfcPlateType (plaat) (RKAS BIM + ARCHICAD Classification); Material: _KLAAS - kirgas
Pset_PlateCommon - Reference: Built-in CW Panel
AR_001-002 - 001_Nimetus: RF PANEEL PEAMINE-925; 002_Tüüp: Built-in CW Panel
AC_Pset_RenovationAndPhasing - Renovation Status: Undefined

# IfcPlate: Main Panel 625 x 1075 x 33, RF PANEEL PEAMINE-183
In: 1. korrus
Classification: 1.15 IfcPlateType (plaat) (RKAS BIM + ARCHICAD Classification); Material: _KLAAS - kirgas
Pset_PlateCommon - Reference: Built-in CW Panel
AR_001-002 - 001_Nimetus: RF PANEEL PEAMINE-183; 002_Tüüp: Built-in CW Panel
AC_Pset_RenovationAndPhasing - Renovation Status: Undefined

# IfcPlate: Main Panel 625 x 1195 x 33, RF PANEEL PEAMINE-178
In: 1. korrus
Classification: 1.15 IfcPlateType (plaat) (RKAS BIM + ARCHICAD Classification); Material: _KLAAS - kirgas
Pset_PlateCommon - Reference: Built-in CW Panel
AR_001-002 - 001_Nimetus: RF PANEEL PEAMINE-178; 002_Tüüp: Built-in CW Panel
AC_Pset_RenovationAndPhasing - Renovation Status: Undefined

# IfcPlate: Main Panel 625 x 1220 x 33 (4)
In: 1. korrus
Classification: 1.15 IfcPlateType (plaat) (RKAS BIM + ARCHICAD Classification); Material: _KLAAS - kirgas
Pset_PlateCommon - Reference: Built-in CW Panel
AR_001-002 - 002_Tüüp: Built-in CW Panel
AC_Pset_RenovationAndPhasing - Renovation Status: Undefined
Name | 001_Nimetus
RF PANEEL PEAMINE-182 | RF PANEEL PEAMINE-182
RF PANEEL PEAMINE-181 | RF PANEEL PEAMINE-181
RF PANEEL PEAMINE-180 | RF PANEEL PEAMINE-180
RF PANEEL PEAMINE-179 | RF PANEEL PEAMINE-179

# IfcPlate: Main Panel 7 x 5 x 58 (2)
In: 4. TEHNO korrus
Classification: 1.15 IfcPlateType (plaat) (RKAS BIM + ARCHICAD Classification); Material: _KLAAS - kirgas
Pset_PlateCommon - Reference: Built-in CW Panel
AR_001-002 - 002_Tüüp: Built-in CW Panel
AC_Pset_RenovationAndPhasing - Renovation Status: Undefined
Name | 001_Nimetus
RF PANEEL PEAMINE-851 | RF PANEEL PEAMINE-851
RF PANEEL PEAMINE-849 | RF PANEEL PEAMINE-849

# IfcPlate: Main Panel 72 x 1075 x 33 (10)
In: 1. korrus
Classification: 1.15 IfcPlateType (plaat) (RKAS BIM + ARCHICAD Classification); Material: _KLAAS - kirgas
Pset_PlateCommon - Reference: Built-in CW Panel
AR_001-002 - 002_Tüüp: Built-in CW Panel
AC_Pset_RenovationAndPhasing - Renovation Status: Undefined
Name | 001_Nimetus
RF PANEEL PEAMINE-058 | RF PANEEL PEAMINE-058
RF PANEEL PEAMINE-030 | RF PANEEL PEAMINE-030
RF PANEEL PEAMINE-028 | RF PANEEL PEAMINE-028
RF PANEEL PEAMINE-031 | RF PANEEL PEAMINE-031
RF PANEEL PEAMINE-062 | RF PANEEL PEAMINE-062
RF PANEEL PEAMINE-060 | RF PANEEL PEAMINE-060
RF PANEEL PEAMINE-056 | RF PANEEL PEAMINE-056
RF PANEEL PEAMINE-054 | RF PANEEL PEAMINE-054
RF PANEEL PEAMINE-052 | RF PANEEL PEAMINE-052
RF PANEEL PEAMINE-050 | RF PANEEL PEAMINE-050

# IfcPlate: Main Panel 72 x 1195 x 33 (8)
In: 1. korrus
Classification: 1.15 IfcPlateType (plaat) (RKAS BIM + ARCHICAD Classification); Material: _KLAAS - kirgas
Pset_PlateCommon - Reference: Built-in CW Panel
AR_001-002 - 002_Tüüp: Built-in CW Panel
AC_Pset_RenovationAndPhasing - Renovation Status: Undefined
Name | 001_Nimetus
7 x RF PANEEL PEAMINE-010 | RF PANEEL PEAMINE-010
Kahepoolne välisuks | Kahepoolne välisuks

# IfcPlate: Main Panel 72 x 1220 x 33 (38)
In: 1. korrus
Classification: 1.15 IfcPlateType (plaat) (RKAS BIM + ARCHICAD Classification); Material: _KLAAS - kirgas
Pset_PlateCommon - Reference: Built-in CW Panel
AR_001-002 - 002_Tüüp: Built-in CW Panel
AC_Pset_RenovationAndPhasing - Renovation Status: Undefined
Name | 001_Nimetus
18 x RF PANEEL PEAMINE-010 | RF PANEEL PEAMINE-010
RF PANEEL PEAMINE-038 | RF PANEEL PEAMINE-038
RF PANEEL PEAMINE-041 | RF PANEEL PEAMINE-041
RF PANEEL PEAMINE-047 | RF PANEEL PEAMINE-047
RF PANEEL PEAMINE-049 | RF PANEEL PEAMINE-049
RF PANEEL PEAMINE-051 | RF PANEEL PEAMINE-051
RF PANEEL PEAMINE-053 | RF PANEEL PEAMINE-053
RF PANEEL PEAMINE-057 | RF PANEEL PEAMINE-057
RF PANEEL PEAMINE-059 | RF PANEEL PEAMINE-059
RF PANEEL PEAMINE-063 | RF PANEEL PEAMINE-063
RF PANEEL PEAMINE-045 | RF PANEEL PEAMINE-045
RF PANEEL PEAMINE-032 | RF PANEEL PEAMINE-032
RF PANEEL PEAMINE-042 | RF PANEEL PEAMINE-042
RF PANEEL PEAMINE-040 | RF PANEEL PEAMINE-040
RF PANEEL PEAMINE-061 | RF PANEEL PEAMINE-061
RF PANEEL PEAMINE-039 | RF PANEEL PEAMINE-039
RF PANEEL PEAMINE-037 | RF PANEEL PEAMINE-037
RF PANEEL PEAMINE-036 | RF PANEEL PEAMINE-036
RF PANEEL PEAMINE-035 | RF PANEEL PEAMINE-035
RF PANEEL PEAMINE-034 | RF PANEEL PEAMINE-034
RF PANEEL PEAMINE-055 | RF PANEEL PEAMINE-055

# IfcPlate: Main Panel 76 x 1075 x 33, RF PANEEL PEAMINE-048
In: 1. korrus
Classification: 1.15 IfcPlateType (plaat) (RKAS BIM + ARCHICAD Classification); Material: _KLAAS - kirgas
Pset_PlateCommon - Reference: Built-in CW Panel
AR_001-002 - 001_Nimetus: RF PANEEL PEAMINE-048; 002_Tüüp: Built-in CW Panel
AC_Pset_RenovationAndPhasing - Renovation Status: Undefined

# IfcPlate: Main Panel 76 x 1195 x 33, RF PANEEL PEAMINE-010
In: 1. korrus
Classification: 1.15 IfcPlateType (plaat) (RKAS BIM + ARCHICAD Classification); Material: _KLAAS - kirgas
Pset_PlateCommon - Reference: Built-in CW Panel
AR_001-002 - 001_Nimetus: RF PANEEL PEAMINE-010; 002_Tüüp: Built-in CW Panel
AC_Pset_RenovationAndPhasing - Renovation Status: Undefined

# IfcPlate: Main Panel 76 x 1220 x 33 (4)
In: 1. korrus
Classification: 1.15 IfcPlateType (plaat) (RKAS BIM + ARCHICAD Classification); Material: _KLAAS - kirgas
Pset_PlateCommon - Reference: Built-in CW Panel
AR_001-002 - 002_Tüüp: Built-in CW Panel
AC_Pset_RenovationAndPhasing - Renovation Status: Undefined
Name | 001_Nimetus
2 x RF PANEEL PEAMINE-010 | RF PANEEL PEAMINE-010
RF PANEEL PEAMINE-044 | RF PANEEL PEAMINE-044
RF PANEEL PEAMINE-033 | RF PANEEL PEAMINE-033

# IfcPlate: Main Panel 8 x 5 x 58, RF PANEEL PEAMINE-848
In: 4. TEHNO korrus
Classification: 1.15 IfcPlateType (plaat) (RKAS BIM + ARCHICAD Classification); Material: _KLAAS - kirgas
Pset_PlateCommon - Reference: Built-in CW Panel
AR_001-002 - 001_Nimetus: RF PANEEL PEAMINE-848; 002_Tüüp: Built-in CW Panel
AC_Pset_RenovationAndPhasing - Renovation Status: Undefined

# IfcPlate: Main Panel 838 x 1075 x 33, RF PANEEL PEAMINE-046
In: 1. korrus
Classification: 1.15 IfcPlateType (plaat) (RKAS BIM + ARCHICAD Classification); Material: _KLAAS - kirgas
Pset_PlateCommon - Reference: Built-in CW Panel
AR_001-002 - 001_Nimetus: RF PANEEL PEAMINE-046; 002_Tüüp: Built-in CW Panel
AC_Pset_RenovationAndPhasing - Renovation Status: Undefined

# IfcPlate: Main Panel 838 x 1195 x 33, RF PANEEL PEAMINE-010
In: 1. korrus
Classification: 1.15 IfcPlateType (plaat) (RKAS BIM + ARCHICAD Classification); Material: _KLAAS - kirgas
Pset_PlateCommon - Reference: Built-in CW Panel
AR_001-002 - 001_Nimetus: RF PANEEL PEAMINE-010; 002_Tüüp: Built-in CW Panel
AC_Pset_RenovationAndPhasing - Renovation Status: Undefined

# IfcPlate: Main Panel 838 x 1220 x 33 (4)
In: 1. korrus
Classification: 1.15 IfcPlateType (plaat) (RKAS BIM + ARCHICAD Classification); Material: _KLAAS - kirgas
Pset_PlateCommon - Reference: Built-in CW Panel
AR_001-002 - 002_Tüüp: Built-in CW Panel
AC_Pset_RenovationAndPhasing - Renovation Status: Undefined
Name | 001_Nimetus
RF PANEEL PEAMINE-043 | RF PANEEL PEAMINE-043
RF PANEEL PEAMINE-029 | RF PANEEL PEAMINE-029
2 x RF PANEEL PEAMINE-010 | RF PANEEL PEAMINE-010

# IfcPlate: Main Panel 9 x 5 x 58, RF PANEEL PEAMINE-902
In: 4. TEHNO korrus
Classification: 1.15 IfcPlateType (plaat) (RKAS BIM + ARCHICAD Classification); Material: _KLAAS - kirgas
Pset_PlateCommon - Reference: Built-in CW Panel
AR_001-002 - 001_Nimetus: RF PANEEL PEAMINE-902; 002_Tüüp: Built-in CW Panel
AC_Pset_RenovationAndPhasing - Renovation Status: Undefined

# IfcPlate: Main Panel 915 x 1075 x 33 (9)
In: 1. korrus
Classification: 1.15 IfcPlateType (plaat) (RKAS BIM + ARCHICAD Classification); Material: _KLAAS - kirgas
Pset_PlateCommon - Reference: Built-in CW Panel
AR_001-002 - 002_Tüüp: Built-in CW Panel
AC_Pset_RenovationAndPhasing - Renovation Status: Undefined
Name | 001_Nimetus
RF PANEEL PEAMINE-237 | RF PANEEL PEAMINE-237
RF PANEEL PEAMINE-243 | RF PANEEL PEAMINE-243
RF PANEEL PEAMINE-219 | RF PANEEL PEAMINE-219
RF PANEEL PEAMINE-213 | RF PANEEL PEAMINE-213
RF PANEEL PEAMINE-192 | RF PANEEL PEAMINE-192
RF PANEEL PEAMINE-191 | RF PANEEL PEAMINE-191
RF PANEEL PEAMINE-190 | RF PANEEL PEAMINE-190
RF PANEEL PEAMINE-189 | RF PANEEL PEAMINE-189
RF PANEEL PEAMINE-231 | RF PANEEL PEAMINE-231

# IfcPlate: Main Panel 915 x 1195 x 33 (7)
In: 1. korrus
Classification: 1.15 IfcPlateType (plaat) (RKAS BIM + ARCHICAD Classification); Material: _KLAAS - kirgas
Pset_PlateCommon - Reference: Built-in CW Panel
AR_001-002 - 002_Tüüp: Built-in CW Panel
AC_Pset_RenovationAndPhasing - Renovation Status: Undefined
Name | 001_Nimetus
RF PANEEL PEAMINE-214 | RF PANEEL PEAMINE-214
RF PANEEL PEAMINE-193 | RF PANEEL PEAMINE-193
RF PANEEL PEAMINE-198 | RF PANEEL PEAMINE-198
RF PANEEL PEAMINE-203 | RF PANEEL PEAMINE-203
RF PANEEL PEAMINE-208 | RF PANEEL PEAMINE-208
RF PANEEL PEAMINE-220 | RF PANEEL PEAMINE-220
RF PANEEL PEAMINE-226 | RF PANEEL PEAMINE-226

# IfcPlate: Main Panel 915 x 1220 x 33 (34)
In: 1. korrus
Classification: 1.15 IfcPlateType (plaat) (RKAS BIM + ARCHICAD Classification); Material: _KLAAS - kirgas
Pset_PlateCommon - Reference: Built-in CW Panel
AR_001-002 - 002_Tüüp: Built-in CW Panel
AC_Pset_RenovationAndPhasing - Renovation Status: Undefined
Name | 001_Nimetus
RF PANEEL PEAMINE-195 | RF PANEEL PEAMINE-195
RF PANEEL PEAMINE-196 | RF PANEEL PEAMINE-196
RF PANEEL PEAMINE-197 | RF PANEEL PEAMINE-197
RF PANEEL PEAMINE-200 | RF PANEEL PEAMINE-200
RF PANEEL PEAMINE-201 | RF PANEEL PEAMINE-201
RF PANEEL PEAMINE-202 | RF PANEEL PEAMINE-202
RF PANEEL PEAMINE-205 | RF PANEEL PEAMINE-205
RF PANEEL PEAMINE-206 | RF PANEEL PEAMINE-206
RF PANEEL PEAMINE-207 | RF PANEEL PEAMINE-207
RF PANEEL PEAMINE-210 | RF PANEEL PEAMINE-210
RF PANEEL PEAMINE-211 | RF PANEEL PEAMINE-211
RF PANEEL PEAMINE-212 | RF PANEEL PEAMINE-212
RF PANEEL PEAMINE-216 | RF PANEEL PEAMINE-216
RF PANEEL PEAMINE-217 | RF PANEEL PEAMINE-217
RF PANEEL PEAMINE-218 | RF PANEEL PEAMINE-218
RF PANEEL PEAMINE-222 | RF PANEEL PEAMINE-222
RF PANEEL PEAMINE-223 | RF PANEEL PEAMINE-223
RF PANEEL PEAMINE-224 | RF PANEEL PEAMINE-224
RF PANEEL PEAMINE-227 | RF PANEEL PEAMINE-227
RF PANEEL PEAMINE-228 | RF PANEEL PEAMINE-228
RF PANEEL PEAMINE-229 | RF PANEEL PEAMINE-229
RF PANEEL PEAMINE-230 | RF PANEEL PEAMINE-230
RF PANEEL PEAMINE-234 | RF PANEEL PEAMINE-234
RF PANEEL PEAMINE-235 | RF PANEEL PEAMINE-235
RF PANEEL PEAMINE-236 | RF PANEEL PEAMINE-236
RF PANEEL PEAMINE-240 | RF PANEEL PEAMINE-240
RF PANEEL PEAMINE-241 | RF PANEEL PEAMINE-241
RF PANEEL PEAMINE-242 | RF PANEEL PEAMINE-242
RF PANEEL PEAMINE-215 | RF PANEEL PEAMINE-215
RF PANEEL PEAMINE-194 | RF PANEEL PEAMINE-194
RF PANEEL PEAMINE-221 | RF PANEEL PEAMINE-221
RF PANEEL PEAMINE-199 | RF PANEEL PEAMINE-199
RF PANEEL PEAMINE-204 | RF PANEEL PEAMINE-204
RF PANEEL PEAMINE-209 | RF PANEEL PEAMINE-209

# IfcPlate: Main Panel 950 x 865 x 20, RF PANEEL PEAMINE-081
In: 1. korrus
Classification: 1.15 IfcPlateType (plaat) (RKAS BIM + ARCHICAD Classification); Material: _GENEERILINE MATERJAL KLAAS
Pset_PlateCommon - Reference: Built-in CW Panel
AR_001-002 - 001_Nimetus: RF PANEEL PEAMINE-081; 002_Tüüp: Built-in CW Panel
AC_Pset_RenovationAndPhasing - Renovation Status: Undefined

# IfcPlate: Main Panel 960 x 2265 x 20, RF PANEEL PEAMINE-056
In: 1. korrus
Classification: 1.15 IfcPlateType (plaat) (RKAS BIM + ARCHICAD Classification); Material: _GENEERILINE MATERJAL KLAAS
Pset_PlateCommon - Reference: Built-in CW Panel
AR_001-002 - 001_Nimetus: RF PANEEL PEAMINE-056; 002_Tüüp: Built-in CW Panel
AC_Pset_RenovationAndPhasing - Renovation Status: Undefined

# IfcPlate: Main Panel 960 x 865 x 20, RF PANEEL PEAMINE-057
In: 1. korrus
Classification: 1.15 IfcPlateType (plaat) (RKAS BIM + ARCHICAD Classification); Material: _GENEERILINE MATERJAL KLAAS
Pset_PlateCommon - Reference: Built-in CW Panel
AR_001-002 - 001_Nimetus: RF PANEEL PEAMINE-057; 002_Tüüp: Built-in CW Panel
AC_Pset_RenovationAndPhasing - Renovation Status: Undefined

# IfcPlate: Turvaklaas 1374 x 1115 x 48, Panel-Turvaklaas-149
In: 1. korrus
Type - PredefinedType: CURTAIN_PANEL
Classification: Curtain Wall Panel (RKAS BIM + ARCHICAD Classification); Material: _KLAAS - kirgas
AC_Pset_RenovationAndPhasing - Renovation Status: Undefined

# IfcPlate: Turvaklaas 1374 x 1140 x 48, Panel-Turvaklaas-151
In: 1. korrus
Type - PredefinedType: CURTAIN_PANEL
Classification: Curtain Wall Panel (RKAS BIM + ARCHICAD Classification); Material: _KLAAS - kirgas
AC_Pset_RenovationAndPhasing - Renovation Status: Undefined

# IfcPlate: Turvaklaas 1385 x 1195 x 33 (2)
In: 1. korrus
Type - PredefinedType: CURTAIN_PANEL
Classification: Curtain Wall Panel (RKAS BIM + ARCHICAD Classification); Material: _KLAAS - kirgas
AC_Pset_RenovationAndPhasing - Renovation Status: Undefined
Name
Panel-Turvaklaas-005
Panel-Turvaklaas-006

# IfcPlate: Turvaklaas 1404 x 1115 x 48, Panel-Turvaklaas-088
In: 1. korrus
Type - PredefinedType: CURTAIN_PANEL
Classification: Curtain Wall Panel (RKAS BIM + ARCHICAD Classification); Material: _KLAAS - kirgas
AC_Pset_RenovationAndPhasing - Renovation Status: Undefined

# IfcPlate: Turvaklaas 1404 x 1140 x 48, Panel-Turvaklaas-047
In: 1. korrus
Type - PredefinedType: CURTAIN_PANEL
Classification: Curtain Wall Panel (RKAS BIM + ARCHICAD Classification); Material: _KLAAS - kirgas
AC_Pset_RenovationAndPhasing - Renovation Status: Undefined

# IfcPlate: Turvaklaas 1420 x 1115 x 48 (34)
In: 1. korrus
Type - PredefinedType: CURTAIN_PANEL
Classification: Curtain Wall Panel (RKAS BIM + ARCHICAD Classification); Material: _KLAAS - kirgas
AC_Pset_RenovationAndPhasing - Renovation Status: Undefined
Name
16 x Panel-Turvaklaas-027
Panel-Turvaklaas-070
Panel-Turvaklaas-071
Panel-Turvaklaas-072
Panel-Turvaklaas-073
Panel-Turvaklaas-074
Panel-Turvaklaas-075
Panel-Turvaklaas-076
Panel-Turvaklaas-077
Panel-Turvaklaas-078
Panel-Turvaklaas-079
Panel-Turvaklaas-080
Panel-Turvaklaas-081
Panel-Turvaklaas-082
Panel-Turvaklaas-083
Panel-Turvaklaas-084
Panel-Turvaklaas-085
Panel-Turvaklaas-086
Panel-Turvaklaas-087

# IfcPlate: Turvaklaas 1420 x 1140 x 48 (34)
In: 1. korrus
Type - PredefinedType: CURTAIN_PANEL
Classification: Curtain Wall Panel (RKAS BIM + ARCHICAD Classification); Material: _KLAAS - kirgas
AC_Pset_RenovationAndPhasing - Renovation Status: Undefined
Name
Panel-Turvaklaas-029
Panel-Turvaklaas-030
Panel-Turvaklaas-031
Panel-Turvaklaas-032
Panel-Turvaklaas-033
Panel-Turvaklaas-034
Panel-Turvaklaas-035
Panel-Turvaklaas-036
Panel-Turvaklaas-037
Panel-Turvaklaas-038
Panel-Turvaklaas-039
Panel-Turvaklaas-040
Panel-Turvaklaas-041
Panel-Turvaklaas-042
Panel-Turvaklaas-043
Panel-Turvaklaas-044
Panel-Turvaklaas-048
Panel-Turvaklaas-049
Panel-Turvaklaas-050
Panel-Turvaklaas-051
Panel-Turvaklaas-052
Panel-Turvaklaas-053
Panel-Turvaklaas-054
Panel-Turvaklaas-055
Panel-Turvaklaas-056
Panel-Turvaklaas-057
Panel-Turvaklaas-058
Panel-Turvaklaas-059
Panel-Turvaklaas-060
Panel-Turvaklaas-061
Panel-Turvaklaas-062
Panel-Turvaklaas-063
Panel-Turvaklaas-064
Panel-Turvaklaas-065

# IfcPlate: Turvaklaas 1420 x 1195 x 33 (4)
In: 1. korrus
Type - PredefinedType: CURTAIN_PANEL
Classification: Curtain Wall Panel (RKAS BIM + ARCHICAD Classification); Material: _KLAAS - kirgas
AC_Pset_RenovationAndPhasing - Renovation Status: Undefined
Name
Panel-Turvaklaas-001
Panel-Turvaklaas-002
Panel-Turvaklaas-003
Panel-Turvaklaas-004

# IfcRailing: IfcRailing (4)
In: 4. TEHNO korrus
Classification: 1.16 IfcRailingType (piire) (RKAS BIM + ARCHICAD Classification); Material: _METALL - kuumtsingitud teras
Pset_RailingCommon - Reference: Rail 25
AR_001-002 - 001_Nimetus: Piirde Ülaosa - 001; 002_Tüüp: Rail 25
AC_Pset_RenovationAndPhasing - Renovation Status: New

# IfcRailing: Railing Type (2)
In: 4. TEHNO korrus
Classification: 1.16 IfcRailingType (piire) (RKAS BIM + ARCHICAD Classification)
Pset_RailingCommon - IsExternal: no
AR_001-002 - 001_Nimetus: PIIRE
AC_Pset_RenovationAndPhasing - Renovation Status: New
Name | Reference = 002_Tüüp
PIIRE | TR-07-käsipuu
PIIRE | TR-08-käsipuu

# IfcSlab: KL-CLT-14/1_ribiplaadi plaat 141, Ribiplaat
In: 4. TEHNO korrus
Type - PredefinedType: ROOF
Classification: 1.19 IfcSlabType.ROOF (katus) (RKAS BIM + ARCHICAD Classification)
Pset_SlabCommon - Reference: KL-CLT-14/1; LoadBearing: yes; IsExternal: yes
AR_Katus - 001_Nimetus: Ribiplaat; 205_Tüüp: KL-CLT-14/1; 325_Helipidavus: nõudeid ei esitata; 330_Tulekindlus: REI 60; 340_Soojusläbivus: 0.1; 520_Pindala: 157.448 m2
AR_Vahelagi - 001_Nimetus: Ribiplaat; 205_Tüüp: KL-CLT-14/1; 325_Helipidavus: nõudeid ei esitata; 330_Tulekindlus: REI 60; 340_Soojusläbivus: 0.1
AC_Pset_RenovationAndPhasing - Renovation Status: New

# IfcSlab: KL-CLT-20/_soojust. 350 PVCta 551, Lamekatus
In: 4. TEHNO korrus
Type - PredefinedType: ROOF
Classification: 1.19 IfcSlabType.ROOF (katus) (RKAS BIM + ARCHICAD Classification)
Pset_SlabCommon - Reference: KL-CLT-20/; LoadBearing: yes; IsExternal: yes
AR_Katus - 001_Nimetus: Lamekatus; 205_Tüüp: KL-CLT-20/; 325_Helipidavus: nõudeid ei esitata; 330_Tulekindlus: REI 60; 340_Soojusläbivus: 0.1; 520_Pindala: 504.226 m2
AR_Vahelagi - 001_Nimetus: Lamekatus; 205_Tüüp: KL-CLT-20/; 325_Helipidavus: nõudeid ei esitata; 330_Tulekindlus: REI 60; 340_Soojusläbivus: 0.1
AC_Pset_RenovationAndPhasing - Renovation Status: New

# IfcSlab: KL-CLT-24/_CLT 240 ilma PVCta 591 (5)
Type - PredefinedType: ROOF
Classification: 1.19 IfcSlabType.ROOF (katus) (RKAS BIM + ARCHICAD Classification)
Pset_SlabCommon - Reference: KL-CLT-24/; LoadBearing: yes; IsExternal: yes
AR_Katus - 001_Nimetus: Lamekatus; 205_Tüüp: KL-CLT-24/; 325_Helipidavus: nõudeid ei esitata; 330_Tulekindlus: REI 60; 340_Soojusläbivus: 0.1
AR_Vahelagi - 001_Nimetus: Lamekatus; 205_Tüüp: KL-CLT-24/; 325_Helipidavus: nõudeid ei esitata; 330_Tulekindlus: REI 60; 340_Soojusläbivus: 0.1
AC_Pset_RenovationAndPhasing - Renovation Status: New
Name | In | 520_Pindala (m2)
Lamekatus | 3. korrus | 401.68
Lamekatus | 4. TEHNO korrus | 801.211
Lamekatus | 4. TEHNO korrus | 82.1389
Lamekatus | 4. TEHNO korrus | 307.986
Lamekatus | 4. TEHNO korrus | 59.8246

# IfcSlab: KL-CLT-28/2_PVC 883, Vahelagi
In: 4. TEHNO korrus
Classification: 1.20 IfcSlabType (vahelagi) (RKAS BIM + ARCHICAD Classification)
Pset_SlabCommon - Reference: KL-CLT-28/2; LoadBearing: yes; IsExternal: no
AR_Katus - 001_Nimetus: Vahelagi; 205_Tüüp: KL-CLT-28/2; 325_Helipidavus: nõudeid ei esitata; 330_Tulekindlus: REI 60; 340_Soojusläbivus: 0.1
AR_Vahelagi - 001_Nimetus: Vahelagi; 205_Tüüp: KL-CLT-28/2; 325_Helipidavus: nõudeid ei esitata; 330_Tulekindlus: REI 60; 335_Välispiire: no; 340_Soojusläbivus: 0.1; 500_Kandev: TRUE; 505_Paksus: 883 mm; 510_Bruto_pindala: 21.648 m2; 515_Neto_pindala: 0.000327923 m2
AC_Pset_RenovationAndPhasing - Renovation Status: New

# IfcSlab: KL-CLT-28/_PVCta 631, Lamekatus
In: 2. korrus
Type - PredefinedType: ROOF
Classification: 1.19 IfcSlabType.ROOF (katus) (RKAS BIM + ARCHICAD Classification)
Pset_SlabCommon - Reference: KL-CLT-28/; LoadBearing: yes; IsExternal: yes
AR_Katus - 001_Nimetus: Lamekatus; 205_Tüüp: KL-CLT-28/; 325_Helipidavus: nõudeid ei esitata; 330_Tulekindlus: REI 60; 340_Soojusläbivus: 0.1; 520_Pindala: 66.1251 m2
AR_Vahelagi - 001_Nimetus: Lamekatus; 205_Tüüp: KL-CLT-28/; 325_Helipidavus: nõudeid ei esitata; 330_Tulekindlus: REI 60; 340_Soojusläbivus: 0.1
AC_Pset_RenovationAndPhasing - Renovation Status: New

# IfcSlab: KL-CLT-72/1_viimistluseta klass 331 491 (2)
In: 4. TEHNO korrus
Type - PredefinedType: ROOF
Classification: 1.19 IfcSlabType.ROOF (katus) (RKAS BIM + ARCHICAD Classification)
Pset_SlabCommon - Reference: KL-CLT-72/1; LoadBearing: yes; IsExternal: yes
AR_Katus - 205_Tüüp: KL-CLT-72/1; 325_Helipidavus: nõudeid ei esitata; 330_Tulekindlus: REI 60; 340_Soojusläbivus: 0.1
AR_Vahelagi - 205_Tüüp: KL-CLT-72/1; 325_Helipidavus: nõudeid ei esitata; 330_Tulekindlus: REI 60; 340_Soojusläbivus: 0.1
AC_Pset_RenovationAndPhasing - Renovation Status: New
Name | AR_Katus, 001_Nimetus = AR_Vahelagi, 001_Nimetus | 520_Pindala (m2)
Ribiplaat | Ribiplaat | 78.8289
Lamekatus | Lamekatus | 69.9077

# IfcSlab: KL-MK-13/1_spordisaali lagi 511, Lamekatus
In: 3. korrus
Type - PredefinedType: ROOF
Classification: 1.19 IfcSlabType.ROOF (katus) (RKAS BIM + ARCHICAD Classification)
Pset_SlabCommon - Reference: KL-MK-13/1; LoadBearing: yes; IsExternal: yes
AR_Katus - 001_Nimetus: Lamekatus; 205_Tüüp: KL-MK-13/1; 325_Helipidavus: nõudeid ei esitata; 330_Tulekindlus: REI 60; 340_Soojusläbivus: 0.1; 520_Pindala: 478.089 m2
AR_Vahelagi - 001_Nimetus: Lamekatus; 205_Tüüp: KL-MK-13/1; 325_Helipidavus: nõudeid ei esitata; 330_Tulekindlus: REI 60; 340_Soojusläbivus: 0.1
AC_Pset_RenovationAndPhasing - Renovation Status: New

# IfcSlab: KL-MK-13/2_soojustus 350+PVC tehnoruumi lagi 482 (4)
In: Katus
Type - PredefinedType: ROOF
Classification: 1.19 IfcSlabType.ROOF (katus) (RKAS BIM + ARCHICAD Classification)
Pset_SlabCommon - Reference: KL-MK-13/2; LoadBearing: yes; IsExternal: yes
AR_Katus - 001_Nimetus: Viilkatus; 205_Tüüp: KL-MK-13/2; 325_Helipidavus: nõudeid ei esitata; 330_Tulekindlus: REI 60; 340_Soojusläbivus: 0.1
AR_Vahelagi - 001_Nimetus: Viilkatus; 205_Tüüp: KL-MK-13/2; 325_Helipidavus: nõudeid ei esitata; 330_Tulekindlus: REI 60; 340_Soojusläbivus: 0.1
AC_Pset_RenovationAndPhasing - Renovation Status: New
Name | 520_Pindala (m2)
Viilkatus | 97.0135
Viilkatus | 109.659
Viilkatus | 0.361508
Viilkatus | 0.341539

# IfcSlab: KL-MK-13/3_spordisaali lagi kaldtugede all 541, Katusekalded
In: 3. korrus
Type - PredefinedType: ROOF
Classification: 1.19 IfcSlabType.ROOF (katus) (RKAS BIM + ARCHICAD Classification)
Pset_SlabCommon - Reference: KL-MK-13/3; LoadBearing: yes; IsExternal: yes
AR_Katus - 001_Nimetus: Katusekalded; 205_Tüüp: KL-MK-13/3; 325_Helipidavus: nõudeid ei esitata; 330_Tulekindlus: nõudeid ei esitata; 340_Soojusläbivus: 0; 520_Pindala: 147.71 m2
AR_Vahelagi - 001_Nimetus: Katusekalded; 205_Tüüp: KL-MK-13/3; 325_Helipidavus: nõudeid ei esitata; 330_Tulekindlus: nõudeid ei esitata; 340_Soojusläbivus: 0
AC_Pset_RenovationAndPhasing - Renovation Status: New

# IfcSlab: KL-PK-19/1_soojust. 350 PVCta 494, Lamekatus
In: 4. TEHNO korrus
Type - PredefinedType: ROOF
Classification: 1.19 IfcSlabType.ROOF (katus) (RKAS BIM + ARCHICAD Classification)
Pset_SlabCommon - Reference: KL-PK-19/1; LoadBearing: yes; IsExternal: yes
AR_Katus - 001_Nimetus: Lamekatus; 205_Tüüp: KL-PK-19/1; 325_Helipidavus: nõudeid ei esitata; 330_Tulekindlus: REI 60; 340_Soojusläbivus: 0.1; 520_Pindala: 11.9968 m2
AR_Vahelagi - 001_Nimetus: Lamekatus; 205_Tüüp: KL-PK-19/1; 325_Helipidavus: nõudeid ei esitata; 330_Tulekindlus: REI 60; 340_Soojusläbivus: 0.1
AC_Pset_RenovationAndPhasing - Renovation Status: New

# IfcSlab: KL-PK-20/1_parapeti kaldtoed 74 (21)
Type - PredefinedType: ROOF
Classification: 1.19 IfcSlabType.ROOF (katus) (RKAS BIM + ARCHICAD Classification)
Pset_SlabCommon - Reference: KL-PK-20/1; IsExternal: yes
AR_Katus - 205_Tüüp: KL-PK-20/1; 325_Helipidavus: nõudeid ei esitata; 330_Tulekindlus: nõudeid ei esitata
AR_Vahelagi - 205_Tüüp: KL-PK-20/1; 325_Helipidavus: nõudeid ei esitata; 330_Tulekindlus: nõudeid ei esitata
AC_Pset_RenovationAndPhasing - Renovation Status: New
Name | In | LoadBearing | AR_Katus, 001_Nimetus = AR_Vahelagi, 001_Nimetus | AR_Katus, 340_Soojusläbivus = AR_Vahelagi, 340_Soojusläbivus | 520_Pindala (m2)
Katusekalded | 3. korrus | yes | Katusekalded | 0 | 34.3469
Katusekalded | 3. korrus | yes | Katusekalded | 0 | 77.1682
Katusekalded | 3. korrus | yes | Katusekalded | 0 | 14.5771
Katusekalded | 3. korrus | yes | Katusekalded | 0 | 100.252
Katusekalded | 3. korrus | yes | Katusekalded | 0 | 49.541
šahti katus | 4. TEHNO korrus | no | šahti katus | 0 | 70.2963
šahti katus | 4. TEHNO korrus | no | šahti katus | 0 | 16.4856
Katusekalded | 4. TEHNO korrus | yes | Katusekalded | 0 | 73.7758
Katusekalded | 4. TEHNO korrus | yes | Katusekalded | 0.1 | 150.575
Katusekalded | 4. TEHNO korrus | yes | Katusekalded | 0 | 38.405
Katusekalded | 4. TEHNO korrus | yes | Katusekalded | 0.1 | 42.4197
Katusekalded | 4. TEHNO korrus | yes | Katusekalded | 0 | 35.9035
Katusekalded | 4. TEHNO korrus | yes | Katusekalded | 0.1 | 99.18
Katusekalded | 4. TEHNO korrus | yes | Katusekalded | 0 | 0.150337
Katusekalded | 4. TEHNO korrus | yes | Katusekalded | 0 | 0.14953
Katusekalded | 4. TEHNO korrus | yes | Katusekalded | 0 | 0.150593
Katusekalded | 4. TEHNO korrus | yes | Katusekalded | 0 | 0.150373
Katusekalded | 4. TEHNO korrus | yes | Katusekalded | 0 | 0.150541
Katusekalded | 4. TEHNO korrus | yes | Katusekalded | 0 | 0.150516
Katusekalded | 4. TEHNO korrus | yes | Katusekalded | 0.1 | 1.56612
Katusekalded | 4. TEHNO korrus | yes | Katusekalded | 0.1 | 0.812069

# IfcSlab: KL-RB-10_100 mm betoonplaat trenaazimatil katusekorstende toetuseks 125 (7)
In: 4. TEHNO korrus
Type - PredefinedType: ROOF
Classification: 1.19 IfcSlabType.ROOF (katus) (RKAS BIM + ARCHICAD Classification)
Pset_SlabCommon - Reference: KL-RB-10; LoadBearing: no; IsExternal: yes
AR_Katus - 001_Nimetus: Korstende toetusplaat; 205_Tüüp: KL-RB-10; 325_Helipidavus: nõudeid ei esitata; 330_Tulekindlus: nõudeid ei esitata; 340_Soojusläbivus: 0
AR_Vahelagi - 001_Nimetus: Korstende toetusplaat; 205_Tüüp: KL-RB-10; 325_Helipidavus: nõudeid ei esitata; 330_Tulekindlus: nõudeid ei esitata; 340_Soojusläbivus: 0
AC_Pset_RenovationAndPhasing - Renovation Status: New
Name | 520_Pindala (m2)
2 x Korstende toetusplaat | 1.44115
Korstende toetusplaat | 0.896179
Korstende toetusplaat | 1.01812
Korstende toetusplaat | 0.422874
Korstende toetusplaat | 1.0008
Korstende toetusplaat | 0.544973

# IfcSlab: KL-RB-22/2_soojust 350 571 (4)
Type - PredefinedType: ROOF
Classification: 1.19 IfcSlabType.ROOF (katus) (RKAS BIM + ARCHICAD Classification)
Pset_SlabCommon - Reference: KL-RB-22/2; LoadBearing: yes; IsExternal: yes
AR_Katus - 001_Nimetus: Lamekatus; 205_Tüüp: KL-RB-22/2; 325_Helipidavus: nõudeid ei esitata; 330_Tulekindlus: REI 60; 340_Soojusläbivus: 0.1
AR_Vahelagi - 001_Nimetus: Lamekatus; 205_Tüüp: KL-RB-22/2; 325_Helipidavus: nõudeid ei esitata; 330_Tulekindlus: REI 60; 340_Soojusläbivus: 0.1
AC_Pset_RenovationAndPhasing - Renovation Status: New
Name | In | 520_Pindala (m2)
Lamekatus | 2. korrus | 6.95958
Lamekatus | 4. TEHNO korrus | 45.5273
Lamekatus | 4. TEHNO korrus | 25.0559
Lamekatus | 4. TEHNO korrus | 11.5749

# IfcSlab: KL-RB-22/_PVCta 571 (2)
Type - PredefinedType: ROOF
Classification: 1.19 IfcSlabType.ROOF (katus) (RKAS BIM + ARCHICAD Classification)
Pset_SlabCommon - Reference: KL-RB-22/; LoadBearing: yes; IsExternal: yes
AR_Katus - 001_Nimetus: Lamekatus; 205_Tüüp: KL-RB-22/; 325_Helipidavus: nõudeid ei esitata; 330_Tulekindlus: REI 60; 340_Soojusläbivus: 0.1
AR_Vahelagi - 001_Nimetus: Lamekatus; 205_Tüüp: KL-RB-22/; 325_Helipidavus: nõudeid ei esitata; 330_Tulekindlus: REI 60; 340_Soojusläbivus: 0.1
AC_Pset_RenovationAndPhasing - Renovation Status: New
Name | In | 520_Pindala (m2)
Lamekatus | 2. korrus | 29.9862
Lamekatus | 4. TEHNO korrus | 13.1047

# IfcSlab: KL-S-35_(KL-24/2, KL-28/2, KL-RB-22/2) +PVC 382 (89)
Type - PredefinedType: ROOF
Classification: 1.19 IfcSlabType.ROOF (katus) (RKAS BIM + ARCHICAD Classification)
Pset_SlabCommon - Reference: KL-S-35; LoadBearing: no; IsExternal: yes
AR_Katus - 001_Nimetus: Katusekalded; 205_Tüüp: KL-S-35; 325_Helipidavus: nõudeid ei esitata; 340_Soojusläbivus: 0.1
AR_Vahelagi - 001_Nimetus: Katusekalded; 205_Tüüp: KL-S-35; 325_Helipidavus: nõudeid ei esitata; 340_Soojusläbivus: 0.1
AC_Pset_RenovationAndPhasing - Renovation Status: New
Name | In | AR_Katus, 330_Tulekindlus = AR_Vahelagi, 330_Tulekindlus | 520_Pindala (m2)
Katusekalded | 3. korrus | REI 60 | 83.6982
Katusekalded | 3. korrus | REI 60 | 21.0265
Katusekalded | 3. korrus | REI 60 | 17.8656
Katusekalded | 3. korrus | REI 60 | 17.838
Katusekalded | 3. korrus | REI 60 | 25.4219
Katusekalded | 3. korrus | REI 60 | 17.3561
Katusekalded | 3. korrus | REI 60 | 17.3221
Katusekalded | 3. korrus | REI 60 | 25.4875
Katusekalded | 3. korrus | REI 60 | 42.7731
Katusekalded | 3. korrus | REI 60 | 66.0548
Katusekalded | 3. korrus | REI 60 | 11.759
Katusekalded | 3. korrus | REI 60 | 1.0246
Katusekalded | 3. korrus | REI 60 | 29.4948
Katusekalded | 3. korrus | REI 60 | 12.3078
Katusekalded | 3. korrus | REI 60 | 41.0336
Katusekalded | 3. korrus | REI 60 | 196.596
8 x Katusekalded | 3. korrus | REI 60 | 0.28359
2 x Katusekalded | 3. korrus | nõudeid ei esitata | 0.394995
2 x Katusekalded | 3. korrus | nõudeid ei esitata | 0.214039
2 x Katusekalded | 3. korrus | nõudeid ei esitata | 0.196514
Katusekalded | 3. korrus | REI 60 | 0.542274
Katusekalded | 3. korrus | REI 60 | 0.398137
Katusekalded | 3. korrus | REI 60 | 0.453212
Katusekalded | 3. korrus | REI 60 | 0.468778
Katusekalded | 3. korrus | REI 60 | 0.39484
Katusekalded | 3. korrus | REI 60 | 0.394525
Katusekalded | 4. TEHNO korrus | REI 60 | 8.24151
Katusekalded | 4. TEHNO korrus | REI 60 | 7.51862
Katusekalded | 4. TEHNO korrus | REI 60 | 9.43479
Katusekalded | 4. TEHNO korrus | REI 60 | 9.02673
Katusekalded | 4. TEHNO korrus | REI 60 | 22.6391
Katusekalded | 4. TEHNO korrus | REI 60 | 33.3161
Katusekalded | 4. TEHNO korrus | REI 60 | 22.3598
Katusekalded | 4. TEHNO korrus | REI 60 | 26.2062
Katusekalded | 4. TEHNO korrus | REI 60 | 9.58921
Katusekalded | 4. TEHNO korrus | REI 60 | 7.8592
Katusekalded | 4. TEHNO korrus | REI 60 | 8.05035
Katusekalded | 4. TEHNO korrus | REI 60 | 7.62423
Katusekalded | 4. TEHNO korrus | REI 60 | 8.33163
Katusekalded | 4. TEHNO korrus | REI 60 | 9.44699
Katusekalded | 4. TEHNO korrus | REI 60 | 6.6197
Katusekalded | 4. TEHNO korrus | REI 60 | 4.25056
Katusekalded | 4. TEHNO korrus | REI 60 | 9.37243
Katusekalded | 4. TEHNO korrus | REI 60 | 8.53564
Katusekalded | 4. TEHNO korrus | REI 60 | 9.44916
Katusekalded | 4. TEHNO korrus | REI 60 | 14.1346
Katusekalded | 4. TEHNO korrus | REI 60 | 14.2312
Katusekalded | 4. TEHNO korrus | REI 60 | 14.2366
Katusekalded | 4. TEHNO korrus | REI 60 | 12.1474
Katusekalded | 4. TEHNO korrus | REI 60 | 21.9388
Katusekalded | 4. TEHNO korrus | REI 60 | 23.2963
Katusekalded | 4. TEHNO korrus | REI 60 | 15.9215
Katusekalded | 4. TEHNO korrus | REI 60 | 16.8239
Katusekalded | 4. TEHNO korrus | REI 60 | 17.2368
Katusekalded | 4. TEHNO korrus | REI 60 | 16.1314
Katusekalded | 4. TEHNO korrus | REI 60 | 16.1231
Katusekalded | 4. TEHNO korrus | REI 60 | 12.5414
Katusekalded | 4. TEHNO korrus | REI 60 | 14.5726
Katusekalded | 4. TEHNO korrus | REI 60 | 20.4059
Katusekalded | 4. TEHNO korrus | REI 60 | 13.706
Katusekalded | 4. TEHNO korrus | REI 60 | 14.1753
Katusekalded | 4. TEHNO korrus | REI 60 | 11.4597
2 x Katusekalded | 4. TEHNO korrus | REI 60 | 9.06714
Katusekalded | 4. TEHNO korrus | REI 60 | 11.2364
Katusekalded | 4. TEHNO korrus | REI 60 | 12.6583
Katusekalded | 4. TEHNO korrus | REI 60 | 9.43047
Katusekalded | 4. TEHNO korrus | REI 60 | 10.2207
Katusekalded | 4. TEHNO korrus | REI 60 | 11.6581
Katusekalded | 4. TEHNO korrus | REI 60 | 9.68574
2 x Katusekalded | 4. TEHNO korrus | REI 60 | 0.350345
Katusekalded | 4. TEHNO korrus | REI 60 | 10.2112
Katusekalded | 4. TEHNO korrus | REI 60 | 10.1846
Katusekalded | 4. TEHNO korrus | REI 60 | 3.61527
Katusekalded | 4. TEHNO korrus | REI 60 | 4.41777
Katusekalded | 4. TEHNO korrus | REI 60 | 3.81971
Katusekalded | 4. TEHNO korrus | REI 60 | 2.62604
Katusekalded | 4. TEHNO korrus | REI 60 | 14.4989

# IfcSlab: KL-S-65_(KL-24/1, KL-14, KL-RB-22/3)+PVC 682 (15)
Type - PredefinedType: ROOF
Classification: 1.19 IfcSlabType.ROOF (katus) (RKAS BIM + ARCHICAD Classification)
Pset_SlabCommon - Reference: KL-S-65; IsExternal: yes
AR_Katus - 205_Tüüp: KL-S-65; 325_Helipidavus: nõudeid ei esitata; 330_Tulekindlus: REI 60; 340_Soojusläbivus: 0.1
AR_Vahelagi - 205_Tüüp: KL-S-65; 325_Helipidavus: nõudeid ei esitata; 330_Tulekindlus: REI 60; 340_Soojusläbivus: 0.1
AC_Pset_RenovationAndPhasing - Renovation Status: New
Name | In | LoadBearing | AR_Katus, 001_Nimetus = AR_Vahelagi, 001_Nimetus | 520_Pindala (m2)
Katusekalded | 3. korrus | no | Katusekalded | 59.1077
Katusekalded | 3. korrus | no | Katusekalded | 82.601
Katusekalded | 3. korrus | no | Katusekalded | 42.918
Katusekalded | 3. korrus | no | Katusekalded | 47.6022
Katusekalded | 3. korrus | no | Katusekalded | 1.05049
Katusekalded | 3. korrus | no | Katusekalded | 8.29209
Katusekalded | 3. korrus | no | Katusekalded | 1.03028
Katusekalded | 4. TEHNO korrus | no | Katusekalded | 431.745
Katusekalded | 4. TEHNO korrus | no | Katusekalded | 31.7566
Katusekalded | 4. TEHNO korrus | no | Katusekalded | 271.017
Katusekalded | 4. TEHNO korrus | no | Katusekalded | 61.0184
Katusekalded | 4. TEHNO korrus | no | Katusekalded | 60.2611
2 x Katusekalded | 4. TEHNO korrus | no | Katusekalded | 0.350223
Lamekatus | Katus | yes | Lamekatus | 164.578

# IfcSlab: PP-RBM-10/1_EPS 200 500 (4)
Classification: 1.20 IfcSlabType (vahelagi) (RKAS BIM + ARCHICAD Classification)
Pset_SlabCommon - Reference: PP-RBM-10/1; LoadBearing: yes
AR_Katus - 205_Tüüp: PP-RBM-10/1; 325_Helipidavus: nõudeid ei esitata; 330_Tulekindlus: nõudeid ei esitata; 340_Soojusläbivus: 0.1
AR_Vahelagi - 205_Tüüp: PP-RBM-10/1; 325_Helipidavus: nõudeid ei esitata; 330_Tulekindlus: nõudeid ei esitata; 340_Soojusläbivus: 0.1; 500_Kandev: TRUE; 505_Paksus: 500.3 mm; 510_Bruto_pindala: 0 m2; 515_Neto_pindala: 0 m2
AC_Pset_RenovationAndPhasing - Renovation Status: New
Name | In | IsExternal = 335_Välispiire | AR_Katus, 001_Nimetus = AR_Vahelagi, 001_Nimetus
Liftišaht | Vundament | yes | Liftišaht
3 x Põrand pinnasel | 1. korrus | no | Põrand pinnasel

# IfcSlab: PP-RBM-10/2_EPS 200+spordipõrand 589, Põrand pinnasel
In: 1. korrus
Classification: 1.20 IfcSlabType (vahelagi) (RKAS BIM + ARCHICAD Classification)
Pset_SlabCommon - Reference: PP-RBM-10/2; LoadBearing: yes; IsExternal: no
AR_Katus - 001_Nimetus: Põrand pinnasel; 205_Tüüp: PP-RBM-10/2; 325_Helipidavus: nõudeid ei esitata; 330_Tulekindlus: nõudeid ei esitata; 340_Soojusläbivus: 0.1
AR_Vahelagi - 001_Nimetus: Põrand pinnasel; 205_Tüüp: PP-RBM-10/2; 325_Helipidavus: nõudeid ei esitata; 330_Tulekindlus: nõudeid ei esitata; 335_Välispiire: no; 340_Soojusläbivus: 0.1; 500_Kandev: TRUE; 505_Paksus: 589.3 mm; 510_Bruto_pindala: 544.577 m2; 515_Neto_pindala: 544.577 m2
AC_Pset_RenovationAndPhasing - Renovation Status: New

# IfcSlab: PP-RBM-20/1_EPS 100+ betoon, mullakast 500 (3)
In: Vundament
Classification: 1.20 IfcSlabType (vahelagi) (RKAS BIM + ARCHICAD Classification)
Pset_SlabCommon - Reference: PP-RBM-20/1; LoadBearing: yes; IsExternal: yes
AR_Katus - 001_Nimetus: Taimekast; 205_Tüüp: PP-RBM-20/1; 340_Soojusläbivus: 0.1
AR_Vahelagi - 001_Nimetus: Taimekast; 205_Tüüp: PP-RBM-20/1; 335_Välispiire: yes; 340_Soojusläbivus: 0.1; 500_Kandev: TRUE; 505_Paksus: 500.2 mm
AC_Pset_RenovationAndPhasing - Renovation Status: New
Name | AR_Katus, 325_Helipidavus = AR_Vahelagi, 325_Helipidavus | AR_Katus, 330_Tulekindlus = AR_Vahelagi, 330_Tulekindlus | 510_Bruto_pindala (m2) = 515_Neto_pindala (m2)
Taimekast | nõudeid ei esitata | nõudeid ei esitata | 9.03604
Taimekast | - | REI 60 | 9.03604
Taimekast | nõudeid ei esitata | nõudeid ei esitata | 9.02702

# IfcSlab: VL-CLT-10/1_PVC kate aula kassettlagi 430, VAHELAGI
In: 3. korrus
Classification: 1.20 IfcSlabType (vahelagi) (RKAS BIM + ARCHICAD Classification)
Pset_SlabCommon - Reference: VL-CLT-10/1; LoadBearing: yes; IsExternal: no
AR_Katus - 001_Nimetus: VAHELAGI; 205_Tüüp: VL-CLT-10/1; 325_Helipidavus: 52 dB; 330_Tulekindlus: REI 60; 340_Soojusläbivus: 0
AR_Vahelagi - 001_Nimetus: VAHELAGI; 205_Tüüp: VL-CLT-10/1; 325_Helipidavus: 52 dB; 330_Tulekindlus: REI 60; 335_Välispiire: no; 340_Soojusläbivus: 0; 500_Kandev: TRUE; 505_Paksus: 430 mm; 510_Bruto_pindala: 281.146 m2; 515_Neto_pindala: 264.07 m2
AC_Pset_RenovationAndPhasing - Renovation Status: New

# IfcSlab: VL-CLT-24/1_lihvitud bet.- ventseadmete vahetasand 450, VAHELAGI
In: 2. korrus
Classification: 1.20 IfcSlabType (vahelagi) (RKAS BIM + ARCHICAD Classification)
Pset_SlabCommon - Reference: VL-CLT-24/1; LoadBearing: yes; IsExternal: no
AR_Katus - 001_Nimetus: VAHELAGI; 205_Tüüp: VL-CLT-24/1; 325_Helipidavus: 55 dB; 330_Tulekindlus: REI 90; 340_Soojusläbivus: 0
AR_Vahelagi - 001_Nimetus: VAHELAGI; 205_Tüüp: VL-CLT-24/1; 325_Helipidavus: 55 dB; 330_Tulekindlus: REI 90; 335_Välispiire: no; 340_Soojusläbivus: 0; 500_Kandev: TRUE; 505_Paksus: 450 mm; 510_Bruto_pindala: 0 m2; 515_Neto_pindala: 0 m2
AC_Pset_RenovationAndPhasing - Renovation Status: New

# IfcSlab: VL-CLT-28/1_PVC kate 430 (4)
Classification: 1.20 IfcSlabType (vahelagi) (RKAS BIM + ARCHICAD Classification)
Pset_SlabCommon - Reference: VL-CLT-28/1; LoadBearing: yes; IsExternal: no
AR_Katus - 001_Nimetus: VAHELAGI; 205_Tüüp: VL-CLT-28/1; 325_Helipidavus: 52 dB; 330_Tulekindlus: REI 60; 340_Soojusläbivus: 0
AR_Vahelagi - 001_Nimetus: VAHELAGI; 205_Tüüp: VL-CLT-28/1; 325_Helipidavus: 52 dB; 330_Tulekindlus: REI 60; 335_Välispiire: no; 340_Soojusläbivus: 0; 500_Kandev: TRUE; 505_Paksus: 430 mm
AC_Pset_RenovationAndPhasing - Renovation Status: New
Name | In | 510_Bruto_pindala (m2) | 515_Neto_pindala (m2)
VAHELAGI | 2. korrus | 1493.82 | 1351.14
VAHELAGI | 2. korrus | 163.056 | 150.497
VAHELAGI | 3. korrus | 36.8878 | 31.0981
VAHELAGI | 3. korrus | 1322.47 | 1162.13

# IfcSlab: VL-CLT-28/2_ aeroobika 520, VAHELAGI
In: 2. korrus
Classification: 1.20 IfcSlabType (vahelagi) (RKAS BIM + ARCHICAD Classification)
Pset_SlabCommon - Reference: VL-CLT-28/2; LoadBearing: yes; IsExternal: no
AR_Katus - 001_Nimetus: VAHELAGI; 205_Tüüp: VL-CLT-28/2; 325_Helipidavus: 55 dB; 330_Tulekindlus: REI 60; 340_Soojusläbivus: 0
AR_Vahelagi - 001_Nimetus: VAHELAGI; 205_Tüüp: VL-CLT-28/2; 325_Helipidavus: 55 dB; 330_Tulekindlus: REI 60; 335_Välispiire: no; 340_Soojusläbivus: 0; 500_Kandev: TRUE; 505_Paksus: 520 mm; 510_Bruto_pindala: 68.6647 m2; 515_Neto_pindala: 66.5876 m2
AC_Pset_RenovationAndPhasing - Renovation Status: New

# IfcSlab: VL-CLT-28/3_ jõusaal 520, VAHELAGI
In: 2. korrus
Classification: 1.20 IfcSlabType (vahelagi) (RKAS BIM + ARCHICAD Classification)
Pset_SlabCommon - Reference: VL-CLT-28/3; LoadBearing: yes; IsExternal: no
AR_Katus - 001_Nimetus: VAHELAGI; 205_Tüüp: VL-CLT-28/3; 325_Helipidavus: 55 dB; 330_Tulekindlus: REI 60; 340_Soojusläbivus: 0
AR_Vahelagi - 001_Nimetus: VAHELAGI; 205_Tüüp: VL-CLT-28/3; 325_Helipidavus: 55 dB; 330_Tulekindlus: REI 60; 335_Välispiire: no; 340_Soojusläbivus: 0; 500_Kandev: TRUE; 505_Paksus: 520 mm; 510_Bruto_pindala: 69.7778 m2; 515_Neto_pindala: 67.0239 m2
AC_Pset_RenovationAndPhasing - Renovation Status: New

# IfcSlab: VL-CLT-28/6_PVC konsoolne soojustatud põrand 1078, VAHELAGI
In: 3. korrus
Classification: 1.20 IfcSlabType (vahelagi) (RKAS BIM + ARCHICAD Classification)
Pset_SlabCommon - Reference: VL-CLT-28/6; LoadBearing: yes; IsExternal: yes
AR_Katus - 001_Nimetus: VAHELAGI; 205_Tüüp: VL-CLT-28/6; 325_Helipidavus: nõudeid ei esitata; 330_Tulekindlus: REI 60; 340_Soojusläbivus: 0.06
AR_Vahelagi - 001_Nimetus: VAHELAGI; 205_Tüüp: VL-CLT-28/6; 325_Helipidavus: nõudeid ei esitata; 330_Tulekindlus: REI 60; 335_Välispiire: yes; 340_Soojusläbivus: 0.06; 500_Kandev: TRUE; 505_Paksus: 1078 mm; 510_Bruto_pindala: 56.441 m2; 515_Neto_pindala: 53.3608 m2
AC_Pset_RenovationAndPhasing - Renovation Status: New

# IfcSlab: VL-CLT-28/7_tehnokambri vahelagi 510, Vahelagi
In: 4. TEHNO korrus
Classification: 1.20 IfcSlabType (vahelagi) (RKAS BIM + ARCHICAD Classification)
Pset_SlabCommon - Reference: VL-CLT-28/7; LoadBearing: yes; IsExternal: yes
AR_Katus - 001_Nimetus: Vahelagi; 205_Tüüp: VL-CLT-28/7; 325_Helipidavus: 60 dB; 330_Tulekindlus: REI 60; 340_Soojusläbivus: 0
AR_Vahelagi - 001_Nimetus: Vahelagi; 205_Tüüp: VL-CLT-28/7; 325_Helipidavus: 60 dB; 330_Tulekindlus: REI 60; 335_Välispiire: yes; 340_Soojusläbivus: 0; 500_Kandev: TRUE; 505_Paksus: 510 mm; 510_Bruto_pindala: 167.514 m2; 515_Neto_pindala: 157.943 m2
AC_Pset_RenovationAndPhasing - Renovation Status: New

# IfcSlab: VL-CLT-30/1_+PVC kate 443 (4)
Classification: 1.20 IfcSlabType (vahelagi) (RKAS BIM + ARCHICAD Classification)
Pset_SlabCommon - Reference: VL-CLT-30/1; LoadBearing: yes; IsExternal: no
AR_Katus - 001_Nimetus: VAHELAGI; 205_Tüüp: VL-CLT-30/1; 325_Helipidavus: 60 dB; 330_Tulekindlus: REI 60; 340_Soojusläbivus: 0
AR_Vahelagi - 001_Nimetus: VAHELAGI; 205_Tüüp: VL-CLT-30/1; 325_Helipidavus: 60 dB; 330_Tulekindlus: REI 60; 335_Välispiire: no; 340_Soojusläbivus: 0; 500_Kandev: TRUE; 505_Paksus: 443.1 mm
AC_Pset_RenovationAndPhasing - Renovation Status: New
Name | In | 510_Bruto_pindala (m2) | 515_Neto_pindala (m2)
VAHELAGI | 2. korrus | 196.659 | 185.451
VAHELAGI | 2. korrus | 59.8959 | 56.4492
VAHELAGI | 3. korrus | 196.662 | 184.999
VAHELAGI | 3. korrus | 59.671 | 55.4415

# IfcSlab: VL-CLT-30/2_+PVC kate muusika lagi 575 (2)
In: 3. korrus
Classification: 1.20 IfcSlabType (vahelagi) (RKAS BIM + ARCHICAD Classification)
Pset_SlabCommon - Reference: VL-CLT-30/2; LoadBearing: yes; IsExternal: no
AR_Katus - 001_Nimetus: VAHELAGI; 205_Tüüp: VL-CLT-30/2; 325_Helipidavus: 60 dB; 330_Tulekindlus: REI 60; 340_Soojusläbivus: 0
AR_Vahelagi - 001_Nimetus: VAHELAGI; 205_Tüüp: VL-CLT-30/2; 325_Helipidavus: 60 dB; 330_Tulekindlus: REI 60; 335_Välispiire: no; 340_Soojusläbivus: 0; 500_Kandev: TRUE; 505_Paksus: 575 mm
AC_Pset_RenovationAndPhasing - Renovation Status: New
Name | 510_Bruto_pindala (m2) | 515_Neto_pindala (m2)
VAHELAGI | 59.8995 | 57.4483
VAHELAGI | 13.7856 | 13.4666

# IfcSlab: VL-MK-10/1_ köögi tehno šahti lagi 35 dB 130 (2)
In: 2. korrus
Classification: 1.20 IfcSlabType (vahelagi) (RKAS BIM + ARCHICAD Classification)
Pset_SlabCommon - Reference: VL-MK-10/1; LoadBearing: yes; IsExternal: no
AR_Katus - 001_Nimetus: VAHELAGI; 205_Tüüp: VL-MK-10/1; 325_Helipidavus: 35 dB; 330_Tulekindlus: REI 60; 340_Soojusläbivus: 0
AR_Vahelagi - 001_Nimetus: VAHELAGI; 205_Tüüp: VL-MK-10/1; 325_Helipidavus: 35 dB; 330_Tulekindlus: REI 60; 335_Välispiire: no; 340_Soojusläbivus: 0; 500_Kandev: TRUE; 505_Paksus: 130 mm
AC_Pset_RenovationAndPhasing - Renovation Status: New
Name | 510_Bruto_pindala (m2) = 515_Neto_pindala (m2)
VAHELAGI | 11.6934
VAHELAGI | 7.07434

# IfcSlab: VL-MK-10/2_variseinte hor. osad - laeks 130, VAHELAGI
In: 2. korrus
Classification: 1.20 IfcSlabType (vahelagi) (RKAS BIM + ARCHICAD Classification)
Pset_SlabCommon - Reference: VL-MK-10/2; LoadBearing: yes; IsExternal: no
AR_Katus - 001_Nimetus: VAHELAGI; 205_Tüüp: VL-MK-10/2; 325_Helipidavus: nõudeid ei esitata; 330_Tulekindlus: REI 60; 340_Soojusläbivus: 0
AR_Vahelagi - 001_Nimetus: VAHELAGI; 205_Tüüp: VL-MK-10/2; 325_Helipidavus: nõudeid ei esitata; 330_Tulekindlus: REI 60; 335_Välispiire: no; 340_Soojusläbivus: 0; 500_Kandev: TRUE; 505_Paksus: 130 mm; 510_Bruto_pindala: 0.5764 m2; 515_Neto_pindala: 0.524 m2
AC_Pset_RenovationAndPhasing - Renovation Status: New

# IfcSlab: VL-MK-10/2_variseinte hor. osad+vill- tasapind 130, VAHELAGI
In: 2. korrus
Classification: 1.20 IfcSlabType (vahelagi) (RKAS BIM + ARCHICAD Classification)
Pset_SlabCommon - Reference: VL-MK-10/2; LoadBearing: yes; IsExternal: no
AR_Katus - 001_Nimetus: VAHELAGI; 205_Tüüp: VL-MK-10/2; 325_Helipidavus: nõudeid ei esitata; 330_Tulekindlus: nõudeid ei esitata; 340_Soojusläbivus: 0
AR_Vahelagi - 001_Nimetus: VAHELAGI; 205_Tüüp: VL-MK-10/2; 325_Helipidavus: nõudeid ei esitata; 330_Tulekindlus: nõudeid ei esitata; 335_Välispiire: no; 340_Soojusläbivus: 0; 500_Kandev: TRUE; 505_Paksus: 130 mm; 510_Bruto_pindala: 0.5764 m2; 515_Neto_pindala: 0.5764 m2
AC_Pset_RenovationAndPhasing - Renovation Status: New

# IfcSlab: VL-MK-10/3_variseinte hor. osad - laeks 135 (2)
In: 4. TEHNO korrus
Classification: 1.20 IfcSlabType (vahelagi) (RKAS BIM + ARCHICAD Classification)
Pset_SlabCommon - Reference: VL-MK-10/3; LoadBearing: yes; IsExternal: no
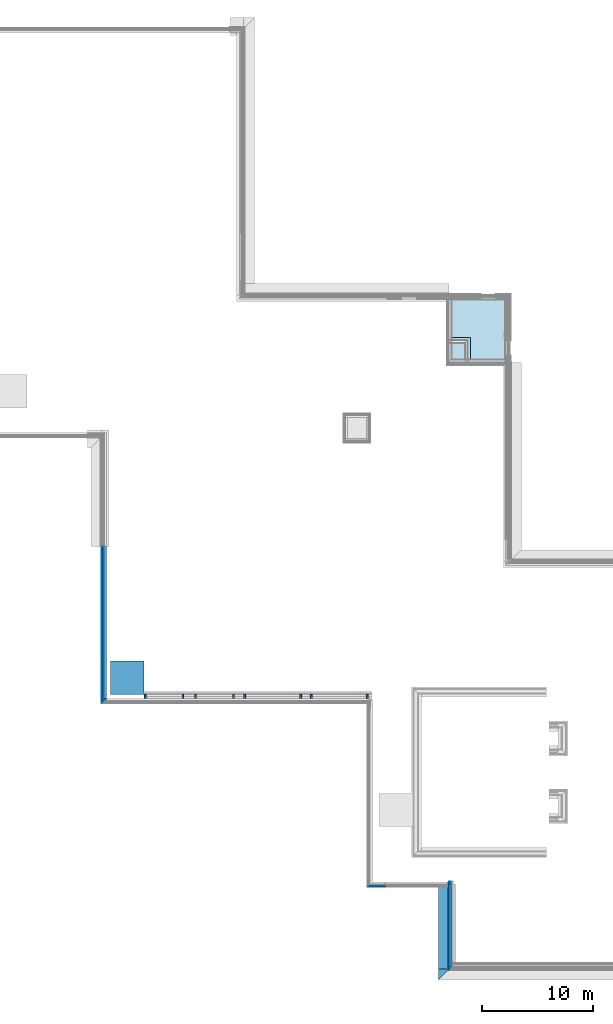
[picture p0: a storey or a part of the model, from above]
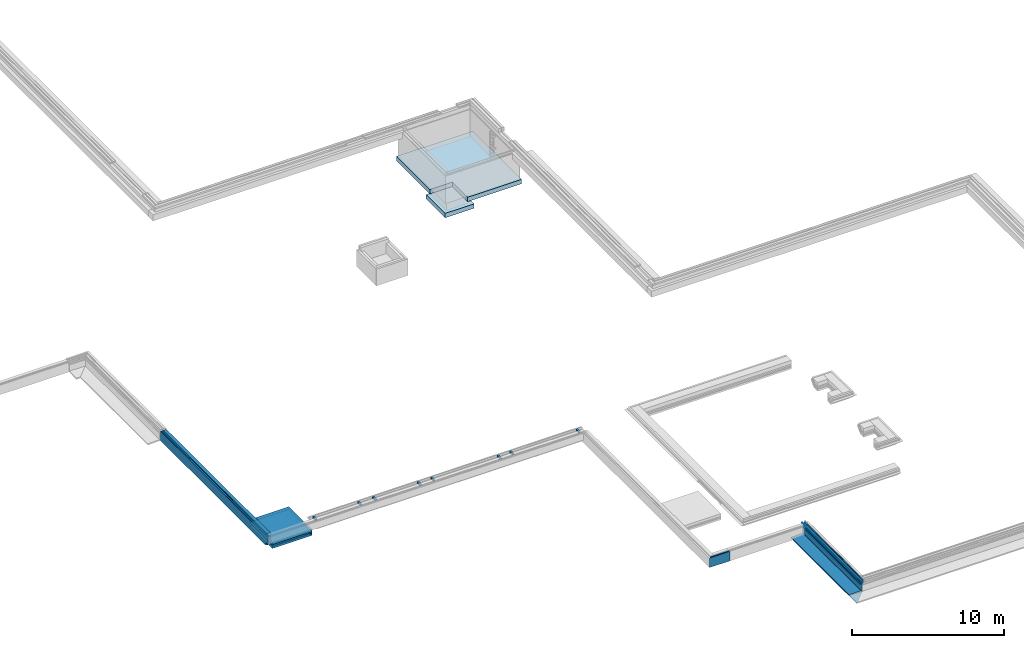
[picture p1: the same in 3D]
Properties of the parts of a building model (IFC2X3), part 10 of 14

# IfcSlab: VL-MK-10/3_variseinte hor. osad - laeks 135 (2)
AR_Katus - 001_Nimetus: VAHELAGI; 205_Tüüp: VL-MK-10/3; 325_Helipidavus: nõudeid ei esitata; 330_Tulekindlus: nõudeid ei esitata; 340_Soojusläbivus: 0
AR_Vahelagi - 001_Nimetus: VAHELAGI; 205_Tüüp: VL-MK-10/3; 325_Helipidavus: nõudeid ei esitata; 330_Tulekindlus: nõudeid ei esitata; 335_Välispiire: no; 340_Soojusläbivus: 0; 500_Kandev: TRUE; 505_Paksus: 135 mm
AC_Pset_RenovationAndPhasing - Renovation Status: New
Name | 510_Bruto_pindala (m2) = 515_Neto_pindala (m2)
VAHELAGI | 7.78086
VAHELAGI | 0.0000124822

# IfcSlab: VL-MK-22/1_ Audika trepistik koosolekuruumis 380, Katuslagi
In: 4. TEHNO korrus
Classification: 1.20 IfcSlabType (vahelagi) (RKAS BIM + ARCHICAD Classification)
Pset_SlabCommon - Reference: VL-MK-22/1; LoadBearing: yes; IsExternal: yes
AR_Katus - 001_Nimetus: Katuslagi; 205_Tüüp: VL-MK-22/1; 325_Helipidavus: 60 dB; 330_Tulekindlus: REI 60; 340_Soojusläbivus: 0
AR_Vahelagi - 001_Nimetus: Katuslagi; 205_Tüüp: VL-MK-22/1; 325_Helipidavus: 60 dB; 330_Tulekindlus: REI 60; 335_Välispiire: yes; 340_Soojusläbivus: 0; 500_Kandev: TRUE; 505_Paksus: 380 mm; 510_Bruto_pindala: 1.38267 m2; 515_Neto_pindala: 0 m2
AC_Pset_RenovationAndPhasing - Renovation Status: New

# IfcSlab: VL-MK-22/1_ Audika trepistik koosolekuruumis 380, Katusekalded
In: 3. korrus
Type - PredefinedType: ROOF
Classification: 1.19 IfcSlabType.ROOF (katus) (RKAS BIM + ARCHICAD Classification)
Pset_SlabCommon - Reference: VL-MK-22/1; LoadBearing: no; IsExternal: yes
AR_Katus - 001_Nimetus: Katusekalded; 205_Tüüp: VL-MK-22/1; 325_Helipidavus: 60 dB; 330_Tulekindlus: nõudeid ei esitata; 340_Soojusläbivus: 0; 520_Pindala: 13.5985 m2
AR_Vahelagi - 001_Nimetus: Katusekalded; 205_Tüüp: VL-MK-22/1; 325_Helipidavus: 60 dB; 330_Tulekindlus: nõudeid ei esitata; 340_Soojusläbivus: 0
AC_Pset_RenovationAndPhasing - Renovation Status: New

# IfcSlab: VL-MK-22/2_ Audika trepistik mudelis 320, Katuslagi
In: 4. TEHNO korrus
Classification: 1.20 IfcSlabType (vahelagi) (RKAS BIM + ARCHICAD Classification)
Pset_SlabCommon - Reference: VL-MK-22/2; LoadBearing: yes; IsExternal: yes
AR_Katus - 001_Nimetus: Katuslagi; 205_Tüüp: VL-MK-22/2; 325_Helipidavus: 60 dB; 330_Tulekindlus: REI 60; 340_Soojusläbivus: 0
AR_Vahelagi - 001_Nimetus: Katuslagi; 205_Tüüp: VL-MK-22/2; 325_Helipidavus: 60 dB; 330_Tulekindlus: REI 60; 335_Välispiire: yes; 340_Soojusläbivus: 0; 500_Kandev: TRUE; 505_Paksus: 320 mm; 510_Bruto_pindala: 4.54738 m2; 515_Neto_pindala: 0.661358 m2
AC_Pset_RenovationAndPhasing - Renovation Status: New

# IfcSlab: VL-MK-22/2_ Audika trepistik mudelis 320, Kaldlagi
In: 3. korrus
Type - PredefinedType: ROOF
Classification: 1.19 IfcSlabType.ROOF (katus) (RKAS BIM + ARCHICAD Classification)
Pset_SlabCommon - Reference: VL-MK-22/2; LoadBearing: no; IsExternal: yes
AR_Katus - 001_Nimetus: Kaldlagi; 205_Tüüp: VL-MK-22/2; 325_Helipidavus: 60 dB; 330_Tulekindlus: nõudeid ei esitata; 340_Soojusläbivus: 0; 520_Pindala: 40.8054 m2
AR_Vahelagi - 001_Nimetus: Kaldlagi; 205_Tüüp: VL-MK-22/2; 325_Helipidavus: 60 dB; 330_Tulekindlus: nõudeid ei esitata; 340_Soojusläbivus: 0
AC_Pset_RenovationAndPhasing - Renovation Status: New

# IfcSlab: VL-MK-24/1_ 2. k astmestiku lagi 370, Kaldlagi
In: 2. korrus
Type - PredefinedType: ROOF
Classification: 1.19 IfcSlabType.ROOF (katus) (RKAS BIM + ARCHICAD Classification)
Pset_SlabCommon - Reference: VL-MK-24/1; LoadBearing: yes; IsExternal: yes
AR_Katus - 001_Nimetus: Kaldlagi; 205_Tüüp: VL-MK-24/1; 325_Helipidavus: 52 dB; 330_Tulekindlus: REI 60; 340_Soojusläbivus: 0; 520_Pindala: 22.8963 m2
AR_Vahelagi - 001_Nimetus: Kaldlagi; 205_Tüüp: VL-MK-24/1; 325_Helipidavus: 52 dB; 330_Tulekindlus: REI 60; 340_Soojusläbivus: 0
AC_Pset_RenovationAndPhasing - Renovation Status: New

# IfcSlab: VL-MK-24/2_ 2 k astmestiku ülemine osa 555, VAHELAGI
In: 3. korrus
Classification: 1.20 IfcSlabType (vahelagi) (RKAS BIM + ARCHICAD Classification)
Pset_SlabCommon - Reference: VL-MK-24/2; LoadBearing: yes; IsExternal: no
AR_Katus - 001_Nimetus: VAHELAGI; 205_Tüüp: VL-MK-24/2; 325_Helipidavus: 52 dB; 330_Tulekindlus: REI 60; 340_Soojusläbivus: 0
AR_Vahelagi - 001_Nimetus: VAHELAGI; 205_Tüüp: VL-MK-24/2; 325_Helipidavus: 52 dB; 330_Tulekindlus: REI 60; 335_Välispiire: no; 340_Soojusläbivus: 0; 500_Kandev: TRUE; 505_Paksus: 555 mm; 510_Bruto_pindala: 5.82755 m2; 515_Neto_pindala: 0.0158214 m2
AC_Pset_RenovationAndPhasing - Renovation Status: New

# IfcSlab: VL-RB-22/1 370 (2)
Classification: 1.20 IfcSlabType (vahelagi) (RKAS BIM + ARCHICAD Classification)
Pset_SlabCommon - Reference: VL-RB-22/1; LoadBearing: yes; IsExternal: no
AR_Katus - 001_Nimetus: VAHELAGI; 205_Tüüp: VL-RB-22/1; 325_Helipidavus: 55 dB; 330_Tulekindlus: REI 60; 340_Soojusläbivus: 0
AR_Vahelagi - 001_Nimetus: VAHELAGI; 205_Tüüp: VL-RB-22/1; 325_Helipidavus: 55 dB; 330_Tulekindlus: REI 60; 335_Välispiire: no; 340_Soojusläbivus: 0; 500_Kandev: TRUE; 505_Paksus: 370 mm; 510_Bruto_pindala: 35.7629 m2
AC_Pset_RenovationAndPhasing - Renovation Status: New
Name | In | 515_Neto_pindala (m2)
VAHELAGI | 2. korrus | 34.0232
VAHELAGI | 3. korrus | 32.1892

# IfcSlab: VL-RB-22/2 _köögi ventruumi lagi 55 dB 450, VAHELAGI
In: 2. korrus
Classification: 1.20 IfcSlabType (vahelagi) (RKAS BIM + ARCHICAD Classification)
Pset_SlabCommon - Reference: VL-RB-22/2; LoadBearing: yes; IsExternal: no
AR_Katus - 001_Nimetus: VAHELAGI; 205_Tüüp: VL-RB-22/2; 325_Helipidavus: 55 dB; 330_Tulekindlus: REI 60; 340_Soojusläbivus: 0
AR_Vahelagi - 001_Nimetus: VAHELAGI; 205_Tüüp: VL-RB-22/2; 325_Helipidavus: 55 dB; 330_Tulekindlus: REI 60; 335_Välispiire: no; 340_Soojusläbivus: 0; 500_Kandev: TRUE; 505_Paksus: 450 mm; 510_Bruto_pindala: 20.8889 m2; 515_Neto_pindala: 17.7738 m2
AC_Pset_RenovationAndPhasing - Renovation Status: New

# IfcSlab: VL-RB-22/3_PVC 370 (2)
In: 2. korrus
Classification: 1.20 IfcSlabType (vahelagi) (RKAS BIM + ARCHICAD Classification)
Pset_SlabCommon - Reference: VL-RB-22/3; LoadBearing: yes; IsExternal: no
AR_Katus - 001_Nimetus: VAHELAGI; 205_Tüüp: VL-RB-22/3; 325_Helipidavus: 60 dB; 330_Tulekindlus: REI 60; 340_Soojusläbivus: 0
AR_Vahelagi - 001_Nimetus: VAHELAGI; 205_Tüüp: VL-RB-22/3; 325_Helipidavus: 60 dB; 330_Tulekindlus: REI 60; 335_Välispiire: no; 340_Soojusläbivus: 0; 500_Kandev: TRUE; 505_Paksus: 370 mm
AC_Pset_RenovationAndPhasing - Renovation Status: New
Name | 510_Bruto_pindala (m2) | 515_Neto_pindala (m2)
VAHELAGI | 99.2421 | 90.7443
VAHELAGI | 67.3506 | 64.022

# IfcSlab: VL-RB-25/1_+puitkilp trepikodades 290 (8)
Classification: 1.20 IfcSlabType (vahelagi) (RKAS BIM + ARCHICAD Classification)
Pset_SlabCommon - Reference: VL-RB-25/1; LoadBearing: yes; IsExternal: no
AR_Katus - 205_Tüüp: VL-RB-25/1; 325_Helipidavus: 57 dB; 340_Soojusläbivus: 0
AR_Vahelagi - 205_Tüüp: VL-RB-25/1; 325_Helipidavus: 57 dB; 335_Välispiire: no; 340_Soojusläbivus: 0; 500_Kandev: TRUE; 505_Paksus: 290 mm
AC_Pset_RenovationAndPhasing - Renovation Status: New
Name | In | AR_Katus, 001_Nimetus = AR_Vahelagi, 001_Nimetus | AR_Katus, 330_Tulekindlus = AR_Vahelagi, 330_Tulekindlus | 510_Bruto_pindala (m2) = 515_Neto_pindala (m2)
TR4 made | 1. korrus | TR4 made | REI 30 | 10.2574
VAHELAGI | 2. korrus | VAHELAGI | REI 60 | 5.84254
VAHELAGI | 2. korrus | VAHELAGI | REI 60 | 12.2095
VAHELAGI | 2. korrus | VAHELAGI | REI 60 | 5.62858
VAHELAGI | 2. korrus | VAHELAGI | REI 60 | 6.85805
VAHELAGI | 3. korrus | VAHELAGI | REI 60 | 6.41106
VAHELAGI | 3. korrus | VAHELAGI | REI 60 | 7.12454
VAHELAGI | 3. korrus | VAHELAGI | REI 60 | 6.85842

# IfcSlab: VL-RB-26/1_PVC 415 (2)
Classification: 1.20 IfcSlabType (vahelagi) (RKAS BIM + ARCHICAD Classification)
Pset_SlabCommon - Reference: VL-RB-26/1; LoadBearing: yes; IsExternal: no
AR_Katus - 001_Nimetus: VAHELAGI; 205_Tüüp: VL-RB-26/1; 325_Helipidavus: 60 dB; 330_Tulekindlus: REI 60; 340_Soojusläbivus: 0
AR_Vahelagi - 001_Nimetus: VAHELAGI; 205_Tüüp: VL-RB-26/1; 325_Helipidavus: 60 dB; 330_Tulekindlus: REI 60; 335_Välispiire: no; 340_Soojusläbivus: 0; 500_Kandev: TRUE; 505_Paksus: 415 mm
AC_Pset_RenovationAndPhasing - Renovation Status: New
Name | In | 510_Bruto_pindala (m2) | 515_Neto_pindala (m2)
VAHELAGI | 2. korrus | 55.8142 | 54.5882
VAHELAGI | 3. korrus | 56.1643 | 52.9442

# IfcSlab: VL-RB-26/2_parkett/plaat 415 (3)
Classification: 1.20 IfcSlabType (vahelagi) (RKAS BIM + ARCHICAD Classification)
Pset_SlabCommon - Reference: VL-RB-26/2; LoadBearing: yes; IsExternal: no
AR_Katus - 001_Nimetus: VAHELAGI; 205_Tüüp: VL-RB-26/2; 325_Helipidavus: 60 dB; 330_Tulekindlus: REI 60; 340_Soojusläbivus: 0
AR_Vahelagi - 001_Nimetus: VAHELAGI; 205_Tüüp: VL-RB-26/2; 325_Helipidavus: 60 dB; 330_Tulekindlus: REI 60; 335_Välispiire: no; 340_Soojusläbivus: 0; 500_Kandev: TRUE; 505_Paksus: 415 mm
AC_Pset_RenovationAndPhasing - Renovation Status: New
Name | In | 510_Bruto_pindala (m2) | 515_Neto_pindala (m2)
VAHELAGI | 2. korrus | 159.66 | 148.757
VAHELAGI | 2. korrus | 26.9011 | 24.0741
VAHELAGI | 3. korrus | 27.6035 | 25.3773

# IfcSlab: VL-RB-40/1_PVC 600, VAHELAGI
In: 3. korrus
Classification: 1.20 IfcSlabType (vahelagi) (RKAS BIM + ARCHICAD Classification)
Pset_SlabCommon - Reference: VL-RB-40/1; LoadBearing: yes; IsExternal: no
AR_Katus - 001_Nimetus: VAHELAGI; 205_Tüüp: VL-RB-40/1; 325_Helipidavus: 60 dB; 330_Tulekindlus: REI 60; 340_Soojusläbivus: 0
AR_Vahelagi - 001_Nimetus: VAHELAGI; 205_Tüüp: VL-RB-40/1; 325_Helipidavus: 60 dB; 330_Tulekindlus: REI 60; 335_Välispiire: no; 340_Soojusläbivus: 0; 500_Kandev: TRUE; 505_Paksus: 600 mm; 510_Bruto_pindala: 104.41 m2; 515_Neto_pindala: 100.265 m2
AC_Pset_RenovationAndPhasing - Renovation Status: New

# IfcSlab: VL-RB-40/2_parkett kaldaudikas 600, VAHELAGI
In: 3. korrus
Classification: 1.20 IfcSlabType (vahelagi) (RKAS BIM + ARCHICAD Classification)
Pset_SlabCommon - Reference: VL-RB-40/2; LoadBearing: yes; IsExternal: no
AR_Katus - 001_Nimetus: VAHELAGI; 205_Tüüp: VL-RB-40/2; 325_Helipidavus: 60 dB; 330_Tulekindlus: REI 60; 340_Soojusläbivus: 0
AR_Vahelagi - 001_Nimetus: VAHELAGI; 205_Tüüp: VL-RB-40/2; 325_Helipidavus: 60 dB; 330_Tulekindlus: REI 60; 335_Välispiire: no; 340_Soojusläbivus: 0; 500_Kandev: TRUE; 505_Paksus: 600 mm; 510_Bruto_pindala: 51.4571 m2; 515_Neto_pindala: 50.5061 m2
AC_Pset_RenovationAndPhasing - Renovation Status: New

# IfcSlab: VL-RBM-20/1_garderoobi tasand 200 (3)
In: 1. korrus
Classification: 1.20 IfcSlabType (vahelagi) (RKAS BIM + ARCHICAD Classification); Material: _KANDETARIND - monoliitne raudbetoon vastavalt EK osale
Pset_SlabCommon - Reference: VL-RBM-20/1; LoadBearing: yes; IsExternal: no
AR_Katus - 205_Tüüp: VL-RBM-20/1; 340_Soojusläbivus: 0
AR_Vahelagi - 205_Tüüp: VL-RBM-20/1; 335_Välispiire: no; 340_Soojusläbivus: 0; 500_Kandev: TRUE; 505_Paksus: 200 mm
AC_Pset_RenovationAndPhasing - Renovation Status: New
Name | AR_Katus, 001_Nimetus = AR_Vahelagi, 001_Nimetus | AR_Katus, 325_Helipidavus = AR_Vahelagi, 325_Helipidavus | AR_Katus, 330_Tulekindlus = AR_Vahelagi, 330_Tulekindlus | 510_Bruto_pindala (m2) = 515_Neto_pindala (m2)
VAHELAGI | VAHELAGI | 55 dB | REI 60 | 0
VAHELAGI | VAHELAGI | nõudeid ei esitata | REI 60 | 0
Vahelagi | Vahelagi | 60 dB | R60

# IfcSlab: VL-RBM-20/2_mahuti vahelagi 350, Mahuti vahelagi
In: 1. korrus
Classification: 1.20 IfcSlabType (vahelagi) (RKAS BIM + ARCHICAD Classification)
Pset_SlabCommon - Reference: VL-RBM-20/2; LoadBearing: yes; IsExternal: no
AR_Katus - 001_Nimetus: Mahuti vahelagi; 205_Tüüp: VL-RBM-20/2; 325_Helipidavus: -; 330_Tulekindlus: REI 60; 340_Soojusläbivus: 0.1
AR_Vahelagi - 001_Nimetus: Mahuti vahelagi; 205_Tüüp: VL-RBM-20/2; 325_Helipidavus: -; 330_Tulekindlus: REI 60; 335_Välispiire: no; 340_Soojusläbivus: 0.1; 500_Kandev: TRUE; 505_Paksus: 350.2 mm; 510_Bruto_pindala: 0 m2; 515_Neto_pindala: 0 m2
AC_Pset_RenovationAndPhasing - Renovation Status: New

# IfcSlab: _KANDETARIND - monoliitne raudbetoon vastavalt EK osale 100 (6)
In: 1. korrus
Classification: 1.20 IfcSlabType (vahelagi) (RKAS BIM + ARCHICAD Classification); Material: _KANDETARIND - monoliitne raudbetoon vastavalt EK osale
Pset_SlabCommon - LoadBearing: no; IsExternal: yes
AR_Katus - 001_Nimetus: Porivann, monoliitne raudbetoon vastavalt EK osale; 325_Helipidavus: Undefined; 330_Tulekindlus: nõudeid ei esitata; 340_Soojusläbivus: 0
AR_Vahelagi - 001_Nimetus: Porivann, monoliitne raudbetoon vastavalt EK osale; 325_Helipidavus: Undefined; 330_Tulekindlus: nõudeid ei esitata; 335_Välispiire: yes; 340_Soojusläbivus: 0; 500_Kandev: FALSE; 505_Paksus: 100 mm
AC_Pset_RenovationAndPhasing - Renovation Status: New
Name | 510_Bruto_pindala (m2) = 515_Neto_pindala (m2)
2 x Porivann, monoliitne raudbetoon vastavalt EK osale | 1.0188
Porivann, monoliitne raudbetoon vastavalt EK osale | 6.54337
Porivann, monoliitne raudbetoon vastavalt EK osale | 1.45796
Porivann, monoliitne raudbetoon vastavalt EK osale | 1.02116
Porivann, monoliitne raudbetoon vastavalt EK osale | 12.4424

# IfcSlab: _KANDETARIND - monoliitne raudbetoonplaat 100 (4)
In: 4. TEHNO korrus
Classification: 1.20 IfcSlabType (vahelagi) (RKAS BIM + ARCHICAD Classification); Material: _KANDETARIND - monoliitne raudbetoonplaat
Pset_SlabCommon - LoadBearing: no; IsExternal: no
AR_Katus - 001_Nimetus: SE korstna kate, monoliitne raudbetoonplaat, vuugid hermetiseeritud tulekindla vuugihermeetikuga PENOSIL Firestop Acrylic või analoogne; 325_Helipidavus: nõudeid ei esitata; 330_Tulekindlus: nõudeid ei esitata; 340_Soojusläbivus: 0
AR_Vahelagi - 001_Nimetus: SE korstna kate, monoliitne raudbetoonplaat, vuugid hermetiseeritud tulekindla vuugihermeetikuga PENOSIL Firestop Acrylic või analoogne; 325_Helipidavus: nõudeid ei esitata; 330_Tulekindlus: nõudeid ei esitata; 335_Välispiire: no; 340_Soojusläbivus: 0; 500_Kandev: FALSE; 505_Paksus: 100 mm; 510_Bruto_pindala: 0.350001 m2; 515_Neto_pindala: 0.350001 m2
AC_Pset_RenovationAndPhasing - Renovation Status: New

# IfcSlab: _KANDETARIND - monoliitne raudbetoonplaat 350 (2)
In: Vundament
Classification: 1.20 IfcSlabType (vahelagi) (RKAS BIM + ARCHICAD Classification); Material: _KANDETARIND - monoliitne raudbetoonplaat
Pset_SlabCommon - Reference: Raudbetoon vastavalt EK osale; LoadBearing: yes; IsExternal: yes
AR_Katus - 001_Nimetus: Põrand pinnasel; 205_Tüüp: Raudbetoon vastavalt EK osale; 325_Helipidavus: -; 330_Tulekindlus: REI 60; 340_Soojusläbivus: 0.1
AR_Vahelagi - 001_Nimetus: Põrand pinnasel; 205_Tüüp: Raudbetoon vastavalt EK osale; 325_Helipidavus: -; 330_Tulekindlus: REI 60; 335_Välispiire: yes; 340_Soojusläbivus: 0.1; 500_Kandev: TRUE; 505_Paksus: 350 mm
AC_Pset_RenovationAndPhasing - Renovation Status: New
Name | 510_Bruto_pindala (m2) | 515_Neto_pindala (m2)
Põrand pinnasel | 33.9359 | 33.9274
Põrand pinnasel | 5.49147 | 5.49147

# IfcSlab: _VÄLISVIIMISTLUS - vertikaalne voodrilaud, Platowood P01 profiil 18x140mm, kuusk; eeltöödeldud tuletõkkega mõlemad küljed, B-s1, d0, Woodsafe Exterior WFX™ või samaväärne 18, VAHELAGI
In: 2. korrus
Classification: 1.20 IfcSlabType (vahelagi) (RKAS BIM + ARCHICAD Classification); Material: _VÄLISVIIMISTLUS - vertikaalne voodrilaud, Platowood P01 profiil 18x140mm, kuusk; eeltöödeldud tuletõkkega mõlemad küljed, B-s1, d0, Woodsafe Exterior WFX™ või samaväärne
Pset_SlabCommon - LoadBearing: yes; IsExternal: yes
AR_Katus - 001_Nimetus: VAHELAGI; 325_Helipidavus: nõudeid ei esitata; 330_Tulekindlus: REI 60; 340_Soojusläbivus: 0.06
AR_Vahelagi - 001_Nimetus: VAHELAGI; 325_Helipidavus: nõudeid ei esitata; 330_Tulekindlus: REI 60; 335_Välispiire: yes; 340_Soojusläbivus: 0.06; 500_Kandev: TRUE; 505_Paksus: 18 mm; 510_Bruto_pindala: 54.9386 m2; 515_Neto_pindala: 54.8037 m2
AC_Pset_RenovationAndPhasing - Renovation Status: New

# IfcStair (25)
Classification: 1.22 IfcStair (trepp) (RKAS BIM + ARCHICAD Classification)
Pset_StairCommon - IsExternal: no
AC_Pset_RenovationAndPhasing - Renovation Status: New
Name | In | Reference = 002_Tüüp | NumberOfRiser = NumberOfTreads | RiserHeight (mm) | RequiredHeadroom (mm) | 001_Nimetus
TREPP | 1. korrus | TR1.1 | 29 | 158.621 | 2200 | TREPP
TREPP | 1. korrus | TR2.1 | 29 | 158.621 | 2200 | TREPP
2 x Aste | 1. korrus |  |  |  |  | Aste | Material: _KANDETARIND - monoliitne raudbetoonplaat
3 x Aste | 1. korrus |  |  |  |  | Aste | Material: _PEALEVALUKIHT - raudbetoon plaat, C25/30, XF2
TREPP | 1. korrus | TR6 | 13 | 157.308 | 2200 | Betoontrepp vastavalt EK osale
TREPP | 1. korrus | TR5 | 13 | 157.308 | 2200 | Betoontrepp vastavalt EK osale
TREPP | 1. korrus | TR3.1 | 29 | 158.621 | 2200 | TREPP
TREPP | 1. korrus | TR4 | 18 | 158.611 | 2200 | TREPP
TREPP | 1. korrus | TR4 | 11 | 158.636 | 2200 | TREPP
vahelae luugi sisse kokkuklapitav, allatõmmatav käärtrepp käsipuuga | 1. korrus | TR-05 |  |  |  | vahelae luugi sisse kokkuklapitav, allatõmmatav käärtrepp käsipuuga
TREPP | 2. korrus | TR1.2: 156 ( H ) ; 280 ( AL ) ; KÄIGUTEE: 9 240 | 24 | 156.25 | 2200 | TR1.2
TREPP | 2. korrus | TR2.2: 156 ( H ) ; 280 ( AL ) ; KÄIGUTEE: 10 865 | 24 | 156.25 | 2200 | TR2.2
Aula astmed | 2. korrus | Aula astmed: 156 ( H ) ; 300 ( AL ) ; KÄIGUTEE: 7 200 | 24 | 156.25 | 2200 | Aula astmed
Aula astmed | 2. korrus | Aula astmed: 469 ( H ) ; 900 ( AL ) ; KÄIGUTEE: 7 200 | 8 | 468.75 | 2200 | Aula astmed
TREPP | 2. korrus | TR3.2: 156 ( H ) ; 280 ( AL ) ; KÄIGUTEE: 9 240 | 24 | 156.25 | 2200 | TR3.2
3 x TREPP | 3. korrus | TREPP: 156 ( H ) ; 300 ( AL ) ; KÄIGUTEE: 7 200 | 24 | 156.25 | 2200 | TREPP
2 x Auditooriomi astmed | 3. korrus | Auditooriomi astmed: 469 ( H ) ; 900 ( AL ) ; KÄIGUTEE: 7 200 | 8 | 468.75 | 2200 | Auditooriomi astmed
metalltrepp | 4. TEHNO korrus | TR-07 | 4 | 157.5 | 2200 | metalltrepp
metalltrepp | 4. TEHNO korrus | TR-08 | 3 | 166.667 | 2200 | metalltrepp

# IfcTransportElement: LIFT KONE Monospace, KONE_LDO_KES201_2L_P15_TX:KONE_LDO_2.0:299058
In: 1. korrus
Classification: 1.23 IfcTransportElementType (lift) (RKAS BIM + ARCHICAD Classification); Material: _GENEERILINE MATERJAL, _ÕHK
Constraints - Moves With Nearby Elements: no; Offset: 8350 mm
Dimensions - DIM_FLOORING_THICKNESS: 0 mm; DIM_FRAME_BR_FIX_LEVEL: 0 mm; DIM_FRAME_BR_FIX_LEVEL_OPT_1: 0 mm; DIM_FRAME_BR_FIX_LEVEL_OPT_2: 0 mm; DIM_FRAME_BR_FIX_LEVEL_OPT_3: 0 mm; DIM_FRAME_BR_FIX_LEVEL_OPT_4: 0 mm; DIM_FRAME_BR_HEIGHT: 0 mm; DIM_FRAME_BR_LEFTSIDE: 0 mm; DIM_FRAME_BR_LEFTSIDE_OPT_1: 0 mm; DIM_FRAME_BR_LEFTSIDE_OPT_2: 0 mm; DIM_FRAME_BR_LEFTSIDE_OPT_3: 0 mm; DIM_FRAME_BR_LEFTSIDE_OPT_4: 0 mm; DIM_FRAME_BR_OPT_HEIGHT: 0 mm; DIM_FRAME_BR_RIGHTSIDE: 0 mm; DIM_FRAME_BR_RIGHTSIDE_OPT_1: 0 mm; DIM_FRAME_BR_RIGHTSIDE_OPT_2: 0 mm; DIM_FRAME_BR_RIGHTSIDE_OPT_3: 0 mm; DIM_FRAME_BR_RIGHTSIDE_OPT_4: 0 mm; DIM_FRAME_BR_SUPPORT_LEFTSIDE: 0 mm; DIM_FRAME_BR_SUPPORT_LEFTSIDE_OPT: 0 mm; DIM_FRAME_BR_SUPPORT_RIGHTSIDE: 0 mm; DIM_FRAME_BR_SUPPORT_RIGHTSIDE_OPT: 0 mm; DIM_RAILING_BR_LEFTSIDE_OPT: 0 mm; DIM_RAILING_CUTOUT_EXT: 0 mm; DIM_SILL_BR_LEFTSIDE_1: 0 mm; DIM_SILL_BR_LEFTSIDE_2: 0 mm; DIM_SILL_BR_LEFTSIDE_4: 0 mm; DIM_SILL_BR_LEFTSIDE_5: 0 mm; DIM_SILL_BR_RIGHTSIDE_1: 0 mm; DIM_SILL_BR_RIGHTSIDE_2: 0 mm; DIM_SILL_BR_RIGHTSIDE_4: 0 mm; DIM_SILL_BR_RIGHTSIDE_5: 0 mm; DIM_SILL_FIX_FROM_SHAFT_WALL: 0 mm; Area: 23.9381 m2; DIM_DOOR_HH: 2100 mm; DIM_DOOR_HR: 2280 mm; DIM_DOOR_LL: 900 mm; DIM_DOOR_LR: 1200 mm; DIM_DOOR_LR_LEFTSIDE: 600 mm; DIM_DOOR_LR_RIGHTSIDE: 600 mm; DIM_DOOR_PH_LEFTSIDE: 620 mm; DIM_DOOR_PH_RIGHTSIDE: 970 mm; DIM_LDO_HA: 150 mm; DIM_LDO_LA: 120 mm; DIM_LDO_LB: 120 mm; DIM_LDO_RECESS_MANUAL_FROM_SILL_LINE: 140 mm; DIM_LDO_WALL_TO_SILL_LINE: 140 mm; DIM_PANEL_FRAME_BOTTOM_WIDTH: 1 mm; DIM_PANEL_FRAME_LEFT_WIDTH: 1 mm; DIM_PANEL_FRAME_RIGHT_WIDTH: 1 mm; DIM_PANEL_FRAME_TOP_WIDTH: 1 mm; DIM_PANEL_GAP_TO_FRAME: 5 mm; DIM_PANEL_THICKNESS_BACK: 45 mm; DIM_PANEL_THICKNESS_FRONT: 45 mm; DIM_PANEL_WIDTH: 472 mm; DIM_RAILING_BR_FIX_LEVEL: 2430 mm; DIM_RAILING_BR_FIX_LEVEL_OPT: 2430 mm; DIM_RAILING_BR_LEFTSIDE: 510 mm; DIM_RAILING_BR_RIGHTSIDE: 510 mm; DIM_RAILING_BR_RIGHTSIDE_OPT: 850 mm; DIM_RAILING_BR_TOP_FROM_HH: 500 mm; DIM_RAILING_FIX_FROM_SILL_LINE: 140 mm; DIM_SHAFT_TOLERANCE: 25 mm; DIM_SHAFT_WALL_THICKNESS: 150 mm; DIM_SILL_BR_BOTTOM_FROM_FFL: 275 mm; DIM_SILL_BR_FIX_LEVEL: 100 mm; DIM_SILL_BR_LEFTSIDE_3: 350 mm; DIM_SILL_BR_RIGHTSIDE_3: 350 mm; DIM_SILL_CUTOUT_EXT: 30 mm; DIM_SILL_FIX_FROM_SILL_LINE: 140 mm; DIM_SILL_PH_DEPTH: 140 mm; DIM_SILL_PH_HEIGHT: 2 mm; Volume: 4.63787 m3
Other - Category: Specialty Equipment; Family: KONE_LDO_KES201_2L_P15_TX: KONE_LDO_2.0; Family and Type: KONE_LDO_KES201_2L_P15_TX: KONE_LDO_2.0; TYP_DOOR_FIRE_CLASS_CODE: yes; Type: KONE_LDO_KES201_2L_P15_TX: KONE_LDO_2.0; Type Id: KONE_LDO_KES201_2L_P15_TX: KONE_LDO_2.0
Phasing - Phase Created: Phase 3
Visibility - VIS_CINSERT: no; VIS_DOOR_OPENING: no; VIS_DOOR_WALL_CUTOUT: no; VIS_FRAME: yes; VIS_FRAME_BR_LEFTSIDE_OPT_1: no; VIS_FRAME_BR_LEFTSIDE_OPT_2: no; VIS_FRAME_BR_LEFTSIDE_OPT_3: no; VIS_FRAME_BR_LEFTSIDE_OPT_4: no; VIS_FRAME_BR_RIGHTSIDE_OPT_1: no; VIS_FRAME_BR_RIGHTSIDE_OPT_2: no; VIS_FRAME_BR_RIGHTSIDE_OPT_3: no; VIS_FRAME_BR_RIGHTSIDE_OPT_4: no; VIS_FRAME_BRACKETS: no; VIS_FRAME_CINSERT_OPT_1: no; VIS_FRAME_CINSERT_OPT_2: no; VIS_FRAME_MAP_RIGHT: no; VIS_PANEL_GLASS_WINDOW_LEFT: no; VIS_PANEL_GLASS_WINDOW_RIGHT: no; VIS_RAILING_BR_LEFTSIDE: yes; VIS_RAILING_BR_LEFTSIDE_OPT: no; VIS_RAILING_BR_RIGHTSIDE: yes; VIS_RAILING_BR_RIGHTSIDE_OPT: no; VIS_RAILING_BRACKETS: yes; VIS_RAILING_CINSERT_OPT: no; VIS_SILL_BR_LEFTSIDE_1: yes; VIS_SILL_BR_LEFTSIDE_2: no; VIS_SILL_BR_LEFTSIDE_3: yes; VIS_SILL_BR_LEFTSIDE_4: no; VIS_SILL_BR_LEFTSIDE_5: no; VIS_SILL_BR_RIGHTSIDE_1: no; VIS_SILL_BR_RIGHTSIDE_2: no; VIS_SILL_BR_RIGHTSIDE_3: yes; VIS_SILL_BR_RIGHTSIDE_4: no; VIS_SILL_BR_RIGHTSIDE_5: no; VIS_SILL_BRACKETS: yes; VIS_SILL_CINSERT_OPT_1: no; VIS_SILL_CINSERT_OPT_2: no; VIS_SILL_CINSERT_OPT_3: no; VIS_SILL_CINSERT_OPT_4: no; VIS_SILL_CINSERT_VERTICAL: no; VIS_SILL_POV: no; VIS_FRAME_MAP_LEFT: yes
Pset_TransportElementCommon - Reference: LIFT KONE Monospace
AR_001-002 - 001_Nimetus: KONE MonoSpace 300 DX; 002_Tüüp: LIFT KONE Monospace
AC_Pset_RenovationAndPhasing - Renovation Status: New

# IfcWall: KL-PK-20/1_parapeti kaldtoed 74 (3)
In: 4. TEHNO korrus
Classification: 1.24 IfcWallType (sein) (RKAS BIM + ARCHICAD Classification)
Pset_WallCommon - Reference: KL-PK-20/1; LoadBearing: yes; IsExternal: yes
AR_Sein - 205_Tüüp: KL-PK-20/1; 325_Helipidavus: nõudeid ei esitata; 330_Tulekindlus: nõudeid ei esitata; 335_Välispiire: yes; 340_Soojusläbivus: 0; 376_Viimistlus_väljast: Telje poolne pind: TOON- helehall RR21; Telje vastaspoolne pind: ÕHK; 505_Paksus: 74 mm; 500_Kandev: TRUE; 376_Viimistlus_väljast (MUDELIS): _HÜDROISOLATSIOON - katusekate PVC rullmaterjal, vastavalt RIL 107-2012-le, helehall F91, Protan SE või samaväärne; _ERALDUSKIHT - siirdetõke, min 140g/m2, Fibertex F2B 140g/m2 või samaväärne; _PLAATMATERJAL - veekindla pinnaga niiskuskindel kuusevineer vastavalt EN 314 klass 3, BS 1203/H4, DIN 68705 osa 3 tüüp BFU nõuetele, lõikeserv ja õhuga kokkupuutuv pind kaitsta puidukaitsevahendiga, nt 2x Pinotex Impra; _KARKASS - puitroov 50x50mm horisontaalne, sügavimmutatud, samm 600mm; _KANDETARIND - puitkarkass vastavalt EK osale
AC_Pset_RenovationAndPhasing - Renovation Status: New
Name | 001_Nimetus | 605_Neto_pindala (m2) | 600_Bruto_pindala (m2)
Varisein | Varisein | 21.9412 | 22.083
Varisein | Varisein | 9.17753 | 9.57524
Välissein | Välissein | 13.269 | 25.0494

# IfcWall: Konsooli välisnurk 312 x 1078 (2)
In: 2. korrus
Classification: 1.24 IfcWallType (sein) (RKAS BIM + ARCHICAD Classification)
Pset_WallCommon - Reference: Konsooli välisnurk; LoadBearing: yes; IsExternal: yes
AR_Sein - 001_Nimetus: Välissein; 205_Tüüp: Konsooli välisnurk; 325_Helipidavus: nõudeid ei esitata; 330_Tulekindlus: REI 60; 335_Välispiire: yes; 340_Soojusläbivus: 0; 505_Paksus: 312 mm; 500_Kandev: TRUE; 376_Viimistlus_väljast (MUDELIS): _TUULETÕKE - tuuletõkkeplaat, soojuserijuhtivus λD<0,031 W/(mK), ISOVER RKL FACADE või samaväärne, liitekohad katta tihendusteibiga ISOVER FacadeTape või samaväärne; _ÕHK; _KARKASS - kübarprofiil 50mm, samm 600mm, kuumtsingitud teras; _SOOJUSTUS - mineraalvill, λD<0,032 W/(mK), kuumtsingitud lehtteras termoroovidega, S350GD+Zn275 vastavalt EN10346, ISOVER EXTREME 32 100mm või samaväärne; _VÄLISVIIMISTLUS - vertikaalne voodrilaud, Platowood P01 profiil 18x140mm, kuusk; eeltöödeldud tuletõkkega mõlemad küljed, B-s1, d0, Woodsafe Exterior WFX™ või samaväärne; _KARKASS - puitroov 32x50mm vertikaalne, immutatud Driconi tulekaitsevahendiga või samaväärne, samm 600mm; _VÄLISVIIMISTLUS - vertikaalne voodrilaud, Platowood P01 profiil 18x140mm, kuusk; eeltöödeldud tuletõkkega mõlemad küljed, B-s1, d0, Woodsafe Exterior WFX™ või samaväärne; _TUULETÕKE - tuuletõkkeplaat, soojuserijuhtivus λD<0,031 W/(mK), ISOVER RKL FACADE või samaväärne, liitekohad katta tihendusteibiga ISOVER FacadeTape või samaväärne; _SOOJUSTUS - mineraalvill, λD<0,032 W/(mK), kuumtsingitud lehtteras termoroovidega, S350GD+Zn275 vastavalt EN10346, ISOVER EXTREME 32 200mm või samaväärne; _KARKASS - puitroov 32x50mm vertikaalne, immutatud Driconi tulekaitsevahendiga või samaväärne, samm 600mm
AC_Pset_RenovationAndPhasing - Renovation Status: New
Name | 605_Neto_pindala (m2) | 600_Bruto_pindala (m2)
Välissein | 8.82106 | 8.95647
Välissein | 7.83826 | 7.98691

# IfcWall: Lintvundament 1602 x 765 (11)
In: Vundament
Classification: 1.24 IfcWallType (sein) (RKAS BIM + ARCHICAD Classification)
Pset_WallCommon - Reference: Lintvundament; LoadBearing: yes; IsExternal: yes
AR_Sein - 001_Nimetus: Vundament; 205_Tüüp: Lintvundament; 325_Helipidavus: -; 330_Tulekindlus: nõudeid ei esitata; 335_Välispiire: yes; 340_Soojusläbivus: 0; 505_Paksus: 1602.41 mm; 500_Kandev: TRUE; 376_Viimistlus_väljast (MUDELIS): _TUULETÕKE - sokli krohv, silikoonvaikkrohv Weber.pas 481 AquaBalance 1mm "scratch" viimistlus, toon helehall CL444 (S 3502-Y) * 35, SILS süsteem, või samaväärne; _HÜDROISOLATSIOON - tsemendil baseeruv ühekomponentne hüdroisolatsioon hüdroisoleerimiseks sokli krohvi pealt, ülevärvitud silikoonvaikvärviga sokli krohvi tooni, Weber.tec 824 ja Weber.ton 411 AquaBalance toon CL444 (S 3502-Y) * 35 või samaväärne; _SOOJUSTUS - ekstrudeeritud polüstüreenist plaadid XPS 250, survetugevus min 250kPa, soojuserijuhtivus λD<0,036 W/(mK), veeimavus alla 0,2%, näiteks XPS 250 foam SL või samaväärne; _SOOJUSTUS - vahtpolüstüreenplaadid EPS 120 Perimeeter, survetugevus min 120kPa, veeimavus <2%, soojuserijuhtivus λD<0,036 W/(mK); _HÜDROISOLATSIOON - Bituumenvõõp COMBIFLEX-EL vastavalt TL2 nõuetele; _SOOJUSTUS - vahtpolüstüreenplaadid EPS 120 Perimeeter, survetugevus min 120kPa, veeimavus <2%, soojuserijuhtivus λD<0,036 W/(mK); _ALUSKATE - drenaaži- ja kaitsematt geotekstiiliga soojustuse kaitseks, Interplast Iso-Drain 8 Geo või samaväärne; _SOOJUSTUS - vahtpolüstüreenplaadid EPS 120 Perimeeter, survetugevus min 120kPa, veeimavus <2%, soojuserijuhtivus λD<0,036 W/(mK); _SOOJUSTUS - vahtpolüstüreenplaadid EPS 120 Perimeeter, survetugevus min 120kPa, veeimavus <2%, soojuserijuhtivus λD<0,036 W/(mK); _KANDETARIND - monoliitne raudbetoon vastavalt EK osale
AC_Pset_RenovationAndPhasing - Renovation Status: New
Name | 605_Neto_pindala (m2) | 600_Bruto_pindala (m2)
Vundament | 49.7574 | 49.7973
Vundament | 12.6661 | 13.2692
Vundament | 61.2228 | 61.8458
Vundament | 39.4493 | 41.0434
Vundament | 28.7313 | 30.3054
Vundament | 30.3855 | 31.3703
Vundament | 18.5078 | 19.1104
Vundament | 16.1803 | 17.1712
Vundament | 1.49707 | 3.0712
Vundament | 2.02371 | 2.62623
Vundament | 11.4513 | 12.0538

# IfcWall: Lintvundament C plokk 1602 x 765 (2)
In: Vundament
Classification: 1.24 IfcWallType (sein) (RKAS BIM + ARCHICAD Classification)
Pset_WallCommon - Reference: Lintvundament C plokk; LoadBearing: yes; IsExternal: yes
AR_Sein - 001_Nimetus: Vundament; 205_Tüüp: Lintvundament C plokk; 325_Helipidavus: -; 330_Tulekindlus: nõudeid ei esitata; 335_Välispiire: yes; 340_Soojusläbivus: 0; 505_Paksus: 1602.41 mm; 500_Kandev: TRUE; 376_Viimistlus_väljast (MUDELIS): _TUULETÕKE - sokli krohv, silikoonvaikkrohv Weber.pas 481 AquaBalance 1mm "scratch" viimistlus, toon helehall CL444 (S 3502-Y) * 35, SILS süsteem, või samaväärne; _HÜDROISOLATSIOON - tsemendil baseeruv ühekomponentne hüdroisolatsioon hüdroisoleerimiseks sokli krohvi pealt, ülevärvitud silikoonvaikvärviga sokli krohvi tooni, Weber.tec 824 ja Weber.ton 411 AquaBalance toon CL444 (S 3502-Y) * 35 või samaväärne; _SOOJUSTUS - vahtpolüstüreenplaadid EPS 120 Perimeeter, survetugevus min 120kPa, veeimavus <2%, soojuserijuhtivus λD<0,036 W/(mK); _HÜDROISOLATSIOON - Bituumenvõõp COMBIFLEX-EL vastavalt TL2 nõuetele; _SOOJUSTUS - vahtpolüstüreenplaadid EPS 120 Perimeeter, survetugevus min 120kPa, veeimavus <2%, soojuserijuhtivus λD<0,036 W/(mK); _ALUSKATE - drenaaži- ja kaitsematt geotekstiiliga soojustuse kaitseks, Interplast Iso-Drain 8 Geo või samaväärne; _SOOJUSTUS - vahtpolüstüreenplaadid EPS 120 Perimeeter, survetugevus min 120kPa, veeimavus <2%, soojuserijuhtivus λD<0,036 W/(mK); _SOOJUSTUS - vahtpolüstüreenplaadid EPS 120 Perimeeter, survetugevus min 120kPa, veeimavus <2%, soojuserijuhtivus λD<0,036 W/(mK); _SOOJUSTUS - ekstrudeeritud polüstüreenist plaadid XPS 250, survetugevus min 250kPa, soojuserijuhtivus λD<0,036 W/(mK), veeimavus alla 0,2%, näiteks XPS 250 foam SL või samaväärne; _KANDETARIND - monoliitne raudbetoon vastavalt EK osale
AC_Pset_RenovationAndPhasing - Renovation Status: New
Name | 605_Neto_pindala (m2) | 600_Bruto_pindala (m2)
Vundament | 39.4493 | 41.0434
Vundament | 61.806 | 61.8458

# IfcWall: Puit 20, ASTMESTIK
In: 1. korrus
Classification: 1.24 IfcWallType (sein) (RKAS BIM + ARCHICAD Classification); Material: Puit
Pset_WallCommon - Reference: Puit; LoadBearing: no; IsExternal: no
AR_Sein - 001_Nimetus: Vastavalt SA osale; 205_Tüüp: Puit; 325_Helipidavus: nõudeid ei esitata; 330_Tulekindlus: nõudeid ei esitata; 335_Välispiire: no; 340_Soojusläbivus: 0; 376_Viimistlus_väljast: Telje poolne pind: Puit; Telje vastaspoolne pind: Puit; 505_Paksus: 20 mm; 605_Neto_pindala: 0.41468 m2; 600_Bruto_pindala: 0.487881 m2; 500_Kandev: FALSE; 376_Viimistlus_väljast (MUDELIS): Puit
AC_Pset_RenovationAndPhasing - Renovation Status: New

# IfcWall: SS-CLT-12/1_jõusaal 65 dB 554 (2)
In: 2. korrus
Classification: 1.24 IfcWallType (sein) (RKAS BIM + ARCHICAD Classification)
Pset_WallCommon - Reference: SS-CLT-12/1; LoadBearing: yes; IsExternal: no
AR_Sein - 001_Nimetus: Sisesein; 205_Tüüp: SS-CLT-12/1; 325_Helipidavus: 65 dB; 330_Tulekindlus: REI 60; 335_Välispiire: no; 340_Soojusläbivus: 0; 376_Viimistlus_väljast: Telje poolne pind: TOON- vastavalt SA osale; Telje vastaspoolne pind: TOON- vastavalt SA osale; 505_Paksus: 554 mm; 500_Kandev: TRUE; 376_Viimistlus_väljast (MUDELIS): _VIIMISTLUSKIHT - viimistlus vastavalt SA osale; _PLAATMATERJAL - tuletõkkekipsplaat, Knauf Red GKF või samaväärne; _PLAATMATERJAL - OSB3 plaat; _KARKASS - mütsprofiil MP-27, kuumtsingitud teras; _KANDETARIND - CLT ristkihtliimpuit vastavalt EK osale, CLT paigaldusvuugid teibitakse ROTHOBLAAS teibiga; _PLAATMATERJAL - tuletõkkekipsplaat, Knauf Red GKF või samaväärne; _KARKASS - puitroov 70x45mm vertikaalne, samm 600mm, vahel mineraalvill, helineeldetegur αw = 1.0, ISOVER ACOUSTIC 70mm või samaväärne; _ÕHKVAHE; _KARKASS - puitroov 70x45mm vertikaalne, samm 600mm, vahel mineraalvill, helineeldetegur αw = 1.0, ISOVER ACOUSTIC 70mm või samaväärne; _PLAATMATERJAL - tuletõkkekipsplaat, Knauf Red GKF või samaväärne; _KANDETARIND - CLT ristkihtliimpuit vastavalt EK osale, CLT paigaldusvuugid teibitakse ROTHOBLAAS teibiga; _KARKASS - mütsprofiil MP-27, kuumtsingitud teras; _PLAATMATERJAL - tuletõkkekipsplaat, Knauf Red GKF või samaväärne; _PLAATMATERJAL - tuletõkkekipsplaat, Knauf Red GKF või samaväärne; _VIIMISTLUSKIHT - viimistlus vastavalt SA osale
AC_Pset_RenovationAndPhasing - Renovation Status: New
Name | 605_Neto_pindala (m2) | 600_Bruto_pindala (m2)
Sisesein | 11.0266 | 14.1638
Sisesein | 23.8997 | 28.5378

# IfcWall: SS-CLT-12/3_Tehno 65 dB õhuvõturuumis 857, Sisesein
In: 4. TEHNO korrus
Classification: 1.24 IfcWallType (sein) (RKAS BIM + ARCHICAD Classification)
Pset_WallCommon - Reference: SS-CLT-12/3; LoadBearing: yes; IsExternal: no
AR_Sein - 001_Nimetus: Sisesein; 205_Tüüp: SS-CLT-12/3; 325_Helipidavus: 65 dB; 330_Tulekindlus: REI 60; 335_Välispiire: no; 340_Soojusläbivus: 0; 376_Viimistlus_väljast: Telje poolne pind: TOON- helehall RR21; Telje vastaspoolne pind: TOON- vastavalt SA osale; 505_Paksus: 856.5 mm; 605_Neto_pindala: 2.90496 m2; 600_Bruto_pindala: 4.79055 m2; 500_Kandev: TRUE; 376_Viimistlus_väljast (MUDELIS): _VÄLISVIIMISTLUS - kiudtsemendist fassaadikatteplaat, tuletundlikkus A2-s1, d0, Cembrit Cover toon hall C 020 või samaväärne; _KARKASS - puitroov 50x50mm horisontaalne, sügavimmutatud, samm 600mm; _KARKASS - puitroov 32x50mm vertikaalne, immutatud Driconi tulekaitsevahendiga või samaväärne, samm 600mm; _TUULETÕKE - tuuletõkkeplaat, soojuserijuhtivus λD<0,031 W/(mK), ISOVER RKL FACADE või samaväärne, liitekohad katta tihendusteibiga ISOVER FacadeTape või samaväärne; _KARKASS - puitpruss 195x45mm sammuga 600mm vastavalt EK osale, vahel SOOJUSTUS - mineraalvill, soojuserijuhtivus λD<0,032 W/(mK), ISOVER EXTREME 32 200mm või samaväärne; _KANDETARIND - CLT ristkihtliimpuit vastavalt EK osale, CLT paigaldusvuugid teibitakse ROTHOBLAAS teibiga; _PLAATMATERJAL - tuletõkkekipsplaat, Knauf Red GKF või samaväärne; _KARKASS - puitroov 70x45mm vertikaalne, samm 600mm, vahel mineraalvill, helineeldetegur αw = 1.0, ISOVER ACOUSTIC 70mm või samaväärne; _ÕHKVAHE; _KARKASS - puitroov 70x45mm vertikaalne, samm 600mm, vahel mineraalvill, helineeldetegur αw = 1.0, ISOVER ACOUSTIC 70mm või samaväärne; _PLAATMATERJAL - tuletõkkekipsplaat, Knauf Red GKF või samaväärne; _KANDETARIND - CLT ristkihtliimpuit vastavalt EK osale, CLT paigaldusvuugid teibitakse ROTHOBLAAS teibiga; _KARKASS - mütsprofiil MP-27, kuumtsingitud teras; _PLAATMATERJAL - niiskuskindel vineerplaat, kvaliteediklass BB; _PLAATMATERJAL - tuletõkkekipsplaat, Knauf Red GKF või samaväärne; _SOOJUSTUS - akustiline vill Ecophon Industry must TAL PE 50mm või samaväärne; _VIIMISTLUSKIHT - viimistlus vastavalt SA osale
AC_Pset_RenovationAndPhasing - Renovation Status: New

# IfcWall: SS-CLT-12/4_Tehno 65 dB auditoorium 594, Sisesein
In: 4. TEHNO korrus
Classification: 1.24 IfcWallType (sein) (RKAS BIM + ARCHICAD Classification)
Pset_WallCommon - Reference: SS-CLT-12/4; LoadBearing: yes; IsExternal: no
AR_Sein - 001_Nimetus: Sisesein; 205_Tüüp: SS-CLT-12/4; 325_Helipidavus: 65 dB; 330_Tulekindlus: REI 60; 335_Välispiire: no; 340_Soojusläbivus: 0; 376_Viimistlus_väljast: Telje poolne pind: TOON- vastavalt SA osale; Telje vastaspoolne pind: TOON- vastavalt SA osale; 505_Paksus: 593.5 mm; 605_Neto_pindala: 0 m2; 600_Bruto_pindala: 0 m2; 500_Kandev: TRUE; 376_Viimistlus_väljast (MUDELIS): _VIIMISTLUSKIHT - viimistlus vastavalt SA osale; _PLAATMATERJAL - tuletõkkekipsplaat, Knauf Red GKF või samaväärne; _PLAATMATERJAL - tuletõkkekipsplaat, Knauf Red GKF või samaväärne; _KARKASS - mütsprofiil MP-27, kuumtsingitud teras; _KANDETARIND - CLT ristkihtliimpuit vastavalt EK osale, CLT paigaldusvuugid teibitakse ROTHOBLAAS teibiga; _PLAATMATERJAL - tuletõkkekipsplaat, Knauf Red GKF või samaväärne; _KARKASS - puitroov 70x45mm vertikaalne, samm 600mm, vahel mineraalvill, helineeldetegur αw = 1.0, ISOVER ACOUSTIC 70mm või samaväärne; _ÕHKVAHE; _KARKASS - puitroov 70x45mm vertikaalne, samm 600mm, vahel mineraalvill, helineeldetegur αw = 1.0, ISOVER ACOUSTIC 70mm või samaväärne; _PLAATMATERJAL - tuletõkkekipsplaat, Knauf Red GKF või samaväärne; _KANDETARIND - CLT ristkihtliimpuit vastavalt EK osale, CLT paigaldusvuugid teibitakse ROTHOBLAAS teibiga; _KARKASS - mütsprofiil MP-27, kuumtsingitud teras; _PLAATMATERJAL - niiskuskindel vineerplaat, kvaliteediklass BB; _PLAATMATERJAL - tuletõkkekipsplaat, Knauf Red GKF või samaväärne; _SOOJUSTUS - akustiline vill Ecophon Industry must TAL PE 50mm või samaväärne; _VIIMISTLUSKIHT - viimistlus vastavalt SA osale
AC_Pset_RenovationAndPhasing - Renovation Status: New

# IfcWall: SS-CLT-12/5_Klass-võimla 65 dB 527, Sisesein
In: 2. korrus
Classification: 1.24 IfcWallType (sein) (RKAS BIM + ARCHICAD Classification)
Pset_WallCommon - Reference: SS-CLT-12/5; LoadBearing: yes; IsExternal: no
AR_Sein - 001_Nimetus: Sisesein; 205_Tüüp: SS-CLT-12/5; 325_Helipidavus: 65 dB; 330_Tulekindlus: REI 60; 335_Välispiire: no; 340_Soojusläbivus: 0; 376_Viimistlus_väljast: Telje poolne pind: TOON- vastavalt SA osale; Telje vastaspoolne pind: PUIT- Woodex 1820; 505_Paksus: 527 mm; 605_Neto_pindala: 0 m2; 600_Bruto_pindala: 7.97238 m2; 500_Kandev: TRUE; 376_Viimistlus_väljast (MUDELIS): _VIIMISTLUSKIHT - viimistlus vastavalt SA osale; _PLAATMATERJAL - tuletõkkekipsplaat, Knauf Red GKF või samaväärne; _PLAATMATERJAL - OSB3 plaat; _KARKASS - mütsprofiil MP-27, kuumtsingitud teras; _KANDETARIND - CLT ristkihtliimpuit vastavalt EK osale, CLT paigaldusvuugid teibitakse ROTHOBLAAS teibiga; _PLAATMATERJAL - tuletõkkekipsplaat, Knauf Red GKF või samaväärne; _KARKASS - puitroov 70x45mm vertikaalne, samm 600mm, vahel mineraalvill, helineeldetegur αw = 1.0, ISOVER ACOUSTIC 70mm või samaväärne; _ÕHKVAHE; _KARKASS - puitroov 70x45mm vertikaalne, samm 600mm, vahel mineraalvill, helineeldetegur αw = 1.0, ISOVER ACOUSTIC 70mm või samaväärne; _PLAATMATERJAL - tuletõkkekipsplaat, Knauf Red GKF või samaväärne; _KANDETARIND - CLT ristkihtliimpuit vastavalt EK osale, CLT paigaldusvuugid teibitakse ROTHOBLAAS teibiga; _KARKASS - mütsprofiil MP-27, kuumtsingitud teras; _VIIMISTLUSKIHT - Dold plaat vastavalt SA osale
AC_Pset_RenovationAndPhasing - Renovation Status: New

# IfcWall: SS-CLT-16/10_vineer18+karkass60+CLT+vill75+krohv 378, Sisesein
In: 2. korrus
Classification: 1.24 IfcWallType (sein) (RKAS BIM + ARCHICAD Classification)
Pset_WallCommon - Reference: SS-CLT-16/10; LoadBearing: yes; IsExternal: no
AR_Sein - 001_Nimetus: Sisesein; 205_Tüüp: SS-CLT-16/10; 325_Helipidavus: 52 dB; 330_Tulekindlus: REI 90; 335_Välispiire: no; 340_Soojusläbivus: 0; 376_Viimistlus_väljast: Telje poolne pind: PUIT- mahagon V; Telje vastaspoolne pind: TOON- vastavalt SA osale; 505_Paksus: 378 mm; 605_Neto_pindala: 16.4224 m2; 600_Bruto_pindala: 17.68 m2; 500_Kandev: TRUE; 376_Viimistlus_väljast (MUDELIS): _PLAATMATERJAL - niiskuskindel vineerplaat, kvaliteediklass BB; _KARKASS - puitroov 60x40mm, s. 600mm; _KANDETARIND - CLT ristkihtliimpuit vastavalt EK osale, CLT paigaldusvuugid teibitakse ROTHOBLAAS teibiga; _ÕHKVAHE; _KARKASS - metallkarkass CW 75/50/06 ja UW 75/40/06, samm 600, vahel mineraalvill, helineeldetegur αw = 1.0, ISOVER ACOUSTIC 75mm või samaväärne; _PLAATMATERJAL - OSB3 plaat; _PLAATMATERJAL - tuletõkkekipsplaat, Knauf Red GKF või samaväärne; _PLAATMATERJAL - tuletõkkekipsplaat, Knauf Red GKF või samaväärne; _VIIMISTLUSKIHT - viimistlus vastavalt SA osale
AC_Pset_RenovationAndPhasing - Renovation Status: New

# IfcWall: SS-CLT-16/11_ak. plaat50+vineer12+distansliist18+CLT+vill75+krohv 380, Sisesein
In: 2. korrus
Classification: 1.24 IfcWallType (sein) (RKAS BIM + ARCHICAD Classification)
Pset_WallCommon - Reference: SS-CLT-16/11; LoadBearing: yes; IsExternal: no
AR_Sein - 001_Nimetus: Sisesein; 205_Tüüp: SS-CLT-16/11; 325_Helipidavus: 52 dB; 330_Tulekindlus: EI60; 335_Välispiire: no; 340_Soojusläbivus: 0; 376_Viimistlus_väljast: Telje poolne pind: TOON- must; Telje vastaspoolne pind: TOON- vastavalt SA osale; 505_Paksus: 380 mm; 605_Neto_pindala: 9.56283 m2; 600_Bruto_pindala: 9.5862 m2; 500_Kandev: TRUE; 376_Viimistlus_väljast (MUDELIS): _SOOJUSTUS - akustiline vill Ecophon Industry must TAL PE 50mm või samaväärne; _PLAATMATERJAL - niiskuskindel vineerplaat, kvaliteediklass BB; _KARKASS - distantsliist 18x45mm, s. 600mm; _KANDETARIND - CLT ristkihtliimpuit vastavalt EK osale, CLT paigaldusvuugid teibitakse ROTHOBLAAS teibiga; _ÕHKVAHE; _KARKASS - metallkarkass CW 75/50/06 ja UW 75/40/06, samm 600, vahel mineraalvill, helineeldetegur αw = 1.0, ISOVER ACOUSTIC 75mm või samaväärne; _PLAATMATERJAL - tuletõkkekipsplaat, Knauf Red GKF või samaväärne; _PLAATMATERJAL - tuletõkkekipsplaat, Knauf Red GKF või samaväärne; _VIIMISTLUSKIHT - viimistlus vastavalt SA osale
AC_Pset_RenovationAndPhasing - Renovation Status: New

# IfcWall: SS-CLT-16/12_vineer18+karkass70+CLT+vill75+krohv 388, Sisesein
In: 2. korrus
Classification: 1.24 IfcWallType (sein) (RKAS BIM + ARCHICAD Classification)
Pset_WallCommon - Reference: SS-CLT-16/12; LoadBearing: yes; IsExternal: no
AR_Sein - 001_Nimetus: Sisesein; 205_Tüüp: SS-CLT-16/12; 325_Helipidavus: 52 dB; 330_Tulekindlus: REI 90; 335_Välispiire: no; 340_Soojusläbivus: 0; 376_Viimistlus_väljast: Telje poolne pind: PUIT- mahagon V; Telje vastaspoolne pind: TOON- vastavalt SA osale; 505_Paksus: 388 mm; 605_Neto_pindala: 16.4226 m2; 600_Bruto_pindala: 17.6802 m2; 500_Kandev: TRUE; 376_Viimistlus_väljast (MUDELIS): _PLAATMATERJAL - niiskuskindel vineerplaat, kvaliteediklass BB; _KARKASS - puitroov 70x50mm, s. 600mm; _KANDETARIND - CLT ristkihtliimpuit vastavalt EK osale, CLT paigaldusvuugid teibitakse ROTHOBLAAS teibiga; _ÕHKVAHE; _KARKASS - metallkarkass CW 75/50/06 ja UW 75/40/06, samm 600, vahel mineraalvill, helineeldetegur αw = 1.0, ISOVER ACOUSTIC 75mm või samaväärne; _PLAATMATERJAL - OSB3 plaat; _PLAATMATERJAL - tuletõkkekipsplaat, Knauf Red GKF või samaväärne; _PLAATMATERJAL - tuletõkkekipsplaat, Knauf Red GKF või samaväärne; _VIIMISTLUSKIHT - viimistlus vastavalt SA osale
AC_Pset_RenovationAndPhasing - Renovation Status: New

# IfcWall: SS-CLT-16/13_ak.plaat50+vineer18+distants22+CLT+vill75+krohv 390, Sisesein
In: 2. korrus
Classification: 1.24 IfcWallType (sein) (RKAS BIM + ARCHICAD Classification)
Pset_WallCommon - Reference: SS-CLT-16/13; LoadBearing: yes; IsExternal: no
AR_Sein - 001_Nimetus: Sisesein; 205_Tüüp: SS-CLT-16/13; 325_Helipidavus: 52 dB; 330_Tulekindlus: EI60; 335_Välispiire: no; 340_Soojusläbivus: 0; 376_Viimistlus_väljast: Telje poolne pind: TOON- must; Telje vastaspoolne pind: TOON- vastavalt SA osale; 505_Paksus: 390 mm; 605_Neto_pindala: 9.28408 m2; 600_Bruto_pindala: 9.98545 m2; 500_Kandev: TRUE; 376_Viimistlus_väljast (MUDELIS): _SOOJUSTUS - akustiline vill Ecophon Industry must TAL PE 50mm või samaväärne; _PLAATMATERJAL - niiskuskindel vineerplaat, kvaliteediklass BB; _KARKASS - distantsliist 22x50mm, s. 600mm; _KANDETARIND - CLT ristkihtliimpuit vastavalt EK osale, CLT paigaldusvuugid teibitakse ROTHOBLAAS teibiga; _ÕHKVAHE; _KARKASS - metallkarkass CW 75/50/06 ja UW 75/40/06, samm 600, vahel mineraalvill, helineeldetegur αw = 1.0, ISOVER ACOUSTIC 75mm või samaväärne; _PLAATMATERJAL - tuletõkkekipsplaat, Knauf Red GKF või samaväärne; _PLAATMATERJAL - tuletõkkekipsplaat, Knauf Red GKF või samaväärne; _VIIMISTLUSKIHT - viimistlus vastavalt SA osale
AC_Pset_RenovationAndPhasing - Renovation Status: New

# IfcWall: SS-CLT-16/14_vill75+dold 52 dB 310, Sisesein
In: 1. korrus
Classification: 1.24 IfcWallType (sein) (RKAS BIM + ARCHICAD Classification)
Pset_WallCommon - Reference: SS-CLT-16/14; LoadBearing: yes; IsExternal: no
AR_Sein - 001_Nimetus: Sisesein; 205_Tüüp: SS-CLT-16/14; 325_Helipidavus: 52 dB; 330_Tulekindlus: REI 90; 335_Välispiire: no; 340_Soojusläbivus: 0; 376_Viimistlus_väljast: Telje poolne pind: PUIT- kuusk V; Telje vastaspoolne pind: PUIT- Woodex 1820; 505_Paksus: 310 mm; 605_Neto_pindala: 14.7604 m2; 600_Bruto_pindala: 14.8312 m2; 500_Kandev: TRUE; 376_Viimistlus_väljast (MUDELIS): _KANDETARIND - CLT ristkihtliimpuit vastavalt EK osale, CLT paigaldusvuugid teibitakse ROTHOBLAAS teibiga; _ÕHKVAHE; _KARKASS - metallkarkass CW 75/50/06 ja UW 75/40/06, samm 600, vahel mineraalvill, helineeldetegur αw = 1.0, ISOVER ACOUSTIC 75mm või samaväärne; _PLAATMATERJAL - OSB3 plaat; _PLAATMATERJAL - tuletõkkekipsplaat, Knauf Red GKF või samaväärne; _PLAATMATERJAL - tuletõkkekipsplaat, Knauf Red GKF või samaväärne; _KARKASS - eriprofiilkinnitus vastavalt sisemisele plaatviimistlusele; _VIIMISTLUSKIHT - Dold plaat vastavalt SA osale
AC_Pset_RenovationAndPhasing - Renovation Status: New

# IfcWall: SS-CLT-16/1_vill75+krohv 52 dB 300 (63)
Classification: 1.24 IfcWallType (sein) (RKAS BIM + ARCHICAD Classification)
Pset_WallCommon - Reference: SS-CLT-16/1; IsExternal: no
AR_Sein - 001_Nimetus: Sisesein; 205_Tüüp: SS-CLT-16/1; 335_Välispiire: no; 340_Soojusläbivus: 0; 376_Viimistlus_väljast: Telje poolne pind: PUIT- kuusk V; Telje vastaspoolne pind: TOON- vastavalt SA osale; 505_Paksus: 300 mm; 376_Viimistlus_väljast (MUDELIS): _KANDETARIND - CLT ristkihtliimpuit vastavalt EK osale, CLT paigaldusvuugid teibitakse ROTHOBLAAS teibiga; _ÕHKVAHE; _KARKASS - metallkarkass CW 75/50/06 ja UW 75/40/06, samm 600, vahel mineraalvill, helineeldetegur αw = 1.0, ISOVER ACOUSTIC 75mm või samaväärne; _PLAATMATERJAL - OSB3 plaat; _PLAATMATERJAL - tuletõkkekipsplaat, Knauf Red GKF või samaväärne; _PLAATMATERJAL - tuletõkkekipsplaat, Knauf Red GKF või samaväärne; _VIIMISTLUSKIHT - viimistlus vastavalt SA osale
AC_Pset_RenovationAndPhasing - Renovation Status: New
Name | In | LoadBearing | 325_Helipidavus | 330_Tulekindlus | 605_Neto_pindala (m2) | 600_Bruto_pindala (m2) | 500_Kandev
Sisesein | 1. korrus | yes | 52 dB | REI 60 | 35.2595 | 45.9288 | TRUE
Sisesein | 1. korrus | yes | 52 dB | REI 60 | 21.4694 | 23.8832 | TRUE
Sisesein | 1. korrus | yes | 52 dB | REI 90 | 35.3777 | 38.1482 | TRUE
Sisesein | 1. korrus | yes | 52 dB | REI 60 | 5.9595 | 19.6511 | TRUE
Sisesein | 1. korrus | yes | 52 dB | REI 90 | 9.05574 | 18.1846 | TRUE
Sisesein | 1. korrus | yes | 52 dB | REI 90 | 17.294 | 22.3835 | TRUE
Sisesein | 1. korrus | yes | 52 dB | REI 60 | 31.4001 | 32.2211 | TRUE
Sisesein | 1. korrus | yes | 52 dB | REI 90 | 15.1892 | 18.0172 | TRUE
Sisesein | 1. korrus | yes | 52 dB | REI 60 | 66.8195 | 74.0731 | TRUE
Sisesein | 1. korrus | yes | 52 dB | REI 60 | 7.54359 | 8.25017 | TRUE
Sisesein | 1. korrus | yes | 52 dB | REI 60 | 10.0706 | 10.0706 | TRUE
Sisesein | 1. korrus | yes | 52 dB | REI 60 | 14.2303 | 14.2303 | TRUE
Sisesein | 1. korrus | yes | 52 dB | REI 60 | 13.7746 | 13.7746 | TRUE
Sisesein | 1. korrus | yes | 52 dB | REI 60 | 14.0638 | 14.0638 | TRUE
Sisesein | 1. korrus | yes | 52 dB | REI 90 | 80.9411 | 81.3293 | TRUE
Sisesein | 2. korrus | yes | 55 dB | REI 60 | 6.9 | 6.9 | TRUE
Sisesein | 2. korrus | yes | 52 dB | REI 60 | 17.1274 | 17.2184 | TRUE
Sisesein | 2. korrus | yes | 52 dB | REI 60 | 26.3925 | 28.3221 | TRUE
Sisesein | 2. korrus | yes | 52 dB | REI 60 | 77.8246 | 106.681 | TRUE
Sisesein | 2. korrus | yes | 52 dB | REI 60 | 13.0924 | 15.9232 | TRUE
Sisesein | 2. korrus | yes | 52 dB | REI 60 | 21.5086 | 32.5617 | TRUE
Sisesein | 2. korrus | yes | 52 dB | REI 60 | 38.6295 | 46.1857 | TRUE
Sisesein | 2. korrus | yes | 52 dB | REI 60 | 25.9785 | 27.2226 | TRUE
Sisesein | 2. korrus | yes | 52 dB | REI 60 | 61.5937 | 73.6335 | TRUE
Sisesein | 2. korrus | yes | 52 dB | REI 60 | 10.833 | 15.4068 | TRUE
Sisesein | 2. korrus | yes | 52 dB | REI 60 | 1.65718 | 1.78115 | TRUE
Sisesein | 2. korrus | yes | 52 dB | EI60 | 5.89864 | 25.1329 | TRUE
Sisesein | 2. korrus | yes | 52 dB | REI 60 | 27.2804 | 28.8898 | TRUE
Sisesein | 2. korrus | yes | 52 dB | REI 60 | 13.5616 | 16.6558 | TRUE
Sisesein | 2. korrus | no | 52 dB | REI 60 | 8.82716 | 9.86216 | FALSE
Sisesein | 2. korrus | yes | 52 dB | REI 60 | 1.65737 | 1.93336 | TRUE
Sisesein | 2. korrus | yes | 52 dB | REI 60 | 29.0468 | 33.8314 | TRUE
Sisesein | 2. korrus | yes | 52 dB | REI 60 | 13.4283 | 33.5896 | TRUE
Sisesein | 2. korrus | yes | 52 dB | REI 60 | 10.8672 | 11.4854 | TRUE
Sisesein | 2. korrus | yes | 52 dB | REI 60 | 40.8615 | 55.7629 | TRUE
Sisesein | 2. korrus | yes | 52 dB | REI 60 | 6.9 | 7.5 | TRUE
Sisesein | 2. korrus | yes | 52 dB | REI 60 | 73.4468 | 87.3466 | TRUE
Sisesein | 2. korrus | yes | 52 dB | REI 60 | 10.8716 | 11.4236 | TRUE
Sisesein | 2. korrus | yes | 52 dB | REI 60 | 11.3493 | 12.9103 | TRUE
Sisesein | 2. korrus | yes | 52 dB | REI 60 | 51.6664 | 59.5289 | TRUE
Sisesein | 2. korrus | no | 52 dB | REI 60 | 10.1085 | 10.1671 | FALSE
Sisesein | 2. korrus | yes | 52 dB | REI 60 | 15.7653 | 22.5783 | TRUE
Sisesein | 2. korrus | yes | 52 dB | REI 60 | 7.33063 | 10.9756 | TRUE
Sisesein | 3. korrus | yes | 52 dB | REI 60 | 13.9011 | 13.9347 | TRUE
Sisesein | 3. korrus | yes | 52 dB | REI 60 | 51.192 | 63.18 | TRUE
Sisesein | 3. korrus | yes | 52 dB | REI 60 | 6.0722 | 7.72892 | TRUE
Sisesein | 3. korrus | yes | 52 dB | REI 60 | 50.66 | 58.845 | TRUE
Sisesein | 3. korrus | yes | 52 dB | REI 60 | 26.2548 | 28.4731 | TRUE
Sisesein | 3. korrus | yes | 52 dB | REI 60 | 49.2698 | 63.145 | TRUE
Sisesein | 3. korrus | yes | 52 dB | REI 60 | 69.9583 | 81.7438 | TRUE
Sisesein | 3. korrus | yes | 52 dB | REI 60 | 51.379 | 52.1588 | TRUE
Sisesein | 3. korrus | yes | 52 dB | REI 60 | 20.5553 | 27.659 | TRUE
Sisesein | 3. korrus | yes | 52 dB | REI 60 | 8.95046 | 9.56626 | TRUE
Sisesein | 3. korrus | yes | 55 dB | REI 60 | 6.2192 | 6.2192 | TRUE
Sisesein | 3. korrus | yes | 52 dB | REI 60 | 10.495 | 11.2671 | TRUE
Sisesein | 3. korrus | yes | 52 dB | REI 60 | 30.0996 | 39.1406 | TRUE
Sisesein | 3. korrus | yes | 52 dB | REI 60 | 45.3654 | 56.3004 | TRUE
Sisesein | 3. korrus | yes | 52 dB | REI 60 | 15.5493 | 15.5493 | TRUE
Sisesein | 3. korrus | yes | 52 dB | REI 60 | 75.0288 | 88.3535 | TRUE
Sisesein | 3. korrus | yes | 52 dB | REI 60 | 7.02 | 7.02 | TRUE
Sisesein | 3. korrus | yes | 52 dB | REI 60 | 30.5775 | 35.2755 | TRUE
Sisesein | 3. korrus | yes | 52 dB | REI 60 | 102.805 | 122.922 | TRUE
Sisesein | 3. korrus | yes | 52 dB | REI 60 | 8.0519 | 12.9792 | TRUE

# IfcWall: SS-CLT-16/2_vill75 +plaat 300 (4)
In: 1. korrus
Classification: 1.24 IfcWallType (sein) (RKAS BIM + ARCHICAD Classification)
Pset_WallCommon - Reference: SS-CLT-16/2; LoadBearing: yes; IsExternal: no
AR_Sein - 001_Nimetus: Sisesein; 205_Tüüp: SS-CLT-16/2; 325_Helipidavus: 52 dB; 330_Tulekindlus: REI 60; 335_Välispiire: no; 340_Soojusläbivus: 0; 376_Viimistlus_väljast: Telje poolne pind: PUIT- kuusk V; Telje vastaspoolne pind: TOON- vastavalt SA osale; 505_Paksus: 300 mm; 500_Kandev: TRUE; 376_Viimistlus_väljast (MUDELIS): _KANDETARIND - CLT ristkihtliimpuit vastavalt EK osale, CLT paigaldusvuugid teibitakse ROTHOBLAAS teibiga; _ÕHKVAHE; _KARKASS - metallkarkass CW 75/50/06 ja UW 75/40/06, samm 600, vahel mineraalvill, helineeldetegur αw = 1.0, ISOVER ACOUSTIC 75mm või samaväärne; _PLAATMATERJAL - tuletõkkekipsplaat, Knauf Red GKF või samaväärne; _PLAATMATERJAL - tuletõkkekipsplaat, Knauf Red GKF või samaväärne; _VIIMISTLUSKIHT - viimistlus vastavalt SA osale
AC_Pset_RenovationAndPhasing - Renovation Status: New
Name | 605_Neto_pindala (m2) | 600_Bruto_pindala (m2)
Sisesein | 11.577 | 11.577
Sisesein | 9.62552 | 9.62552
Sisesein | 10.2278 | 10.2278
Sisesein | 10.1607 | 10.8311

# IfcWall: SS-CLT-16/3_vill+plaat märgruumid 285 (6)
In: 1. korrus
Classification: 1.24 IfcWallType (sein) (RKAS BIM + ARCHICAD Classification)
Pset_WallCommon - Reference: SS-CLT-16/3; LoadBearing: yes; IsExternal: no
AR_Sein - 001_Nimetus: Sisesein; 205_Tüüp: SS-CLT-16/3; 325_Helipidavus: 45 dB; 330_Tulekindlus: REI 60; 335_Välispiire: no; 340_Soojusläbivus: 0; 376_Viimistlus_väljast: Telje poolne pind: PUIT- kuusk V; Telje vastaspoolne pind: TOON- vastavalt SA osale; 505_Paksus: 285 mm; 500_Kandev: TRUE; 376_Viimistlus_väljast (MUDELIS): _KANDETARIND - CLT ristkihtliimpuit vastavalt EK osale, CLT paigaldusvuugid teibitakse ROTHOBLAAS teibiga; _ÕHKVAHE; _KARKASS - metallkarkass CW 75/50/06 ja UW 75/40/06, samm 600; _PLAATMATERJAL - kipsplaat veekindel; _PLAATMATERJAL - kipsplaat veekindel; _HÜDROISLOATSIOON - märgruumidesse; _VIIMISTLUSKIHT - viimistlus vastavalt SA osale
AC_Pset_RenovationAndPhasing - Renovation Status: New
Name | 605_Neto_pindala (m2) | 600_Bruto_pindala (m2)
Sisesein | 14.0453 | 15.0944
Sisesein | 16.5278 | 17.6438
Sisesein | 16.587 | 17.7046
Sisesein | 6.30581 | 8.23562
Sisesein | 9.27387 | 10.1943
Sisesein | 9.17187 | 10.0896

# IfcWall: SS-CLT-16/4_1xplaaditud 285 (3)
In: 1. korrus
Classification: 1.24 IfcWallType (sein) (RKAS BIM + ARCHICAD Classification)
Pset_WallCommon - Reference: SS-CLT-16/4; LoadBearing: yes; IsExternal: no
AR_Sein - 001_Nimetus: Sisesein; 205_Tüüp: SS-CLT-16/4; 325_Helipidavus: 45 dB; 335_Välispiire: no; 340_Soojusläbivus: 0; 376_Viimistlus_väljast: Telje poolne pind: PUIT- kuusk V; Telje vastaspoolne pind: KERAAMILINE PLAAT- liiva hall 25x25 mm, tumehall vuuk; 505_Paksus: 285 mm; 500_Kandev: TRUE; 376_Viimistlus_väljast (MUDELIS): _KANDETARIND - CLT ristkihtliimpuit vastavalt EK osale, CLT paigaldusvuugid teibitakse ROTHOBLAAS teibiga; _ÕHKVAHE; _KARKASS - metallkarkass CW 75/50/06 ja UW 75/40/06, samm 600; _PLAATMATERJAL - kipsplaat veekindel; _PLAATMATERJAL - kipsplaat veekindel; _HÜDROISLOATSIOON - märgruumidesse; _VIIMISTLUSKIHT - keraamiline plaat sein
AC_Pset_RenovationAndPhasing - Renovation Status: New
Name | 330_Tulekindlus | 605_Neto_pindala (m2) | 600_Bruto_pindala (m2)
Sisesein | REI 90 | 14.2946 | 15.0337
Sisesein | REI 60 | 9.074 | 9.78792
Sisesein | REI 60 | 19.9984 | 25.5322

# IfcWall: SS-CLT-16/5_vill75+värv 52 dB 292 (12)
Classification: 1.24 IfcWallType (sein) (RKAS BIM + ARCHICAD Classification)
Pset_WallCommon - Reference: SS-CLT-16/5; LoadBearing: yes; IsExternal: no
AR_Sein - 001_Nimetus: Sisesein; 205_Tüüp: SS-CLT-16/5; 325_Helipidavus: 52 dB; 335_Välispiire: no; 340_Soojusläbivus: 0; 376_Viimistlus_väljast: Telje poolne pind: PUIT- kuusk V; Telje vastaspoolne pind: TOON- vastavalt SA osale; 505_Paksus: 292 mm; 500_Kandev: TRUE; 376_Viimistlus_väljast (MUDELIS): _KANDETARIND - CLT ristkihtliimpuit vastavalt EK osale, CLT paigaldusvuugid teibitakse ROTHOBLAAS teibiga; _ÕHKVAHE; _KARKASS - metallkarkass CW 75/50/06 ja UW 75/40/06, samm 600, vahel mineraalvill, helineeldetegur αw = 1.0, ISOVER ACOUSTIC 75mm või samaväärne; _PLAATMATERJAL - tuletõkkekipsplaat, Knauf Red GKF või samaväärne; _PLAATMATERJAL - tuletõkkekipsplaat, Knauf Red GKF või samaväärne; _VIIMISTLUSKIHT - viimistlus vastavalt SA osale
AC_Pset_RenovationAndPhasing - Renovation Status: New
Name | In | 330_Tulekindlus | 605_Neto_pindala (m2) | 600_Bruto_pindala (m2)
Sisesein | 2. korrus | REI 90 | 23.0798 | 27.2394
Sisesein | 2. korrus | REI 60 | 7.6095 | 10.0977
Sisesein | 2. korrus | REI 60 | 1.54299 | 1.55194
Sisesein | 2. korrus | REI 90 | 15.801 | 16.5426
Sisesein | 2. korrus | REI 60 | 5.01059 | 7.52685
Sisesein | 2. korrus | REI 60 | 25.0056 | 25.1506
Sisesein | 2. korrus | REI 90 | 20.3523 | 32.4238
Sisesein | 3. korrus | REI 60 | 26.1495 | 26.2985
Sisesein | 3. korrus | REI 60 | 11.6731 | 12.6807
Sisesein | 3. korrus | REI 60 | 12.2519 | 13.4298
Sisesein | 3. korrus | REI 90 | 11.9541 | 12.5386
Sisesein | 3. korrus | REI 60 | 10.9289 | 11.4478

# IfcWall: SS-CLT-16/6_vill75 +värv 292, Sisesein
In: 1. korrus
Classification: 1.24 IfcWallType (sein) (RKAS BIM + ARCHICAD Classification)
Pset_WallCommon - Reference: SS-CLT-16/6; LoadBearing: yes; IsExternal: no
AR_Sein - 001_Nimetus: Sisesein; 205_Tüüp: SS-CLT-16/6; 325_Helipidavus: 40 dB; 330_Tulekindlus: REI 90; 335_Välispiire: no; 340_Soojusläbivus: 0; 376_Viimistlus_väljast: Telje poolne pind: PUIT- kuusk V; Telje vastaspoolne pind: TOON- vastavalt SA osale; 505_Paksus: 292 mm; 605_Neto_pindala: 22.5346 m2; 600_Bruto_pindala: 23.3131 m2; 500_Kandev: TRUE; 376_Viimistlus_väljast (MUDELIS): _KANDETARIND - CLT ristkihtliimpuit vastavalt EK osale, CLT paigaldusvuugid teibitakse ROTHOBLAAS teibiga; _ÕHKVAHE; _KARKASS - metallkarkass CW 75/50/06 ja UW 75/40/06, samm 600, vahel mineraalvill, helineeldetegur αw = 1.0, ISOVER ACOUSTIC 75mm või samaväärne; _PLAATMATERJAL - tuletõkkekipsplaat, Knauf Red GKF või samaväärne; _PLAATMATERJAL - tuletõkkekipsplaat, Knauf Red GKF või samaväärne; _VIIMISTLUSKIHT - viimistlus vastavalt SA osale
AC_Pset_RenovationAndPhasing - Renovation Status: New

# IfcWall: SS-CLT-16/7_viimistluseta 160 (7)
Classification: 1.24 IfcWallType (sein) (RKAS BIM + ARCHICAD Classification); Material: _KANDETARIND - CLT ristkihtliimpuit vastavalt EK osale, CLT paigaldusvuugid teibitakse ROTHOBLAAS teibiga
Pset_WallCommon - Reference: SS-CLT-16/7; LoadBearing: yes; IsExternal: no
AR_Sein - 001_Nimetus: Sisesein; 205_Tüüp: SS-CLT-16/7; 335_Välispiire: no; 340_Soojusläbivus: 0; 376_Viimistlus_väljast: Telje poolne pind: PUIT- kuusk V; Telje vastaspoolne pind: PUIT- kuusk V; 505_Paksus: 160 mm; 500_Kandev: TRUE; 376_Viimistlus_väljast (MUDELIS): _KANDETARIND - CLT ristkihtliimpuit vastavalt EK osale, CLT paigaldusvuugid teibitakse ROTHOBLAAS teibiga
AC_Pset_RenovationAndPhasing - Renovation Status: New
Name | In | 325_Helipidavus | 330_Tulekindlus | 605_Neto_pindala (m2) | 600_Bruto_pindala (m2)
Sisesein | 1. korrus | 45 dB | REI 60 | 1.10924 | 3.44001
Sisesein | 1. korrus | 45 dB | REI 90 | 8.66107 | 8.70261
Sisesein | 1. korrus | 30 dB | REI 60 | 10.5753 | 10.8604
Sisesein | 1. korrus | 30 dB | REI 60 | 5.1247 | 5.26286
Sisesein | 1. korrus | 30 dB | REI 60 | 5.16754 | 6.39626
Sisesein | 2. korrus | 52 dB | EI60 | 1.27139 | 3.25268
Sisesein | 2. korrus | 52 dB | REI 60 | 2.53773 | 2.53773

# IfcWall: SS-CLT-16/8_karkass30+CLT+vill75+krohv 350, Sisesein
In: 3. korrus
Classification: 1.24 IfcWallType (sein) (RKAS BIM + ARCHICAD Classification)
Pset_WallCommon - Reference: SS-CLT-16/8; LoadBearing: yes; IsExternal: no
AR_Sein - 001_Nimetus: Sisesein; 205_Tüüp: SS-CLT-16/8; 325_Helipidavus: 52 dB; 330_Tulekindlus: REI 60; 335_Välispiire: no; 340_Soojusläbivus: 0; 376_Viimistlus_väljast: Telje poolne pind: PUIT- kuusk H; Telje vastaspoolne pind: TOON- vastavalt SA osale; 505_Paksus: 350 mm; 605_Neto_pindala: 11.271 m2; 600_Bruto_pindala: 12.838 m2; 500_Kandev: TRUE; 376_Viimistlus_väljast (MUDELIS): _KARKASS - puitroov 50x110mm, s. 600mm; _KANDETARIND - CLT ristkihtliimpuit vastavalt EK osale, CLT paigaldusvuugid teibitakse ROTHOBLAAS teibiga; _ÕHKVAHE; _KARKASS - metallkarkass CW 75/50/06 ja UW 75/40/06, samm 600, vahel mineraalvill, helineeldetegur αw = 1.0, ISOVER ACOUSTIC 75mm või samaväärne; _PLAATMATERJAL - OSB3 plaat; _PLAATMATERJAL - tuletõkkekipsplaat, Knauf Red GKF või samaväärne; _PLAATMATERJAL - tuletõkkekipsplaat, Knauf Red GKF või samaväärne; _VIIMISTLUSKIHT - viimistlus vastavalt SA osale
AC_Pset_RenovationAndPhasing - Renovation Status: New

# IfcWall: SS-CLT-16/9_must fliis+vineer18+karkass110+CLT+vill75+krohv 350, Sisesein
In: 3. korrus
Classification: 1.24 IfcWallType (sein) (RKAS BIM + ARCHICAD Classification)
Pset_WallCommon - Reference: SS-CLT-16/9; LoadBearing: yes; IsExternal: no
AR_Sein - 001_Nimetus: Sisesein; 205_Tüüp: SS-CLT-16/9; 325_Helipidavus: 52 dB; 330_Tulekindlus: REI 60; 335_Välispiire: no; 340_Soojusläbivus: 0; 376_Viimistlus_väljast: Telje poolne pind: TOON- must; Telje vastaspoolne pind: TOON- vastavalt SA osale; 505_Paksus: 350 mm; 605_Neto_pindala: 3.96428 m2; 600_Bruto_pindala: 3.96428 m2; 500_Kandev: TRUE; 376_Viimistlus_väljast (MUDELIS): _SOOJUSTUS - akustiline vill Ecophon Industry must TAL PE 50mm või samaväärne; _KANDETARIND - CLT ristkihtliimpuit vastavalt EK osale, CLT paigaldusvuugid teibitakse ROTHOBLAAS teibiga; _ÕHKVAHE; _KARKASS - metallkarkass CW 75/50/06 ja UW 75/40/06, samm 600, vahel mineraalvill, helineeldetegur αw = 1.0, ISOVER ACOUSTIC 75mm või samaväärne; _PLAATMATERJAL - tuletõkkekipsplaat, Knauf Red GKF või samaväärne; _PLAATMATERJAL - tuletõkkekipsplaat, Knauf Red GKF või samaväärne; _VIIMISTLUSKIHT - viimistlus vastavalt SA osale
AC_Pset_RenovationAndPhasing - Renovation Status: New

# IfcWall: SS-CLT-20/1_vill+krohv 340 (11)
In: 1. korrus
Classification: 1.24 IfcWallType (sein) (RKAS BIM + ARCHICAD Classification)
Pset_WallCommon - Reference: SS-CLT-20/1; IsExternal: no
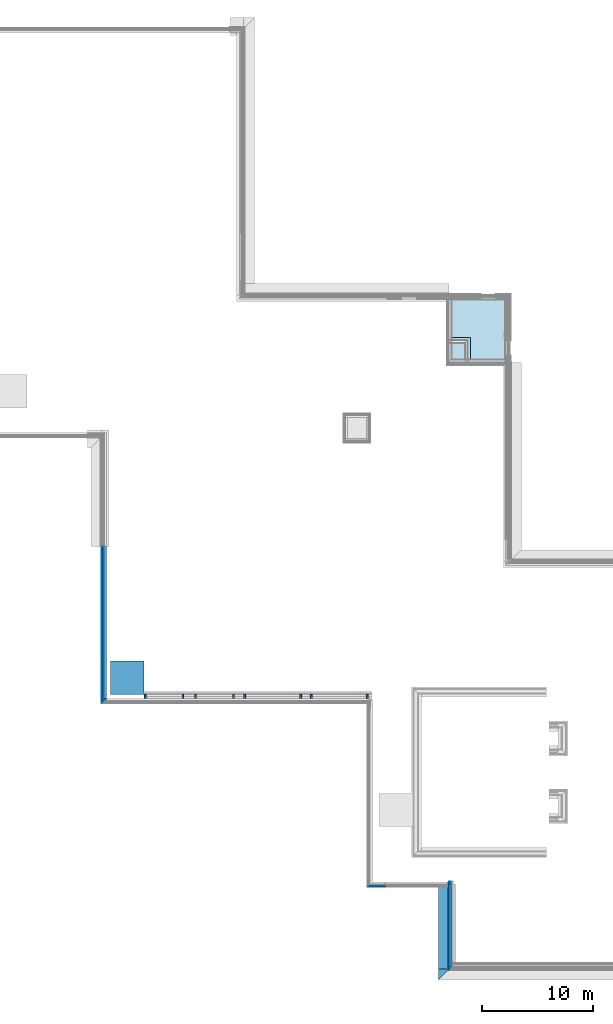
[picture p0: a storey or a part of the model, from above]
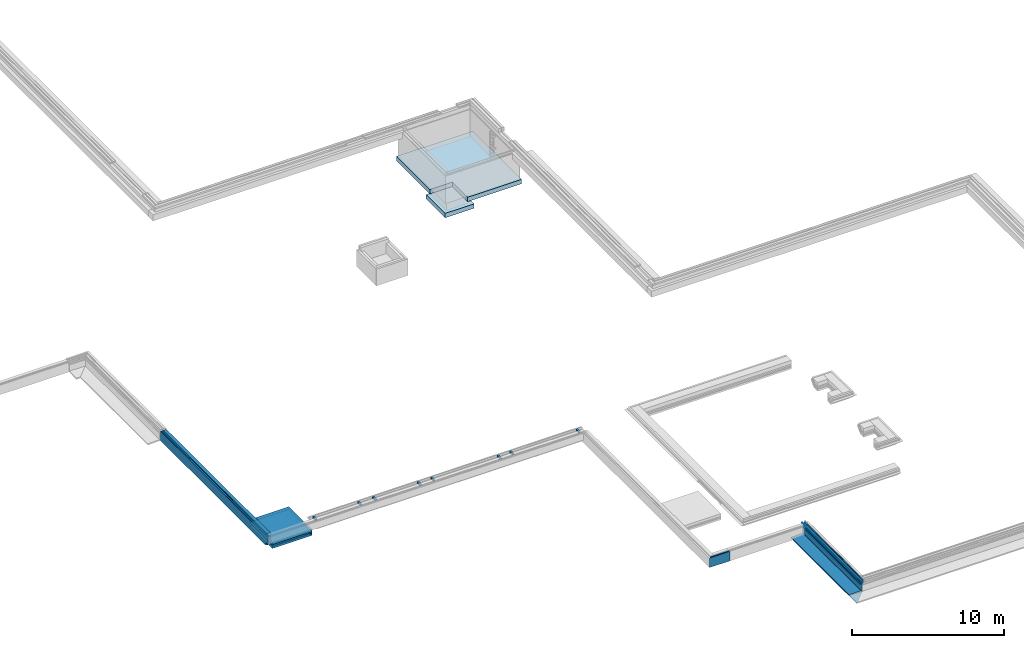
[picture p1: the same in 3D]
Properties of the parts of a building model (IFC2X3), part 11 of 14

# IfcWall: SS-CLT-20/1_vill+krohv 340 (11)
AR_Sein - 001_Nimetus: Sisesein; 205_Tüüp: SS-CLT-20/1; 325_Helipidavus: 52 dB; 335_Välispiire: no; 340_Soojusläbivus: 0; 376_Viimistlus_väljast: Telje poolne pind: PUIT- kuusk V; Telje vastaspoolne pind: TOON- vastavalt SA osale; 505_Paksus: 340 mm; 376_Viimistlus_väljast (MUDELIS): _KANDETARIND - CLT ristkihtliimpuit vastavalt EK osale, CLT paigaldusvuugid teibitakse ROTHOBLAAS teibiga; _ÕHKVAHE; _KARKASS - metallkarkass CW 75/50/06 ja UW 75/40/06, samm 600, vahel mineraalvill, helineeldetegur αw = 1.0, ISOVER ACOUSTIC 75mm või samaväärne; _PLAATMATERJAL - OSB3 plaat; _PLAATMATERJAL - tuletõkkekipsplaat, Knauf Red GKF või samaväärne; _PLAATMATERJAL - tuletõkkekipsplaat, Knauf Red GKF või samaväärne; _VIIMISTLUSKIHT - viimistlus vastavalt SA osale
AC_Pset_RenovationAndPhasing - Renovation Status: New
Name | LoadBearing | 330_Tulekindlus | 605_Neto_pindala (m2) | 600_Bruto_pindala (m2) | 500_Kandev
Sisesein | yes | REI 60 | 29.1502 | 41.2358 | TRUE
Sisesein | yes | REI 60 | 17.356 | 17.4395 | TRUE
Sisesein | yes | REI 60 | 78.4509 | 88.9957 | TRUE
Sisesein | yes | REI 60 | 31.2333 | 34.1676 | TRUE
Sisesein | yes | REI 90 | 31.0665 | 32.0535 | TRUE
Sisesein | no | nõudeid ei esitata | 11.0382 | 34.2095 | FALSE
Sisesein | yes | REI 90 | 19.1736 | 35.5313 | TRUE
Sisesein | yes | REI 60 | 16.263 | 17.179 | TRUE
Sisesein | yes | REI 60 | 48.7695 | 55.9365 | TRUE
Sisesein | no | nõudeid ei esitata | 6.08916 | 13.911 | FALSE
Sisesein | no | nõudeid ei esitata | 5.21733 | 14.2879 | FALSE

# IfcWall: SS-CLT-20/2_vill+dold 360, Sisesein
In: 1. korrus
Classification: 1.24 IfcWallType (sein) (RKAS BIM + ARCHICAD Classification)
Pset_WallCommon - Reference: SS-CLT-20/2; LoadBearing: yes; IsExternal: no
AR_Sein - 001_Nimetus: Sisesein; 205_Tüüp: SS-CLT-20/2; 325_Helipidavus: 52 dB; 330_Tulekindlus: REI 60; 335_Välispiire: no; 340_Soojusläbivus: 0; 376_Viimistlus_väljast: Telje poolne pind: PUIT- kuusk V; Telje vastaspoolne pind: PUIT- Woodex 1820; 505_Paksus: 360 mm; 605_Neto_pindala: 31.0305 m2; 600_Bruto_pindala: 33.3715 m2; 500_Kandev: TRUE; 376_Viimistlus_väljast (MUDELIS): _KANDETARIND - CLT ristkihtliimpuit vastavalt EK osale, CLT paigaldusvuugid teibitakse ROTHOBLAAS teibiga; _ÕHKVAHE; _KARKASS - metallkarkass CW 75/50/06 ja UW 75/40/06, samm 600, vahel mineraalvill, helineeldetegur αw = 1.0, ISOVER ACOUSTIC 75mm või samaväärne; _PLAATMATERJAL - OSB3 plaat; _PLAATMATERJAL - tuletõkkekipsplaat, Knauf Red GKF või samaväärne; _PLAATMATERJAL - tuletõkkekipsplaat, Knauf Red GKF või samaväärne; _KARKASS - eriprofiilkinnitus vastavalt sisemisele plaatviimistlusele; _VIIMISTLUSKIHT - Dold plaat vastavalt SA osale
AC_Pset_RenovationAndPhasing - Renovation Status: New

# IfcWall: SS-KP-10/1_1x dold 130 (2)
In: 2. korrus
Classification: 1.24 IfcWallType (sein) (RKAS BIM + ARCHICAD Classification)
Pset_WallCommon - Reference: SS-KP-10/1; LoadBearing: no; IsExternal: no
AR_Sein - 001_Nimetus: SE šaht; 205_Tüüp: SS-KP-10/1; 325_Helipidavus: 42 dB; 330_Tulekindlus: EI60; 335_Välispiire: no; 340_Soojusläbivus: 0; 376_Viimistlus_väljast: Telje poolne pind: TOON- helehall RR21; Telje vastaspoolne pind: PUIT- Woodex 1820; 505_Paksus: 130 mm; 605_Neto_pindala: 3.75001 m2; 500_Kandev: FALSE; 376_Viimistlus_väljast (MUDELIS): _KANDETARIND - kergplokk Fibo 100mm; _KARKASS - eriprofiilkinnitus vastavalt sisemisele plaatviimistlusele; _VIIMISTLUSKIHT - Dold plaat vastavalt SA osale
AC_Pset_RenovationAndPhasing - Renovation Status: New
Name | 600_Bruto_pindala (m2)
SE šaht | 4.07971
SE šaht | 5.59071

# IfcWall: SS-KP-10/2_SE šahti sein +plaat 115 (3)
In: 2. korrus
Classification: 1.24 IfcWallType (sein) (RKAS BIM + ARCHICAD Classification)
Pset_WallCommon - Reference: SS-KP-10/2; LoadBearing: no; IsExternal: no
AR_Sein - 001_Nimetus: SE šaht; 205_Tüüp: SS-KP-10/2; 325_Helipidavus: 40 dB; 330_Tulekindlus: EI60; 335_Välispiire: no; 340_Soojusläbivus: 0; 376_Viimistlus_väljast: Telje poolne pind: TOON- helehall RR21; Telje vastaspoolne pind: TOON- vastavalt SA osale; 505_Paksus: 115 mm; 500_Kandev: FALSE; 376_Viimistlus_väljast (MUDELIS): _KANDETARIND - kergplokk Fibo 100mm; _VIIMISTLUSKIHT - viimistlus vastavalt SA osale
AC_Pset_RenovationAndPhasing - Renovation Status: New
Name | 605_Neto_pindala (m2) | 600_Bruto_pindala (m2)
SE šaht | 4.1965 | 4.4254
SE šaht | 5.45545 | 6.4092
SE šaht | 4.69245 | 6.4092

# IfcWall: SS-KP-10/3_viimistluseta 100 (30)
Classification: 1.24 IfcWallType (sein) (RKAS BIM + ARCHICAD Classification); Material: _KANDETARIND - kergplokk Fibo 100mm
Pset_WallCommon - Reference: SS-KP-10/3; LoadBearing: no; IsExternal: no
AR_Sein - 001_Nimetus: SE šaht; 205_Tüüp: SS-KP-10/3; 330_Tulekindlus: EI60; 335_Välispiire: no; 340_Soojusläbivus: 0; 376_Viimistlus_väljast: Telje poolne pind: TOON- vastavalt SA osale; Telje vastaspoolne pind: TOON- helehall RR21; 505_Paksus: 100 mm; 605_Neto_pindala: 0 m2; 600_Bruto_pindala: 0 m2; 500_Kandev: FALSE; 376_Viimistlus_väljast (MUDELIS): _VIIMISTLUSKIHT - viimistlus vastavalt SA osale; _KANDETARIND - kergplokk Fibo 100mm
AC_Pset_RenovationAndPhasing - Renovation Status: New
Name | In | 325_Helipidavus
2 x SE šaht | 2. korrus | 42 dB
20 x SE šaht | 2. korrus | nõudeid ei esitata
8 x SE šaht | 3. korrus | 42 dB

# IfcWall: SS-KP-10/4_SE šahti sein +krohv 110 (11)
Classification: 1.24 IfcWallType (sein) (RKAS BIM + ARCHICAD Classification)
Pset_WallCommon - Reference: SS-KP-10/4; LoadBearing: no; IsExternal: no
AR_Sein - 001_Nimetus: SE šaht; 205_Tüüp: SS-KP-10/4; 330_Tulekindlus: EI60; 335_Välispiire: no; 340_Soojusläbivus: 0; 376_Viimistlus_väljast: Telje poolne pind: TOON- helehall RR21; Telje vastaspoolne pind: TOON- vastavalt SA osale; 505_Paksus: 110 mm; 500_Kandev: FALSE; 376_Viimistlus_väljast (MUDELIS): _KANDETARIND - kergplokk Fibo 100mm; _VIIMISTLUSKIHT - viimistlus vastavalt SA osale
AC_Pset_RenovationAndPhasing - Renovation Status: New
Name | In | 325_Helipidavus | 605_Neto_pindala (m2) | 600_Bruto_pindala (m2)
SE šaht | 2. korrus | 42 dB | 4.50001 | 5.59071
SE šaht | 2. korrus | 42 dB | 3.00001 | 4.07971
SE šaht | 2. korrus | 40 dB | 3.4335 | 4.4254
SE šaht | 3. korrus | 42 dB | 2.07778 | 2.52669
SE šaht | 3. korrus | 42 dB | 1.6324 | 2.08131
SE šaht | 3. korrus | 42 dB | 2.0405 | 2.08131
SE šaht | 3. korrus | 42 dB | 2.06091 | 2.50982
SE šaht | 4. TEHNO korrus | nõudeid ei esitata | 0.865001 | 0.900701
SE šaht | 4. TEHNO korrus | nõudeid ei esitata | 0.865001 | 1.2467
SE šaht | 4. TEHNO korrus | nõudeid ei esitata | 1.038 | 1.2467
SE šaht | 4. TEHNO korrus | nõudeid ei esitata | 0.692001 | 0.900701

# IfcWall: SS-KP-20/1_2xplaaditud 230, Sisesein
In: 1. korrus
Classification: 1.24 IfcWallType (sein) (RKAS BIM + ARCHICAD Classification)
Pset_WallCommon - Reference: SS-KP-20/1; LoadBearing: yes; IsExternal: no
AR_Sein - 001_Nimetus: Sisesein; 205_Tüüp: SS-KP-20/1; 325_Helipidavus: 49 dB; 330_Tulekindlus: REI 60; 335_Välispiire: no; 340_Soojusläbivus: 0; 376_Viimistlus_väljast: Telje poolne pind: TOON- vastavalt SA osale; Telje vastaspoolne pind: TOON- vastavalt SA osale; 505_Paksus: 230 mm; 605_Neto_pindala: 9.00135 m2; 600_Bruto_pindala: 11.5344 m2; 500_Kandev: TRUE; 376_Viimistlus_väljast (MUDELIS): _VIIMISTLUSKIHT - viimistlus vastavalt SA osale; _HÜDROISLOATSIOON - märgruumidesse; _KANDETARIND - kergplokk Fibo3 200mm; _HÜDROISLOATSIOON - märgruumidesse; _VIIMISTLUSKIHT - viimistlus vastavalt SA osale
AC_Pset_RenovationAndPhasing - Renovation Status: New

# IfcWall: SS-KP-20/2_plokksein 1xplaaditud (1) 215 (2)
In: 2. korrus
Classification: 1.24 IfcWallType (sein) (RKAS BIM + ARCHICAD Classification)
Pset_WallCommon - Reference: SS-KP-20/2; LoadBearing: no; IsExternal: no
AR_Sein - 001_Nimetus: Sisesein; 205_Tüüp: SS-KP-20/2; 325_Helipidavus: 49 dB; 330_Tulekindlus: REI 60; 335_Välispiire: no; 340_Soojusläbivus: 0; 376_Viimistlus_väljast: Telje poolne pind: TOON- vastavalt SA osale; Telje vastaspoolne pind: TOON- helehall RR21; 505_Paksus: 215 mm; 500_Kandev: FALSE; 376_Viimistlus_väljast (MUDELIS): _VIIMISTLUSKIHT - viimistlus vastavalt SA osale; _HÜDROISLOATSIOON - märgruumidesse; _KANDETARIND - kergplokk Fibo3 200mm
AC_Pset_RenovationAndPhasing - Renovation Status: New
Name | 605_Neto_pindala (m2) | 600_Bruto_pindala (m2)
Sisesein | 5.54892 | 6.61453
Sisesein | 9.09308 | 12.378

# IfcWall: SS-KP-20/3_plokksein viimistluseta 200 (3)
Classification: 1.24 IfcWallType (sein) (RKAS BIM + ARCHICAD Classification); Material: _KANDETARIND - kergplokk Fibo3 200mm
Pset_WallCommon - Reference: SS-KP-20/3; LoadBearing: no; IsExternal: no
AR_Sein - 001_Nimetus: Sisesein; 205_Tüüp: SS-KP-20/3; 330_Tulekindlus: REI 60; 335_Välispiire: no; 340_Soojusläbivus: 0; 376_Viimistlus_väljast: Telje poolne pind: TOON- helehall RR21; Telje vastaspoolne pind: TOON- helehall RR21; 505_Paksus: 200 mm; 500_Kandev: FALSE; 376_Viimistlus_väljast (MUDELIS): _KANDETARIND - kergplokk Fibo3 200mm
AC_Pset_RenovationAndPhasing - Renovation Status: New
Name | In | 325_Helipidavus | 605_Neto_pindala (m2) = 600_Bruto_pindala (m2)
Sisesein | 1. korrus | 47 dB | 8.33034
Sisesein | 2. korrus | 42 dB | 6.375
Sisesein | 3. korrus | 47 dB | 5.95

# IfcWall: SS-KP-20/4_1xplaat+1dold 245, Sisesein
In: 2. korrus
Classification: 1.24 IfcWallType (sein) (RKAS BIM + ARCHICAD Classification)
Pset_WallCommon - Reference: SS-KP-20/4; LoadBearing: no; IsExternal: no
AR_Sein - 001_Nimetus: Sisesein; 205_Tüüp: SS-KP-20/4; 325_Helipidavus: 49 dB; 330_Tulekindlus: nõudeid ei esitata; 335_Välispiire: no; 340_Soojusläbivus: 0; 376_Viimistlus_väljast: Telje poolne pind: TOON- vastavalt SA osale; Telje vastaspoolne pind: TOON- vastavalt SA osale; 505_Paksus: 245 mm; 605_Neto_pindala: 5.54944 m2; 600_Bruto_pindala: 7.3758 m2; 500_Kandev: FALSE; 376_Viimistlus_väljast (MUDELIS): _VIIMISTLUSKIHT - viimistlus vastavalt SA osale; _HÜDROISLOATSIOON - märgruumidesse; _KANDETARIND - kergplokk Fibo3 200mm; _KARKASS - eriprofiilkinnitus vastavalt sisemisele plaatviimistlusele; _VIIMISTLUSKIHT - viimistlus vastavalt SA osale
AC_Pset_RenovationAndPhasing - Renovation Status: New

# IfcWall: SS-KP-20/5_plokksein 1xplaaditud+kollektor 360, Sisesein
In: 2. korrus
Classification: 1.24 IfcWallType (sein) (RKAS BIM + ARCHICAD Classification)
Pset_WallCommon - Reference: SS-KP-20/5; LoadBearing: no; IsExternal: no
AR_Sein - 001_Nimetus: Sisesein; 205_Tüüp: SS-KP-20/5; 325_Helipidavus: 49 dB; 330_Tulekindlus: REI 60; 335_Välispiire: no; 340_Soojusläbivus: 0; 376_Viimistlus_väljast: Telje poolne pind: TOON- vastavalt SA osale; Telje vastaspoolne pind: TOON- helehall RR21; 505_Paksus: 360 mm; 605_Neto_pindala: 4.8045 m2; 600_Bruto_pindala: 6.6417 m2; 500_Kandev: FALSE; 376_Viimistlus_väljast (MUDELIS): _VIIMISTLUSKIHT - viimistlus vastavalt SA osale; _HÜDROISLOATSIOON - märgruumidesse; _PLAATMATERJAL - kipsplaat veekindel; _PLAATMATERJAL - kipsplaat veekindel; _KARKASS - eriprofiilkinnitus vastavalt sisemisele plaatviimistlusele; _KANDETARIND - kergplokk Fibo3 200mm
AC_Pset_RenovationAndPhasing - Renovation Status: New

# IfcWall: SS-KP-20/6_plokksein dold+plaat+kollektor 390, Sisesein
In: 2. korrus
Classification: 1.24 IfcWallType (sein) (RKAS BIM + ARCHICAD Classification)
Pset_WallCommon - Reference: SS-KP-20/6; LoadBearing: no; IsExternal: no
AR_Sein - 001_Nimetus: Sisesein; 205_Tüüp: SS-KP-20/6; 325_Helipidavus: 49 dB; 330_Tulekindlus: nõudeid ei esitata; 335_Välispiire: no; 340_Soojusläbivus: 0; 376_Viimistlus_väljast: Telje poolne pind: TOON- vastavalt SA osale; Telje vastaspoolne pind: TOON- vastavalt SA osale; 505_Paksus: 390 mm; 605_Neto_pindala: 4.82325 m2; 600_Bruto_pindala: 7.605 m2; 500_Kandev: FALSE; 376_Viimistlus_väljast (MUDELIS): _VIIMISTLUSKIHT - viimistlus vastavalt SA osale; _HÜDROISLOATSIOON - märgruumidesse; _PLAATMATERJAL - kipsplaat veekindel; _PLAATMATERJAL - kipsplaat veekindel; _KARKASS - eriprofiilkinnitus vastavalt sisemisele plaatviimistlusele; _KANDETARIND - kergplokk Fibo3 200mm; _KARKASS - eriprofiilkinnitus vastavalt sisemisele plaatviimistlusele; _VIIMISTLUSKIHT - viimistlus vastavalt SA osale
AC_Pset_RenovationAndPhasing - Renovation Status: New

# IfcWall: SS-MK-07/1_varisein 2x vineer 100 (2)
In: 3. korrus
Classification: 1.24 IfcWallType (sein) (RKAS BIM + ARCHICAD Classification)
Pset_WallCommon - Reference: SS-MK-07/1; LoadBearing: no; IsExternal: no
AR_Sein - 001_Nimetus: SE šaht; 205_Tüüp: SS-MK-07/1; 325_Helipidavus: nõudeid ei esitata; 330_Tulekindlus: nõudeid ei esitata; 335_Välispiire: no; 340_Soojusläbivus: 0; 376_Viimistlus_väljast: Telje poolne pind: PUIT- mahagon V; Telje vastaspoolne pind: PUIT- mahagon V; 505_Paksus: 100 mm; 500_Kandev: FALSE; 376_Viimistlus_väljast (MUDELIS): _PLAATMATERJAL - niiskuskindel kuusevineer vastavalt EN 314 klass 3, BS 1203/H4, DIN 68705 osa 3 tüüp BFU nõuetele; _KARKASS - metallkarkass CW 100/50/06 ja UW 100/40/06, samm 600; _PLAATMATERJAL - niiskuskindel kuusevineer vastavalt EN 314 klass 3, BS 1203/H4, DIN 68705 osa 3 tüüp BFU nõuetele
AC_Pset_RenovationAndPhasing - Renovation Status: New
Name | 605_Neto_pindala (m2) = 600_Bruto_pindala (m2)
SE šaht | 0.514024
SE šaht | 0.543534

# IfcWall: SS-MK-07/2_varisein 1x vineer 85 (4)
In: 3. korrus
Classification: 1.24 IfcWallType (sein) (RKAS BIM + ARCHICAD Classification)
Pset_WallCommon - Reference: SS-MK-07/2; LoadBearing: no; IsExternal: no
AR_Sein - 001_Nimetus: SE šaht; 205_Tüüp: SS-MK-07/2; 325_Helipidavus: nõudeid ei esitata; 330_Tulekindlus: nõudeid ei esitata; 335_Välispiire: no; 340_Soojusläbivus: 0; 376_Viimistlus_väljast: Telje poolne pind: PUIT- mahagon V; Telje vastaspoolne pind: Roostevaba teras; 505_Paksus: 85 mm; 500_Kandev: FALSE; 376_Viimistlus_väljast (MUDELIS): _PLAATMATERJAL - niiskuskindel kuusevineer vastavalt EN 314 klass 3, BS 1203/H4, DIN 68705 osa 3 tüüp BFU nõuetele; _KARKASS - metallkarkass CW 100/50/06 ja UW 100/40/06, samm 600
AC_Pset_RenovationAndPhasing - Renovation Status: New
Name | 605_Neto_pindala (m2) | 600_Bruto_pindala (m2)
SE šaht | 3.12 | 4.18964
SE šaht | 2.56739 | 4.04187
SE šaht | 3.01184 | 4.02584
SE šaht | 2.55829 | 4.04187

# IfcWall: SS-MK-1/1_1x dold pinnakiht 30 (58)
Classification: 1.24 IfcWallType (sein) (RKAS BIM + ARCHICAD Classification)
Pset_WallCommon - Reference: SS-MK-1/1; LoadBearing: no; IsExternal: no
AR_Sein - 001_Nimetus: Sisesein; 205_Tüüp: SS-MK-1/1; 335_Välispiire: no; 340_Soojusläbivus: 0; 505_Paksus: 30 mm; 500_Kandev: FALSE; 376_Viimistlus_väljast (MUDELIS): _KARKASS - eriprofiilkinnitus vastavalt sisemisele plaatviimistlusele; _VIIMISTLUSKIHT - Dold plaat vastavalt SA osale
AC_Pset_RenovationAndPhasing - Renovation Status: New
Name | In | 325_Helipidavus | 330_Tulekindlus | 376_Viimistlus_väljast | 605_Neto_pindala (m2) | 600_Bruto_pindala (m2)
Sisesein | 1. korrus | 42 dB | nõudeid ei esitata | Telje poolne pind: METALL- teras; Telje vastaspoolne pind: PUIT- Woodex 1820 | 2.2725 | 2.45445
Sisesein | 1. korrus | 42 dB | EI60 | Telje poolne pind: METALL- teras; Telje vastaspoolne pind: PUIT- Woodex 1820 | 0.04131 | 0.184084
Sisesein | 1. korrus | 42 dB | nõudeid ei esitata | Telje poolne pind: METALL- teras; Telje vastaspoolne pind: PUIT- Woodex 1820 | 0.14718 | 0.49089
Sisesein | 1. korrus | 42 dB | nõudeid ei esitata | Telje poolne pind: METALL- teras; Telje vastaspoolne pind: PUIT- Woodex 1820 | 0.3206 | 0.47201
Sisesein | 1. korrus | 42 dB | nõudeid ei esitata | Telje poolne pind: PUIT- hele tamm V; Telje vastaspoolne pind: PUIT- hele tamm V | 4.83694 | 4.83694
Sisesein | 1. korrus | 42 dB | nõudeid ei esitata | Telje poolne pind: PUIT- hele tamm V; Telje vastaspoolne pind: PUIT- hele tamm V | 0.84476 | 0.84476
Sisesein | 1. korrus | 42 dB | nõudeid ei esitata | Telje poolne pind: PUIT- hele tamm V; Telje vastaspoolne pind: PUIT- hele tamm V | 0.2085 | 0.3879
2 x Sisesein | 1. korrus | 42 dB | nõudeid ei esitata | Telje poolne pind: PUIT- hele tamm V; Telje vastaspoolne pind: PUIT- hele tamm V | 0.3336 | 0.5603
Sisesein | 1. korrus | 42 dB | nõudeid ei esitata | Telje poolne pind: PUIT- hele tamm V; Telje vastaspoolne pind: PUIT- hele tamm V | 0.2502 | 0.3879
Sisesein | 1. korrus | 42 dB | nõudeid ei esitata | Telje poolne pind: PUIT- hele tamm V; Telje vastaspoolne pind: PUIT- hele tamm V | 1.2093 | 1.293
Sisesein | 1. korrus | 42 dB | nõudeid ei esitata | Telje poolne pind: PUIT- hele tamm V; Telje vastaspoolne pind: PUIT- hele tamm V | 0.24715 | 0.3879
Sisesein | 1. korrus | 42 dB | nõudeid ei esitata | Telje poolne pind: PUIT- hele tamm V; Telje vastaspoolne pind: PUIT- hele tamm V | 0.31275 | 0.53875
Sisesein | 1. korrus | 42 dB | nõudeid ei esitata | Telje poolne pind: PUIT- hele tamm V; Telje vastaspoolne pind: PUIT- hele tamm V | 0.28885 | 0.3879
Sisesein | 1. korrus | 42 dB | nõudeid ei esitata | Telje poolne pind: PUIT- hele tamm V; Telje vastaspoolne pind: PUIT- hele tamm V | 0.235971 | 0.366371
Sisesein | 1. korrus | 42 dB | nõudeid ei esitata | Telje poolne pind: PUIT- hele tamm V; Telje vastaspoolne pind: PUIT- hele tamm V | 1.02176 | 1.293
Sisesein | 1. korrus | 42 dB | nõudeid ei esitata | Telje poolne pind: PUIT- hele tamm V; Telje vastaspoolne pind: PUIT- hele tamm V | 0.258621 | 0.387921
2 x Sisesein | 1. korrus | 42 dB | nõudeid ei esitata | Telje poolne pind: PUIT- hele tamm V; Telje vastaspoolne pind: PUIT- hele tamm V | 0.3448 | 0.5603
Sisesein | 1. korrus | 42 dB | nõudeid ei esitata | Telje poolne pind: PUIT- hele tamm V; Telje vastaspoolne pind: PUIT- hele tamm V | 0.2586 | 0.3879
Sisesein | 1. korrus | 42 dB | nõudeid ei esitata | Telje poolne pind: PUIT- hele tamm V; Telje vastaspoolne pind: PUIT- hele tamm V | 0.92564 | 0.97406
Sisesein | 1. korrus | 42 dB | nõudeid ei esitata | Telje poolne pind: PUIT- hele tamm V; Telje vastaspoolne pind: PUIT- hele tamm V | 0.36465 | 0.36635
Sisesein | 1. korrus | 42 dB | nõudeid ei esitata | Telje poolne pind: PUIT- hele tamm V; Telje vastaspoolne pind: PUIT- hele tamm V | 0.288988 | 0.429545
Sisesein | 1. korrus | 42 dB | nõudeid ei esitata | Telje poolne pind: PUIT- hele tamm V; Telje vastaspoolne pind: PUIT- hele tamm V | 0.43785 | 0.53875
Sisesein | 1. korrus | 42 dB | nõudeid ei esitata | Telje poolne pind: PUIT- hele tamm V; Telje vastaspoolne pind: PUIT- hele tamm V | 0.3328 | 0.3879
Sisesein | 1. korrus | 42 dB | nõudeid ei esitata | Telje poolne pind: METALL- teras; Telje vastaspoolne pind: PUIT- Woodex 1820 | 1.7577 | 1.7724
Sisesein | 1. korrus | nõudeid ei esitata | nõudeid ei esitata | Telje poolne pind: METALL- teras; Telje vastaspoolne pind: PUIT- Woodex 1820 | 1.65266 | 1.87578
Sisesein | 1. korrus | nõudeid ei esitata | nõudeid ei esitata | Telje poolne pind: METALL- teras; Telje vastaspoolne pind: PUIT- Woodex 1820 | 1.31696 | 1.49672
Sisesein | 2. korrus | 42 dB | nõudeid ei esitata | Telje poolne pind: METALL- teras; Telje vastaspoolne pind: PUIT- Woodex 1820 | 0.506852 | 0.506852
Sisesein | 2. korrus | 42 dB | nõudeid ei esitata | Telje poolne pind: PUIT- hele tamm V; Telje vastaspoolne pind: PUIT- hele tamm V | 0.569689 | 0.575473
Sisesein | 2. korrus | 42 dB | nõudeid ei esitata | Telje poolne pind: PUIT- hele tamm V; Telje vastaspoolne pind: PUIT- hele tamm V | 0.1655 | 0.2076
Sisesein | 2. korrus | 42 dB | nõudeid ei esitata | Telje poolne pind: PUIT- hele tamm V; Telje vastaspoolne pind: PUIT- hele tamm V | 0.166 | 0.2422
Sisesein | 2. korrus | 42 dB | nõudeid ei esitata | Telje poolne pind: PUIT- hele tamm V; Telje vastaspoolne pind: PUIT- hele tamm V | 0.20354 | 0.3114
Sisesein | 2. korrus | 42 dB | nõudeid ei esitata | Telje poolne pind: PUIT- hele tamm V; Telje vastaspoolne pind: PUIT- hele tamm V | 0.851143 | 0.920343
Sisesein | 2. korrus | 42 dB | nõudeid ei esitata | Telje poolne pind: PUIT- hele tamm V; Telje vastaspoolne pind: PUIT- hele tamm V | 0.854145 | 0.957945
Sisesein | 2. korrus | 42 dB | nõudeid ei esitata | Telje poolne pind: PUIT- hele tamm V; Telje vastaspoolne pind: PUIT- hele tamm V | 0.2712 | 0.346
Sisesein | 2. korrus | 42 dB | nõudeid ei esitata | Telje poolne pind: PUIT- hele tamm V; Telje vastaspoolne pind: PUIT- hele tamm V | 0.249 | 0.4325
Sisesein | 2. korrus | 42 dB | nõudeid ei esitata | Telje poolne pind: PUIT- hele tamm V; Telje vastaspoolne pind: PUIT- hele tamm V | 0.2034 | 0.3114
Sisesein | 2. korrus | 42 dB | nõudeid ei esitata | Telje poolne pind: PUIT- hele tamm V; Telje vastaspoolne pind: PUIT- hele tamm V | 0.826213 | 0.860813
Sisesein | 2. korrus | 42 dB | nõudeid ei esitata | Telje poolne pind: PUIT- hele tamm V; Telje vastaspoolne pind: PUIT- hele tamm V | 0.202 | 0.3114
2 x Sisesein | 2. korrus | 42 dB | nõudeid ei esitata | Telje poolne pind: PUIT- hele tamm V; Telje vastaspoolne pind: PUIT- hele tamm V | 0.2656 | 0.4498
Sisesein | 2. korrus | 42 dB | nõudeid ei esitata | Telje poolne pind: PUIT- hele tamm V; Telje vastaspoolne pind: PUIT- hele tamm V | 0.09974 | 0.2076
Sisesein | 3. korrus | 42 dB | nõudeid ei esitata | Telje poolne pind: METALL- teras; Telje vastaspoolne pind: PUIT- Woodex 1820 | 0.506852 | 0.506852
Sisesein | 3. korrus | 42 dB | nõudeid ei esitata | Telje poolne pind: PUIT- hele tamm V; Telje vastaspoolne pind: PUIT- hele tamm V | 0.570918 | 0.617334
2 x Sisesein | 3. korrus | 42 dB | nõudeid ei esitata | Telje poolne pind: PUIT- hele tamm V; Telje vastaspoolne pind: PUIT- hele tamm V | 0.2768 | 0.4498
Sisesein | 3. korrus | 42 dB | nõudeid ei esitata | Telje poolne pind: PUIT- hele tamm V; Telje vastaspoolne pind: PUIT- hele tamm V | 0.1014 | 0.2076
Sisesein | 3. korrus | 42 dB | nõudeid ei esitata | Telje poolne pind: PUIT- hele tamm V; Telje vastaspoolne pind: PUIT- hele tamm V | 0.2768 | 0.346
Sisesein | 3. korrus | 42 dB | nõudeid ei esitata | Telje poolne pind: PUIT- hele tamm V; Telje vastaspoolne pind: PUIT- hele tamm V | 0.478824 | 0.548449
Sisesein | 3. korrus | 42 dB | nõudeid ei esitata | Telje poolne pind: PUIT- hele tamm V; Telje vastaspoolne pind: PUIT- hele tamm V | 0.2595 | 0.4325
Sisesein | 3. korrus | 42 dB | nõudeid ei esitata | Telje poolne pind: PUIT- hele tamm V; Telje vastaspoolne pind: PUIT- hele tamm V | 0.1701 | 0.2422
2 x Sisesein | 3. korrus | 42 dB | nõudeid ei esitata | Telje poolne pind: PUIT- hele tamm V; Telje vastaspoolne pind: PUIT- hele tamm V | 0.2076 | 0.3114
Sisesein | 3. korrus | 42 dB | nõudeid ei esitata | Telje poolne pind: PUIT- hele tamm V; Telje vastaspoolne pind: PUIT- hele tamm V | 1.0034 | 1.038
Sisesein | 3. korrus | 42 dB | nõudeid ei esitata | Telje poolne pind: PUIT- hele tamm V; Telje vastaspoolne pind: PUIT- hele tamm V | 0.569789 | 0.575473
Sisesein | 3. korrus | 42 dB | nõudeid ei esitata | Telje poolne pind: PUIT- hele tamm V; Telje vastaspoolne pind: PUIT- hele tamm V | 0.1685 | 0.2076
Sisesein | 3. korrus | 42 dB | nõudeid ei esitata | Telje poolne pind: PUIT- hele tamm V; Telje vastaspoolne pind: PUIT- hele tamm V | 0.2028 | 0.3114

# IfcWall: SS-MK-10/10_varisein vineer+kips 130, Sisesein
In: 4. TEHNO korrus
Classification: 1.24 IfcWallType (sein) (RKAS BIM + ARCHICAD Classification)
Pset_WallCommon - Reference: SS-MK-10/10; LoadBearing: no; IsExternal: no
AR_Sein - 001_Nimetus: Sisesein; 205_Tüüp: SS-MK-10/10; 325_Helipidavus: 35 dB; 330_Tulekindlus: nõudeid ei esitata; 335_Välispiire: no; 340_Soojusläbivus: 0; 376_Viimistlus_väljast: Telje poolne pind: KROHV- peenkrohv, valge; Telje vastaspoolne pind: Roostevaba teras; 505_Paksus: 130 mm; 605_Neto_pindala: 39.6139 m2; 600_Bruto_pindala: 40.4203 m2; 500_Kandev: FALSE; 376_Viimistlus_väljast (MUDELIS): _PLAATMATERJAL - tuletõkkekipsplaat, Knauf Red GKF või samaväärne; _PLAATMATERJAL - niiskuskindel kuusevineer vastavalt EN 314 klass 3, BS 1203/H4, DIN 68705 osa 3 tüüp BFU nõuetele; _KARKASS - metallkarkass CW 100/50/06 ja UW 100/40/06, samm 600
AC_Pset_RenovationAndPhasing - Renovation Status: New

# IfcWall: SS-MK-10/11_kollektorvarisein plaaditud 40 (12)
Classification: 1.24 IfcWallType (sein) (RKAS BIM + ARCHICAD Classification)
Pset_WallCommon - Reference: SS-MK-10/11; LoadBearing: no; IsExternal: no
AR_Sein - 001_Nimetus: Sisesein; 205_Tüüp: SS-MK-10/11; 330_Tulekindlus: nõudeid ei esitata; 335_Välispiire: no; 376_Viimistlus_väljast: Telje poolne pind: TOON- vastavalt SA osale; Telje vastaspoolne pind: KROHV- peenkrohv, valge; 505_Paksus: 40 mm; 500_Kandev: FALSE; 376_Viimistlus_väljast (MUDELIS): _VIIMISTLUSKIHT - viimistlus vastavalt SA osale; _PLAATMATERJAL - kipsplaat veekindel; _PLAATMATERJAL - kipsplaat veekindel
AC_Pset_RenovationAndPhasing - Renovation Status: New
Name | In | 325_Helipidavus | 340_Soojusläbivus | 605_Neto_pindala (m2) | 600_Bruto_pindala (m2)
2 x Sisesein | 1. korrus | 35dB | 0 | 0.86 | 1.35
Sisesein | 1. korrus | 40 dB | 0 | 0.35445 | 0.356318
Sisesein | 1. korrus | 40 dB | 0 | 2.2935 | 2.36847
4 x Sisesein | 2. korrus | 35dB | 0 | 0.86 | 1.35
4 x Sisesein | 3. korrus | 35dB | 0.12 | 0.86 | 1.35

# IfcWall: SS-MK-10/12_šahti sein viimistluseta 125 (4)
In: 2. korrus
Classification: 1.24 IfcWallType (sein) (RKAS BIM + ARCHICAD Classification)
Pset_WallCommon - Reference: SS-MK-10/12; LoadBearing: no; IsExternal: no
AR_Sein - 001_Nimetus: Sisesein; 205_Tüüp: SS-MK-10/12; 325_Helipidavus: nõudeid ei esitata; 330_Tulekindlus: nõudeid ei esitata; 335_Välispiire: no; 340_Soojusläbivus: 0; 376_Viimistlus_väljast: Telje poolne pind: KROHV- peenkrohv, valge; Telje vastaspoolne pind: SOOJUSTUS- vill; 505_Paksus: 125 mm; 500_Kandev: FALSE; 376_Viimistlus_väljast (MUDELIS): _PLAATMATERJAL - kipsplaat veekindel; _PLAATMATERJAL - kipsplaat veekindel; _KARKASS - metallkarkass CW 100/50/06 ja UW 100/40/06, samm 600, vahel mineraalvill, helineeldetegur αw = 1.0, ISOVER ACOUSTIC 100mm või samaväärne
AC_Pset_RenovationAndPhasing - Renovation Status: New
Name | 605_Neto_pindala (m2) | 600_Bruto_pindala (m2)
2 x Sisesein | 0.1575 | 0.1575
2 x Sisesein | 0.839198 | 1.26445

# IfcWall: SS-MK-10/1_šahti sein TTS+värv 127 (2)
In: 4. TEHNO korrus
Classification: 1.24 IfcWallType (sein) (RKAS BIM + ARCHICAD Classification)
Pset_WallCommon - Reference: SS-MK-10/1; LoadBearing: no; IsExternal: no
AR_Sein - 001_Nimetus: Sisesein; 205_Tüüp: SS-MK-10/1; 325_Helipidavus: 35 dB; 330_Tulekindlus: EI60; 335_Välispiire: no; 340_Soojusläbivus: 0; 376_Viimistlus_väljast: Telje poolne pind: TOON- vastavalt SA osale; Telje vastaspoolne pind: KROHV- peenkrohv, valge; 505_Paksus: 127 mm; 500_Kandev: FALSE; 376_Viimistlus_väljast (MUDELIS): _VIIMISTLUSKIHT - viimistlus vastavalt SA osale; _PLAATMATERJAL - tuletõkkekipsplaat, Knauf Red GKF või samaväärne; _PLAATMATERJAL - tuletõkkekipsplaat, Knauf Red GKF või samaväärne; _KARKASS - metallkarkass CW 50, samm 600, mineraalvill karkassi vahel; _PLAATMATERJAL - tuletõkkekipsplaat, Knauf Red GKF või samaväärne
AC_Pset_RenovationAndPhasing - Renovation Status: New
Name | 605_Neto_pindala (m2) | 600_Bruto_pindala (m2)
Sisesein | 10.6265 | 11.4628
Sisesein | 11.5115 | 14.749

# IfcWall: SS-MK-10/2_šahti sein+plaat 140 (46)
Classification: 1.24 IfcWallType (sein) (RKAS BIM + ARCHICAD Classification)
Pset_WallCommon - Reference: SS-MK-10/2; IsExternal: no
AR_Sein - 205_Tüüp: SS-MK-10/2; 325_Helipidavus: 40 dB; 335_Välispiire: no; 340_Soojusläbivus: 0; 376_Viimistlus_väljast: Telje poolne pind: TOON- vastavalt SA osale; Telje vastaspoolne pind: SOOJUSTUS- vill; 505_Paksus: 140 mm; 376_Viimistlus_väljast (MUDELIS): _VIIMISTLUSKIHT - viimistlus vastavalt SA osale; _HÜDROISLOATSIOON - märgruumidesse; _PLAATMATERJAL - kipsplaat veekindel; _PLAATMATERJAL - kipsplaat veekindel; _KARKASS - metallkarkass CW 100/50/06 ja UW 100/40/06, samm 600, vahel mineraalvill, helineeldetegur αw = 1.0, ISOVER ACOUSTIC 100mm või samaväärne
AC_Pset_RenovationAndPhasing - Renovation Status: New
Name | In | LoadBearing | 001_Nimetus | 330_Tulekindlus | 605_Neto_pindala (m2) | 600_Bruto_pindala (m2) | 500_Kandev
Varisein | 1. korrus | no | Varisein | nõudeid ei esitata | 5.0062 | 6.8762 | FALSE
Sisesein | 1. korrus | no | Sisesein | nõudeid ei esitata | 2.06876 | 3.26974 | FALSE
Varisein | 1. korrus | no | Varisein | nõudeid ei esitata | 12.5521 | 14.4976 | FALSE
Sisesein | 1. korrus | no | Sisesein | nõudeid ei esitata | 4.06575 | 5.32313 | FALSE
Sisesein | 1. korrus | no | Sisesein | nõudeid ei esitata | 1.2093 | 2.783 | FALSE
Sisesein | 1. korrus | no | Sisesein | nõudeid ei esitata | 2.6219 | 4.557 | FALSE
Varisein | 1. korrus | no | Varisein | nõudeid ei esitata | 1.8348 | 1.9096 | FALSE
Varisein | 1. korrus | no | Varisein | nõudeid ei esitata | 1.93947 | 2.08363 | FALSE
2 x Sisesein | 1. korrus | no | Sisesein | nõudeid ei esitata | 3.74312 | 4.1143 | FALSE
Sisesein | 1. korrus | no | Sisesein | nõudeid ei esitata | 4.81658 | 5.9018 | FALSE
Sisesein | 1. korrus | no | Sisesein | nõudeid ei esitata | 4.59478 | 5.658 | FALSE
Sisesein | 1. korrus | no | Sisesein | nõudeid ei esitata | 0.4945 | 1.80255 | FALSE
Sisesein | 1. korrus | no | Sisesein | nõudeid ei esitata | 2.05975 | 2.36847 | FALSE
Sisesein | 1. korrus | no | Sisesein | nõudeid ei esitata | 6.8068 | 6.88679 | FALSE
Sisesein | 1. korrus | no | Sisesein | nõudeid ei esitata | 4.862 | 5.37321 | FALSE
Sisesein | 1. korrus | no | Sisesein | nõudeid ei esitata | 2.1223 | 3.01822 | FALSE
Sisesein | 1. korrus | no | Sisesein | nõudeid ei esitata | 2.85645 | 2.93438 | FALSE
Sisesein | 1. korrus | no | Sisesein | nõudeid ei esitata | 3.366 | 3.85963 | FALSE
Sisesein | 1. korrus | no | Sisesein | nõudeid ei esitata | 0.834 | 1.67679 | FALSE
Sisesein | 1. korrus | no | Sisesein | nõudeid ei esitata | 2.05975 | 3.01822 | FALSE
Sisesein | 1. korrus | no | Sisesein | nõudeid ei esitata | 0.834 | 0.838395 | FALSE
Sisesein | 1. korrus | no | Sisesein | nõudeid ei esitata | 1.93905 | 2.93438 | FALSE
Sisesein | 1. korrus | no | Sisesein | nõudeid ei esitata | 2.1684 | 2.7667 | FALSE
Sisesein | 1. korrus | no | Sisesein | nõudeid ei esitata | 0.4587 | 0.461117 | FALSE
Sisesein | 2. korrus | no | Sisesein | nõudeid ei esitata | 1.1148 | 2.9815 | FALSE
Varisein | 2. korrus | no | Varisein | nõudeid ei esitata | 1.50491 | 3.11915 | FALSE
Varisein | 2. korrus | no | Varisein | nõudeid ei esitata | 1.3167 | 1.368 | FALSE
Varisein | 2. korrus | no | Varisein | nõudeid ei esitata | 1.20702 | 2.0202 | FALSE
Varisein | 2. korrus | no | Varisein | nõudeid ei esitata | 1.68656 | 1.77995 | FALSE
Sisesein | 2. korrus | no | Sisesein | REI 60 | 3.1208 | 4.0964 | FALSE
Sisesein | 2. korrus | no | Sisesein | REI 60 | 0.91298 | 2.18248 | FALSE
Varisein | 2. korrus | no | Varisein | nõudeid ei esitata | 1.182 | 2.6904 | FALSE
Varisein | 2. korrus | no | Varisein | nõudeid ei esitata | 0.3818 | 1.16475 | FALSE
Varisein | 2. korrus | no | Varisein | nõudeid ei esitata | 0.4847 | 0.8525 | FALSE
Varisein | 2. korrus | no | Varisein | nõudeid ei esitata | 0.6419 | 0.6812 | FALSE
Sisesein | 3. korrus | yes | Sisesein | nõudeid ei esitata | 1.1682 | 3.0082 | TRUE
Varisein | 3. korrus | no | Varisein | nõudeid ei esitata | 1.4872 | 3.21936 | FALSE
Varisein | 3. korrus | no | Varisein | nõudeid ei esitata | 1.4534 | 2.34305 | FALSE
Sisesein | 3. korrus | no | Sisesein | REI 60 | 5.29416 | 7.34136 | FALSE
Varisein | 3. korrus | no | Varisein | nõudeid ei esitata | 1.42561 | 2.5826 | FALSE
Varisein | 3. korrus | no | Varisein | nõudeid ei esitata | 1.37701 | 1.5356 | FALSE
Sisesein | 3. korrus | no | Sisesein | nõudeid ei esitata | 1.443 | 3.283 | FALSE
Sisesein | 3. korrus | no | Sisesein | nõudeid ei esitata | 1.8425 | 1.89275 | FALSE
Varisein | 3. korrus | no | Varisein | nõudeid ei esitata | 1.26701 | 2.09544 | FALSE
Varisein | 3. korrus | no | Varisein | nõudeid ei esitata | 1.4703 | 2.6475 | FALSE

# IfcWall: SS-MK-10/3_TTS sein viimistluseta 160 (2)
In: 1. korrus
Classification: 1.24 IfcWallType (sein) (RKAS BIM + ARCHICAD Classification)
Pset_WallCommon - Reference: SS-MK-10/3; IsExternal: no
AR_Sein - 001_Nimetus: Sisesein; 205_Tüüp: SS-MK-10/3; 335_Välispiire: no; 340_Soojusläbivus: 0; 376_Viimistlus_väljast: Telje poolne pind: KROHV- peenkrohv, valge; Telje vastaspoolne pind: TOON- vastavalt SA osale; 505_Paksus: 160 mm; 376_Viimistlus_väljast (MUDELIS): _PLAATMATERJAL - tuletõkkekipsplaat, Knauf Red GKF või samaväärne; _PLAATMATERJAL - tuletõkkekipsplaat, Knauf Red GKF või samaväärne; _KARKASS - metallkarkass CW 100/50/06 ja UW 100/40/06, samm 600, vahel mineraalvill, helineeldetegur αw = 1.0, ISOVER ACOUSTIC 100mm või samaväärne; _PLAATMATERJAL - tuletõkkekipsplaat, Knauf Red GKF või samaväärne; _PLAATMATERJAL - tuletõkkekipsplaat, Knauf Red GKF või samaväärne; _VIIMISTLUSKIHT - viimistlus vastavalt SA osale
AC_Pset_RenovationAndPhasing - Renovation Status: New
Name | LoadBearing | 325_Helipidavus | 330_Tulekindlus | 605_Neto_pindala (m2) | 600_Bruto_pindala (m2) | 500_Kandev
Sisesein | yes | 40 dB | REI 90 | 16.6534 | 19.1592 | TRUE
Sisesein | no | 53 dB | REI 60 | 7.43418 | 7.43418 | FALSE

# IfcWall: SS-MK-10/4_šahti sein+dold 160 (13)
Classification: 1.24 IfcWallType (sein) (RKAS BIM + ARCHICAD Classification)
Pset_WallCommon - Reference: SS-MK-10/4; IsExternal: no
AR_Sein - 205_Tüüp: SS-MK-10/4; 335_Välispiire: no; 340_Soojusläbivus: 0; 376_Viimistlus_väljast: Telje poolne pind: PUIT- Woodex 1820; Telje vastaspoolne pind: SOOJUSTUS- vill; 505_Paksus: 160 mm; 376_Viimistlus_väljast (MUDELIS): _VIIMISTLUSKIHT - Dold plaat vastavalt SA osale; _KARKASS - eriprofiilkinnitus vastavalt sisemisele plaatviimistlusele; _PLAATMATERJAL - tuletõkkekipsplaat, Knauf Red GKF või samaväärne; _PLAATMATERJAL - tuletõkkekipsplaat, Knauf Red GKF või samaväärne; _KARKASS - metallkarkass CW 100/50/06 ja UW 100/40/06, samm 600, vahel mineraalvill, helineeldetegur αw = 1.0, ISOVER ACOUSTIC 100mm või samaväärne
AC_Pset_RenovationAndPhasing - Renovation Status: New
Name | In | LoadBearing | 001_Nimetus | 325_Helipidavus | 330_Tulekindlus | 605_Neto_pindala (m2) | 600_Bruto_pindala (m2) | 500_Kandev
Sisesein | 1. korrus | no | Sisesein | 52 dB | nõudeid ei esitata | 1.06426 | 1.73466 | FALSE
Sisesein | 1. korrus | no | Sisesein | 52 dB | nõudeid ei esitata | 1.02514 | 1.72318 | FALSE
Sisesein | 1. korrus | no | Sisesein | 52 dB | nõudeid ei esitata | 3.26433 | 3.63119 | FALSE
Varisein | 1. korrus | no | Varisein | 35 dB | nõudeid ei esitata | 15.2782 | 17.8475 | FALSE
Sisesein | 1. korrus | no | Sisesein | 35 dB | EI60 | 1.16726 | 1.16726 | FALSE
Sisesein | 1. korrus | no | Sisesein | 35 dB | EI60 | 1.4268 | 1.4268 | FALSE
Sisesein | 1. korrus | no | Sisesein | 52 dB | nõudeid ei esitata | 1.04617 | 1.25875 | FALSE
Sisesein | 1. korrus | no | Sisesein | 52 dB | nõudeid ei esitata | 1.0812 | 1.78075 | FALSE
Sisesein | 2. korrus | no | Sisesein | 40 dB | nõudeid ei esitata | 3.5717 | 7.20799 | FALSE
Sisesein | 2. korrus | no | Sisesein | 35 dB | EI60 | 0.878626 | 0.878626 | FALSE
Sisesein | 2. korrus | no | Sisesein | 35 dB | EI60 | 0.884573 | 0.884573 | FALSE
Varisein | 2. korrus | no | Varisein | 40 dB | nõudeid ei esitata | 0.334925 | 0.407324 | FALSE
Varisein | 3. korrus | yes | Varisein | 35 dB | nõudeid ei esitata | 0.508423 | 0.669181 | TRUE

# IfcWall: SS-MK-10/6_šahti sein+krohv 40 dB 135 (23)
Classification: 1.24 IfcWallType (sein) (RKAS BIM + ARCHICAD Classification)
Pset_WallCommon - Reference: SS-MK-10/6; LoadBearing: no; IsExternal: no
AR_Sein - 205_Tüüp: SS-MK-10/6; 335_Välispiire: no; 340_Soojusläbivus: 0; 376_Viimistlus_väljast: Telje poolne pind: TOON- vastavalt SA osale; Telje vastaspoolne pind: SOOJUSTUS- vill; 505_Paksus: 135 mm; 500_Kandev: FALSE; 376_Viimistlus_väljast (MUDELIS): _VIIMISTLUSKIHT - viimistlus vastavalt SA osale; _PLAATMATERJAL - kipsplaat veekindel; _PLAATMATERJAL - kipsplaat veekindel; _KARKASS - metallkarkass CW 100/50/06 ja UW 100/40/06, samm 600, vahel mineraalvill, helineeldetegur αw = 1.0, ISOVER ACOUSTIC 100mm või samaväärne
AC_Pset_RenovationAndPhasing - Renovation Status: New
Name | In | 001_Nimetus | 325_Helipidavus | 330_Tulekindlus | 605_Neto_pindala (m2) | 600_Bruto_pindala (m2)
Sisesein | 1. korrus | Sisesein | nõudeid ei esitata | nõudeid ei esitata | 1.8867 | 1.94822
Sisesein | 1. korrus | Sisesein | nõudeid ei esitata | nõudeid ei esitata | 5.63985 | 8.33625
Varisein | 1. korrus | Varisein | 40 dB | nõudeid ei esitata | 4.03353 | 6.13822
Varisein | 1. korrus | Varisein | 40 dB | nõudeid ei esitata | 0.983475 | 1.80675
Varisein | 1. korrus | Varisein | 40 dB | nõudeid ei esitata | 1.6455 | 2.24451
Varisein | 1. korrus | Varisein | 40 dB | nõudeid ei esitata | 2.8688 | 3.2926
Varisein | 1. korrus | Varisein | 40 dB | nõudeid ei esitata | 1.6292 | 2.24451
Sisesein | 1. korrus | Sisesein | nõudeid ei esitata | nõudeid ei esitata | 0.857506 | 1.02077
Varisein | 2. korrus | Varisein | 40 dB | nõudeid ei esitata | 6.03379 | 8.37969
Varisein | 2. korrus | Varisein | 40 dB | nõudeid ei esitata | 2.19425 | 3.23275
Sisesein | 2. korrus | Sisesein | nõudeid ei esitata | nõudeid ei esitata | 3.54445 | 3.60395
Sisesein | 2. korrus | Sisesein | nõudeid ei esitata | nõudeid ei esitata | 3.11675 | 4.37025
Varisein | 2. korrus | Varisein | 40 dB | nõudeid ei esitata | 1.4276 | 3.14798
Varisein | 2. korrus | Varisein | 40 dB | nõudeid ei esitata | 4.3326 | 4.55445
Varisein | 2. korrus | Varisein | 40 dB | nõudeid ei esitata | 1.9715 | 3.23275
Sisesein | 2. korrus | Sisesein | nõudeid ei esitata | nõudeid ei esitata | 3.67705 | 4.29042
Sisesein | 2. korrus | Sisesein | nõudeid ei esitata | nõudeid ei esitata | 3.08525 | 4.29375
Sisesein | 2. korrus | Sisesein | nõudeid ei esitata | EI60 | 3.7875 | 4.25625
Sisesein | 2. korrus | Sisesein | nõudeid ei esitata | EI60 | 0.5625 | 1.87072
Sisesein | 3. korrus | Sisesein | 40 dB | REI 60 | 8.1976 | 11.9652
Sisesein | 3. korrus | Sisesein | nõudeid ei esitata | REI 60 | 3.83295 | 4.30732
Sisesein | 3. korrus | Sisesein | nõudeid ei esitata | REI 60 | 0.77425 | 1.84057
Sisesein | 3. korrus | Sisesein | nõudeid ei esitata | EI60 | 0.3568 | 0.9108

# IfcWall: SS-MK-10/7_ plaat+krohv 175 (4)
Classification: 1.24 IfcWallType (sein) (RKAS BIM + ARCHICAD Classification)
Pset_WallCommon - Reference: SS-MK-10/7; IsExternal: no
AR_Sein - 001_Nimetus: Sisesein; 205_Tüüp: SS-MK-10/7; 330_Tulekindlus: nõudeid ei esitata; 335_Välispiire: no; 340_Soojusläbivus: 0; 376_Viimistlus_väljast: Telje poolne pind: TOON- vastavalt SA osale; Telje vastaspoolne pind: TOON- vastavalt SA osale; 505_Paksus: 175 mm; 376_Viimistlus_väljast (MUDELIS): _VIIMISTLUSKIHT - viimistlus vastavalt SA osale; _PLAATMATERJAL - tuletõkkekipsplaat, Knauf Red GKF või samaväärne; _PLAATMATERJAL - tuletõkkekipsplaat, Knauf Red GKF või samaväärne; _KARKASS - metallkarkass CW 100/50/06 ja UW 100/40/06, samm 600, vahel mineraalvill, helineeldetegur αw = 1.0, ISOVER ACOUSTIC 100mm või samaväärne; _PLAATMATERJAL - tuletõkkekipsplaat, Knauf Red GKF või samaväärne; _PLAATMATERJAL - tuletõkkekipsplaat, Knauf Red GKF või samaväärne; _HÜDROISLOATSIOON - märgruumidesse; _VIIMISTLUSKIHT - viimistlus vastavalt SA osale
AC_Pset_RenovationAndPhasing - Renovation Status: New
Name | In | LoadBearing | 325_Helipidavus | 605_Neto_pindala (m2) | 600_Bruto_pindala (m2) | 500_Kandev
Sisesein | 2. korrus | no | 53 dB | 14.7462 | 23.3369 | FALSE
Sisesein | 2. korrus | no | 55 dB | 2.90816 | 3.56658 | FALSE
Sisesein | 3. korrus | no | 40 dB | 13.4625 | 23.0199 | FALSE
Sisesein | 3. korrus | yes | nõudeid ei esitata | 3.02033 | 4.08644 | TRUE

# IfcWall: SS-MK-10/8_ 2xkrohv 170, Sisesein
In: 1. korrus
Classification: 1.24 IfcWallType (sein) (RKAS BIM + ARCHICAD Classification)
Pset_WallCommon - Reference: SS-MK-10/8; LoadBearing: no; IsExternal: no
AR_Sein - 001_Nimetus: Sisesein; 205_Tüüp: SS-MK-10/8; 325_Helipidavus: nõudeid ei esitata; 330_Tulekindlus: nõudeid ei esitata; 335_Välispiire: no; 340_Soojusläbivus: 0; 376_Viimistlus_väljast: Telje poolne pind: TOON- vastavalt SA osale; Telje vastaspoolne pind: TOON- vastavalt SA osale; 505_Paksus: 170 mm; 605_Neto_pindala: 3.90664 m2; 600_Bruto_pindala: 9.97078 m2; 500_Kandev: FALSE; 376_Viimistlus_väljast (MUDELIS): _VIIMISTLUSKIHT - viimistlus vastavalt SA osale; _PLAATMATERJAL - tuletõkkekipsplaat, Knauf Red GKF või samaväärne; _PLAATMATERJAL - tuletõkkekipsplaat, Knauf Red GKF või samaväärne; _KARKASS - metallkarkass CW 100/50/06 ja UW 100/40/06, samm 600, vahel mineraalvill, helineeldetegur αw = 1.0, ISOVER ACOUSTIC 100mm või samaväärne; _PLAATMATERJAL - tuletõkkekipsplaat, Knauf Red GKF või samaväärne; _PLAATMATERJAL - tuletõkkekipsplaat, Knauf Red GKF või samaväärne; _HÜDROISLOATSIOON - märgruumidesse; _VIIMISTLUSKIHT - viimistlus vastavalt SA osale
AC_Pset_RenovationAndPhasing - Renovation Status: New

# IfcWall: SS-MK-10/9_šahti sein+kollektorvarisein 275, Sisesein
In: 3. korrus
Classification: 1.24 IfcWallType (sein) (RKAS BIM + ARCHICAD Classification)
Pset_WallCommon - Reference: SS-MK-10/9; LoadBearing: no; IsExternal: no
AR_Sein - 001_Nimetus: Sisesein; 205_Tüüp: SS-MK-10/9; 325_Helipidavus: nõudeid ei esitata; 330_Tulekindlus: REI 60; 335_Välispiire: no; 340_Soojusläbivus: 0; 376_Viimistlus_väljast: Telje poolne pind: TOON- vastavalt SA osale; Telje vastaspoolne pind: SOOJUSTUS- vill; 505_Paksus: 275 mm; 605_Neto_pindala: 4.071 m2; 600_Bruto_pindala: 7.1149 m2; 500_Kandev: FALSE; 376_Viimistlus_väljast (MUDELIS): _VIIMISTLUSKIHT - viimistlus vastavalt SA osale; _PLAATMATERJAL - kipsplaat veekindel; _PLAATMATERJAL - kipsplaat veekindel; _KARKASS - eriprofiilkinnitus vastavalt sisemisele plaatviimistlusele; _PLAATMATERJAL - tuletõkkekipsplaat, Knauf Red GKF või samaväärne; _KARKASS - metallkarkass CW 100/50/06 ja UW 100/40/06, samm 600, vahel mineraalvill, helineeldetegur αw = 1.0, ISOVER ACOUSTIC 100mm või samaväärne
AC_Pset_RenovationAndPhasing - Renovation Status: New

# IfcWall: SS-MK-2,7/1_2x kips karkassil 52 (2)
In: 2. korrus
Classification: 1.24 IfcWallType (sein) (RKAS BIM + ARCHICAD Classification)
Pset_WallCommon - Reference: SS-MK-2,7/1; LoadBearing: no; IsExternal: no
AR_Sein - 001_Nimetus: Sisesein; 205_Tüüp: SS-MK-2,7/1; 325_Helipidavus: nõudeid ei esitata; 330_Tulekindlus: nõudeid ei esitata; 335_Välispiire: no; 340_Soojusläbivus: 0; 376_Viimistlus_väljast: Telje poolne pind: METALL- nikkel; Telje vastaspoolne pind: KROHV- peenkrohv, valge; 505_Paksus: 52 mm; 605_Neto_pindala: 2.2163 m2; 600_Bruto_pindala: 2.2163 m2; 500_Kandev: FALSE; 376_Viimistlus_väljast (MUDELIS): _KARKASS - metallkarkass CW 66/35/06, samm 600; _PLAATMATERJAL - kipsplaat vastavalt ruumi nõuetele 12,5mm; _PLAATMATERJAL - kipsplaat vastavalt ruumi nõuetele 12,5mm
AC_Pset_RenovationAndPhasing - Renovation Status: New

# IfcWall: SS-MK-6,6/1_vill75+dold+värv tehno-võimla 60dB 257 (3)
Classification: 1.24 IfcWallType (sein) (RKAS BIM + ARCHICAD Classification)
Pset_WallCommon - Reference: SS-MK-6,6/1; LoadBearing: no; IsExternal: no
AR_Sein - 001_Nimetus: Sisesein; 205_Tüüp: SS-MK-6,6/1; 325_Helipidavus: 60 dB; 335_Välispiire: no; 340_Soojusläbivus: 0; 376_Viimistlus_väljast: Telje poolne pind: TOON- vastavalt SA osale; Telje vastaspoolne pind: PUIT- Woodex 1820; 505_Paksus: 257 mm; 605_Neto_pindala: 0 m2; 600_Bruto_pindala: 0 m2; 500_Kandev: FALSE; 376_Viimistlus_väljast (MUDELIS): _VIIMISTLUSKIHT - viimistlus vastavalt SA osale; _PLAATMATERJAL - tuletõkkekipsplaat, Knauf Red GKF või samaväärne; _PLAATMATERJAL - tuletõkkekipsplaat, Knauf Red GKF või samaväärne; _PLAATMATERJAL - tuletõkkekipsplaat, Knauf Red GKF või samaväärne; _KARKASS - metallkarkass CW 66/35/06, samm 600, mineraalvill karkassi vahel; _ÕHKVAHE; _KARKASS - metallkarkass CW 66/35/06, samm 600, mineraalvill karkassi vahel; _PLAATMATERJAL - tuletõkkekipsplaat, Knauf Red GKF või samaväärne; _PLAATMATERJAL - tuletõkkekipsplaat, Knauf Red GKF või samaväärne; _KARKASS - eriprofiilkinnitus vastavalt sisemisele plaatviimistlusele; _VIIMISTLUSKIHT - Dold plaat vastavalt SA osale
AC_Pset_RenovationAndPhasing - Renovation Status: New
Name | In | 330_Tulekindlus
Sisesein | 1. korrus | REI 60
Sisesein | 1. korrus | REI 90
Sisesein | 3. korrus | nõudeid ei esitata

# IfcWall: SS-MK-6,6/2_vill75+värv audika alune sein 60 dB 247 (4)
Classification: 1.24 IfcWallType (sein) (RKAS BIM + ARCHICAD Classification)
Pset_WallCommon - Reference: SS-MK-6,6/2; IsExternal: no
AR_Sein - 001_Nimetus: Sisesein; 205_Tüüp: SS-MK-6,6/2; 325_Helipidavus: 60 dB; 335_Välispiire: no; 340_Soojusläbivus: 0; 376_Viimistlus_väljast: Telje poolne pind: TOON- vastavalt SA osale; Telje vastaspoolne pind: KROHV- peenkrohv, valge; 505_Paksus: 247 mm; 376_Viimistlus_väljast (MUDELIS): _VIIMISTLUSKIHT - viimistlus vastavalt SA osale; _PLAATMATERJAL - tuletõkkekipsplaat, Knauf Red GKF või samaväärne; _PLAATMATERJAL - tuletõkkekipsplaat, Knauf Red GKF või samaväärne; _PLAATMATERJAL - tuletõkkekipsplaat, Knauf Red GKF või samaväärne; _KARKASS - metallkarkass CW 66/35/06, samm 600, mineraalvill karkassi vahel; _ÕHKVAHE; _KARKASS - metallkarkass CW 66/35/06, samm 600, mineraalvill karkassi vahel; _PLAATMATERJAL - tuletõkkekipsplaat, Knauf Red GKF või samaväärne; _PLAATMATERJAL - tuletõkkekipsplaat, Knauf Red GKF või samaväärne; _PLAATMATERJAL - tuletõkkekipsplaat, Knauf Red GKF või samaväärne
AC_Pset_RenovationAndPhasing - Renovation Status: New
Name | In | LoadBearing | 330_Tulekindlus | 605_Neto_pindala (m2) | 600_Bruto_pindala (m2) | 500_Kandev
Sisesein | 1. korrus | yes | REI 60 | 8.889 | 12.9292 | TRUE
Sisesein | 3. korrus | no | nõudeid ei esitata | 3.77257 | 5.79371 | FALSE
Sisesein | 3. korrus | no | REI 60 | 4.94338 | 6.0626 | FALSE
Sisesein | 3. korrus | no | REI 90 | 4.82954 | 6.12438 | FALSE

# IfcWall: SS-MK-66/3_šahti sein+plaat 106 (29)
Classification: 1.24 IfcWallType (sein) (RKAS BIM + ARCHICAD Classification)
Pset_WallCommon - Reference: SS-MK-66/3; IsExternal: no
AR_Sein - 205_Tüüp: SS-MK-66/3; 330_Tulekindlus: nõudeid ei esitata; 335_Välispiire: no; 340_Soojusläbivus: 0; 376_Viimistlus_väljast: Telje poolne pind: TOON- vastavalt SA osale; Telje vastaspoolne pind: SOOJUSTUS- vill; 505_Paksus: 106 mm; 376_Viimistlus_väljast (MUDELIS): _VIIMISTLUSKIHT - viimistlus vastavalt SA osale; _HÜDROISLOATSIOON - märgruumidesse; _PLAATMATERJAL - kipsplaat veekindel; _PLAATMATERJAL - kipsplaat veekindel; _KARKASS - metallkarkass CW 75/50, mineraalvill karkassi vahel
AC_Pset_RenovationAndPhasing - Renovation Status: New
Name | In | LoadBearing | 001_Nimetus | 325_Helipidavus | 605_Neto_pindala (m2) | 600_Bruto_pindala (m2) | 500_Kandev
Varisein | 1. korrus | no | Varisein | 40 dB | 7.47984 | 8.66554 | FALSE
Varisein | 1. korrus | no | Varisein | 40 dB | 4.01152 | 5.19722 | FALSE
Varisein | 1. korrus | no | Varisein | 40 dB | 3.96309 | 5.14879 | FALSE
Varisein | 1. korrus | no | Varisein | 44 dB | 8.78851 | 10.2721 | FALSE
Varisein | 1. korrus | no | Varisein | 40 dB | 9.92472 | 12.3397 | FALSE
Sisesein | 1. korrus | no | Sisesein | 40 dB | 9.22421 | 12.0939 | FALSE
Sisesein | 1. korrus | no | Sisesein | 40 dB | 4.24777 | 5.474 | FALSE
Sisesein | 1. korrus | no | Sisesein | 40 dB | 4.24777 | 5.47399 | FALSE
Sisesein | 1. korrus | no | Sisesein | 40 dB | 4.24776 | 5.47399 | FALSE
Sisesein | 1. korrus | no | Sisesein | 40 dB | 4.24776 | 5.47398 | FALSE
Sisesein | 1. korrus | no | Sisesein | 40 dB | 4.31053 | 5.47398 | FALSE
Varisein | 1. korrus | no | Varisein | 40 dB | 9.87288 | 12.0939 | FALSE
Varisein | 1. korrus | no | Varisein | 40 dB | 4.31053 | 5.47398 | FALSE
2 x Varisein | 1. korrus | no | Varisein | 40 dB | 4.24776 | 5.47398 | FALSE
2 x Varisein | 1. korrus | no | Varisein | 40 dB | 4.24777 | 5.47399 | FALSE
Varisein | 1. korrus | no | Varisein | 40 dB | 4.24778 | 5.474 | FALSE
Varisein | 1. korrus | no | Varisein | 40 dB | 7.51667 | 8.70237 | FALSE
Sisesein | 1. korrus | no | Sisesein | 40 dB | 0.53793 | 1.9044 | FALSE
Varisein | 1. korrus | no | Varisein | 44 dB | 9.32208 | 10.0399 | FALSE
Varisein | 1. korrus | no | Varisein | 40 dB | 25.4864 | 29.1719 | FALSE
Varisein | 1. korrus | no | Varisein | 40 dB | 8.77654 | 11.1717 | FALSE
Varisein | 2. korrus | no | Varisein | 40 dB | 20.1415 | 26.6402 | FALSE
Varisein | 2. korrus | no | Varisein | 40 dB | 6.95068 | 8.82668 | FALSE
Varisein | 2. korrus | no | Varisein | 40 dB | 20.3647 | 23.3237 | FALSE
Varisein | 3. korrus | yes | Varisein | 40 dB | 20.9675 | 23.9429 | TRUE
Varisein | 3. korrus | yes | Varisein | 40 dB | 7.22041 | 9.16921 | TRUE
Varisein | 3. korrus | yes | Varisein | 40 dB | 19.4583 | 23.6602 | TRUE

# IfcWall: SS-MK-7,5/1_plaaditud 155 (65)
Classification: 1.24 IfcWallType (sein) (RKAS BIM + ARCHICAD Classification)
Pset_WallCommon - Reference: SS-MK-7,5/1; LoadBearing: no; IsExternal: no
AR_Sein - 001_Nimetus: Sisesein; 205_Tüüp: SS-MK-7,5/1; 330_Tulekindlus: nõudeid ei esitata; 335_Välispiire: no; 340_Soojusläbivus: 0; 376_Viimistlus_väljast: Telje poolne pind: TOON- vastavalt SA osale; Telje vastaspoolne pind: TOON- vastavalt SA osale; 505_Paksus: 155 mm; 500_Kandev: FALSE; 376_Viimistlus_väljast (MUDELIS): _VIIMISTLUSKIHT - viimistlus vastavalt SA osale; _HÜDROISLOATSIOON - märgruumidesse; _PLAATMATERJAL - kipsplaat veekindel; _PLAATMATERJAL - kipsplaat veekindel; _KARKASS - metallkarkass CW 75/50, mineraalvill karkassi vahel; _PLAATMATERJAL - kipsplaat veekindel; _PLAATMATERJAL - kipsplaat veekindel; _HÜDROISLOATSIOON - märgruumidesse; _VIIMISTLUSKIHT - viimistlus vastavalt SA osale
AC_Pset_RenovationAndPhasing - Renovation Status: New
Name | In | 325_Helipidavus | 605_Neto_pindala (m2) | 600_Bruto_pindala (m2)
Sisesein | 1. korrus | 40 dB | 9.37589 | 12.7199
Sisesein | 1. korrus | 40 dB | 8.22528 | 11.4226
Sisesein | 1. korrus | 44 dB | 5.0485 | 6.8762
Sisesein | 1. korrus | 44 dB | 12.6929 | 19.3031
Sisesein | 1. korrus | 34 dB | 8.23402 | 9.82393
Sisesein | 1. korrus | 44 dB | 8.23422 | 9.82414
Sisesein | 1. korrus | 44 dB | 10.2798 | 22.1601
2 x Sisesein | 1. korrus | 44 dB | 6.66224 | 8.4795
Sisesein | 1. korrus | 44 dB | 7.04738 | 9.59823
Sisesein | 1. korrus | 44 dB | 8.10656 | 11.6381
Sisesein | 1. korrus | 44 dB | 7.30893 | 10.5618
Sisesein | 1. korrus | 44 dB | 9.21724 | 15.9163
Sisesein | 1. korrus | 40 dB | 8.29162 | 11.4974
Sisesein | 1. korrus | 44 dB | 7.64793 | 9.73616
Sisesein | 1. korrus | 44 dB | 7.66893 | 9.73616
Sisesein | 1. korrus | 44 dB | 15.1542 | 22.6891
Sisesein | 1. korrus | 44 dB | 3.69 | 4.542
Sisesein | 1. korrus | 34 dB | 10.6518 | 24.9779
5 x Sisesein | 1. korrus | 44 dB | 6.106 | 7.22708
Sisesein | 1. korrus | 44 dB | 6.66224 | 8.48321
Sisesein | 1. korrus | 44 dB | 5.4083 | 5.56521
Sisesein | 1. korrus | nõudeid ei esitata | 13.4301 | 13.557
Sisesein | 1. korrus | nõudeid ei esitata | 3.67888 | 5.89819
Sisesein | 1. korrus | 44 dB | 3.28519 | 3.89089
Sisesein | 1. korrus | 44 dB | 3.08025 | 5.22405
Sisesein | 1. korrus | 44 dB | 14.4464 | 29.7911
Sisesein | 1. korrus | nõudeid ei esitata | 7.81875 | 9.89288
Sisesein | 1. korrus | 40 dB | 8.88626 | 11.1435
Sisesein | 1. korrus | 44 dB | 0.619818 | 0.681282
Sisesein | 1. korrus | 44 dB | 7.68338 | 9.43889
Sisesein | 1. korrus | 44 dB | 5.14719 | 7.68006
4 x Sisesein | 1. korrus | 44 dB | 4.57174 | 7.04755
Sisesein | 1. korrus | 44 dB | 5.28406 | 7.83051
5 x Sisesein | 2. korrus | 44 dB | 4.81908 | 6.4215
Sisesein | 2. korrus | 44 dB | 11.1864 | 26.6402
5 x Sisesein | 2. korrus | 44 dB | 4.87903 | 5.77825
Sisesein | 2. korrus | 44 dB | 9.32475 | 23.9429
5 x Sisesein | 3. korrus | 44 dB | 5.02338 | 5.93166
Sisesein | 3. korrus | 44 dB | 9.92754 | 23.9429
5 x Sisesein | 3. korrus | 44 dB | 4.6818 | 5.79187
Sisesein | 3. korrus | 44 dB | 9.66566 | 23.5607

# IfcWall: SS-MK-7,5/1_plaat+värv 145, Sisesein
In: 1. korrus
Classification: 1.24 IfcWallType (sein) (RKAS BIM + ARCHICAD Classification)
Pset_WallCommon - Reference: SS-MK-7,5/1; LoadBearing: no; IsExternal: no
AR_Sein - 001_Nimetus: Sisesein; 205_Tüüp: SS-MK-7,5/1; 325_Helipidavus: 44 dB; 330_Tulekindlus: nõudeid ei esitata; 335_Välispiire: no; 340_Soojusläbivus: 0; 376_Viimistlus_väljast: Telje poolne pind: TOON- vastavalt SA osale; Telje vastaspoolne pind: TOON- vastavalt SA osale; 505_Paksus: 145 mm; 605_Neto_pindala: 10.7032 m2; 600_Bruto_pindala: 13.1145 m2; 500_Kandev: FALSE; 376_Viimistlus_väljast (MUDELIS): _VIIMISTLUSKIHT - viimistlus vastavalt SA osale; _HÜDROISLOATSIOON - märgruumidesse; _PLAATMATERJAL - kipsplaat veekindel; _PLAATMATERJAL - kipsplaat veekindel; _KARKASS - metallkarkass CW 75/50, mineraalvill karkassi vahel; _PLAATMATERJAL - kipsplaat veekindel; _PLAATMATERJAL - kipsplaat veekindel; _VIIMISTLUSKIHT - viimistlus vastavalt SA osale
AC_Pset_RenovationAndPhasing - Renovation Status: New

# IfcWall: SS-MK-7,5/2_värvitud TTS sein 139 (8)
Classification: 1.24 IfcWallType (sein) (RKAS BIM + ARCHICAD Classification)
Pset_WallCommon - Reference: SS-MK-7,5/2; LoadBearing: no; IsExternal: no
AR_Sein - 001_Nimetus: Sisesein; 205_Tüüp: SS-MK-7,5/2; 335_Välispiire: no; 340_Soojusläbivus: 0; 376_Viimistlus_väljast: Telje poolne pind: TOON- vastavalt SA osale; Telje vastaspoolne pind: TOON- vastavalt SA osale; 505_Paksus: 139 mm; 500_Kandev: FALSE; 376_Viimistlus_väljast (MUDELIS): _VIIMISTLUSKIHT - viimistlus vastavalt SA osale; _HÜDROISLOATSIOON - märgruumidesse; _PLAATMATERJAL - tuletõkkekipsplaat, Knauf Red GKF või samaväärne; _PLAATMATERJAL - tuletõkkekipsplaat, Knauf Red GKF või samaväärne; _KARKASS - metallkarkass CW 75/50, mineraalvill karkassi vahel; _PLAATMATERJAL - tuletõkkekipsplaat, Knauf Red GKF või samaväärne; _PLAATMATERJAL - tuletõkkekipsplaat, Knauf Red GKF või samaväärne; _VIIMISTLUSKIHT - viimistlus vastavalt SA osale
AC_Pset_RenovationAndPhasing - Renovation Status: New
Name | In | 325_Helipidavus | 330_Tulekindlus | 605_Neto_pindala (m2) | 600_Bruto_pindala (m2)
Sisesein | 1. korrus | 35 dB | EI60 | 2.85533 | 2.85533
Sisesein | 2. korrus | 44 dB | REI 60 | 9.55828 | 11.4857
Sisesein | 2. korrus | 44 dB | REI 90 | 24.1231 | 27.2395
Sisesein | 2. korrus | 35 dB | EI60 | 1.80558 | 1.80558
Sisesein | 3. korrus | 44 dB | REI 90 | 6.58813 | 13.9314
Sisesein | 3. korrus | 44 dB | REI 60 | 3.50821 | 7.67507
Sisesein | 3. korrus | 44 dB | REI 60 | 8.68813 | 14.135
Sisesein | 3. korrus | 35 dB | EI60 | 1.54216 | 1.65316

# IfcWall: SS-MK-7,5/_plaatvarisein 115 (8)
In: 1. korrus
Classification: 1.24 IfcWallType (sein) (RKAS BIM + ARCHICAD Classification)
Pset_WallCommon - Reference: SS-MK-7,5/; LoadBearing: no; IsExternal: no
AR_Sein - 001_Nimetus: Sisesein; 205_Tüüp: SS-MK-7,5/; 325_Helipidavus: 44 dB; 330_Tulekindlus: nõudeid ei esitata; 335_Välispiire: no; 340_Soojusläbivus: 0; 376_Viimistlus_väljast: Telje poolne pind: TOON- vastavalt SA osale; Telje vastaspoolne pind: SOOJUSTUS- vill; 505_Paksus: 115 mm; 500_Kandev: FALSE; 376_Viimistlus_väljast (MUDELIS): _VIIMISTLUSKIHT - viimistlus vastavalt SA osale; _HÜDROISLOATSIOON - märgruumidesse; _PLAATMATERJAL - kipsplaat veekindel; _PLAATMATERJAL - kipsplaat veekindel; _KARKASS - metallkarkass CW 75/50, mineraalvill karkassi vahel
AC_Pset_RenovationAndPhasing - Renovation Status: New
Name | 605_Neto_pindala (m2) | 600_Bruto_pindala (m2)
Sisesein | 1.51706 | 1.6675
Sisesein | 0.629829 | 0.692285
5 x Sisesein | 0.912008 | 1.00245
Sisesein | 1.18735 | 1.30509

# IfcWall: SS-PK-07/1_2xvill70+2dold muusikaklassi sein 300, Sisesein
In: 2. korrus
Classification: 1.24 IfcWallType (sein) (RKAS BIM + ARCHICAD Classification)
Pset_WallCommon - Reference: SS-PK-07/1; LoadBearing: no; IsExternal: no
AR_Sein - 001_Nimetus: Sisesein; 205_Tüüp: SS-PK-07/1; 325_Helipidavus: 60 dB; 330_Tulekindlus: nõudeid ei esitata; 335_Välispiire: no; 340_Soojusläbivus: 0; 376_Viimistlus_väljast: Telje poolne pind: TOON- vastavalt SA osale; Telje vastaspoolne pind: PUIT- Woodex 1820; 505_Paksus: 300 mm; 605_Neto_pindala: 23.4632 m2; 600_Bruto_pindala: 28.3221 m2; 500_Kandev: FALSE; 376_Viimistlus_väljast (MUDELIS): _VIIMISTLUSKIHT - viimistlus vastavalt SA osale; _PLAATMATERJAL - tuletõkkekipsplaat, Knauf Red GKF või samaväärne; _PLAATMATERJAL - OSB3 plaat; _KARKASS - puitroov 70x45mm vertikaalne, samm 600mm, vahel mineraalvill, helineeldetegur αw = 1.0, ISOVER ACOUSTIC 70mm või samaväärne; _ÕHKVAHE; _KARKASS - puitroov 70x45mm vertikaalne, samm 600mm, vahel mineraalvill, helineeldetegur αw = 1.0, ISOVER ACOUSTIC 70mm või samaväärne; _PLAATMATERJAL - tuletõkkekipsplaat, Knauf Red GKF või samaväärne; _PLAATMATERJAL - tuletõkkekipsplaat, Knauf Red GKF või samaväärne; _KARKASS - eriprofiilkinnitus vastavalt sisemisele plaatviimistlusele; _VIIMISTLUSKIHT - Dold plaat vastavalt SA osale
AC_Pset_RenovationAndPhasing - Renovation Status: New

# IfcWall: SS-PK-10/1_vill100+2dold 220 (22)
Classification: 1.24 IfcWallType (sein) (RKAS BIM + ARCHICAD Classification)
Pset_WallCommon - Reference: SS-PK-10/1; IsExternal: no
AR_Sein - 001_Nimetus: Sisesein; 205_Tüüp: SS-PK-10/1; 335_Välispiire: no; 340_Soojusläbivus: 0; 376_Viimistlus_väljast: Telje poolne pind: PUIT- Woodex 1820; Telje vastaspoolne pind: PUIT- Woodex 1820; 505_Paksus: 220 mm; 376_Viimistlus_väljast (MUDELIS): _VIIMISTLUSKIHT - Dold plaat vastavalt SA osale; _KARKASS - eriprofiilkinnitus vastavalt sisemisele plaatviimistlusele; _PLAATMATERJAL - tuletõkkekipsplaat, Knauf Red GKF või samaväärne; _PLAATMATERJAL - tuletõkkekipsplaat, Knauf Red GKF või samaväärne; _KARKASS - puitpruss 100x50mm vertikaalne, samm 600mm, vahel mineraalvill, helineeldetegur αw = 1.0, ISOVER ACOUSTIC 100mm või samaväärne; _PLAATMATERJAL - tuletõkkekipsplaat, Knauf Red GKF või samaväärne; _PLAATMATERJAL - tuletõkkekipsplaat, Knauf Red GKF või samaväärne; _KARKASS - eriprofiilkinnitus vastavalt sisemisele plaatviimistlusele; _VIIMISTLUSKIHT - Dold plaat vastavalt SA osale
AC_Pset_RenovationAndPhasing - Renovation Status: New
Name | In | LoadBearing | 325_Helipidavus | 330_Tulekindlus | 605_Neto_pindala (m2) | 600_Bruto_pindala (m2) | 500_Kandev
Sisesein | 1. korrus | no | 52 dB | nõudeid ei esitata | 22.6935 | 45.2937 | FALSE
Sisesein | 1. korrus | no | 52 dB | nõudeid ei esitata | 30.3359 | 34.1676 | FALSE
2 x Sisesein | 1. korrus | no | 52 dB | nõudeid ei esitata | 18.9453 | 24.363 | FALSE
Sisesein | 1. korrus | no | 52 dB | nõudeid ei esitata | 16.5786 | 24.363 | FALSE
Sisesein | 1. korrus | no | 52 dB | nõudeid ei esitata | 28.4186 | 34.2095 | FALSE
Sisesein | 1. korrus | no | 52 dB | nõudeid ei esitata | 12.4353 | 17.0723 | FALSE
Sisesein | 1. korrus | no | 52 dB | nõudeid ei esitata | 6.88799 | 11.732 | FALSE
Sisesein | 1. korrus | no | 52 dB | nõudeid ei esitata | 4.01699 | 4.09979 | FALSE
Sisesein | 1. korrus | no | 52 dB | nõudeid ei esitata | 23.5279 | 34.1676 | FALSE
Sisesein | 1. korrus | no | 52 dB | nõudeid ei esitata | 9.87914 | 38.1482 | FALSE
Sisesein | 1. korrus | no | 52 dB | nõudeid ei esitata | 8.13004 | 10.3478 | FALSE
Sisesein | 1. korrus | no | 52 dB | nõudeid ei esitata | 11.8105 | 30.1871 | FALSE
Sisesein | 1. korrus | no | 52 dB | nõudeid ei esitata | 8.12773 | 10.3455 | FALSE
Sisesein | 1. korrus | no | 52 dB | nõudeid ei esitata | 3.7112 | 9.1342 | FALSE
Sisesein | 1. korrus | no | 52 dB | nõudeid ei esitata | 1.96766 | 8.10149 | FALSE
Sisesein | 1. korrus | no | 52 dB | nõudeid ei esitata | 2.78226 | 13.3 | FALSE
Sisesein | 1. korrus | no | 52 dB | nõudeid ei esitata | 0.771318 | 0.95 | FALSE
Sisesein | 2. korrus | no | 40 dB | nõudeid ei esitata | 5.4978 | 7.9591 | FALSE
Sisesein | 2. korrus | no | 40 dB | nõudeid ei esitata | 3.54717 | 3.905 | FALSE
Sisesein | 2. korrus | no | 40 dB | nõudeid ei esitata | 5.08512 | 7.29301 | FALSE
Sisesein | 3. korrus | yes | 52 dB | REI 60 | 3.6375 | 3.6569 | TRUE

# IfcWall: SS-PK-10/2_vill100+dold+plaat 200 (11)
Classification: 1.24 IfcWallType (sein) (RKAS BIM + ARCHICAD Classification)
Pset_WallCommon - Reference: SS-PK-10/2; LoadBearing: no; IsExternal: no
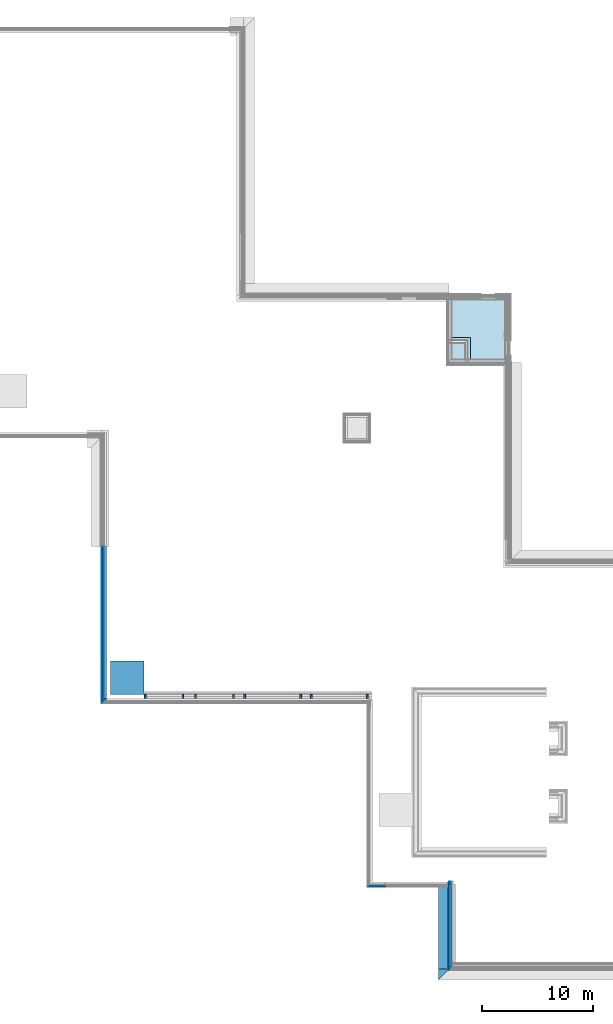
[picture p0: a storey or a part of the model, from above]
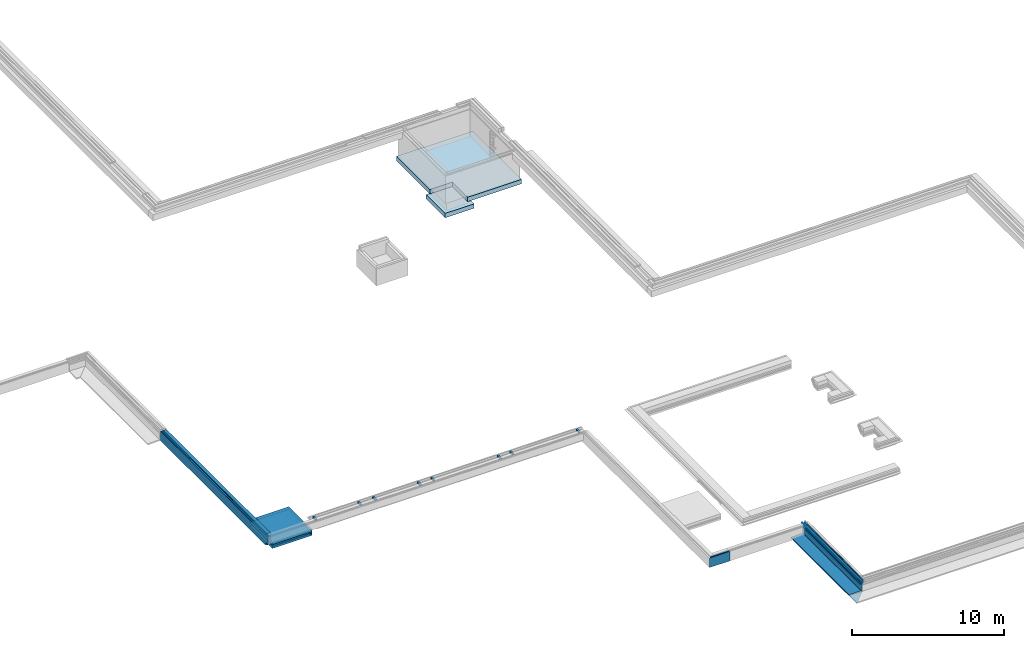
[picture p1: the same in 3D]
Properties of the parts of a building model (IFC2X3), part 12 of 14

# IfcWall: SS-PK-10/2_vill100+dold+plaat 200 (11)
AR_Sein - 001_Nimetus: Sisesein; 205_Tüüp: SS-PK-10/2; 325_Helipidavus: 52 dB; 330_Tulekindlus: nõudeid ei esitata; 335_Välispiire: no; 340_Soojusläbivus: 0; 376_Viimistlus_väljast: Telje poolne pind: TOON- vastavalt SA osale; Telje vastaspoolne pind: TOON- vastavalt SA osale; 505_Paksus: 200 mm; 500_Kandev: FALSE; 376_Viimistlus_väljast (MUDELIS): _VIIMISTLUSKIHT - viimistlus vastavalt SA osale; _HÜDROISLOATSIOON - märgruumidesse; _PLAATMATERJAL - kipsplaat veekindel; _PLAATMATERJAL - kipsplaat veekindel; _KARKASS - puitpruss 100x50mm vertikaalne, samm 600mm, vahel mineraalvill, helineeldetegur αw = 1.0, ISOVER ACOUSTIC 100mm või samaväärne; _PLAATMATERJAL - tuletõkkekipsplaat, Knauf Red GKF või samaväärne; _PLAATMATERJAL - tuletõkkekipsplaat, Knauf Red GKF või samaväärne; _KARKASS - eriprofiilkinnitus vastavalt sisemisele plaatviimistlusele; _VIIMISTLUSKIHT - viimistlus vastavalt SA osale
AC_Pset_RenovationAndPhasing - Renovation Status: New
Name | In | 605_Neto_pindala (m2) | 600_Bruto_pindala (m2)
Sisesein | 1. korrus | 18.1766 | 25.5358
Sisesein | 1. korrus | 8.50075 | 9.88007
2 x Sisesein | 1. korrus | 16.7913 | 23.6818
Sisesein | 1. korrus | 8.43134 | 10.4792
Sisesein | 1. korrus | 13.5466 | 19.2741
Sisesein | 1. korrus | 13.9293 | 15.2764
Sisesein | 1. korrus | 3.55725 | 4.1989
Sisesein | 1. korrus | 8.58232 | 10.1384
Sisesein | 1. korrus | 7.47254 | 8.82414
Sisesein | 3. korrus | 5.29416 | 7.34136

# IfcWall: SS-PK-10/3_vill100+dold+värv 195 (7)
Classification: 1.24 IfcWallType (sein) (RKAS BIM + ARCHICAD Classification)
Pset_WallCommon - Reference: SS-PK-10/3; LoadBearing: no; IsExternal: no
AR_Sein - 001_Nimetus: Sisesein; 205_Tüüp: SS-PK-10/3; 335_Välispiire: no; 340_Soojusläbivus: 0; 376_Viimistlus_väljast: Telje poolne pind: TOON- vastavalt SA osale; Telje vastaspoolne pind: TOON- vastavalt SA osale; 505_Paksus: 195 mm; 500_Kandev: FALSE; 376_Viimistlus_väljast (MUDELIS): _VIIMISTLUSKIHT - viimistlus vastavalt SA osale; _PLAATMATERJAL - tuletõkkekipsplaat, Knauf Red GKF või samaväärne; _PLAATMATERJAL - OSB3 plaat; _KARKASS - puitpruss 100x50mm vertikaalne, samm 600mm, vahel mineraalvill, helineeldetegur αw = 1.0, ISOVER ACOUSTIC 100mm või samaväärne; _PLAATMATERJAL - OSB3 plaat; _PLAATMATERJAL - tuletõkkekipsplaat, Knauf Red GKF või samaväärne; _KARKASS - eriprofiilkinnitus vastavalt sisemisele plaatviimistlusele; _VIIMISTLUSKIHT - viimistlus vastavalt SA osale
AC_Pset_RenovationAndPhasing - Renovation Status: New
Name | In | 325_Helipidavus | 330_Tulekindlus | 605_Neto_pindala (m2) | 600_Bruto_pindala (m2)
Sisesein | 1. korrus | 52 dB | REI 90 | 19.7158 | 21.7042
Sisesein | 1. korrus | 53 dB | nõudeid ei esitata | 1.0425 | 1.8436
Sisesein | 1. korrus | 52 dB | nõudeid ei esitata | 2.95903 | 6.1137
Sisesein | 1. korrus | 53 dB | nõudeid ei esitata | 13.5736 | 14.4557
Sisesein | 1. korrus | 52 dB | REI 60 | 9.11902 | 33.9403
Sisesein | 2. korrus | 52 dB | nõudeid ei esitata | 8.84453 | 9.96809
Sisesein | 3. korrus | nõudeid ei esitata | REI 90 | 6.66382 | 13.8959

# IfcWall: SS-PK-10/4_vill100+2värv distantsliistudega 220 (24)
Classification: 1.24 IfcWallType (sein) (RKAS BIM + ARCHICAD Classification)
Pset_WallCommon - Reference: SS-PK-10/4; LoadBearing: no; IsExternal: no
AR_Sein - 001_Nimetus: Sisesein; 205_Tüüp: SS-PK-10/4; 325_Helipidavus: 52 dB; 330_Tulekindlus: nõudeid ei esitata; 335_Välispiire: no; 340_Soojusläbivus: 0; 376_Viimistlus_väljast: Telje poolne pind: TOON- vastavalt SA osale; Telje vastaspoolne pind: TOON- vastavalt SA osale; 505_Paksus: 220 mm; 500_Kandev: FALSE; 376_Viimistlus_väljast (MUDELIS): _VIIMISTLUSKIHT - viimistlus vastavalt SA osale; _PLAATMATERJAL - tuletõkkekipsplaat, Knauf Red GKF või samaväärne; _PLAATMATERJAL - OSB3 plaat; _KARKASS- distantasliist; _KARKASS - puitpruss 100x50mm vertikaalne, samm 600mm, vahel mineraalvill, helineeldetegur αw = 1.0, ISOVER ACOUSTIC 100mm või samaväärne; _KARKASS- distantasliist; _PLAATMATERJAL - OSB3 plaat; _PLAATMATERJAL - tuletõkkekipsplaat, Knauf Red GKF või samaväärne; _VIIMISTLUSKIHT - viimistlus vastavalt SA osale
AC_Pset_RenovationAndPhasing - Renovation Status: New
Name | In | 605_Neto_pindala (m2) | 600_Bruto_pindala (m2)
Sisesein | 1. korrus | 30.0153 | 34.2095
Sisesein | 1. korrus | 30.5444 | 34.2095
Sisesein | 2. korrus | 24.568 | 28.3568
2 x Sisesein | 2. korrus | 24.1364 | 28.3568
3 x Sisesein | 2. korrus | 24.5348 | 28.3221
Sisesein | 2. korrus | 24.1198 | 28.3221
Sisesein | 2. korrus | 24.5213 | 27.3686
Sisesein | 2. korrus | 14.7146 | 16.4752
Sisesein | 3. korrus | 1.014 | 2.70972
Sisesein | 3. korrus | 23.9436 | 28.6486
Sisesein | 3. korrus | 24.5726 | 28.6837
Sisesein | 3. korrus | 24.5895 | 28.6837
4 x Sisesein | 3. korrus | 24.9782 | 28.6486
Sisesein | 3. korrus | 22.712 | 28.6837
Sisesein | 3. korrus | 23.8628 | 28.6837
Sisesein | 3. korrus | 24.9782 | 28.8056
Sisesein | 3. korrus | 7.35426 | 12.694
Sisesein | 3. korrus | 21.2417 | 25.9389

# IfcWall: SS-PK-10/5_vill100+plaat+värv 175 (3)
In: 1. korrus
Classification: 1.24 IfcWallType (sein) (RKAS BIM + ARCHICAD Classification)
Pset_WallCommon - Reference: SS-PK-10/5; LoadBearing: no; IsExternal: no
AR_Sein - 001_Nimetus: Sisesein; 205_Tüüp: SS-PK-10/5; 335_Välispiire: no; 340_Soojusläbivus: 0; 376_Viimistlus_väljast: Telje poolne pind: TOON- vastavalt SA osale; Telje vastaspoolne pind: TOON- vastavalt SA osale; 505_Paksus: 175 mm; 500_Kandev: FALSE; 376_Viimistlus_väljast (MUDELIS): _VIIMISTLUSKIHT - viimistlus vastavalt SA osale; _HÜDROISLOATSIOON - märgruumidesse; _PLAATMATERJAL - kipsplaat veekindel; _PLAATMATERJAL - kipsplaat veekindel; _KARKASS - puitpruss 100x50mm vertikaalne, samm 600mm, vahel mineraalvill, helineeldetegur αw = 1.0, ISOVER ACOUSTIC 100mm või samaväärne; _PLAATMATERJAL - tuletõkkekipsplaat, Knauf Red GKF või samaväärne; _PLAATMATERJAL - tuletõkkekipsplaat, Knauf Red GKF või samaväärne; _VIIMISTLUSKIHT - viimistlus vastavalt SA osale
AC_Pset_RenovationAndPhasing - Renovation Status: New
Name | 325_Helipidavus | 330_Tulekindlus | 605_Neto_pindala (m2) | 600_Bruto_pindala (m2)
Sisesein | 52 dB | nõudeid ei esitata | 11.1147 | 12.5496
Sisesein | 35 dB | REI 60 | 8.4177 | 9.07335
Sisesein | 52 dB | nõudeid ei esitata | 29.6326 | 33.3366

# IfcWall: SS-PK-10/6_vill100+dold+plaat+ kollektor 335, Sisesein
In: 3. korrus
Classification: 1.24 IfcWallType (sein) (RKAS BIM + ARCHICAD Classification)
Pset_WallCommon - Reference: SS-PK-10/6; LoadBearing: no; IsExternal: no
AR_Sein - 001_Nimetus: Sisesein; 205_Tüüp: SS-PK-10/6; 325_Helipidavus: 53 dB; 330_Tulekindlus: nõudeid ei esitata; 335_Välispiire: no; 340_Soojusläbivus: 0; 376_Viimistlus_väljast: Telje poolne pind: TOON- vastavalt SA osale; Telje vastaspoolne pind: TOON- vastavalt SA osale; 505_Paksus: 335 mm; 605_Neto_pindala: 4.071 m2; 600_Bruto_pindala: 7.1149 m2; 500_Kandev: FALSE; 376_Viimistlus_väljast (MUDELIS): _VIIMISTLUSKIHT - viimistlus vastavalt SA osale; _HÜDROISLOATSIOON - märgruumidesse; _PLAATMATERJAL - kipsplaat veekindel; _PLAATMATERJAL - kipsplaat veekindel; _KARKASS - eriprofiilkinnitus vastavalt sisemisele plaatviimistlusele; _PLAATMATERJAL - tuletõkkekipsplaat, Knauf Red GKF või samaväärne; _KARKASS - puitpruss 100x50mm vertikaalne, samm 600mm, vahel mineraalvill, helineeldetegur αw = 1.0, ISOVER ACOUSTIC 100mm või samaväärne; _PLAATMATERJAL - tuletõkkekipsplaat, Knauf Red GKF või samaväärne; _PLAATMATERJAL - tuletõkkekipsplaat, Knauf Red GKF või samaväärne; _KARKASS - eriprofiilkinnitus vastavalt sisemisele plaatviimistlusele; _VIIMISTLUSKIHT - viimistlus vastavalt SA osale
AC_Pset_RenovationAndPhasing - Renovation Status: New

# IfcWall: SS-PK-10/7_vill100+plaat+värv vineeriga 217, Sisesein
In: 1. korrus
Classification: 1.24 IfcWallType (sein) (RKAS BIM + ARCHICAD Classification)
Pset_WallCommon - Reference: SS-PK-10/7; LoadBearing: no; IsExternal: no
AR_Sein - 001_Nimetus: Sisesein; 205_Tüüp: SS-PK-10/7; 325_Helipidavus: 52 dB; 330_Tulekindlus: REI 60; 335_Välispiire: no; 340_Soojusläbivus: 0; 376_Viimistlus_väljast: Telje poolne pind: TOON- vastavalt SA osale; Telje vastaspoolne pind: PUIT- kuusk H; 505_Paksus: 217 mm; 605_Neto_pindala: 18.1607 m2; 600_Bruto_pindala: 22.7247 m2; 500_Kandev: FALSE; 376_Viimistlus_väljast (MUDELIS): _VIIMISTLUSKIHT - viimistlus vastavalt SA osale; _HÜDROISLOATSIOON - märgruumidesse; _PLAATMATERJAL - kipsplaat veekindel; _PLAATMATERJAL - kipsplaat veekindel; _KARKASS - puitpruss 100x50mm vertikaalne, samm 600mm, vahel mineraalvill, helineeldetegur αw = 1.0, ISOVER ACOUSTIC 100mm või samaväärne; _PLAATMATERJAL - vineerplaat; _PLAATMATERJAL - tuletõkkekipsplaat, Knauf Red GKF või samaväärne; _KARKASS - roov 50x50mm, s. 600 mm, kinnitus puidukruvidega
AC_Pset_RenovationAndPhasing - Renovation Status: New

# IfcWall: SS-PK-10/8_vill100+dold+vineer-värv 200 (8)
Classification: 1.24 IfcWallType (sein) (RKAS BIM + ARCHICAD Classification)
Pset_WallCommon - Reference: SS-PK-10/8; LoadBearing: no; IsExternal: no
AR_Sein - 001_Nimetus: Sisesein; 205_Tüüp: SS-PK-10/8; 325_Helipidavus: 52 dB; 330_Tulekindlus: nõudeid ei esitata; 335_Välispiire: no; 340_Soojusläbivus: 0; 376_Viimistlus_väljast: Telje poolne pind: TOON- vastavalt SA osale; Telje vastaspoolne pind: PUIT- Woodex 1820; 505_Paksus: 200 mm; 500_Kandev: FALSE; 376_Viimistlus_väljast (MUDELIS): _VIIMISTLUSKIHT - viimistlus vastavalt SA osale; _PLAATMATERJAL - tuletõkkekipsplaat, Knauf Red GKF või samaväärne; _PLAATMATERJAL - tuletõkkekipsplaat, Knauf Red GKF või samaväärne; _PLAATMATERJAL - OSB3 plaat; _KARKASS - puitpruss 100x50mm vertikaalne, samm 600mm, vahel mineraalvill, helineeldetegur αw = 1.0, ISOVER ACOUSTIC 100mm või samaväärne; _PLAATMATERJAL - OSB3 plaat; _PLAATMATERJAL - tuletõkkekipsplaat, Knauf Red GKF või samaväärne; _KARKASS - eriprofiilkinnitus vastavalt sisemisele plaatviimistlusele; _VIIMISTLUSKIHT - Dold plaat vastavalt SA osale
AC_Pset_RenovationAndPhasing - Renovation Status: New
Name | In | 605_Neto_pindala (m2) | 600_Bruto_pindala (m2)
Sisesein | 1. korrus | 2.68079 | 4.13203
Sisesein | 1. korrus | 26.8187 | 32.6325
Sisesein | 1. korrus | 0.97995 | 1.30625
Sisesein | 2. korrus | 24.108 | 27.3686
Sisesein | 3. korrus | 22.6782 | 28.6486
Sisesein | 3. korrus | 13.9728 | 28.6837
Sisesein | 3. korrus | 21.6436 | 28.6494
Sisesein | 3. korrus | 21.4268 | 27.9466

# IfcWall: SS-PK-10/9_vill100+2värv 170 (13)
Classification: 1.24 IfcWallType (sein) (RKAS BIM + ARCHICAD Classification)
Pset_WallCommon - Reference: SS-PK-10/9; IsExternal: no
AR_Sein - 001_Nimetus: Sisesein; 205_Tüüp: SS-PK-10/9; 335_Välispiire: no; 340_Soojusläbivus: 0; 376_Viimistlus_väljast: Telje poolne pind: TOON- vastavalt SA osale; Telje vastaspoolne pind: TOON- vastavalt SA osale; 505_Paksus: 170 mm; 376_Viimistlus_väljast (MUDELIS): _VIIMISTLUSKIHT - viimistlus vastavalt SA osale; _PLAATMATERJAL - tuletõkkekipsplaat, Knauf Red GKF või samaväärne; _PLAATMATERJAL - OSB3 plaat; _KARKASS - puitpruss 100x50mm vertikaalne, samm 600mm, vahel mineraalvill, helineeldetegur αw = 1.0, ISOVER ACOUSTIC 100mm või samaväärne; _PLAATMATERJAL - OSB3 plaat; _PLAATMATERJAL - tuletõkkekipsplaat, Knauf Red GKF või samaväärne; _VIIMISTLUSKIHT - viimistlus vastavalt SA osale
AC_Pset_RenovationAndPhasing - Renovation Status: New
Name | In | LoadBearing | 325_Helipidavus | 330_Tulekindlus | 605_Neto_pindala (m2) | 600_Bruto_pindala (m2) | 500_Kandev
Sisesein | 1. korrus | yes | 53 dB | REI 60 | 0.551088 | 5.52136 | TRUE
Sisesein | 1. korrus | no | 52 dB | nõudeid ei esitata | 16.9411 | 17.6391 | FALSE
Sisesein | 1. korrus | no | 52 dB | REI 60 | 12.1549 | 14.2488 | FALSE
Sisesein | 1. korrus | no | 35 dB | REI 60 | 8.49598 | 13.4709 | FALSE
Sisesein | 1. korrus | no | 35 dB | REI 60 | 30.8154 | 33.6481 | FALSE
Sisesein | 1. korrus | no | 40 dB | nõudeid ei esitata | 9.86128 | 10.8173 | FALSE
Sisesein | 1. korrus | no | 35 dB | REI 60 | 14.6845 | 16.1227 | FALSE
Sisesein | 1. korrus | no | 52 dB | REI 60 | 12.0039 | 16.9819 | FALSE
Sisesein | 1. korrus | yes | 40 dB | nõudeid ei esitata | 2.32094 | 4.61182 | TRUE
Sisesein | 1. korrus | no | 35 dB | REI 60 | 20.6846 | 25.2304 | FALSE
Sisesein | 2. korrus | no | 52 dB | nõudeid ei esitata | 8.49826 | 10.9089 | FALSE
Sisesein | 3. korrus | no | 52 dB | REI 60 | 10.2227 | 12.6938 | FALSE
Sisesein | 3. korrus | no | 52 dB | nõudeid ei esitata | 12.0499 | 16.0457 | FALSE

# IfcWall: SS-RB-20/10_+1 plaat +kollektor 360 (3)
Classification: 1.24 IfcWallType (sein) (RKAS BIM + ARCHICAD Classification)
Pset_WallCommon - Reference: SS-RB-20/10; LoadBearing: yes; IsExternal: no
AR_Sein - 001_Nimetus: Sisesein; 205_Tüüp: SS-RB-20/10; 325_Helipidavus: 55 dB; 330_Tulekindlus: REI 60; 335_Välispiire: no; 340_Soojusläbivus: 0; 376_Viimistlus_väljast: Telje poolne pind: TOON- vastavalt SA osale; Telje vastaspoolne pind: GENERAL; 505_Paksus: 360 mm; 500_Kandev: TRUE; 376_Viimistlus_väljast (MUDELIS): _VIIMISTLUSKIHT - viimistlus vastavalt SA osale; _HÜDROISLOATSIOON - märgruumidesse; _PLAATMATERJAL - kipsplaat veekindel; _PLAATMATERJAL - kipsplaat veekindel; _KARKASS - eriprofiilkinnitus vastavalt sisemisele plaatviimistlusele; _KANDETARIND - monteeritav raudbetoon vastavalt EK osale; _HÜDROISLOATSIOON - märgruumidesse
AC_Pset_RenovationAndPhasing - Renovation Status: New
Name | In | 605_Neto_pindala (m2) | 600_Bruto_pindala (m2)
Sisesein | 1. korrus | 6.07719 | 7.75719
Sisesein | 2. korrus | 4.5544 | 6.23442
Sisesein | 3. korrus | 4.55442 | 6.23442

# IfcWall: SS-RB-20/11_kipsil krohv+roov60 +krohv 310 (2)
In: 2. korrus
Classification: 1.24 IfcWallType (sein) (RKAS BIM + ARCHICAD Classification)
Pset_WallCommon - Reference: SS-RB-20/11; LoadBearing: yes; IsExternal: no
AR_Sein - 001_Nimetus: Sisesein; 205_Tüüp: SS-RB-20/11; 325_Helipidavus: 55 dB; 330_Tulekindlus: REI 60; 335_Välispiire: no; 340_Soojusläbivus: 0; 376_Viimistlus_väljast: Telje poolne pind: TOON- vastavalt SA osale; Telje vastaspoolne pind: TOON- vastavalt SA osale; 505_Paksus: 310 mm; 500_Kandev: TRUE; 376_Viimistlus_väljast (MUDELIS): _VIIMISTLUSKIHT - viimistlus vastavalt SA osale; _PLAATMATERJAL - tuletõkkekipsplaat, Knauf Red GKF või samaväärne; _PLAATMATERJAL - OSB3 plaat; _KARKASS - metallkarkass CW 66/35/06, samm 600, mineraalvill karkassi vahel; _KANDETARIND - monteeritav raudbetoon vastavalt EK osale; _VIIMISTLUSKIHT - viimistlus vastavalt SA osale
AC_Pset_RenovationAndPhasing - Renovation Status: New
Name | 605_Neto_pindala (m2) | 600_Bruto_pindala (m2)
Sisesein | 24.3523 | 28.7625
Sisesein | 10.4309 | 10.4309

# IfcWall: SS-RB-20/12_+2 plaat +kollektor 375 (3)
Classification: 1.24 IfcWallType (sein) (RKAS BIM + ARCHICAD Classification)
Pset_WallCommon - Reference: SS-RB-20/12; LoadBearing: yes; IsExternal: no
AR_Sein - 001_Nimetus: Sisesein; 205_Tüüp: SS-RB-20/12; 325_Helipidavus: 55 dB; 335_Välispiire: no; 340_Soojusläbivus: 0; 376_Viimistlus_väljast: Telje poolne pind: TOON- vastavalt SA osale; Telje vastaspoolne pind: TOON- vastavalt SA osale; 505_Paksus: 375 mm; 500_Kandev: TRUE; 376_Viimistlus_väljast (MUDELIS): _VIIMISTLUSKIHT - viimistlus vastavalt SA osale; _HÜDROISLOATSIOON - märgruumidesse; _PLAATMATERJAL - kipsplaat veekindel; _PLAATMATERJAL - kipsplaat veekindel; _KARKASS - eriprofiilkinnitus vastavalt sisemisele plaatviimistlusele; _KANDETARIND - monteeritav raudbetoon vastavalt EK osale; _HÜDROISLOATSIOON - märgruumidesse; _VIIMISTLUSKIHT - viimistlus vastavalt SA osale
AC_Pset_RenovationAndPhasing - Renovation Status: New
Name | In | 330_Tulekindlus | 605_Neto_pindala (m2) | 600_Bruto_pindala (m2)
Sisesein | 1. korrus | REI 60 | 5.8544 | 8.84866
Sisesein | 2. korrus | REI 60 | 4.34435 | 7.14314
Sisesein | 3. korrus | nõudeid ei esitata | 4.52202 | 7.14314

# IfcWall: SS-RB-20/1_+2 krohv 55 dB 220 (24)
Classification: 1.24 IfcWallType (sein) (RKAS BIM + ARCHICAD Classification)
Pset_WallCommon - Reference: SS-RB-20/1; IsExternal: no
AR_Sein - 001_Nimetus: Sisesein; 205_Tüüp: SS-RB-20/1; 325_Helipidavus: 55 dB; 335_Välispiire: no; 340_Soojusläbivus: 0; 376_Viimistlus_väljast: Telje poolne pind: TOON- vastavalt SA osale; Telje vastaspoolne pind: TOON- vastavalt SA osale; 505_Paksus: 220 mm; 376_Viimistlus_väljast (MUDELIS): _VIIMISTLUSKIHT - viimistlus vastavalt SA osale; _KANDETARIND - monteeritav raudbetoon vastavalt EK osale; _VIIMISTLUSKIHT - viimistlus vastavalt SA osale
AC_Pset_RenovationAndPhasing - Renovation Status: New
Name | In | LoadBearing | 330_Tulekindlus | 605_Neto_pindala (m2) | 600_Bruto_pindala (m2) | 500_Kandev
Sisesein | 1. korrus | yes | REI 60 | 30.4415 | 35.236 | TRUE
Sisesein | 1. korrus | yes | REI 60 | 8.88761 | 10.9876 | TRUE
Sisesein | 1. korrus | yes | REI 60 | 12.7919 | 13.1999 | TRUE
Sisesein | 1. korrus | yes | REI 60 | 17.195 | 17.195 | TRUE
Sisesein | 1. korrus | yes | REI 60 | 23.5002 | 26.4148 | TRUE
Sisesein | 1. korrus | yes | REI 60 | 59.07 | 64.741 | TRUE
Sisesein | 1. korrus | yes | REI 60 | 21.6838 | 24.944 | TRUE
Sisesein | 1. korrus | yes | REI 60 | 3.63995 | 13.1598 | TRUE
Sisesein | 1. korrus | yes | REI 60 | 24.1461 | 24.1461 | TRUE
Sisesein | 1. korrus | yes | REI 60 | 12.8511 | 15.1511 | TRUE
Sisesein | 1. korrus | yes | REI 60 | 3.67659 | 7.28439 | TRUE
Sisesein | 1. korrus | yes | REI 60 | 44.7775 | 50.5505 | TRUE
Sisesein | 1. korrus | yes | REI 60 | 12.5386 | 15.3883 | TRUE
Sisesein | 1. korrus | yes | REI 60 | 23.4474 | 28.0474 | TRUE
Sisesein | 2. korrus | yes | REI 60 | 31.7048 | 39.6628 | TRUE
Sisesein | 2. korrus | yes | REI 60 | 33.3026 | 37.4414 | TRUE
Sisesein | 2. korrus | yes | REI 60 | 7.74905 | 36.5312 | TRUE
Sisesein | 2. korrus | no | nõudeid ei esitata | 3.9066 | 3.9832 | FALSE
Sisesein | 2. korrus | yes | REI 60 | 34.2399 | 38.3462 | TRUE
Sisesein | 2. korrus | yes | REI 60 | 14.1826 | 39.8867 | TRUE
Sisesein | 2. korrus | yes | REI 60 | 21.0375 | 21.0375 | TRUE
Sisesein | 3. korrus | yes | REI 60 | 25.3287 | 25.3287 | TRUE
Sisesein | 3. korrus | yes | REI 60 | 18.9956 | 18.9956 | TRUE
Sisesein | 3. korrus | yes | REI 60 | 1.224 | 1.224 | TRUE

# IfcWall: SS-RB-20/2_+2 plaat 230 (22)
Classification: 1.24 IfcWallType (sein) (RKAS BIM + ARCHICAD Classification)
Pset_WallCommon - Reference: SS-RB-20/2; LoadBearing: yes; IsExternal: no
AR_Sein - 001_Nimetus: Sisesein; 205_Tüüp: SS-RB-20/2; 325_Helipidavus: 55 dB; 335_Välispiire: no; 340_Soojusläbivus: 0; 376_Viimistlus_väljast: Telje poolne pind: TOON- vastavalt SA osale; Telje vastaspoolne pind: TOON- vastavalt SA osale; 505_Paksus: 230 mm; 500_Kandev: TRUE; 376_Viimistlus_väljast (MUDELIS): _VIIMISTLUSKIHT - viimistlus vastavalt SA osale; _HÜDROISLOATSIOON - märgruumidesse; _KANDETARIND - monteeritav raudbetoon vastavalt EK osale; _HÜDROISLOATSIOON - märgruumidesse; _VIIMISTLUSKIHT - viimistlus vastavalt SA osale
AC_Pset_RenovationAndPhasing - Renovation Status: New
Name | In | 330_Tulekindlus | 605_Neto_pindala (m2) | 600_Bruto_pindala (m2)
Sisesein | 1. korrus | REI 60 | 1.77225 | 2.6555
Sisesein | 1. korrus | REI 60 | 3.70125 | 4.7954
Sisesein | 1. korrus | REI 60 | 3.44745 | 3.57785
Sisesein | 1. korrus | REI 60 | 8.05392 | 9.7019
Sisesein | 1. korrus | REI 60 | 2.2935 | 2.599
Sisesein | 1. korrus | REI 60 | 2.35605 | 2.68375
Sisesein | 1. korrus | REI 60 | 29.3477 | 42.2918
Sisesein | 1. korrus | REI 60 | 7.15928 | 9.36463
Sisesein | 2. korrus | REI 60 | 6.43825 | 7.6687
Sisesein | 2. korrus | REI 60 | 1.826 | 2.16395
Sisesein | 2. korrus | REI 60 | 1.57223 | 2.16395
Sisesein | 2. korrus | REI 60 | 1.93135 | 2.16395
Sisesein | 2. korrus | REI 60 | 2.9575 | 3.83435
Sisesein | 2. korrus | REI 60 | 21.209 | 34.1404
Sisesein | 2. korrus | REI 60 | 5.72065 | 7.55966
Sisesein | 3. korrus | nõudeid ei esitata | 1.73826 | 2.0114
Sisesein | 3. korrus | nõudeid ei esitata | 2.9575 | 3.8233
Sisesein | 3. korrus | nõudeid ei esitata | 22.741 | 34.1404
Sisesein | 3. korrus | nõudeid ei esitata | 5.8899 | 7.55966
Sisesein | 3. korrus | nõudeid ei esitata | 6.7566 | 8.02125
Sisesein | 3. korrus | nõudeid ei esitata | 1.859 | 1.9549
Sisesein | 3. korrus | nõudeid ei esitata | 1.7187 | 2.0114

# IfcWall: SS-RB-20/3_+krohv+dold 240 (17)
Classification: 1.24 IfcWallType (sein) (RKAS BIM + ARCHICAD Classification)
Pset_WallCommon - Reference: SS-RB-20/3; IsExternal: no
AR_Sein - 001_Nimetus: Sisesein; 205_Tüüp: SS-RB-20/3; 325_Helipidavus: 55 dB; 335_Välispiire: no; 340_Soojusläbivus: 0; 376_Viimistlus_väljast: Telje poolne pind: TOON- vastavalt SA osale; Telje vastaspoolne pind: TOON- vastavalt SA osale; 505_Paksus: 240 mm; 376_Viimistlus_väljast (MUDELIS): _VIIMISTLUSKIHT - viimistlus vastavalt SA osale; _KANDETARIND - monteeritav raudbetoon vastavalt EK osale; _KARKASS - eriprofiilkinnitus vastavalt sisemisele plaatviimistlusele; _VIIMISTLUSKIHT - viimistlus vastavalt SA osale
AC_Pset_RenovationAndPhasing - Renovation Status: New
Name | In | LoadBearing | 330_Tulekindlus | 605_Neto_pindala (m2) | 600_Bruto_pindala (m2) | 500_Kandev
Sisesein | 1. korrus | no | EI60 | 7.01638 | 29.0769 | FALSE
Sisesein | 1. korrus | yes | REI 60 | 31.4028 | 31.4028 | TRUE
Sisesein | 1. korrus | yes | REI 60 | 5.4385 | 8.395 | TRUE
Sisesein | 1. korrus | no | EI60 | 4.00238 | 13.7999 | FALSE
Sisesein | 1. korrus | no | EI60 | 5.82125 | 24.7805 | FALSE
Sisesein | 1. korrus | yes | REI 60 | 8.10128 | 10.4013 | TRUE
Sisesein | 1. korrus | yes | EI60 | 7.67095 | 7.67095 | TRUE
Sisesein | 1. korrus | yes | REI 60 | 29.3302 | 33.9302 | TRUE
Sisesein | 2. korrus | yes | REI 60 | 11.5501 | 12.1976 | TRUE
Sisesein | 2. korrus | yes | EI60 | 4.66394 | 11.1039 | TRUE
Sisesein | 2. korrus | yes | REI 60 | 4.04544 | 11.2499 | TRUE
Sisesein | 2. korrus | yes | EI60 | 7.6995 | 19.95 | TRUE
Sisesein | 2. korrus | no | EI60 | 9.22218 | 24.9752 | FALSE
Sisesein | 3. korrus | no | EI60 | 3.01318 | 10.1399 | FALSE
Sisesein | 3. korrus | no | REI 60 | 4.47387 | 10.9139 | FALSE
Sisesein | 3. korrus | no | EI60 | 8.52992 | 24.924 | FALSE
Sisesein | 3. korrus | no | EI60 | 6.7711 | 18.9956 | FALSE

# IfcWall: SS-RB-20/5_+1 plaat 215 (18)
Classification: 1.24 IfcWallType (sein) (RKAS BIM + ARCHICAD Classification)
Pset_WallCommon - Reference: SS-RB-20/5; LoadBearing: yes; IsExternal: no
AR_Sein - 001_Nimetus: Sisesein; 205_Tüüp: SS-RB-20/5; 325_Helipidavus: 55 dB; 335_Välispiire: no; 340_Soojusläbivus: 0; 376_Viimistlus_väljast: Telje poolne pind: TOON- vastavalt SA osale; Telje vastaspoolne pind: BETOON- hall, raketis 50x50; 505_Paksus: 215 mm; 500_Kandev: TRUE; 376_Viimistlus_väljast (MUDELIS): _VIIMISTLUSKIHT - viimistlus vastavalt SA osale; _HÜDROISLOATSIOON - märgruumidesse; _KANDETARIND - monteeritav raudbetoon vastavalt EK osale
AC_Pset_RenovationAndPhasing - Renovation Status: New
Name | In | 330_Tulekindlus | 605_Neto_pindala (m2) | 600_Bruto_pindala (m2)
Sisesein | 1. korrus | REI 60 | 9.35203 | 9.35203
Sisesein | 1. korrus | REI 60 | 18.1307 | 18.1307
Sisesein | 1. korrus | REI 60 | 37.7176 | 43.5574
Sisesein | 1. korrus | REI 60 | 8.757 | 9.618
Sisesein | 1. korrus | REI 60 | 7.56027 | 10.3203
Sisesein | 2. korrus | REI 60 | 7.15688 | 7.15688
Sisesein | 2. korrus | REI 60 | 13.875 | 13.875
Sisesein | 2. korrus | REI 60 | 33.3666 | 35.121
Sisesein | 2. korrus | REI 60 | 7.228 | 7.602
Sisesein | 2. korrus | REI 60 | 2.7547 | 2.8851
Sisesein | 2. korrus | REI 60 | 5.67601 | 8.41202
Sisesein | 3. korrus | nõudeid ei esitata | 2.8362 | 2.95845
Sisesein | 3. korrus | REI 60 | 6.64158 | 6.64158
Sisesein | 3. korrus | REI 60 | 7.098 | 7.35
Sisesein | 3. korrus | REI 60 | 4.81901 | 7.8575
Sisesein | 3. korrus | nõudeid ei esitata | 32.6452 | 32.6452
Sisesein | 3. korrus | REI 60 | 7.54204 | 7.665
Sisesein | 3. korrus | REI 60 | 5.408 | 5.6

# IfcWall: SS-RB-20/6_+1 krohv 210 (6)
Classification: 1.24 IfcWallType (sein) (RKAS BIM + ARCHICAD Classification)
Pset_WallCommon - Reference: SS-RB-20/6; IsExternal: no
AR_Sein - 001_Nimetus: Sisesein; 205_Tüüp: SS-RB-20/6; 325_Helipidavus: 55 dB; 335_Välispiire: no; 340_Soojusläbivus: 0; 376_Viimistlus_väljast: Telje poolne pind: TOON- vastavalt SA osale; Telje vastaspoolne pind: BETOON- hall, raketis 50x50; 505_Paksus: 210 mm; 376_Viimistlus_väljast (MUDELIS): _VIIMISTLUSKIHT - viimistlus vastavalt SA osale; _KANDETARIND - monteeritav raudbetoon vastavalt EK osale
AC_Pset_RenovationAndPhasing - Renovation Status: New
Name | In | LoadBearing | 330_Tulekindlus | 605_Neto_pindala (m2) | 600_Bruto_pindala (m2) | 500_Kandev
Sisesein | 1. korrus | no | nõudeid ei esitata | 12.2152 | 12.2152 | FALSE
Sisesein | 2. korrus | yes | REI 60 | 15.7365 | 15.7365 | TRUE
Sisesein | 2. korrus | yes | REI 60 | 10.692 | 10.692 | TRUE
Sisesein | 2. korrus | yes | REI 60 | 26.9945 | 26.9945 | TRUE
Sisesein | 2. korrus | no | nõudeid ei esitata | 22.44 | 23.698 | FALSE
Sisesein | 3. korrus | yes | REI 60 | 23.3555 | 23.3555 | TRUE

# IfcWall: SS-RB-20/7_kipsil krohv +dold 275, Sisesein
In: 2. korrus
Classification: 1.24 IfcWallType (sein) (RKAS BIM + ARCHICAD Classification)
Pset_WallCommon - Reference: SS-RB-20/7; LoadBearing: yes; IsExternal: no
AR_Sein - 001_Nimetus: Sisesein; 205_Tüüp: SS-RB-20/7; 325_Helipidavus: 55 dB; 330_Tulekindlus: REI 60; 335_Välispiire: no; 340_Soojusläbivus: 0; 376_Viimistlus_väljast: Telje poolne pind: TOON- vastavalt SA osale; Telje vastaspoolne pind: PUIT- Woodex 1820; 505_Paksus: 274.8 mm; 605_Neto_pindala: 37.909 m2; 600_Bruto_pindala: 45.23 m2; 500_Kandev: TRUE; 376_Viimistlus_väljast (MUDELIS): _VIIMISTLUSKIHT - viimistlus vastavalt SA osale; _PLAATMATERJAL - erikõva kipsplaat, kinnitamiseks kasutada erikõvale plaadile sobivaid kruve nt XTB 3,9x55mm, Knauf Blue (Diamant) või samaväärne; _PLAATMATERJAL - erikõva kipsplaat, kinnitamiseks kasutada erikõvale plaadile sobivaid kruve nt XTB 3,9x55mm, Knauf Blue (Diamant) või samaväärne; _KARKASS - eriprofiilkinnitus vastavalt sisemisele plaatviimistlusele; _KANDETARIND - monteeritav raudbetoon vastavalt EK osale; _KARKASS - eriprofiilkinnitus vastavalt sisemisele plaatviimistlusele; _VIIMISTLUSKIHT - Dold plaat vastavalt SA osale
AC_Pset_RenovationAndPhasing - Renovation Status: New

# IfcWall: SS-RB-20/8_kipsil krohv roov 75+krohv 350, Sisesein
In: 1. korrus
Classification: 1.24 IfcWallType (sein) (RKAS BIM + ARCHICAD Classification)
Pset_WallCommon - Reference: SS-RB-20/8; LoadBearing: yes; IsExternal: no
AR_Sein - 001_Nimetus: Sisesein; 205_Tüüp: SS-RB-20/8; 325_Helipidavus: 55 dB; 330_Tulekindlus: REI 60; 335_Välispiire: no; 340_Soojusläbivus: 0; 376_Viimistlus_väljast: Telje poolne pind: TOON- vastavalt SA osale; Telje vastaspoolne pind: TOON- vastavalt SA osale; 505_Paksus: 350 mm; 605_Neto_pindala: 36.2424 m2; 600_Bruto_pindala: 36.2424 m2; 500_Kandev: TRUE; 376_Viimistlus_väljast (MUDELIS): _VIIMISTLUSKIHT - viimistlus vastavalt SA osale; _PLAATMATERJAL - tuletõkkekipsplaat, Knauf Red GKF või samaväärne; _PLAATMATERJAL - tuletõkkekipsplaat, Knauf Red GKF või samaväärne; _PLAATMATERJAL - tuletõkkekipsplaat, Knauf Red GKF või samaväärne; _KARKASS - eriprofiilkinnitus vastavalt sisemisele plaatviimistlusele; _KANDETARIND - monteeritav raudbetoon vastavalt EK osale; _VIIMISTLUSKIHT - viimistlus vastavalt SA osale
AC_Pset_RenovationAndPhasing - Renovation Status: New

# IfcWall: SS-RB-20/9_kipsil krohv+roov66 +krohv 325 (8)
Classification: 1.24 IfcWallType (sein) (RKAS BIM + ARCHICAD Classification)
Pset_WallCommon - Reference: SS-RB-20/9; LoadBearing: yes; IsExternal: no
AR_Sein - 001_Nimetus: Sisesein; 205_Tüüp: SS-RB-20/9; 325_Helipidavus: 55 dB; 330_Tulekindlus: REI 60; 335_Välispiire: no; 340_Soojusläbivus: 0; 376_Viimistlus_väljast: Telje poolne pind: TOON- vastavalt SA osale; Telje vastaspoolne pind: TOON- vastavalt SA osale; 505_Paksus: 325 mm; 500_Kandev: TRUE; 376_Viimistlus_väljast (MUDELIS): _VIIMISTLUSKIHT - viimistlus vastavalt SA osale; _PLAATMATERJAL - tuletõkkekipsplaat, Knauf Red GKF või samaväärne; _PLAATMATERJAL - OSB3 plaat; _KARKASS - metallkarkass CW 66/35/06, samm 600, mineraalvill karkassi vahel; _ÕHKVAHE; _KANDETARIND - monteeritav raudbetoon vastavalt EK osale; _VIIMISTLUSKIHT - viimistlus vastavalt SA osale
AC_Pset_RenovationAndPhasing - Renovation Status: New
Name | In | 605_Neto_pindala (m2) | 600_Bruto_pindala (m2)
Sisesein | 1. korrus | 34.132 | 34.132
Sisesein | 1. korrus | 32.1903 | 32.1903
Sisesein | 2. korrus | 27.975 | 27.975
Sisesein | 2. korrus | 29.718 | 29.718
Sisesein | 2. korrus | 28.8361 | 28.8361
Sisesein | 3. korrus | 26.026 | 26.026
Sisesein | 3. korrus | 25.4007 | 25.4007
Sisesein | 3. korrus | 23.49 | 24.65

# IfcWall: SS-RBM-20/1_+krohv+dold 240, Sisesein
In: 1. korrus
Classification: 1.24 IfcWallType (sein) (RKAS BIM + ARCHICAD Classification)
Pset_WallCommon - Reference: SS-RBM-20/1; LoadBearing: yes; IsExternal: no
AR_Sein - 001_Nimetus: Sisesein; 205_Tüüp: SS-RBM-20/1; 325_Helipidavus: 55 dB; 330_Tulekindlus: REI 60; 335_Välispiire: no; 340_Soojusläbivus: 0; 376_Viimistlus_väljast: Telje poolne pind: TOON- vastavalt SA osale; Telje vastaspoolne pind: PUIT- Woodex 1820; 505_Paksus: 240 mm; 605_Neto_pindala: 14.0286 m2; 600_Bruto_pindala: 21.183 m2; 500_Kandev: TRUE; 376_Viimistlus_väljast (MUDELIS): _VIIMISTLUSKIHT - viimistlus vastavalt SA osale; _KANDETARIND - monoliitne raudbetoon vastavalt EK osale; _KARKASS - eriprofiilkinnitus vastavalt sisemisele plaatviimistlusele; _VIIMISTLUSKIHT - Dold plaat vastavalt SA osale
AC_Pset_RenovationAndPhasing - Renovation Status: New

# IfcWall: VS-CLT-14/1_Katuseakna parapett CLT 428 (3)
In: 4. TEHNO korrus
Classification: 1.24 IfcWallType (sein) (RKAS BIM + ARCHICAD Classification)
Pset_WallCommon - Reference: VS-CLT-14/1; LoadBearing: yes; IsExternal: yes
AR_Sein - 001_Nimetus: Välissein; 205_Tüüp: VS-CLT-14/1; 325_Helipidavus: 33 dB; 330_Tulekindlus: REI 60; 335_Välispiire: yes; 340_Soojusläbivus: 0.13; 376_Viimistlus_väljast: Telje poolne pind: TOON- helehall RR21; Telje vastaspoolne pind: TOON- vastavalt SA osale; 505_Paksus: 428 mm; 500_Kandev: TRUE; 376_Viimistlus_väljast (MUDELIS): _VÄLISVIIMISTLUS - kiudtsemendist fassaadikatteplaat, tuletundlikkus A2-s1, d0, Cembrit Cover toon hall C 020 või samaväärne; _KARKASS - puitroov 50x50mm vertikaalne, sügavimmutatud, samm 600mm; _TUULETÕKE - tuuletõkkeplaat, soojuserijuhtivus λD<0,031 W/(mK), ISOVER RKL FACADE või samaväärne, liitekohad katta tihendusteibiga ISOVER FacadeTape või samaväärne; _SOOJUSTUS - mineraalvill, λD<0,032 W/(mK), kuumtsingitud lehtteras termoroovidega, S350GD+Zn275 vastavalt EN10346, ISOVER EXTREME 32 200mm või samaväärne; _KANDETARIND - CLT ristkihtliimpuit vastavalt EK osale, CLT paigaldusvuugid teibitakse ROTHOBLAAS teibiga; _VIIMISTLUSKIHT - viimistlus vastavalt SA osale
AC_Pset_RenovationAndPhasing - Renovation Status: New
Name | 605_Neto_pindala (m2) | 600_Bruto_pindala (m2)
Välissein | 28.7385 | 46.6365
Välissein | 54.8443 | 55.1096
Välissein | 29.9272 | 48.1108

# IfcWall: VS-CLT-16/1_soojust 200+laudis 472 (29)
Classification: 1.24 IfcWallType (sein) (RKAS BIM + ARCHICAD Classification)
Pset_WallCommon - Reference: VS-CLT-16/1; LoadBearing: yes; IsExternal: yes
AR_Sein - 001_Nimetus: Välissein; 205_Tüüp: VS-CLT-16/1; 325_Helipidavus: 40 dB; 330_Tulekindlus: REI 60; 335_Välispiire: yes; 340_Soojusläbivus: 0.13; 376_Viimistlus_väljast: Telje poolne pind: PUITLAUDIS- hõbehall peits V ; Telje vastaspoolne pind: TOON- vastavalt SA osale; 505_Paksus: 472 mm; 500_Kandev: TRUE; 376_Viimistlus_väljast (MUDELIS): _VÄLISVIIMISTLUS - vertikaalne voodrilaud, Platowood P01 profiil 18x140mm, kuusk; eeltöödeldud tuletõkkega mõlemad küljed, B-s1, d0, Woodsafe Exterior WFX™ või samaväärne; _KARKASS - puitroov 32x50mm horisontaalne, immutatud Driconi tulekaitsevahendiga või samaväärne, samm 600mm; _KARKASS - puitroov 32x50mm vertikaalne, immutatud Driconi tulekaitsevahendiga või samaväärne, samm 600mm; _TUULETÕKE - tuuletõkkeplaat, soojuserijuhtivus λD<0,031 W/(mK), ISOVER RKL FACADE või samaväärne, liitekohad katta tihendusteibiga ISOVER FacadeTape või samaväärne; _SOOJUSTUS - mineraalvill, λD<0,032 W/(mK), kuumtsingitud lehtteras termoroovidega, S350GD+Zn275 vastavalt EN10346, ISOVER EXTREME 32 200mm või samaväärne; _KANDETARIND - CLT ristkihtliimpuit vastavalt EK osale, CLT paigaldusvuugid teibitakse ROTHOBLAAS teibiga; _VIIMISTLUSKIHT - viimistlus vastavalt SA osale
AC_Pset_RenovationAndPhasing - Renovation Status: New
Name | In | 605_Neto_pindala (m2) | 600_Bruto_pindala (m2)
Välissein | 1. korrus | 36.8673 | 161.795
Välissein | 1. korrus | 100.922 | 110.133
Välissein | 1. korrus | 29.8341 | 42.127
Välissein | 1. korrus | 77.1043 | 77.1829
Välissein | 1. korrus | 9.06684 | 24.5375
Välissein | 2. korrus | 29.8949 | 29.8949
Välissein | 2. korrus | 55.4835 | 91.77
Välissein | 2. korrus | 29.79 | 29.8575
Välissein | 2. korrus | 89.5395 | 100.849
Välissein | 2. korrus | 148.778 | 152.569
Välissein | 2. korrus | 85.5814 | 103.041
Välissein | 2. korrus | 22.4698 | 29.6887
Välissein | 2. korrus | 52.272 | 91.77
Välissein | 2. korrus | 29.2785 | 49.9125
Välissein | 2. korrus | 69.1009 | 97.4648
Välissein | 2. korrus | 26.6974 | 39.2734
Välissein | 2. korrus | 14.6343 | 23.0075
Välissein | 2. korrus | 9.3559 | 9.3559
Välissein | 3. korrus | 32.6852 | 32.6852
Välissein | 3. korrus | 60.7458 | 100.335
Välissein | 3. korrus | 63.816 | 100.335
Välissein | 3. korrus | 32.5704 | 32.6442
Välissein | 3. korrus | 73.7915 | 101.437
Välissein | 3. korrus | 7.38782 | 9.02809
Välissein | 3. korrus | 36.7082 | 58.7904
Välissein | 3. korrus | 63.4541 | 91.137
Välissein | 3. korrus | 68.5222 | 105.993
Välissein | 3. korrus | 14.8234 | 14.8972
Välissein | 3. korrus | 57.7646 | 84.2654

# IfcWall: VS-CLT-16/2_A ploki välissein 2-3 k 602 (4)
Classification: 1.24 IfcWallType (sein) (RKAS BIM + ARCHICAD Classification)
Pset_WallCommon - Reference: VS-CLT-16/2; LoadBearing: yes; IsExternal: yes
AR_Sein - 001_Nimetus: Välissein; 205_Tüüp: VS-CLT-16/2; 325_Helipidavus: 40 dB; 330_Tulekindlus: REI 60; 335_Välispiire: yes; 340_Soojusläbivus: 0.13; 376_Viimistlus_väljast: Telje poolne pind: PUITLAUDIS- hõbehall peits V ; Telje vastaspoolne pind: PUIT- Woodex 1820; 505_Paksus: 602 mm; 500_Kandev: TRUE; 376_Viimistlus_väljast (MUDELIS): _VÄLISVIIMISTLUS - vertikaalne voodrilaud, Platowood P01 profiil 18x140mm, kuusk; eeltöödeldud tuletõkkega mõlemad küljed, B-s1, d0, Woodsafe Exterior WFX™ või samaväärne; _KARKASS - puitroov 32x50mm horisontaalne, immutatud Driconi tulekaitsevahendiga või samaväärne, samm 600mm; _KARKASS - puitroov 32x50mm vertikaalne, immutatud Driconi tulekaitsevahendiga või samaväärne, samm 600mm; _TUULETÕKE - tuuletõkkeplaat, soojuserijuhtivus λD<0,031 W/(mK), ISOVER RKL FACADE või samaväärne, liitekohad katta tihendusteibiga ISOVER FacadeTape või samaväärne; _SOOJUSTUS - mineraalvill, λD<0,032 W/(mK), kuumtsingitud lehtteras termoroovidega, S350GD+Zn275 vastavalt EN10346, ISOVER EXTREME 32 200mm või samaväärne; _KANDETARIND - CLT ristkihtliimpuit vastavalt EK osale, CLT paigaldusvuugid teibitakse ROTHOBLAAS teibiga; _KARKASS - metallkarkass CW 50/50/06 ja UW 75/40/06, samm 600, 50x50mm postid eraldiseisvalt vaheldumisi, kogupaksus 75mm, vahel mineraalvill, helineeldetegur αw = 0.85, ISOVER ACOUSTIC 50mm või samaväärne; _PLAATMATERJAL - kipsplaat vastavalt ruumi nõuetele 12,5mm; _PLAATMATERJAL - kipsplaat vastavalt ruumi nõuetele 12,5mm; _KARKASS - eriprofiilkinnitus vastavalt sisemisele plaatviimistlusele; _VIIMISTLUSKIHT - Dold plaat vastavalt SA osale
AC_Pset_RenovationAndPhasing - Renovation Status: New
Name | In | 605_Neto_pindala (m2) | 600_Bruto_pindala (m2)
Välissein | 2. korrus | 24.3558 | 36.999
Välissein | 2. korrus | 45.9837 | 74.3472
Välissein | 3. korrus | 18.8653 | 31.4413
Välissein | 3. korrus | 82.6644 | 120.466

# IfcWall: VS-CLT-16/3_sokkel võimla 393 (9)
In: Vundament
Classification: 1.24 IfcWallType (sein) (RKAS BIM + ARCHICAD Classification)
Pset_WallCommon - Reference: VS-CLT-16/3; LoadBearing: yes; IsExternal: yes
AR_Sein - 001_Nimetus: Sokkel; 205_Tüüp: VS-CLT-16/3; 325_Helipidavus: nõudeid ei esitata; 330_Tulekindlus: REI 60; 335_Välispiire: yes; 376_Viimistlus_väljast: Telje poolne pind: KROHV- Weber pas.481 AquaBalance, toon helehall CL444 (S 3502-Y) * 35; Telje vastaspoolne pind: PUIT- kuusk V; 505_Paksus: 393 mm; 500_Kandev: TRUE; 376_Viimistlus_väljast (MUDELIS): _TUULETÕKE - sokli krohv, silikoonvaikkrohv Weber.pas 481 AquaBalance 1mm "scratch" viimistlus, toon helehall CL444 (S 3502-Y) * 35, SILS süsteem, või samaväärne; _SOOJUSTUS - vahtpolüstüreenplaadid EPS 120 Perimeeter, survetugevus min 120kPa, veeimavus <2%, soojuserijuhtivus λD<0,036 W/(mK); _SOOJUSTUS - ekstrudeeritud polüstüreenist plaadid XPS 250, soojuserijuhtivus lambdaD=0,035 W/mK, veeimavus alla 2%, näiteks Styrofoam 250 SL-A-N või samaväärne, plaatide vuugid omavahel nihutada; _HÜDROISOLATSIOON - 3x SBS rullmaterjal vastavalt TL2 nõuetele, nakke tugevduseks betoonpind eelnevalt katta hüdroisolatsiooni bituumenvõõbaga; _KANDETARIND - CLT ristkihtliimpuit vastavalt EK osale, CLT paigaldusvuugid teibitakse ROTHOBLAAS teibiga
AC_Pset_RenovationAndPhasing - Renovation Status: New
Name | 340_Soojusläbivus | 605_Neto_pindala (m2) | 600_Bruto_pindala (m2)
Sokkel | 0.13 | 0.154583 | 0.205343
Sokkel | 0.13 | 0.152571 | 0.152571
Sokkel | 0.13 | 2.21466 | 2.21586
Sokkel | 0.12 | 0.841018 | 0.841018
Sokkel | 0.12 | 1.52624 | 1.52744
Sokkel | 0.12 | 1.30958 | 1.30958
Sokkel | 0.12 | 1.98892 | 1.98892
Sokkel | 0.13 | 0.948432 | 0.948432
Sokkel | 0.12 | 0.154602 | 0.205362

# IfcWall: VS-CLT-16/4_soojust 200+70soojustus+laudis 382 (2)
In: 2. korrus
Classification: 1.24 IfcWallType (sein) (RKAS BIM + ARCHICAD Classification)
Pset_WallCommon - Reference: VS-CLT-16/4; LoadBearing: yes; IsExternal: yes
AR_Sein - 001_Nimetus: Välissein; 205_Tüüp: VS-CLT-16/4; 325_Helipidavus: 40 dB; 330_Tulekindlus: REI 60; 335_Välispiire: yes; 376_Viimistlus_väljast: Telje poolne pind: PUITLAUDIS- hõbehall peits V ; Telje vastaspoolne pind: TOON- tumehall; 505_Paksus: 382 mm; 500_Kandev: TRUE; 376_Viimistlus_väljast (MUDELIS): _VÄLISVIIMISTLUS - vertikaalne voodrilaud, Platowood P01 profiil 18x140mm, kuusk; eeltöödeldud tuletõkkega mõlemad küljed, B-s1, d0, Woodsafe Exterior WFX™ või samaväärne; _KARKASS - puitroov 32x50mm horisontaalne, immutatud Driconi tulekaitsevahendiga või samaväärne, samm 600mm; _KARKASS - puitroov 32x50mm vertikaalne, immutatud Driconi tulekaitsevahendiga või samaväärne, samm 600mm; _TUULETÕKE - tuuletõkkeplaat, soojuserijuhtivus λD<0,031 W/(mK), ISOVER RKL FACADE või samaväärne, liitekohad katta tihendusteibiga ISOVER FacadeTape või samaväärne; _SOOJUSTUS - mineraalvill, λD<0,032 W/(mK), kuumtsingitud lehtteras termoroovidega, S350GD+Zn275 vastavalt EN10346, ISOVER EXTREME 32 200mm või samaväärne; _KARKASS - puitpruss 70x70mm sammuga 600mm, vahel SOOJUSTUS - mineraalvill, soojuserijuhtivus λD<0,032 W/(mK), ISOVER EXTREME 32 70mm või samaväärne; _AURUTÕKE - aurutõkkekile, vuugid ülekattega teibitud, veeaurutakistus Sd 0,3 kuni 25m, ISOVER Vario auru- ja õhutõkkesüsteem (Vario Xtra aurutõkkekile, Vario MultiTape SL, Vario DF) või samaväärne
AC_Pset_RenovationAndPhasing - Renovation Status: New
Name | 340_Soojusläbivus | 605_Neto_pindala (m2) | 600_Bruto_pindala (m2)
Välissein | 0.13 | 22.5631 | 23.1397
Välissein | 0.12 | 13.3988 | 13.4157

# IfcWall: VS-CLT-16/5_karkass 100+soojust 200+laudis 620 (2)
Classification: 1.24 IfcWallType (sein) (RKAS BIM + ARCHICAD Classification)
Pset_WallCommon - Reference: VS-CLT-16/5; LoadBearing: yes; IsExternal: yes
AR_Sein - 001_Nimetus: Välissein; 205_Tüüp: VS-CLT-16/5; 325_Helipidavus: 40 dB; 330_Tulekindlus: REI 60; 335_Välispiire: yes; 340_Soojusläbivus: 0.13; 376_Viimistlus_väljast: Telje poolne pind: PUITLAUDIS- hõbehall peits V ; Telje vastaspoolne pind: TOON- vastavalt SA osale; 505_Paksus: 620 mm; 500_Kandev: TRUE; 376_Viimistlus_väljast (MUDELIS): _VÄLISVIIMISTLUS - vertikaalne voodrilaud, Platowood P01 profiil 18x140mm, kuusk; eeltöödeldud tuletõkkega mõlemad küljed, B-s1, d0, Woodsafe Exterior WFX™ või samaväärne; _KARKASS - puitroov 32x50mm horisontaalne, immutatud Driconi tulekaitsevahendiga või samaväärne, samm 600mm; _KARKASS - puitroov 32x50mm vertikaalne, immutatud Driconi tulekaitsevahendiga või samaväärne, samm 600mm; _TUULETÕKE - tuuletõkkeplaat, soojuserijuhtivus λD<0,031 W/(mK), ISOVER RKL FACADE või samaväärne, liitekohad katta tihendusteibiga ISOVER FacadeTape või samaväärne; _SOOJUSTUS - mineraalvill, λD<0,032 W/(mK), kuumtsingitud lehtteras termoroovidega, S350GD+Zn275 vastavalt EN10346, ISOVER EXTREME 32 200mm või samaväärne; _KANDETARIND - CLT ristkihtliimpuit vastavalt EK osale, CLT paigaldusvuugid teibitakse ROTHOBLAAS teibiga; _KARKASS - puitroov 50x130mm, s. 600mm; _PLAATMATERJAL - niiskuskindel vineerplaat, kvaliteediklass BB; _VIIMISTLUSKIHT - viimistlus vastavalt SA osale
AC_Pset_RenovationAndPhasing - Renovation Status: New
Name | In | 605_Neto_pindala (m2) | 600_Bruto_pindala (m2)
Välissein | 2. korrus | 5.79494 | 6.1429
Välissein | 3. korrus | 17.0297 | 18.3183

# IfcWall: VS-CLT-16/6_soojust 200 akustiline plaat 622, Välissein
In: 4. TEHNO korrus
Classification: 1.24 IfcWallType (sein) (RKAS BIM + ARCHICAD Classification)
Pset_WallCommon - Reference: VS-CLT-16/6; LoadBearing: yes; IsExternal: yes
AR_Sein - 001_Nimetus: Välissein; 205_Tüüp: VS-CLT-16/6; 325_Helipidavus: 35dB; 330_Tulekindlus: nõudeid ei esitata; 335_Välispiire: yes; 340_Soojusläbivus: 0.13; 376_Viimistlus_väljast: Telje poolne pind: PUITLAUDIS- hõbehall peits V ; Telje vastaspoolne pind: TOON- vastavalt SA osale; 505_Paksus: 622 mm; 605_Neto_pindala: 17.1435 m2; 600_Bruto_pindala: 17.51 m2; 500_Kandev: TRUE; 376_Viimistlus_väljast (MUDELIS): _VÄLISVIIMISTLUS - vertikaalne voodrilaud, Platowood P01 profiil 18x140mm, kuusk; eeltöödeldud tuletõkkega mõlemad küljed, B-s1, d0, Woodsafe Exterior WFX™ või samaväärne; _KARKASS - puitroov 32x50mm horisontaalne, immutatud Driconi tulekaitsevahendiga või samaväärne, samm 600mm; _KARKASS - puitroov 32x50mm vertikaalne, immutatud Driconi tulekaitsevahendiga või samaväärne, samm 600mm; _TUULETÕKE - tuuletõkkeplaat, soojuserijuhtivus λD<0,031 W/(mK), ISOVER RKL FACADE või samaväärne, liitekohad katta tihendusteibiga ISOVER FacadeTape või samaväärne; _SOOJUSTUS - mineraalvill, λD<0,032 W/(mK), kuumtsingitud lehtteras termoroovidega, S350GD+Zn275 vastavalt EN10346, ISOVER EXTREME 32 200mm või samaväärne; _KANDETARIND - CLT ristkihtliimpuit vastavalt EK osale, CLT paigaldusvuugid teibitakse ROTHOBLAAS teibiga; _KARKASS - puitroov 50x80mm, s. 600mm; _PLAATMATERJAL - niiskuskindel vineerplaat, kvaliteediklass BB; _SOOJUSTUS - akustiline vill Ecophon Industry must TAL PE 50mm või samaväärne; _VIIMISTLUSKIHT - must akustiline fliis vastavalt SA osale; _VIIMISTLUSKIHT - viimistlus vastavalt SA osale
AC_Pset_RenovationAndPhasing - Renovation Status: New

# IfcWall: VS-CLT-16/7_must kangas+karkass 100+soojust 200+laudis 622, Välissein
In: 3. korrus
Classification: 1.24 IfcWallType (sein) (RKAS BIM + ARCHICAD Classification)
Pset_WallCommon - Reference: VS-CLT-16/7; LoadBearing: yes; IsExternal: yes
AR_Sein - 001_Nimetus: Välissein; 205_Tüüp: VS-CLT-16/7; 325_Helipidavus: 40 dB; 330_Tulekindlus: REI 60; 335_Välispiire: yes; 340_Soojusläbivus: 0.13; 376_Viimistlus_väljast: Telje poolne pind: PUITLAUDIS- hõbehall peits V ; Telje vastaspoolne pind: TOON- vastavalt SA osale; 505_Paksus: 622 mm; 605_Neto_pindala: 4.86564 m2; 600_Bruto_pindala: 5.2338 m2; 500_Kandev: TRUE; 376_Viimistlus_väljast (MUDELIS): _VÄLISVIIMISTLUS - vertikaalne voodrilaud, Platowood P01 profiil 18x140mm, kuusk; eeltöödeldud tuletõkkega mõlemad küljed, B-s1, d0, Woodsafe Exterior WFX™ või samaväärne; _KARKASS - puitroov 32x50mm horisontaalne, immutatud Driconi tulekaitsevahendiga või samaväärne, samm 600mm; _KARKASS - puitroov 32x50mm vertikaalne, immutatud Driconi tulekaitsevahendiga või samaväärne, samm 600mm; _TUULETÕKE - tuuletõkkeplaat, soojuserijuhtivus λD<0,031 W/(mK), ISOVER RKL FACADE või samaväärne, liitekohad katta tihendusteibiga ISOVER FacadeTape või samaväärne; _SOOJUSTUS - mineraalvill, λD<0,032 W/(mK), kuumtsingitud lehtteras termoroovidega, S350GD+Zn275 vastavalt EN10346, ISOVER EXTREME 32 200mm või samaväärne; _KANDETARIND - CLT ristkihtliimpuit vastavalt EK osale, CLT paigaldusvuugid teibitakse ROTHOBLAAS teibiga; _KARKASS - puitroov 50x130mm, s. 600mm; _PLAATMATERJAL - niiskuskindel vineerplaat, kvaliteediklass BB; _VIIMISTLUSKIHT - must akustiline fliis vastavalt SA osale; _VIIMISTLUSKIHT - viimistlus vastavalt SA osale
AC_Pset_RenovationAndPhasing - Renovation Status: New

# IfcWall: VS-CLT-16/8_ak. plaat+CLT160+soojust 200 524 (2)
Classification: 1.24 IfcWallType (sein) (RKAS BIM + ARCHICAD Classification)
Pset_WallCommon - Reference: VS-CLT-16/8; LoadBearing: yes; IsExternal: yes
AR_Sein - 001_Nimetus: Välissein; 205_Tüüp: VS-CLT-16/8; 325_Helipidavus: 40 dB; 330_Tulekindlus: REI 60; 335_Välispiire: yes; 340_Soojusläbivus: 0.13; 376_Viimistlus_väljast: Telje poolne pind: PUITLAUDIS- hõbehall peits V ; Telje vastaspoolne pind: TOON- vastavalt SA osale; 505_Paksus: 524 mm; 500_Kandev: TRUE; 376_Viimistlus_väljast (MUDELIS): _VÄLISVIIMISTLUS - vertikaalne voodrilaud, Platowood P01 profiil 18x140mm, kuusk; eeltöödeldud tuletõkkega mõlemad küljed, B-s1, d0, Woodsafe Exterior WFX™ või samaväärne; _KARKASS - puitroov 32x50mm horisontaalne, immutatud Driconi tulekaitsevahendiga või samaväärne, samm 600mm; _KARKASS - puitroov 32x50mm vertikaalne, immutatud Driconi tulekaitsevahendiga või samaväärne, samm 600mm; _TUULETÕKE - tuuletõkkeplaat, soojuserijuhtivus λD<0,031 W/(mK), ISOVER RKL FACADE või samaväärne, liitekohad katta tihendusteibiga ISOVER FacadeTape või samaväärne; _SOOJUSTUS - mineraalvill, λD<0,032 W/(mK), kuumtsingitud lehtteras termoroovidega, S350GD+Zn275 vastavalt EN10346, ISOVER EXTREME 32 200mm või samaväärne; _KANDETARIND - CLT ristkihtliimpuit vastavalt EK osale, CLT paigaldusvuugid teibitakse ROTHOBLAAS teibiga; _SOOJUSTUS - akustiline vill Ecophon Industry must TAL PE 50mm või samaväärne; _VIIMISTLUSKIHT - must akustiline fliis vastavalt SA osale; _VIIMISTLUSKIHT - viimistlus vastavalt SA osale
AC_Pset_RenovationAndPhasing - Renovation Status: New
Name | In | 605_Neto_pindala (m2) = 600_Bruto_pindala (m2)
Välissein | 2. korrus | 6.42601
Välissein | 3. korrus | 13.4708

# IfcWall: VS-CLT-16/9_18vineer+karkass 32+CLT160+soojust 200 522 (2)
Classification: 1.24 IfcWallType (sein) (RKAS BIM + ARCHICAD Classification)
Pset_WallCommon - Reference: VS-CLT-16/9; LoadBearing: yes; IsExternal: yes
AR_Sein - 001_Nimetus: Välissein; 205_Tüüp: VS-CLT-16/9; 330_Tulekindlus: REI 60; 335_Välispiire: yes; 376_Viimistlus_väljast: Telje poolne pind: PUITLAUDIS- hõbehall peits V ; Telje vastaspoolne pind: TOON- vastavalt SA osale; 505_Paksus: 522 mm; 500_Kandev: TRUE; 376_Viimistlus_väljast (MUDELIS): _VÄLISVIIMISTLUS - vertikaalne voodrilaud, Platowood P01 profiil 18x140mm, kuusk; eeltöödeldud tuletõkkega mõlemad küljed, B-s1, d0, Woodsafe Exterior WFX™ või samaväärne; _KARKASS - puitroov 32x50mm horisontaalne, immutatud Driconi tulekaitsevahendiga või samaväärne, samm 600mm; _KARKASS - puitroov 32x50mm vertikaalne, immutatud Driconi tulekaitsevahendiga või samaväärne, samm 600mm; _TUULETÕKE - tuuletõkkeplaat, soojuserijuhtivus λD<0,031 W/(mK), ISOVER RKL FACADE või samaväärne, liitekohad katta tihendusteibiga ISOVER FacadeTape või samaväärne; _SOOJUSTUS - mineraalvill, λD<0,032 W/(mK), kuumtsingitud lehtteras termoroovidega, S350GD+Zn275 vastavalt EN10346, ISOVER EXTREME 32 200mm või samaväärne; _KANDETARIND - CLT ristkihtliimpuit vastavalt EK osale, CLT paigaldusvuugid teibitakse ROTHOBLAAS teibiga; _KARKASS - puitroov 32x32mm, s. 600mm; _PLAATMATERJAL - niiskuskindel vineerplaat, kvaliteediklass BB; _VIIMISTLUSKIHT - viimistlus vastavalt SA osale
AC_Pset_RenovationAndPhasing - Renovation Status: New
Name | In | 325_Helipidavus | 340_Soojusläbivus | 605_Neto_pindala (m2) | 600_Bruto_pindala (m2)
Välissein | 1. korrus | 34 dB | 0.12 | 6.48796 | 26.3025
Välissein | 2. korrus | 40 dB | 0.13 | 14.076 | 14.076

# IfcWall: VS-CLT-20/1 512 (9)
Classification: 1.24 IfcWallType (sein) (RKAS BIM + ARCHICAD Classification)
Pset_WallCommon - Reference: VS-CLT-20/1; LoadBearing: yes; IsExternal: yes
AR_Sein - 001_Nimetus: Välissein; 205_Tüüp: VS-CLT-20/1; 325_Helipidavus: 34 dB; 330_Tulekindlus: REI 60; 335_Välispiire: yes; 376_Viimistlus_väljast: Telje poolne pind: PUITLAUDIS- hõbehall peits V ; Telje vastaspoolne pind: TOON- vastavalt SA osale; 505_Paksus: 512 mm; 500_Kandev: TRUE; 376_Viimistlus_väljast (MUDELIS): _VÄLISVIIMISTLUS - vertikaalne voodrilaud, Platowood P01 profiil 18x140mm, kuusk; eeltöödeldud tuletõkkega mõlemad küljed, B-s1, d0, Woodsafe Exterior WFX™ või samaväärne; _KARKASS - puitroov 32x50mm horisontaalne, immutatud Driconi tulekaitsevahendiga või samaväärne, samm 600mm; _KARKASS - puitroov 32x50mm vertikaalne, immutatud Driconi tulekaitsevahendiga või samaväärne, samm 600mm; _TUULETÕKE - tuuletõkkeplaat, soojuserijuhtivus λD<0,031 W/(mK), ISOVER RKL FACADE või samaväärne, liitekohad katta tihendusteibiga ISOVER FacadeTape või samaväärne; _SOOJUSTUS - mineraalvill, λD<0,032 W/(mK), kuumtsingitud lehtteras termoroovidega, S350GD+Zn275 vastavalt EN10346, ISOVER EXTREME 32 200mm või samaväärne; _KANDETARIND - CLT ristkihtliimpuit vastavalt EK osale, CLT paigaldusvuugid teibitakse ROTHOBLAAS teibiga; _VIIMISTLUSKIHT - viimistlus vastavalt SA osale
AC_Pset_RenovationAndPhasing - Renovation Status: New
Name | In | 340_Soojusläbivus | 605_Neto_pindala (m2) | 600_Bruto_pindala (m2)
Välissein | 1. korrus | 0.12 | 34.8375 | 34.8375
Välissein | 1. korrus | 0.14 | 80.1257 | 107.161
Välissein | 1. korrus | 0.13 | 13.1341 | 29.9345
Välissein | 1. korrus | 0.12 | 30.2871 | 44.8471
Välissein | 1. korrus | 0.12 | 34.7454 | 35.6036
Välissein | 1. korrus | 0.12 | 37.2381 | 58.3395
Välissein | 1. korrus | 0.14 | 74.6475 | 112.973
Välissein | 2. korrus | 0.12 | 16.6777 | 30.9562
Välissein | 2. korrus | 0.12 | 7.52814 | 7.52814

# IfcWall: VS-CLT-20/2_A ploki välissein 642, Välissein
In: 1. korrus
Classification: 1.24 IfcWallType (sein) (RKAS BIM + ARCHICAD Classification)
Pset_WallCommon - Reference: VS-CLT-20/2; LoadBearing: yes; IsExternal: yes
AR_Sein - 001_Nimetus: Välissein; 205_Tüüp: VS-CLT-20/2; 325_Helipidavus: 40 dB; 330_Tulekindlus: REI 60; 335_Välispiire: yes; 340_Soojusläbivus: 0.12; 376_Viimistlus_väljast: Telje poolne pind: PUITLAUDIS- hõbehall peits V ; Telje vastaspoolne pind: PUIT- Woodex 1820; 505_Paksus: 642 mm; 605_Neto_pindala: 88.8121 m2; 600_Bruto_pindala: 129.763 m2; 500_Kandev: TRUE; 376_Viimistlus_väljast (MUDELIS): _VÄLISVIIMISTLUS - vertikaalne voodrilaud, Platowood P01 profiil 18x140mm, kuusk; eeltöödeldud tuletõkkega mõlemad küljed, B-s1, d0, Woodsafe Exterior WFX™ või samaväärne; _KARKASS - puitroov 32x50mm horisontaalne, immutatud Driconi tulekaitsevahendiga või samaväärne, samm 600mm; _KARKASS - puitroov 32x50mm vertikaalne, immutatud Driconi tulekaitsevahendiga või samaväärne, samm 600mm; _TUULETÕKE - tuuletõkkeplaat, soojuserijuhtivus λD<0,031 W/(mK), ISOVER RKL FACADE või samaväärne, liitekohad katta tihendusteibiga ISOVER FacadeTape või samaväärne; _SOOJUSTUS - mineraalvill, λD<0,032 W/(mK), kuumtsingitud lehtteras termoroovidega, S350GD+Zn275 vastavalt EN10346, ISOVER EXTREME 32 200mm või samaväärne; _KANDETARIND - CLT ristkihtliimpuit vastavalt EK osale, CLT paigaldusvuugid teibitakse ROTHOBLAAS teibiga; _KARKASS - metallkarkass CW 50/50/06 ja UW 75/40/06, samm 600, 50x50mm postid eraldiseisvalt vaheldumisi, kogupaksus 75mm, vahel mineraalvill, helineeldetegur αw = 0.85, ISOVER ACOUSTIC 50mm või samaväärne; _PLAATMATERJAL - kipsplaat vastavalt ruumi nõuetele 12,5mm; _PLAATMATERJAL - kipsplaat vastavalt ruumi nõuetele 12,5mm; _KARKASS - eriprofiilkinnitus vastavalt sisemisele plaatviimistlusele; _VIIMISTLUSKIHT - Dold plaat vastavalt SA osale
AC_Pset_RenovationAndPhasing - Renovation Status: New

# IfcWall: VS-CLT-20/3_sokkel 433 (6)
In: Vundament
Classification: 1.24 IfcWallType (sein) (RKAS BIM + ARCHICAD Classification)
Pset_WallCommon - Reference: VS-CLT-20/3; LoadBearing: yes; IsExternal: yes
AR_Sein - 001_Nimetus: Sokkel; 205_Tüüp: VS-CLT-20/3; 325_Helipidavus: nõudeid ei esitata; 335_Välispiire: yes; 376_Viimistlus_väljast: Telje poolne pind: KROHV- Weber pas.481 AquaBalance, toon helehall CL444 (S 3502-Y) * 35; Telje vastaspoolne pind: PUIT- kuusk V; 505_Paksus: 433 mm; 500_Kandev: TRUE; 376_Viimistlus_väljast (MUDELIS): _TUULETÕKE - sokli krohv, silikoonvaikkrohv Weber.pas 481 AquaBalance 1mm "scratch" viimistlus, toon helehall CL444 (S 3502-Y) * 35, SILS süsteem, või samaväärne; _SOOJUSTUS - vahtpolüstüreenplaadid EPS 120 Perimeeter, survetugevus min 120kPa, veeimavus <2%, soojuserijuhtivus λD<0,036 W/(mK); _SOOJUSTUS - ekstrudeeritud polüstüreenist plaadid XPS 250, survetugevus min 250kPa, soojuserijuhtivus λD<0,036 W/(mK), veeimavus alla 0,2%, näiteks XPS 250 foam SL või samaväärne; _HÜDROISOLATSIOON - 3x SBS rullmaterjal vastavalt TL2 nõuetele, nakke tugevduseks betoonpind eelnevalt katta hüdroisolatsiooni bituumenvõõbaga; _KANDETARIND - CLT ristkihtliimpuit vastavalt EK osale, CLT paigaldusvuugid teibitakse ROTHOBLAAS teibiga
AC_Pset_RenovationAndPhasing - Renovation Status: New
Name | 330_Tulekindlus | 340_Soojusläbivus | 605_Neto_pindala (m2) | 600_Bruto_pindala (m2)
Sokkel | REI 60 | 0.12 | 0.945957 | 0.947157
Sokkel | REI 60 | 0.14 | 2.8812 | 2.93316
Sokkel | REI 60 | 0.12 | 1.55004 | 1.5972
Sokkel | REI 60 | 0.14 | 3.09156 | 3.09276
Sokkel | REI 60 | 0.12 | 1.18277 | 1.22993
Sokkel | nõudeid ei esitata | 0.12 | 0.149242 | 0.15786

# IfcWall: VS-CLT-20/4_sokkel A plokk 563, Sokkel
In: Vundament
Classification: 1.24 IfcWallType (sein) (RKAS BIM + ARCHICAD Classification)
Pset_WallCommon - Reference: VS-CLT-20/4; LoadBearing: yes; IsExternal: yes
AR_Sein - 001_Nimetus: Sokkel; 205_Tüüp: VS-CLT-20/4; 325_Helipidavus: nõudeid ei esitata; 330_Tulekindlus: REI 60; 335_Välispiire: yes; 340_Soojusläbivus: 0.12; 376_Viimistlus_väljast: Telje poolne pind: KROHV- Weber pas.481 AquaBalance, toon helehall CL444 (S 3502-Y) * 35; Telje vastaspoolne pind: PUIT- Woodex 1820; 505_Paksus: 563 mm; 605_Neto_pindala: 3.52102 m2; 600_Bruto_pindala: 3.52102 m2; 500_Kandev: TRUE; 376_Viimistlus_väljast (MUDELIS): _TUULETÕKE - sokli krohv, silikoonvaikkrohv Weber.pas 481 AquaBalance 1mm "scratch" viimistlus, toon helehall CL444 (S 3502-Y) * 35, SILS süsteem, või samaväärne; _SOOJUSTUS - vahtpolüstüreenplaadid EPS 120 Perimeeter, survetugevus min 120kPa, veeimavus <2%, soojuserijuhtivus λD<0,036 W/(mK); _SOOJUSTUS - ekstrudeeritud polüstüreenist plaadid XPS 250, survetugevus min 250kPa, soojuserijuhtivus λD<0,036 W/(mK), veeimavus alla 0,2%, näiteks XPS 250 foam SL või samaväärne; _HÜDROISOLATSIOON - 3x SBS rullmaterjal vastavalt TL2 nõuetele, nakke tugevduseks betoonpind eelnevalt katta hüdroisolatsiooni bituumenvõõbaga; _KANDETARIND - CLT ristkihtliimpuit vastavalt EK osale, CLT paigaldusvuugid teibitakse ROTHOBLAAS teibiga; _KARKASS - metallkarkass CW 50/50/06 ja UW 75/40/06, samm 600, 50x50mm postid eraldiseisvalt vaheldumisi, kogupaksus 75mm, vahel mineraalvill, helineeldetegur αw = 0.85, ISOVER ACOUSTIC 50mm või samaväärne; _PLAATMATERJAL - erikõva kipsplaat, kinnitamiseks kasutada erikõvale plaadile sobivaid kruve nt XTB 3,9x55mm, Knauf Blue (Diamant) või samaväärne; _PLAATMATERJAL - erikõva kipsplaat, kinnitamiseks kasutada erikõvale plaadile sobivaid kruve nt XTB 3,9x55mm, Knauf Blue (Diamant) või samaväärne; _KARKASS - eriprofiilkinnitus vastavalt sisemisele plaatviimistlusele; _VIIMISTLUSKIHT - Dold plaat vastavalt SA osale
AC_Pset_RenovationAndPhasing - Renovation Status: New

# IfcWall: VS-MK-20/1_A ploki ruum 302 667 (2)
In: 3. korrus
Classification: 1.24 IfcWallType (sein) (RKAS BIM + ARCHICAD Classification)
Pset_WallCommon - Reference: VS-MK-20/1; LoadBearing: yes; IsExternal: yes
AR_Sein - 001_Nimetus: Välissein; 205_Tüüp: VS-MK-20/1; 330_Tulekindlus: REI 60; 335_Välispiire: yes; 340_Soojusläbivus: 0.13; 376_Viimistlus_väljast: Telje poolne pind: PUITLAUDIS- hõbehall peits V ; Telje vastaspoolne pind: TOON- vastavalt SA osale; 505_Paksus: 667 mm; 500_Kandev: TRUE; 376_Viimistlus_väljast (MUDELIS): _VÄLISVIIMISTLUS - vertikaalne voodrilaud, Platowood P01 profiil 18x140mm, kuusk; eeltöödeldud tuletõkkega mõlemad küljed, B-s1, d0, Woodsafe Exterior WFX™ või samaväärne; _KARKASS - puitroov 32x50mm horisontaalne, immutatud Driconi tulekaitsevahendiga või samaväärne, samm 600mm; _KARKASS - puitroov 32x50mm vertikaalne, immutatud Driconi tulekaitsevahendiga või samaväärne, samm 600mm; _TUULETÕKE - tuuletõkkeplaat, soojuserijuhtivus λD<0,031 W/(mK), ISOVER RKL FACADE või samaväärne, liitekohad katta tihendusteibiga ISOVER FacadeTape või samaväärne; _SOOJUSTUS - mineraalvill, λD<0,032 W/(mK), kuumtsingitud lehtteras termoroovidega, S350GD+Zn275 vastavalt EN10346, ISOVER EXTREME 32 200mm või samaväärne; _KARKASS - teraskarkass vastavalt EK osale, vahel mineraalvillaplaat soojuserijuhtivus λD<0,035 W/(mK), kuumtsingitud lehtterasest termoroovidega, S350GD+Zn275 vastavalt EN10346, ISOVER OL-E 35 või samaväärne; _KARKASS - metallkarkass VP 120/40; _PLAATMATERJAL - OSB3 plaat; _PLAATMATERJAL - tuletõkkekipsplaat, Knauf Red GKF või samaväärne; _PLAATMATERJAL - tuletõkkekipsplaat, Knauf Red GKF või samaväärne; _VIIMISTLUSKIHT - viimistlus vastavalt SA osale
AC_Pset_RenovationAndPhasing - Renovation Status: New
Name | 325_Helipidavus | 605_Neto_pindala (m2) | 600_Bruto_pindala (m2)
Välissein | 34 dB | 32.3714 | 32.4428
Välissein | 35dB | 23.638 | 39.358

# IfcWall: VS-PK-19/1_dold+soojust 195+PVC-katuseakende sein 325 (4)
In: 3. korrus
Classification: 1.24 IfcWallType (sein) (RKAS BIM + ARCHICAD Classification)
Pset_WallCommon - Reference: VS-PK-19/1; LoadBearing: yes; IsExternal: yes
AR_Sein - 001_Nimetus: Välissein; 205_Tüüp: VS-PK-19/1; 325_Helipidavus: 35dB; 330_Tulekindlus: REI 60; 335_Välispiire: yes; 340_Soojusläbivus: 0.16; 376_Viimistlus_väljast: Telje poolne pind: TOON- helehall RR21; Telje vastaspoolne pind: TOON- vastavalt SA osale; 505_Paksus: 325 mm; 500_Kandev: TRUE; 376_Viimistlus_väljast (MUDELIS): _HÜDROISOLATSIOON - katusekate PVC rullmaterjal, vastavalt RIL 107-2012-le, helehall F91, Protan SE või samaväärne; _ERALDUSKIHT - siirdetõke, min 140g/m2, Fibertex F2B 140g/m2 või samaväärne; _PLAATMATERJAL - veekindla pinnaga niiskuskindel kuusevineer vastavalt EN 314 klass 3, BS 1203/H4, DIN 68705 osa 3 tüüp BFU nõuetele, lõikeserv ja õhuga kokkupuutuv pind kaitsta puidukaitsevahendiga, nt 2x Pinotex Impra; _KARKASS - puitroov 32x50mm vertikaalne, immutatud Driconi tulekaitsevahendiga või samaväärne, samm 600mm; _TUULETÕKE - tuuletõkkeplaat, soojuserijuhtivus λD<0,031 W/(mK), ISOVER RKL FACADE või samaväärne, liitekohad katta tihendusteibiga ISOVER FacadeTape või samaväärne; _KARKASS - puitpruss 195x45mm sammuga 600mm vastavalt EK osale, vahel SOOJUSTUS - mineraalvill, soojuserijuhtivus λD<0,032 W/(mK), ISOVER EXTREME 32 200mm või samaväärne; _AURUTÕKE - aurutõkkekile, vuugid ülekattega teibitud, veeaurutakistus Sd 0,3 kuni 25m, ISOVER Vario auru- ja õhutõkkesüsteem (Vario Xtra aurutõkkekile, Vario MultiTape SL, Vario DF) või samaväärne; _KARKASS - mütsprofiil MP-27, kuumtsingitud teras; _VIIMISTLUSKIHT - viimistlus vastavalt SA osale
AC_Pset_RenovationAndPhasing - Renovation Status: New
Name | 605_Neto_pindala (m2) | 600_Bruto_pindala (m2)
Välissein | 2.62557 | 5.63438
Välissein | 2.59975 | 5.43316
Välissein | 2.54774 | 7.16381
Välissein | 2.54798 | 5.88568

# IfcWall: VS-PK-19/2_soojustamata+fassaadiplaat- õhuvõtukambri sein 300, Välissein
In: 4. TEHNO korrus
Classification: 1.24 IfcWallType (sein) (RKAS BIM + ARCHICAD Classification)
Pset_WallCommon - Reference: VS-PK-19/2; LoadBearing: yes; IsExternal: yes
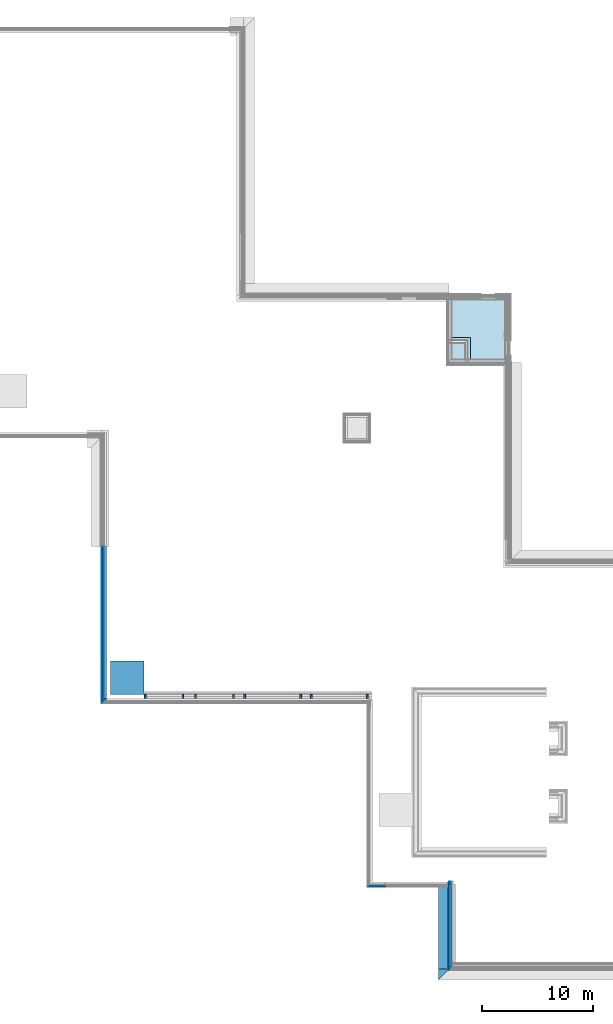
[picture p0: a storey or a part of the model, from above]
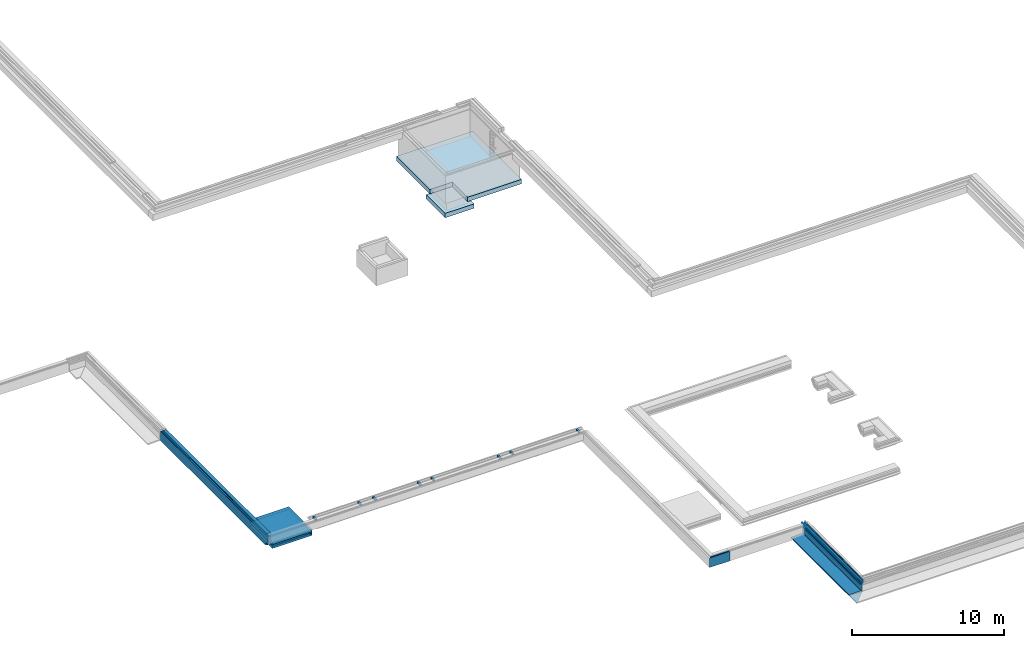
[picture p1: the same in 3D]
Properties of the parts of a building model (IFC2X3), part 13 of 14

# IfcWall: VS-PK-19/2_soojustamata+fassaadiplaat- õhuvõtukambri sein 300, Välissein
AR_Sein - 001_Nimetus: Välissein; 205_Tüüp: VS-PK-19/2; 325_Helipidavus: 35dB; 330_Tulekindlus: nõudeid ei esitata; 335_Välispiire: yes; 340_Soojusläbivus: 0.16; 376_Viimistlus_väljast: Telje poolne pind: TOON- helehall RR21; Telje vastaspoolne pind: TOON- helehall RR21; 505_Paksus: 300 mm; 605_Neto_pindala: 37.3854 m2; 600_Bruto_pindala: 58.0707 m2; 500_Kandev: TRUE; 376_Viimistlus_väljast (MUDELIS): _VÄLISVIIMISTLUS - kiudtsemendist fassaadikatteplaat, tuletundlikkus A2-s1, d0, Cembrit Cover toon hall C 020 või samaväärne; _KARKASS - puitroov 50x50mm vertikaalne, sügavimmutatud, samm 600mm; _KARKASS - puitroov 32x50mm horisontaalne, immutatud Driconi tulekaitsevahendiga või samaväärne, samm 600mm; _KARKASS - teraskarkass, C-profiilid, samm 600mm, kuumtsingitud lehtteras 2mm, S350GD+Zn275 vastavalt EN10346, keskkonnaklass C3; _KARKASS - puitroov 32x50mm horisontaalne, immutatud Driconi tulekaitsevahendiga või samaväärne, samm 600mm; _KARKASS - puitroov 50x50mm vertikaalne, sügavimmutatud, samm 600mm; _VÄLISVIIMISTLUS - kiudtsemendist fassaadikatteplaat, tuletundlikkus A2-s1, d0, Cembrit Cover toon hall C 020 või samaväärne
AC_Pset_RenovationAndPhasing - Renovation Status: New

# IfcWall: VS-PK-19/3_soojust 195+fassaadiplaat- tehnoruumi sein 350, Välissein
In: 4. TEHNO korrus
Classification: 1.24 IfcWallType (sein) (RKAS BIM + ARCHICAD Classification)
Pset_WallCommon - Reference: VS-PK-19/3; LoadBearing: yes; IsExternal: yes
AR_Sein - 001_Nimetus: Välissein; 205_Tüüp: VS-PK-19/3; 325_Helipidavus: 35dB; 330_Tulekindlus: REI 60; 335_Välispiire: yes; 340_Soojusläbivus: 0.16; 376_Viimistlus_väljast: Telje poolne pind: TOON- helehall RR21; Telje vastaspoolne pind: TOON- vastavalt SA osale; 505_Paksus: 350 mm; 605_Neto_pindala: 51.2241 m2; 600_Bruto_pindala: 59.3619 m2; 500_Kandev: TRUE; 376_Viimistlus_väljast (MUDELIS): _VÄLISVIIMISTLUS - kiudtsemendist fassaadikatteplaat, tuletundlikkus A2-s1, d0, Cembrit Cover toon hall C 020 või samaväärne; _KARKASS - puitroov 50x50mm vertikaalne, sügavimmutatud, samm 600mm; _TUULETÕKE - tuuletõkkeplaat, soojuserijuhtivus λD<0,031 W/(mK), ISOVER RKL FACADE või samaväärne, liitekohad katta tihendusteibiga ISOVER FacadeTape või samaväärne; _KARKASS - puitpruss 195x45mm sammuga 600mm vastavalt EK osale, vahel SOOJUSTUS - mineraalvill, soojuserijuhtivus λD<0,032 W/(mK), ISOVER EXTREME 32 200mm või samaväärne; _AURUTÕKE - aurutõkkekile, vuugid ülekattega teibitud, veeaurutakistus Sd 0,3 kuni 25m, ISOVER Vario auru- ja õhutõkkesüsteem (Vario Xtra aurutõkkekile, Vario MultiTape SL, Vario DF) või samaväärne; _KARKASS - mütsprofiil MP-27, kuumtsingitud teras; _PLAATMATERJAL - tuletõkkekipsplaat, Knauf Red GKF või samaväärne; _PLAATMATERJAL - tuletõkkekipsplaat, Knauf Red GKF või samaväärne; _VIIMISTLUSKIHT - viimistlus vastavalt SA osale
AC_Pset_RenovationAndPhasing - Renovation Status: New

# IfcWall: VS-PK-19/4_soojust 195+ tehnošahti sein 292, Välissein
In: 4. TEHNO korrus
Classification: 1.24 IfcWallType (sein) (RKAS BIM + ARCHICAD Classification)
Pset_WallCommon - Reference: VS-PK-19/4; LoadBearing: yes; IsExternal: yes
AR_Sein - 001_Nimetus: Välissein; 205_Tüüp: VS-PK-19/4; 325_Helipidavus: 35dB; 330_Tulekindlus: REI 60; 335_Välispiire: yes; 340_Soojusläbivus: 0.16; 376_Viimistlus_väljast: Telje poolne pind: TOON- hall, poolläikiv; Telje vastaspoolne pind: TOON- vastavalt SA osale; 505_Paksus: 292 mm; 605_Neto_pindala: 14.5425 m2; 600_Bruto_pindala: 17.2444 m2; 500_Kandev: TRUE; 376_Viimistlus_väljast (MUDELIS): _TUULETÕKE - tuuletõkkeplaat, soojuserijuhtivus λD<0,031 W/(mK), ISOVER RKL FACADE või samaväärne, liitekohad katta tihendusteibiga ISOVER FacadeTape või samaväärne; _KARKASS - puitpruss 195x45mm sammuga 600mm vastavalt EK osale, vahel SOOJUSTUS - mineraalvill, soojuserijuhtivus λD<0,032 W/(mK), ISOVER EXTREME 32 200mm või samaväärne; _AURUTÕKE - aurutõkkekile, vuugid ülekattega teibitud, veeaurutakistus Sd 0,3 kuni 25m, ISOVER Vario auru- ja õhutõkkesüsteem (Vario Xtra aurutõkkekile, Vario MultiTape SL, Vario DF) või samaväärne; _KARKASS - mütsprofiil MP-27, kuumtsingitud teras; _PLAATMATERJAL - tuletõkkekipsplaat, Knauf Red GKF või samaväärne; _PLAATMATERJAL - tuletõkkekipsplaat, Knauf Red GKF või samaväärne; _VIIMISTLUSKIHT - viimistlus vastavalt SA osale
AC_Pset_RenovationAndPhasing - Renovation Status: New

# IfcWall: VS-PK-19/5_soojust 195+PVC -tulekindla katuseakna sein 345 (3)
In: 4. TEHNO korrus
Classification: 1.24 IfcWallType (sein) (RKAS BIM + ARCHICAD Classification)
Pset_WallCommon - Reference: VS-PK-19/5; LoadBearing: yes; IsExternal: yes
AR_Sein - 001_Nimetus: Välissein; 205_Tüüp: VS-PK-19/5; 325_Helipidavus: 35dB; 330_Tulekindlus: REI 60; 335_Välispiire: yes; 340_Soojusläbivus: 0.16; 376_Viimistlus_väljast: Telje poolne pind: TOON- helehall RR21; Telje vastaspoolne pind: TOON- vastavalt SA osale; 505_Paksus: 345 mm; 500_Kandev: TRUE; 376_Viimistlus_väljast (MUDELIS): _HÜDROISOLATSIOON - katusekate PVC rullmaterjal, vastavalt RIL 107-2012-le, helehall F91, Protan SE või samaväärne; _ERALDUSKIHT - siirdetõke, min 140g/m2, Fibertex F2B 140g/m2 või samaväärne; _PLAATMATERJAL - veekindla pinnaga niiskuskindel kuusevineer vastavalt EN 314 klass 3, BS 1203/H4, DIN 68705 osa 3 tüüp BFU nõuetele, lõikeserv ja õhuga kokkupuutuv pind kaitsta puidukaitsevahendiga, nt 2x Pinotex Impra; _KARKASS - puitroov 32x50mm vertikaalne, immutatud Driconi tulekaitsevahendiga või samaväärne, samm 600mm; _TUULETÕKE - tuuletõkkeplaat, soojuserijuhtivus λD<0,031 W/(mK), ISOVER RKL FACADE või samaväärne, liitekohad katta tihendusteibiga ISOVER FacadeTape või samaväärne; _KARKASS - puitpruss 195x45mm sammuga 600mm vastavalt EK osale, vahel SOOJUSTUS - mineraalvill, soojuserijuhtivus λD<0,032 W/(mK), ISOVER EXTREME 32 200mm või samaväärne; _AURUTÕKE - aurutõkkekile, vuugid ülekattega teibitud, veeaurutakistus Sd 0,3 kuni 25m, ISOVER Vario auru- ja õhutõkkesüsteem (Vario Xtra aurutõkkekile, Vario MultiTape SL, Vario DF) või samaväärne; _KARKASS - mütsprofiil MP-27, kuumtsingitud teras; _PLAATMATERJAL - tuletõkkekipsplaat, Knauf Red GKF või samaväärne; _PLAATMATERJAL - tuletõkkekipsplaat, Knauf Red GKF või samaväärne; _VIIMISTLUSKIHT - viimistlus vastavalt SA osale
AC_Pset_RenovationAndPhasing - Renovation Status: New
Name | 605_Neto_pindala (m2) | 600_Bruto_pindala (m2)
Välissein | 7.92481 | 15.9879
Välissein | 8.77361 | 19.4697
Välissein | 5.63881 | 16.0598

# IfcWall: VS-PK-19/6_soojust 200+laudis tehnokorrus 574, Välissein
In: 4. TEHNO korrus
Classification: 1.24 IfcWallType (sein) (RKAS BIM + ARCHICAD Classification)
Pset_WallCommon - Reference: VS-PK-19/6; LoadBearing: no; IsExternal: yes
AR_Sein - 001_Nimetus: Välissein; 205_Tüüp: VS-PK-19/6; 325_Helipidavus: 35 dB; 330_Tulekindlus: nõudeid ei esitata; 335_Välispiire: yes; 340_Soojusläbivus: 0.13; 376_Viimistlus_väljast: Telje poolne pind: PUITLAUDIS- hõbehall peits V ; Telje vastaspoolne pind: TOON- vastavalt SA osale; 505_Paksus: 574 mm; 605_Neto_pindala: 38.4403 m2; 600_Bruto_pindala: 47.1871 m2; 500_Kandev: FALSE; 376_Viimistlus_väljast (MUDELIS): _VÄLISVIIMISTLUS - vertikaalne voodrilaud, Platowood P01 profiil 18x140mm, kuusk; eeltöödeldud tuletõkkega mõlemad küljed, B-s1, d0, Woodsafe Exterior WFX™ või samaväärne; _KARKASS - puitroov 32x50mm horisontaalne, immutatud Driconi tulekaitsevahendiga või samaväärne, samm 600mm; _KARKASS - puitroov 32x50mm vertikaalne, immutatud Driconi tulekaitsevahendiga või samaväärne, samm 600mm; _TUULETÕKE - tuuletõkkeplaat, soojuserijuhtivus λD<0,031 W/(mK), ISOVER RKL FACADE või samaväärne, liitekohad katta tihendusteibiga ISOVER FacadeTape või samaväärne; _SOOJUSTUS - mineraalvill, λD<0,032 W/(mK), kuumtsingitud lehtteras termoroovidega, S350GD+Zn275 vastavalt EN10346, ISOVER EXTREME 32 200mm või samaväärne; _KARKASS - puitpruss 195x45mm sammuga 600mm vastavalt EK osale, vahel SOOJUSTUS - mineraalvill, soojuserijuhtivus λD<0,032 W/(mK), ISOVER EXTREME 32 200mm või samaväärne; _AURUTÕKE - aurutõkkekile, vuugid ülekattega teibitud, veeaurutakistus Sd 0,3 kuni 25m, ISOVER Vario auru- ja õhutõkkesüsteem (Vario Xtra aurutõkkekile, Vario MultiTape SL, Vario DF) või samaväärne; _KARKASS - mütsprofiil MP-27, kuumtsingitud teras; _PLAATMATERJAL - tuletõkkekipsplaat, Knauf Red GKF või samaväärne; _PLAATMATERJAL - tuletõkkekipsplaat, Knauf Red GKF või samaväärne; _VIIMISTLUSKIHT - viimistlus vastavalt SA osale
AC_Pset_RenovationAndPhasing - Renovation Status: New

# IfcWall: VS-PK-19/7_akustilinevill+soojust 195+PVC-katuseakende sein 328 (10)
Classification: 1.24 IfcWallType (sein) (RKAS BIM + ARCHICAD Classification)
Pset_WallCommon - Reference: VS-PK-19/7
AR_Sein - 001_Nimetus: Välissein; 205_Tüüp: VS-PK-19/7; 325_Helipidavus: 35 dB; 330_Tulekindlus: REI 60; 340_Soojusläbivus: 0.16; 376_Viimistlus_väljast: Telje poolne pind: TOON- helehall RR21; Telje vastaspoolne pind: TOON- vastavalt SA osale; 505_Paksus: 328.1 mm; 376_Viimistlus_väljast (MUDELIS): _HÜDROISOLATSIOON - katusekate PVC rullmaterjal, vastavalt RIL 107-2012-le, helehall F91, Protan SE või samaväärne; _ERALDUSKIHT - siirdetõke, min 140g/m2, Fibertex F2B 140g/m2 või samaväärne; _PLAATMATERJAL - veekindla pinnaga niiskuskindel kuusevineer vastavalt EN 314 klass 3, BS 1203/H4, DIN 68705 osa 3 tüüp BFU nõuetele, lõikeserv ja õhuga kokkupuutuv pind kaitsta puidukaitsevahendiga, nt 2x Pinotex Impra; _KARKASS - puitroov 32x50mm vertikaalne, immutatud Driconi tulekaitsevahendiga või samaväärne, samm 600mm; _TUULETÕKE - tuuletõkkeplaat, soojuserijuhtivus λD<0,031 W/(mK), ISOVER RKL FACADE või samaväärne, liitekohad katta tihendusteibiga ISOVER FacadeTape või samaväärne; _KARKASS - puitpruss 195x45mm sammuga 600mm vastavalt EK osale, vahel SOOJUSTUS - mineraalvill, soojuserijuhtivus λD<0,032 W/(mK), ISOVER EXTREME 32 200mm või samaväärne; _AURUTÕKE - aurutõkkekile, vuugid ülekattega teibitud, veeaurutakistus Sd0,3 kuni 25m, ISOVER Vario auru- ja õhutõkkesüsteem (Vario Xtra aurutõkkekile, Vario MultiTape SL, Vario DF) või samaväärne; _SOOJUSTUS - akustiline vill Ecophon Industry must TAL PE 50mm või samaväärne; _VIIMISTLUSKIHT - viimistlus vastavalt SA osale
AC_Pset_RenovationAndPhasing - Renovation Status: New
Name | In | LoadBearing = IsExternal = 335_Välispiire | 605_Neto_pindala (m2) | 600_Bruto_pindala (m2) | 500_Kandev
Välissein | 3. korrus | yes | 6.27847 | 10.012 | TRUE
Välissein | 3. korrus | yes | 5.10763 | 11.833 | TRUE
Välissein | 3. korrus | yes | 9.91506 | 15.0538 | TRUE
Välissein | 4. TEHNO korrus | no | 4.59507 | 16.3239 | FALSE
Välissein | 4. TEHNO korrus | no | 13.9565 | 25.5909 | FALSE
Välissein | 4. TEHNO korrus | no | 4.61673 | 16.3239 | FALSE
Välissein | 4. TEHNO korrus | no | 4.97718 | 26.8305 | FALSE
Välissein | 4. TEHNO korrus | yes | 3.95777 | 14.5379 | TRUE
Välissein | 4. TEHNO korrus | yes | 8.10572 | 20.7607 | TRUE
Välissein | 4. TEHNO korrus | yes | 3.96591 | 13.8451 | TRUE

# IfcWall: VS-PK-19/8_soojust 195+fassaadiplaat- tehnoruumi sein tuulduv 377, Sisesein
In: 4. TEHNO korrus
Classification: 1.24 IfcWallType (sein) (RKAS BIM + ARCHICAD Classification)
Pset_WallCommon - Reference: VS-PK-19/8; LoadBearing: no; IsExternal: no
AR_Sein - 001_Nimetus: Sisesein; 205_Tüüp: VS-PK-19/8; 325_Helipidavus: 35 dB; 330_Tulekindlus: nõudeid ei esitata; 335_Välispiire: no; 340_Soojusläbivus: 0.16; 376_Viimistlus_väljast: Telje poolne pind: TOON- helehall RR21; Telje vastaspoolne pind: TOON- vastavalt SA osale; 505_Paksus: 377 mm; 605_Neto_pindala: 35.2458 m2; 600_Bruto_pindala: 61.2662 m2; 500_Kandev: FALSE; 376_Viimistlus_väljast (MUDELIS): _VÄLISVIIMISTLUS - kiudtsemendist fassaadikatteplaat, tuletundlikkus A2-s1, d0, Cembrit Cover toon hall C 020 või samaväärne; _KARKASS - puitroov 50x50mm horisontaalne, sügavimmutatud, samm 600mm; _KARKASS - puitroov 32x50mm vertikaalne, immutatud Driconi tulekaitsevahendiga või samaväärne, samm 600mm; _TUULETÕKE - tuuletõkkeplaat, soojuserijuhtivus λD<0,031 W/(mK), ISOVER RKL FACADE või samaväärne, liitekohad katta tihendusteibiga ISOVER FacadeTape või samaväärne; _KARKASS - puitpruss 195x45mm sammuga 600mm vastavalt EK osale, vahel SOOJUSTUS - mineraalvill, soojuserijuhtivus λD<0,032 W/(mK), ISOVER EXTREME 32 200mm või samaväärne; _AURUTÕKE - aurutõkkekile, vuugid ülekattega teibitud, veeaurutakistus Sd 0,3 kuni 25m, ISOVER Vario auru- ja õhutõkkesüsteem (Vario Xtra aurutõkkekile, Vario MultiTape SL, Vario DF) või samaväärne; _KARKASS - mütsprofiil MP-27, kuumtsingitud teras; _PLAATMATERJAL - tuletõkkekipsplaat, Knauf Red GKF või samaväärne; _PLAATMATERJAL - tuletõkkekipsplaat, Knauf Red GKF või samaväärne; _VIIMISTLUSKIHT - viimistlus vastavalt SA osale
AC_Pset_RenovationAndPhasing - Renovation Status: New

# IfcWall: VS-PK-20/1_kõrge parapett 365 (17)
Classification: 1.24 IfcWallType (sein) (RKAS BIM + ARCHICAD Classification)
Pset_WallCommon - Reference: VS-PK-20/1; LoadBearing: no; IsExternal: yes
AR_Sein - 001_Nimetus: Parapet; 205_Tüüp: VS-PK-20/1; 325_Helipidavus: nõudeid ei esitata; 330_Tulekindlus: nõudeid ei esitata; 335_Välispiire: yes; 340_Soojusläbivus: 0; 376_Viimistlus_väljast: Telje poolne pind: PUITLAUDIS- hõbehall peits V ; Telje vastaspoolne pind: TOON- helehall RR21; 505_Paksus: 365 mm; 500_Kandev: FALSE; 376_Viimistlus_väljast (MUDELIS): _VÄLISVIIMISTLUS - vertikaalne voodrilaud, Platowood P01 profiil 18x140mm, kuusk; eeltöödeldud tuletõkkega mõlemad küljed, B-s1, d0, Woodsafe Exterior WFX™ või samaväärne; _KARKASS - puitroov 32x50mm horisontaalne, immutatud Driconi tulekaitsevahendiga või samaväärne, samm 600mm; _KARKASS - puitroov 50x50mm vertikaalne, sügavimmutatud, samm 600mm; _PLAATMATERJAL - veekindla pinnaga niiskuskindel kuusevineer vastavalt EN 314 klass 3, BS 1203/H4, DIN 68705 osa 3 tüüp BFU nõuetele, lõikeserv ja õhuga kokkupuutuv pind kaitsta puidukaitsevahendiga, nt 2x Pinotex Impra; _KANDETARIND - puitkarkass vastavalt EK osale; _KARKASS - puitroov 32x50mm horisontaalne, immutatud Driconi tulekaitsevahendiga või samaväärne, samm 600mm; _PLAATMATERJAL - veekindla pinnaga niiskuskindel kuusevineer vastavalt EN 314 klass 3, BS 1203/H4, DIN 68705 osa 3 tüüp BFU nõuetele, lõikeserv ja õhuga kokkupuutuv pind kaitsta puidukaitsevahendiga, nt 2x Pinotex Impra; _ERALDUSKIHT - siirdetõke, min 140g/m2, Fibertex F2B 140g/m2 või samaväärne; _HÜDROISOLATSIOON - katusekate PVC rullmaterjal, vastavalt RIL 107-2012-le, helehall F91, Protan SE või samaväärne
AC_Pset_RenovationAndPhasing - Renovation Status: New
Name | In | 605_Neto_pindala (m2) | 600_Bruto_pindala (m2)
Parapet | 3. korrus | 9.55113 | 10.8318
Parapet | 3. korrus | 69.1321 | 70.6628
Parapet | 3. korrus | 68.5792 | 70.6507
Parapet | 3. korrus | 44.9483 | 45.0623
Parapet | 3. korrus | 24.2275 | 24.9674
Parapet | 3. korrus | 5.5003 | 5.84449
Parapet | 4. TEHNO korrus | 109.218 | 112.052
Parapet | 4. TEHNO korrus | 37.6417 | 41.8797
Parapet | 4. TEHNO korrus | 111.968 | 113.622
Parapet | 4. TEHNO korrus | 53.3132 | 57.3497
Parapet | 4. TEHNO korrus | 13.7778 | 13.7808
Parapet | 4. TEHNO korrus | 21.2486 | 29.5939
Parapet | 4. TEHNO korrus | 21.2486 | 29.6192
Parapet | 4. TEHNO korrus | 13.7703 | 19.2
Parapet | 4. TEHNO korrus | 38.4762 | 41.7729
Parapet | 4. TEHNO korrus | 42.1335 | 44.969
Parapet | 4. TEHNO korrus | 7.80418 | 9.39275

# IfcWall: VS-RB-16/1_mullakast 273 (12)
In: 1. korrus
Classification: 1.24 IfcWallType (sein) (RKAS BIM + ARCHICAD Classification)
Pset_WallCommon - Reference: VS-RB-16/1; LoadBearing: no; IsExternal: yes
AR_Sein - 001_Nimetus: taimekast; 205_Tüüp: VS-RB-16/1; 325_Helipidavus: nõudeid ei esitata; 330_Tulekindlus: REI 60; 335_Välispiire: yes; 340_Soojusläbivus: 0.22; 376_Viimistlus_väljast: Telje poolne pind: TOON- antratsiit; Telje vastaspoolne pind: BETOON- tumehall; 505_Paksus: 273 mm; 600_Bruto_pindala: 4.27887 m2; 500_Kandev: FALSE; 376_Viimistlus_väljast (MUDELIS): _ALUSKATE - drenaaži- ja kaitsematt geotekstiiliga soojustuse kaitseks, Interplast Iso-Drain 8 Geo või samaväärne; _SOOJUSTUS - vahtpolüstüreenplaadid EPS 120 Perimeeter, survetugevus min. 120kPa, veeimavus <2%, soojuserijuhtivus λD<0,036 W/(mK); _HÜDROISOLATSIOON/RADOONITÕKE - eelpaigaldatav elastne hüdroisolatsioonimembraan, värske betooniga nakkuv, radoonitihe, FORSOC PROOFEX 3000 või samaväärne; _KANDETARIND - monoliitne raudbetoon vastavalt EK osale
AC_Pset_RenovationAndPhasing - Renovation Status: New
Name | 605_Neto_pindala (m2)
3 x taimekast | 4.27887
4 x taimekast | 4.26527
3 x taimekast | 4.25167
taimekast | 4.20997
taimekast | 4.13614

# IfcWall: VS-RB-20/1_soojust 200+laudis 522 (13)
Classification: 1.24 IfcWallType (sein) (RKAS BIM + ARCHICAD Classification)
Pset_WallCommon - Reference: VS-RB-20/1; LoadBearing: yes; IsExternal: yes
AR_Sein - 001_Nimetus: Välissein; 205_Tüüp: VS-RB-20/1; 325_Helipidavus: 55 dB; 330_Tulekindlus: REI 60; 335_Välispiire: yes; 340_Soojusläbivus: 0.14; 376_Viimistlus_väljast: Telje poolne pind: PUITLAUDIS- hõbehall peits V ; Telje vastaspoolne pind: TOON- vastavalt SA osale; 505_Paksus: 522 mm; 500_Kandev: TRUE; 376_Viimistlus_väljast (MUDELIS): _VÄLISVIIMISTLUS - vertikaalne voodrilaud, Platowood P01 profiil 18x140mm, kuusk; eeltöödeldud tuletõkkega mõlemad küljed, B-s1, d0, Woodsafe Exterior WFX™ või samaväärne; _KARKASS - puitroov 32x50mm horisontaalne, immutatud Driconi tulekaitsevahendiga või samaväärne, samm 600mm; _KARKASS - puitroov 32x50mm vertikaalne, immutatud Driconi tulekaitsevahendiga või samaväärne, samm 600mm; _TUULETÕKE - tuuletõkkeplaat, soojuserijuhtivus λD<0,031 W/(mK), ISOVER RKL FACADE või samaväärne, liitekohad katta tihendusteibiga ISOVER FacadeTape või samaväärne; _SOOJUSTUS - mineraalvill, λD<0,032 W/(mK), kuumtsingitud lehtteras termoroovidega, S350GD+Zn275 vastavalt EN10346, ISOVER EXTREME 32 200mm või samaväärne; _KANDETARIND - monteeritav raudbetoon vastavalt EK osale; _VIIMISTLUSKIHT - viimistlus vastavalt SA osale
AC_Pset_RenovationAndPhasing - Renovation Status: New
Name | In | 605_Neto_pindala (m2) | 600_Bruto_pindala (m2)
Välissein | 1. korrus | 4.23556 | 11.073
Välissein | 1. korrus | 30.5539 | 34.7939
Välissein | 1. korrus | 15.8035 | 15.8035
2 x Välissein | 1. korrus | 11.7799 | 14.3999
Välissein | 1. korrus | 47.6981 | 53.1991
Välissein | 1. korrus | 77.6433 | 96.0444
Välissein | 2. korrus | 14.0558 | 14.0558
Välissein | 2. korrus | 8.85594 | 11.9999
Välissein | 2. korrus | 8.85596 | 12
Välissein | 2. korrus | 38.9397 | 47.461
Välissein | 3. korrus | 9.55994 | 12.7039
Välissein | 3. korrus | 8.43986 | 11.5839

# IfcWall: VS-RB-20/2_sokkel 443 (12)
In: Vundament
Classification: 1.24 IfcWallType (sein) (RKAS BIM + ARCHICAD Classification)
Pset_WallCommon - Reference: VS-RB-20/2; IsExternal: yes
AR_Sein - 001_Nimetus: Sokkel; 205_Tüüp: VS-RB-20/2; 325_Helipidavus: nõudeid ei esitata; 330_Tulekindlus: REI 60; 335_Välispiire: yes; 376_Viimistlus_väljast: Telje poolne pind: KROHV- Weber pas.481 AquaBalance, toon helehall CL444 (S 3502-Y) * 35; Telje vastaspoolne pind: TOON- vastavalt SA osale; 505_Paksus: 443 mm; 376_Viimistlus_väljast (MUDELIS): _TUULETÕKE - sokli krohv, silikoonvaikkrohv Weber.pas 481 AquaBalance 1mm "scratch" viimistlus, toon helehall CL444 (S 3502-Y) * 35, SILS süsteem, või samaväärne; _SOOJUSTUS - vahtpolüstüreenplaadid EPS 120 Perimeeter, survetugevus min 120kPa, veeimavus <2%, soojuserijuhtivus λD<0,036 W/(mK); _SOOJUSTUS - ekstrudeeritud polüstüreenist plaadid XPS 250, survetugevus min 250kPa, soojuserijuhtivus λD<0,036 W/(mK), veeimavus alla 0,2%, näiteks XPS 250 foam SL või samaväärne; _HÜDROISOLATSIOON - 3x SBS rullmaterjal vastavalt TL2 nõuetele, nakke tugevduseks betoonpind eelnevalt katta hüdroisolatsiooni bituumenvõõbaga; _KANDETARIND - monteeritav raudbetoon vastavalt EK osale; _VIIMISTLUSKIHT - viimistlus vastavalt SA osale
AC_Pset_RenovationAndPhasing - Renovation Status: New
Name | LoadBearing | 340_Soojusläbivus | 605_Neto_pindala (m2) | 600_Bruto_pindala (m2) | 500_Kandev
Sokkel | no | 0.14 | 0.0146601 | 0.0666201 | FALSE
Sokkel | yes | 0.14 | 0.149874 | 0.149874 | TRUE
Sokkel | yes | 0.14 | 1.9833 | 1.9833 | TRUE
Sokkel | yes | 0.14 | 0.15486 | 0.15486 | TRUE
Sokkel | yes | 0.14 | 0.148323 | 0.148323 | TRUE
Sokkel | yes | 0.14 | 0.688893 | 0.688893 | TRUE
Sokkel | yes | 0.14 | 1.20051 | 1.20171 | TRUE
Sokkel | yes | 0.12 | 0.0561591 | 0.0561591 | TRUE
Sokkel | yes | 0.14 | 0.862886 | 0.862886 | TRUE
Sokkel | yes | 0.14 | 0.152917 | 0.152917 | TRUE
Sokkel | yes | 0.14 | 0.406553 | 0.407753 | TRUE
Sokkel | yes | 0.14 | 0.0649245 | 0.0649244 | TRUE

# IfcWall: VS-RB-20/3_lintvundament 363 (4)
In: Vundament
Classification: 1.24 IfcWallType (sein) (RKAS BIM + ARCHICAD Classification)
Pset_WallCommon - Reference: VS-RB-20/3; LoadBearing: no; IsExternal: no
AR_Sein - 001_Nimetus: Liftišaht; 205_Tüüp: VS-RB-20/3; 325_Helipidavus: nõudeid ei esitata; 330_Tulekindlus: nõudeid ei esitata; 335_Välispiire: no; 340_Soojusläbivus: 0.22; 376_Viimistlus_väljast: Telje poolne pind: TOON- antratsiit; Telje vastaspoolne pind: BETOON- tumehall; 505_Paksus: 363 mm; 500_Kandev: FALSE; 376_Viimistlus_väljast (MUDELIS): _ALUSKATE - drenaaži- ja kaitsematt geotekstiiliga soojustuse kaitseks, Interplast Iso-Drain 8 Geo või samaväärne; _SOOJUSTUS - vahtpolüstüreenplaadid EPS 120 Perimeeter, survetugevus min. 120kPa, veeimavus <2%, soojuserijuhtivus λD<0,036 W/(mK); _HÜDROISOLATSIOON - 3x SBS rullmaterjal vastavalt TL2 nõuetele, nakke tugevduseks betoonpind eelnevalt katta hüdroisolatsiooni bituumenvõõbaga; _KANDETARIND - monoliitne raudbetoon vastavalt EK osale
AC_Pset_RenovationAndPhasing - Renovation Status: New
Name | 605_Neto_pindala (m2) | 600_Bruto_pindala (m2)
Liftišaht | 3.86937 | 3.86937
Liftišaht | 3.49262 | 3.50597
Liftišaht | 3.2256 | 3.23895
Liftišaht | 3.47927 | 3.50597

# IfcWall: VS-RB-25/1_mahuti sein 416 (4)
In: Vundament
Classification: 1.24 IfcWallType (sein) (RKAS BIM + ARCHICAD Classification)
Pset_WallCommon - Reference: VS-RB-25/1; IsExternal: yes
AR_Sein - 001_Nimetus: Mahuti sein; 205_Tüüp: VS-RB-25/1; 325_Helipidavus: nõudeid ei esitata; 330_Tulekindlus: nõudeid ei esitata; 335_Välispiire: yes; 340_Soojusläbivus: 0; 376_Viimistlus_väljast: Telje poolne pind: TOON- antratsiit; Telje vastaspoolne pind: GENERAL; 505_Paksus: 416 mm; 376_Viimistlus_väljast (MUDELIS): _ALUSKATE - drenaaži- ja kaitsematt geotekstiiliga soojustuse kaitseks, Interplast Iso-Drain 8 Geo või samaväärne; _SOOJUSTUS - ekstrudeeritud polüstüreenist plaadid XPS 250, survetugevus min 250kPa, soojuserijuhtivus λD<0,036 W/(mK), veeimavus alla 0,2%, näiteks XPS 250 foam SL või samaväärne; _HÜDROISOLATSIOON/RADOONITÕKE - eelpaigaldatav elastne hüdroisolatsioonimembraan, värske betooniga nakkuv, radoonitihe, FORSOC PROOFEX 3000 või samaväärne; _KANDETARIND - monoliitne raudbetoonplaat; _HÜDROISOLATSIOON/RADOONITÕKE - eelpaigaldatav elastne hüdroisolatsioonimembraan, värske betooniga nakkuv, radoonitihe, FORSOC PROOFEX 3000 või samaväärne
AC_Pset_RenovationAndPhasing - Renovation Status: New
Name | LoadBearing | 605_Neto_pindala (m2) | 600_Bruto_pindala (m2) | 500_Kandev
Mahuti sein | yes | 15.8737 | 15.8737 | TRUE
Mahuti sein | no | 12.5509 | 13.5582 | FALSE
Mahuti sein | no | 13.8798 | 14.991 | FALSE
Mahuti sein | no | 14.3048 | 14.3542 | FALSE

# IfcWall: VS-RB-25/2_mahuti sein soojustamata 266 (4)
In: Vundament
Classification: 1.24 IfcWallType (sein) (RKAS BIM + ARCHICAD Classification)
Pset_WallCommon - Reference: VS-RB-25/2; IsExternal: yes
AR_Sein - 001_Nimetus: Mahuti sein; 205_Tüüp: VS-RB-25/2; 325_Helipidavus: nõudeid ei esitata; 330_Tulekindlus: nõudeid ei esitata; 335_Välispiire: yes; 340_Soojusläbivus: 0; 376_Viimistlus_väljast: Telje poolne pind: TOON- antratsiit; Telje vastaspoolne pind: GENERAL; 505_Paksus: 266 mm; 376_Viimistlus_väljast (MUDELIS): _ALUSKATE - drenaaži- ja kaitsematt geotekstiiliga soojustuse kaitseks, Interplast Iso-Drain 8 Geo või samaväärne; _HÜDROISOLATSIOON/RADOONITÕKE - eelpaigaldatav elastne hüdroisolatsioonimembraan, värske betooniga nakkuv, radoonitihe, FORSOC PROOFEX 3000 või samaväärne; _KANDETARIND - monoliitne raudbetoonplaat; _HÜDROISOLATSIOON/RADOONITÕKE - eelpaigaldatav elastne hüdroisolatsioonimembraan, värske betooniga nakkuv, radoonitihe, FORSOC PROOFEX 3000 või samaväärne
AC_Pset_RenovationAndPhasing - Renovation Status: New
Name | LoadBearing | 605_Neto_pindala (m2) | 600_Bruto_pindala (m2) | 500_Kandev
Mahuti sein | no | 0.71015 | 1.4203 | FALSE
Mahuti sein | no | 0.598161 | 1.20332 | FALSE
Mahuti sein | no | 1.11584 | 1.21242 | FALSE
Mahuti sein | yes | 1.31467 | 1.4091 | TRUE

# IfcWall: VS-RB-25/3_lintvundament klaasfassaad 433 (7)
In: Vundament
Classification: 1.24 IfcWallType (sein) (RKAS BIM + ARCHICAD Classification)
Pset_WallCommon - Reference: VS-RB-25/3; LoadBearing: yes; IsExternal: yes
AR_Sein - 001_Nimetus: Vundament; 205_Tüüp: VS-RB-25/3; 330_Tulekindlus: nõudeid ei esitata; 335_Välispiire: yes; 376_Viimistlus_väljast: Telje poolne pind: KROHV- Weber pas.481 AquaBalance, toon helehall CL444 (S 3502-Y) * 35; Telje vastaspoolne pind: BETOON- tumehall; 505_Paksus: 433 mm; 500_Kandev: TRUE; 376_Viimistlus_väljast (MUDELIS): _TUULETÕKE - sokli krohv, silikoonvaikkrohv Weber.pas 481 AquaBalance 1mm "scratch" viimistlus, toon helehall CL444 (S 3502-Y) * 35, SILS süsteem, või samaväärne; _SOOJUSTUS - vahtpolüstüreenplaadid EPS 120 Perimeeter, survetugevus min 120kPa, veeimavus <2%, soojuserijuhtivus λD<0,036 W/(mK); _SOOJUSTUS - ekstrudeeritud polüstüreenist plaadid XPS 250, survetugevus min 250kPa, soojuserijuhtivus λD<0,036 W/(mK), veeimavus alla 0,2%, näiteks XPS 250 foam SL või samaväärne; _HÜDROISOLATSIOON - Bituumenvõõp COMBIFLEX-EL vastavalt TL2 nõuetele; _KANDETARIND - monoliitne raudbetoon vastavalt EK osale
AC_Pset_RenovationAndPhasing - Renovation Status: New
Name | 325_Helipidavus | 340_Soojusläbivus | 605_Neto_pindala (m2) | 600_Bruto_pindala (m2)
Vundament | nõudeid ei esitata | 0.22 | 13.3281 | 13.3281
Vundament | nõudeid ei esitata | 0.22 | 12.9229 | 12.9229
Vundament | nõudeid ei esitata | 0.22 | 1.18946 | 1.19716
Vundament | nõudeid ei esitata | 0.22 | 10.8194 | 10.8249
Vundament | - | 0 | 8.79342 | 8.79342
Vundament | - | 0 | 22.01 | 22.01
Vundament | nõudeid ei esitata | 0.22 | 4.61416 | 4.62277

# IfcWall: _KANDETARIND - monoliitne raudbetoon vastavalt EK osale 100 (25)
In: 1. korrus
Classification: 1.24 IfcWallType (sein) (RKAS BIM + ARCHICAD Classification); Material: _KANDETARIND - monoliitne raudbetoon vastavalt EK osale
Pset_WallCommon - Reference: Porivann, monoliitne raudbetoon vastavalt EK osale; LoadBearing: no; IsExternal: yes
AR_Sein - 001_Nimetus: Porivann, monoliitne raudbetoon vastavalt EK osale; 205_Tüüp: Porivann, monoliitne raudbetoon vastavalt EK osale; 325_Helipidavus: -; 330_Tulekindlus: nõudeid ei esitata; 335_Välispiire: yes; 340_Soojusläbivus: 0; 376_Viimistlus_väljast: Telje poolne pind: BETOON- tumehall; Telje vastaspoolne pind: BETOON- tumehall; 505_Paksus: 100 mm; 500_Kandev: FALSE; 376_Viimistlus_väljast (MUDELIS): _KANDETARIND - monoliitne raudbetoon vastavalt EK osale
AC_Pset_RenovationAndPhasing - Renovation Status: New
Name | 605_Neto_pindala (m2) | 600_Bruto_pindala (m2)
3 x Porivann, monoliitne raudbetoon vastavalt EK osale | 0.313591 | 0.313591
3 x Porivann, monoliitne raudbetoon vastavalt EK osale | 0.3388 | 0.3668
3 x Porivann, monoliitne raudbetoon vastavalt EK osale | 0.285591 | 0.313591
3 x Porivann, monoliitne raudbetoon vastavalt EK osale | 0.3108 | 0.3668
Porivann, monoliitne raudbetoon vastavalt EK osale | 0.504 | 0.504
Porivann, monoliitne raudbetoon vastavalt EK osale | 1.17309 | 1.20109
Porivann, monoliitne raudbetoon vastavalt EK osale | 0.476 | 0.504
Porivann, monoliitne raudbetoon vastavalt EK osale | 1.14509 | 1.20109
Porivann, monoliitne raudbetoon vastavalt EK osale | 0.31359 | 0.31359
Porivann, monoliitne raudbetoon vastavalt EK osale | 0.471745 | 0.499745
Porivann, monoliitne raudbetoon vastavalt EK osale | 0.28559 | 0.31359
Porivann, monoliitne raudbetoon vastavalt EK osale | 0.443745 | 0.499745
Porivann, monoliitne raudbetoon vastavalt EK osale | 0.387233 | 0.387233
Porivann, monoliitne raudbetoon vastavalt EK osale | 0.895989 | 0.895989
Porivann, monoliitne raudbetoon vastavalt EK osale | 1.19 | 1.218
Porivann, monoliitne raudbetoon vastavalt EK osale | 0.839989 | 0.895989
Porivann, monoliitne raudbetoon vastavalt EK osale | 0.802766 | 0.830766

# IfcWall: _KANDETARIND - monteeritav raudbetoon vastavalt EK osale 150 (8)
In: Vundament
Classification: 1.24 IfcWallType (sein) (RKAS BIM + ARCHICAD Classification); Material: _KANDETARIND - monteeritav raudbetoon vastavalt EK osale
Pset_WallCommon - Reference: Raudbetoon vaastavalt EK osale; LoadBearing: no; IsExternal: yes
AR_Sein - 001_Nimetus: Vundament; 205_Tüüp: Raudbetoon vaastavalt EK osale; 325_Helipidavus: -; 330_Tulekindlus: nõudeid ei esitata; 335_Välispiire: yes; 340_Soojusläbivus: 0.22; 376_Viimistlus_väljast: Telje poolne pind: BETOON- hall, raketis 50x50; Telje vastaspoolne pind: BETOON- hall, raketis 50x50; 505_Paksus: 150 mm; 500_Kandev: FALSE; 376_Viimistlus_väljast (MUDELIS): _KANDETARIND - monteeritav raudbetoon vastavalt EK osale
AC_Pset_RenovationAndPhasing - Renovation Status: New
Name | 605_Neto_pindala (m2) | 600_Bruto_pindala (m2)
Vundament | 0.0441946 | 0.0442686
Vundament | 0.0455042 | 0.0728662
Vundament | 0.0455057 | 0.0728676
Vundament | 0.0455122 | 0.0728742
Vundament | 0.0455212 | 0.0728831
Vundament | 0.04552 | 0.0728817
Vundament | 0.045511 | 0.072873
Vundament | 0.0454991 | 0.0728676

# IfcWall: garderoobi plaadipaksendus 916 x 700 (9)
In: Vundament
Classification: 1.24 IfcWallType (sein) (RKAS BIM + ARCHICAD Classification)
Pset_WallCommon - Reference: garderoobi plaadipaksendus; LoadBearing: no; IsExternal: yes
AR_Sein - 001_Nimetus: Vundament; 205_Tüüp: garderoobi plaadipaksendus; 325_Helipidavus: nõudeid ei esitata; 330_Tulekindlus: nõudeid ei esitata; 335_Välispiire: yes; 505_Paksus: 915.627 mm; 500_Kandev: FALSE; 376_Viimistlus_väljast (MUDELIS): _KANDETARIND - monoliitne raudbetoon vastavalt EK osale; _SOOJUSTUS - vahtpolüstüreenplaadid EPS 120 Perimeeter, survetugevus min 120kPa, veeimavus <2%, soojuserijuhtivus λD<0,036 W/(mK); _SOOJUSTUS - vahtpolüstüreenplaadid EPS 120 Perimeeter, survetugevus min 120kPa, veeimavus <2%, soojuserijuhtivus λD<0,036 W/(mK); _TÄIDE - tasandus-/tugevduskiht, pinnasesse tambitud killustik E=80MPa, fr 16/32; _TÄIDE - tasandus-/tugevduskiht, pinnasesse tambitud killustik E=80MPa, kiilutud fr 4/16; _SOOJUSTUS - vahtpolüstüreenplaadid EPS 120 Perimeeter, survetugevus min 120kPa, veeimavus <2%, soojuserijuhtivus λD<0,036 W/(mK); _SOOJUSTUS - vahtpolüstüreenplaadid EPS 120 Perimeeter, survetugevus min 120kPa, veeimavus <2%, soojuserijuhtivus λD<0,036 W/(mK); _TÄIDE - tasandus-/tugevduskiht, pinnasesse tambitud killustik E=80MPa, fr 16/32; _TÄIDE - tasandus-/tugevduskiht, pinnasesse tambitud killustik E=80MPa, kiilutud fr 4/16
AC_Pset_RenovationAndPhasing - Renovation Status: New
Name | 340_Soojusläbivus | 605_Neto_pindala (m2) | 600_Bruto_pindala (m2)
Vundament | 0 | 2.92652 | 3.54412
Vundament | 0.22 | 1.31218 | 1.97858
Vundament | 0.22 | 18.7192 | 19.3367
Vundament | 0.22 | 1.31219 | 1.97859
Vundament | 0.22 | 2.92647 | 3.54407
Vundament | 0 | 1.31191 | 1.97831
Vundament | 0 | 1.30317 | 1.97834
2 x Vundament | 0.22 | 14.774 | 15.4408

# IfcWall: konvektori alus 853 x 650, Vundament
In: Vundament
Classification: 1.24 IfcWallType (sein) (RKAS BIM + ARCHICAD Classification)
Pset_WallCommon - Reference: konvektori alus; LoadBearing: no; IsExternal: yes
AR_Sein - 001_Nimetus: Vundament; 205_Tüüp: konvektori alus; 325_Helipidavus: nõudeid ei esitata; 330_Tulekindlus: nõudeid ei esitata; 335_Välispiire: yes; 340_Soojusläbivus: 0.22; 505_Paksus: 852.67 mm; 605_Neto_pindala: 13.3119 m2; 600_Bruto_pindala: 13.39 m2; 500_Kandev: FALSE; 376_Viimistlus_väljast (MUDELIS): _SOOJUSTUS - vahtpolüstüreenplaadid EPS 120 Perimeeter, survetugevus min 120kPa, veeimavus <2%, soojuserijuhtivus λD<0,036 W/(mK); _SOOJUSTUS - vahtpolüstüreenplaadid EPS 120 Perimeeter, survetugevus min 120kPa, veeimavus <2%, soojuserijuhtivus λD<0,036 W/(mK); _KANDETARIND - monoliitne raudbetoon vastavalt EK osale; _SOOJUSTUS - ekstrudeeritud polüstüreenist plaadid XPS 250, survetugevus min 250kPa, soojuserijuhtivus λD<0,036 W/(mK), veeimavus alla 0,2%, näiteks XPS 250 foam SL või samaväärne; _SOOJUSTUS - vahtpolüstüreenplaadid EPS 120 Perimeeter, survetugevus min 120kPa, veeimavus <2%, soojuserijuhtivus λD<0,036 W/(mK); _SOOJUSTUS - vahtpolüstüreenplaadid EPS 120 Perimeeter, survetugevus min 120kPa, veeimavus <2%, soojuserijuhtivus λD<0,036 W/(mK)
AC_Pset_RenovationAndPhasing - Renovation Status: New

# IfcWindow: 12 x 5 x 58, SE aken
In: 4. TEHNO korrus
Type - OperationType: SINGLE_PANEL; ParameterTakesPrecedence: no; Sizeable: no
OverallHeight: 1375 mm; OverallWidth: 1625.89 mm; Classification: 1.25 IfcWindowStyle (aken) (RKAS BIM + ARCHICAD Classification)
Pset_WindowCommon - Reference: KA-02
AR_Aken - 001_Nimetus: SE aken; 300_Tüüp: KA-02; 305_Ava_mõõt: 1 626x1 375; 310_Materjal: MUDELIS: _METALL - alumiinium; _KLAAS - kirgas; MÄRKUS: Alumiinium; 315_Avanemine: Automaatselt avanev, käivitustase 3 - Parem ; ARCHICAD tüüp: 4; 320_Klaas: Kirgas; 325_Helipidavus: 33dB; 330_Tulekindlus: nõudeid ei esitata; 340_Soojusläbivus: 1.2; 345_Päikesekiirgus_tegur: 0,26; 350_Klaaspakett: 3-kordne klaaspakett, välimine karastatud ja sisemine lamineeritud: 6-14-4-12-55.2; 355_Pindala: 2.23559 m2; 375_Viimistlus_seest: Raam: METALL- tsink; Aknaleht: METALL- tsink; MÄRKUS: RAL 9006 alumiiniumhall; 376_Viimistlus_väljast: Raam:METALL- tsink; Aknaleht: METALL- tsink; MÄRKUS: RAL 9006 alumiiniumhall; 900_Tootja: Schüco või analoog; 905_Mudel: AWS-57-RO.Hi või analoog; 910_Tooteinfo: Undefined; 915_Kasutus-ja_hooldusjuhend: Undefined
Pset_ManufacturerOccurrence - SerialNumber: Off
AC_Pset_RenovationAndPhasing - Renovation Status: Undefined

# IfcWindow: 13 x 5 x 58, SE aken
In: 4. TEHNO korrus
Type - OperationType: SINGLE_PANEL; ParameterTakesPrecedence: no; Sizeable: no
OverallHeight: 1359.8 mm; OverallWidth: 1625.89 mm; Classification: 1.25 IfcWindowStyle (aken) (RKAS BIM + ARCHICAD Classification)
Pset_WindowCommon - Reference: KA-02
AR_Aken - 001_Nimetus: SE aken; 300_Tüüp: KA-02; 305_Ava_mõõt: 1 626x1 360; 310_Materjal: MUDELIS: _METALL - alumiinium; _KLAAS - kirgas; MÄRKUS: Alumiinium; 315_Avanemine: Automaatselt avanev, käivitustase 3 - Parem ; ARCHICAD tüüp: 5; 320_Klaas: Kirgas; 325_Helipidavus: 33dB; 330_Tulekindlus: nõudeid ei esitata; 340_Soojusläbivus: 1.2; 345_Päikesekiirgus_tegur: 0,26; 350_Klaaspakett: 3-kordne klaaspakett, välimine karastatud ja sisemine lamineeritud: 6-14-4-12-55.2; 355_Pindala: 2.21088 m2; 375_Viimistlus_seest: Raam: METALL- tsink; Aknaleht: METALL- tsink; MÄRKUS: RAL 9006 alumiiniumhall; 376_Viimistlus_väljast: Raam:METALL- tsink; Aknaleht: METALL- tsink; MÄRKUS: RAL 9006 alumiiniumhall; 900_Tootja: Schüco või analoog; 905_Mudel: AWS-57-RO.Hi või analoog; 910_Tooteinfo: Undefined; 915_Kasutus-ja_hooldusjuhend: Undefined
Pset_ManufacturerOccurrence - SerialNumber: Off
AC_Pset_RenovationAndPhasing - Renovation Status: Undefined

# IfcWindow: 1377 x 1783 x 58, SE aken
In: 4. TEHNO korrus
Type - OperationType: SINGLE_PANEL; ParameterTakesPrecedence: no; Sizeable: no
OverallHeight: 1780.04 mm; OverallWidth: 1367.99 mm; Classification: 1.25 IfcWindowStyle (aken) (RKAS BIM + ARCHICAD Classification)
Pset_WindowCommon - Reference: KA-04
AR_Aken - 001_Nimetus: SE aken; 300_Tüüp: KA-04; 305_Ava_mõõt: 1 368x1 780; 310_Materjal: MUDELIS: _METALL - alumiinium; _KLAAS - kirgas; MÄRKUS: Alumiinium; 315_Avanemine: Automaatselt avanev, käivitustase L3 - Vasak ; ARCHICAD tüüp: 5; 320_Klaas: Kirgas; 325_Helipidavus: 33 db; 330_Tulekindlus: nõudeid ei esitata; 340_Soojusläbivus: 1.2; 345_Päikesekiirgus_tegur: 0,26; 350_Klaaspakett: 3 kordne, välimine karastatud, sisemine lamineeritud: 6-14-4-12-55.2; 355_Pindala: 2.43508 m2; 375_Viimistlus_seest: Raam: METALL- tsink; Aknaleht: METALL- tsink; MÄRKUS: RAL 9006 alumiiniumhall; 376_Viimistlus_väljast: Raam:METALL- tsink; Aknaleht: METALL- tsink; MÄRKUS: RAL 9006 alumiiniumhall; 900_Tootja: Schücko või analoog; 905_Mudel: AWS-57-RO.Hi või analoog; 910_Tooteinfo: -; 915_Kasutus-ja_hooldusjuhend: -
Pset_ManufacturerOccurrence - SerialNumber: Off
AC_Pset_RenovationAndPhasing - Renovation Status: Undefined

# IfcWindow: 1389 x 1783 x 58, SE aken
In: 4. TEHNO korrus
Type - OperationType: SINGLE_PANEL; ParameterTakesPrecedence: no; Sizeable: no
OverallHeight: 1780.04 mm; OverallWidth: 1368.03 mm; Classification: 1.25 IfcWindowStyle (aken) (RKAS BIM + ARCHICAD Classification)
Pset_WindowCommon - Reference: KA-04
AR_Aken - 001_Nimetus: SE aken; 300_Tüüp: KA-04; 305_Ava_mõõt: 1 368x1 780; 310_Materjal: MUDELIS: _METALL - alumiinium; _KLAAS - kirgas; MÄRKUS: Alumiinium; 315_Avanemine: Automaatselt avanev, käivitustase L3 - Vasak ; ARCHICAD tüüp: 5; 320_Klaas: Kirgas; 325_Helipidavus: 33 db; 330_Tulekindlus: nõudeid ei esitata; 340_Soojusläbivus: 1.2; 345_Päikesekiirgus_tegur: 0,26; 350_Klaaspakett: 3 kordne, välimine karastatud, sisemine lamineeritud: 6-14-4-12-55.2; 355_Pindala: 2.43514 m2; 375_Viimistlus_seest: Raam: METALL- tsink; Aknaleht: METALL- tsink; MÄRKUS: RAL 9006 alumiiniumhall; 376_Viimistlus_väljast: Raam:METALL- tsink; Aknaleht: METALL- tsink; MÄRKUS: RAL 9006 alumiiniumhall; 900_Tootja: Schücko või analoog; 905_Mudel: AWS-57-RO.Hi või analoog; 910_Tooteinfo: -; 915_Kasutus-ja_hooldusjuhend: -
Pset_ManufacturerOccurrence - SerialNumber: Off
AC_Pset_RenovationAndPhasing - Renovation Status: Undefined

# IfcWindow: 1389 x 1820 x 58, SE aken
In: 4. TEHNO korrus
Type - OperationType: SINGLE_PANEL; ParameterTakesPrecedence: no; Sizeable: no
OverallHeight: 1780.04 mm; OverallWidth: 1368.03 mm; Classification: 1.25 IfcWindowStyle (aken) (RKAS BIM + ARCHICAD Classification)
Pset_WindowCommon - Reference: KA-04
AR_Aken - 001_Nimetus: SE aken; 300_Tüüp: KA-04; 305_Ava_mõõt: 1 368x1 780; 310_Materjal: MUDELIS: _METALL - alumiinium; _KLAAS - kirgas; MÄRKUS: Alumiinium; 315_Avanemine: Automaatselt avanev, käivitustase L3 - Vasak ; ARCHICAD tüüp: 4; 320_Klaas: Kirgas; 325_Helipidavus: 33 db; 330_Tulekindlus: nõudeid ei esitata; 340_Soojusläbivus: 1.2; 345_Päikesekiirgus_tegur: 0,26; 350_Klaaspakett: 3 kordne, välimine karastatud, sisemine lamineeritud: 6-14-4-12-55.2; 355_Pindala: 2.43514 m2; 375_Viimistlus_seest: Raam: METALL- tsink; Aknaleht: METALL- tsink; MÄRKUS: RAL 9006 alumiiniumhall; 376_Viimistlus_väljast: Raam:METALL- tsink; Aknaleht: METALL- tsink; MÄRKUS: RAL 9006 alumiiniumhall; 900_Tootja: Schücko või analoog; 905_Mudel: AWS-57-RO.Hi või analoog; 910_Tooteinfo: -; 915_Kasutus-ja_hooldusjuhend: -
Pset_ManufacturerOccurrence - SerialNumber: Off
AC_Pset_RenovationAndPhasing - Renovation Status: Undefined

# IfcWindow: 1401 x 1783 x 58, SE aken
In: 4. TEHNO korrus
Type - OperationType: SINGLE_PANEL; ParameterTakesPrecedence: no; Sizeable: no
OverallHeight: 1780.04 mm; OverallWidth: 1381.04 mm; Classification: 1.25 IfcWindowStyle (aken) (RKAS BIM + ARCHICAD Classification)
Pset_WindowCommon - Reference: KA-04
AR_Aken - 001_Nimetus: SE aken; 300_Tüüp: KA-04; 305_Ava_mõõt: 1 381x1 780; 310_Materjal: MUDELIS: _METALL - alumiinium; _KLAAS - kirgas; MÄRKUS: Alumiinium; 315_Avanemine: Automaatselt avanev, käivitustase L3 - Vasak ; ARCHICAD tüüp: 5; 320_Klaas: Kirgas; 325_Helipidavus: 33 db; 330_Tulekindlus: nõudeid ei esitata; 340_Soojusläbivus: 1.2; 345_Päikesekiirgus_tegur: 0,26; 350_Klaaspakett: 3 kordne, välimine karastatud, sisemine lamineeritud: 6-14-4-12-55.2; 355_Pindala: 2.45789 m2; 375_Viimistlus_seest: Raam: METALL- tsink; Aknaleht: METALL- tsink; MÄRKUS: RAL 9006 alumiiniumhall; 376_Viimistlus_väljast: Raam:METALL- tsink; Aknaleht: METALL- tsink; MÄRKUS: RAL 9006 alumiiniumhall; 900_Tootja: Schücko või analoog; 905_Mudel: AWS-57-RO.Hi või analoog; 910_Tooteinfo: -; 915_Kasutus-ja_hooldusjuhend: -
Pset_ManufacturerOccurrence - SerialNumber: Off
AC_Pset_RenovationAndPhasing - Renovation Status: Undefined

# IfcWindow: 1401 x 1820 x 58, SE aken
In: 4. TEHNO korrus
Type - OperationType: SINGLE_PANEL; ParameterTakesPrecedence: no; Sizeable: no
OverallHeight: 1780.04 mm; OverallWidth: 1366.04 mm; Classification: 1.25 IfcWindowStyle (aken) (RKAS BIM + ARCHICAD Classification)
Pset_WindowCommon - Reference: KA-04
AR_Aken - 001_Nimetus: SE aken; 300_Tüüp: KA-04; 305_Ava_mõõt: 1 366x1 780; 310_Materjal: MUDELIS: _METALL - alumiinium; _KLAAS - kirgas; MÄRKUS: Alumiinium; 315_Avanemine: Automaatselt avanev, käivitustase L3 - Vasak ; ARCHICAD tüüp: 4; 320_Klaas: Kirgas; 325_Helipidavus: 33 db; 330_Tulekindlus: nõudeid ei esitata; 340_Soojusläbivus: 1.2; 345_Päikesekiirgus_tegur: 0,26; 350_Klaaspakett: 3 kordne, välimine karastatud, sisemine lamineeritud: 6-14-4-12-55.2; 355_Pindala: 2.43161 m2; 375_Viimistlus_seest: Raam: METALL- tsink; Aknaleht: METALL- tsink; MÄRKUS: RAL 9006 alumiiniumhall; 376_Viimistlus_väljast: Raam:METALL- tsink; Aknaleht: METALL- tsink; MÄRKUS: RAL 9006 alumiiniumhall; 900_Tootja: Schücko või analoog; 905_Mudel: AWS-57-RO.Hi või analoog; 910_Tooteinfo: -; 915_Kasutus-ja_hooldusjuhend: -
Pset_ManufacturerOccurrence - SerialNumber: Off
AC_Pset_RenovationAndPhasing - Renovation Status: Undefined

# IfcWindow: 1668 x 1410 x 58, SE aken
In: 4. TEHNO korrus
Type - OperationType: SINGLE_PANEL; ParameterTakesPrecedence: no; Sizeable: no
OverallHeight: 1375 mm; OverallWidth: 1629.06 mm; Classification: 1.25 IfcWindowStyle (aken) (RKAS BIM + ARCHICAD Classification)
Pset_WindowCommon - Reference: KA-02
AR_Aken - 001_Nimetus: SE aken; 300_Tüüp: KA-02; 305_Ava_mõõt: 1 629x1 375; 310_Materjal: MUDELIS: _METALL - alumiinium; _KLAAS - kirgas; MÄRKUS: Alumiinium; 315_Avanemine: Automaatselt avanev, käivitustase 3 - Parem ; ARCHICAD tüüp: 4; 320_Klaas: Kirgas; 325_Helipidavus: 33dB; 330_Tulekindlus: nõudeid ei esitata; 340_Soojusläbivus: 1.2; 345_Päikesekiirgus_tegur: 0,26; 350_Klaaspakett: 3-kordne klaaspakett, välimine karastatud ja sisemine lamineeritud: 6-14-4-12-55.2; 355_Pindala: 2.2389 m2; 375_Viimistlus_seest: Raam: METALL- tsink; Aknaleht: METALL- tsink; MÄRKUS: RAL 9006 alumiiniumhall; 376_Viimistlus_väljast: Raam:METALL- tsink; Aknaleht: METALL- tsink; MÄRKUS: RAL 9006 alumiiniumhall; 900_Tootja: Schüco või analoog; 905_Mudel: AWS-57-RO.Hi või analoog; 910_Tooteinfo: Undefined; 915_Kasutus-ja_hooldusjuhend: Undefined
Pset_ManufacturerOccurrence - SerialNumber: Off
AC_Pset_RenovationAndPhasing - Renovation Status: Undefined

# IfcWindow: 1793 x 1198 x 58, SE-aken
In: 3. korrus
Type - OperationType: SINGLE_PANEL; ParameterTakesPrecedence: no; Sizeable: no
OverallHeight: 1261.5 mm; OverallWidth: 1753 mm; Classification: 1.25 IfcWindowStyle (aken) (RKAS BIM + ARCHICAD Classification)
Pset_WindowCommon - Reference: KA-05
AR_Aken - 001_Nimetus: SE-aken; 300_Tüüp: KA-05; 305_Ava_mõõt: 1 753x1 262; 310_Materjal: MUDELIS: _METALL - alumiinium; _KLAAS - kirgas; MÄRKUS: Alumiinium; 315_Avanemine: Automaatselt avanev, käivitustase L3 - Vasak ; ARCHICAD tüüp: 5; 320_Klaas: Kirgas, välimine karastatud, sisemine lamineeritud, 6-14-4-12-55.2; 325_Helipidavus: 33dB; 330_Tulekindlus: nõudeid ei esitata; 340_Soojusläbivus: 1.2; 345_Päikesekiirgus_tegur: 0,26; 350_Klaaspakett: 3 kordne, karastatud ja lamineeritud; 355_Pindala: 2.21141 m2; 375_Viimistlus_seest: Raam: METALL- tsink; Aknaleht: METALL- tsink; MÄRKUS: RAL 9006 alumiiniumhall; 376_Viimistlus_väljast: Raam:METALL- tsink; Aknaleht: METALL- tsink; MÄRKUS: RAL 9006 alumiiniumhall; 900_Tootja: Schüco või analoog; 905_Mudel: AWS-57-RO.Hi või analoog; 910_Tooteinfo: Undefined; 915_Kasutus-ja_hooldusjuhend: Undefined
Pset_ManufacturerOccurrence - SerialNumber: Off
AC_Pset_RenovationAndPhasing - Renovation Status: Undefined

# IfcWindow: 1793 x 1302 x 58, SE-aken
In: 3. korrus
Type - OperationType: SINGLE_PANEL; ParameterTakesPrecedence: no; Sizeable: no
OverallHeight: 1261.6 mm; OverallWidth: 1753 mm; Classification: 1.25 IfcWindowStyle (aken) (RKAS BIM + ARCHICAD Classification)
Pset_WindowCommon - Reference: KA-05
AR_Aken - 001_Nimetus: SE-aken; 300_Tüüp: KA-05; 305_Ava_mõõt: 1 753x1 262; 310_Materjal: MUDELIS: _METALL - alumiinium; _KLAAS - kirgas; MÄRKUS: Alumiinium; 315_Avanemine: Automaatselt avanev, käivitustase L3 - Vasak ; ARCHICAD tüüp: 4; 320_Klaas: Kirgas, välimine karastatud, sisemine lamineeritud, 6-14-4-12-55.2; 325_Helipidavus: 33dB; 330_Tulekindlus: nõudeid ei esitata; 340_Soojusläbivus: 1.2; 345_Päikesekiirgus_tegur: 0,26; 350_Klaaspakett: 3 kordne, karastatud ja lamineeritud; 355_Pindala: 2.21158 m2; 375_Viimistlus_seest: Raam: METALL- tsink; Aknaleht: METALL- tsink; MÄRKUS: RAL 9006 alumiiniumhall; 376_Viimistlus_väljast: Raam:METALL- tsink; Aknaleht: METALL- tsink; MÄRKUS: RAL 9006 alumiiniumhall; 900_Tootja: Schüco või analoog; 905_Mudel: AWS-57-RO.Hi või analoog; 910_Tooteinfo: Undefined; 915_Kasutus-ja_hooldusjuhend: Undefined
Pset_ManufacturerOccurrence - SerialNumber: Off
AC_Pset_RenovationAndPhasing - Renovation Status: Undefined

# IfcWindow: 19 x 5 x 58, SE aken
In: 4. TEHNO korrus
Type - OperationType: SINGLE_PANEL; ParameterTakesPrecedence: no; Sizeable: no
OverallHeight: 1780.04 mm; OverallWidth: 1368 mm; Classification: 1.25 IfcWindowStyle (aken) (RKAS BIM + ARCHICAD Classification)
Pset_WindowCommon - Reference: KA-04
AR_Aken - 001_Nimetus: SE aken; 300_Tüüp: KA-04; 305_Ava_mõõt: 1 368x1 780; 310_Materjal: MUDELIS: _METALL - alumiinium; _KLAAS - kirgas; MÄRKUS: Alumiinium; 315_Avanemine: Automaatselt avanev, käivitustase L3 - Vasak ; ARCHICAD tüüp: 4; 320_Klaas: Kirgas; 325_Helipidavus: 33 db; 330_Tulekindlus: nõudeid ei esitata; 340_Soojusläbivus: 1.2; 345_Päikesekiirgus_tegur: 0,26; 350_Klaaspakett: 3 kordne, välimine karastatud, sisemine lamineeritud: 6-14-4-12-55.2; 355_Pindala: 2.43508 m2; 375_Viimistlus_seest: Raam: METALL- tsink; Aknaleht: METALL- tsink; MÄRKUS: RAL 9006 alumiiniumhall; 376_Viimistlus_väljast: Raam:METALL- tsink; Aknaleht: METALL- tsink; MÄRKUS: RAL 9006 alumiiniumhall; 900_Tootja: Schücko või analoog; 905_Mudel: AWS-57-RO.Hi või analoog; 910_Tooteinfo: -; 915_Kasutus-ja_hooldusjuhend: -
Pset_ManufacturerOccurrence - SerialNumber: Off
AC_Pset_RenovationAndPhasing - Renovation Status: Undefined

# IfcWindow: 20 x 10 x 58, SE aken
In: 4. TEHNO korrus
Type - OperationType: SINGLE_PANEL; ParameterTakesPrecedence: no; Sizeable: no
OverallHeight: 1375 mm; OverallWidth: 1624.29 mm; Classification: 1.25 IfcWindowStyle (aken) (RKAS BIM + ARCHICAD Classification)
Pset_WindowCommon - Reference: KA-02
AR_Aken - 001_Nimetus: SE aken; 300_Tüüp: KA-02; 305_Ava_mõõt: 1 624x1 375; 310_Materjal: MUDELIS: _METALL - alumiinium; _KLAAS - kirgas; MÄRKUS: Alumiinium; 315_Avanemine: Automaatselt avanev, käivitustase 3 - Parem ; ARCHICAD tüüp: 4; 320_Klaas: Kirgas; 325_Helipidavus: 33dB; 330_Tulekindlus: nõudeid ei esitata; 340_Soojusläbivus: 1.2; 345_Päikesekiirgus_tegur: 0,26; 350_Klaaspakett: 3-kordne klaaspakett, välimine karastatud ja sisemine lamineeritud: 6-14-4-12-55.2; 355_Pindala: 2.23235 m2; 375_Viimistlus_seest: Raam: METALL- tsink; Aknaleht: METALL- tsink; MÄRKUS: RAL 9006 alumiiniumhall; 376_Viimistlus_väljast: Raam:METALL- tsink; Aknaleht: METALL- tsink; MÄRKUS: RAL 9006 alumiiniumhall; 900_Tootja: Schüco või analoog; 905_Mudel: AWS-57-RO.Hi või analoog; 910_Tooteinfo: Undefined; 915_Kasutus-ja_hooldusjuhend: Undefined
Pset_ManufacturerOccurrence - SerialNumber: Off
AC_Pset_RenovationAndPhasing - Renovation Status: Undefined

# IfcWindow: 21 x 5 x 58, SE aken
In: 4. TEHNO korrus
Type - OperationType: SINGLE_PANEL; ParameterTakesPrecedence: no; Sizeable: no
OverallHeight: 1384.8 mm; OverallWidth: 1625.89 mm; Classification: 1.25 IfcWindowStyle (aken) (RKAS BIM + ARCHICAD Classification)
Pset_WindowCommon - Reference: KA-02
AR_Aken - 001_Nimetus: SE aken; 300_Tüüp: KA-02; 305_Ava_mõõt: 1 626x1 385; 310_Materjal: MUDELIS: _METALL - alumiinium; _KLAAS - kirgas; MÄRKUS: Alumiinium; 315_Avanemine: Automaatselt avanev, käivitustase 3 - Parem ; ARCHICAD tüüp: 5; 320_Klaas: Kirgas; 325_Helipidavus: 33dB; 330_Tulekindlus: nõudeid ei esitata; 340_Soojusläbivus: 1.2; 345_Päikesekiirgus_tegur: 0,26; 350_Klaaspakett: 3-kordne klaaspakett, välimine karastatud ja sisemine lamineeritud: 6-14-4-12-55.2; 355_Pindala: 2.20983 m2; 375_Viimistlus_seest: Raam: METALL- tsink; Aknaleht: METALL- tsink; MÄRKUS: RAL 9006 alumiiniumhall; 376_Viimistlus_väljast: Raam:METALL- tsink; Aknaleht: METALL- tsink; MÄRKUS: RAL 9006 alumiiniumhall; 900_Tootja: Schüco või analoog; 905_Mudel: AWS-57-RO.Hi või analoog; 910_Tooteinfo: Undefined; 915_Kasutus-ja_hooldusjuhend: Undefined
Pset_ManufacturerOccurrence - SerialNumber: Off
AC_Pset_RenovationAndPhasing - Renovation Status: Undefined

# IfcWindow: 32 x 5 x 58, SE-aken
In: 3. korrus
Type - ParameterTakesPrecedence: no; Sizeable: no
OverallHeight: 1286.6 mm; OverallWidth: 1752.67 mm; Classification: 1.25 IfcWindowStyle (aken) (RKAS BIM + ARCHICAD Classification); Material: _KLAAS - kirgas
Pset_WindowCommon - Reference: Built-in CW Panel: 1 753x1 287
AR_Aken - 001_Nimetus: SE-aken; 300_Tüüp: Built-in CW Panel: 1 753x1 287; 305_Ava_mõõt: 1 753x1 287; 310_Materjal: MUDELIS: _KLAAS - kirgas; MÄRKUS: Alumiinium; 315_Avanemine: Automaatselt avanev, käivitustase L3; 320_Klaas: Kirgas; 325_Helipidavus: 33dB; 330_Tulekindlus: B300; 340_Soojusläbivus: 1; 345_Päikesekiirgus_tegur: 0,39; 350_Klaaspakett: 3 kordne, karastatud ja lamineeritud; 355_Pindala: 2.21147 m2; 900_Tootja: Schüco või analoog; 905_Mudel: AWS-57-RO.Hi või analoog; 910_Tooteinfo: Undefined; 915_Kasutus-ja_hooldusjuhend: Undefined
AC_Pset_RenovationAndPhasing - Renovation Status: Undefined

# IfcWindow: 58, SE aken
In: 4. TEHNO korrus
Type - OperationType: SINGLE_PANEL; ParameterTakesPrecedence: no; Sizeable: no
OverallHeight: 1384.8 mm; OverallWidth: 1627.47 mm; Classification: 1.25 IfcWindowStyle (aken) (RKAS BIM + ARCHICAD Classification)
Pset_WindowCommon - Reference: KA-02
AR_Aken - 001_Nimetus: SE aken; 300_Tüüp: KA-02; 305_Ava_mõõt: 1 627x1 385; 310_Materjal: MUDELIS: _METALL - alumiinium; _KLAAS - kirgas; MÄRKUS: Alumiinium; 315_Avanemine: Automaatselt avanev, käivitustase 3 - Parem ; ARCHICAD tüüp: 5; 320_Klaas: Kirgas; 325_Helipidavus: 33dB; 330_Tulekindlus: nõudeid ei esitata; 340_Soojusläbivus: 1.2; 345_Päikesekiirgus_tegur: 0,26; 350_Klaaspakett: 3-kordne klaaspakett, välimine karastatud ja sisemine lamineeritud: 6-14-4-12-55.2; 355_Pindala: 2.21201 m2; 375_Viimistlus_seest: Raam: METALL- tsink; Aknaleht: METALL- tsink; MÄRKUS: RAL 9006 alumiiniumhall; 376_Viimistlus_väljast: Raam:METALL- tsink; Aknaleht: METALL- tsink; MÄRKUS: RAL 9006 alumiiniumhall; 900_Tootja: Schüco või analoog; 905_Mudel: AWS-57-RO.Hi või analoog; 910_Tooteinfo: Undefined; 915_Kasutus-ja_hooldusjuhend: Undefined
Pset_ManufacturerOccurrence - SerialNumber: Off
AC_Pset_RenovationAndPhasing - Renovation Status: Undefined

# IfcWindow: 67 x 1198 x 58, SE-aken
In: 3. korrus
Type - ParameterTakesPrecedence: no; Sizeable: no
OverallHeight: 1286.5 mm; OverallWidth: 1752.67 mm; Classification: 1.25 IfcWindowStyle (aken) (RKAS BIM + ARCHICAD Classification); Material: _KLAAS - kirgas
Pset_WindowCommon - Reference: Built-in CW Panel: 1 753x1 287
AR_Aken - 001_Nimetus: SE-aken; 300_Tüüp: Built-in CW Panel: 1 753x1 287; 305_Ava_mõõt: 1 753x1 287; 310_Materjal: MUDELIS: _KLAAS - kirgas; MÄRKUS: Alumiinium; 315_Avanemine: Automaatselt avanev, käivitustase L3; 320_Klaas: Kirgas; 325_Helipidavus: 33dB; 330_Tulekindlus: B300; 340_Soojusläbivus: 1; 345_Päikesekiirgus_tegur: 0,39; 350_Klaaspakett: 3 kordne, karastatud ja lamineeritud; 355_Pindala: 2.2113 m2; 900_Tootja: Schüco või analoog; 905_Mudel: AWS-57-RO.Hi või analoog; 910_Tooteinfo: Undefined; 915_Kasutus-ja_hooldusjuhend: Undefined
AC_Pset_RenovationAndPhasing - Renovation Status: Undefined

# IfcWindow: Horizontal Multi-Sash Window 25, Rest
In: 4. TEHNO korrus
Type - OperationType: USERDEFINED; ParameterTakesPrecedence: no; Sizeable: no
OverallHeight: 1100 mm; OverallWidth: 7603.92 mm; Classification: 1.25 IfcWindowStyle (aken) (RKAS BIM + ARCHICAD Classification)
Pset_WindowCommon - Reference: RE-05; ThermalTransmittance: 0; IsExternal: yes
AR_Aken - 001_Nimetus: Rest; 300_Tüüp: RE-05; 305_Ava_mõõt: 7 604x1 100; 310_Materjal: MUDELIS: väljast TOON- helehall RR21; PUIT- kuusk H; seest TOON- helehall RR21; PUIT- kuusk H; MÄRKUS: kuumtsingitud teras; 315_Avanemine: -; ARCHICAD tüüp: Louvers in Frame; 320_Klaas: -; 325_Helipidavus: -; 330_Tulekindlus: nõudeid ei esitata; 335_Välispiire: yes; 340_Soojusläbivus: 0; 345_Päikesekiirgus_tegur: -; 350_Klaaspakett: -; 355_Pindala: 8.36431 m2; 375_Viimistlus_seest: Raam: TOON- helehall RR21; Aknaleht: PUIT- kuusk H; MÄRKUS: pulbervärvitud RAL 9006 alumiiniumhall; 376_Viimistlus_väljast: Raam: TOON- helehall RR21; Aknaleht: PUIT- kuusk H; MÄRKUS: pulbervärvitud RAL 9006 alumiiniumhall; 900_Tootja: FläktGroup Eesti OÜ või samaväärne; 905_Mudel: RISJ External Louvre või samaväärne, vt. täpsemalt KVJ osa; 910_Tooteinfo: -; 915_Kasutus-ja_hooldusjuhend: -
AC_Pset_RenovationAndPhasing - Renovation Status: New

# IfcWindow: Orivent 21 (4)
Type - ParameterTakesPrecedence: no; Sizeable: no
OverallHeight: 1200 mm; OverallWidth: 1200 mm; Classification: 1.25 IfcWindowStyle (aken) (RKAS BIM + ARCHICAD Classification)
Pset_WindowCommon - ThermalTransmittance: 0; IsExternal: yes
AR_Aken - 001_Nimetus: Suitsueemaldusluuk; 305_Ava_mõõt: 1 200x1 200; 310_Materjal: MUDELIS: ; MÄRKUS: värvitud lehtmetall, kihtpaneel 70mm kivivillisolatsiooniga alusraamil ja 100mm kivivillisolatsiooniga kaanel; 320_Klaas: -; 325_Helipidavus: Rw≥25 dB; 330_Tulekindlus: EI30; 335_Välispiire: yes; 340_Soojusläbivus: 0.5; 345_Päikesekiirgus_tegur: -; 350_Klaaspakett: -; 355_Pindala: 1.44 m2; 375_Viimistlus_seest: Raam: TOON- helehall RR21; MÄRKUS: viimistlus vastavalt SA osale; 376_Viimistlus_väljast: Raam: TOON- helehall RR21; MÄRKUS: värvitud lehtmetall RR21 helehall; 900_Tootja: nt. Kera Group OY; 905_Mudel: Orivent 21 või samaväärne; CE-märgisega ja sertifitseeritud paigaldusjuhendiga; 910_Tooteinfo: -; 915_Kasutus-ja_hooldusjuhend: -
AC_Pset_RenovationAndPhasing - Renovation Status: New
Name | In | Reference = 300_Tüüp | 315_Avanemine
Suitsueemaldusluuk | 3. korrus | SEL-2 | kaldavatav, käivitustase 2*
2 x Suitsueemaldusluuk | 4. TEHNO korrus | SEL-5 | kaldavatav, käivitustase 3
Suitsueemaldusluuk | Katus | SEL-6 | kaldavatav, käivitustase 2*

# IfcWindow: Orivent 23 (7)
Type - ParameterTakesPrecedence: no; Sizeable: no
OverallHeight: 1000 mm; OverallWidth: 1000 mm; Classification: 1.25 IfcWindowStyle (aken) (RKAS BIM + ARCHICAD Classification)
Pset_WindowCommon - ThermalTransmittance: 0; IsExternal: yes
AR_Aken - 305_Ava_mõõt: 1 000x1 000; 310_Materjal: MUDELIS: ; MÄRKUS: värvitud lehtmetall, kihtpaneel 70mm kivivillisolatsiooniga alusraamil ja 100mm kivivillisolatsiooniga kaanel; 320_Klaas: -; 325_Helipidavus: Rw≥25 dB; 335_Välispiire: yes; 340_Soojusläbivus: 0.92; 345_Päikesekiirgus_tegur: -; 350_Klaaspakett: -; 355_Pindala: 1 m2; 375_Viimistlus_seest: Raam: TOON- helehall RR21; MÄRKUS: viimistlus vastavalt SA osale; 900_Tootja: nt. Kera Group OY; 910_Tooteinfo: -; 915_Kasutus-ja_hooldusjuhend: -
AC_Pset_RenovationAndPhasing - Renovation Status: New
Name | In | Reference = 300_Tüüp | 001_Nimetus | 315_Avanemine | 330_Tulekindlus | 376_Viimistlus_väljast | 905_Mudel
4 x Suitsueemaldusluuk | 3. korrus | SEL-3 | Suitsueemaldusluuk | kaldavatav, käivitustase 2 | EI30 | Raam: TOON- helehall RR21; MÄRKUS: värvitud lehtmetall RR21 helehall | Orivent 23 või samaväärne; CE-märgisega ja sertifitseeritud paigaldusjuhendiga
3 x Katuseluuk | 4. TEHNO korrus | LU-1 | Katuseluuk | manuaalselt avatav, pöördavanev | nõudeid ei esitata | Raam: TOON- helehall RR21; MÄRKUS: värvitud lehtmetall R21 helehall | Orivent 23 kukkumiskaitsega või samaväärne; CE-märgisega ja sertifitseeritud paigaldusjuhendiga

# IfcWindow: Orivent 51 lasi (2)
In: 3. korrus
Type - ParameterTakesPrecedence: no; Sizeable: no
OverallHeight: 2400 mm; OverallWidth: 1200 mm; Classification: 1.25 IfcWindowStyle (aken) (RKAS BIM + ARCHICAD Classification)
Pset_WindowCommon - Reference: SEL-4; ThermalTransmittance: 0; IsExternal: yes
AR_Aken - 001_Nimetus: Suitsueemaldusluuk; 300_Tüüp: SEL-4; 305_Ava_mõõt: 1 200x2 400; 310_Materjal: MUDELIS: ; MÄRKUS: värvitud lehtmetall, kihtpaneel PIR plaadist isolatsioon 100; 315_Avanemine: kaldavatav, käivitustase 2; 320_Klaas: turvaklaas; 325_Helipidavus: Rw ≥25 dB; 330_Tulekindlus: nõudeid ei esitata; 335_Välispiire: yes; 340_Soojusläbivus: 1.26; 345_Päikesekiirgus_tegur: 0,28; 350_Klaaspakett: vastavalt tootja standartile; 355_Pindala: 2.88 m2; 375_Viimistlus_seest: Raam: KLAAS- kirgas; TOON- helehall RR21; MÄRKUS: RR21 helehall; 376_Viimistlus_väljast: Raam: KLAAS- kirgas; TOON- helehall RR21; MÄRKUS: värvitud lehtmetall RR21 helehall; 900_Tootja: nt. Kera Group OY; 905_Mudel: Orivent 51 või samaväärne; CE-märgisega ja sertifitseeritud paigaldusjuhendiga; 910_Tooteinfo: -; 915_Kasutus-ja_hooldusjuhend: -
AC_Pset_RenovationAndPhasing - Renovation Status: New

# IfcWindow: Skylight Flat Panel 25, Põrandaluuk
In: 1. korrus
Type - ParameterTakesPrecedence: no; Sizeable: no
Type - Window Lining Properties - LiningThickness: 50 mm
OverallHeight: 800 mm; OverallWidth: 800 mm; Classification: 1.25 IfcWindowStyle (aken) (RKAS BIM + ARCHICAD Classification)
Pset_WindowCommon - Reference: PL-01; ThermalTransmittance: 0; IsExternal: no
AR_Aken - 001_Nimetus: Põrandaluuk; 300_Tüüp: PL-01; 305_Ava_mõõt: 800x800; 310_Materjal: MUDELIS: ; MÄRKUS: anodeeritud alumiinium; 315_Avanemine: manuaalselt avatav, pöördavanev; 320_Klaas: -; 325_Helipidavus: Rw≥25 dB; 330_Tulekindlus: nõudeid ei esitata; 335_Välispiire: no; 340_Soojusläbivus: 0; 345_Päikesekiirgus_tegur: -; 350_Klaaspakett: -; 355_Pindala: 0.64 m2; 375_Viimistlus_seest: Raam: TOON- RAL 9006 alumiinium hall; MÄRKUS: anodeeritud alumiinium; 376_Viimistlus_väljast: Raam: TOON- RAL 9006 alumiinium hall; MÄRKUS: anodeeritud alumiinium; 900_Tootja: nt Gorter Hatches Pty Ltd; 905_Mudel: WA-E või samaväärne; CE-märgisega ja sertifitseeritud paigaldusjuhendiga; 910_Tooteinfo: Täpsustatakse põhiprojektis; 915_Kasutus-ja_hooldusjuhend: Täpsustatakse põhiprojektis
AC_Pset_RenovationAndPhasing - Renovation Status: New

# IfcWindow: Skylight Top Hung 25, Põrandaluuk kokkuklapitava käärdtrepiga
In: 1. korrus
Type - ParameterTakesPrecedence: no; Sizeable: no
Type - Window Lining Properties - LiningDepth: 100 mm; LiningThickness: 40 mm
OverallHeight: 700 mm; OverallWidth: 1400 mm; Classification: 1.25 IfcWindowStyle (aken) (RKAS BIM + ARCHICAD Classification)
Pset_WindowCommon - Reference: PL-02; ThermalTransmittance: 0; IsExternal: no
AR_Aken - 001_Nimetus: Põrandaluuk kokkuklapitava käärdtrepiga; 300_Tüüp: PL-02; 305_Ava_mõõt: 1 400x700; 310_Materjal: MUDELIS: ; MÄRKUS: teras; 315_Avanemine: manuaalselt avatav, pöördavanev; 320_Klaas: -; 325_Helipidavus: Rw≥25 dB; 330_Tulekindlus: EI60; 335_Välispiire: no; 340_Soojusläbivus: 0; 345_Päikesekiirgus_tegur: -; 350_Klaaspakett: -; 355_Pindala: 0.98 m2; 375_Viimistlus_seest: Raam: PUIT- kuusk H; TOON- titaan valge; METALL- tsink; METALL- teras; MÄRKUS: viimistlus vastavalt SA osale; 376_Viimistlus_väljast: Raam: PUIT- kuusk H; TOON- titaan valge; METALL- tsink; METALL- teras; MÄRKUS: vastavalt standarttootele; 900_Tootja: nt Gorter Hatches Pty Ltd; 905_Mudel: RHTEI7014 käärredeliga või analoog; CE-märgisega ja sertifitseeritud paigaldusjuhendiga; 910_Tooteinfo: Undefined; 915_Kasutus-ja_hooldusjuhend: Undefined
AC_Pset_RenovationAndPhasing - Renovation Status: New

# IfcWindow: Vertical Multi-Sash Window 25 (5)
Type - OperationType: SINGLE_PANEL; ParameterTakesPrecedence: no; Sizeable: no
Type - Window Lining Properties - LiningDepth: 108 mm; LiningThickness: 90 mm
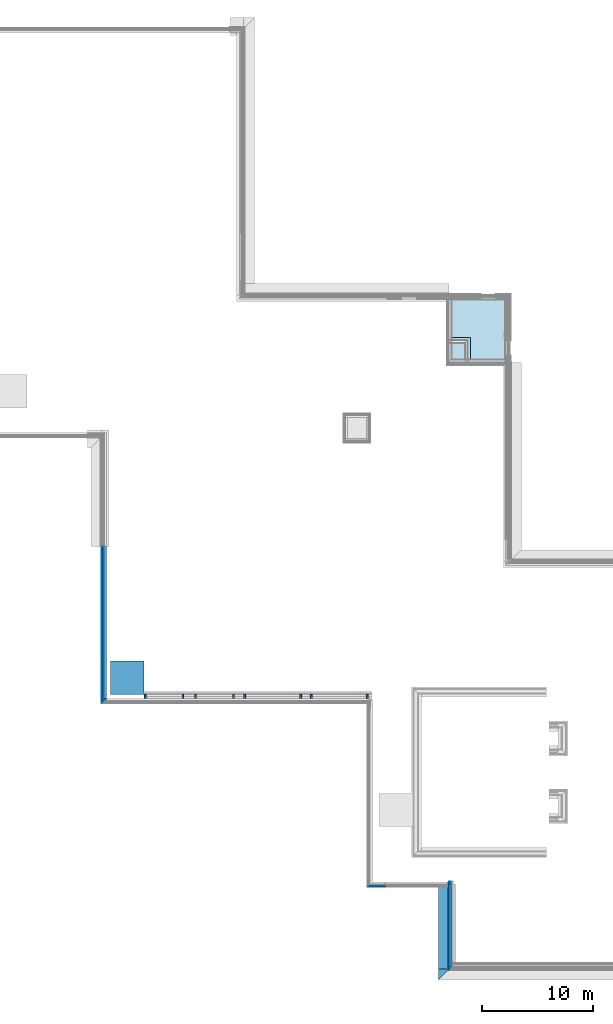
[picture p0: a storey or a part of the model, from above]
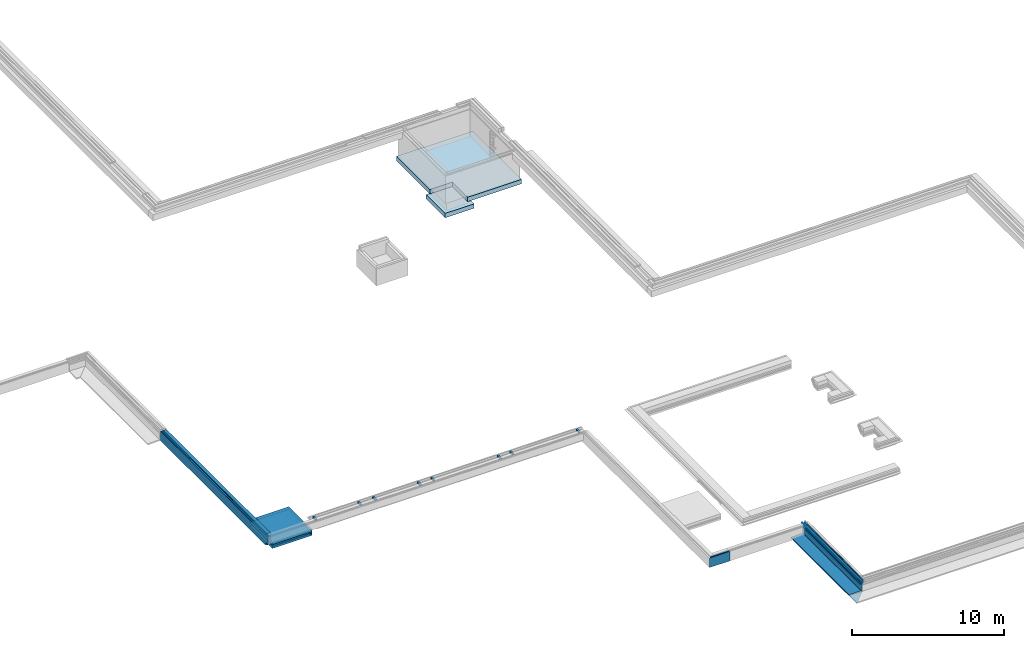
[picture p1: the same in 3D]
Properties of the parts of a building model (IFC2X3), part 14 of 14

# IfcWindow: Vertical Multi-Sash Window 25 (5)
Type - Window Panel Properties - Panel 1 - OperationType: BOTTOMHUNG; PanelPosition: MIDDLE; FrameDepth: 50 mm; FrameThickness: 50 mm
Classification: 1.25 IfcWindowStyle (aken) (RKAS BIM + ARCHICAD Classification)
Pset_WindowCommon - ThermalTransmittance: 0; IsExternal: yes
AR_Aken - 001_Nimetus: Välisaken; 310_Materjal: MUDELIS: väljast TOON- RAL 9006 alumiinium hall; TOON- RAL 9006 alumiinium hall; seest Liimpuit; Liimpuit; MÄRKUS: Puit-alumiinium; 320_Klaas: Kirgas; 325_Helipidavus: 33 dB; 335_Välispiire: yes; 340_Soojusläbivus: 0.8; 375_Viimistlus_seest: Raam: Liimpuit; Aknaleht: Liimpuit; MÄRKUS: toonitud lasuur, vastavalt SA osale; 376_Viimistlus_väljast: Raam: TOON- RAL 9006 alumiinium hall; Aknaleht: TOON- RAL 9006 alumiinium hall; MÄRKUS: RAL: 9006 alumiiniumhall; 900_Tootja: Lasita aken AS või samalaadne; 905_Mudel: IV92 ALU või analoog; 910_Tooteinfo: -; 915_Kasutus-ja_hooldusjuhend: -
AC_Pset_RenovationAndPhasing - Renovation Status: New
Name | In | OverallHeight (mm) | OverallWidth (mm) | Reference = 300_Tüüp | GlazingAreaFraction | 305_Ava_mõõt | 315_Avanemine | 330_Tulekindlus | 345_Päikesekiirgus_tegur | 350_Klaaspakett | 355_Pindala (m2)
2 x Välisaken | 1. korrus | 2400 | 1310 | VA-01-v-gb* | 2.3436 | 1 310x2 400 | Automaatselt avanev kompensatsiooniõhu aken, käivitustase M4 -kaldavanev; ARCHICAD tüüp: Bottom Hung | nõudeid ei esitata | 0,39 | 3 kordne, sisemine klaas lamineeritud, välimine karastatud: 4-16-4-16-44,1 | 3.144
Välisaken | 2. korrus | 2150 | 1310 | VA-03-p-ga* | 2.0736 | 1 310x2 150 | automaatselt avanev SE aken käivitustase L3-kaldavanev; ARCHICAD tüüp: Bottom Hung | B300 | 0,28 | 3 kordne, sisemine klaas lamineeritud: 4-16-4-16-44,1 | 2.8165
2 x Välisaken | 4. TEHNO korrus | 1660 | 1250 | VA-08-k-ga | 1.4586 | 1 250x1 660 | Automaatselt avanev kompensatsiooniõhu aken, käivitustase M4- kaldavanev; ARCHICAD tüüp: Bottom Hung | nõudeid ei esitata | 0,28 | 3 kordne, sisemine klaas lamineeritud: 4-16-4-16-44,1 | 2.075

# IfcWindow: Vertical Multi-Sash Window 25 (156)
Type - OperationType: SINGLE_PANEL; ParameterTakesPrecedence: no; Sizeable: no
Type - Window Lining Properties - LiningDepth: 108 mm; LiningThickness: 90 mm
Type - Window Panel Properties - Panel 1 - OperationType: FIXEDCASEMENT; PanelPosition: MIDDLE
Classification: 1.25 IfcWindowStyle (aken) (RKAS BIM + ARCHICAD Classification)
Pset_WindowCommon - ThermalTransmittance: 0; IsExternal: yes
AR_Aken - 001_Nimetus: Välisaken; 310_Materjal: MUDELIS: väljast TOON- RAL 9006 alumiinium hall; TOON- RAL 9006 alumiinium hall; seest Liimpuit; Liimpuit; MÄRKUS: Puit-alumiinium; 315_Avanemine: mitte-avatav ; ARCHICAD tüüp: Fixed Glass; 320_Klaas: Kirgas; 330_Tulekindlus: nõudeid ei esitata; 335_Välispiire: yes; 340_Soojusläbivus: 0.8; 375_Viimistlus_seest: Raam: Liimpuit; Aknaleht: Liimpuit; MÄRKUS: toonitud lasuur, vastavalt SA osale; 376_Viimistlus_väljast: Raam: TOON- RAL 9006 alumiinium hall; Aknaleht: TOON- RAL 9006 alumiinium hall; MÄRKUS: RAL: 9006 alumiiniumhall; 900_Tootja: Lasita aken AS või samalaadne; 905_Mudel: IV92 ALU või analoog; 910_Tooteinfo: -; 915_Kasutus-ja_hooldusjuhend: -
AC_Pset_RenovationAndPhasing - Renovation Status: New
Name | In | OverallHeight (mm) | OverallWidth (mm) | Reference = 300_Tüüp | GlazingAreaFraction | 305_Ava_mõõt | 325_Helipidavus | 345_Päikesekiirgus_tegur | 350_Klaaspakett | 355_Pindala (m2)
9 x Välisaken | 1. korrus | 2400 | 1310 | VA-11-ga | 2.5086 | 1 310x2 400 | 33 dB | 0,28 | 3 kordne, sisemine klaas lamineeritud, välimine karastatud: 4-16-4-16-44,1 | 3.144
Välisaken | 1. korrus | 2150 | 1310 | VA-13-ga | 2.2261 | 1 310x2 150 | 33 dB | 0,28 | 3 kordne, sisemine klaas lamineeritud, välimine karastatud: 4-16-4-16-44,1 | 2.8165
10 x Välisaken | 1. korrus | 2400 | 1310 | VA-14-ga | 2.5086 | 1 310x2 400 | 40 dB+ transpordi korrektsion | 0,28 | 3 kordne, sisemine klaas lamineeritud, välimine karastatud: 4-16-4-16-44,1 | 3.144
7 x Välisaken | 1. korrus | 2400 | 1310 | VA-12-gb | 2.5086 | 1 310x2 400 | 33 dB | 0,39 | 3 kordne, sisemine klaas lamineeritud, välimine karastatud: 4-16-4-16-44,1 | 3.144
2 x Välisaken | 1. korrus | 2150 | 1310 | VA-03-gb | 2.2261 | 1 310x2 150 | 33 dB | 0,39 | 3 kordne, sisemine klaas lamineeritud, välimine karastatud: 4-16-4-16-44,1 | 2.8165
16 x Välisaken | 2. korrus | 2400 | 1310 | VA-02-gb | 2.5086 | 1 310x2 400 | 33 dB | 0,39 | 3 kordne, sisemine klaas lamineeritud: 4-16-4-16-44,1 | 3.144
5 x Välisaken | 2. korrus | 2150 | 1310 | VA-03-ga | 2.2261 | 1 310x2 150 | 33 dB | 0,28 | 3 kordne, sisemine klaas lamineeritud: 4-16-4-16-44,1 | 2.8165
10 x Välisaken | 2. korrus | 2400 | 1310 | VA-06-ga | 2.5086 | 1 310x2 400 | 40 dB+ transpordi korrektsion | 0,28 | 3 kordne, sisemine klaas lamineeritud: 4-16-4-16-44,1 | 3.144
21 x Välisaken | 2. korrus | 2400 | 1310 | VA-01-ga | 2.5086 | 1 310x2 400 | 33 dB | 0,28 | 3 kordne, sisemine klaas lamineeritud: 4-16-4-16-44,1 | 3.144
33 x Välisaken | 3. korrus | 2400 | 1310 | VA-01-ga | 2.5086 | 1 310x2 400 | 33 dB | 0,28 | 3 kordne, sisemine klaas lamineeritud: 4-16-4-16-44,1 | 3.144
14 x Välisaken | 3. korrus | 2400 | 1310 | VA-02-gb | 2.5086 | 1 310x2 400 | 33 dB | 0,39 | 3 kordne, sisemine klaas lamineeritud: 4-16-4-16-44,1 | 3.144
12 x Välisaken | 3. korrus | 2400 | 1310 | VA-06-ga | 2.5086 | 1 310x2 400 | 40 dB+ transpordi korrektsion | 0,28 | 3 kordne, sisemine klaas lamineeritud: 4-16-4-16-44,1 | 3.144
4 x Välisaken | 3. korrus | 2000 | 1310 | VA-05-ga | 2.0566 | 1 310x2 000 | 33 dB | 0,28 | 3 kordne, sisemine klaas lamineeritud: 4-16-4-16-44,1 | 2.62
4 x Välisaken | 4. TEHNO korrus | 1660 | 750 | VA-09-ga | 0.8436 | 750x1 660 | 33 dB | 0,28 | 3 kordne, sisemine klaas lamineeritud: 4-16-4-16-44,1 | 1.245
8 x Välisaken | 4. TEHNO korrus | 1660 | 1250 | VA-08-ga | 1.5836 | 1 250x1 660 | 33 dB | 0,28 | 3 kordne, sisemine klaas lamineeritud: 4-16-4-16-44,1 | 2.075

# IfcWindow: Vertical Multi-Sash Window 25 (30)
Type - OperationType: SINGLE_PANEL; ParameterTakesPrecedence: no; Sizeable: no
Type - Window Lining Properties - LiningDepth: 108 mm; LiningThickness: 90 mm
Type - Window Panel Properties - Panel 1 - OperationType: TILTANDTURNLEFTHAND; PanelPosition: MIDDLE; FrameDepth: 50 mm; FrameThickness: 50 mm
Classification: 1.25 IfcWindowStyle (aken) (RKAS BIM + ARCHICAD Classification)
Pset_WindowCommon - ThermalTransmittance: 0; IsExternal: yes
AR_Aken - 001_Nimetus: Välisaken; 310_Materjal: MUDELIS: väljast TOON- RAL 9006 alumiinium hall; TOON- RAL 9006 alumiinium hall; seest Liimpuit; Liimpuit; MÄRKUS: Puit-alumiinium; 320_Klaas: Kirgas; 325_Helipidavus: 33 dB; 330_Tulekindlus: nõudeid ei esitata; 335_Välispiire: yes; 340_Soojusläbivus: 0.8; 375_Viimistlus_seest: Raam: Liimpuit; Aknaleht: Liimpuit; MÄRKUS: toonitud lasuur, vastavalt SA osale; 376_Viimistlus_väljast: Raam: TOON- RAL 9006 alumiinium hall; Aknaleht: TOON- RAL 9006 alumiinium hall; MÄRKUS: RAL: 9006 alumiiniumhall; 900_Tootja: Lasita aken AS või samalaadne; 905_Mudel: IV92 ALU või analoog; 910_Tooteinfo: -; 915_Kasutus-ja_hooldusjuhend: -
AC_Pset_RenovationAndPhasing - Renovation Status: New
Name | In | OverallHeight (mm) | OverallWidth (mm) | Reference = 300_Tüüp | GlazingAreaFraction | 305_Ava_mõõt | 315_Avanemine | 345_Päikesekiirgus_tegur | 350_Klaaspakett | 355_Pindala (m2)
8 x Välisaken | 1. korrus | 2400 | 1310 | VA-11-v-ga | 2.3436 | 1 310x2 400 | manuaalselt avanev SE aken - Vasak ; ARCHICAD tüüp: Tilt-Turn | 0,28 | 3 kordne, sisemine klaas lamineeritud, välimine karastatud: 4-16-4-16-44,1 | 3.144
Välisaken | 1. korrus | 2150 | 1310 | VA-03-v-ga | 2.0736 | 1 310x2 150 | manuaalselt avanev SE aken - Vasak ; ARCHICAD tüüp: Tilt-Turn | 0,28 | 3 kordne, sisemine klaas lamineeritud, välimine karastatud: 4-16-4-16-44,1 | 2.8165
3 x Välisaken | 1. korrus | 2150 | 1310 | VA-03-v-gb | 2.0736 | 1 310x2 150 | manuaalselt avanev SE aken - Vasak ; ARCHICAD tüüp: Tilt-Turn | 0,39 | 3 kordne, sisemine klaas lamineeritud, välimine karastatud: 4-16-4-16-44,1 | 2.8165
3 x Välisaken | 2. korrus | 2400 | 1310 | VA-01-v-gb | 2.3436 | 1 310x2 400 | manuaalselt avanev SE aken - Vasak ; ARCHICAD tüüp: Tilt-Turn | 0,39 | 3 kordne, sisemine klaas lamineeritud: 4-16-4-16-44,1 | 3.144
Välisaken | 2. korrus | 2400 | 1310 | VA-02-v-ga | 2.3436 | 1 310x2 400 | manuaalselt avanev SE aken - Vasak ; ARCHICAD tüüp: Tilt-Turn | 0,28 | 3 kordne, sisemine klaas lamineeritud: 4-16-4-16-44,1 | 3.144
4 x Välisaken | 2. korrus | 2400 | 1310 | VA-01-v-ga | 2.3436 | 1 310x2 400 | manuaalselt avanev SE aken - Vasak ; ARCHICAD tüüp: Tilt-Turn | 0,28 | 3 kordne, sisemine klaas lamineeritud: 4-16-4-16-44,1 | 3.144
4 x Välisaken | 3. korrus | 2400 | 1310 | VA-01-v-ga | 2.3436 | 1 310x2 400 | manuaalselt avanev SE aken - Vasak ; ARCHICAD tüüp: Tilt-Turn | 0,28 | 3 kordne, sisemine klaas lamineeritud: 4-16-4-16-44,1 | 3.144
2 x Välisaken | 3. korrus | 2400 | 1310 | VA-01-v-gb | 2.3436 | 1 310x2 400 | manuaalselt avanev SE aken - Vasak ; ARCHICAD tüüp: Tilt-Turn | 0,39 | 3 kordne, sisemine klaas lamineeritud: 4-16-4-16-44,1 | 3.144
Välisaken | 3. korrus | 2400 | 1310 | VA-01-v-gb | 2.3436 | 1 310x2 400 | manuaalselt avanev SE aken - Vasak ; ARCHICAD tüüp: Tilt-Turn Mirrored | 0,39 | 3 kordne, sisemine klaas lamineeritud: 4-16-4-16-44,1 | 3.144
Välisaken | 3. korrus | 2400 | 1310 | VA-10-k-ga | 2.3436 | 1 310x2 400 | manuaalselt avanev SE aken - Parem ; ARCHICAD tüüp: Tilt-Turn Mirrored | 0,28 | 3 kordne, sisemine klaas lamineeritud: 4-16-4-16-44,1 | 3.144
Välisaken | 3. korrus | 2400 | 1310 | VA-02-v-ga | 2.3436 | 1 310x2 400 | manuaalselt avanev SE aken - Vasak ; ARCHICAD tüüp: Tilt-Turn | 0,28 | 3 kordne, sisemine klaas lamineeritud: 4-16-4-16-44,1 | 3.144
Välisaken | 4. TEHNO korrus | 1660 | 1250 | VA-08-v-ga | 1.4586 | 1 250x1 660 | Vasak; ARCHICAD tüüp: Tilt-Turn | 0,28 | 3 kordne, sisemine klaas lamineeritud: 4-16-4-16-44,1 | 2.075

# IfcWindow: Vertical Multi-Sash Window 25 (36)
Type - OperationType: SINGLE_PANEL; ParameterTakesPrecedence: no; Sizeable: no
Type - Window Lining Properties - LiningDepth: 108 mm; LiningThickness: 90 mm
Type - Window Panel Properties - Panel 1 - OperationType: TILTANDTURNRIGHTHAND; PanelPosition: MIDDLE; FrameDepth: 50 mm; FrameThickness: 50 mm
Classification: 1.25 IfcWindowStyle (aken) (RKAS BIM + ARCHICAD Classification)
Pset_WindowCommon - ThermalTransmittance: 0; IsExternal: yes
AR_Aken - 001_Nimetus: Välisaken; 310_Materjal: MUDELIS: väljast TOON- RAL 9006 alumiinium hall; TOON- RAL 9006 alumiinium hall; seest Liimpuit; Liimpuit; MÄRKUS: Puit-alumiinium; 320_Klaas: Kirgas; 330_Tulekindlus: nõudeid ei esitata; 335_Välispiire: yes; 340_Soojusläbivus: 0.8; 375_Viimistlus_seest: Raam: Liimpuit; Aknaleht: Liimpuit; MÄRKUS: toonitud lasuur, vastavalt SA osale; 376_Viimistlus_väljast: Raam: TOON- RAL 9006 alumiinium hall; Aknaleht: TOON- RAL 9006 alumiinium hall; MÄRKUS: RAL: 9006 alumiiniumhall; 900_Tootja: Lasita aken AS või samalaadne; 905_Mudel: IV92 ALU või analoog; 910_Tooteinfo: -; 915_Kasutus-ja_hooldusjuhend: -
AC_Pset_RenovationAndPhasing - Renovation Status: New
Name | In | OverallHeight (mm) | OverallWidth (mm) | Reference = 300_Tüüp | GlazingAreaFraction | 305_Ava_mõõt | 315_Avanemine | 325_Helipidavus | 345_Päikesekiirgus_tegur | 350_Klaaspakett | 355_Pindala (m2)
3 x Välisaken | 1. korrus | 2400 | 1310 | VA-14-p-ga | 2.3436 | 1 310x2 400 | manuaalselt avanev SE aken - Parem ; ARCHICAD tüüp: Tilt-Turn | 40 dB+ transpordi korrektsion | 0,28 | 3 kordne, sisemine klaas lamineeritud, välimine karastatud: 4-16-4-16-44,1 | 3.144
2 x Välisaken | 1. korrus | 2400 | 1310 | VA-12-p-ga | 2.3436 | 1 310x2 400 | manuaalselt avanev SE aken - Parem ; ARCHICAD tüüp: Tilt-Turn | 33 dB | 0,28 | 3 kordne, sisemine klaas lamineeritud, välimine karastatud: 4-16-4-16-44,1 | 3.144
3 x Välisaken | 1. korrus | 2400 | 1310 | VA-12-p-gb | 2.3436 | 1 310x2 400 | manuaalselt avanev SE aken - Parem ; ARCHICAD tüüp: Tilt-Turn | 33 dB | 0,39 | 3 kordne, sisemine klaas lamineeritud, välimine karastatud: 4-16-4-16-44,1 | 3.144
5 x Välisaken | 2. korrus | 2400 | 1310 | VA-02-p-gb | 2.3436 | 1 310x2 400 | manuaalselt avanev SE aken - Parem ; ARCHICAD tüüp: Tilt-Turn | 33 dB | 0,39 | 3 kordne, sisemine klaas lamineeritud: 4-16-4-16-44,1 | 3.144
Välisaken | 2. korrus | 2150 | 1310 | VA-03-p-ga | 2.0736 | 1 310x2 150 | manuaalselt avanev SE aken - Parem ; ARCHICAD tüüp: Tilt-Turn | 33 dB | 0,28 | 3 kordne, sisemine klaas lamineeritud: 4-16-4-16-44,1 | 2.8165
3 x Välisaken | 2. korrus | 2400 | 1310 | VA-06-p-ga | 2.3436 | 1 310x2 400 | manuaalselt avanev SE aken - Parem ; ARCHICAD tüüp: Tilt-Turn | 40 dB+ transpordi korrektsion | 0,28 | 3 kordne, sisemine klaas lamineeritud: 4-16-4-16-44,1 | 3.144
Välisaken | 2. korrus | 2400 | 1310 | VA-01-p-ga | 2.3436 | 1 310x2 400 | manuaalselt avanev SE aken - Parem ; ARCHICAD tüüp: Tilt-Turn | 33 dB | 0,28 | 3 kordne, sisemine klaas lamineeritud: 4-16-4-16-44,1 | 3.144
2 x Välisaken | 2. korrus | 2400 | 1310 | VA-02-p-ga | 2.3436 | 1 310x2 400 | manuaalselt avanev SE aken - Parem ; ARCHICAD tüüp: Tilt-Turn | 33 dB | 0,28 | 3 kordne, sisemine klaas lamineeritud: 4-16-4-16-44,1 | 3.144
2 x Välisaken | 3. korrus | 2400 | 1310 | VA-02-p-gb | 2.3436 | 1 310x2 400 | manuaalselt avanev SE aken - Parem ; ARCHICAD tüüp: Tilt-Turn Mirrored | 33 dB | 0,39 | 3 kordne, sisemine klaas lamineeritud: 4-16-4-16-44,1 | 3.144
2 x Välisaken | 3. korrus | 2400 | 1310 | VA-02-p-gb | 2.3436 | 1 310x2 400 | manuaalselt avanev SE aken - Parem ; ARCHICAD tüüp: Tilt-Turn | 33 dB | 0,39 | 3 kordne, sisemine klaas lamineeritud: 4-16-4-16-44,1 | 3.144
4 x Välisaken | 3. korrus | 2400 | 1310 | VA-02-p-ga | 2.3436 | 1 310x2 400 | manuaalselt avanev SE aken - Parem ; ARCHICAD tüüp: Tilt-Turn | 33 dB | 0,28 | 3 kordne, sisemine klaas lamineeritud: 4-16-4-16-44,1 | 3.144
4 x Välisaken | 3. korrus | 2400 | 1310 | VA-06-p-ga | 2.3436 | 1 310x2 400 | manuaalselt avanev SE aken - Parem ; ARCHICAD tüüp: Tilt-Turn | 40 dB+ transpordi korrektsion | 0,28 | 3 kordne, sisemine klaas lamineeritud: 4-16-4-16-44,1 | 3.144
Välisaken | 3. korrus | 2400 | 1310 | VA-01-p-ga | 2.3436 | 1 310x2 400 | manuaalselt avanev SE aken - Parem ; ARCHICAD tüüp: Tilt-Turn | 33 dB | 0,28 | 3 kordne, sisemine klaas lamineeritud: 4-16-4-16-44,1 | 3.144
Välisaken | 3. korrus | 1950 | 1310 | VA-07-p-ga | 1.8576 | 1 310x1 950 | manuaalselt avanev SE aken - Parem ; ARCHICAD tüüp: Tilt-Turn | 33 dB | 0,28 | 3 kordne, sisemine klaas lamineeritud: 4-16-4-16-44,1 | 2.5545
Välisaken | 3. korrus | 2000 | 1310 | VA-05-p-ga | 1.9116 | 1 310x2 000 | manuaalselt avanev SE aken - Parem ; ARCHICAD tüüp: Tilt-Turn | 33 dB | 0,28 | 3 kordne, sisemine klaas lamineeritud: 4-16-4-16-44,1 | 2.62
Välisaken | 4. TEHNO korrus | 1660 | 1250 | VA-08-p-ga | 1.4586 | 1 250x1 660 | Parem ; ARCHICAD tüüp: Tilt-Turn | 33 dB | 0,28 | 3 kordne, sisemine klaas lamineeritud: 4-16-4-16-44,1 | 2.075

# IfcWindow: Vertical Sliding Garage Door 25, Nõudetagastus ava kardin
In: 1. korrus
Type - ParameterTakesPrecedence: no; Sizeable: no
OverallHeight: 1510 mm; OverallWidth: 3750 mm; Classification: 1.25 IfcWindowStyle (aken) (RKAS BIM + ARCHICAD Classification)
Pset_WindowCommon - Reference: SU-505; ThermalTransmittance: 0; IsExternal: no
AR_Aken - 001_Nimetus: Nõudetagastus ava kardin; 300_Tüüp: SU-505; 305_Ava_mõõt: 3 750x1 510; 310_Materjal: MUDELIS: ; MÄRKUS: Alumiiniumprofiil; 315_Avanemine: Elektriline üles rulluv ruloo; 320_Klaas: -; 325_Helipidavus: -; 330_Tulekindlus: nõudeid ei esitata; 335_Välispiire: no; 340_Soojusläbivus: 0; 345_Päikesekiirgus_tegur: Nõudeid ei esitata; 350_Klaaspakett: -; 355_Pindala: 5.6625 m2; 375_Viimistlus_seest: Anodeeritud alumiinium; 376_Viimistlus_väljast: Anodeeritud alumiinium; 900_Tootja: -; 905_Mudel: -; 910_Tooteinfo: -; 915_Kasutus-ja_hooldusjuhend: -
AC_Pset_RenovationAndPhasing - Renovation Status: New

# IfcWindow: Window 25 (13)
Type - OperationType: SINGLE_PANEL; ParameterTakesPrecedence: no; Sizeable: no
Type - Window Lining Properties - LiningDepth: 50 mm; LiningThickness: 50 mm
Type - Window Panel Properties - Panel 1 - OperationType: FIXEDCASEMENT; PanelPosition: MIDDLE
Classification: 1.25 IfcWindowStyle (aken) (RKAS BIM + ARCHICAD Classification)
Pset_WindowCommon - ThermalTransmittance: 0; IsExternal: yes
AR_Aken - 001_Nimetus: Rest; 310_Materjal: MUDELIS: väljast TOON- helehall RR21; PUIT- kuusk H; seest TOON- helehall RR21; PUIT- kuusk H; MÄRKUS: kuumtsingitud teras; 330_Tulekindlus: nõudeid ei esitata; 335_Välispiire: yes; 340_Soojusläbivus: 0; 345_Päikesekiirgus_tegur: -; 375_Viimistlus_seest: Raam: TOON- helehall RR21; Aknaleht: PUIT- kuusk H; MÄRKUS: pulbervärvitud RAL 9006 alumiiniumhall; 376_Viimistlus_väljast: Raam: TOON- helehall RR21; Aknaleht: PUIT- kuusk H; MÄRKUS: pulbervärvitud RAL 9006 alumiiniumhall; 900_Tootja: FläktGroup Eesti OÜ või samaväärne; 910_Tooteinfo: -; 915_Kasutus-ja_hooldusjuhend: -
AC_Pset_RenovationAndPhasing - Renovation Status: New
Name | In | OverallHeight (mm) | OverallWidth (mm) | Reference = 300_Tüüp | 305_Ava_mõõt | 315_Avanemine | 320_Klaas = 325_Helipidavus = 350_Klaaspakett | 355_Pindala (m2) | 905_Mudel
Rest | 1. korrus | 1130 | 2500 | RE-02 | 2 500x1 130 | Undefined ; ARCHICAD tüüp: Louvers in Frame | - | 2.825 | RIS External Louvre või samaväärne, vt. täpsemalt KVJ osa
2 x Rest | 1. korrus | 1200 | 1200 | RE-06 | 1 200x1 200 | - ; ARCHICAD tüüp: Louvers in Frame | - | 1.44 | RISJ External Louvre või samaväärne, vt. täpsemalt KVJ osa
Rest | 2. korrus | 1000 | 2840 | RE-04 | 2 840x1 000 | - ; ARCHICAD tüüp: Louvers in Frame | - | 2.84 | RIS External Louvre või samaväärne, vt. täpsemalt KVJ osa
Rest | 2. korrus | 2000 | 1640 | RE-03 | 1 640x2 000 | - ; ARCHICAD tüüp: Louvers in Frame | - | 3.28 | RIS External Louvre või samaväärne, vt. täpsemalt KVJ osa
6 x Rest | 4. TEHNO korrus | 1425 | 1275 | RE-01 | 1 275x1 425 | - ; ARCHICAD tüüp: Louvers in Frame | - | 1.81688 | RIS External Louvre või samaväärne, vt. täpsemalt KVJ osa
Rest | 4. TEHNO korrus | 1100 | 2500 | RE-08 | 2 500x1 100 | -; ARCHICAD tüüp: Louvers in Frame | - | 2.75 | RISJ External Louvre või samaväärne, vt. täpsemalt KVJ osa
Rest | 4. TEHNO korrus | 430 | 2650 | RE-07 | 2 650x430 | - ; ARCHICAD tüüp: Louvers in Frame | Undefined | 1.1395 | RISJ External Louvre või samaväärne, vt. täpsemalt KVJ osa

# IfcWindow: Window 25, Suitsueemaldusluuk
In: 1. korrus
Type - OperationType: SINGLE_PANEL; ParameterTakesPrecedence: no; Sizeable: no
Type - Window Lining Properties - LiningDepth: 90 mm; LiningThickness: 120 mm
Type - Window Panel Properties - Panel 1 - OperationType: BOTTOMHUNG; PanelPosition: MIDDLE; FrameDepth: 80 mm; FrameThickness: 70 mm
OverallHeight: 1000 mm; OverallWidth: 1000 mm; Classification: 1.25 IfcWindowStyle (aken) (RKAS BIM + ARCHICAD Classification)
Pset_WindowCommon - Reference: SEL-1; ThermalTransmittance: 0; IsExternal: yes
AR_Aken - 001_Nimetus: Suitsueemaldusluuk; 300_Tüüp: SEL-1; 305_Ava_mõõt: 1 000x1 000; 310_Materjal: MUDELIS: väljast TOON- RAL 9006 alumiinium hall; PUIT- kuusk H; seest TOON- RAL 9006 alumiinium hall; PUIT- kuusk H; MÄRKUS: alumiinium, sise ja välispind galvaniseeritud teraslehed, PIR-isolatsioon 56mm; 315_Avanemine: kaldavatav, käivitustase 2*; ARCHICAD tüüp: Bottom Hung; 320_Klaas: -; 325_Helipidavus: Rw≥25 dB; 330_Tulekindlus: EI30; 335_Välispiire: yes; 340_Soojusläbivus: 0.9; 345_Päikesekiirgus_tegur: -; 350_Klaaspakett: -; 355_Pindala: 1 m2; 375_Viimistlus_seest: Raam: TOON- RAL 9006 alumiinium hall; Aknaleht: PUIT- kuusk H; MÄRKUS: viimistlus vastavalt SA osale; 376_Viimistlus_väljast: Raam: TOON- RAL 9006 alumiinium hall; Aknaleht: PUIT- kuusk H; MÄRKUS: RAL9006 alumiiniumhall; 900_Tootja: nt. Kera Group OY; 905_Mudel: Orivent 70 SL või samaväärne; CE-märgisega ja sertifitseeritud paigaldusjuhendiga; 910_Tooteinfo: -; 915_Kasutus-ja_hooldusjuhend: -
AC_Pset_RenovationAndPhasing - Renovation Status: New

# IfcZone (13)
AR_Tsoon - 085_Tuletõkkesektsioon: EI60
Name | 080_Tähis | 090_Pindala (m2)
TTS 01 | TTS 01 | 2716.13 | Classification: 1.0.4 IfcZone (tsoon) (RKAS BIM + ARCHICAD Classification 23 + v 2.0)
TTS 02 | TTS 02 | 3283.25
TTS 03 | TTS 03 | 60.44
TTS 04 | TTS 04 | 96.35
TTS 05 | TTS 05 | 26.68
TTS 16 | TTS 16 | 30.87
TTS 17 | TTS 17 | 10.61
TTS 18 | TTS 18 | 9.12
TTS 19 | TTS 19 | 9.02
TTS 20 | TTS 20 | 175.04
TTS 21 | TTS 21 | 89.76
TTS 22 | TTS 22 | 9.17
TTS 23 | TTS 23 | 171.36
